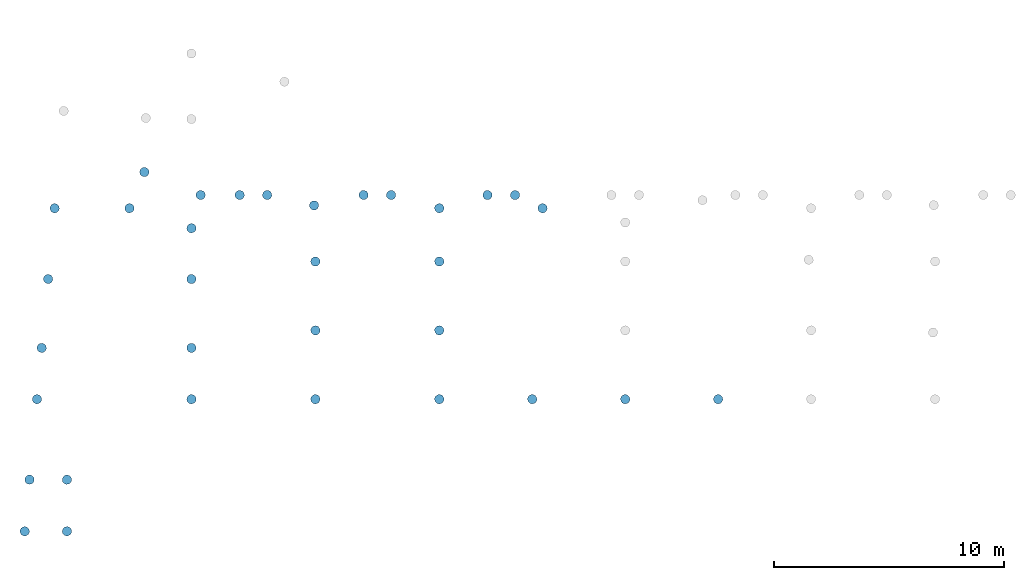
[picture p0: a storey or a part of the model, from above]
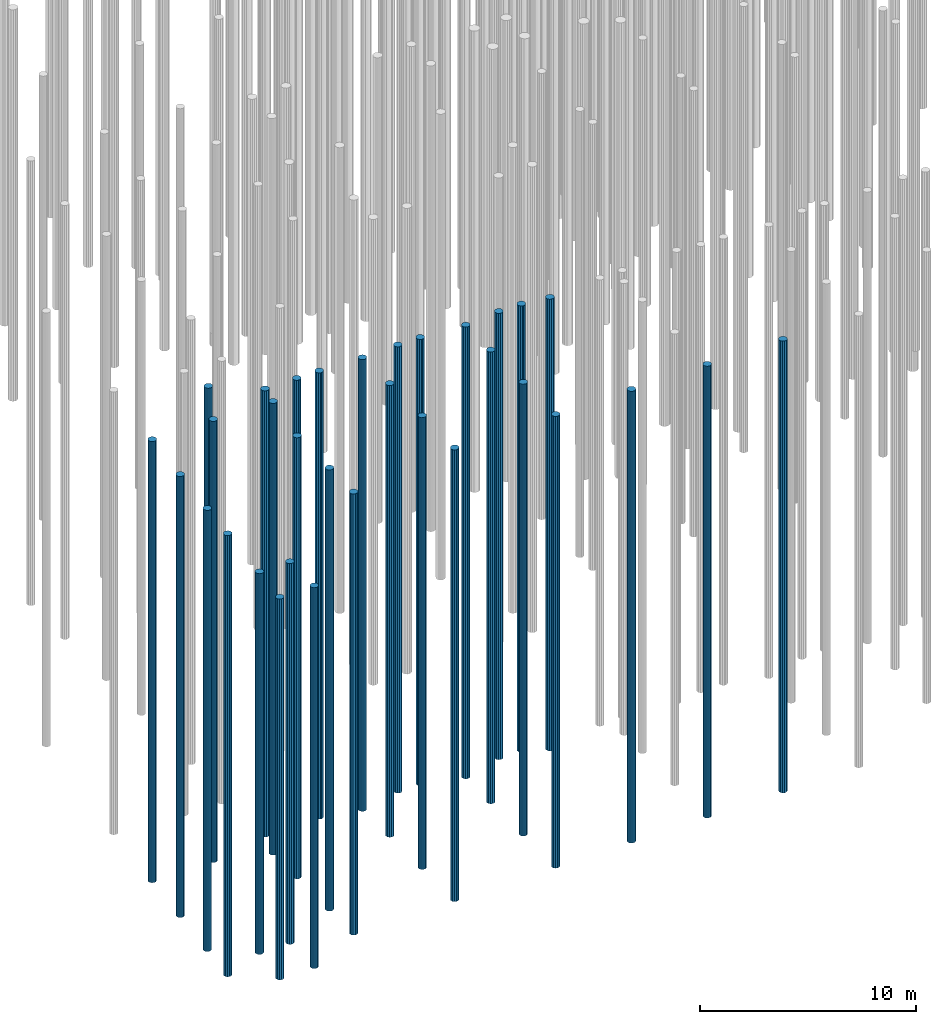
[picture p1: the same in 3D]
Properties of the parts of a building model (IFC2X3), part 1 of 11

# File
Description: ViewDefinition [CoordinationView_V2.0]
Time: 2020-05-26T17:20:09
Written by: The EXPRESS Data Manager Version 5.02.0100.07 : 28 Aug 2013
Made in: 20190510_1515(x64) - Exporter 18.3.3.18 - Alternate UI 18.3.3.18
Comment: STEP Physical File produced by: The EXPRESS Data Manager Version 5.02.0100.07 : 28 Aug 2013 * Module: EDMstepFileFactory/EDMstandAlone * Creation date: Tue May 26 17:20:09 2020 * Host: NL5CD93789YK * Database: C:\Users\Kees-D\AppData\Local\Temp\{93316886-3447-4F1F-995B-1711069A9E40}\ifc * Database version: 5507 * Database creation date: Tue May 26 17:18:45 2020 * Schema: IFC2X3 * Model: DataRepository.ifc * Model creation date: Tue May 26 17:18:45 2020 * Header model: DataRepository.ifc_HeaderModel * Header model creation date: Tue May 26 17:18:45 2020 * EDMuser: sdai-user * EDMgroup: sdai-group * License ID and type: 5605 : Permanent license. Expiry date: * EDMstepFileFactory options: 020000

# IfcProject
LongName: De Zalmhaven Rotterdam; Phase: voorlopig

# IfcSite, Default
RefLatitude: 42, 24, 53, 508911; RefLongitude: -71, -15, -29, -58837; RefElevation: 0 mm

# IfcBuilding, niet gebruiken
LongName: niet gebruiken
Pset_BuildingCommon - NumberOfStoreys: 32

# IfcBuildingStorey (32)
In: niet gebruiken
Name | LongName | Elevation (mm)
Level t.b.v. palenplan | Level t.b.v. palenplan | -4000
00 begane grond | 00 begane grond | 0
00a eerste tussenverdieping | 00a eerste tussenverdieping | 2770
01 eerste verdieping | 01 eerste verdieping | 3690
01a eerste tussenverdieping | 01a eerste tussenverdieping | 3810
01b tweede tussenverdieping | 01b tweede tussenverdieping | 5570
01c derde tussenverdieping | 01c derde tussenverdieping | 6610
02 tweede verdieping | 02 tweede verdieping | 6660
02a eerste tussenverdieping | 02a eerste tussenverdieping | 8370
02b tweede tussenverdieping | 02b tweede tussenverdieping | 9410
03 derde verdieping | 03 derde verdieping | 9630
04 vierde verdieping | 04 vierde verdieping | 12600
05 vijfde verdieping | 05 vijfde verdieping | 15570
06 zesde verdieping | 06 zesde verdieping | 18540
07 zevende verdieping | 07 zevende verdieping | 21510
08 achtste verdieping | 08 achtste verdieping | 24480
09 negende verdieping | 09 negende verdieping | 27450
10 tiende verdieping | 10 tiende verdieping | 30420
11 elfde verdieping | 11 elfde verdieping | 33390
12 twaalfde verdieping | 12 twaalfde verdieping | 36360
13 dertiende verdieping | 13 dertiende verdieping | 39330
14 veertiende verdieping | 14 veertiende verdieping | 42300
15 vijftiende verdieping | 15 vijftiende verdieping | 45270
16 zestiende verdieping | 16 zestiende verdieping | 48240
17 zeventiende verdieping | 17 zeventiende verdieping | 51210
18 achttiende verdieping | 18 achttiende verdieping | 54180
19 negentiende verdieping | 19 negentiende verdieping | 57150
20 twintigste verdieping | 20 twintigste verdieping | 60120
21 eenentwintigste verdieping | 21 eenentwintigste verdieping | 63090
22 tweeëntwintigste verdieping | 22 tweeëntwintigste verdieping | 66160
23 dakverdieping | 23 dakverdieping | 69950
23 drieëntwintigste verdieping | 23 drieëntwintigste verdieping | 73080

# IfcBeam: 250x100 (4)
In: 04 vierde verdieping
Type - ElementType: 250x100; PredefinedType: BEAM; Classification: 28.11 hoofddraagconstructies - kolommen en liggers, kolom-/liggerconstructies (Uniformat); Material: NLRS_f2_beton ihwg
Pset_BeamCommon - LoadBearing: yes; IsExternal: no; Slope: 0 deg; Reference: 250x100
Name (NLRS_28.11_SF_WPB_betonbalk ihwg recht_gen:250x100:...) | Span (mm)
6669307 | 10390
6669745 | 10390
6670276 | 5195
6670424 | 5195

# IfcBeam: 250x280 (12)
Type - ElementType: 250x280; PredefinedType: BEAM; Classification: 28.11 hoofddraagconstructies - kolommen en liggers, kolom-/liggerconstructies (Uniformat); Material: NLRS_f2_beton ihwg
Pset_BeamCommon - LoadBearing: yes; IsExternal: no; Slope: 0 deg; Reference: 250x280
Name (NLRS_28.11_SF_WPB_betonbalk ihwg recht_gen:250x280:...) | In | Span (mm)
4332247 | 01 eerste verdieping | 27080
4332594 | 02 tweede verdieping | 27080
4332708 | 03 derde verdieping | 27080
4332937 | 04 vierde verdieping | 5810
4333367 | 01 eerste verdieping | 27080
4333371 | 01c derde tussenverdieping | 27080
4333375 | 02b tweede tussenverdieping | 27080
4333379 | 04 vierde verdieping | 5810
6669748 | 23 drieëntwintigste verdieping | 2490
7334016 | 04 vierde verdieping | 2885
7334308 | 04 vierde verdieping | 2885
7673550 | 23 drieëntwintigste verdieping | 2490

# IfcBeam: 400x600, NLRS_28.11_SF_WPB_prefabbeton balk recht_gen:400x600:10267960
In: 04 vierde verdieping
Type - ElementType: 400x600; PredefinedType: BEAM; Classification: 28.11 hoofddraagconstructies - kolommen en liggers, kolom-/liggerconstructies (Uniformat); Material: NLRS_f2_beton prefab
Pset_BeamCommon - LoadBearing: yes; IsExternal: yes; Slope: 0 deg; Reference: 400x600; Span: 32800 mm

# IfcBeam: 600x540/200x200 (4)
Type - ElementType: 600x540/200x200; PredefinedType: BEAM; Classification: 28.11 hoofddraagconstructies - kolommen en liggers, kolom-/liggerconstructies (Uniformat); Material: NLRS_f2_beton prefab
Pset_BeamCommon - LoadBearing: yes; IsExternal: no; Slope: 0 deg; Reference: 600x540/200x200; Span: 32800 mm
Name (NLRS_28.11_SF_WPB_prefabbeton balk enkele sponning_gen:600x540/200x200:...) | In
6144007 | 01b tweede tussenverdieping
6144459 | 02a eerste tussenverdieping
6209170 | 02a eerste tussenverdieping
6209176 | 01b tweede tussenverdieping

# IfcBeam: 800x810 (6)
In: 04 vierde verdieping
Type - ElementType: 800x810; PredefinedType: BEAM; Classification: 28.11 hoofddraagconstructies - kolommen en liggers, kolom-/liggerconstructies (Uniformat); Material: NLRS_f2_beton ihwg
Pset_BeamCommon - LoadBearing: yes; IsExternal: yes; Slope: 0 deg; Reference: 800x810
Name (NLRS_28.11_SF_WPB_betonbalk ihwg recht_gen:800x810:...) | Span (mm)
4380914 | 11755
4381154 | 11755
4381575 | 3845
4381686 | 3845
4382677 | 3655
4382757 | 3655

# IfcBeam: NLRS_28.11_SF_WPB_Halfen 40-22_gen:ligger stripstaal RECT_100x10 (68)
Type - PredefinedType: BEAM
Classification: 28.11 hoofddraagconstructies - kolommen en liggers, kolom-/liggerconstructies (Uniformat); Material: NLRS_h2_staal
Pset_BeamCommon - LoadBearing: yes; IsExternal: yes; Slope: 0 deg; Reference: ligger stripstaal RECT_100x10; Span: 1760 mm
Name (NLRS_28.11_SF_WPB_Halfen 40-22_gen:ligger stripstaal RECT_100x10:...) | In | Group
10560951 | 05 vijfde verdieping | Model Group:NLRS_01.00_verdieping 05_gen:6691052
10564388 | 05 vijfde verdieping | Model Group:NLRS_01.00_verdieping 05_gen (members excluded):6698157
10564701 | 05 vijfde verdieping | Model Group:NLRS_01.00_verdieping 05_gen:6691052
10564886 | 05 vijfde verdieping | Model Group:NLRS_01.00_verdieping 05_gen (members excluded):6698157
10597414 | 06 zesde verdieping | Model Group:NLRS_01.00_verdieping 06--10_gen:4844478
10597416 | 06 zesde verdieping | Model Group:NLRS_01.00_verdieping 06--10_gen:4844478
10597426 | 06 zesde verdieping | Model Group:NLRS_01.00_verdieping 06--10_gen:4600460
10597428 | 06 zesde verdieping | Model Group:NLRS_01.00_verdieping 06--10_gen:4600460
10597434 | 07 zevende verdieping | Model Group:NLRS_01.00_verdieping 06--10_gen:4600975
10597436 | 07 zevende verdieping | Model Group:NLRS_01.00_verdieping 06--10_gen:4600975
10597438 | 08 achtste verdieping | Model Group:NLRS_01.00_verdieping 06--10_gen:4602043
10597440 | 08 achtste verdieping | Model Group:NLRS_01.00_verdieping 06--10_gen:4602043
10597442 | 09 negende verdieping | Model Group:NLRS_01.00_verdieping 06--10_gen:4603152
10597444 | 09 negende verdieping | Model Group:NLRS_01.00_verdieping 06--10_gen:4603152
10597446 | 10 tiende verdieping | Model Group:NLRS_01.00_verdieping 06--10_gen:4604220
10597448 | 10 tiende verdieping | Model Group:NLRS_01.00_verdieping 06--10_gen:4604220
10597470 | 07 zevende verdieping | Model Group:NLRS_01.00_verdieping 06--10_gen:4844553
10597472 | 07 zevende verdieping | Model Group:NLRS_01.00_verdieping 06--10_gen:4844553
10597474 | 08 achtste verdieping | Model Group:NLRS_01.00_verdieping 06--10_gen:4844628
10597476 | 08 achtste verdieping | Model Group:NLRS_01.00_verdieping 06--10_gen:4844628
10597478 | 09 negende verdieping | Model Group:NLRS_01.00_verdieping 06--10_gen:4844703
10597480 | 09 negende verdieping | Model Group:NLRS_01.00_verdieping 06--10_gen:4844703
10597482 | 10 tiende verdieping | Model Group:NLRS_01.00_verdieping 06--10_gen:4844850
10597484 | 10 tiende verdieping | Model Group:NLRS_01.00_verdieping 06--10_gen:4844850
10612537 | 11 elfde verdieping | Model Group:NLRS_01.00_verdieping 11--17_gen:4845821
10612539 | 11 elfde verdieping | Model Group:NLRS_01.00_verdieping 11--17_gen:4845821
10613337 | 12 twaalfde verdieping | Model Group:NLRS_01.00_verdieping 11--17_gen:4609129
10613339 | 12 twaalfde verdieping | Model Group:NLRS_01.00_verdieping 11--17_gen:4609129
10613347 | 13 dertiende verdieping | Model Group:NLRS_01.00_verdieping 11--17_gen:4609592
10613349 | 13 dertiende verdieping | Model Group:NLRS_01.00_verdieping 11--17_gen:4609592
10613352 | 14 veertiende verdieping | Model Group:NLRS_01.00_verdieping 11--17_gen:4610618
10613354 | 14 veertiende verdieping | Model Group:NLRS_01.00_verdieping 11--17_gen:4610618
10613357 | 15 vijftiende verdieping | Model Group:NLRS_01.00_verdieping 11--17_gen:4611642
10613359 | 15 vijftiende verdieping | Model Group:NLRS_01.00_verdieping 11--17_gen:4611642
10613362 | 16 zestiende verdieping | Model Group:NLRS_01.00_verdieping 11--17_gen:4612668
10613364 | 16 zestiende verdieping | Model Group:NLRS_01.00_verdieping 11--17_gen:4612668
10613367 | 17 zeventiende verdieping | Model Group:NLRS_01.00_verdieping 11--17_gen:4613692
10613369 | 17 zeventiende verdieping | Model Group:NLRS_01.00_verdieping 11--17_gen:4613692
10613372 | 11 elfde verdieping | Model Group:NLRS_01.00_verdieping 11--17_gen:4626135
10613374 | 11 elfde verdieping | Model Group:NLRS_01.00_verdieping 11--17_gen:4626135
10613412 | 12 twaalfde verdieping | Model Group:NLRS_01.00_verdieping 11--17_gen:4844919
10613414 | 12 twaalfde verdieping | Model Group:NLRS_01.00_verdieping 11--17_gen:4844919
10613417 | 13 dertiende verdieping | Model Group:NLRS_01.00_verdieping 11--17_gen:4844988
10613419 | 13 dertiende verdieping | Model Group:NLRS_01.00_verdieping 11--17_gen:4844988
10613422 | 14 veertiende verdieping | Model Group:NLRS_01.00_verdieping 11--17_gen:4845057
10613424 | 14 veertiende verdieping | Model Group:NLRS_01.00_verdieping 11--17_gen:4845057
10613427 | 15 vijftiende verdieping | Model Group:NLRS_01.00_verdieping 11--17_gen:4845126
10613429 | 15 vijftiende verdieping | Model Group:NLRS_01.00_verdieping 11--17_gen:4845126
10613432 | 16 zestiende verdieping | Model Group:NLRS_01.00_verdieping 11--17_gen:4845195
10613434 | 16 zestiende verdieping | Model Group:NLRS_01.00_verdieping 11--17_gen:4845195
10613437 | 17 zeventiende verdieping | Model Group:NLRS_01.00_verdieping 11--17_gen:4845336
10613439 | 17 zeventiende verdieping | Model Group:NLRS_01.00_verdieping 11--17_gen:4845336
10622174 | 18 achttiende verdieping | Model Group:NLRS_01.00_verdieping 18-19_gen:4845405
10622176 | 18 achttiende verdieping | Model Group:NLRS_01.00_verdieping 18-19_gen:4845405
10622920 | 18 achttiende verdieping | Model Group:NLRS_01.00_verdieping 18-19_gen:4617185
10622922 | 18 achttiende verdieping | Model Group:NLRS_01.00_verdieping 18-19_gen:4617185
10622930 | 19 negentiende verdieping | Model Group:NLRS_01.00_verdieping 18-19_gen:4617669
10622932 | 19 negentiende verdieping | Model Group:NLRS_01.00_verdieping 18-19_gen:4617669
10622945 | 19 negentiende verdieping | Model Group:NLRS_01.00_verdieping 18-19_gen:4845546
10622947 | 19 negentiende verdieping | Model Group:NLRS_01.00_verdieping 18-19_gen:4845546
10623256 | 20 twintigste verdieping | Model Group:NLRS_01.00_verdieping 20_gen:4845671
10623258 | 20 twintigste verdieping | Model Group:NLRS_01.00_verdieping 20_gen:4845671
10623633 | 20 twintigste verdieping | Model Group:NLRS_01.00_verdieping 20_gen:4622361
10623635 | 20 twintigste verdieping | Model Group:NLRS_01.00_verdieping 20_gen:4622361
10623772 | 21 eenentwintigste verdieping | Model Group:NLRS_01.00_verdieping 21--23_gen (members excluded):4846692
10623774 | 21 eenentwintigste verdieping | Model Group:NLRS_01.00_verdieping 21--23_gen (members excluded):4846692
10624008 | 21 eenentwintigste verdieping | Model Group:NLRS_01.00_verdieping 21--23_gen (members excluded):4647240
10624010 | 21 eenentwintigste verdieping | Model Group:NLRS_01.00_verdieping 21--23_gen (members excluded):4647240

# IfcBeam: NLRS_28.11_SF_WPB_betonbalk ihwg enkele sponning_gen:1050x560/200x310 (6)
In: 04 vierde verdieping
Type - PredefinedType: BEAM
Classification: 28.11 hoofddraagconstructies - kolommen en liggers, kolom-/liggerconstructies (Uniformat); Material: NLRS_f2_beton ihwg
Pset_BeamCommon - LoadBearing: yes; Slope: 0 deg; Reference: 1050x560/200x310
Name (NLRS_28.11_SF_WPB_betonbalk ihwg enkele sponning_gen:1050x560/200x310:...) | IsExternal | Span (mm)
4375370 | no | 5400
4378778 | yes | 26800
4380398 | yes | 26800
4380517 | no | 5400
13262287 | yes | 100
13265829 | yes | 100

# IfcBeam: NLRS_28.11_SF_WPB_betonbalk ihwg recht_gen:1000x150 (2)
In: 04 vierde verdieping
Type - PredefinedType: BEAM
Classification: 28.11 hoofddraagconstructies - kolommen en liggers, kolom-/liggerconstructies (Uniformat); Material: NLRS_f2_beton ihwg
Pset_BeamCommon - LoadBearing: yes; IsExternal: yes; Slope: 0 deg; Reference: 1000x150; Span: 1900 mm
Name (NLRS_28.11_SF_WPB_betonbalk ihwg recht_gen:1000x150:...)
4382414
4382585

# IfcBeam: NLRS_28.11_SF_WPB_betonbalk ihwg recht_gen:1000x560 (2)
In: 04 vierde verdieping
Type - PredefinedType: BEAM
Classification: 28.11 hoofddraagconstructies - kolommen en liggers, kolom-/liggerconstructies (Uniformat); Material: NLRS_f2_beton ihwg
Pset_BeamCommon - LoadBearing: yes; IsExternal: yes; Slope: 0 deg; Reference: 1000x560; Span: 1495 mm
Name (NLRS_28.11_SF_WPB_betonbalk ihwg recht_gen:1000x560:...)
4381937
4382583

# IfcBeam: NLRS_28.11_SF_WPB_betonbalk ihwg recht_gen:1050x250 (10)
In: 04 vierde verdieping
Type - PredefinedType: BEAM
Classification: 28.11 hoofddraagconstructies - kolommen en liggers, kolom-/liggerconstructies (Uniformat); Material: NLRS_f2_beton ihwg
Pset_BeamCommon - LoadBearing: yes; IsExternal: yes; Slope: 0 deg; Reference: 1050x250
Name (NLRS_28.11_SF_WPB_betonbalk ihwg recht_gen:1050x250:...) | Span (mm)
9976815 | 1203.1
9976825 | 3900
9976848 | 3900
9976854 | 3900
9976860 | 3900
10146550 | 1203.1
10146552 | 3900
10146554 | 3900
10146556 | 3900
10146558 | 3900

# IfcBeam: NLRS_28.11_SF_WPB_betonbalk ihwg recht_gen:1050x560 (2)
In: 04 vierde verdieping
Type - PredefinedType: BEAM
Classification: 28.11 hoofddraagconstructies - kolommen en liggers, kolom-/liggerconstructies (Uniformat); Material: NLRS_f2_beton ihwg
Pset_BeamCommon - LoadBearing: yes; IsExternal: no; Slope: 0 deg; Reference: 1050x560; Span: 3100 mm
Name (NLRS_28.11_SF_WPB_betonbalk ihwg recht_gen:1050x560:...)
4378003
4380521

# IfcBeam: NLRS_28.11_SF_WPB_betonbalk ihwg recht_gen:125x250 (2)
In: 04 vierde verdieping
Type - PredefinedType: BEAM
Classification: 28.11 hoofddraagconstructies - kolommen en liggers, kolom-/liggerconstructies (Uniformat); Material: NLRS_f2_beton ihwg
Pset_BeamCommon - LoadBearing: yes; IsExternal: yes; Slope: 0 deg; Reference: 125x250; Span: 5400 mm
Name (NLRS_28.11_SF_WPB_betonbalk ihwg recht_gen:125x250:...)
4375756
4380519

# IfcBeam: NLRS_28.11_SF_WPB_betonbalk ihwg recht_gen:180x250 (102)
Type - PredefinedType: BEAM
Classification: 28.11 hoofddraagconstructies - kolommen en liggers, kolom-/liggerconstructies (Uniformat); Material: NLRS_f2_beton ihwg
Pset_BeamCommon - LoadBearing: yes; IsExternal: no; Slope: 0 deg; Reference: 180x250
Name (NLRS_28.11_SF_WPB_betonbalk ihwg recht_gen:180x250:...) | In | Span (mm)
6347500 | 01 eerste verdieping | 970
6348159 | 01 eerste verdieping | 970
6348193 | 01 eerste verdieping | 970
6348211 | 01 eerste verdieping | 970
6348388 | 01 eerste verdieping | 970
6348408 | 01 eerste verdieping | 970
6348428 | 01 eerste verdieping | 970
6348448 | 01 eerste verdieping | 970
6348462 | 01 eerste verdieping | 970
6348476 | 01 eerste verdieping | 970
6348494 | 01 eerste verdieping | 970
6348510 | 01 eerste verdieping | 970
6348524 | 01 eerste verdieping | 970
6348540 | 01 eerste verdieping | 970
6348590 | 01c derde tussenverdieping | 970
6348595 | 01c derde tussenverdieping | 970
6348600 | 01c derde tussenverdieping | 970
6348605 | 01c derde tussenverdieping | 970
6348610 | 01c derde tussenverdieping | 970
6348620 | 01c derde tussenverdieping | 970
6348625 | 01c derde tussenverdieping | 970
6348630 | 01c derde tussenverdieping | 970
6348635 | 01c derde tussenverdieping | 970
6348640 | 01c derde tussenverdieping | 970
6348645 | 01c derde tussenverdieping | 970
6348650 | 01c derde tussenverdieping | 970
6348655 | 01c derde tussenverdieping | 970
6348735 | 03 derde verdieping | 970
6348740 | 03 derde verdieping | 970
6348745 | 03 derde verdieping | 970
6348750 | 03 derde verdieping | 970
6348755 | 03 derde verdieping | 970
6348760 | 03 derde verdieping | 970
6348765 | 03 derde verdieping | 970
6348770 | 03 derde verdieping | 970
6348775 | 03 derde verdieping | 970
6348780 | 03 derde verdieping | 970
6348785 | 03 derde verdieping | 970
6348790 | 03 derde verdieping | 970
6348795 | 03 derde verdieping | 970
6348800 | 03 derde verdieping | 970
6349392 | 04 vierde verdieping | 970
6349522 | 04 vierde verdieping | 970
6349592 | 04 vierde verdieping | 970
6349610 | 04 vierde verdieping | 970
6349626 | 04 vierde verdieping | 970
6349642 | 04 vierde verdieping | 970
6349660 | 04 vierde verdieping | 970
6353897 | 01 eerste verdieping | 970
6354036 | 01 eerste verdieping | 970
6354056 | 01 eerste verdieping | 970
6354076 | 01 eerste verdieping | 970
6354096 | 01 eerste verdieping | 1000
6354116 | 01 eerste verdieping | 1000
6354134 | 01 eerste verdieping | 970
6354152 | 01 eerste verdieping | 970
6354170 | 01 eerste verdieping | 1000
6354188 | 01 eerste verdieping | 970
6354210 | 01 eerste verdieping | 970
6354230 | 01 eerste verdieping | 970
6354289 | 01 eerste verdieping | 1000
6354309 | 01 eerste verdieping | 970
6354329 | 01 eerste verdieping | 970
6354478 | 01c derde tussenverdieping | 970
6354483 | 01c derde tussenverdieping | 970
6354488 | 01c derde tussenverdieping | 970
6354493 | 01c derde tussenverdieping | 970
6354498 | 01c derde tussenverdieping | 970
6354503 | 01c derde tussenverdieping | 970
6354508 | 01c derde tussenverdieping | 970
6354513 | 01c derde tussenverdieping | 970
6354518 | 01c derde tussenverdieping | 970
6354523 | 01c derde tussenverdieping | 970
6354528 | 01c derde tussenverdieping | 970
6354533 | 01c derde tussenverdieping | 970
6354538 | 01c derde tussenverdieping | 970
6354543 | 01c derde tussenverdieping | 970
6354548 | 01c derde tussenverdieping | 970
6354620 | 03 derde verdieping | 970
6354625 | 03 derde verdieping | 970
6354630 | 03 derde verdieping | 970
6354635 | 03 derde verdieping | 970
6354640 | 03 derde verdieping | 970
6354645 | 03 derde verdieping | 970
6354650 | 03 derde verdieping | 970
6354655 | 03 derde verdieping | 970
6354660 | 03 derde verdieping | 970
6354665 | 03 derde verdieping | 970
6354670 | 03 derde verdieping | 970
6354675 | 03 derde verdieping | 970
6354680 | 03 derde verdieping | 970
6354685 | 03 derde verdieping | 970
6354690 | 03 derde verdieping | 970
6355044 | 04 vierde verdieping | 970
6355186 | 04 vierde verdieping | 970
6355234 | 04 vierde verdieping | 970
6355239 | 04 vierde verdieping | 970
6355267 | 04 vierde verdieping | 970
6355272 | 04 vierde verdieping | 970
6355300 | 04 vierde verdieping | 970
6355305 | 04 vierde verdieping | 970
7228354 | 01c derde tussenverdieping | 970

# IfcBeam: NLRS_28.11_SF_WPB_betonbalk ihwg recht_gen:700x450 (2)
In: 04 vierde verdieping
Type - PredefinedType: BEAM
Classification: 28.11 hoofddraagconstructies - kolommen en liggers, kolom-/liggerconstructies (Uniformat); Material: NLRS_f2_beton ihwg
Pset_BeamCommon - LoadBearing: yes; IsExternal: no; Slope: 0 deg; Reference: 700x450
Name (NLRS_28.11_SF_WPB_betonbalk ihwg recht_gen:700x450:...) | Span (mm)
4376239 | 8575
4380562 | 8450

# IfcBeam: NLRS_28.11_SF_WPB_betonbalk ihwg recht_gen:800x250, NLRS_28.11_SF_WPB_betonbalk ihwg recht_gen:800x250:5027235
In: 01 eerste verdieping
Type - PredefinedType: BEAM
Classification: 28.11 hoofddraagconstructies - kolommen en liggers, kolom-/liggerconstructies (Uniformat); Material: NLRS_f2_beton ihwg
Pset_BeamCommon - LoadBearing: yes; IsExternal: yes; Slope: 0 deg; Reference: 800x250; Span: 2895 mm

# IfcBeam: NLRS_28.11_SF_WPB_betonbalk ihwg recht_gen:850x650 (2)
In: 04 vierde verdieping
Type - PredefinedType: BEAM
Classification: 28.11 hoofddraagconstructies - kolommen en liggers, kolom-/liggerconstructies (Uniformat); Material: NLRS_f2_beton ihwg
Pset_BeamCommon - LoadBearing: yes; IsExternal: no; Slope: 0 deg; Reference: 850x650; Span: 11200 mm
Name (NLRS_28.11_SF_WPB_betonbalk ihwg recht_gen:850x650:...)
4379910
4380402

# IfcBeam: NLRS_28.11_SF_WPB_oplegnok ihwg beton_gen:620x250 (12)
Type - PredefinedType: BEAM
Classification: 28.11 hoofddraagconstructies - kolommen en liggers, kolom-/liggerconstructies (Uniformat); Material: NLRS_f2_beton ihwg
Pset_BeamCommon - LoadBearing: yes; IsExternal: yes; Slope: 0 deg; Reference: 620x250; Span: 300 mm
Name (NLRS_28.11_SF_WPB_oplegnok ihwg beton_gen:620x250:...) | In
5040999 | 01 eerste verdieping
5041577 | 01c derde tussenverdieping
5041601 | 02b tweede tussenverdieping
5041644 | 02b tweede tussenverdieping
5041664 | 01c derde tussenverdieping
5041684 | 01 eerste verdieping
5042062 | 01 eerste verdieping
5042066 | 01c derde tussenverdieping
5042070 | 02b tweede tussenverdieping
5042074 | 02b tweede tussenverdieping
5042078 | 01c derde tussenverdieping
5042082 | 01 eerste verdieping

# IfcBeam: NLRS_28.11_SF_WPB_prefabbeton balk dubbele sponning_gen:1250x460/200x260/200x260 (18)
Type - PredefinedType: BEAM
Classification: 28.11 hoofddraagconstructies - kolommen en liggers, kolom-/liggerconstructies (Uniformat); Material: NLRS_f2_beton prefab
Pset_BeamCommon - LoadBearing: yes; IsExternal: yes; Slope: 0 deg; Reference: 1250x460/200x260/200x260
Name (NLRS_28.11_SF_WPB_prefabbeton balk dubbele sponning_gen:1250x460/200x260/200x260:...) | In | Span (mm)
4287489 | 01 eerste verdieping | 27705
4287718 | 01 eerste verdieping | 8155
4288211 | 01 eerste verdieping | 11285
4288277 | 01 eerste verdieping | 26490
4288377 | 01 eerste verdieping | 8155
4288379 | 01 eerste verdieping | 11285
4289503 | 01c derde tussenverdieping | 27705
4289505 | 01c derde tussenverdieping | 8155
4289507 | 01c derde tussenverdieping | 11285
4289509 | 01c derde tussenverdieping | 26490
4289511 | 01c derde tussenverdieping | 8155
4289513 | 01c derde tussenverdieping | 11285
4289604 | 02b tweede tussenverdieping | 27705
4289606 | 02b tweede tussenverdieping | 8154.87
4289608 | 02b tweede tussenverdieping | 11285
4289610 | 02b tweede tussenverdieping | 26490
4289612 | 02b tweede tussenverdieping | 8155
4289614 | 02b tweede tussenverdieping | 11285

# IfcBeam: NLRS_28.11_SF_WPB_prefabbeton balk dubbele sponning_gen:500x600/150x270/150x270, NLRS_28.11_SF_WPB_prefabbeton balk dubbele sponning_gen:500x600/150x270/150x270:5711546
In: 01b tweede tussenverdieping
Type - PredefinedType: BEAM
Classification: 28.11 hoofddraagconstructies - kolommen en liggers, kolom-/liggerconstructies (Uniformat); Material: NLRS_f2_beton prefab
Pset_BeamCommon - LoadBearing: yes; IsExternal: yes; Slope: 0 deg; Reference: 500x600/150x270/150x270; Span: 5725 mm

# IfcBeam: NLRS_28.11_SF_WPB_prefabbeton balk dubbele sponning_gen:650x1715/200x1530/200x345 (2)
In: 04 vierde verdieping
Type - PredefinedType: BEAM
Classification: 28.11 hoofddraagconstructies - kolommen en liggers, kolom-/liggerconstructies (Uniformat); Material: NLRS_f2_beton prefab
Pset_BeamCommon - LoadBearing: yes; IsExternal: yes; Slope: 0 deg; Reference: 650x1715/200x1530/200x345
Name (NLRS_28.11_SF_WPB_prefabbeton balk dubbele sponning_gen:650x1715/200x1530/200x345:...) | Span (mm)
4376907 | 26300
4376967 | 26270

# IfcBeam: NLRS_28.11_SF_WPB_prefabbeton balk dubbele sponning_gen:650x1860/200x1530/200x490 (5)
In: 04 vierde verdieping
Type - PredefinedType: BEAM
Classification: 28.11 hoofddraagconstructies - kolommen en liggers, kolom-/liggerconstructies (Uniformat); Material: NLRS_f2_beton prefab
Pset_BeamCommon - LoadBearing: yes; Slope: 0 deg; Reference: 650x1860/200x1530/200x490
Name (NLRS_28.11_SF_WPB_prefabbeton balk dubbele sponning_gen:650x1860/200x1530/200x490:...) | IsExternal | Span (mm)
4369412 | yes | 13625
4376826 | yes | 10005
5499119 | yes | 4320
6598969 | yes | 5515
9418061 | no | 22300

# IfcBeam: NLRS_28.11_SF_WPB_prefabbeton balk dubbele sponning_gen:800x460/200x260/200x260 (22)
Type - PredefinedType: BEAM
Classification: 28.11 hoofddraagconstructies - kolommen en liggers, kolom-/liggerconstructies (Uniformat); Material: NLRS_f2_beton prefab
Pset_BeamCommon - LoadBearing: yes; IsExternal: yes; Slope: 0 deg; Reference: 800x460/200x260/200x260
Name (NLRS_28.11_SF_WPB_prefabbeton balk dubbele sponning_gen:800x460/200x260/200x260:...) | In | Span (mm)
4273786 | 00a eerste tussenverdieping | 48580
4281436 | 00a eerste tussenverdieping | 9785
4281739 | 00a eerste tussenverdieping | 27705
4281942 | 00a eerste tussenverdieping | 4085
4285708 | 01b tweede tussenverdieping | 48580
4285710 | 01b tweede tussenverdieping | 9785
4285714 | 01b tweede tussenverdieping | 27705
4285716 | 01b tweede tussenverdieping | 4085
4285832 | 02a eerste tussenverdieping | 48580
4285834 | 02a eerste tussenverdieping | 9785
4285838 | 02a eerste tussenverdieping | 27705
4285840 | 02a eerste tussenverdieping | 13435
4288633 | 01a eerste tussenverdieping | 22070
4289113 | 01a eerste tussenverdieping | 9785
4289221 | 01a eerste tussenverdieping | 13355
4289515 | 01c derde tussenverdieping | 22070
4289519 | 01c derde tussenverdieping | 9785
4289521 | 01c derde tussenverdieping | 13355
4289616 | 02b tweede tussenverdieping | 22070
4289620 | 02b tweede tussenverdieping | 9785
4289622 | 02b tweede tussenverdieping | 13355
6646900 | 00a eerste tussenverdieping | 3760

# IfcBeam: NLRS_28.11_SF_WPB_prefabbeton balk dubbele sponning_gen:800x600/200x150/200x270, NLRS_28.11_SF_WPB_prefabbeton balk dubbele sponning_gen:800x600/200x150/200x270:5712803
In: 01b tweede tussenverdieping
Type - PredefinedType: BEAM
Classification: 28.11 hoofddraagconstructies - kolommen en liggers, kolom-/liggerconstructies (Uniformat); Material: NLRS_f2_beton prefab
Pset_BeamCommon - LoadBearing: yes; IsExternal: yes; Slope: 0 deg; Reference: 800x600/200x150/200x270; Span: 16105 mm

# IfcBeam: NLRS_28.11_SF_WPB_prefabbeton balk dubbele sponning_gen:800x660/200x410/200x410 (8)
In: 04 vierde verdieping
Type - PredefinedType: BEAM
Classification: 28.11 hoofddraagconstructies - kolommen en liggers, kolom-/liggerconstructies (Uniformat); Material: NLRS_f2_beton prefab
Pset_BeamCommon - LoadBearing: yes; IsExternal: yes; Slope: 0 deg; Reference: 800x660/200x410/200x410
Name (NLRS_28.11_SF_WPB_prefabbeton balk dubbele sponning_gen:800x660/200x410/200x410:...) | Span (mm)
4369086 | 1610
4372293 | 3760
4380201 | 22335
6267585 | 9785
6267593 | 4340
6597534 | 4345
6597552 | 13355
6597572 | 3900

# IfcBeam: NLRS_28.11_SF_WPB_prefabbeton balk dubbele sponning_gen:800x660/250x410/250x410 (2)
In: 04 vierde verdieping
Type - PredefinedType: BEAM
Classification: 28.11 hoofddraagconstructies - kolommen en liggers, kolom-/liggerconstructies (Uniformat); Material: NLRS_f2_beton prefab
Pset_BeamCommon - LoadBearing: yes; Slope: 0 deg; Reference: 800x660/250x410/250x410
Name (NLRS_28.11_SF_WPB_prefabbeton balk dubbele sponning_gen:800x660/250x410/250x410:...) | IsExternal | Span (mm)
5372191 | yes | 4080
7688064 | no | 4370

# IfcBeam: NLRS_28.11_SF_WPB_prefabbeton balk dubbele sponning_gen:900x660/250x410/250x410 (6)
Type - PredefinedType: BEAM
Classification: 28.11 hoofddraagconstructies - kolommen en liggers, kolom-/liggerconstructies (Uniformat); Material: NLRS_f2_beton prefab
Pset_BeamCommon - LoadBearing: yes; IsExternal: yes; Slope: 0 deg; Reference: 900x660/250x410/250x410
Name (NLRS_28.11_SF_WPB_prefabbeton balk dubbele sponning_gen:900x660/250x410/250x410:...) | In | Span (mm)
4369169 | 04 vierde verdieping | 13755
4374534 | 04 vierde verdieping | 4400
4374785 | 03 derde verdieping | 27705
4376654 | 03 derde verdieping | 48580
4377311 | 03 derde verdieping | 9785
6598063 | 03 derde verdieping | 4370

# IfcBeam: NLRS_28.11_SF_WPB_prefabbeton balk enkele sponning_gen:380x370/180x150 (10)
Type - PredefinedType: BEAM
Classification: 28.11 hoofddraagconstructies - kolommen en liggers, kolom-/liggerconstructies (Uniformat); Material: NLRS_f2_beton prefab
Pset_BeamCommon - LoadBearing: yes; IsExternal: yes; Slope: 0 deg; Reference: 380x370/180x150; Span: 3760 mm
Name (NLRS_28.11_SF_WPB_prefabbeton balk enkele sponning_gen:380x370/180x150:...) | In
9909960 | 01a eerste tussenverdieping
9959031 | 01c derde tussenverdieping
12389725 | 02a eerste tussenverdieping
12389727 | 01b tweede tussenverdieping
12389729 | 00a eerste tussenverdieping
12391878 | 01 eerste verdieping
12391880 | 01c derde tussenverdieping
12391915 | 02a eerste tussenverdieping
12391917 | 01b tweede tussenverdieping
12391919 | 00a eerste tussenverdieping

# IfcBeam: NLRS_28.11_SF_WPB_prefabbeton balk enkele sponning_gen:400x385/100x210 (2)
In: 00a eerste tussenverdieping
Type - PredefinedType: BEAM
Classification: 28.11 hoofddraagconstructies - kolommen en liggers, kolom-/liggerconstructies (Uniformat); Material: NLRS_f2_beton prefab
Pset_BeamCommon - LoadBearing: yes; IsExternal: yes; Slope: 0 deg; Reference: 400x385/100x210
Name (NLRS_28.11_SF_WPB_prefabbeton balk enkele sponning_gen:400x385/100x210:...) | Span (mm)
5712865 | 15906.7
5713066 | 6795.62

# IfcBeam: NLRS_28.11_SF_WPB_prefabbeton balk enkele sponning_gen:600x530/200x200 (2)
In: 00a eerste tussenverdieping
Type - PredefinedType: BEAM
Classification: 28.11 hoofddraagconstructies - kolommen en liggers, kolom-/liggerconstructies (Uniformat); Material: NLRS_f2_beton prefab
Pset_BeamCommon - LoadBearing: yes; IsExternal: yes; Slope: 0 deg; Reference: 600x530/200x200; Span: 12255 mm
Name (NLRS_28.11_SF_WPB_prefabbeton balk enkele sponning_gen:600x530/200x200:...)
6563997
6564005

# IfcBeam: NLRS_28.11_SF_WPB_prefabbeton balk enkele sponning_gen:600x540/200x200 (49)
Type - PredefinedType: BEAM
Classification: 28.11 hoofddraagconstructies - kolommen en liggers, kolom-/liggerconstructies (Uniformat); Material: NLRS_f2_beton prefab
Pset_BeamCommon - LoadBearing: yes; Slope: 0 deg; Reference: 600x540/200x200
Name (NLRS_28.11_SF_WPB_prefabbeton balk enkele sponning_gen:600x540/200x200:...) | In | IsExternal | Span (mm)
4273336 | 00a eerste tussenverdieping | yes | 27965
4273691 | 00a eerste tussenverdieping | yes | 8155
4281434 | 00a eerste tussenverdieping | yes | 2755
4281737 | 00a eerste tussenverdieping | yes | 17250
4282006 | 00a eerste tussenverdieping | yes | 4105
4285706 | 01b tweede tussenverdieping | yes | 27950
4285712 | 01b tweede tussenverdieping | yes | 17250
4285718 | 01b tweede tussenverdieping | yes | 4085
4285830 | 02a eerste tussenverdieping | yes | 27950
4285836 | 02a eerste tussenverdieping | yes | 17250
4285842 | 02a eerste tussenverdieping | yes | 13365
4285936 | 01b tweede tussenverdieping | yes | 2755
4286149 | 01b tweede tussenverdieping | yes | 8155
4286705 | 02a eerste tussenverdieping | yes | 2755
4286855 | 02a eerste tussenverdieping | yes | 8155
4288872 | 01a eerste tussenverdieping | no | 17250
4289307 | 01a eerste tussenverdieping | no | 4105
4289517 | 01c derde tussenverdieping | no | 17250
4289523 | 01c derde tussenverdieping | yes | 8155
4289618 | 02b tweede tussenverdieping | no | 17250
4289624 | 02b tweede tussenverdieping | no | 13355
4289793 | 01c derde tussenverdieping | no | 26550
4289898 | 01c derde tussenverdieping | no | 15530
4290076 | 02b tweede tussenverdieping | no | 15530
4290285 | 02b tweede tussenverdieping | no | 26550
4370319 | 00a eerste tussenverdieping | yes | 17930
4943216 | 01a eerste tussenverdieping | no | 15530
5228666 | 01b tweede tussenverdieping | yes | 5180
5591001 | 00a eerste tussenverdieping | yes | 3800
5778800 | 00a eerste tussenverdieping | no | 27830
6140185 | 00a eerste tussenverdieping | no | 4950
6188712 | 01a eerste tussenverdieping | no | 4715
6188793 | 01c derde tussenverdieping | no | 4730
6188839 | 02b tweede tussenverdieping | no | 4730
6191604 | 00a eerste tussenverdieping | no | 15530
6191719 | 01b tweede tussenverdieping | no | 15530
6191768 | 02a eerste tussenverdieping | no | 15530
6205656 | 01a eerste tussenverdieping | no | 4205
6205664 | 01b tweede tussenverdieping | no | 5455
6205676 | 00a eerste tussenverdieping | no | 5455
6205793 | 01c derde tussenverdieping | no | 4205
6205799 | 02a eerste tussenverdieping | no | 5455
6205914 | 02b tweede tussenverdieping | no | 4205
6206204 | 01b tweede tussenverdieping | yes | 17930
6206216 | 02a eerste tussenverdieping | no | 27510
6209184 | 00a eerste tussenverdieping | no | 10780
6383836 | 01a eerste tussenverdieping | no | 26565
6603083 | 01c derde tussenverdieping | no | 5180
6607941 | 01a eerste tussenverdieping | no | 5180

# IfcBeam: NLRS_28.11_SF_WPB_prefabbeton balk enkele sponning_gen:600x540/200x340, NLRS_28.11_SF_WPB_prefabbeton balk enkele sponning_gen:600x540/200x340:5711531
In: 01b tweede tussenverdieping
Type - PredefinedType: BEAM
Classification: 28.11 hoofddraagconstructies - kolommen en liggers, kolom-/liggerconstructies (Uniformat); Material: NLRS_f2_beton prefab
Pset_BeamCommon - LoadBearing: yes; IsExternal: yes; Slope: 0 deg; Reference: 600x540/200x340; Span: 5860 mm

# IfcBeam: NLRS_28.11_SF_WPB_prefabbeton balk enkele sponning_gen:600x600/200x330, NLRS_28.11_SF_WPB_prefabbeton balk enkele sponning_gen:600x600/200x330:5711533
In: 01b tweede tussenverdieping
Type - PredefinedType: BEAM
Classification: 28.11 hoofddraagconstructies - kolommen en liggers, kolom-/liggerconstructies (Uniformat); Material: NLRS_f2_beton prefab
Pset_BeamCommon - LoadBearing: yes; IsExternal: yes; Slope: 0 deg; Reference: 600x600/200x330; Span: 9310 mm

# IfcBeam: NLRS_28.11_SF_WPB_prefabbeton balk recht_gen:200x140 (9)
Type - PredefinedType: BEAM
Classification: 28.11 hoofddraagconstructies - kolommen en liggers, kolom-/liggerconstructies (Uniformat); Material: NLRS_f2_beton prefab
Pset_BeamCommon - LoadBearing: yes; IsExternal: yes; Slope: 0 deg; Reference: 200x140
Name (NLRS_28.11_SF_WPB_prefabbeton balk recht_gen:200x140:...) | In | Span (mm)
9339275 | 01a eerste tussenverdieping | 1270
9383114 | 01c derde tussenverdieping | 1270
9383120 | 02b tweede tussenverdieping | 1270
9383130 | 01a eerste tussenverdieping | 990
9388214 | 01c derde tussenverdieping | 990
9388231 | 02b tweede tussenverdieping | 990
9388316 | 01a eerste tussenverdieping | 1229.9
9388849 | 01c derde tussenverdieping | 1229.9
9388875 | 02b tweede tussenverdieping | 1229.9

# IfcBeam: NLRS_28.11_SF_WPB_prefabbeton balk recht_gen:200x490, NLRS_28.11_SF_WPB_prefabbeton balk recht_gen:200x490:10350241
In: 04 vierde verdieping
Type - PredefinedType: BEAM
Classification: 28.11 hoofddraagconstructies - kolommen en liggers, kolom-/liggerconstructies (Uniformat); Material: NLRS_f2_beton prefab
Pset_BeamCommon - LoadBearing: yes; IsExternal: yes; Slope: 0 deg; Reference: 200x490; Span: 2150 mm

# IfcBeam: NLRS_28.11_SF_WPB_prefabbeton balk recht_gen:380x350 (11)
Type - PredefinedType: BEAM
Classification: 28.11 hoofddraagconstructies - kolommen en liggers, kolom-/liggerconstructies (Uniformat); Material: NLRS_f2_beton prefab
Pset_BeamCommon - LoadBearing: yes; IsExternal: yes; Slope: 0 deg; Reference: 380x350; Span: 3760 mm
Name (NLRS_28.11_SF_WPB_prefabbeton balk recht_gen:380x350:...) | In
6595537 | 00a eerste tussenverdieping
6595552 | 01b tweede tussenverdieping
6595558 | 02a eerste tussenverdieping
12390936 | 01b tweede tussenverdieping
12390990 | 02a eerste tussenverdieping
12391668 | 00a eerste tussenverdieping
12391803 | 02a eerste tussenverdieping
12391840 | 01b tweede tussenverdieping
12391954 | 01 eerste verdieping
12391956 | 01c derde tussenverdieping
12391958 | 02b tweede tussenverdieping

# IfcBeam: NLRS_28.11_SF_WPB_prefabbeton balk recht_gen:400x450 (2)
In: 02b tweede tussenverdieping
Type - PredefinedType: BEAM
Classification: 28.11 hoofddraagconstructies - kolommen en liggers, kolom-/liggerconstructies (Uniformat); Material: NLRS_f2_beton prefab
Pset_BeamCommon - LoadBearing: yes; IsExternal: yes; Slope: 0 deg; Reference: 400x450; Span: 3760 mm
Name (NLRS_28.11_SF_WPB_prefabbeton balk recht_gen:400x450:...)
5136998
6350766

# IfcBeam: NLRS_28.11_SF_WPB_prefabbeton balk recht_gen:400x540 (3)
Type - PredefinedType: BEAM
Classification: 28.11 hoofddraagconstructies - kolommen en liggers, kolom-/liggerconstructies (Uniformat); Material: NLRS_f2_beton prefab
Pset_BeamCommon - LoadBearing: yes; IsExternal: no; Slope: 0 deg; Reference: 400x540
Name (NLRS_28.11_SF_WPB_prefabbeton balk recht_gen:400x540:...) | In | Span (mm)
6188659 | 00a eerste tussenverdieping | 4715
6515204 | 01b tweede tussenverdieping | 4730
6515227 | 02a eerste tussenverdieping | 4730

# IfcBeam: NLRS_28.11_SF_WPB_prefabbeton balk recht_gen:400x600 (3)
In: 04 vierde verdieping
Type - PredefinedType: BEAM
Classification: 28.11 hoofddraagconstructies - kolommen en liggers, kolom-/liggerconstructies (Uniformat); Material: NLRS_f2_beton prefab
Pset_BeamCommon - LoadBearing: yes; IsExternal: yes; Slope: 0 deg; Reference: 400x600
Name (NLRS_28.11_SF_WPB_prefabbeton balk recht_gen:400x600:...) | Span (mm)
4371802 | 8155
6146898 | 32800
10268051 | 27930

# IfcBeam: NLRS_28.11_SF_WPB_stalen ligger HEA_gen:ligger HEA 120 (12)
In: 04 vierde verdieping
Type - PredefinedType: BEAM
Classification: 28.11 hoofddraagconstructies - kolommen en liggers, kolom-/liggerconstructies (Uniformat); Material: NLRS_h2_staal
Pset_BeamCommon - LoadBearing: yes; IsExternal: yes; Slope: 0 deg; Reference: ligger HEA 120
Name (NLRS_28.11_SF_WPB_stalen ligger HEA_gen:ligger HEA 120:...) | Span (mm) | Group
6841219 | 2515 | Model Group:NLRS_01.00_low-rise loggia dak staal_gen:6844852
6842499 | 2318.1 | Model Group:NLRS_01.00_low-rise loggia dak staal_gen:6844852
6844909 | 2515 | Model Group:NLRS_01.00_low-rise loggia dak staal_gen:6844915
6844913 | 2318.1 | Model Group:NLRS_01.00_low-rise loggia dak staal_gen:6844915
6845592 | 2415
6845596 | 2318
12746877 | 2308 | Model Group:NLRS_01.00_low-rise loggia dak staal_gen:6844852
12746896 | 2308 | Model Group:NLRS_01.00_low-rise loggia dak staal_gen:6844915
12746916 | 2515 | Model Group:NLRS_01.00_low-rise loggia dak staal_gen:6844852
12746922 | 2515 | Model Group:NLRS_01.00_low-rise loggia dak staal_gen:6844915
12746949 | 2415
12746951 | 2318

# IfcBeam: NLRS_28.11_SF_WPB_stalen ligger HEA_gen:ligger HEA 160 (59)
Type - PredefinedType: BEAM
Classification: 28.11 hoofddraagconstructies - kolommen en liggers, kolom-/liggerconstructies (Uniformat); Material: NLRS_h2_staal
Pset_BeamCommon - LoadBearing: yes; IsExternal: yes; Slope: 0 deg; Reference: ligger HEA 160
Name (NLRS_28.11_SF_WPB_stalen ligger HEA_gen:ligger HEA 160:...) | In | Span (mm) | Group
4383226 | 04 vierde verdieping | 2500
4426600 | 04 vierde verdieping | 2819.42
4526759 | 00a eerste tussenverdieping | 1915
4527006 | 00a eerste tussenverdieping | 1152
4672129 | 23 dakverdieping | 2560 | Model Group:NLRS_01.00_verdieping 21--23_gen (members excluded):4647240
4672852 | 23 dakverdieping | 2560 | Model Group:NLRS_01.00_verdieping 21--23_gen (members excluded):4647240
4672917 | 23 dakverdieping | 2560 | Model Group:NLRS_01.00_verdieping 21--23_gen (members excluded):4647240
4672987 | 23 dakverdieping | 2560 | Model Group:NLRS_01.00_verdieping 21--23_gen (members excluded):4647240
4847134 | 23 dakverdieping | 2560 | Model Group:NLRS_01.00_verdieping 21--23_gen (members excluded):4846692
4847144 | 23 dakverdieping | 2560 | Model Group:NLRS_01.00_verdieping 21--23_gen (members excluded):4846692
4847146 | 23 dakverdieping | 2560 | Model Group:NLRS_01.00_verdieping 21--23_gen (members excluded):4846692
4847148 | 23 dakverdieping | 2560 | Model Group:NLRS_01.00_verdieping 21--23_gen (members excluded):4846692
12744530 | 04 vierde verdieping | 2819.42
12747691 | 04 vierde verdieping | 2500
12748023 | 04 vierde verdieping | 2500
12748067 | 04 vierde verdieping | 2500
12748134 | 04 vierde verdieping | 10600
12748541 | 04 vierde verdieping | 2500
12748543 | 04 vierde verdieping | 2500
12748545 | 04 vierde verdieping | 2500
12748547 | 04 vierde verdieping | 2500
12748549 | 04 vierde verdieping | 10600
12748605 | 04 vierde verdieping | 2500
12748607 | 04 vierde verdieping | 2500
12748609 | 04 vierde verdieping | 2500
12748611 | 04 vierde verdieping | 2500
12748613 | 04 vierde verdieping | 10600
13141686 | 23 dakverdieping | 2480 | Model Group:NLRS_01.00_verdieping 21--23_gen (members excluded):4846692
13141727 | 23 dakverdieping | 2480 | Model Group:NLRS_01.00_verdieping 21--23_gen (members excluded):4647240
13142162 | 23 dakverdieping | 2460 | Model Group:NLRS_01.00_verdieping 21--23_gen (members excluded):4846692
13142243 | 23 dakverdieping | 2435 | Model Group:NLRS_01.00_verdieping 21--23_gen (members excluded):4846692
13142305 | 23 dakverdieping | 2445 | Model Group:NLRS_01.00_verdieping 21--23_gen (members excluded):4846692
13142395 | 23 dakverdieping | 2460 | Model Group:NLRS_01.00_verdieping 21--23_gen (members excluded):4647240
13142397 | 23 dakverdieping | 2435 | Model Group:NLRS_01.00_verdieping 21--23_gen (members excluded):4647240
13142399 | 23 dakverdieping | 2445 | Model Group:NLRS_01.00_verdieping 21--23_gen (members excluded):4647240
13142850 | 23 dakverdieping | 2445 | Model Group:NLRS_01.00_verdieping 21--23_gen (members excluded):4846692
13143296 | 23 dakverdieping | 2480 | Model Group:NLRS_01.00_verdieping 21--23_gen (members excluded):4846692
13143298 | 23 dakverdieping | 2460 | Model Group:NLRS_01.00_verdieping 21--23_gen (members excluded):4846692
13143300 | 23 dakverdieping | 2435 | Model Group:NLRS_01.00_verdieping 21--23_gen (members excluded):4846692
13143662 | 23 dakverdieping | 2445 | Model Group:NLRS_01.00_verdieping 21--23_gen (members excluded):4647240
13143664 | 23 dakverdieping | 2480 | Model Group:NLRS_01.00_verdieping 21--23_gen (members excluded):4647240
13143666 | 23 dakverdieping | 2460 | Model Group:NLRS_01.00_verdieping 21--23_gen (members excluded):4647240
13143668 | 23 dakverdieping | 2435 | Model Group:NLRS_01.00_verdieping 21--23_gen (members excluded):4647240
13144793 | 23 dakverdieping | 2555 | Model Group:NLRS_01.00_verdieping 21--23_gen (members excluded):4846692
13144795 | 23 dakverdieping | 2555 | Model Group:NLRS_01.00_verdieping 21--23_gen (members excluded):4846692
13145132 | 23 dakverdieping | 2555 | Model Group:NLRS_01.00_verdieping 21--23_gen (members excluded):4846692
13145209 | 23 dakverdieping | 2460 | Model Group:NLRS_01.00_verdieping 21--23_gen (members excluded):4846692
13145273 | 23 dakverdieping | 2477.11 | Model Group:NLRS_01.00_verdieping 21--23_gen (members excluded):4846692
13145354 | 23 dakverdieping | 2555 | Model Group:NLRS_01.00_verdieping 21--23_gen (members excluded):4846692
13145356 | 23 dakverdieping | 2460 | Model Group:NLRS_01.00_verdieping 21--23_gen (members excluded):4846692
13145358 | 23 dakverdieping | 2460 | Model Group:NLRS_01.00_verdieping 21--23_gen (members excluded):4846692
13145738 | 23 dakverdieping | 2555 | Model Group:NLRS_01.00_verdieping 21--23_gen (members excluded):4647240
13145740 | 23 dakverdieping | 2555 | Model Group:NLRS_01.00_verdieping 21--23_gen (members excluded):4647240
13145742 | 23 dakverdieping | 2555 | Model Group:NLRS_01.00_verdieping 21--23_gen (members excluded):4647240
13145744 | 23 dakverdieping | 2460 | Model Group:NLRS_01.00_verdieping 21--23_gen (members excluded):4647240
13145746 | 23 dakverdieping | 2477.11 | Model Group:NLRS_01.00_verdieping 21--23_gen (members excluded):4647240
13145748 | 23 dakverdieping | 2555 | Model Group:NLRS_01.00_verdieping 21--23_gen (members excluded):4647240
13145750 | 23 dakverdieping | 2460 | Model Group:NLRS_01.00_verdieping 21--23_gen (members excluded):4647240
13145752 | 23 dakverdieping | 2460 | Model Group:NLRS_01.00_verdieping 21--23_gen (members excluded):4647240

# IfcBeam: NLRS_28.11_SF_WPB_stalen ligger HEA_gen:ligger HEA 180 (4)
In: 04 vierde verdieping
Type - PredefinedType: BEAM
Classification: 28.11 hoofddraagconstructies - kolommen en liggers, kolom-/liggerconstructies (Uniformat); Material: NLRS_h2_staal
Pset_BeamCommon - LoadBearing: yes; IsExternal: yes; Slope: 0 deg; Reference: ligger HEA 180
Name (NLRS_28.11_SF_WPB_stalen ligger HEA_gen:ligger HEA 180:...) | Span (mm)
4426450 | 6104
4426547 | 6330.2
12744526 | 6104
12744528 | 6330.2

# IfcBeam: NLRS_28.11_SF_WPB_stalen ligger HEA_gen:ligger HEA 200 (4)
In: 23 dakverdieping
Type - PredefinedType: BEAM
Classification: 28.11 hoofddraagconstructies - kolommen en liggers, kolom-/liggerconstructies (Uniformat); Material: NLRS_h2_staal
Pset_BeamCommon - LoadBearing: yes; IsExternal: yes; Slope: 0 deg; Reference: ligger HEA 200; Span: 12850 mm
Name (NLRS_28.11_SF_WPB_stalen ligger HEA_gen:ligger HEA 200:...) | Group
13245114 | Model Group:NLRS_01.00_verdieping 21--23_gen (members excluded):4846692
13245936 | Model Group:NLRS_01.00_verdieping 21--23_gen (members excluded):4846692
13247040 | Model Group:NLRS_01.00_verdieping 21--23_gen (members excluded):4647240
13247060 | Model Group:NLRS_01.00_verdieping 21--23_gen (members excluded):4647240

# IfcBeam: NLRS_28.11_SF_WPB_stalen ligger HEA_gen:ligger HEA 240 (8)
In: 23 dakverdieping
Type - PredefinedType: BEAM
Classification: 28.11 hoofddraagconstructies - kolommen en liggers, kolom-/liggerconstructies (Uniformat); Material: NLRS_h2_staal
Pset_BeamCommon - LoadBearing: yes; IsExternal: yes; Slope: 0 deg; Reference: ligger HEA 240
Name (NLRS_28.11_SF_WPB_stalen ligger HEA_gen:ligger HEA 240:...) | Span (mm) | Group
4672390 | 7999 | Model Group:NLRS_01.00_verdieping 21--23_gen (members excluded):4647240
4672593 | 8016.11 | Model Group:NLRS_01.00_verdieping 21--23_gen (members excluded):4647240
4672640 | 8019 | Model Group:NLRS_01.00_verdieping 21--23_gen (members excluded):4647240
4672698 | 8016.11 | Model Group:NLRS_01.00_verdieping 21--23_gen (members excluded):4647240
4847136 | 8075 | Model Group:NLRS_01.00_verdieping 21--23_gen (members excluded):4846692
4847138 | 8092.11 | Model Group:NLRS_01.00_verdieping 21--23_gen (members excluded):4846692
4847140 | 8095 | Model Group:NLRS_01.00_verdieping 21--23_gen (members excluded):4846692
4847142 | 8092.11 | Model Group:NLRS_01.00_verdieping 21--23_gen (members excluded):4846692

# IfcBeam: NLRS_28.11_SF_WPB_stalen ligger HEA_gen:ligger HEA 260 (12)
Type - PredefinedType: BEAM
Classification: 28.11 hoofddraagconstructies - kolommen en liggers, kolom-/liggerconstructies (Uniformat); Material: NLRS_h2_staal
Pset_BeamCommon - LoadBearing: yes; IsExternal: yes; Slope: 0 deg; Reference: ligger HEA 260
Name (NLRS_28.11_SF_WPB_stalen ligger HEA_gen:ligger HEA 260:...) | In | Span (mm) | Group
10436185 | 01 eerste verdieping | 11940
10436193 | 01 eerste verdieping | 11940
10436203 | 01 eerste verdieping | 1839.99
10436213 | 01 eerste verdieping | 1839.99
10439399 | 01c derde tussenverdieping | 11940 | Model Group:Hijsloods stalen liggers:10439407
10439401 | 01c derde tussenverdieping | 11940 | Model Group:Hijsloods stalen liggers:10439407
10439403 | 01c derde tussenverdieping | 1839.99 | Model Group:Hijsloods stalen liggers:10439407
10439405 | 01c derde tussenverdieping | 1839.99 | Model Group:Hijsloods stalen liggers:10439407
10439424 | 02b tweede tussenverdieping | 11940 | Model Group:Hijsloods stalen liggers:10439432
10439426 | 02b tweede tussenverdieping | 11940 | Model Group:Hijsloods stalen liggers:10439432
10439428 | 02b tweede tussenverdieping | 1839.99 | Model Group:Hijsloods stalen liggers:10439432
10439430 | 02b tweede tussenverdieping | 1839.99 | Model Group:Hijsloods stalen liggers:10439432

# IfcBeam: NLRS_28.11_SF_WPB_stalen ligger HEA_gen:ligger HEA 320 (4)
In: 04 vierde verdieping
Type - PredefinedType: BEAM
Classification: 28.11 hoofddraagconstructies - kolommen en liggers, kolom-/liggerconstructies (Uniformat); Material: NLRS_h2_staal
Pset_BeamCommon - LoadBearing: yes; IsExternal: yes; Slope: 0 deg; Reference: ligger HEA 320
Name (NLRS_28.11_SF_WPB_stalen ligger HEA_gen:ligger HEA 320:...) | Span (mm)
10465154 | 1930
10465156 | 1930
10465178 | 11940
10465180 | 11940

# IfcBeam: NLRS_28.11_SF_WPB_stalen ligger HEB_gen:ligger HEB 100 (6)
Type - PredefinedType: BEAM
Classification: 28.11 hoofddraagconstructies - kolommen en liggers, kolom-/liggerconstructies (Uniformat); Material: NLRS_h2_staal
Pset_BeamCommon - LoadBearing: yes; IsExternal: yes; Slope: 0 deg; Reference: ligger HEB 100
Name (NLRS_28.11_SF_WPB_stalen ligger HEB_gen:ligger HEB 100:...) | In | Span (mm) | Group
7614056 | 22 tweeëntwintigste verdieping | 4551.7 | Model Group:NLRS_01.00_mid-rise_gen:4847172
7614480 | 22 tweeëntwintigste verdieping | 4550 | Model Group:NLRS_01.00_mid-rise_gen:4847172
7618134 | 22 tweeëntwintigste verdieping | 4551.7 | Model Group:NLRS_01.00_mid-rise_gen:4675261
7618136 | 22 tweeëntwintigste verdieping | 4550 | Model Group:NLRS_01.00_mid-rise_gen:4675261
9362902 | 04 vierde verdieping | 1900
9363547 | 04 vierde verdieping | 1900

# IfcBeam: NLRS_28.11_SF_WPB_stalen ligger HEB_gen:ligger HEB 160 (4)
In: 00a eerste tussenverdieping
Type - PredefinedType: BEAM
Classification: 28.11 hoofddraagconstructies - kolommen en liggers, kolom-/liggerconstructies (Uniformat); Material: NLRS_h2_staal
Pset_BeamCommon - LoadBearing: yes; IsExternal: no; Reference: ligger HEB 160; Span: 2553.88 mm; Slope: 0.987034 deg
Name (NLRS_28.11_SF_WPB_stalen ligger HEB_gen:ligger HEB 160:...) | Group
12735725 | Model Group:luifel:12735764
12735732 | Model Group:luifel:12735764
12735804 | Model Group:luifel:12735808
12735806 | Model Group:luifel:12735808

# IfcBeam: NLRS_28.11_SF_WPB_stalen ligger HEB_gen:ligger HEB 200 (2)
In: 05 vijfde verdieping
Type - PredefinedType: BEAM
Classification: 28.11 hoofddraagconstructies - kolommen en liggers, kolom-/liggerconstructies (Uniformat); Material: NLRS_h2_staal
Pset_BeamCommon - LoadBearing: yes; IsExternal: no; Slope: 0 deg; Reference: ligger HEB 200
Name (NLRS_28.11_SF_WPB_stalen ligger HEB_gen:ligger HEB 200:...) | Span (mm)
5713848 | 22285
5719558 | 21163.5

# IfcBeam: NLRS_28.11_SF_WPB_stalen ligger HEB_gen:ligger HEB 260 (2)
In: 04 vierde verdieping
Type - PredefinedType: BEAM
Classification: 28.11 hoofddraagconstructies - kolommen en liggers, kolom-/liggerconstructies (Uniformat); Material: NLRS_h2_staal
Pset_BeamCommon - LoadBearing: yes; IsExternal: no; Slope: 0 deg; Reference: ligger HEB 260
Name (NLRS_28.11_SF_WPB_stalen ligger HEB_gen:ligger HEB 260:...) | Span (mm)
5714088 | 21875
5719544 | 5510

# IfcBeam: NLRS_28.11_SF_WPB_stalen ligger HEB_gen:ligger HEB 320, NLRS_28.11_SF_WPB_stalen ligger HEB_gen:ligger HEB 320:12047275
In: 01c derde tussenverdieping
Type - PredefinedType: BEAM
Classification: 28.11 hoofddraagconstructies - kolommen en liggers, kolom-/liggerconstructies (Uniformat); Material: NLRS_h2_staal
Pset_BeamCommon - LoadBearing: yes; IsExternal: no; Slope: 0 deg; Reference: ligger HEB 320; Span: 21570 mm

# IfcBeam: NLRS_28.11_SF_WPB_stalen ligger UNP_gen:160 (6)
In: 00a eerste tussenverdieping
Type - PredefinedType: BEAM
Classification: 28.11 hoofddraagconstructies - kolommen en liggers, kolom-/liggerconstructies (Uniformat); Material: NLRS_h2_staal_gen_rsf
Pset_BeamCommon - LoadBearing: yes; IsExternal: no; Reference: 160
Name (NLRS_28.11_SF_WPB_stalen ligger UNP_gen:160:...) | Span (mm) | Slope (deg) | Group
12735706 | 2618.87 | 0.962544 | Model Group:luifel:12735764
12735712 | 4670 | 0 | Model Group:luifel:12735764
12735718 | 2618.87 | 0.962544 | Model Group:luifel:12735764
12735798 | 2618.87 | 0.962544 | Model Group:luifel:12735808
12735800 | 4670 | 0 | Model Group:luifel:12735808
12735802 | 2618.87 | 0.962544 | Model Group:luifel:12735808

# IfcBeam: NLRS_28.11_SF_WPB_stalen ligger buisprofiel warmgevormd vierkant_gen:ligger buisprofiel warmgevormd vierkant SHSH_180x180x10 (3)
In: 04 vierde verdieping
Type - PredefinedType: BEAM
Classification: 28.11 hoofddraagconstructies - kolommen en liggers, kolom-/liggerconstructies (Uniformat); Material: NLRS_h2_staal
Pset_BeamCommon - LoadBearing: yes; IsExternal: yes; Slope: 0 deg; Reference: ligger buisprofiel warmgevormd vierkant SHSH_180x180x10; Span: 8085 mm
Name (NLRS_28.11_SF_WPB_stalen ligger buisprofiel warmgevormd vierkant_gen:ligger buisprofiel warmgevormd vierkant SHSH_180x180x10:...)
4383766
4384096
4384111

# IfcBeam: NLRS_28.11_SF_WPB_stalen ligger buisprofiel warmgevormd vierkant_gen:ligger buisprofiel warmgevormd vierkant SHSH_250x450x10 (2)
Type - PredefinedType: BEAM
Classification: 28.11 hoofddraagconstructies - kolommen en liggers, kolom-/liggerconstructies (Uniformat); Material: NLRS_h2_staal
Pset_BeamCommon - LoadBearing: yes; IsExternal: yes; Slope: 0 deg; Reference: ligger buisprofiel warmgevormd vierkant SHSH_250x450x10; Span: 5200 mm
Name (NLRS_28.11_SF_WPB_stalen ligger buisprofiel warmgevormd vierkant_gen:ligger buisprofiel warmgevormd vierkant SHSH_250x450x10:...) | In | Group
4401447 | 00a eerste tussenverdieping | Model Group:luifel:12735764
12735790 | 01 eerste verdieping | Model Group:luifel:12735808

# IfcBeam: NLRS_28.11_SF_WPB_stalen ligger hoekprofiel gelijkzijdig_gen:ligger gelijzijdig hoekprofiel LEQU_100x100x10 (12)
Type - PredefinedType: BEAM
Classification: 28.11 hoofddraagconstructies - kolommen en liggers, kolom-/liggerconstructies (Uniformat); Material: NLRS_h2_staal
Pset_BeamCommon - LoadBearing: yes; IsExternal: yes; Slope: 0 deg; Reference: ligger gelijzijdig hoekprofiel LEQU_100x100x10
Name (NLRS_28.11_SF_WPB_stalen ligger hoekprofiel gelijkzijdig_gen:ligger gelijzijdig hoekprofiel LEQU_100x100x10:...) | In | Span (mm) | Group
11785569 | 04 vierde verdieping | 3600 | Model Group:Rooster en hoeklijnen schacht:11786479
11785699 | 04 vierde verdieping | 1800 | Model Group:Rooster en hoeklijnen schacht:11786479
11785993 | 04 vierde verdieping | 1800 | Model Group:Rooster en hoeklijnen schacht:11786479
11786434 | 04 vierde verdieping | 3600 | Model Group:Rooster en hoeklijnen schacht:11786479
11786703 | 07 zevende verdieping | 3600 | Model Group:Rooster en hoeklijnen schacht:11786711
11786705 | 07 zevende verdieping | 1800 | Model Group:Rooster en hoeklijnen schacht:11786711
11786707 | 07 zevende verdieping | 1800 | Model Group:Rooster en hoeklijnen schacht:11786711
11786709 | 07 zevende verdieping | 3600 | Model Group:Rooster en hoeklijnen schacht:11786711
11786790 | 02a eerste tussenverdieping | 3600 | Model Group:Rooster en hoeklijnen schacht:11786798
11786792 | 02a eerste tussenverdieping | 1800 | Model Group:Rooster en hoeklijnen schacht:11786798
11786794 | 02a eerste tussenverdieping | 1800 | Model Group:Rooster en hoeklijnen schacht:11786798
11786796 | 02a eerste tussenverdieping | 3600 | Model Group:Rooster en hoeklijnen schacht:11786798

# IfcBeam: NLRS_28.11_SF_WPB_stalen ligger hoekprofiel gelijkzijdig_gen:ligger gelijzijdig hoekprofiel LEQU_120x120x12, NLRS_28.11_SF_WPB_stalen ligger hoekprofiel gelijkzijdig_gen:ligger gelijzijdig hoekprofiel LEQU_120x120x12:4527140
In: 00a eerste tussenverdieping
Type - PredefinedType: BEAM
Classification: 28.11 hoofddraagconstructies - kolommen en liggers, kolom-/liggerconstructies (Uniformat); Material: NLRS_h2_staal
Pset_BeamCommon - LoadBearing: yes; IsExternal: yes; Slope: 0 deg; Reference: ligger gelijzijdig hoekprofiel LEQU_120x120x12; Span: 1658.74 mm

# IfcBeam: NLRS_28.11_SF_WPB_stalen ligger hoekprofiel gelijkzijdig_gen:ligger gelijzijdig hoekprofiel LEQU_150x150x15 (29)
Type - PredefinedType: BEAM
Classification: 28.11 hoofddraagconstructies - kolommen en liggers, kolom-/liggerconstructies (Uniformat); Material: NLRS_h2_staal
Pset_BeamCommon - LoadBearing: yes; IsExternal: yes; Reference: ligger gelijzijdig hoekprofiel LEQU_150x150x15
Name (NLRS_28.11_SF_WPB_stalen ligger hoekprofiel gelijkzijdig_gen:ligger gelijzijdig hoekprofiel LEQU_150x150x15:...) | In | Span (mm) | Slope (deg)
4271743 | 00 begane grond | 1660 | 0
5014942 | 00 begane grond | 1660 | 0
6540256 | 00 begane grond | 1250 | 0
6540268 | 00 begane grond | 1250 | 0
6540275 | 00a eerste tussenverdieping | 1000 | 0 | Group: Model Group:NLRS_28.11_trapvloerligger 00a -- 02a_gen:6540295
6540288 | 00a eerste tussenverdieping | 1000 | 0 | Group: Model Group:NLRS_28.11_trapvloerligger 00a -- 02a_gen:6540295
6540303 | 01b tweede tussenverdieping | 1000 | 0 | Group: Model Group:NLRS_28.11_trapvloerligger 00a -- 02a_gen:6540307
6540305 | 01b tweede tussenverdieping | 1000 | 0 | Group: Model Group:NLRS_28.11_trapvloerligger 00a -- 02a_gen:6540307
6540316 | 02a eerste tussenverdieping | 1000 | 0 | Group: Model Group:NLRS_28.11_trapvloerligger 00a -- 02a_gen:6540320
6540318 | 02a eerste tussenverdieping | 1000 | 0 | Group: Model Group:NLRS_28.11_trapvloerligger 00a -- 02a_gen:6540320
6540814 | 00 begane grond | 1250 | 0
6540816 | 00 begane grond | 1250 | 0
6541572 | 00a eerste tussenverdieping | 1000 | 0 | Group: Model Group:NLRS_28.11_trapvloerligger 00a -- 02a_gen:6541576
6541574 | 00a eerste tussenverdieping | 1000 | 0 | Group: Model Group:NLRS_28.11_trapvloerligger 00a -- 02a_gen:6541576
6541577 | 01b tweede tussenverdieping | 1000 | 0 | Group: Model Group:NLRS_28.11_trapvloerligger 00a -- 02a_gen:6541581
6541579 | 01b tweede tussenverdieping | 1000 | 0 | Group: Model Group:NLRS_28.11_trapvloerligger 00a -- 02a_gen:6541581
6541582 | 02a eerste tussenverdieping | 1000 | 0 | Group: Model Group:NLRS_28.11_trapvloerligger 00a -- 02a_gen:6541586
6541584 | 02a eerste tussenverdieping | 1000 | 0 | Group: Model Group:NLRS_28.11_trapvloerligger 00a -- 02a_gen:6541586
6665302 | 00a eerste tussenverdieping | 765 | 0
6665320 | 00a eerste tussenverdieping | 940 | 0
7339718 | 00 begane grond | 1755 | 0
7339974 | 00 begane grond | 1755 | 0
11787286 | 06 zesde verdieping | 3600 | 0
11787288 | 06 zesde verdieping | 1800 | 0
11787290 | 06 zesde verdieping | 1800 | 0
11787292 | 06 zesde verdieping | 3600 | 0
12806389 | 03 derde verdieping | 1045 | 7.05883
12806466 | 03 derde verdieping | 1045 | 7.05883
12806489 | 03 derde verdieping | 1045 | 7.05883

# IfcBeam: NLRS_28.11_SF_WPB_stalen ligger hoekprofiel gelijkzijdig_gen:ligger gelijzijdig hoekprofiel LEQU_180x180x16 (2)
Type - PredefinedType: BEAM
Classification: 28.11 hoofddraagconstructies - kolommen en liggers, kolom-/liggerconstructies (Uniformat); Material: NLRS_h2_staal
Pset_BeamCommon - LoadBearing: yes; IsExternal: yes; Slope: 0 deg; Reference: ligger gelijzijdig hoekprofiel LEQU_180x180x16; Span: 3825 mm
Name (NLRS_28.11_SF_WPB_stalen ligger hoekprofiel gelijkzijdig_gen:ligger gelijzijdig hoekprofiel LEQU_180x180x16:...) | In
7801111 | 02b tweede tussenverdieping
7801322 | 04 vierde verdieping

# IfcBeam: NLRS_28.11_SF_WPB_stalen ligger hoekprofiel gelijkzijdig_gen:ligger gelijzijdig hoekprofiel LEQU_180x180x18, NLRS_28.11_SF_WPB_stalen ligger hoekprofiel gelijkzijdig_gen:ligger gelijzijdig hoekprofiel LEQU_180x180x18:5719584
In: 04 vierde verdieping
Type - PredefinedType: BEAM
Classification: 28.11 hoofddraagconstructies - kolommen en liggers, kolom-/liggerconstructies (Uniformat); Material: NLRS_h2_staal
Pset_BeamCommon - LoadBearing: yes; IsExternal: no; Slope: 0 deg; Reference: ligger gelijzijdig hoekprofiel LEQU_180x180x18; Span: 16025 mm

# IfcBeam: NLRS_28.11_SF_WPB_stalen ligger hoekprofiel gelijkzijdig_gen:ligger gelijzijdig hoekprofiel LEQU_200x200x12 (2)
Type - PredefinedType: BEAM
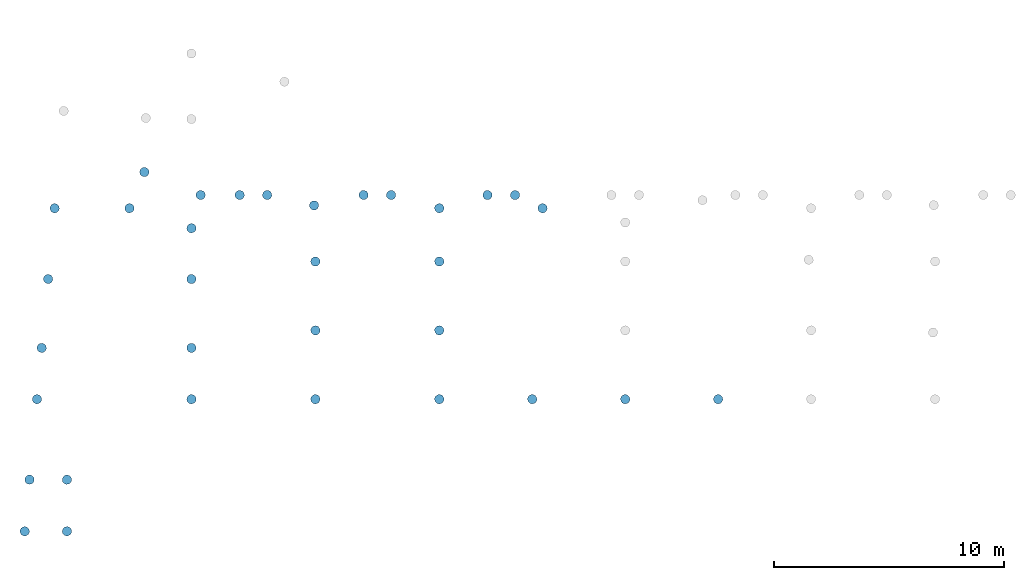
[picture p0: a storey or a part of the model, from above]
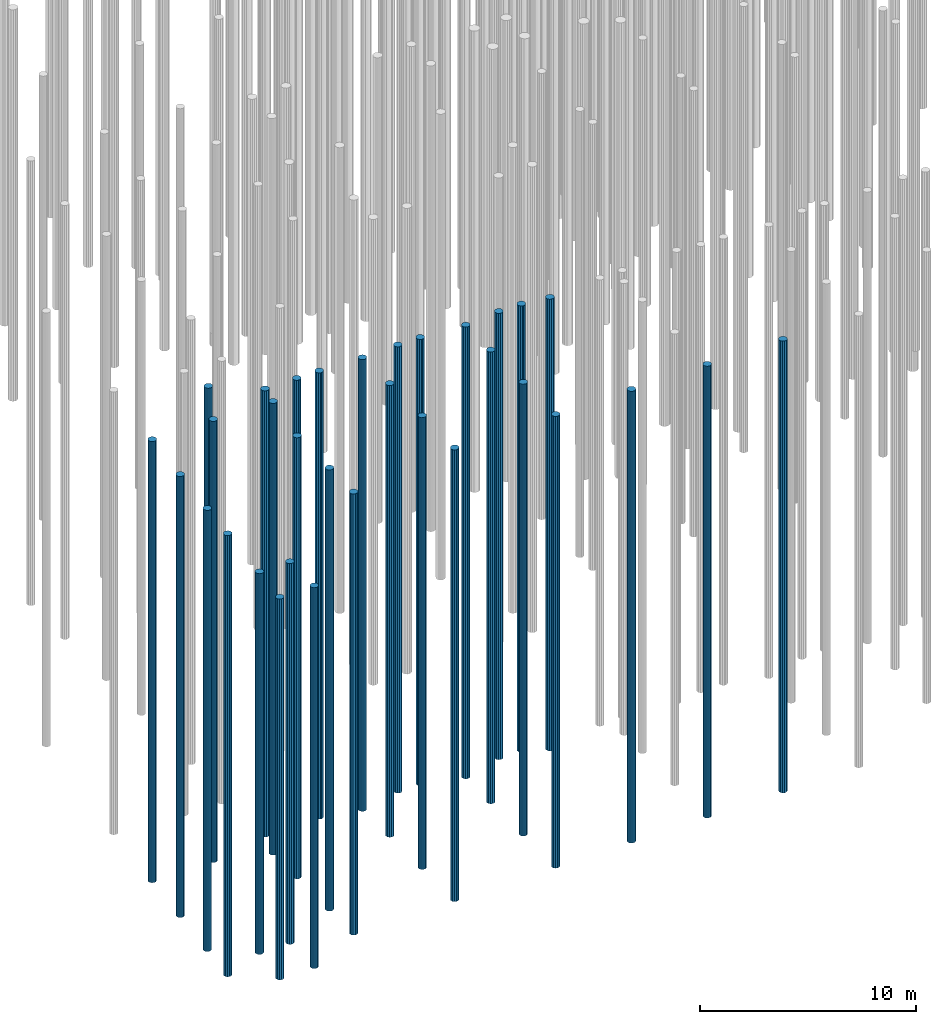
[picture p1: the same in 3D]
Properties of the parts of a building model (IFC2X3), part 2 of 11

# IfcBeam: NLRS_28.11_SF_WPB_stalen ligger hoekprofiel gelijkzijdig_gen:ligger gelijzijdig hoekprofiel LEQU_200x200x12 (2)
Classification: 28.11 hoofddraagconstructies - kolommen en liggers, kolom-/liggerconstructies (Uniformat); Material: NLRS_h2_staal
Pset_BeamCommon - LoadBearing: yes; IsExternal: yes; Slope: 0 deg; Reference: ligger gelijzijdig hoekprofiel LEQU_200x200x12; Span: 4100 mm
Name (NLRS_28.11_SF_WPB_stalen ligger hoekprofiel gelijkzijdig_gen:ligger gelijzijdig hoekprofiel LEQU_200x200x12:...) | In
7798782 | 01 eerste verdieping
7800392 | 01c derde tussenverdieping

# IfcBeam: NLRS_28.11_SF_WPB_stalen ligger hoekprofiel gelijkzijdig_gen:ligger gelijzijdig hoekprofiel LEQU_200x200x15 (48)
Type - PredefinedType: BEAM
Classification: 28.11 hoofddraagconstructies - kolommen en liggers, kolom-/liggerconstructies (Uniformat); Material: NLRS_h2_staal
Pset_BeamCommon - LoadBearing: yes; IsExternal: yes; Slope: 0 deg; Reference: ligger gelijzijdig hoekprofiel LEQU_200x200x15
Name (NLRS_28.11_SF_WPB_stalen ligger hoekprofiel gelijkzijdig_gen:ligger gelijzijdig hoekprofiel LEQU_200x200x15:...) | In | Span (mm)
4398969 | 01c derde tussenverdieping | 1510
4399065 | 02b tweede tussenverdieping | 1510
4400018 | 01c derde tussenverdieping | 1510.02
4400020 | 02b tweede tussenverdieping | 1510
4400491 | 02b tweede tussenverdieping | 7420
5015048 | 01c derde tussenverdieping | 1510
5015050 | 02b tweede tussenverdieping | 1510
5015060 | 01c derde tussenverdieping | 1510.02
5015062 | 02b tweede tussenverdieping | 1510
5015064 | 02b tweede tussenverdieping | 7420
5163502 | 01c derde tussenverdieping | 1025
5164369 | 02b tweede tussenverdieping | 1025
5164424 | 04 vierde verdieping | 1025
5165587 | 01c derde tussenverdieping | 1605
5165820 | 02b tweede tussenverdieping | 1025
5165852 | 04 vierde verdieping | 1025
6290990 | 01a eerste tussenverdieping | 8080
6293801 | 01c derde tussenverdieping | 8080
6294368 | 02b tweede tussenverdieping | 8100
6294415 | 01a eerste tussenverdieping | 8080
6294629 | 00a eerste tussenverdieping | 8080
6294697 | 01c derde tussenverdieping | 8080
6296511 | 01a eerste tussenverdieping | 8350
6296513 | 00a eerste tussenverdieping | 4300
6297227 | 01b tweede tussenverdieping | 8350
6297305 | 01c derde tussenverdieping | 8350
6297535 | 02b tweede tussenverdieping | 8350
6297645 | 02a eerste tussenverdieping | 8350
6356914 | 00a eerste tussenverdieping | 4950
6357214 | 00a eerste tussenverdieping | 3880
6497865 | 03 derde verdieping | 3880
6497867 | 03 derde verdieping | 3880
6515192 | 01b tweede tussenverdieping | 3880
6515198 | 02a eerste tussenverdieping | 3880
6515213 | 01b tweede tussenverdieping | 4950
6515236 | 02a eerste tussenverdieping | 4950
6665327 | 00a eerste tussenverdieping | 1820
7389013 | 01a eerste tussenverdieping | 2986
7389334 | 01a eerste tussenverdieping | 1215
7390213 | 02a eerste tussenverdieping | 5625
7391093 | 04 vierde verdieping | 7941
7392047 | 01b tweede tussenverdieping | 3881
8693514 | 02b tweede tussenverdieping | 5205
8699555 | 02b tweede tussenverdieping | 5205
10987446 | 02b tweede tussenverdieping | 2065
10987459 | 02b tweede tussenverdieping | 2065
12734886 | 03 derde verdieping | 5200 | Group: Model Group:luifel:12735764
12735796 | 03 derde verdieping | 5200 | Group: Model Group:luifel:12735808

# IfcBeam: NLRS_28.11_SF_WPB_stalen ligger hoekprofiel gelijkzijdig_gen:ligger gelijzijdig hoekprofiel LEQU_200x200x16 (23)
Type - PredefinedType: BEAM
Classification: 28.11 hoofddraagconstructies - kolommen en liggers, kolom-/liggerconstructies (Uniformat); Material: NLRS_h2_staal
Pset_BeamCommon - LoadBearing: yes; IsExternal: yes; Reference: ligger gelijzijdig hoekprofiel LEQU_200x200x16
Name (NLRS_28.11_SF_WPB_stalen ligger hoekprofiel gelijkzijdig_gen:ligger gelijzijdig hoekprofiel LEQU_200x200x16:...) | In | Span (mm) | Slope (deg)
12806381 | 04 vierde verdieping | 1075 | 7.05883
12806460 | 04 vierde verdieping | 1075 | 7.05883
12806482 | 04 vierde verdieping | 1075 | 7.05883
13472094 | 00a eerste tussenverdieping | 2550 | 0
13472780 | 00a eerste tussenverdieping | 1650 | 0
13472844 | 00a eerste tussenverdieping | 4200 | 0
13473012 | 00a eerste tussenverdieping | 2550 | 0
13473090 | 00a eerste tussenverdieping | 6750 | 0
13473264 | 00a eerste tussenverdieping | 2550 | 0
13473305 | 00a eerste tussenverdieping | 1650 | 0
13473480 | 00a eerste tussenverdieping | 5700 | 0
13473840 | 00a eerste tussenverdieping | 5100 | 0
13474145 | 00a eerste tussenverdieping | 6694.99 | 0
13474516 | 00a eerste tussenverdieping | 1830 | 0
13474754 | 01b tweede tussenverdieping | 26155 | 0
13474943 | 02a eerste tussenverdieping | 26170 | 0
13475207 | 01b tweede tussenverdieping | 16480 | 0
13475371 | 01b tweede tussenverdieping | 11285 | 0
13475550 | 02a eerste tussenverdieping | 14425 | 0
13475552 | 02a eerste tussenverdieping | 10205 | 0
13475632 | 02a eerste tussenverdieping | 2550 | 0
13475955 | 02a eerste tussenverdieping | 480 | 0
13476107 | 00a eerste tussenverdieping | 7489.98 | 0

# IfcBeam: NLRS_28.11_SF_WPB_stalen ligger hoekprofiel gelijkzijdig_gen:ligger gelijzijdig hoekprofiel LEQU_40x40x4 (16)
In: 00 begane grond
Type - PredefinedType: BEAM
Classification: 28.11 hoofddraagconstructies - kolommen en liggers, kolom-/liggerconstructies (Uniformat); Material: NLRS_h2_staal
Pset_BeamCommon - LoadBearing: yes; IsExternal: yes; Slope: 0 deg; Reference: ligger gelijzijdig hoekprofiel LEQU_40x40x4
Name (NLRS_28.11_SF_WPB_stalen ligger hoekprofiel gelijkzijdig_gen:ligger gelijzijdig hoekprofiel LEQU_40x40x4:...) | Span (mm) | Group
11673526 | 1180 | Model Group:omranding 1000x1000:11674810
11674352 | 1180 | Model Group:omranding 1000x1000:11674810
11674433 | 1180 | Model Group:omranding 1000x1000:11674810
11674705 | 1180 | Model Group:omranding 1000x1000:11674810
11674855 | 1180 | Model Group:omranding 1000x1000:11674867
11674861 | 1180 | Model Group:omranding 1000x1000:11674867
11674863 | 1180 | Model Group:omranding 1000x1000:11674867
11674865 | 1180 | Model Group:omranding 1000x1000:11674867
11674918 | 1180 | Model Group:omranding 1000x1000:11674930
11674924 | 1180 | Model Group:omranding 1000x1000:11674930
11674926 | 1180 | Model Group:omranding 1000x1000:11674930
11674928 | 1180 | Model Group:omranding 1000x1000:11674930
11675404 | 985
11675406 | 960
11675787 | 960
11675861 | 985

# IfcBeam: NLRS_28.11_SF_WPB_stalen ligger hoekprofiel gelijkzijdig_gen:ligger gelijzijdig hoekprofiel LEQU_50x50x5 (2)
In: 00 begane grond
Type - PredefinedType: BEAM
Classification: 28.11 hoofddraagconstructies - kolommen en liggers, kolom-/liggerconstructies (Uniformat); Material: NLRS_h2_staal
Pset_BeamCommon - LoadBearing: yes; IsExternal: yes; Slope: 0 deg; Reference: ligger gelijzijdig hoekprofiel LEQU_50x50x5
Name (NLRS_28.11_SF_WPB_stalen ligger hoekprofiel gelijkzijdig_gen:ligger gelijzijdig hoekprofiel LEQU_50x50x5:...) | Span (mm)
7198411 | 4479.62
7199133 | 5080

# IfcBeam: NLRS_28.11_SF_WPB_stalen ligger hoekprofiel ongelijkzijdig_gen:ligger ongelijzijdig hoekprofiel LUEQ_75x50x5 (64)
Type - PredefinedType: BEAM
Classification: 28.11 hoofddraagconstructies - kolommen en liggers, kolom-/liggerconstructies (Uniformat); Material: NLRS_h2_staal
Pset_BeamCommon - LoadBearing: yes; IsExternal: yes; Slope: 0 deg; Reference: ligger ongelijzijdig hoekprofiel LUEQ_75x50x5
Name (NLRS_28.11_SF_WPB_stalen ligger hoekprofiel ongelijkzijdig_gen:ligger ongelijzijdig hoekprofiel LUEQ_75x50x5:...) | In | Span (mm) | Group
13476683 | 23 dakverdieping | 330 | Model Group:verankering glazenwasinstallatie:13477772
13477040 | 23 dakverdieping | 330 | Model Group:verankering glazenwasinstallatie:13477772
13477234 | 23 dakverdieping | 230 | Model Group:verankering glazenwasinstallatie:13477772
13477681 | 23 dakverdieping | 230 | Model Group:verankering glazenwasinstallatie:13477772
13477807 | 23 dakverdieping | 330 | Model Group:verankering glazenwasinstallatie:13477815
13477809 | 22 tweeëntwintigste verdieping | 330 | Model Group:verankering glazenwasinstallatie:13477815
13477811 | 23 dakverdieping | 230 | Model Group:verankering glazenwasinstallatie:13477815
13477813 | 23 dakverdieping | 230 | Model Group:verankering glazenwasinstallatie:13477815
13482484 | 23 dakverdieping | 330 | Model Group:verankering glazenwasinstallatie:13482492
13482486 | 23 dakverdieping | 330 | Model Group:verankering glazenwasinstallatie:13482492
13482488 | 23 dakverdieping | 230 | Model Group:verankering glazenwasinstallatie:13482492
13482490 | 23 dakverdieping | 230 | Model Group:verankering glazenwasinstallatie:13482492
13482516 | 23 dakverdieping | 330 | Model Group:verankering glazenwasinstallatie:13482524
13482518 | 23 dakverdieping | 330 | Model Group:verankering glazenwasinstallatie:13482524
13482520 | 23 dakverdieping | 230 | Model Group:verankering glazenwasinstallatie:13482524
13482522 | 23 dakverdieping | 230 | Model Group:verankering glazenwasinstallatie:13482524
13482544 | 23 dakverdieping | 330 | Model Group:verankering glazenwasinstallatie:13482552
13482546 | 23 dakverdieping | 330 | Model Group:verankering glazenwasinstallatie:13482552
13482548 | 23 dakverdieping | 230 | Model Group:verankering glazenwasinstallatie:13482552
13482550 | 23 dakverdieping | 230 | Model Group:verankering glazenwasinstallatie:13482552
13482570 | 23 dakverdieping | 330 | Model Group:verankering glazenwasinstallatie:13482578
13482572 | 23 dakverdieping | 330 | Model Group:verankering glazenwasinstallatie:13482578
13482574 | 23 dakverdieping | 230 | Model Group:verankering glazenwasinstallatie:13482578
13482576 | 23 dakverdieping | 230 | Model Group:verankering glazenwasinstallatie:13482578
13482596 | 23 dakverdieping | 330 | Model Group:verankering glazenwasinstallatie:13482604
13482598 | 23 dakverdieping | 330 | Model Group:verankering glazenwasinstallatie:13482604
13482600 | 23 dakverdieping | 230 | Model Group:verankering glazenwasinstallatie:13482604
13482602 | 23 dakverdieping | 230 | Model Group:verankering glazenwasinstallatie:13482604
13482624 | 23 dakverdieping | 330 | Model Group:verankering glazenwasinstallatie:13482632
13482626 | 23 dakverdieping | 330 | Model Group:verankering glazenwasinstallatie:13482632
13482628 | 23 dakverdieping | 230 | Model Group:verankering glazenwasinstallatie:13482632
13482630 | 23 dakverdieping | 230 | Model Group:verankering glazenwasinstallatie:13482632
13482671 | 23 dakverdieping | 330 | Model Group:verankering glazenwasinstallatie:13482679
13482673 | 23 dakverdieping | 330 | Model Group:verankering glazenwasinstallatie:13482679
13482675 | 23 dakverdieping | 230 | Model Group:verankering glazenwasinstallatie:13482679
13482677 | 23 dakverdieping | 230 | Model Group:verankering glazenwasinstallatie:13482679
13482680 | 23 dakverdieping | 330 | Model Group:verankering glazenwasinstallatie:13482688
13482682 | 22 tweeëntwintigste verdieping | 330 | Model Group:verankering glazenwasinstallatie:13482688
13482684 | 23 dakverdieping | 230 | Model Group:verankering glazenwasinstallatie:13482688
13482686 | 23 dakverdieping | 230 | Model Group:verankering glazenwasinstallatie:13482688
13482689 | 23 dakverdieping | 330 | Model Group:verankering glazenwasinstallatie:13482697
13482691 | 23 dakverdieping | 330 | Model Group:verankering glazenwasinstallatie:13482697
13482693 | 23 dakverdieping | 230 | Model Group:verankering glazenwasinstallatie:13482697
13482695 | 23 dakverdieping | 230 | Model Group:verankering glazenwasinstallatie:13482697
13482698 | 23 dakverdieping | 330 | Model Group:verankering glazenwasinstallatie:13482706
13482700 | 23 dakverdieping | 330 | Model Group:verankering glazenwasinstallatie:13482706
13482702 | 23 dakverdieping | 230 | Model Group:verankering glazenwasinstallatie:13482706
13482704 | 23 dakverdieping | 230 | Model Group:verankering glazenwasinstallatie:13482706
13482707 | 23 dakverdieping | 330 | Model Group:verankering glazenwasinstallatie:13482715
13482709 | 23 dakverdieping | 330 | Model Group:verankering glazenwasinstallatie:13482715
13482711 | 23 dakverdieping | 230 | Model Group:verankering glazenwasinstallatie:13482715
13482713 | 23 dakverdieping | 230 | Model Group:verankering glazenwasinstallatie:13482715
13482716 | 23 dakverdieping | 330 | Model Group:verankering glazenwasinstallatie:13482724
13482718 | 23 dakverdieping | 330 | Model Group:verankering glazenwasinstallatie:13482724
13482720 | 23 dakverdieping | 230 | Model Group:verankering glazenwasinstallatie:13482724
13482722 | 23 dakverdieping | 230 | Model Group:verankering glazenwasinstallatie:13482724
13482725 | 23 dakverdieping | 330 | Model Group:verankering glazenwasinstallatie:13482733
13482727 | 23 dakverdieping | 330 | Model Group:verankering glazenwasinstallatie:13482733
13482729 | 23 dakverdieping | 230 | Model Group:verankering glazenwasinstallatie:13482733
13482731 | 23 dakverdieping | 230 | Model Group:verankering glazenwasinstallatie:13482733
13482734 | 23 dakverdieping | 330 | Model Group:verankering glazenwasinstallatie:13482742
13482736 | 23 dakverdieping | 330 | Model Group:verankering glazenwasinstallatie:13482742
13482738 | 23 dakverdieping | 230 | Model Group:verankering glazenwasinstallatie:13482742
13482740 | 23 dakverdieping | 230 | Model Group:verankering glazenwasinstallatie:13482742

# IfcBeam: NLRS_28.11_SF_WPB_tt-plaatvloer Holcon 1 ligger_gen:TT-plaat 1 ligger b=400, NLRS_28.11_SF_WPB_tt-plaatvloer Holcon 1 ligger_gen:TT-plaat 1 ligger b=400:10184322
In: 04 vierde verdieping
Type - PredefinedType: BEAM
Classification: 28.11 hoofddraagconstructies - kolommen en liggers, kolom-/liggerconstructies (Uniformat); Material: NLRS_f2_beton prefab
Pset_BeamCommon - LoadBearing: yes; IsExternal: yes; Slope: 0 deg; Reference: TT-plaat 1 ligger b=400; Span: 11730 mm

# IfcBeam: NLRS_28.11_SF_WPB_tt-plaatvloer Holcon 1 ligger_gen:TT-plaat 1 ligger b=930 (9)
In: 04 vierde verdieping
Type - PredefinedType: BEAM
Classification: 28.11 hoofddraagconstructies - kolommen en liggers, kolom-/liggerconstructies (Uniformat); Material: NLRS_f2_beton prefab
Pset_BeamCommon - LoadBearing: yes; IsExternal: yes; Slope: 0 deg; Reference: TT-plaat 1 ligger b=930; Span: 11730 mm
Name (NLRS_28.11_SF_WPB_tt-plaatvloer Holcon 1 ligger_gen:TT-plaat 1 ligger b=930:...)
10184264
10184271
10184277
10184283
10184289
10184298
10184304
10184310
10184316

# IfcBeam: NLRS_28.11_SF_WPB_tt-plaatvloer Holcon 102B_gen:TT-plaat, b=1790 (2)
In: 04 vierde verdieping
Type - PredefinedType: BEAM
Classification: 28.11 hoofddraagconstructies - kolommen en liggers, kolom-/liggerconstructies (Uniformat); Material: NLRS_f2_beton prefab
Pset_BeamCommon - LoadBearing: yes; IsExternal: yes; Slope: 0 deg; Reference: TT-plaat, b=1790; Span: 11730 mm
Name (NLRS_28.11_SF_WPB_tt-plaatvloer Holcon 102B_gen:TT-plaat, b=1790:...)
4558991
4559931

# IfcBeam: NLRS_28.11_SF_WPB_tt-plaatvloer Holcon 102B_gen:TT-plaat, b=1990, NLRS_28.11_SF_WPB_tt-plaatvloer Holcon 102B_gen:TT-plaat, b=1990:4559775
In: 04 vierde verdieping
Type - PredefinedType: BEAM
Classification: 28.11 hoofddraagconstructies - kolommen en liggers, kolom-/liggerconstructies (Uniformat); Material: NLRS_f2_beton prefab
Pset_BeamCommon - LoadBearing: yes; IsExternal: yes; Slope: 0 deg; Reference: TT-plaat, b=1990; Span: 11730 mm

# IfcBeam: NLRS_28.11_SF_WPB_tt-plaatvloer Holcon 102B_gen:TT-plaat, b=2040 (10)
In: 04 vierde verdieping
Type - PredefinedType: BEAM
Classification: 28.11 hoofddraagconstructies - kolommen en liggers, kolom-/liggerconstructies (Uniformat); Material: NLRS_f2_beton prefab
Pset_BeamCommon - LoadBearing: yes; IsExternal: yes; Reference: TT-plaat, b=2040
Name (NLRS_28.11_SF_WPB_tt-plaatvloer Holcon 102B_gen:TT-plaat, b=2040:...) | Slope (deg) | Span (mm)
4558813 | 0 | 11730
4558884 | 0 | 11730
4558886 | 0 | 11730
4558888 | 0 | 11730
4559251 | 0 | 10560
4559253 | 0 | 10560
4559894 | 0 | 11730
4559896 | 0 | 11730
10159797 | 1.36772e-07 | 10510
10162999 | 1.36772e-07 | 10510

# IfcBeam: NLRS_28.11_SF_WPB_tt-plaatvloer Holcon 102B_gen:TT-plaat, b=2305, NLRS_28.11_SF_WPB_tt-plaatvloer Holcon 102B_gen:TT-plaat, b=2305:4559898
In: 04 vierde verdieping
Type - PredefinedType: BEAM
Classification: 28.11 hoofddraagconstructies - kolommen en liggers, kolom-/liggerconstructies (Uniformat); Material: NLRS_f2_beton prefab
Pset_BeamCommon - LoadBearing: yes; IsExternal: yes; Slope: 0 deg; Reference: TT-plaat, b=2305; Span: 11730 mm

# IfcBeam: NLRS_28.11_SF_WPB_tt-plaatvloer Holcon 102B_gen:TT-plaat, b=2460 (32)
In: 04 vierde verdieping
Type - PredefinedType: BEAM
Classification: 28.11 hoofddraagconstructies - kolommen en liggers, kolom-/liggerconstructies (Uniformat); Material: NLRS_f2_beton prefab
Pset_BeamCommon - LoadBearing: yes; IsExternal: yes; Slope: 0 deg; Reference: TT-plaat, b=2460; Span: 11730 mm
Name (NLRS_28.11_SF_WPB_tt-plaatvloer Holcon 102B_gen:TT-plaat, b=2460:...)
4556368
4558734
4558993
4558995
4558999
4559001
4559617
4559619
4559621
4559623
4559654
4559656
4559660
4559693
4559695
4559699
4559701
4559734
4559738
4559740
4559742
4559773
4559779
4559812
4559814
4559816
4559818
4559853
4559855
4559857
4559859
4559892

# IfcBeam: ligger stripstaal RECT_100x10 (4)
In: 03 derde verdieping
Type - ElementType: ligger stripstaal RECT_100x10; PredefinedType: BEAM; Classification: 28.11 hoofddraagconstructies - kolommen en liggers, kolom-/liggerconstructies (Uniformat); Material: NLRS_h2_staal
Pset_BeamCommon - LoadBearing: yes; IsExternal: yes; Reference: ligger stripstaal RECT_100x10; Span: 1517.15 mm; Slope: 44.893 deg
Name (NLRS_28.11_SF_WPB_stalen ligger stripstaal_gen:ligger stripstaal RECT_100x10:...)
4427543
12744363
12744393
12744395

# IfcBeam: ligger stripstaal RECT_120x10 (194)
Type - ElementType: ligger stripstaal RECT_120x10; PredefinedType: BEAM; Classification: 28.11 hoofddraagconstructies - kolommen en liggers, kolom-/liggerconstructies (Uniformat); Material: NLRS_h2_staal
Pset_BeamCommon - LoadBearing: yes; IsExternal: yes; Slope: 0 deg; Reference: ligger stripstaal RECT_120x10; Span: 600 mm
Name (NLRS_28.11_SF_WPB_stalen ligger stripstaal_gen:ligger stripstaal RECT_120x10:...) | In | Group
10553879 | 05 vijfde verdieping | Model Group:NLRS_01.00_verdieping 05_gen:6691052
10555017 | 05 vijfde verdieping | Model Group:NLRS_01.00_verdieping 05_gen:6691052
10555073 | 05 vijfde verdieping | Model Group:NLRS_01.00_verdieping 05_gen:6691052
10555682 | 05 vijfde verdieping | Model Group:NLRS_01.00_verdieping 05_gen (members excluded):6698157
10555684 | 05 vijfde verdieping | Model Group:NLRS_01.00_verdieping 05_gen (members excluded):6698157
10555687 | 05 vijfde verdieping | Model Group:NLRS_01.00_verdieping 05_gen (members excluded):6698157
10678003 | 06 zesde verdieping | Model Group:NLRS_01.00_verdieping 06--10_gen:4844478
10678179 | 06 zesde verdieping | Model Group:NLRS_01.00_verdieping 06--10_gen:4844478
10678243 | 06 zesde verdieping | Model Group:NLRS_01.00_verdieping 06--10_gen:4844478
10681913 | 06 zesde verdieping | Model Group:NLRS_01.00_verdieping 06--10_gen:4600460
10681916 | 06 zesde verdieping | Model Group:NLRS_01.00_verdieping 06--10_gen:4600460
10681919 | 06 zesde verdieping | Model Group:NLRS_01.00_verdieping 06--10_gen:4600460
10681935 | 07 zevende verdieping | Model Group:NLRS_01.00_verdieping 06--10_gen:4600975
10681938 | 07 zevende verdieping | Model Group:NLRS_01.00_verdieping 06--10_gen:4600975
10681941 | 07 zevende verdieping | Model Group:NLRS_01.00_verdieping 06--10_gen:4600975
10681946 | 08 achtste verdieping | Model Group:NLRS_01.00_verdieping 06--10_gen:4602043
10681949 | 08 achtste verdieping | Model Group:NLRS_01.00_verdieping 06--10_gen:4602043
10681952 | 08 achtste verdieping | Model Group:NLRS_01.00_verdieping 06--10_gen:4602043
10681957 | 09 negende verdieping | Model Group:NLRS_01.00_verdieping 06--10_gen:4603152
10681960 | 09 negende verdieping | Model Group:NLRS_01.00_verdieping 06--10_gen:4603152
10681963 | 09 negende verdieping | Model Group:NLRS_01.00_verdieping 06--10_gen:4603152
10681968 | 10 tiende verdieping | Model Group:NLRS_01.00_verdieping 06--10_gen:4604220
10681971 | 10 tiende verdieping | Model Group:NLRS_01.00_verdieping 06--10_gen:4604220
10681974 | 10 tiende verdieping | Model Group:NLRS_01.00_verdieping 06--10_gen:4604220
10682034 | 07 zevende verdieping | Model Group:NLRS_01.00_verdieping 06--10_gen:4844553
10682037 | 07 zevende verdieping | Model Group:NLRS_01.00_verdieping 06--10_gen:4844553
10682040 | 07 zevende verdieping | Model Group:NLRS_01.00_verdieping 06--10_gen:4844553
10682045 | 08 achtste verdieping | Model Group:NLRS_01.00_verdieping 06--10_gen:4844628
10682048 | 08 achtste verdieping | Model Group:NLRS_01.00_verdieping 06--10_gen:4844628
10682051 | 08 achtste verdieping | Model Group:NLRS_01.00_verdieping 06--10_gen:4844628
10682056 | 09 negende verdieping | Model Group:NLRS_01.00_verdieping 06--10_gen:4844703
10682059 | 09 negende verdieping | Model Group:NLRS_01.00_verdieping 06--10_gen:4844703
10682062 | 09 negende verdieping | Model Group:NLRS_01.00_verdieping 06--10_gen:4844703
10682067 | 10 tiende verdieping | Model Group:NLRS_01.00_verdieping 06--10_gen:4844850
10682070 | 10 tiende verdieping | Model Group:NLRS_01.00_verdieping 06--10_gen:4844850
10682073 | 10 tiende verdieping | Model Group:NLRS_01.00_verdieping 06--10_gen:4844850
10769471 | 21 eenentwintigste verdieping | Model Group:NLRS_01.00_verdieping 21--23_gen (members excluded):4846692
10771042 | 21 eenentwintigste verdieping | Model Group:NLRS_01.00_verdieping 21--23_gen (members excluded):4846692
10771110 | 21 eenentwintigste verdieping | Model Group:NLRS_01.00_verdieping 21--23_gen (members excluded):4846692
10771257 | 21 eenentwintigste verdieping | Model Group:NLRS_01.00_verdieping 21--23_gen (members excluded):4846692
10771605 | 21 eenentwintigste verdieping | Model Group:NLRS_01.00_verdieping 21--23_gen (members excluded):4846692
10771669 | 21 eenentwintigste verdieping | Model Group:NLRS_01.00_verdieping 21--23_gen (members excluded):4846692
10771789 | 21 eenentwintigste verdieping | Model Group:NLRS_01.00_verdieping 21--23_gen (members excluded):4846692
10771887 | 21 eenentwintigste verdieping | Model Group:NLRS_01.00_verdieping 21--23_gen (members excluded):4846692
10771963 | 21 eenentwintigste verdieping | Model Group:NLRS_01.00_verdieping 21--23_gen (members excluded):4846692
10773153 | 21 eenentwintigste verdieping | Model Group:NLRS_01.00_verdieping 21--23_gen (members excluded):4647240
10773155 | 21 eenentwintigste verdieping | Model Group:NLRS_01.00_verdieping 21--23_gen (members excluded):4647240
10773157 | 21 eenentwintigste verdieping | Model Group:NLRS_01.00_verdieping 21--23_gen (members excluded):4647240
10773160 | 21 eenentwintigste verdieping | Model Group:NLRS_01.00_verdieping 21--23_gen (members excluded):4647240
10773163 | 21 eenentwintigste verdieping | Model Group:NLRS_01.00_verdieping 21--23_gen (members excluded):4647240
10773166 | 21 eenentwintigste verdieping | Model Group:NLRS_01.00_verdieping 21--23_gen (members excluded):4647240
10773168 | 21 eenentwintigste verdieping | Model Group:NLRS_01.00_verdieping 21--23_gen (members excluded):4647240
10773170 | 21 eenentwintigste verdieping | Model Group:NLRS_01.00_verdieping 21--23_gen (members excluded):4647240
10773172 | 21 eenentwintigste verdieping | Model Group:NLRS_01.00_verdieping 21--23_gen (members excluded):4647240
10776341 | 22 tweeëntwintigste verdieping | Model Group:NLRS_01.00_verdieping 21--23_gen (members excluded):4846692
10776344 | 22 tweeëntwintigste verdieping | Model Group:NLRS_01.00_verdieping 21--23_gen (members excluded):4846692
10776442 | 22 tweeëntwintigste verdieping | Model Group:NLRS_01.00_verdieping 21--23_gen (members excluded):4846692
10776584 | 22 tweeëntwintigste verdieping | Model Group:NLRS_01.00_verdieping 21--23_gen (members excluded):4846692
10777478 | 22 tweeëntwintigste verdieping | Model Group:NLRS_01.00_verdieping 21--23_gen (members excluded):4647240
10777481 | 22 tweeëntwintigste verdieping | Model Group:NLRS_01.00_verdieping 21--23_gen (members excluded):4647240
10777484 | 22 tweeëntwintigste verdieping | Model Group:NLRS_01.00_verdieping 21--23_gen (members excluded):4647240
10777487 | 22 tweeëntwintigste verdieping | Model Group:NLRS_01.00_verdieping 21--23_gen (members excluded):4647240
10778747 | 23 dakverdieping | Model Group:NLRS_01.00_verdieping 21--23_gen (members excluded):4846692
10779319 | 23 dakverdieping | Model Group:NLRS_01.00_verdieping 21--23_gen (members excluded):4846692
10779368 | 23 dakverdieping | Model Group:NLRS_01.00_verdieping 21--23_gen (members excluded):4846692
10779447 | 23 dakverdieping | Model Group:NLRS_01.00_verdieping 21--23_gen (members excluded):4647240
10779449 | 23 dakverdieping | Model Group:NLRS_01.00_verdieping 21--23_gen (members excluded):4647240
10779451 | 23 dakverdieping | Model Group:NLRS_01.00_verdieping 21--23_gen (members excluded):4647240
10784642 | 05 vijfde verdieping | Model Group:NLRS_01.00_verdieping 05_gen:6691052
10785435 | 05 vijfde verdieping | Model Group:NLRS_01.00_verdieping 05_gen (members excluded):6698157
10789964 | 07 zevende verdieping | Model Group:NLRS_01.00_verdieping 06--10_gen:4844553
10797724 | 06 zesde verdieping | Model Group:NLRS_01.00_verdieping 06--10_gen:4600460
10797738 | 07 zevende verdieping | Model Group:NLRS_01.00_verdieping 06--10_gen:4600975
10797745 | 08 achtste verdieping | Model Group:NLRS_01.00_verdieping 06--10_gen:4602043
10797752 | 09 negende verdieping | Model Group:NLRS_01.00_verdieping 06--10_gen:4603152
10797759 | 10 tiende verdieping | Model Group:NLRS_01.00_verdieping 06--10_gen:4604220
10797801 | 06 zesde verdieping | Model Group:NLRS_01.00_verdieping 06--10_gen:4844478
10797808 | 08 achtste verdieping | Model Group:NLRS_01.00_verdieping 06--10_gen:4844628
10797815 | 09 negende verdieping | Model Group:NLRS_01.00_verdieping 06--10_gen:4844703
10797822 | 10 tiende verdieping | Model Group:NLRS_01.00_verdieping 06--10_gen:4844850
10799281 | 07 zevende verdieping | Model Group:NLRS_01.00_verdieping 06--10_gen:4844553
10802814 | 06 zesde verdieping | Model Group:NLRS_01.00_verdieping 06--10_gen:4600460
10802832 | 07 zevende verdieping | Model Group:NLRS_01.00_verdieping 06--10_gen:4600975
10802841 | 08 achtste verdieping | Model Group:NLRS_01.00_verdieping 06--10_gen:4602043
10802850 | 09 negende verdieping | Model Group:NLRS_01.00_verdieping 06--10_gen:4603152
10802859 | 10 tiende verdieping | Model Group:NLRS_01.00_verdieping 06--10_gen:4604220
10802913 | 06 zesde verdieping | Model Group:NLRS_01.00_verdieping 06--10_gen:4844478
10802922 | 08 achtste verdieping | Model Group:NLRS_01.00_verdieping 06--10_gen:4844628
10802931 | 09 negende verdieping | Model Group:NLRS_01.00_verdieping 06--10_gen:4844703
10802940 | 10 tiende verdieping | Model Group:NLRS_01.00_verdieping 06--10_gen:4844850
10813220 | 11 elfde verdieping | Model Group:NLRS_01.00_verdieping 11--17_gen:4845821
10813322 | 05 vijfde verdieping | Model Group:NLRS_01.00_verdieping 05_gen:6691052
10813374 | 11 elfde verdieping | Model Group:NLRS_01.00_verdieping 11--17_gen:4845821
10813456 | 11 elfde verdieping | Model Group:NLRS_01.00_verdieping 11--17_gen:4845821
10813459 | 11 elfde verdieping | Model Group:NLRS_01.00_verdieping 11--17_gen:4845821
10813462 | 11 elfde verdieping | Model Group:NLRS_01.00_verdieping 11--17_gen:4845821
10820635 | 12 twaalfde verdieping | Model Group:NLRS_01.00_verdieping 11--17_gen:4609129
10820641 | 12 twaalfde verdieping | Model Group:NLRS_01.00_verdieping 11--17_gen:4609129
10820644 | 12 twaalfde verdieping | Model Group:NLRS_01.00_verdieping 11--17_gen:4609129
10820647 | 12 twaalfde verdieping | Model Group:NLRS_01.00_verdieping 11--17_gen:4609129
10820650 | 12 twaalfde verdieping | Model Group:NLRS_01.00_verdieping 11--17_gen:4609129
10820681 | 13 dertiende verdieping | Model Group:NLRS_01.00_verdieping 11--17_gen:4609592
10820687 | 13 dertiende verdieping | Model Group:NLRS_01.00_verdieping 11--17_gen:4609592
10820690 | 13 dertiende verdieping | Model Group:NLRS_01.00_verdieping 11--17_gen:4609592
10820693 | 13 dertiende verdieping | Model Group:NLRS_01.00_verdieping 11--17_gen:4609592
10820696 | 13 dertiende verdieping | Model Group:NLRS_01.00_verdieping 11--17_gen:4609592
10820704 | 14 veertiende verdieping | Model Group:NLRS_01.00_verdieping 11--17_gen:4610618
10820710 | 14 veertiende verdieping | Model Group:NLRS_01.00_verdieping 11--17_gen:4610618
10820713 | 14 veertiende verdieping | Model Group:NLRS_01.00_verdieping 11--17_gen:4610618
10820716 | 14 veertiende verdieping | Model Group:NLRS_01.00_verdieping 11--17_gen:4610618
10820719 | 14 veertiende verdieping | Model Group:NLRS_01.00_verdieping 11--17_gen:4610618
10820727 | 15 vijftiende verdieping | Model Group:NLRS_01.00_verdieping 11--17_gen:4611642
10820733 | 15 vijftiende verdieping | Model Group:NLRS_01.00_verdieping 11--17_gen:4611642
10820736 | 15 vijftiende verdieping | Model Group:NLRS_01.00_verdieping 11--17_gen:4611642
10820739 | 15 vijftiende verdieping | Model Group:NLRS_01.00_verdieping 11--17_gen:4611642
10820742 | 15 vijftiende verdieping | Model Group:NLRS_01.00_verdieping 11--17_gen:4611642
10820750 | 16 zestiende verdieping | Model Group:NLRS_01.00_verdieping 11--17_gen:4612668
10820756 | 16 zestiende verdieping | Model Group:NLRS_01.00_verdieping 11--17_gen:4612668
10820759 | 16 zestiende verdieping | Model Group:NLRS_01.00_verdieping 11--17_gen:4612668
10820762 | 16 zestiende verdieping | Model Group:NLRS_01.00_verdieping 11--17_gen:4612668
10820765 | 16 zestiende verdieping | Model Group:NLRS_01.00_verdieping 11--17_gen:4612668
10820773 | 17 zeventiende verdieping | Model Group:NLRS_01.00_verdieping 11--17_gen:4613692
10820779 | 17 zeventiende verdieping | Model Group:NLRS_01.00_verdieping 11--17_gen:4613692
10820782 | 17 zeventiende verdieping | Model Group:NLRS_01.00_verdieping 11--17_gen:4613692
10820785 | 17 zeventiende verdieping | Model Group:NLRS_01.00_verdieping 11--17_gen:4613692
10820788 | 17 zeventiende verdieping | Model Group:NLRS_01.00_verdieping 11--17_gen:4613692
10820796 | 11 elfde verdieping | Model Group:NLRS_01.00_verdieping 11--17_gen:4626135
10820802 | 11 elfde verdieping | Model Group:NLRS_01.00_verdieping 11--17_gen:4626135
10820805 | 11 elfde verdieping | Model Group:NLRS_01.00_verdieping 11--17_gen:4626135
10820808 | 11 elfde verdieping | Model Group:NLRS_01.00_verdieping 11--17_gen:4626135
10820811 | 11 elfde verdieping | Model Group:NLRS_01.00_verdieping 11--17_gen:4626135
10820980 | 12 twaalfde verdieping | Model Group:NLRS_01.00_verdieping 11--17_gen:4844919
10820986 | 12 twaalfde verdieping | Model Group:NLRS_01.00_verdieping 11--17_gen:4844919
10820989 | 12 twaalfde verdieping | Model Group:NLRS_01.00_verdieping 11--17_gen:4844919
10820992 | 12 twaalfde verdieping | Model Group:NLRS_01.00_verdieping 11--17_gen:4844919
10820995 | 12 twaalfde verdieping | Model Group:NLRS_01.00_verdieping 11--17_gen:4844919
10821003 | 13 dertiende verdieping | Model Group:NLRS_01.00_verdieping 11--17_gen:4844988
10821009 | 13 dertiende verdieping | Model Group:NLRS_01.00_verdieping 11--17_gen:4844988
10821012 | 13 dertiende verdieping | Model Group:NLRS_01.00_verdieping 11--17_gen:4844988
10821015 | 13 dertiende verdieping | Model Group:NLRS_01.00_verdieping 11--17_gen:4844988
10821018 | 13 dertiende verdieping | Model Group:NLRS_01.00_verdieping 11--17_gen:4844988
10821026 | 14 veertiende verdieping | Model Group:NLRS_01.00_verdieping 11--17_gen:4845057
10821032 | 14 veertiende verdieping | Model Group:NLRS_01.00_verdieping 11--17_gen:4845057
10821035 | 14 veertiende verdieping | Model Group:NLRS_01.00_verdieping 11--17_gen:4845057
10821038 | 14 veertiende verdieping | Model Group:NLRS_01.00_verdieping 11--17_gen:4845057
10821041 | 14 veertiende verdieping | Model Group:NLRS_01.00_verdieping 11--17_gen:4845057
10821049 | 15 vijftiende verdieping | Model Group:NLRS_01.00_verdieping 11--17_gen:4845126
10821055 | 15 vijftiende verdieping | Model Group:NLRS_01.00_verdieping 11--17_gen:4845126
10821058 | 15 vijftiende verdieping | Model Group:NLRS_01.00_verdieping 11--17_gen:4845126
10821061 | 15 vijftiende verdieping | Model Group:NLRS_01.00_verdieping 11--17_gen:4845126
10821064 | 15 vijftiende verdieping | Model Group:NLRS_01.00_verdieping 11--17_gen:4845126
10821072 | 16 zestiende verdieping | Model Group:NLRS_01.00_verdieping 11--17_gen:4845195
10821078 | 16 zestiende verdieping | Model Group:NLRS_01.00_verdieping 11--17_gen:4845195
10821081 | 16 zestiende verdieping | Model Group:NLRS_01.00_verdieping 11--17_gen:4845195
10821084 | 16 zestiende verdieping | Model Group:NLRS_01.00_verdieping 11--17_gen:4845195
10821087 | 16 zestiende verdieping | Model Group:NLRS_01.00_verdieping 11--17_gen:4845195
10821095 | 17 zeventiende verdieping | Model Group:NLRS_01.00_verdieping 11--17_gen:4845336
10821101 | 17 zeventiende verdieping | Model Group:NLRS_01.00_verdieping 11--17_gen:4845336
10821104 | 17 zeventiende verdieping | Model Group:NLRS_01.00_verdieping 11--17_gen:4845336
10821107 | 17 zeventiende verdieping | Model Group:NLRS_01.00_verdieping 11--17_gen:4845336
10821110 | 17 zeventiende verdieping | Model Group:NLRS_01.00_verdieping 11--17_gen:4845336
10854424 | 18 achttiende verdieping | Model Group:NLRS_01.00_verdieping 18-19_gen:4845405
10854430 | 18 achttiende verdieping | Model Group:NLRS_01.00_verdieping 18-19_gen:4845405
10854433 | 18 achttiende verdieping | Model Group:NLRS_01.00_verdieping 18-19_gen:4845405
10854436 | 18 achttiende verdieping | Model Group:NLRS_01.00_verdieping 18-19_gen:4845405
10854439 | 18 achttiende verdieping | Model Group:NLRS_01.00_verdieping 18-19_gen:4845405
10868893 | 18 achttiende verdieping | Model Group:NLRS_01.00_verdieping 18-19_gen:4617185
10868899 | 18 achttiende verdieping | Model Group:NLRS_01.00_verdieping 18-19_gen:4617185
10868902 | 18 achttiende verdieping | Model Group:NLRS_01.00_verdieping 18-19_gen:4617185
10868905 | 18 achttiende verdieping | Model Group:NLRS_01.00_verdieping 18-19_gen:4617185
10868908 | 18 achttiende verdieping | Model Group:NLRS_01.00_verdieping 18-19_gen:4617185
10868943 | 19 negentiende verdieping | Model Group:NLRS_01.00_verdieping 18-19_gen:4617669
10868949 | 19 negentiende verdieping | Model Group:NLRS_01.00_verdieping 18-19_gen:4617669
10868952 | 19 negentiende verdieping | Model Group:NLRS_01.00_verdieping 18-19_gen:4617669
10868955 | 19 negentiende verdieping | Model Group:NLRS_01.00_verdieping 18-19_gen:4617669
10868958 | 19 negentiende verdieping | Model Group:NLRS_01.00_verdieping 18-19_gen:4617669
10869018 | 19 negentiende verdieping | Model Group:NLRS_01.00_verdieping 18-19_gen:4845546
10869024 | 19 negentiende verdieping | Model Group:NLRS_01.00_verdieping 18-19_gen:4845546
10869027 | 19 negentiende verdieping | Model Group:NLRS_01.00_verdieping 18-19_gen:4845546
10869030 | 19 negentiende verdieping | Model Group:NLRS_01.00_verdieping 18-19_gen:4845546
10869033 | 19 negentiende verdieping | Model Group:NLRS_01.00_verdieping 18-19_gen:4845546
10870708 | 20 twintigste verdieping | Model Group:NLRS_01.00_verdieping 20_gen:4845671
10870714 | 20 twintigste verdieping | Model Group:NLRS_01.00_verdieping 20_gen:4845671
10870717 | 20 twintigste verdieping | Model Group:NLRS_01.00_verdieping 20_gen:4845671
10870720 | 20 twintigste verdieping | Model Group:NLRS_01.00_verdieping 20_gen:4845671
10870723 | 20 twintigste verdieping | Model Group:NLRS_01.00_verdieping 20_gen:4845671
10925384 | 05 vijfde verdieping | Model Group:NLRS_01.00_verdieping 05_gen (members excluded):6698157
10931451 | 20 twintigste verdieping | Model Group:NLRS_01.00_verdieping 20_gen:4622361
10931457 | 20 twintigste verdieping | Model Group:NLRS_01.00_verdieping 20_gen:4622361
10931460 | 20 twintigste verdieping | Model Group:NLRS_01.00_verdieping 20_gen:4622361
10931463 | 20 twintigste verdieping | Model Group:NLRS_01.00_verdieping 20_gen:4622361
10931466 | 20 twintigste verdieping | Model Group:NLRS_01.00_verdieping 20_gen:4622361
12634451 | 21 eenentwintigste verdieping | Model Group:NLRS_01.00_verdieping 21--23_gen (members excluded):4846692
12634775 | 21 eenentwintigste verdieping | Model Group:NLRS_01.00_verdieping 21--23_gen (members excluded):4647240

# IfcBeam: ligger stripstaal RECT_300x10 (2)
In: 05 vijfde verdieping
Type - ElementType: ligger stripstaal RECT_300x10; PredefinedType: BEAM; Classification: 28.11 hoofddraagconstructies - kolommen en liggers, kolom-/liggerconstructies (Uniformat); Material: NLRS_h2_staal
Pset_BeamCommon - LoadBearing: yes; IsExternal: no; Slope: 0 deg; Reference: ligger stripstaal RECT_300x10
Name (NLRS_28.11_SF_WPB_stalen ligger stripstaal_gen:ligger stripstaal RECT_300x10:...) | Span (mm)
5714279 | 22015
5719560 | 21163.5

# IfcBeam: ligger stripstaal RECT_355x12 (2)
In: 04 vierde verdieping
Type - ElementType: ligger stripstaal RECT_355x12; PredefinedType: BEAM; Classification: 28.11 hoofddraagconstructies - kolommen en liggers, kolom-/liggerconstructies (Uniformat); Material: NLRS_h2_staal
Pset_BeamCommon - LoadBearing: yes; IsExternal: no; Slope: 0 deg; Reference: ligger stripstaal RECT_355x12
Name (NLRS_28.11_SF_WPB_stalen ligger stripstaal_gen:ligger stripstaal RECT_355x12:...) | Span (mm)
5714028 | 21875
5719546 | 5510

# IfcBeam: ligger stripstaal RECT_450x15, NLRS_28.11_SF_WPB_stalen ligger stripstaal_gen:ligger stripstaal RECT_450x15:12047273
In: 01c derde tussenverdieping
Type - ElementType: ligger stripstaal RECT_450x15; PredefinedType: BEAM; Classification: 28.11 hoofddraagconstructies - kolommen en liggers, kolom-/liggerconstructies (Uniformat); Material: NLRS_h2_staal
Pset_BeamCommon - LoadBearing: yes; IsExternal: no; Slope: 0 deg; Reference: ligger stripstaal RECT_450x15; Span: 21570 mm

# IfcBeam: ligger stripstaal RECT_460x10 (6)
Type - ElementType: ligger stripstaal RECT_460x10; PredefinedType: BEAM; Classification: 28.11 hoofddraagconstructies - kolommen en liggers, kolom-/liggerconstructies (Uniformat); Material: NLRS_h2_staal
Pset_BeamCommon - LoadBearing: yes; IsExternal: yes; Slope: 0 deg; Reference: ligger stripstaal RECT_460x10; Span: 1839.99 mm
Name (NLRS_28.11_SF_WPB_stalen ligger stripstaal_gen:ligger stripstaal RECT_460x10:...) | In | Group
10446243 | 02b tweede tussenverdieping | Model Group:Hijsloods stalen liggers:10439432
10446251 | 02b tweede tussenverdieping | Model Group:Hijsloods stalen liggers:10439432
10449827 | 01 eerste verdieping
10449829 | 01 eerste verdieping
10449835 | 01c derde tussenverdieping | Model Group:Hijsloods stalen liggers:10439407
10449837 | 01c derde tussenverdieping | Model Group:Hijsloods stalen liggers:10439407

# IfcBeam: ligger stripstaal RECT_500x10 (2)
In: 04 vierde verdieping
Type - ElementType: ligger stripstaal RECT_500x10; PredefinedType: BEAM; Classification: 28.11 hoofddraagconstructies - kolommen en liggers, kolom-/liggerconstructies (Uniformat); Material: NLRS_h2_staal
Pset_BeamCommon - LoadBearing: yes; IsExternal: yes; Slope: 0 deg; Reference: ligger stripstaal RECT_500x10; Span: 1930 mm
Name (NLRS_28.11_SF_WPB_stalen ligger stripstaal_gen:ligger stripstaal RECT_500x10:...)
10465158
10465160

# IfcBuildingElementProxy: NLRS_24.11_GM_UN_prefab trap parking bordes l=2020_gen (3)
Type - Classification: 24.11 trappen en hellingen - trappen, rechte steektrappen (Uniformat)
Pset_BuildingElementProxyCommon - Reference: NLRS_24.11_GM_UN_prefab trap parking bordes l=2020_gen
Name (NLRS_24.11_GM_UN_prefab trap parking_gen:NLRS_24.11_GM_UN_prefab trap parking bordes l=2020_gen:...) | In
5734895 | 00a eerste tussenverdieping
5747234 | 01b tweede tussenverdieping
5747242 | 02a eerste tussenverdieping

# IfcBuildingElementProxy: NLRS_24.11_GM_UN_prefab trap parking bordes l=2245 b=1230_gen (3)
Type - Classification: 24.11 trappen en hellingen - trappen, rechte steektrappen (Uniformat); Material: Analytical Floor Surface
Pset_BuildingElementProxyCommon - Reference: NLRS_24.11_GM_UN_prefab trap parking bordes l=2245 b=1230_gen
Name (NLRS_24.11_GM_UN_prefab trap parking_gen:NLRS_24.11_GM_UN_prefab trap parking bordes l=2245 b=1230_gen:...) | In
7637163 | 02a eerste tussenverdieping
7638165 | 00a eerste tussenverdieping
7638219 | 01b tweede tussenverdieping

# IfcBuildingElementProxy: NLRS_24.11_GM_UN_prefab trap parking bordes l=2245_gen (3)
Type - Classification: 24.11 trappen en hellingen - trappen, rechte steektrappen (Uniformat)
Pset_BuildingElementProxyCommon - Reference: NLRS_24.11_GM_UN_prefab trap parking bordes l=2245_gen
Name (NLRS_24.11_GM_UN_prefab trap parking_gen:NLRS_24.11_GM_UN_prefab trap parking bordes l=2245_gen:...) | In
5743728 | 00a eerste tussenverdieping
5746728 | 01b tweede tussenverdieping
5746736 | 02a eerste tussenverdieping

# IfcBuildingElementProxy: isokorf QPZXT 75 E_gen (6)
In: 04 vierde verdieping
Pset_BuildingElementProxyCommon - Reference: isokorf QPZXT 75 E_gen
Name (NLRS_01.00_GM_WPB_isokorf QPZXT 75 E_gen:isokorf QPZXT 75 E_gen:...)
10949792
10949794
10949795
10949796
10949797
10955483

# IfcColumn: 250x400 (4)
In: 04 vierde verdieping
Type - ElementType: 250x400; PredefinedType: COLUMN; Classification: 28.11 hoofddraagconstructies - kolommen en liggers, kolom-/liggerconstructies (Uniformat); Material: NLRS_f2_beton prefab
Pset_ColumnCommon - LoadBearing: yes; IsExternal: no; Reference: 250x400
Name (NLRS_28.11_SCO_TLB_prefabbeton kolom vierkant_gen1:250x400:...)
5713755
5713757
5713759
5713761

# IfcColumn: 290x250 (8)
Type - ElementType: 290x250; PredefinedType: COLUMN; Classification: 28.11 hoofddraagconstructies - kolommen en liggers, kolom-/liggerconstructies (Uniformat); Material: NLRS_f2_beton ihwg
Pset_ColumnCommon - LoadBearing: yes; IsExternal: no; Reference: 290x250
Name (NLRS_28.11_SCO_TLB_beton kolom ihwg_gen:290x250:...) | In
7332375 | 00 begane grond
7333172 | 01 eerste verdieping
7333222 | 02 tweede verdieping
7333245 | 03 derde verdieping
7333505 | 00 begane grond
7333695 | 03 derde verdieping
7333730 | 01 eerste verdieping
7333764 | 02 tweede verdieping

# IfcColumn: 300x1100 (5)
In: 00 begane grond
Type - ElementType: 300x1100; PredefinedType: COLUMN; Classification: 28.11 hoofddraagconstructies - kolommen en liggers, kolom-/liggerconstructies (Uniformat); Material: NLRS_f2_beton prefab
Pset_ColumnCommon - LoadBearing: yes; IsExternal: no; Reference: 300x1100
Name (NLRS_28.11_SCO_TLB_prefabbeton kolom vierkant_gen1:300x1100:...)
5707229
5707231
5707233
5707235
5708559

# IfcColumn: 300x300 opstort, NLRS_28.11_SCO_TLB_beton kolom ihwg_gen:300x300 opstort:7381139
In: 00 begane grond
Type - ElementType: 300x300 opstort; PredefinedType: COLUMN; Classification: 28.11 hoofddraagconstructies - kolommen en liggers, kolom-/liggerconstructies (Uniformat); Material: NLRS_f2_beton ihwg
Pset_ColumnCommon - LoadBearing: yes; IsExternal: no; Reference: 300x300 opstort

# IfcColumn: 300x550 (5)
In: 01b tweede tussenverdieping
Type - ElementType: 300x550; PredefinedType: COLUMN; Classification: 28.11 hoofddraagconstructies - kolommen en liggers, kolom-/liggerconstructies (Uniformat); Material: NLRS_f2_beton prefab
Pset_ColumnCommon - LoadBearing: yes; IsExternal: no; Reference: 300x550
Name (NLRS_28.11_SCO_TLB_prefabbeton kolom vierkant_gen1:300x550:...)
5711304
5711306
5711308
5711310
5711312

# IfcColumn: 300x600 (2)
Type - ElementType: 300x600; PredefinedType: COLUMN; Classification: 28.11 hoofddraagconstructies - kolommen en liggers, kolom-/liggerconstructies (Uniformat); Material: NLRS_f2_beton prefab
Pset_ColumnCommon - LoadBearing: yes; IsExternal: no; Reference: 300x600
Name (NLRS_28.11_SCO_TLB_prefabbeton kolom vierkant_gen1:300x600:...) | In
4479358 | 00 begane grond
5235587 | 01a eerste tussenverdieping

# IfcColumn: 400x400 (5)
In: 00 begane grond
Type - ElementType: 400x400; PredefinedType: COLUMN; Classification: 28.11 hoofddraagconstructies - kolommen en liggers, kolom-/liggerconstructies (Uniformat); Material: NLRS_f2_beton prefab
Pset_ColumnCommon - LoadBearing: yes; IsExternal: no; Reference: 400x400
Name (NLRS_28.11_SCO_TLB_prefabbeton kolom vierkant_gen:400x400:...)
4269729
4269744
4269759
4269776
4269791

# IfcColumn: 400x450 opstort GOI (32)
In: 23 dakverdieping
Type - ElementType: 400x450 opstort GOI; PredefinedType: COLUMN; Classification: 28.11 hoofddraagconstructies - kolommen en liggers, kolom-/liggerconstructies (Uniformat); Material: NLRS_f2_beton ihwg
Pset_ColumnCommon - LoadBearing: yes; IsExternal: no; Reference: 400x450 opstort GOI
Name (NLRS_28.11_SCO_TLB_beton kolom ihwg_gen:400x450 opstort GOI:...) | Group
13244528 | Model Group:NLRS_01.00_verdieping 21--23_gen (members excluded):4846692
13245715 | Model Group:NLRS_01.00_verdieping 21--23_gen (members excluded):4846692
13245727 | Model Group:NLRS_01.00_verdieping 21--23_gen (members excluded):4846692
13245739 | Model Group:NLRS_01.00_verdieping 21--23_gen (members excluded):4846692
13245757 | Model Group:NLRS_01.00_verdieping 21--23_gen (members excluded):4846692
13245771 | Model Group:NLRS_01.00_verdieping 21--23_gen (members excluded):4846692
13245785 | Model Group:NLRS_01.00_verdieping 21--23_gen (members excluded):4846692
13245799 | Model Group:NLRS_01.00_verdieping 21--23_gen (members excluded):4846692
13245934 | Model Group:NLRS_01.00_verdieping 21--23_gen (members excluded):4846692
13245938 | Model Group:NLRS_01.00_verdieping 21--23_gen (members excluded):4846692
13245940 | Model Group:NLRS_01.00_verdieping 21--23_gen (members excluded):4846692
13245942 | Model Group:NLRS_01.00_verdieping 21--23_gen (members excluded):4846692
13245944 | Model Group:NLRS_01.00_verdieping 21--23_gen (members excluded):4846692
13245946 | Model Group:NLRS_01.00_verdieping 21--23_gen (members excluded):4846692
13245948 | Model Group:NLRS_01.00_verdieping 21--23_gen (members excluded):4846692
13245950 | Model Group:NLRS_01.00_verdieping 21--23_gen (members excluded):4846692
13247038 | Model Group:NLRS_01.00_verdieping 21--23_gen (members excluded):4647240
13247044 | Model Group:NLRS_01.00_verdieping 21--23_gen (members excluded):4647240
13247046 | Model Group:NLRS_01.00_verdieping 21--23_gen (members excluded):4647240
13247048 | Model Group:NLRS_01.00_verdieping 21--23_gen (members excluded):4647240
13247050 | Model Group:NLRS_01.00_verdieping 21--23_gen (members excluded):4647240
13247052 | Model Group:NLRS_01.00_verdieping 21--23_gen (members excluded):4647240
13247054 | Model Group:NLRS_01.00_verdieping 21--23_gen (members excluded):4647240
13247056 | Model Group:NLRS_01.00_verdieping 21--23_gen (members excluded):4647240
13247058 | Model Group:NLRS_01.00_verdieping 21--23_gen (members excluded):4647240
13247062 | Model Group:NLRS_01.00_verdieping 21--23_gen (members excluded):4647240
13247064 | Model Group:NLRS_01.00_verdieping 21--23_gen (members excluded):4647240
13247066 | Model Group:NLRS_01.00_verdieping 21--23_gen (members excluded):4647240
13247068 | Model Group:NLRS_01.00_verdieping 21--23_gen (members excluded):4647240
13247070 | Model Group:NLRS_01.00_verdieping 21--23_gen (members excluded):4647240
13247072 | Model Group:NLRS_01.00_verdieping 21--23_gen (members excluded):4647240
13247074 | Model Group:NLRS_01.00_verdieping 21--23_gen (members excluded):4647240

# IfcColumn: 400x850 (64)
Type - ElementType: 400x850; PredefinedType: COLUMN; Classification: 28.11 hoofddraagconstructies - kolommen en liggers, kolom-/liggerconstructies (Uniformat); Material: NLRS_f2_beton prefab
Pset_ColumnCommon - Reference: 400x850; LoadBearing: yes; IsExternal: no
Name (NLRS_28.11_SCO_TLB_prefabbeton kolom vierkant_gen:400x850:...) | In
4106742 | 00 begane grond
4260725 | 00 begane grond
4260737 | 00 begane grond
4260743 | 00 begane grond
4260749 | 00 begane grond
4260771 | 00 begane grond
4260777 | 00 begane grond
4260783 | 00 begane grond
4263038 | 00 begane grond
4263057 | 00 begane grond
4263091 | 00 begane grond
4263110 | 00 begane grond
4263125 | 00 begane grond
4349027 | 01a eerste tussenverdieping
4349029 | 01a eerste tussenverdieping
4349033 | 01a eerste tussenverdieping
4349035 | 01a eerste tussenverdieping
4349037 | 01a eerste tussenverdieping
4349049 | 01a eerste tussenverdieping
4349051 | 01a eerste tussenverdieping
4349055 | 01a eerste tussenverdieping
4349057 | 01a eerste tussenverdieping
4349059 | 01a eerste tussenverdieping
4349155 | 01c derde tussenverdieping
4349157 | 01c derde tussenverdieping
4349161 | 01c derde tussenverdieping
4349163 | 01c derde tussenverdieping
4349165 | 01c derde tussenverdieping
4349177 | 01c derde tussenverdieping
4349179 | 01c derde tussenverdieping
4349183 | 01c derde tussenverdieping
4349185 | 01c derde tussenverdieping
4349187 | 01c derde tussenverdieping
4349277 | 02b tweede tussenverdieping
4349279 | 02b tweede tussenverdieping
4349283 | 02b tweede tussenverdieping
4349285 | 02b tweede tussenverdieping
4349287 | 02b tweede tussenverdieping
4349299 | 02b tweede tussenverdieping
4349301 | 02b tweede tussenverdieping
4349305 | 02b tweede tussenverdieping
4349307 | 02b tweede tussenverdieping
4349309 | 02b tweede tussenverdieping
4350188 | 01a eerste tussenverdieping
4350190 | 01a eerste tussenverdieping
4350232 | 01c derde tussenverdieping
4350234 | 01c derde tussenverdieping
4350267 | 02b tweede tussenverdieping
4350269 | 02b tweede tussenverdieping
4512396 | 01a eerste tussenverdieping
4512549 | 01c derde tussenverdieping
4512565 | 02b tweede tussenverdieping
5014926 | 00 begane grond
5014928 | 00 begane grond
5014930 | 00 begane grond
5015014 | 01a eerste tussenverdieping
5015016 | 01a eerste tussenverdieping
5015022 | 01c derde tussenverdieping
5015024 | 01c derde tussenverdieping
5015030 | 02b tweede tussenverdieping
5015032 | 02b tweede tussenverdieping
5029803 | 01a eerste tussenverdieping
5029805 | 01c derde tussenverdieping
5029807 | 02b tweede tussenverdieping

# IfcColumn: 410x250 (8)
Type - ElementType: 410x250; PredefinedType: COLUMN; Classification: 28.11 hoofddraagconstructies - kolommen en liggers, kolom-/liggerconstructies (Uniformat); Material: NLRS_f2_beton ihwg
Pset_ColumnCommon - LoadBearing: yes; IsExternal: no; Reference: 410x250
Name (NLRS_28.11_SCO_TLB_beton kolom ihwg_gen:410x250:...) | In
4326439 | 00 begane grond
4330815 | 01 eerste verdieping
4330882 | 02 tweede verdieping
4332973 | 03 derde verdieping
4333313 | 00 begane grond
4333331 | 01 eerste verdieping
4333349 | 02 tweede verdieping
4333381 | 03 derde verdieping

# IfcColumn: 410x360 (30)
Type - ElementType: 410x360; PredefinedType: COLUMN; Classification: 28.11 hoofddraagconstructies - kolommen en liggers, kolom-/liggerconstructies (Uniformat); Material: NLRS_f2_beton prefab
Pset_ColumnCommon - LoadBearing: yes; IsExternal: no; Reference: 410x360
Name (NLRS_28.11_SCO_TLB_prefabbeton kolom vierkant_gen:410x360:...) | In | Group
12239478 | 06 zesde verdieping | Model Group:NLRS_01.00_verdieping 06--10_gen:4844478
12239612 | 11 elfde verdieping | Model Group:NLRS_01.00_verdieping 11--17_gen:4845821
12240923 | 06 zesde verdieping | Model Group:NLRS_01.00_verdieping 06--10_gen:4600460
12240931 | 07 zevende verdieping | Model Group:NLRS_01.00_verdieping 06--10_gen:4600975
12240935 | 08 achtste verdieping | Model Group:NLRS_01.00_verdieping 06--10_gen:4602043
12240939 | 09 negende verdieping | Model Group:NLRS_01.00_verdieping 06--10_gen:4603152
12240943 | 10 tiende verdieping | Model Group:NLRS_01.00_verdieping 06--10_gen:4604220
12240967 | 07 zevende verdieping | Model Group:NLRS_01.00_verdieping 06--10_gen:4844553
12240971 | 08 achtste verdieping | Model Group:NLRS_01.00_verdieping 06--10_gen:4844628
12240975 | 09 negende verdieping | Model Group:NLRS_01.00_verdieping 06--10_gen:4844703
12240979 | 10 tiende verdieping | Model Group:NLRS_01.00_verdieping 06--10_gen:4844850
12241427 | 18 achttiende verdieping | Model Group:NLRS_01.00_verdieping 18-19_gen:4845405
12243078 | 12 twaalfde verdieping | Model Group:NLRS_01.00_verdieping 11--17_gen:4609129
12243086 | 13 dertiende verdieping | Model Group:NLRS_01.00_verdieping 11--17_gen:4609592
12243090 | 14 veertiende verdieping | Model Group:NLRS_01.00_verdieping 11--17_gen:4610618
12243094 | 15 vijftiende verdieping | Model Group:NLRS_01.00_verdieping 11--17_gen:4611642
12243098 | 16 zestiende verdieping | Model Group:NLRS_01.00_verdieping 11--17_gen:4612668
12243102 | 17 zeventiende verdieping | Model Group:NLRS_01.00_verdieping 11--17_gen:4613692
12243106 | 11 elfde verdieping | Model Group:NLRS_01.00_verdieping 11--17_gen:4626135
12243138 | 12 twaalfde verdieping | Model Group:NLRS_01.00_verdieping 11--17_gen:4844919
12243142 | 13 dertiende verdieping | Model Group:NLRS_01.00_verdieping 11--17_gen:4844988
12243146 | 14 veertiende verdieping | Model Group:NLRS_01.00_verdieping 11--17_gen:4845057
12243150 | 15 vijftiende verdieping | Model Group:NLRS_01.00_verdieping 11--17_gen:4845126
12243154 | 16 zestiende verdieping | Model Group:NLRS_01.00_verdieping 11--17_gen:4845195
12243158 | 17 zeventiende verdieping | Model Group:NLRS_01.00_verdieping 11--17_gen:4845336
12243893 | 18 achttiende verdieping | Model Group:NLRS_01.00_verdieping 18-19_gen:4617185
12243901 | 19 negentiende verdieping | Model Group:NLRS_01.00_verdieping 18-19_gen:4617669
12243913 | 19 negentiende verdieping | Model Group:NLRS_01.00_verdieping 18-19_gen:4845546
12244335 | 05 vijfde verdieping | Model Group:NLRS_01.00_verdieping 05_gen:6691052
12244622 | 05 vijfde verdieping | Model Group:NLRS_01.00_verdieping 05_gen (members excluded):6698157

# IfcColumn: 410x410 (8)
In: 03 derde verdieping
Type - ElementType: 410x410; PredefinedType: COLUMN; Classification: 28.11 hoofddraagconstructies - kolommen en liggers, kolom-/liggerconstructies (Uniformat); Material: NLRS_f2_beton ihwg
Pset_ColumnCommon - LoadBearing: yes; IsExternal: no; Reference: 410x410
Name (NLRS_28.11_SCO_TLB_beton kolom ihwg_gen:410x410:...)
4330935
4330937
4330939
4332004
4333353
4333355
4333357
4333365

# IfcColumn: 410x410 (134)
Type - ElementType: 410x410; PredefinedType: COLUMN; Classification: 28.11 hoofddraagconstructies - kolommen en liggers, kolom-/liggerconstructies (Uniformat); Material: NLRS_f2_beton prefab
Pset_ColumnCommon - LoadBearing: yes; IsExternal: no; Reference: 410x410
Name | In | Group
NLRS_28.11_SCO_TLB_prefabbeton kolom vierkant_gen:410x410:4575107 | 04 vierde verdieping | Model Group:NLRS_01.00_verdieping 04_gen (members excluded):4585793
NLRS_28.11_SCO_TLB_prefabbeton kolom vierkant_gen:410x410:4576002 | 04 vierde verdieping | Model Group:NLRS_01.00_verdieping 04_gen (members excluded):4585793
NLRS_28.11_SCO_TLB_prefabbeton kolom vierkant_gen:410x410:4599018 | 06 zesde verdieping | Model Group:NLRS_01.00_verdieping 06--10_gen:4600460
NLRS_28.11_SCO_TLB_prefabbeton kolom vierkant_gen1:410x410:4599057 | 06 zesde verdieping | Model Group:NLRS_01.00_verdieping 06--10_gen:4600460
NLRS_28.11_SCO_TLB_prefabbeton kolom vierkant_gen:410x410:4599086 | 06 zesde verdieping | Model Group:NLRS_01.00_verdieping 06--10_gen:4600460
NLRS_28.11_SCO_TLB_prefabbeton kolom vierkant_gen:410x410:4599129 | 06 zesde verdieping | Model Group:NLRS_01.00_verdieping 06--10_gen:4600460
NLRS_28.11_SCO_TLB_prefabbeton kolom vierkant_gen:410x410:4600755 | 07 zevende verdieping | Model Group:NLRS_01.00_verdieping 06--10_gen:4600975
NLRS_28.11_SCO_TLB_prefabbeton kolom vierkant_gen1:410x410:4600794 | 07 zevende verdieping | Model Group:NLRS_01.00_verdieping 06--10_gen:4600975
NLRS_28.11_SCO_TLB_prefabbeton kolom vierkant_gen:410x410:4600823 | 07 zevende verdieping | Model Group:NLRS_01.00_verdieping 06--10_gen:4600975
NLRS_28.11_SCO_TLB_prefabbeton kolom vierkant_gen:410x410:4600866 | 07 zevende verdieping | Model Group:NLRS_01.00_verdieping 06--10_gen:4600975
NLRS_28.11_SCO_TLB_prefabbeton kolom vierkant_gen:410x410:4601823 | 08 achtste verdieping | Model Group:NLRS_01.00_verdieping 06--10_gen:4602043
NLRS_28.11_SCO_TLB_prefabbeton kolom vierkant_gen1:410x410:4601862 | 08 achtste verdieping | Model Group:NLRS_01.00_verdieping 06--10_gen:4602043
NLRS_28.11_SCO_TLB_prefabbeton kolom vierkant_gen:410x410:4601891 | 08 achtste verdieping | Model Group:NLRS_01.00_verdieping 06--10_gen:4602043
NLRS_28.11_SCO_TLB_prefabbeton kolom vierkant_gen:410x410:4601934 | 08 achtste verdieping | Model Group:NLRS_01.00_verdieping 06--10_gen:4602043
NLRS_28.11_SCO_TLB_prefabbeton kolom vierkant_gen:410x410:4602932 | 09 negende verdieping | Model Group:NLRS_01.00_verdieping 06--10_gen:4603152
NLRS_28.11_SCO_TLB_prefabbeton kolom vierkant_gen1:410x410:4602971 | 09 negende verdieping | Model Group:NLRS_01.00_verdieping 06--10_gen:4603152
NLRS_28.11_SCO_TLB_prefabbeton kolom vierkant_gen:410x410:4603000 | 09 negende verdieping | Model Group:NLRS_01.00_verdieping 06--10_gen:4603152
NLRS_28.11_SCO_TLB_prefabbeton kolom vierkant_gen:410x410:4603043 | 09 negende verdieping | Model Group:NLRS_01.00_verdieping 06--10_gen:4603152
NLRS_28.11_SCO_TLB_prefabbeton kolom vierkant_gen:410x410:4604000 | 10 tiende verdieping | Model Group:NLRS_01.00_verdieping 06--10_gen:4604220
NLRS_28.11_SCO_TLB_prefabbeton kolom vierkant_gen1:410x410:4604039 | 10 tiende verdieping | Model Group:NLRS_01.00_verdieping 06--10_gen:4604220
NLRS_28.11_SCO_TLB_prefabbeton kolom vierkant_gen:410x410:4604068 | 10 tiende verdieping | Model Group:NLRS_01.00_verdieping 06--10_gen:4604220
NLRS_28.11_SCO_TLB_prefabbeton kolom vierkant_gen:410x410:4604111 | 10 tiende verdieping | Model Group:NLRS_01.00_verdieping 06--10_gen:4604220
NLRS_28.11_SCO_TLB_prefabbeton kolom vierkant_gen:410x410:4608008 | 12 twaalfde verdieping | Model Group:NLRS_01.00_verdieping 11--17_gen:4609129
NLRS_28.11_SCO_TLB_prefabbeton kolom vierkant_gen1:410x410:4608047 | 12 twaalfde verdieping | Model Group:NLRS_01.00_verdieping 11--17_gen:4609129
NLRS_28.11_SCO_TLB_prefabbeton kolom vierkant_gen:410x410:4608076 | 12 twaalfde verdieping | Model Group:NLRS_01.00_verdieping 11--17_gen:4609129
NLRS_28.11_SCO_TLB_prefabbeton kolom vierkant_gen:410x410:4608119 | 12 twaalfde verdieping | Model Group:NLRS_01.00_verdieping 11--17_gen:4609129
NLRS_28.11_SCO_TLB_prefabbeton kolom vierkant_gen:410x410:4609378 | 13 dertiende verdieping | Model Group:NLRS_01.00_verdieping 11--17_gen:4609592
NLRS_28.11_SCO_TLB_prefabbeton kolom vierkant_gen1:410x410:4609417 | 13 dertiende verdieping | Model Group:NLRS_01.00_verdieping 11--17_gen:4609592
NLRS_28.11_SCO_TLB_prefabbeton kolom vierkant_gen:410x410:4609446 | 13 dertiende verdieping | Model Group:NLRS_01.00_verdieping 11--17_gen:4609592
NLRS_28.11_SCO_TLB_prefabbeton kolom vierkant_gen:410x410:4609489 | 13 dertiende verdieping | Model Group:NLRS_01.00_verdieping 11--17_gen:4609592
NLRS_28.11_SCO_TLB_prefabbeton kolom vierkant_gen:410x410:4610404 | 14 veertiende verdieping | Model Group:NLRS_01.00_verdieping 11--17_gen:4610618
NLRS_28.11_SCO_TLB_prefabbeton kolom vierkant_gen1:410x410:4610443 | 14 veertiende verdieping | Model Group:NLRS_01.00_verdieping 11--17_gen:4610618
NLRS_28.11_SCO_TLB_prefabbeton kolom vierkant_gen:410x410:4610472 | 14 veertiende verdieping | Model Group:NLRS_01.00_verdieping 11--17_gen:4610618
NLRS_28.11_SCO_TLB_prefabbeton kolom vierkant_gen:410x410:4610515 | 14 veertiende verdieping | Model Group:NLRS_01.00_verdieping 11--17_gen:4610618
NLRS_28.11_SCO_TLB_prefabbeton kolom vierkant_gen:410x410:4611428 | 15 vijftiende verdieping | Model Group:NLRS_01.00_verdieping 11--17_gen:4611642
NLRS_28.11_SCO_TLB_prefabbeton kolom vierkant_gen1:410x410:4611467 | 15 vijftiende verdieping | Model Group:NLRS_01.00_verdieping 11--17_gen:4611642
NLRS_28.11_SCO_TLB_prefabbeton kolom vierkant_gen:410x410:4611496 | 15 vijftiende verdieping | Model Group:NLRS_01.00_verdieping 11--17_gen:4611642
NLRS_28.11_SCO_TLB_prefabbeton kolom vierkant_gen:410x410:4611539 | 15 vijftiende verdieping | Model Group:NLRS_01.00_verdieping 11--17_gen:4611642
NLRS_28.11_SCO_TLB_prefabbeton kolom vierkant_gen:410x410:4612454 | 16 zestiende verdieping | Model Group:NLRS_01.00_verdieping 11--17_gen:4612668
NLRS_28.11_SCO_TLB_prefabbeton kolom vierkant_gen1:410x410:4612493 | 16 zestiende verdieping | Model Group:NLRS_01.00_verdieping 11--17_gen:4612668
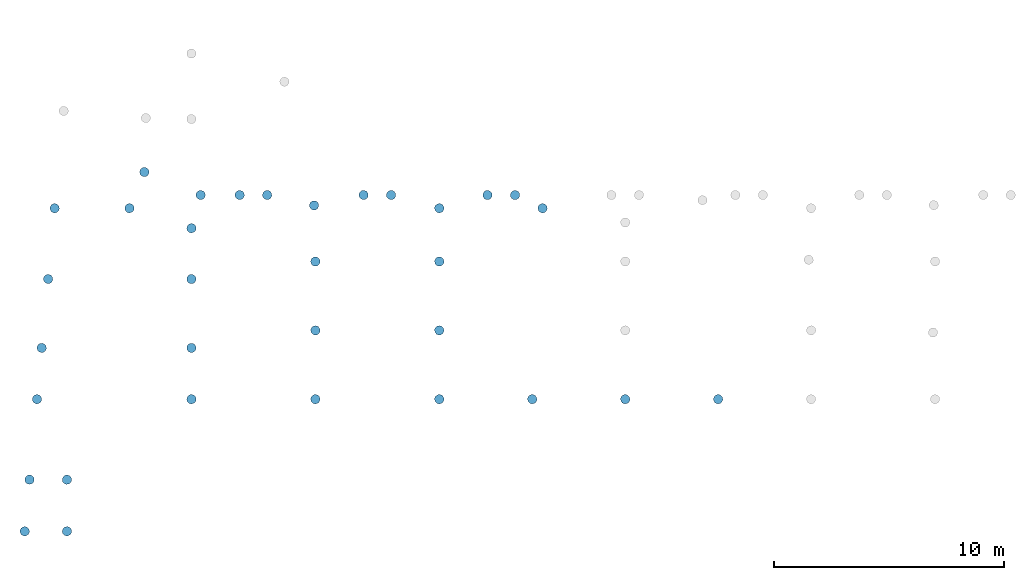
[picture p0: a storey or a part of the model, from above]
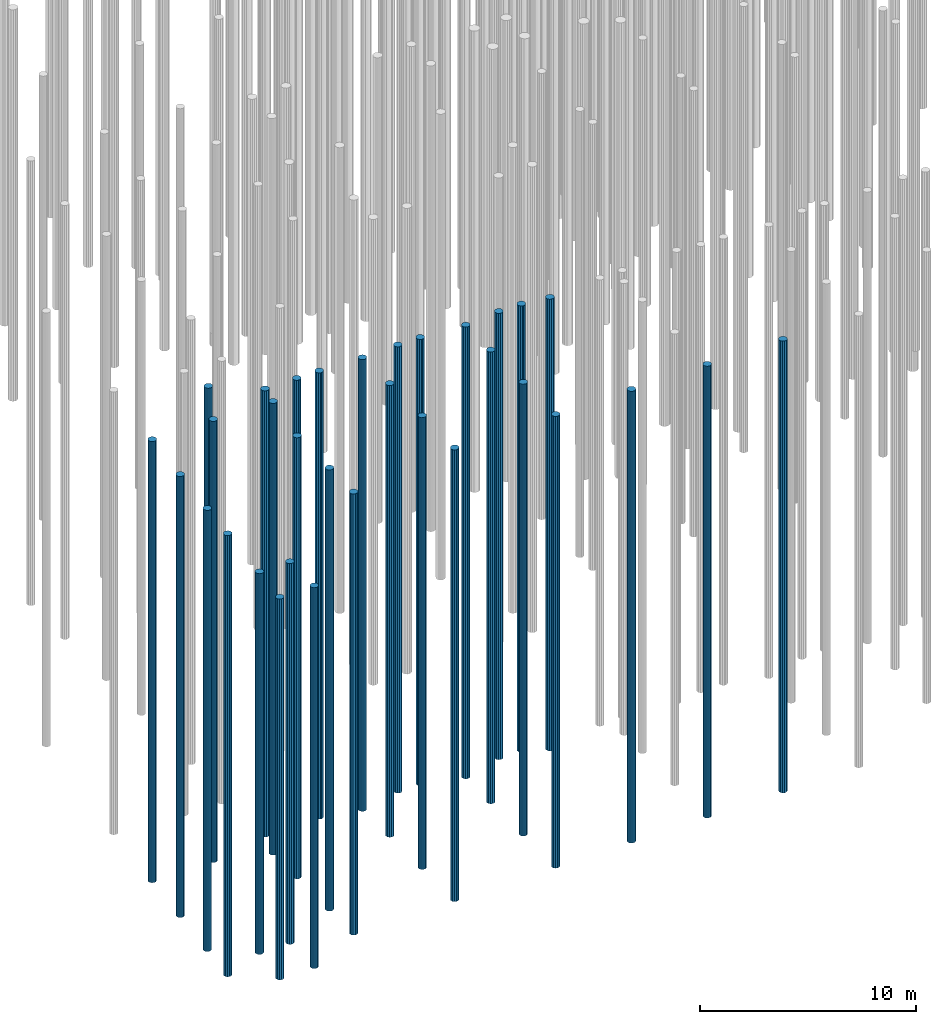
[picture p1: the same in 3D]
Properties of the parts of a building model (IFC2X3), part 3 of 11

# IfcColumn: 410x410 (134)
Name | In | Group
NLRS_28.11_SCO_TLB_prefabbeton kolom vierkant_gen:410x410:4612522 | 16 zestiende verdieping | Model Group:NLRS_01.00_verdieping 11--17_gen:4612668
NLRS_28.11_SCO_TLB_prefabbeton kolom vierkant_gen:410x410:4612565 | 16 zestiende verdieping | Model Group:NLRS_01.00_verdieping 11--17_gen:4612668
NLRS_28.11_SCO_TLB_prefabbeton kolom vierkant_gen:410x410:4613478 | 17 zeventiende verdieping | Model Group:NLRS_01.00_verdieping 11--17_gen:4613692
NLRS_28.11_SCO_TLB_prefabbeton kolom vierkant_gen1:410x410:4613517 | 17 zeventiende verdieping | Model Group:NLRS_01.00_verdieping 11--17_gen:4613692
NLRS_28.11_SCO_TLB_prefabbeton kolom vierkant_gen:410x410:4613546 | 17 zeventiende verdieping | Model Group:NLRS_01.00_verdieping 11--17_gen:4613692
NLRS_28.11_SCO_TLB_prefabbeton kolom vierkant_gen:410x410:4613589 | 17 zeventiende verdieping | Model Group:NLRS_01.00_verdieping 11--17_gen:4613692
NLRS_28.11_SCO_TLB_prefabbeton kolom vierkant_gen:410x410:4615968 | 18 achttiende verdieping | Model Group:NLRS_01.00_verdieping 18-19_gen:4617185
NLRS_28.11_SCO_TLB_prefabbeton kolom vierkant_gen1:410x410:4616007 | 18 achttiende verdieping | Model Group:NLRS_01.00_verdieping 18-19_gen:4617185
NLRS_28.11_SCO_TLB_prefabbeton kolom vierkant_gen:410x410:4616036 | 18 achttiende verdieping | Model Group:NLRS_01.00_verdieping 18-19_gen:4617185
NLRS_28.11_SCO_TLB_prefabbeton kolom vierkant_gen:410x410:4616079 | 18 achttiende verdieping | Model Group:NLRS_01.00_verdieping 18-19_gen:4617185
NLRS_28.11_SCO_TLB_prefabbeton kolom vierkant_gen:410x410:4617455 | 19 negentiende verdieping | Model Group:NLRS_01.00_verdieping 18-19_gen:4617669
NLRS_28.11_SCO_TLB_prefabbeton kolom vierkant_gen1:410x410:4617494 | 19 negentiende verdieping | Model Group:NLRS_01.00_verdieping 18-19_gen:4617669
NLRS_28.11_SCO_TLB_prefabbeton kolom vierkant_gen:410x410:4617523 | 19 negentiende verdieping | Model Group:NLRS_01.00_verdieping 18-19_gen:4617669
NLRS_28.11_SCO_TLB_prefabbeton kolom vierkant_gen:410x410:4617566 | 19 negentiende verdieping | Model Group:NLRS_01.00_verdieping 18-19_gen:4617669
NLRS_28.11_SCO_TLB_prefabbeton kolom vierkant_gen:410x410:4618552 | 20 twintigste verdieping | Model Group:NLRS_01.00_verdieping 20_gen:4622361
NLRS_28.11_SCO_TLB_prefabbeton kolom vierkant_gen1:410x410:4618591 | 20 twintigste verdieping | Model Group:NLRS_01.00_verdieping 20_gen:4622361
NLRS_28.11_SCO_TLB_prefabbeton kolom vierkant_gen:410x410:4618620 | 20 twintigste verdieping | Model Group:NLRS_01.00_verdieping 20_gen:4622361
NLRS_28.11_SCO_TLB_prefabbeton kolom vierkant_gen:410x410:4618663 | 20 twintigste verdieping | Model Group:NLRS_01.00_verdieping 20_gen:4622361
NLRS_28.11_SCO_TLB_prefabbeton kolom vierkant_gen:410x410:4625921 | 11 elfde verdieping | Model Group:NLRS_01.00_verdieping 11--17_gen:4626135
NLRS_28.11_SCO_TLB_prefabbeton kolom vierkant_gen1:410x410:4625960 | 11 elfde verdieping | Model Group:NLRS_01.00_verdieping 11--17_gen:4626135
NLRS_28.11_SCO_TLB_prefabbeton kolom vierkant_gen:410x410:4625989 | 11 elfde verdieping | Model Group:NLRS_01.00_verdieping 11--17_gen:4626135
NLRS_28.11_SCO_TLB_prefabbeton kolom vierkant_gen:410x410:4626032 | 11 elfde verdieping | Model Group:NLRS_01.00_verdieping 11--17_gen:4626135
NLRS_28.11_SCO_TLB_prefabbeton kolom vierkant_gen:410x410:4844293 | 04 vierde verdieping | Model Group:NLRS_01.00_verdieping 04_gen (members excluded):4844403
NLRS_28.11_SCO_TLB_prefabbeton kolom vierkant_gen:410x410:4844299 | 04 vierde verdieping | Model Group:NLRS_01.00_verdieping 04_gen (members excluded):4844403
NLRS_28.11_SCO_TLB_prefabbeton kolom vierkant_gen:410x410:4844404 | 06 zesde verdieping | Model Group:NLRS_01.00_verdieping 06--10_gen:4844478
NLRS_28.11_SCO_TLB_prefabbeton kolom vierkant_gen1:410x410:4844407 | 06 zesde verdieping | Model Group:NLRS_01.00_verdieping 06--10_gen:4844478
NLRS_28.11_SCO_TLB_prefabbeton kolom vierkant_gen:410x410:4844436 | 06 zesde verdieping | Model Group:NLRS_01.00_verdieping 06--10_gen:4844478
NLRS_28.11_SCO_TLB_prefabbeton kolom vierkant_gen:410x410:4844443 | 06 zesde verdieping | Model Group:NLRS_01.00_verdieping 06--10_gen:4844478
NLRS_28.11_SCO_TLB_prefabbeton kolom vierkant_gen:410x410:4844479 | 07 zevende verdieping | Model Group:NLRS_01.00_verdieping 06--10_gen:4844553
NLRS_28.11_SCO_TLB_prefabbeton kolom vierkant_gen1:410x410:4844482 | 07 zevende verdieping | Model Group:NLRS_01.00_verdieping 06--10_gen:4844553
NLRS_28.11_SCO_TLB_prefabbeton kolom vierkant_gen:410x410:4844511 | 07 zevende verdieping | Model Group:NLRS_01.00_verdieping 06--10_gen:4844553
NLRS_28.11_SCO_TLB_prefabbeton kolom vierkant_gen:410x410:4844518 | 07 zevende verdieping | Model Group:NLRS_01.00_verdieping 06--10_gen:4844553
NLRS_28.11_SCO_TLB_prefabbeton kolom vierkant_gen:410x410:4844554 | 08 achtste verdieping | Model Group:NLRS_01.00_verdieping 06--10_gen:4844628
NLRS_28.11_SCO_TLB_prefabbeton kolom vierkant_gen1:410x410:4844557 | 08 achtste verdieping | Model Group:NLRS_01.00_verdieping 06--10_gen:4844628
NLRS_28.11_SCO_TLB_prefabbeton kolom vierkant_gen:410x410:4844586 | 08 achtste verdieping | Model Group:NLRS_01.00_verdieping 06--10_gen:4844628
NLRS_28.11_SCO_TLB_prefabbeton kolom vierkant_gen:410x410:4844593 | 08 achtste verdieping | Model Group:NLRS_01.00_verdieping 06--10_gen:4844628
NLRS_28.11_SCO_TLB_prefabbeton kolom vierkant_gen:410x410:4844629 | 09 negende verdieping | Model Group:NLRS_01.00_verdieping 06--10_gen:4844703
NLRS_28.11_SCO_TLB_prefabbeton kolom vierkant_gen1:410x410:4844632 | 09 negende verdieping | Model Group:NLRS_01.00_verdieping 06--10_gen:4844703
NLRS_28.11_SCO_TLB_prefabbeton kolom vierkant_gen:410x410:4844661 | 09 negende verdieping | Model Group:NLRS_01.00_verdieping 06--10_gen:4844703
NLRS_28.11_SCO_TLB_prefabbeton kolom vierkant_gen:410x410:4844668 | 09 negende verdieping | Model Group:NLRS_01.00_verdieping 06--10_gen:4844703
NLRS_28.11_SCO_TLB_prefabbeton kolom vierkant_gen:410x410:4844704 | 10 tiende verdieping | Model Group:NLRS_01.00_verdieping 06--10_gen:4844850
NLRS_28.11_SCO_TLB_prefabbeton kolom vierkant_gen1:410x410:4844707 | 10 tiende verdieping | Model Group:NLRS_01.00_verdieping 06--10_gen:4844850
NLRS_28.11_SCO_TLB_prefabbeton kolom vierkant_gen:410x410:4844736 | 10 tiende verdieping | Model Group:NLRS_01.00_verdieping 06--10_gen:4844850
NLRS_28.11_SCO_TLB_prefabbeton kolom vierkant_gen:410x410:4844743 | 10 tiende verdieping | Model Group:NLRS_01.00_verdieping 06--10_gen:4844850
NLRS_28.11_SCO_TLB_prefabbeton kolom vierkant_gen:410x410:4844851 | 12 twaalfde verdieping | Model Group:NLRS_01.00_verdieping 11--17_gen:4844919
NLRS_28.11_SCO_TLB_prefabbeton kolom vierkant_gen1:410x410:4844854 | 12 twaalfde verdieping | Model Group:NLRS_01.00_verdieping 11--17_gen:4844919
NLRS_28.11_SCO_TLB_prefabbeton kolom vierkant_gen:410x410:4844883 | 12 twaalfde verdieping | Model Group:NLRS_01.00_verdieping 11--17_gen:4844919
NLRS_28.11_SCO_TLB_prefabbeton kolom vierkant_gen:410x410:4844890 | 12 twaalfde verdieping | Model Group:NLRS_01.00_verdieping 11--17_gen:4844919
NLRS_28.11_SCO_TLB_prefabbeton kolom vierkant_gen:410x410:4844920 | 13 dertiende verdieping | Model Group:NLRS_01.00_verdieping 11--17_gen:4844988
NLRS_28.11_SCO_TLB_prefabbeton kolom vierkant_gen1:410x410:4844923 | 13 dertiende verdieping | Model Group:NLRS_01.00_verdieping 11--17_gen:4844988
NLRS_28.11_SCO_TLB_prefabbeton kolom vierkant_gen:410x410:4844952 | 13 dertiende verdieping | Model Group:NLRS_01.00_verdieping 11--17_gen:4844988
NLRS_28.11_SCO_TLB_prefabbeton kolom vierkant_gen:410x410:4844959 | 13 dertiende verdieping | Model Group:NLRS_01.00_verdieping 11--17_gen:4844988
NLRS_28.11_SCO_TLB_prefabbeton kolom vierkant_gen:410x410:4844989 | 14 veertiende verdieping | Model Group:NLRS_01.00_verdieping 11--17_gen:4845057
NLRS_28.11_SCO_TLB_prefabbeton kolom vierkant_gen1:410x410:4844992 | 14 veertiende verdieping | Model Group:NLRS_01.00_verdieping 11--17_gen:4845057
NLRS_28.11_SCO_TLB_prefabbeton kolom vierkant_gen:410x410:4845021 | 14 veertiende verdieping | Model Group:NLRS_01.00_verdieping 11--17_gen:4845057
NLRS_28.11_SCO_TLB_prefabbeton kolom vierkant_gen:410x410:4845028 | 14 veertiende verdieping | Model Group:NLRS_01.00_verdieping 11--17_gen:4845057
NLRS_28.11_SCO_TLB_prefabbeton kolom vierkant_gen:410x410:4845058 | 15 vijftiende verdieping | Model Group:NLRS_01.00_verdieping 11--17_gen:4845126
NLRS_28.11_SCO_TLB_prefabbeton kolom vierkant_gen1:410x410:4845061 | 15 vijftiende verdieping | Model Group:NLRS_01.00_verdieping 11--17_gen:4845126
NLRS_28.11_SCO_TLB_prefabbeton kolom vierkant_gen:410x410:4845090 | 15 vijftiende verdieping | Model Group:NLRS_01.00_verdieping 11--17_gen:4845126
NLRS_28.11_SCO_TLB_prefabbeton kolom vierkant_gen:410x410:4845097 | 15 vijftiende verdieping | Model Group:NLRS_01.00_verdieping 11--17_gen:4845126
NLRS_28.11_SCO_TLB_prefabbeton kolom vierkant_gen:410x410:4845127 | 16 zestiende verdieping | Model Group:NLRS_01.00_verdieping 11--17_gen:4845195
NLRS_28.11_SCO_TLB_prefabbeton kolom vierkant_gen1:410x410:4845130 | 16 zestiende verdieping | Model Group:NLRS_01.00_verdieping 11--17_gen:4845195
NLRS_28.11_SCO_TLB_prefabbeton kolom vierkant_gen:410x410:4845159 | 16 zestiende verdieping | Model Group:NLRS_01.00_verdieping 11--17_gen:4845195
NLRS_28.11_SCO_TLB_prefabbeton kolom vierkant_gen:410x410:4845166 | 16 zestiende verdieping | Model Group:NLRS_01.00_verdieping 11--17_gen:4845195
NLRS_28.11_SCO_TLB_prefabbeton kolom vierkant_gen:410x410:4845196 | 17 zeventiende verdieping | Model Group:NLRS_01.00_verdieping 11--17_gen:4845336
NLRS_28.11_SCO_TLB_prefabbeton kolom vierkant_gen1:410x410:4845199 | 17 zeventiende verdieping | Model Group:NLRS_01.00_verdieping 11--17_gen:4845336
NLRS_28.11_SCO_TLB_prefabbeton kolom vierkant_gen:410x410:4845228 | 17 zeventiende verdieping | Model Group:NLRS_01.00_verdieping 11--17_gen:4845336
NLRS_28.11_SCO_TLB_prefabbeton kolom vierkant_gen:410x410:4845235 | 17 zeventiende verdieping | Model Group:NLRS_01.00_verdieping 11--17_gen:4845336
NLRS_28.11_SCO_TLB_prefabbeton kolom vierkant_gen:410x410:4845337 | 18 achttiende verdieping | Model Group:NLRS_01.00_verdieping 18-19_gen:4845405
NLRS_28.11_SCO_TLB_prefabbeton kolom vierkant_gen1:410x410:4845340 | 18 achttiende verdieping | Model Group:NLRS_01.00_verdieping 18-19_gen:4845405
NLRS_28.11_SCO_TLB_prefabbeton kolom vierkant_gen:410x410:4845369 | 18 achttiende verdieping | Model Group:NLRS_01.00_verdieping 18-19_gen:4845405
NLRS_28.11_SCO_TLB_prefabbeton kolom vierkant_gen:410x410:4845376 | 18 achttiende verdieping | Model Group:NLRS_01.00_verdieping 18-19_gen:4845405
NLRS_28.11_SCO_TLB_prefabbeton kolom vierkant_gen:410x410:4845406 | 19 negentiende verdieping | Model Group:NLRS_01.00_verdieping 18-19_gen:4845546
NLRS_28.11_SCO_TLB_prefabbeton kolom vierkant_gen1:410x410:4845409 | 19 negentiende verdieping | Model Group:NLRS_01.00_verdieping 18-19_gen:4845546
NLRS_28.11_SCO_TLB_prefabbeton kolom vierkant_gen:410x410:4845438 | 19 negentiende verdieping | Model Group:NLRS_01.00_verdieping 18-19_gen:4845546
NLRS_28.11_SCO_TLB_prefabbeton kolom vierkant_gen:410x410:4845445 | 19 negentiende verdieping | Model Group:NLRS_01.00_verdieping 18-19_gen:4845546
NLRS_28.11_SCO_TLB_prefabbeton kolom vierkant_gen:410x410:4845547 | 20 twintigste verdieping | Model Group:NLRS_01.00_verdieping 20_gen:4845671
NLRS_28.11_SCO_TLB_prefabbeton kolom vierkant_gen1:410x410:4845550 | 20 twintigste verdieping | Model Group:NLRS_01.00_verdieping 20_gen:4845671
NLRS_28.11_SCO_TLB_prefabbeton kolom vierkant_gen:410x410:4845579 | 20 twintigste verdieping | Model Group:NLRS_01.00_verdieping 20_gen:4845671
NLRS_28.11_SCO_TLB_prefabbeton kolom vierkant_gen:410x410:4845586 | 20 twintigste verdieping | Model Group:NLRS_01.00_verdieping 20_gen:4845671
NLRS_28.11_SCO_TLB_prefabbeton kolom vierkant_gen1:410x410:4845678 | 05 vijfde verdieping | Model Group:NLRS_01.00_verdieping 05_gen:6691052
NLRS_28.11_SCO_TLB_prefabbeton kolom vierkant_gen1:410x410:4845681 | 05 vijfde verdieping | Model Group:NLRS_01.00_verdieping 05_gen:6691052
NLRS_28.11_SCO_TLB_prefabbeton kolom vierkant_gen:410x410:4845710 | 05 vijfde verdieping | Model Group:NLRS_01.00_verdieping 05_gen:6691052
NLRS_28.11_SCO_TLB_prefabbeton kolom vierkant_gen:410x410:4845717 | 05 vijfde verdieping | Model Group:NLRS_01.00_verdieping 05_gen:6691052
NLRS_28.11_SCO_TLB_prefabbeton kolom vierkant_gen:410x410:4845753 | 11 elfde verdieping | Model Group:NLRS_01.00_verdieping 11--17_gen:4845821
NLRS_28.11_SCO_TLB_prefabbeton kolom vierkant_gen1:410x410:4845756 | 11 elfde verdieping | Model Group:NLRS_01.00_verdieping 11--17_gen:4845821
NLRS_28.11_SCO_TLB_prefabbeton kolom vierkant_gen:410x410:4845785 | 11 elfde verdieping | Model Group:NLRS_01.00_verdieping 11--17_gen:4845821
NLRS_28.11_SCO_TLB_prefabbeton kolom vierkant_gen:410x410:4845792 | 11 elfde verdieping | Model Group:NLRS_01.00_verdieping 11--17_gen:4845821
NLRS_28.11_SCO_TLB_prefabbeton kolom vierkant_gen1:410x410:6698036 | 05 vijfde verdieping | Model Group:NLRS_01.00_verdieping 05_gen (members excluded):6698157
NLRS_28.11_SCO_TLB_prefabbeton kolom vierkant_gen1:410x410:6698039 | 05 vijfde verdieping | Model Group:NLRS_01.00_verdieping 05_gen (members excluded):6698157
NLRS_28.11_SCO_TLB_prefabbeton kolom vierkant_gen:410x410:6698068 | 05 vijfde verdieping | Model Group:NLRS_01.00_verdieping 05_gen (members excluded):6698157
NLRS_28.11_SCO_TLB_prefabbeton kolom vierkant_gen:410x410:6698075 | 05 vijfde verdieping | Model Group:NLRS_01.00_verdieping 05_gen (members excluded):6698157
NLRS_28.11_SCO_TLB_prefabbeton kolom vierkant_gen1:410x410:12077394 | 04 vierde verdieping | Model Group:NLRS_01.00_verdieping 04_gen (members excluded):4844403
NLRS_28.11_SCO_TLB_prefabbeton kolom vierkant_gen1:410x410:12078238 | 04 vierde verdieping | Model Group:NLRS_01.00_verdieping 04_gen (members excluded):4585793

# IfcColumn: 500x850 (32)
Type - ElementType: 500x850; PredefinedType: COLUMN; Classification: 28.11 hoofddraagconstructies - kolommen en liggers, kolom-/liggerconstructies (Uniformat); Material: NLRS_f2_beton prefab
Pset_ColumnCommon - LoadBearing: yes; IsExternal: no; Reference: 500x850
Name (NLRS_28.11_SCO_TLB_prefabbeton kolom vierkant_gen:500x850:...) | In
4260731 | 00 begane grond
4260759 | 00 begane grond
4260765 | 00 begane grond
4260789 | 00 begane grond
4263076 | 00 begane grond
4349031 | 01a eerste tussenverdieping
4349053 | 01a eerste tussenverdieping
4349159 | 01c derde tussenverdieping
4349181 | 01c derde tussenverdieping
4349281 | 02b tweede tussenverdieping
4349303 | 02b tweede tussenverdieping
4350184 | 01a eerste tussenverdieping
4350186 | 01a eerste tussenverdieping
4350228 | 01c derde tussenverdieping
4350230 | 01c derde tussenverdieping
4350263 | 02b tweede tussenverdieping
4350265 | 02b tweede tussenverdieping
4350583 | 01a eerste tussenverdieping
4350617 | 01c derde tussenverdieping
4350649 | 02b tweede tussenverdieping
5014922 | 00 begane grond
5014924 | 00 begane grond
5014932 | 00 begane grond
5015010 | 01a eerste tussenverdieping
5015012 | 01a eerste tussenverdieping
5015018 | 01c derde tussenverdieping
5015020 | 01c derde tussenverdieping
5015026 | 02b tweede tussenverdieping
5015028 | 02b tweede tussenverdieping
5015034 | 01a eerste tussenverdieping
5015036 | 01c derde tussenverdieping
5015038 | 02b tweede tussenverdieping

# IfcColumn: 515x410/105x160 (8)
In: 03 derde verdieping
Type - ElementType: 515x410/105x160; PredefinedType: COLUMN; Classification: 28.11 hoofddraagconstructies - kolommen en liggers, kolom-/liggerconstructies (Uniformat); Material: NLRS_f2_beton ihwg
Pset_ColumnCommon - LoadBearing: yes; IsExternal: no; Reference: 515x410/105x160
Name (NLRS_28.11_SCO_TLB_beton kolom ihwg enkele sponning_gen:515x410/105x160:...)
4331876
4331947
4332991
4333063
4333361
4333363
4333383
4333385

# IfcColumn: 620x250 (8)
Type - ElementType: 620x250; PredefinedType: COLUMN; Classification: 28.11 hoofddraagconstructies - kolommen en liggers, kolom-/liggerconstructies (Uniformat); Material: NLRS_f2_beton ihwg
Pset_ColumnCommon - LoadBearing: yes; IsExternal: no; Reference: 620x250
Name (NLRS_28.11_SCO_TLB_beton kolom ihwg_gen:620x250:...) | In
4330786 | 00 begane grond
4330817 | 01 eerste verdieping
4330884 | 02 tweede verdieping
4330947 | 03 derde verdieping
4333315 | 00 begane grond
4333333 | 01 eerste verdieping
4333351 | 02 tweede verdieping
4333359 | 03 derde verdieping

# IfcColumn: 620x410/105x160/105x160 (48)
Type - ElementType: 620x410/105x160/105x160; PredefinedType: COLUMN; Classification: 28.11 hoofddraagconstructies - kolommen en liggers, kolom-/liggerconstructies (Uniformat); Material: NLRS_f2_beton ihwg
Pset_ColumnCommon - LoadBearing: yes; IsExternal: no; Reference: 620x410/105x160/105x160
Name (NLRS_28.11_SCO_TLB_beton kolom ihwg dubbele sponning_gen:620x410/105x160/105x160:...) | In
4325567 | 00 begane grond
4325950 | 00 begane grond
4325963 | 00 begane grond
4325976 | 00 begane grond
4325993 | 00 begane grond
4326023 | 00 begane grond
4326248 | 00 begane grond
4330799 | 01 eerste verdieping
4330801 | 01 eerste verdieping
4330803 | 01 eerste verdieping
4330805 | 01 eerste verdieping
4330807 | 01 eerste verdieping
4330809 | 01 eerste verdieping
4330811 | 01 eerste verdieping
4330866 | 02 tweede verdieping
4330868 | 02 tweede verdieping
4330870 | 02 tweede verdieping
4330872 | 02 tweede verdieping
4330874 | 02 tweede verdieping
4330876 | 02 tweede verdieping
4330878 | 02 tweede verdieping
4332538 | 00 begane grond
4332644 | 01 eerste verdieping
4332795 | 02 tweede verdieping
4333299 | 00 begane grond
4333301 | 00 begane grond
4333303 | 00 begane grond
4333305 | 00 begane grond
4333307 | 00 begane grond
4333309 | 00 begane grond
4333311 | 00 begane grond
4333317 | 01 eerste verdieping
4333319 | 01 eerste verdieping
4333321 | 01 eerste verdieping
4333323 | 01 eerste verdieping
4333325 | 01 eerste verdieping
4333327 | 01 eerste verdieping
4333329 | 01 eerste verdieping
4333335 | 02 tweede verdieping
4333337 | 02 tweede verdieping
4333339 | 02 tweede verdieping
4333341 | 02 tweede verdieping
4333343 | 02 tweede verdieping
4333345 | 02 tweede verdieping
4333347 | 02 tweede verdieping
4333369 | 00 begane grond
4333373 | 01 eerste verdieping
4333377 | 02 tweede verdieping

# IfcColumn: kolom HEA 140 (6)
In: 03 derde verdieping
Type - ElementType: kolom HEA 140; PredefinedType: COLUMN; Classification: 28.11 hoofddraagconstructies - kolommen en liggers, kolom-/liggerconstructies (Uniformat); Material: NLRS_h2_staal
Pset_ColumnCommon - LoadBearing: yes; IsExternal: no; Reference: kolom HEA 140
Name (NLRS_28.11_SCO_TLB_stalen kolom HEA_gen:kolom HEA 140:...) | Group
6842096 | Model Group:NLRS_01.00_low-rise loggia dak staal_gen:6844852
6844911 | Model Group:NLRS_01.00_low-rise loggia dak staal_gen:6844915
6845594
12746882 | Model Group:NLRS_01.00_low-rise loggia dak staal_gen:6844852
12746898 | Model Group:NLRS_01.00_low-rise loggia dak staal_gen:6844915
12746965

# IfcColumn: kolom HEA 200 (27)
Type - ElementType: kolom HEA 200; PredefinedType: COLUMN; Classification: 28.11 hoofddraagconstructies - kolommen en liggers, kolom-/liggerconstructies (Uniformat); Material: NLRS_h2_staal
Pset_ColumnCommon - LoadBearing: yes; IsExternal: no; Reference: kolom HEA 200
Name (NLRS_28.11_SCO_TLB_stalen kolom HEA_gen:kolom HEA 200:...) | In
4426868 | 03 derde verdieping
4426960 | 03 derde verdieping
4526367 | 03 derde verdieping
4528126 | 03 derde verdieping
4528293 | 03 derde verdieping
4528310 | 03 derde verdieping
4528414 | 03 derde verdieping
4528416 | 03 derde verdieping
4528418 | 03 derde verdieping
4528451 | 03 derde verdieping
4528453 | 03 derde verdieping
4528455 | 03 derde verdieping
5637571 | 03 derde verdieping
12743961 | 03 derde verdieping
12743986 | 04 vierde verdieping
12744607 | 04 vierde verdieping
12744609 | 04 vierde verdieping
12744664 | 04 vierde verdieping
12744840 | 04 vierde verdieping
12744941 | 03 derde verdieping
12744943 | 04 vierde verdieping
12748228 | 04 vierde verdieping
12748376 | 04 vierde verdieping
12748551 | 04 vierde verdieping
12748553 | 04 vierde verdieping
12748615 | 04 vierde verdieping
12748617 | 04 vierde verdieping

# IfcColumn: kolom HEA 240 (24)
In: 21 eenentwintigste verdieping
Type - ElementType: kolom HEA 240; PredefinedType: COLUMN; Classification: 28.11 hoofddraagconstructies - kolommen en liggers, kolom-/liggerconstructies (Uniformat); Material: NLRS_h2_staal
Pset_ColumnCommon - LoadBearing: yes; IsExternal: no; Reference: kolom HEA 240
Name (NLRS_28.11_SCO_TLB_stalen kolom HEA_gen:kolom HEA 240:...) | Group
4649142 | Model Group:NLRS_01.00_verdieping 21--23_gen (members excluded):4647240
4649326 | Model Group:NLRS_01.00_verdieping 21--23_gen (members excluded):4647240
4649369 | Model Group:NLRS_01.00_verdieping 21--23_gen (members excluded):4647240
4650081 | Model Group:NLRS_01.00_verdieping 21--23_gen (members excluded):4647240
4650098 | Model Group:NLRS_01.00_verdieping 21--23_gen (members excluded):4647240
4650115 | Model Group:NLRS_01.00_verdieping 21--23_gen (members excluded):4647240
4650134 | Model Group:NLRS_01.00_verdieping 21--23_gen (members excluded):4647240
4650153 | Model Group:NLRS_01.00_verdieping 21--23_gen (members excluded):4647240
4650172 | Model Group:NLRS_01.00_verdieping 21--23_gen (members excluded):4647240
4650482 | Model Group:NLRS_01.00_verdieping 21--23_gen (members excluded):4647240
4650503 | Model Group:NLRS_01.00_verdieping 21--23_gen (members excluded):4647240
4650524 | Model Group:NLRS_01.00_verdieping 21--23_gen (members excluded):4647240
4846703 | Model Group:NLRS_01.00_verdieping 21--23_gen (members excluded):4846692
4846705 | Model Group:NLRS_01.00_verdieping 21--23_gen (members excluded):4846692
4846707 | Model Group:NLRS_01.00_verdieping 21--23_gen (members excluded):4846692
4846737 | Model Group:NLRS_01.00_verdieping 21--23_gen (members excluded):4846692
4846739 | Model Group:NLRS_01.00_verdieping 21--23_gen (members excluded):4846692
4846741 | Model Group:NLRS_01.00_verdieping 21--23_gen (members excluded):4846692
4846743 | Model Group:NLRS_01.00_verdieping 21--23_gen (members excluded):4846692
4846745 | Model Group:NLRS_01.00_verdieping 21--23_gen (members excluded):4846692
4846747 | Model Group:NLRS_01.00_verdieping 21--23_gen (members excluded):4846692
4846765 | Model Group:NLRS_01.00_verdieping 21--23_gen (members excluded):4846692
4846767 | Model Group:NLRS_01.00_verdieping 21--23_gen (members excluded):4846692
4846769 | Model Group:NLRS_01.00_verdieping 21--23_gen (members excluded):4846692

# IfcColumn: kolom HEB 200 (2)
In: 05 vijfde verdieping
Type - ElementType: kolom HEB 200; PredefinedType: COLUMN; Classification: 28.11 hoofddraagconstructies - kolommen en liggers, kolom-/liggerconstructies (Uniformat); Material: NLRS_h2_staal
Pset_ColumnCommon - LoadBearing: yes; IsExternal: no; Reference: kolom HEB 200
Name (NLRS_28.11_SCO_TLB_stalen kolom HEB_gen:kolom HEB 200:...)
5713891
6914932

# IfcColumn: kolom IPE 240 (2)
Type - ElementType: kolom IPE 240; PredefinedType: COLUMN; Classification: 28.11 hoofddraagconstructies - kolommen en liggers, kolom-/liggerconstructies (Uniformat); Material: NLRS_h2_staal
Pset_ColumnCommon - LoadBearing: yes; IsExternal: no; Reference: kolom IPE 240
Name (NLRS_28.11_SCO_TLB_stalen kolom IPE_gen:kolom IPE 240:...) | In
13469220 | 01b tweede tussenverdieping
13470216 | 04 vierde verdieping

# IfcColumn: kolom buisprofiel koudgevormd vierkant RHSC_100x100x10, NLRS_28.11_SCO_TLB_stalen kolom buisprofiel koudgevormd vierkant_gen:kolom buisprofiel koudgevormd vierkant RHSC_100x100x10:4526430
In: 00 begane grond
Type - ElementType: kolom buisprofiel koudgevormd vierkant RHSC_100x100x10; PredefinedType: COLUMN; Classification: 28.11 hoofddraagconstructies - kolommen en liggers, kolom-/liggerconstructies (Uniformat); Material: NLRS_h2_staal
Pset_ColumnCommon - LoadBearing: yes; IsExternal: no; Slope: 0 deg; Reference: kolom buisprofiel koudgevormd vierkant RHSC_100x100x10

# IfcColumn: kolom buisprofiel warmgevormd vierkant SHSH_100x100x8 (7)
Type - ElementType: kolom buisprofiel warmgevormd vierkant SHSH_100x100x8; PredefinedType: COLUMN; Classification: 28.11 hoofddraagconstructies - kolommen en liggers, kolom-/liggerconstructies (Uniformat); Material: NLRS_h2_staal
Pset_ColumnCommon - LoadBearing: yes; IsExternal: no; Reference: kolom buisprofiel warmgevormd vierkant SHSH_100x100x8
Name (NLRS_28.11_SCO_TLB_stalen kolom buisprofiel warmgevormd vierkant_gen:kolom buisprofiel warmgevormd vierkant SHSH_100x100x8:...) | In | Group
12746862 | 04 vierde verdieping | Model Group:NLRS_01.00_low-rise loggia dak staal_gen:6844852 | Pset_ColumnCommon - Slope: 0 deg
12746868 | 03 derde verdieping | Pset_ColumnCommon - Slope: 0 deg
12746894 | 04 vierde verdieping | Model Group:NLRS_01.00_low-rise loggia dak staal_gen:6844915
12746928 | 04 vierde verdieping | Model Group:NLRS_01.00_low-rise loggia dak staal_gen:6844852
12746934 | 04 vierde verdieping | Model Group:NLRS_01.00_low-rise loggia dak staal_gen:6844915
12746963 | 04 vierde verdieping
12746967 | 04 vierde verdieping

# IfcColumn: kolom buisprofiel warmgevormd vierkant SHSH_250x100x10 (4)
In: 01 eerste verdieping
Type - ElementType: kolom buisprofiel warmgevormd vierkant SHSH_250x100x10; PredefinedType: COLUMN; Classification: 28.11 hoofddraagconstructies - kolommen en liggers, kolom-/liggerconstructies (Uniformat); Material: NLRS_h2_staal
Pset_ColumnCommon - LoadBearing: yes; IsExternal: no; Reference: kolom buisprofiel warmgevormd vierkant SHSH_250x100x10
Name (NLRS_28.11_SCO_TLB_stalen kolom buisprofiel warmgevormd vierkant_gen:kolom buisprofiel warmgevormd vierkant SHSH_250x100x10:...) | Group
4401572 | Model Group:luifel:12735764 | Pset_ColumnCommon - Slope: 0 deg
4401719 | Model Group:luifel:12735764
12735792 | Model Group:luifel:12735808
12735794 | Model Group:luifel:12735808

# IfcColumn: ø400 (265)
Type - ElementType: ø400; PredefinedType: COLUMN; Classification: 28.11 hoofddraagconstructies - kolommen en liggers, kolom-/liggerconstructies (Uniformat); Material: NLRS_f2_beton prefab
Pset_ColumnCommon - LoadBearing: yes; IsExternal: no; Reference: ø400
Name (NLRS_28.11_SCO_TLB_prefabbeton kolom rond_gen:ø400:...) | In
4111216 | 00 begane grond
4111274 | 00 begane grond
4111291 | 00 begane grond
4111308 | 00 begane grond
4111325 | 00 begane grond
4111372 | 00 begane grond
4111399 | 00 begane grond
4111403 | 00 begane grond
4111407 | 00 begane grond
4111411 | 00 begane grond
4111415 | 00 begane grond
4111419 | 00 begane grond
4111423 | 00 begane grond
4260800 | 00 begane grond
4260806 | 00 begane grond
4262838 | 00 begane grond
4262896 | 00 begane grond
4262911 | 00 begane grond
4263401 | 00 begane grond
4263416 | 00 begane grond
4263431 | 00 begane grond
4263446 | 00 begane grond
4263461 | 00 begane grond
4263508 | 00 begane grond
4263546 | 00 begane grond
4263548 | 00 begane grond
4263550 | 00 begane grond
4263552 | 00 begane grond
4263554 | 00 begane grond
4263556 | 00 begane grond
4263558 | 00 begane grond
4263560 | 00 begane grond
4268940 | 00 begane grond
4269008 | 00 begane grond
4269023 | 00 begane grond
4269036 | 00 begane grond
4269085 | 00 begane grond
4269686 | 00 begane grond
4269699 | 00 begane grond
4269714 | 00 begane grond
4270122 | 00 begane grond
4270139 | 00 begane grond
4270156 | 00 begane grond
4346029 | 00a eerste tussenverdieping
4346031 | 00a eerste tussenverdieping
4346033 | 00a eerste tussenverdieping
4346035 | 00a eerste tussenverdieping
4346037 | 00a eerste tussenverdieping
4346039 | 00a eerste tussenverdieping
4346041 | 00a eerste tussenverdieping
4346043 | 00a eerste tussenverdieping
4346045 | 00a eerste tussenverdieping
4346047 | 00a eerste tussenverdieping
4346049 | 00a eerste tussenverdieping
4346051 | 00a eerste tussenverdieping
4346053 | 00a eerste tussenverdieping
4346055 | 00a eerste tussenverdieping
4346057 | 00a eerste tussenverdieping
4346208 | 01b tweede tussenverdieping
4346210 | 01b tweede tussenverdieping
4346212 | 01b tweede tussenverdieping
4346214 | 01b tweede tussenverdieping
4346216 | 01b tweede tussenverdieping
4346218 | 01b tweede tussenverdieping
4346220 | 01b tweede tussenverdieping
4346222 | 01b tweede tussenverdieping
4346224 | 01b tweede tussenverdieping
4346226 | 01b tweede tussenverdieping
4346228 | 01b tweede tussenverdieping
4346230 | 01b tweede tussenverdieping
4346232 | 01b tweede tussenverdieping
4346234 | 01b tweede tussenverdieping
4346236 | 01b tweede tussenverdieping
4347202 | 00a eerste tussenverdieping
4347204 | 00a eerste tussenverdieping
4347206 | 00a eerste tussenverdieping
4347208 | 00a eerste tussenverdieping
4347210 | 00a eerste tussenverdieping
4347214 | 00a eerste tussenverdieping
4347218 | 00a eerste tussenverdieping
4347220 | 00a eerste tussenverdieping
4347222 | 00a eerste tussenverdieping
4347224 | 00a eerste tussenverdieping
4347226 | 00a eerste tussenverdieping
4347232 | 00a eerste tussenverdieping
4347457 | 01b tweede tussenverdieping
4347459 | 01b tweede tussenverdieping
4347461 | 01b tweede tussenverdieping
4347463 | 01b tweede tussenverdieping
4347465 | 01b tweede tussenverdieping
4347469 | 01b tweede tussenverdieping
4347473 | 01b tweede tussenverdieping
4347475 | 01b tweede tussenverdieping
4347477 | 01b tweede tussenverdieping
4347479 | 01b tweede tussenverdieping
4347481 | 01b tweede tussenverdieping
4347487 | 01b tweede tussenverdieping
4347862 | 02a eerste tussenverdieping
4347864 | 02a eerste tussenverdieping
4347866 | 02a eerste tussenverdieping
4347868 | 02a eerste tussenverdieping
4347870 | 02a eerste tussenverdieping
4347874 | 02a eerste tussenverdieping
4347878 | 02a eerste tussenverdieping
4347880 | 02a eerste tussenverdieping
4347882 | 02a eerste tussenverdieping
4347884 | 02a eerste tussenverdieping
4347886 | 02a eerste tussenverdieping
4347892 | 02a eerste tussenverdieping
4347980 | 01c derde tussenverdieping
4347982 | 01c derde tussenverdieping
4347984 | 01c derde tussenverdieping
4347986 | 01c derde tussenverdieping
4347988 | 01c derde tussenverdieping
4347992 | 01c derde tussenverdieping
4347996 | 01c derde tussenverdieping
4347998 | 01c derde tussenverdieping
4348000 | 01c derde tussenverdieping
4348002 | 01c derde tussenverdieping
4348004 | 01c derde tussenverdieping
4348010 | 01c derde tussenverdieping
4348097 | 01a eerste tussenverdieping
4348099 | 01a eerste tussenverdieping
4348101 | 01a eerste tussenverdieping
4348103 | 01a eerste tussenverdieping
4348105 | 01a eerste tussenverdieping
4348109 | 01a eerste tussenverdieping
4348113 | 01a eerste tussenverdieping
4348115 | 01a eerste tussenverdieping
4348117 | 01a eerste tussenverdieping
4348119 | 01a eerste tussenverdieping
4348121 | 01a eerste tussenverdieping
4348127 | 01a eerste tussenverdieping
4348211 | 02b tweede tussenverdieping
4348213 | 02b tweede tussenverdieping
4348215 | 02b tweede tussenverdieping
4348217 | 02b tweede tussenverdieping
4348219 | 02b tweede tussenverdieping
4348227 | 02b tweede tussenverdieping
4348229 | 02b tweede tussenverdieping
4348231 | 02b tweede tussenverdieping
4348233 | 02b tweede tussenverdieping
4348235 | 02b tweede tussenverdieping
4348408 | 02a eerste tussenverdieping
4348410 | 02a eerste tussenverdieping
4348412 | 02a eerste tussenverdieping
4348414 | 02a eerste tussenverdieping
4348416 | 02a eerste tussenverdieping
4348418 | 02a eerste tussenverdieping
4348420 | 02a eerste tussenverdieping
4348422 | 02a eerste tussenverdieping
4348424 | 02a eerste tussenverdieping
4348426 | 02a eerste tussenverdieping
4348428 | 02a eerste tussenverdieping
4348430 | 02a eerste tussenverdieping
4348432 | 02a eerste tussenverdieping
4348434 | 02a eerste tussenverdieping
4348436 | 02a eerste tussenverdieping
4348543 | 02a eerste tussenverdieping
4348568 | 02a eerste tussenverdieping
4348600 | 01b tweede tussenverdieping
4348623 | 01b tweede tussenverdieping
4348684 | 02a eerste tussenverdieping
4348686 | 01c derde tussenverdieping
4348690 | 02b tweede tussenverdieping
4348736 | 01b tweede tussenverdieping
4348738 | 02a eerste tussenverdieping
4348740 | 01c derde tussenverdieping
4348742 | 02b tweede tussenverdieping
4349039 | 01a eerste tussenverdieping
4349041 | 01a eerste tussenverdieping
4349043 | 01a eerste tussenverdieping
4349045 | 01a eerste tussenverdieping
4349047 | 01a eerste tussenverdieping
4349167 | 01c derde tussenverdieping
4349169 | 01c derde tussenverdieping
4349171 | 01c derde tussenverdieping
4349173 | 01c derde tussenverdieping
4349175 | 01c derde tussenverdieping
4349289 | 02b tweede tussenverdieping
4349291 | 02b tweede tussenverdieping
4349293 | 02b tweede tussenverdieping
4349295 | 02b tweede tussenverdieping
4349297 | 02b tweede tussenverdieping
4349546 | 01a eerste tussenverdieping
4349548 | 01c derde tussenverdieping
4349550 | 02b tweede tussenverdieping
4349576 | 01a eerste tussenverdieping
4349578 | 01c derde tussenverdieping
4349580 | 02b tweede tussenverdieping
4349900 | 01c derde tussenverdieping
4349941 | 01a eerste tussenverdieping
4349981 | 02b tweede tussenverdieping
4370852 | 02a eerste tussenverdieping
4370887 | 02a eerste tussenverdieping
4370947 | 02a eerste tussenverdieping
4370959 | 02a eerste tussenverdieping
4370973 | 02a eerste tussenverdieping
4370987 | 02a eerste tussenverdieping
4370999 | 02a eerste tussenverdieping
4371075 | 02a eerste tussenverdieping
4371089 | 02a eerste tussenverdieping
4371103 | 02a eerste tussenverdieping
4371117 | 02a eerste tussenverdieping
4371131 | 02a eerste tussenverdieping
4371173 | 02a eerste tussenverdieping
4371187 | 02a eerste tussenverdieping
4371229 | 02a eerste tussenverdieping
4371243 | 02a eerste tussenverdieping
4371259 | 02a eerste tussenverdieping
4371375 | 01b tweede tussenverdieping
4371381 | 01b tweede tussenverdieping
4371383 | 01b tweede tussenverdieping
4371385 | 01b tweede tussenverdieping
4371387 | 01b tweede tussenverdieping
4371389 | 01b tweede tussenverdieping
4371393 | 01b tweede tussenverdieping
4371395 | 01b tweede tussenverdieping
4371397 | 01b tweede tussenverdieping
4371399 | 01b tweede tussenverdieping
4371401 | 01b tweede tussenverdieping
4371407 | 01b tweede tussenverdieping
4371409 | 01b tweede tussenverdieping
4371411 | 01b tweede tussenverdieping
4371413 | 01b tweede tussenverdieping
4371415 | 01b tweede tussenverdieping
4371537 | 00a eerste tussenverdieping
4371543 | 00a eerste tussenverdieping
4371545 | 00a eerste tussenverdieping
4371547 | 00a eerste tussenverdieping
4371549 | 00a eerste tussenverdieping
4371551 | 00a eerste tussenverdieping
4371555 | 00a eerste tussenverdieping
4371557 | 00a eerste tussenverdieping
4371559 | 00a eerste tussenverdieping
4371561 | 00a eerste tussenverdieping
4371563 | 00a eerste tussenverdieping
4371569 | 00a eerste tussenverdieping
4371575 | 00a eerste tussenverdieping
4371577 | 00a eerste tussenverdieping
4371679 | 00 begane grond
4371681 | 00 begane grond
4371683 | 00 begane grond
4513723 | 01b tweede tussenverdieping
4513725 | 00a eerste tussenverdieping
5224479 | 01b tweede tussenverdieping
5707225 | 00 begane grond
5707227 | 00 begane grond
5707965 | 00 begane grond
5707971 | 00 begane grond
5708625 | 00 begane grond
5708627 | 00 begane grond
5708629 | 00 begane grond
5708631 | 00 begane grond
5708633 | 00 begane grond
5708635 | 00 begane grond
5712953 | 00a eerste tussenverdieping
5712955 | 00a eerste tussenverdieping
5712957 | 00a eerste tussenverdieping
5712959 | 00a eerste tussenverdieping
5713141 | 00a eerste tussenverdieping
5923048 | 01c derde tussenverdieping
5923062 | 01b tweede tussenverdieping
5923101 | 02a eerste tussenverdieping
5923112 | 02b tweede tussenverdieping

# IfcColumn: ø500 (2)
In: 00 begane grond
Type - ElementType: ø500; PredefinedType: COLUMN; Classification: 28.11 hoofddraagconstructies - kolommen en liggers, kolom-/liggerconstructies (Uniformat); Material: NLRS_f2_beton ihwg
Pset_ColumnCommon - LoadBearing: yes; IsExternal: no; Reference: ø500
Name (NLRS_28.11_SCO_TLB_beton kolom ihwg rond_gen:ø500:...)
5709442
5709444

# IfcColumn: ø650 (16)
Type - ElementType: ø650; PredefinedType: COLUMN; Classification: 28.11 hoofddraagconstructies - kolommen en liggers, kolom-/liggerconstructies (Uniformat); Material: NLRS_f2_beton prefab
Pset_ColumnCommon - LoadBearing: yes; IsExternal: no; Reference: ø650
Name (NLRS_28.11_SCO_TLB_prefabbeton kolom rond_gen:ø650:...) | In
4260818 | 00 begane grond
4260824 | 00 begane grond
4512616 | 01a eerste tussenverdieping
4512706 | 01c derde tussenverdieping
4512726 | 02b tweede tussenverdieping
4512892 | 01a eerste tussenverdieping
4512894 | 01c derde tussenverdieping
4512896 | 02b tweede tussenverdieping
4513494 | 01a eerste tussenverdieping
4513496 | 01c derde tussenverdieping
4513498 | 02b tweede tussenverdieping
4513500 | 01a eerste tussenverdieping
4513502 | 01c derde tussenverdieping
4513504 | 02b tweede tussenverdieping
5014934 | 00 begane grond
5014936 | 00 begane grond

# IfcFooting: NLRS_16.12_SF_WPB_funderingsbalk ihwg enkele sponning_gen:500x700/125x90 (5)
In: 00 begane grond
PredefinedType: FOOTING_BEAM; Classification: 16.12 funderingsconstructies - voeten en balken, fundatie balken (Uniformat); Material: NLRS_f2_beton ihwg
Name (NLRS_16.12_SF_WPB_funderingsbalk ihwg enkele sponning_gen:500x700/125x90:...)
4116787
5301152
5846172
5846183
5857483

# IfcFooting: NLRS_16.12_SF_WPB_funderingsbalk ihwg enkele sponning_gen:850x700/125x90, NLRS_16.12_SF_WPB_funderingsbalk ihwg enkele sponning_gen:850x700/125x90:5301129
In: 00 begane grond
PredefinedType: FOOTING_BEAM; Classification: 16.12 funderingsconstructies - voeten en balken, fundatie balken (Uniformat); Material: NLRS_f2_beton ihwg

# IfcFooting: NLRS_16.12_SF_WPB_funderingsbalk ihwg recht_gen:1000x1200 (3)
In: 00 begane grond
PredefinedType: FOOTING_BEAM; Classification: 16.12 funderingsconstructies - voeten en balken, fundatie balken (Uniformat); Material: NLRS_f2_beton ihwg
Name (NLRS_16.12_SF_WPB_funderingsbalk ihwg recht_gen:1000x1200:...)
5193062
5200732
13061932

# IfcFooting: NLRS_16.12_SF_WPB_funderingsbalk ihwg recht_gen:1000x1300 (2)
In: 00 begane grond
PredefinedType: FOOTING_BEAM; Classification: 16.12 funderingsconstructies - voeten en balken, fundatie balken (Uniformat); Material: NLRS_f2_beton ihwg
Name (NLRS_16.12_SF_WPB_funderingsbalk ihwg recht_gen:1000x1300:...)
5193136
5195674

# IfcFooting: NLRS_16.12_SF_WPB_funderingsbalk ihwg recht_gen:1000x1800, NLRS_16.12_SF_WPB_funderingsbalk ihwg recht_gen:1000x1800:5985573
In: 00 begane grond
PredefinedType: FOOTING_BEAM; Classification: 16.12 funderingsconstructies - voeten en balken, fundatie balken (Uniformat); Material: NLRS_f2_beton ihwg

# IfcFooting: NLRS_16.12_SF_WPB_funderingsbalk ihwg recht_gen:1260x1200, NLRS_16.12_SF_WPB_funderingsbalk ihwg recht_gen:1260x1200:5213145
In: 00 begane grond
PredefinedType: FOOTING_BEAM; Classification: 16.12 funderingsconstructies - voeten en balken, fundatie balken (Uniformat); Material: NLRS_f2_beton ihwg

# IfcFooting: NLRS_16.12_SF_WPB_funderingsbalk ihwg recht_gen:1350x1200, NLRS_16.12_SF_WPB_funderingsbalk ihwg recht_gen:1350x1200:13062500
In: 00 begane grond
PredefinedType: FOOTING_BEAM; Classification: 16.12 funderingsconstructies - voeten en balken, fundatie balken (Uniformat); Material: NLRS_f2_beton ihwg

# IfcFooting: NLRS_16.12_SF_WPB_funderingsbalk ihwg recht_gen:200x200 (6)
In: 00 begane grond
PredefinedType: FOOTING_BEAM; Classification: 16.12 funderingsconstructies - voeten en balken, fundatie balken (Uniformat); Material: NLRS_f2_beton ihwg
Name (NLRS_16.12_SF_WPB_funderingsbalk ihwg recht_gen:200x200:...)
5989763
5991578
10729533
10729544
10729551
10729557

# IfcFooting: NLRS_16.12_SF_WPB_funderingsbalk ihwg recht_gen:200x250 (3)
In: 00 begane grond
PredefinedType: FOOTING_BEAM; Classification: 16.12 funderingsconstructies - voeten en balken, fundatie balken (Uniformat); Material: NLRS_f2_beton ihwg
Name (NLRS_16.12_SF_WPB_funderingsbalk ihwg recht_gen:200x250:...)
11809089
11816197
11819065

# IfcFooting: NLRS_16.12_SF_WPB_funderingsbalk ihwg recht_gen:250x600, NLRS_16.12_SF_WPB_funderingsbalk ihwg recht_gen:250x600:5996238
In: 00 begane grond
PredefinedType: FOOTING_BEAM; Classification: 16.12 funderingsconstructies - voeten en balken, fundatie balken (Uniformat); Material: NLRS_f2_beton ihwg

# IfcFooting: NLRS_16.12_SF_WPB_funderingsbalk ihwg recht_gen:2700x1300 (5)
In: 00 begane grond
PredefinedType: FOOTING_BEAM; Classification: 16.12 funderingsconstructies - voeten en balken, fundatie balken (Uniformat); Material: NLRS_f2_beton ihwg
Name (NLRS_16.12_SF_WPB_funderingsbalk ihwg recht_gen:2700x1300:...)
4195453
4195489
5014821
5014857
7730355

# IfcFooting: NLRS_16.12_SF_WPB_funderingsbalk ihwg recht_gen:350x1000, NLRS_16.12_SF_WPB_funderingsbalk ihwg recht_gen:350x1000:13058161
In: 00 begane grond
PredefinedType: FOOTING_BEAM; Classification: 16.12 funderingsconstructies - voeten en balken, fundatie balken (Uniformat); Material: NLRS_f2_beton ihwg

# IfcFooting: NLRS_16.12_SF_WPB_funderingsbalk ihwg recht_gen:350x700, NLRS_16.12_SF_WPB_funderingsbalk ihwg recht_gen:350x700:13054715
In: 00 begane grond
PredefinedType: FOOTING_BEAM; Classification: 16.12 funderingsconstructies - voeten en balken, fundatie balken (Uniformat); Material: NLRS_f2_beton ihwg

# IfcFooting: NLRS_16.12_SF_WPB_funderingsbalk ihwg recht_gen:400x600 (2)
In: 00 begane grond
PredefinedType: FOOTING_BEAM; Classification: 16.12 funderingsconstructies - voeten en balken, fundatie balken (Uniformat); Material: NLRS_f2_beton ihwg
Name (NLRS_16.12_SF_WPB_funderingsbalk ihwg recht_gen:400x600:...)
13054161
13060282

# IfcFooting: NLRS_16.12_SF_WPB_funderingsbalk ihwg recht_gen:500x1000 (2)
In: 00 begane grond
PredefinedType: FOOTING_BEAM; Classification: 16.12 funderingsconstructies - voeten en balken, fundatie balken (Uniformat); Material: NLRS_f2_beton ihwg
Name (NLRS_16.12_SF_WPB_funderingsbalk ihwg recht_gen:500x1000:...)
5995429
5995735

# IfcFooting: NLRS_16.12_SF_WPB_funderingsbalk ihwg recht_gen:500x1200 (7)
In: 00 begane grond
PredefinedType: FOOTING_BEAM; Classification: 16.12 funderingsconstructies - voeten en balken, fundatie balken (Uniformat); Material: NLRS_f2_beton ihwg
Name (NLRS_16.12_SF_WPB_funderingsbalk ihwg recht_gen:500x1200:...)
5136535
5136541
5136547
5136553
5237996
5990661
5992284

# IfcFooting: NLRS_16.12_SF_WPB_funderingsbalk ihwg recht_gen:500x1250, NLRS_16.12_SF_WPB_funderingsbalk ihwg recht_gen:500x1250:6119427
In: 00 begane grond
PredefinedType: FOOTING_BEAM; Classification: 16.12 funderingsconstructies - voeten en balken, fundatie balken (Uniformat); Material: NLRS_f2_beton ihwg

# IfcFooting: NLRS_16.12_SF_WPB_funderingsbalk ihwg recht_gen:500x550, NLRS_16.12_SF_WPB_funderingsbalk ihwg recht_gen:500x550:13060575
In: 00 begane grond
PredefinedType: FOOTING_BEAM; Classification: 16.12 funderingsconstructies - voeten en balken, fundatie balken (Uniformat); Material: NLRS_f2_beton ihwg

# IfcFooting: NLRS_16.12_SF_WPB_funderingsbalk ihwg recht_gen:500x600 (108)
In: 00 begane grond
PredefinedType: FOOTING_BEAM; Classification: 16.12 funderingsconstructies - voeten en balken, fundatie balken (Uniformat); Material: NLRS_f2_beton ihwg
Name (NLRS_16.12_SF_WPB_funderingsbalk ihwg recht_gen:500x600:...)
4116683
4116689
4116696
4116698
4116708
4116714
4116720
4116726
4116732
4116738
4116744
4116750
4116756
4116762
4116768
4116774
4116781
4116832
4116859
4116865
4117104
4117248
4117410
4117618
4117644
4118572
4119921
4120007
4150359
4153707
4153811
4153849
4153939
4155468
4155876
4159264
4194445
4195433
4195435
4197026
4197127
4197191
4197320
4197393
4197420
4197539
5014803
5143186
5195685
5206024
5218667
5224543
5237603
5288704
5297320
5300702
5302264
5708919
5708958
5756421
5846395
5846484
5846548
5846606
5846799
5846839
5861128
5861556
5923951
5923955
5944160
5946697
5946754
5946758
5947509
5947942
5948049
5987802
6022948
6379410
6379420
10112047
13050315
13051584
13052216
13052844
13053448
13055574
13056009
13056026
13056406
13056473
13056589
13056750
13056817
13057183
13057196
13057260
13057334
13057347
13057394
13057407
13057930
13058549
13058832
13058921
13060169
13060185

# IfcFooting: NLRS_16.12_SF_WPB_funderingsbalk ihwg recht_gen:500x610 (3)
In: 00 begane grond
PredefinedType: FOOTING_BEAM; Classification: 16.12 funderingsconstructies - voeten en balken, fundatie balken (Uniformat); Material: NLRS_f2_beton ihwg
Name (NLRS_16.12_SF_WPB_funderingsbalk ihwg recht_gen:500x610:...)
4155642
4155710
4159114

# IfcFooting: NLRS_16.12_SF_WPB_funderingsbalk ihwg recht_gen:500x658, NLRS_16.12_SF_WPB_funderingsbalk ihwg recht_gen:500x658:8505457
In: 00 begane grond
PredefinedType: FOOTING_BEAM; Classification: 16.12 funderingsconstructies - voeten en balken, fundatie balken (Uniformat); Material: NLRS_f2_beton ihwg

# IfcFooting: NLRS_16.12_SF_WPB_funderingsbalk ihwg recht_gen:500x708 (2)
In: 00 begane grond
PredefinedType: FOOTING_BEAM; Classification: 16.12 funderingsconstructies - voeten en balken, fundatie balken (Uniformat); Material: NLRS_f2_beton ihwg
Name (NLRS_16.12_SF_WPB_funderingsbalk ihwg recht_gen:500x708:...)
9911551
9911826

# IfcFooting: NLRS_16.12_SF_WPB_funderingsbalk ihwg recht_gen:500x798, NLRS_16.12_SF_WPB_funderingsbalk ihwg recht_gen:500x798:9911328
In: 00 begane grond
PredefinedType: FOOTING_BEAM; Classification: 16.12 funderingsconstructies - voeten en balken, fundatie balken (Uniformat); Material: NLRS_f2_beton ihwg

# IfcFooting: NLRS_16.12_SF_WPB_funderingsbalk ihwg recht_gen:500x900, NLRS_16.12_SF_WPB_funderingsbalk ihwg recht_gen:500x900:11808504
In: 00 begane grond
PredefinedType: FOOTING_BEAM; Classification: 16.12 funderingsconstructies - voeten en balken, fundatie balken (Uniformat); Material: NLRS_f2_beton ihwg

# IfcFooting: NLRS_16.12_SF_WPB_funderingsbalk ihwg recht_gen:500x950, NLRS_16.12_SF_WPB_funderingsbalk ihwg recht_gen:500x950:13059339
In: 00 begane grond
PredefinedType: FOOTING_BEAM; Classification: 16.12 funderingsconstructies - voeten en balken, fundatie balken (Uniformat); Material: NLRS_f2_beton ihwg

# IfcFooting: NLRS_16.12_SF_WPB_funderingsbalk ihwg recht_gen:600x1000 (4)
In: 00 begane grond
PredefinedType: FOOTING_BEAM; Classification: 16.12 funderingsconstructies - voeten en balken, fundatie balken (Uniformat); Material: NLRS_f2_beton ihwg
Name (NLRS_16.12_SF_WPB_funderingsbalk ihwg recht_gen:600x1000:...)
8521329
8521485
8556289
8556291

# IfcFooting: NLRS_16.12_SF_WPB_funderingsbalk ihwg recht_gen:600x1200 (18)
In: 00 begane grond
PredefinedType: FOOTING_BEAM; Classification: 16.12 funderingsconstructies - voeten en balken, fundatie balken (Uniformat); Material: NLRS_f2_beton ihwg
Name (NLRS_16.12_SF_WPB_funderingsbalk ihwg recht_gen:600x1200:...)
5210960
5211198
5211878
5216930
5216943
5216956
5216970
5217012
5217022
5217044
5217054
5217065
5217076
5217085
5217095
5217106
5951280
13061578

# IfcFooting: NLRS_16.12_SF_WPB_funderingsbalk ihwg recht_gen:600x1250, NLRS_16.12_SF_WPB_funderingsbalk ihwg recht_gen:600x1250:6007440
In: 00 begane grond
PredefinedType: FOOTING_BEAM; Classification: 16.12 funderingsconstructies - voeten en balken, fundatie balken (Uniformat); Material: NLRS_f2_beton ihwg

# IfcFooting: NLRS_16.12_SF_WPB_funderingsbalk ihwg recht_gen:600x600 (18)
In: 00 begane grond
PredefinedType: FOOTING_BEAM; Classification: 16.12 funderingsconstructies - voeten en balken, fundatie balken (Uniformat); Material: NLRS_f2_beton ihwg
Name (NLRS_16.12_SF_WPB_funderingsbalk ihwg recht_gen:600x600:...)
5707977
5707979
5707981
5951565
5951721
5951956
5952004
5952051
6205608
6206022
6206091
13055190
13055364
13055406
13055537
13059516
13059529
13059996

# IfcFooting: NLRS_16.12_SF_WPB_funderingsbalk ihwg recht_gen:600x700 (2)
In: 00 begane grond
PredefinedType: FOOTING_BEAM; Classification: 16.12 funderingsconstructies - voeten en balken, fundatie balken (Uniformat); Material: NLRS_f2_beton ihwg
Name (NLRS_16.12_SF_WPB_funderingsbalk ihwg recht_gen:600x700:...)
13059753
13059767

# IfcFooting: NLRS_16.12_SF_WPB_funderingsbalk ihwg recht_gen:650x1200, NLRS_16.12_SF_WPB_funderingsbalk ihwg recht_gen:650x1200:7786130
In: 00 begane grond
PredefinedType: FOOTING_BEAM; Classification: 16.12 funderingsconstructies - voeten en balken, fundatie balken (Uniformat); Material: NLRS_f2_beton ihwg

# IfcFooting: NLRS_16.12_SF_WPB_funderingsbalk ihwg recht_gen:700x600 (4)
In: 00 begane grond
PredefinedType: FOOTING_BEAM; Classification: 16.12 funderingsconstructies - voeten en balken, fundatie balken (Uniformat); Material: NLRS_f2_beton ihwg
Name (NLRS_16.12_SF_WPB_funderingsbalk ihwg recht_gen:700x600:...)
4156001
4158942
5206580
9466920

# IfcFooting: NLRS_16.12_SF_WPB_funderingsbalk ihwg recht_gen:800x1000 (15)
In: 00 begane grond
PredefinedType: FOOTING_BEAM; Classification: 16.12 funderingsconstructies - voeten en balken, fundatie balken (Uniformat); Material: NLRS_f2_beton ihwg
Name (NLRS_16.12_SF_WPB_funderingsbalk ihwg recht_gen:800x1000:...)
4195429
4195437
4195443
4195445
4195447
4195455
4195515
5014797
5014805
5014813
5014815
5014823
5014865
6063119
9906641

# IfcFooting: NLRS_16.12_SF_WPB_funderingsbalk ihwg recht_gen:800x1200 (7)
In: 00 begane grond
PredefinedType: FOOTING_BEAM; Classification: 16.12 funderingsconstructies - voeten en balken, fundatie balken (Uniformat); Material: NLRS_f2_beton ihwg
Name (NLRS_16.12_SF_WPB_funderingsbalk ihwg recht_gen:800x1200:...)
4117218
4117233
4150118
4150279
5136529
5138315
5160379

# IfcFooting: NLRS_16.12_SF_WPB_funderingsbalk ihwg recht_gen:850x600, NLRS_16.12_SF_WPB_funderingsbalk ihwg recht_gen:850x600:13063054
In: 00 begane grond
PredefinedType: FOOTING_BEAM; Classification: 16.12 funderingsconstructies - voeten en balken, fundatie balken (Uniformat); Material: NLRS_f2_beton ihwg

# IfcFooting: NLRS_16.12_SF_WPB_funderingsbalk ihwg recht_gen:930x1200, NLRS_16.12_SF_WPB_funderingsbalk ihwg recht_gen:930x1200:5217037
In: 00 begane grond
PredefinedType: FOOTING_BEAM; Classification: 16.12 funderingsconstructies - voeten en balken, fundatie balken (Uniformat); Material: NLRS_f2_beton ihwg

# IfcFooting: NLRS_16.12_SF_WPB_opstort ihwg recht_gen:125x90 (3)
In: 00 begane grond
PredefinedType: FOOTING_BEAM; Classification: 16.12 funderingsconstructies - voeten en balken, fundatie balken (Uniformat); Material: NLRS_f2_beton ihwg
Name (NLRS_16.12_SF_WPB_opstort ihwg recht_gen:125x90:...)
7215924
7311607
7311770

# IfcFooting: NLRS_16.12_SF_WPB_opstort ihwg recht_gen:175x332, NLRS_16.12_SF_WPB_opstort ihwg recht_gen:175x332:6379571
In: 00 begane grond
PredefinedType: FOOTING_BEAM; Classification: 16.12 funderingsconstructies - voeten en balken, fundatie balken (Uniformat); Material: NLRS_f2_beton ihwg

# IfcFooting: NLRS_16.12_SF_WPB_opstort ihwg recht_gen:190x90, NLRS_16.12_SF_WPB_opstort ihwg recht_gen:190x90:7311841
In: 00 begane grond
PredefinedType: FOOTING_BEAM; Classification: 16.12 funderingsconstructies - voeten en balken, fundatie balken (Uniformat); Material: NLRS_f2_beton ihwg

# IfcFooting: NLRS_16.12_SF_WPB_opstort ihwg recht_gen:200x332 (2)
In: 00 begane grond
PredefinedType: FOOTING_BEAM; Classification: 16.12 funderingsconstructies - voeten en balken, fundatie balken (Uniformat); Material: NLRS_f2_beton ihwg
Name (NLRS_16.12_SF_WPB_opstort ihwg recht_gen:200x332:...)
4175069
4175141

# IfcFooting: NLRS_16.12_SF_WPB_opstort ihwg recht_gen:200x390, NLRS_16.12_SF_WPB_opstort ihwg recht_gen:200x390:4195033
In: 00 begane grond
PredefinedType: FOOTING_BEAM; Classification: 16.12 funderingsconstructies - voeten en balken, fundatie balken (Uniformat); Material: NLRS_f2_beton ihwg

# IfcFooting: NLRS_16.12_SF_WPB_opstort ihwg recht_gen:225x132, NLRS_16.12_SF_WPB_opstort ihwg recht_gen:225x132:7315391
In: 00 begane grond
PredefinedType: FOOTING_BEAM; Classification: 16.12 funderingsconstructies - voeten en balken, fundatie balken (Uniformat); Material: NLRS_f2_beton ihwg

# IfcFooting: NLRS_16.12_SF_WPB_opstort ihwg recht_gen:250x242 (3)
In: 00 begane grond
PredefinedType: FOOTING_BEAM; Classification: 16.12 funderingsconstructies - voeten en balken, fundatie balken (Uniformat); Material: NLRS_f2_beton ihwg
Name (NLRS_16.12_SF_WPB_opstort ihwg recht_gen:250x242:...)
4175103
4175135
7065630

# IfcFooting: NLRS_16.12_SF_WPB_opstort ihwg recht_gen:250x292 (3)
In: 00 begane grond
PredefinedType: FOOTING_BEAM; Classification: 16.12 funderingsconstructies - voeten en balken, fundatie balken (Uniformat); Material: NLRS_f2_beton ihwg
Name (NLRS_16.12_SF_WPB_opstort ihwg recht_gen:250x292:...)
5993856
5994008
6570763

# IfcFooting: NLRS_16.12_SF_WPB_opstort ihwg recht_gen:250x332 (61)
In: 00 begane grond
PredefinedType: FOOTING_BEAM; Classification: 16.12 funderingsconstructies - voeten en balken, fundatie balken (Uniformat); Material: NLRS_f2_beton ihwg
Name (NLRS_16.12_SF_WPB_opstort ihwg recht_gen:250x332:...)
4175067
4175071
4175073
4175075
4175077
4175079
4175081
4175083
4175085
4175087
4175089
4175091
4175093
4175095
4175097
4175099
4175101
4175105
4175111
4175119
4175121
4175159
4175167
4175169
4175173
4175183
4190788
4195461
4195463
4195465
4195467
4195469
4195471
4195499
4195501
4197636
4197640
4197642
4227493
5014829
5014831
5014833
5014835
5014837
5014839
5014843
5014861
5014863
5833244
5842829
5845207
5856550
5861117
5862358
5862675
5862729
5944482
5960030
5967067
6122770
7314654

# IfcFooting: NLRS_16.12_SF_WPB_opstort ihwg recht_gen:250x390 (10)
In: 00 begane grond
PredefinedType: FOOTING_BEAM; Classification: 16.12 funderingsconstructies - voeten en balken, fundatie balken (Uniformat); Material: NLRS_f2_beton ihwg
Name (NLRS_16.12_SF_WPB_opstort ihwg recht_gen:250x390:...)
4175125
4175129
4175133
4175153
4175155
4175165
4195517
4195519
5014869
5288706

# IfcFooting: NLRS_16.12_SF_WPB_opstort ihwg recht_gen:250x422 (4)
In: 00 begane grond
PredefinedType: FOOTING_BEAM; Classification: 16.12 funderingsconstructies - voeten en balken, fundatie balken (Uniformat); Material: NLRS_f2_beton ihwg
Name (NLRS_16.12_SF_WPB_opstort ihwg recht_gen:250x422:...)
4175171
4175175
4194435
7791150

# IfcFooting: NLRS_16.12_SF_WPB_opstort ihwg recht_gen:252x250, NLRS_16.12_SF_WPB_opstort ihwg recht_gen:252x250:12834946
In: 00 begane grond
PredefinedType: FOOTING_BEAM; Classification: 16.12 funderingsconstructies - voeten en balken, fundatie balken (Uniformat); Material: NLRS_f2_beton ihwg

# IfcFooting: NLRS_16.12_SF_WPB_opstort ihwg recht_gen:300x550, NLRS_16.12_SF_WPB_opstort ihwg recht_gen:300x550:5143196
In: 00 begane grond
PredefinedType: FOOTING_BEAM; Classification: 16.12 funderingsconstructies - voeten en balken, fundatie balken (Uniformat); Material: NLRS_f2_beton ihwg

# IfcFooting: NLRS_16.12_SF_WPB_opstort ihwg recht_gen:375x292, NLRS_16.12_SF_WPB_opstort ihwg recht_gen:375x292:5962315
In: 00 begane grond
PredefinedType: FOOTING_BEAM; Classification: 16.12 funderingsconstructies - voeten en balken, fundatie balken (Uniformat); Material: NLRS_f2_beton ihwg

# IfcFooting: NLRS_16.12_SF_WPB_opstort ihwg recht_gen:400x200 (3)
In: 00 begane grond
PredefinedType: FOOTING_BEAM; Classification: 16.12 funderingsconstructies - voeten en balken, fundatie balken (Uniformat); Material: NLRS_f2_beton ihwg
Name (NLRS_16.12_SF_WPB_opstort ihwg recht_gen:400x200:...)
7317137
7317722
7317876

# IfcFooting: NLRS_16.12_SF_WPB_opstort ihwg recht_gen:410x332 (2)
In: 00 begane grond
PredefinedType: FOOTING_BEAM; Classification: 16.12 funderingsconstructies - voeten en balken, fundatie balken (Uniformat); Material: NLRS_f2_beton ihwg
Name (NLRS_16.12_SF_WPB_opstort ihwg recht_gen:410x332:...)
5895111
5896187

# IfcGroup: Model Group:NLRS_01.00_verdieping 04_gen (2)
Name (Model Group:NLRS_01.00_verdieping 04_gen (members excluded):...) | Group
4585793 | Model Group:NLRS_01.00_mid-rise_gen:4675261
4844403 | Model Group:NLRS_01.00_mid-rise_gen:4847172

# IfcGroup: Model Group:NLRS_01.00_verdieping 05_gen (2)
Name (Model Group:...) | Group
NLRS_01.00_verdieping 05_gen:6691052 | Model Group:NLRS_01.00_mid-rise_gen:4847172
NLRS_01.00_verdieping 05_gen (members excluded):6698157 | Model Group:NLRS_01.00_mid-rise_gen:4675261

# IfcGroup: Model Group:NLRS_01.00_verdieping 06--10_gen (10)
Name (Model Group:NLRS_01.00_verdieping 06--10_gen:...) | Group
4600460 | Model Group:NLRS_01.00_mid-rise_gen:4675261
4600975 | Model Group:NLRS_01.00_mid-rise_gen:4675261
4602043 | Model Group:NLRS_01.00_mid-rise_gen:4675261
4603152 | Model Group:NLRS_01.00_mid-rise_gen:4675261
4604220 | Model Group:NLRS_01.00_mid-rise_gen:4675261
4844478 | Model Group:NLRS_01.00_mid-rise_gen:4847172
4844553 | Model Group:NLRS_01.00_mid-rise_gen:4847172
4844628 | Model Group:NLRS_01.00_mid-rise_gen:4847172
4844703 | Model Group:NLRS_01.00_mid-rise_gen:4847172
4844850 | Model Group:NLRS_01.00_mid-rise_gen:4847172

# IfcGroup: Model Group:NLRS_01.00_verdieping 11--17_gen (14)
Name (Model Group:NLRS_01.00_verdieping 11--17_gen:...) | Group
4609129 | Model Group:NLRS_01.00_mid-rise_gen:4675261
4609592 | Model Group:NLRS_01.00_mid-rise_gen:4675261
4610618 | Model Group:NLRS_01.00_mid-rise_gen:4675261
4611642 | Model Group:NLRS_01.00_mid-rise_gen:4675261
4612668 | Model Group:NLRS_01.00_mid-rise_gen:4675261
4613692 | Model Group:NLRS_01.00_mid-rise_gen:4675261
4626135 | Model Group:NLRS_01.00_mid-rise_gen:4675261
4844919 | Model Group:NLRS_01.00_mid-rise_gen:4847172
4844988 | Model Group:NLRS_01.00_mid-rise_gen:4847172
4845057 | Model Group:NLRS_01.00_mid-rise_gen:4847172
4845126 | Model Group:NLRS_01.00_mid-rise_gen:4847172
4845195 | Model Group:NLRS_01.00_mid-rise_gen:4847172
4845336 | Model Group:NLRS_01.00_mid-rise_gen:4847172
4845821 | Model Group:NLRS_01.00_mid-rise_gen:4847172

# IfcGroup: Model Group:NLRS_01.00_verdieping 18-19_gen (4)
Name (Model Group:NLRS_01.00_verdieping 18-19_gen:...) | Group
4617185 | Model Group:NLRS_01.00_mid-rise_gen:4675261
4617669 | Model Group:NLRS_01.00_mid-rise_gen:4675261
4845405 | Model Group:NLRS_01.00_mid-rise_gen:4847172
4845546 | Model Group:NLRS_01.00_mid-rise_gen:4847172

# IfcGroup: Model Group:NLRS_01.00_verdieping 20_gen (2)
Name (Model Group:NLRS_01.00_verdieping 20_gen:...) | Group
4622361 | Model Group:NLRS_01.00_mid-rise_gen:4675261
4845671 | Model Group:NLRS_01.00_mid-rise_gen:4847172

# IfcGroup: Model Group:NLRS_01.00_verdieping 21--23_gen (2)
Name (Model Group:NLRS_01.00_verdieping 21--23_gen (members excluded):...) | Group
4647240 | Model Group:NLRS_01.00_mid-rise_gen:4675261
4846692 | Model Group:NLRS_01.00_mid-rise_gen:4847172

# IfcGroup: Model Group:NLRS_21.21_wand ihwg as L.P 06-20_gen (64)
Name (Model Group:NLRS_21.21_wand ihwg as L.P 06-20_gen:...) | Group
4599056 | Model Group:NLRS_01.00_verdieping 06--10_gen:4600460
4599124 | Model Group:NLRS_01.00_verdieping 06--10_gen:4600460
4600793 | Model Group:NLRS_01.00_verdieping 06--10_gen:4600975
4600861 | Model Group:NLRS_01.00_verdieping 06--10_gen:4600975
4601861 | Model Group:NLRS_01.00_verdieping 06--10_gen:4602043
4601929 | Model Group:NLRS_01.00_verdieping 06--10_gen:4602043
4602970 | Model Group:NLRS_01.00_verdieping 06--10_gen:4603152
4603038 | Model Group:NLRS_01.00_verdieping 06--10_gen:4603152
4604038 | Model Group:NLRS_01.00_verdieping 06--10_gen:4604220
4604106 | Model Group:NLRS_01.00_verdieping 06--10_gen:4604220
4608046 | Model Group:NLRS_01.00_verdieping 11--17_gen:4609129
4608114 | Model Group:NLRS_01.00_verdieping 11--17_gen:4609129
4609416 | Model Group:NLRS_01.00_verdieping 11--17_gen:4609592
4609484 | Model Group:NLRS_01.00_verdieping 11--17_gen:4609592
4610442 | Model Group:NLRS_01.00_verdieping 11--17_gen:4610618
4610510 | Model Group:NLRS_01.00_verdieping 11--17_gen:4610618
4611466 | Model Group:NLRS_01.00_verdieping 11--17_gen:4611642
4611534 | Model Group:NLRS_01.00_verdieping 11--17_gen:4611642
4612492 | Model Group:NLRS_01.00_verdieping 11--17_gen:4612668
4612560 | Model Group:NLRS_01.00_verdieping 11--17_gen:4612668
4613516 | Model Group:NLRS_01.00_verdieping 11--17_gen:4613692
4613584 | Model Group:NLRS_01.00_verdieping 11--17_gen:4613692
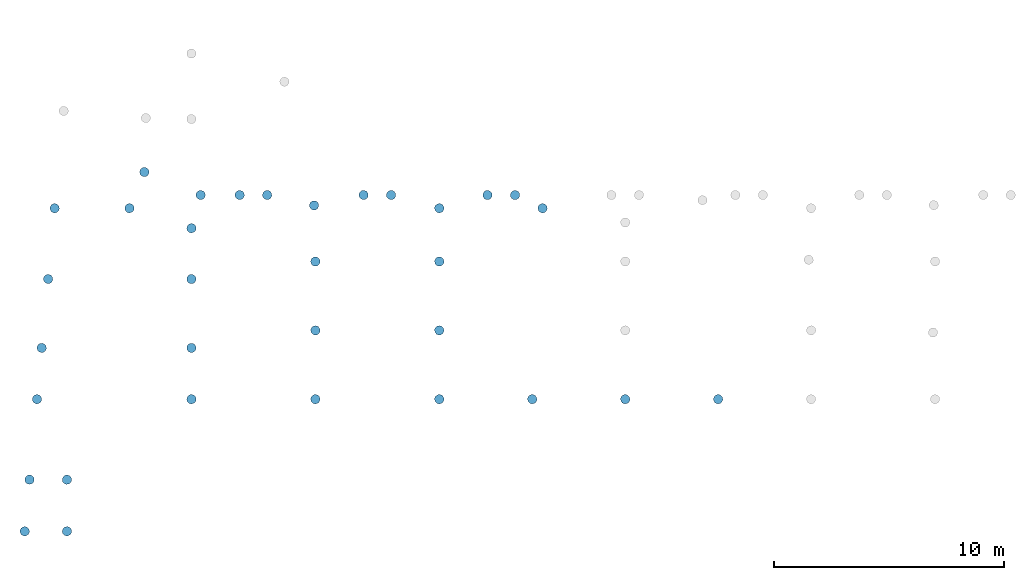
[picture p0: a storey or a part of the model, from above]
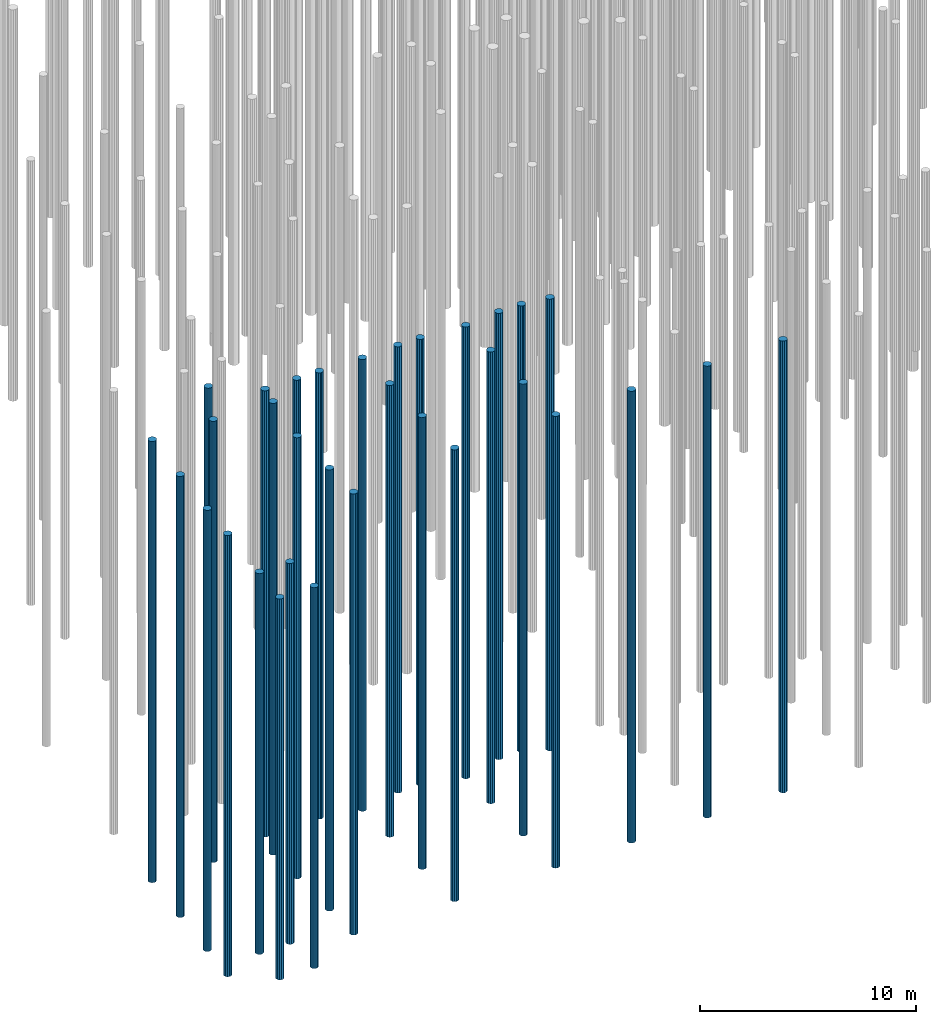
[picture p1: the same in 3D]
Properties of the parts of a building model (IFC2X3), part 4 of 11

# IfcGroup: Model Group:NLRS_21.21_wand ihwg as L.P 06-20_gen (64)
Name (Model Group:NLRS_21.21_wand ihwg as L.P 06-20_gen:...) | Group
4616006 | Model Group:NLRS_01.00_verdieping 18-19_gen:4617185
4616074 | Model Group:NLRS_01.00_verdieping 18-19_gen:4617185
4617493 | Model Group:NLRS_01.00_verdieping 18-19_gen:4617669
4617561 | Model Group:NLRS_01.00_verdieping 18-19_gen:4617669
4618590 | Model Group:NLRS_01.00_verdieping 20_gen:4622361
4618658 | Model Group:NLRS_01.00_verdieping 20_gen:4622361
4625959 | Model Group:NLRS_01.00_verdieping 11--17_gen:4626135
4626027 | Model Group:NLRS_01.00_verdieping 11--17_gen:4626135
4844406 | Model Group:NLRS_01.00_verdieping 06--10_gen:4844478
4844438 | Model Group:NLRS_01.00_verdieping 06--10_gen:4844478
4844481 | Model Group:NLRS_01.00_verdieping 06--10_gen:4844553
4844513 | Model Group:NLRS_01.00_verdieping 06--10_gen:4844553
4844556 | Model Group:NLRS_01.00_verdieping 06--10_gen:4844628
4844588 | Model Group:NLRS_01.00_verdieping 06--10_gen:4844628
4844631 | Model Group:NLRS_01.00_verdieping 06--10_gen:4844703
4844663 | Model Group:NLRS_01.00_verdieping 06--10_gen:4844703
4844706 | Model Group:NLRS_01.00_verdieping 06--10_gen:4844850
4844738 | Model Group:NLRS_01.00_verdieping 06--10_gen:4844850
4844853 | Model Group:NLRS_01.00_verdieping 11--17_gen:4844919
4844885 | Model Group:NLRS_01.00_verdieping 11--17_gen:4844919
4844922 | Model Group:NLRS_01.00_verdieping 11--17_gen:4844988
4844954 | Model Group:NLRS_01.00_verdieping 11--17_gen:4844988
4844991 | Model Group:NLRS_01.00_verdieping 11--17_gen:4845057
4845023 | Model Group:NLRS_01.00_verdieping 11--17_gen:4845057
4845060 | Model Group:NLRS_01.00_verdieping 11--17_gen:4845126
4845092 | Model Group:NLRS_01.00_verdieping 11--17_gen:4845126
4845129 | Model Group:NLRS_01.00_verdieping 11--17_gen:4845195
4845161 | Model Group:NLRS_01.00_verdieping 11--17_gen:4845195
4845198 | Model Group:NLRS_01.00_verdieping 11--17_gen:4845336
4845230 | Model Group:NLRS_01.00_verdieping 11--17_gen:4845336
4845339 | Model Group:NLRS_01.00_verdieping 18-19_gen:4845405
4845371 | Model Group:NLRS_01.00_verdieping 18-19_gen:4845405
4845408 | Model Group:NLRS_01.00_verdieping 18-19_gen:4845546
4845440 | Model Group:NLRS_01.00_verdieping 18-19_gen:4845546
4845549 | Model Group:NLRS_01.00_verdieping 20_gen:4845671
4845581 | Model Group:NLRS_01.00_verdieping 20_gen:4845671
4845680 | Model Group:NLRS_01.00_verdieping 05_gen:6691052
4845712 | Model Group:NLRS_01.00_verdieping 05_gen:6691052
4845755 | Model Group:NLRS_01.00_verdieping 11--17_gen:4845821
4845787 | Model Group:NLRS_01.00_verdieping 11--17_gen:4845821
6698038 | Model Group:NLRS_01.00_verdieping 05_gen (members excluded):6698157
6698070 | Model Group:NLRS_01.00_verdieping 05_gen (members excluded):6698157

# IfcOpeningElement: Opening (5029)
Name | In | Classification
591 x  | 00 begane grond
Basic Wall:NLRS_22.21_WA_beton ihwg d=250_gen:4222103 | 00 begane grond | 22.21 binnenwanden - constructief, massieve wanden (Uniformat)
Basic Wall:NLRS_22.21_WA_beton ihwg d=250_gen:4222248 | 00 begane grond | 22.21 binnenwanden - constructief, massieve wanden (Uniformat)
Basic Wall:NLRS_21.21_WA_beton prefab d=200_gen:4222705 | 00 begane grond | 21.21 buitenwanden - constructief, massieve wanden (Uniformat)
Basic Wall:NLRS_21.21_WA_beton prefab d=250_gen:4223142 | 00 begane grond | 21.21 buitenwanden - constructief, massieve wanden (Uniformat)
2 x Basic Wall:NLRS_21.21_WA_beton prefab d=250_gen:4227569 | 00 begane grond | 21.21 buitenwanden - constructief, massieve wanden (Uniformat)
4 x Basic Wall:NLRS_22.21_WA_beton prefab d=250_gen:4227600 | 00 begane grond | 22.21 binnenwanden - constructief, massieve wanden (Uniformat)
10 x Basic Wall:NLRS_22.21_WA_beton prefab d=250_gen:1312532 | 00 begane grond | 22.21 binnenwanden - constructief, massieve wanden (Uniformat)
8 x Basic Wall:NLRS_21.21_WA_beton prefab d=250_gen:4227922 | 00 begane grond | 21.21 buitenwanden - constructief, massieve wanden (Uniformat)
61 x Basic Wall:NLRS_21.21_WA_beton prefab d=200_gen:4231471 | 00 begane grond | 21.21 buitenwanden - constructief, massieve wanden (Uniformat)
Basic Wall:NLRS_22.21_WA_beton prefab d=250_gen:4238424 | 00 begane grond | 22.21 binnenwanden - constructief, massieve wanden (Uniformat)
Basic Wall:NLRS_22.21_WA_beton prefab d=250_gen:4239312 | 00 begane grond | 22.21 binnenwanden - constructief, massieve wanden (Uniformat)
Basic Wall:NLRS_22.21_WA_beton prefab d=250_gen:4239349 | 00 begane grond | 22.21 binnenwanden - constructief, massieve wanden (Uniformat)
Basic Wall:NLRS_22.21_WA_beton prefab d=250_gen:4239422 | 00 begane grond | 22.21 binnenwanden - constructief, massieve wanden (Uniformat)
2 x Basic Wall:NLRS_22.21_WA_beton ihwg d=250_gen:4239756 | 00 begane grond | 22.21 binnenwanden - constructief, massieve wanden (Uniformat)
5 x Basic Wall:NLRS_22.21_WA_beton ihwg d=250_gen:4239840 | 00 begane grond | 22.21 binnenwanden - constructief, massieve wanden (Uniformat)
4 x Basic Wall:NLRS_22.21_WA_beton ihwg d=250_gen:4240043 | 00 begane grond | 22.21 binnenwanden - constructief, massieve wanden (Uniformat)
Basic Wall:NLRS_22.21_WA_beton ihwg d=250_gen:4240099 | 00 begane grond | 22.21 binnenwanden - constructief, massieve wanden (Uniformat)
4 x Basic Wall:NLRS_22.21_WA_beton ihwg d=250_gen:1312528 | 00 begane grond | 22.21 binnenwanden - constructief, massieve wanden (Uniformat)
Basic Wall:NLRS_22.21_WA_beton ihwg d=250_gen:4240202 | 00 begane grond | 22.21 binnenwanden - constructief, massieve wanden (Uniformat)
2 x Basic Wall:NLRS_22.21_WA_beton prefab d=250_gen:4240422 | 00 begane grond | 22.21 binnenwanden - constructief, massieve wanden (Uniformat)
Basic Wall:NLRS_22.21_WA_beton ihwg d=250_gen:4240908 | 00 begane grond | 22.21 binnenwanden - constructief, massieve wanden (Uniformat)
5 x Basic Wall:NLRS_22.21_WA_beton ihwg d=250_gen:4241678 | 00 begane grond | 22.21 binnenwanden - constructief, massieve wanden (Uniformat)
7 x Basic Wall:NLRS_22.21_WA_beton ihwg d=250_gen:4242182 | 00 begane grond | 22.21 binnenwanden - constructief, massieve wanden (Uniformat)
Basic Wall:NLRS_22.21_WA_beton ihwg d=250_gen:4243948 | 00 begane grond | 22.21 binnenwanden - constructief, massieve wanden (Uniformat)
5 x Basic Wall:NLRS_22.21_WA_beton ihwg d=250_gen:4246637 | 00 begane grond | 22.21 binnenwanden - constructief, massieve wanden (Uniformat)
11 x Basic Wall:NLRS_22.21_WA_beton ihwg d=250_gen:4246909 | 00 begane grond | 22.21 binnenwanden - constructief, massieve wanden (Uniformat)
6 x Basic Wall:NLRS_22.21_WA_beton ihwg d=250_gen:4251977 | 00 begane grond | 22.21 binnenwanden - constructief, massieve wanden (Uniformat)
12 x Basic Wall:NLRS_22.21_WA_beton ihwg d=250_gen:4256084 | 00 begane grond | 22.21 binnenwanden - constructief, massieve wanden (Uniformat)
2 x Basic Wall:NLRS_22.21_WA_beton ihwg d=250_gen:4256256 | 00 begane grond | 22.21 binnenwanden - constructief, massieve wanden (Uniformat)
2 x Basic Wall:NLRS_22.21_WA_beton prefab d=180_gen:4264732 | 00 begane grond | 22.21 binnenwanden - constructief, massieve wanden (Uniformat)
62 x Basic Wall:NLRS_21.21_WA_beton prefab d=200_gen:4291020 | 01 eerste verdieping | 21.21 buitenwanden - constructief, massieve wanden (Uniformat)
40 x Basic Wall:NLRS_21.21_WA_beton prefab d=200_gen:4293523 | 02 tweede verdieping | 21.21 buitenwanden - constructief, massieve wanden (Uniformat)
7 x Basic Wall:NLRS_21.21_WA_beton prefab d=200_gen:4294763 | 03 derde verdieping | 21.21 buitenwanden - constructief, massieve wanden (Uniformat)
6 x Basic Wall:NLRS_21.21_WA_beton prefab d=200_gen:4295345 | 03 derde verdieping | 21.21 buitenwanden - constructief, massieve wanden (Uniformat)
6 x Basic Wall:NLRS_21.21_WA_beton prefab d=200_gen:4296181 | 03 derde verdieping | 21.21 buitenwanden - constructief, massieve wanden (Uniformat)
5 x Basic Wall:NLRS_21.21_WA_beton prefab d=200_gen:4296283 | 03 derde verdieping | 21.21 buitenwanden - constructief, massieve wanden (Uniformat)
7 x Basic Wall:NLRS_21.21_WA_beton prefab d=250_gen:4296753 | 00 begane grond | 21.21 buitenwanden - constructief, massieve wanden (Uniformat)
8 x Basic Wall:NLRS_21.21_WA_beton prefab d=250_gen:4299056 | 01 eerste verdieping | 21.21 buitenwanden - constructief, massieve wanden (Uniformat)
7 x Basic Wall:NLRS_21.21_WA_beton prefab d=250_gen:4299065 | 01 eerste verdieping | 21.21 buitenwanden - constructief, massieve wanden (Uniformat)
7 x Basic Wall:NLRS_21.21_WA_beton prefab d=250_gen:4299069 | 01 eerste verdieping | 21.21 buitenwanden - constructief, massieve wanden (Uniformat)
8 x Basic Wall:NLRS_21.21_WA_beton prefab d=250_gen:4299799 | 02 tweede verdieping | 21.21 buitenwanden - constructief, massieve wanden (Uniformat)
3 x Basic Wall:NLRS_21.21_WA_beton prefab d=250_gen:1307923 | 02 tweede verdieping | 21.21 buitenwanden - constructief, massieve wanden (Uniformat)
6 x Basic Wall:NLRS_21.21_WA_beton prefab d=250_gen:4299801 | 02 tweede verdieping | 21.21 buitenwanden - constructief, massieve wanden (Uniformat)
7 x Basic Wall:NLRS_21.21_WA_beton prefab d=250_gen:4299885 | 03 derde verdieping | 21.21 buitenwanden - constructief, massieve wanden (Uniformat)
5 x Basic Wall:NLRS_21.21_WA_beton prefab d=250_gen:4299887 | 03 derde verdieping | 21.21 buitenwanden - constructief, massieve wanden (Uniformat)
6 x Basic Wall:NLRS_22.21_WA_beton ihwg d=250_gen:1312528 | 01 eerste verdieping | 22.21 binnenwanden - constructief, massieve wanden (Uniformat)
2 x Basic Wall:NLRS_22.21_WA_beton prefab d=250_gen:4318848 | 00 begane grond | 22.21 binnenwanden - constructief, massieve wanden (Uniformat)
2 x Basic Wall:NLRS_22.21_WA_beton ihwg d=250_gen:4319766 | 01 eerste verdieping | 22.21 binnenwanden - constructief, massieve wanden (Uniformat)
2 x Basic Wall:NLRS_22.21_WA_beton ihwg d=250_gen:4320068 | 01 eerste verdieping | 22.21 binnenwanden - constructief, massieve wanden (Uniformat)
3 x Basic Wall:NLRS_22.21_WA_beton prefab d=200_gen:1312531 | 00 begane grond | 22.21 binnenwanden - constructief, massieve wanden (Uniformat)
Basic Wall:NLRS_22.21_WA_beton prefab d=250_gen:1312532 | 01 eerste verdieping | 22.21 binnenwanden - constructief, massieve wanden (Uniformat)
Basic Wall:NLRS_22.21_WA_beton prefab d=250_gen:4323399 | 00a eerste tussenverdieping | 22.21 binnenwanden - constructief, massieve wanden (Uniformat)
Basic Wall:NLRS_22.21_WA_beton prefab d=250_gen:4323753 | 01a eerste tussenverdieping | 22.21 binnenwanden - constructief, massieve wanden (Uniformat)
Basic Wall:NLRS_22.21_WA_beton ihwg d=250_gen:4336141 | 01 eerste verdieping | 22.21 binnenwanden - constructief, massieve wanden (Uniformat)
Basic Wall:NLRS_22.21_WA_beton ihwg d=250_gen:4339330:1 | 02 tweede verdieping | 22.21 binnenwanden - constructief, massieve wanden (Uniformat)
Basic Wall:NLRS_22.21_WA_beton ihwg d=250_gen:4339334 | 01c derde tussenverdieping | 22.21 binnenwanden - constructief, massieve wanden (Uniformat)
Basic Wall:NLRS_22.21_WA_beton ihwg d=250_gen:4339336 | 01c derde tussenverdieping | 22.21 binnenwanden - constructief, massieve wanden (Uniformat)
Basic Wall:NLRS_22.21_WA_beton prefab d=250_gen:4339346 | 01b tweede tussenverdieping | 22.21 binnenwanden - constructief, massieve wanden (Uniformat)
Basic Wall:NLRS_22.21_WA_beton ihwg d=250_gen:4339354 | 01c derde tussenverdieping | 22.21 binnenwanden - constructief, massieve wanden (Uniformat)
4 x Basic Wall:NLRS_22.21_WA_beton ihwg d=250_gen:1312528 | 01c derde tussenverdieping | 22.21 binnenwanden - constructief, massieve wanden (Uniformat)
2 x Basic Wall:NLRS_22.21_WA_beton ihwg d=250_gen:4341136 | 02 tweede verdieping | 22.21 binnenwanden - constructief, massieve wanden (Uniformat)
Basic Wall:NLRS_22.21_WA_beton ihwg d=250_gen:4342956 | 03 derde verdieping | 22.21 binnenwanden - constructief, massieve wanden (Uniformat)
Basic Wall:NLRS_22.21_WA_beton ihwg d=250_gen:4342958 | 02b tweede tussenverdieping | 22.21 binnenwanden - constructief, massieve wanden (Uniformat)
4 x Basic Wall:NLRS_22.21_WA_beton ihwg d=250_gen:1312528 | 02b tweede tussenverdieping | 22.21 binnenwanden - constructief, massieve wanden (Uniformat)
Basic Wall:NLRS_21.21_WA_beton prefab d=250_gen:4342962 | 03 derde verdieping | 21.21 buitenwanden - constructief, massieve wanden (Uniformat)
Basic Wall:NLRS_21.21_WA_beton prefab d=250_gen:1307923 | 03 derde verdieping | 21.21 buitenwanden - constructief, massieve wanden (Uniformat)
Basic Wall:NLRS_22.21_WA_beton prefab d=250_gen:4342970 | 02a eerste tussenverdieping | 22.21 binnenwanden - constructief, massieve wanden (Uniformat)
6 x Basic Wall:NLRS_22.21_WA_beton ihwg d=250_gen:4342978 | 02b tweede tussenverdieping | 22.21 binnenwanden - constructief, massieve wanden (Uniformat)
Basic Wall:NLRS_22.21_WA_beton ihwg d=250_gen:4342984 | 03 derde verdieping | 22.21 binnenwanden - constructief, massieve wanden (Uniformat)
Basic Wall:NLRS_22.21_WA_beton ihwg d=250_gen:4343917 | 03 derde verdieping | 22.21 binnenwanden - constructief, massieve wanden (Uniformat)
2 x Basic Wall:NLRS_21.21_WA_beton ihwg d=250_gen:1307691 | 02b tweede tussenverdieping | 21.21 buitenwanden - constructief, massieve wanden (Uniformat)
2 x Basic Wall:NLRS_22.21_WA_beton ihwg d=250_gen:4343927 | 03 derde verdieping | 22.21 binnenwanden - constructief, massieve wanden (Uniformat)
5 x Basic Wall:NLRS_22.21_WA_beton ihwg d=250_gen:4344512 | 02b tweede tussenverdieping | 22.21 binnenwanden - constructief, massieve wanden (Uniformat)
4 x Basic Wall:NLRS_22.21_WA_beton ihwg d=250_gen:4344708 | 02b tweede tussenverdieping | 22.21 binnenwanden - constructief, massieve wanden (Uniformat)
Basic Wall:NLRS_22.21_WA_beton ihwg d=250_gen:4344791 | 01c derde tussenverdieping | 22.21 binnenwanden - constructief, massieve wanden (Uniformat)
Basic Wall:NLRS_22.21_WA_beton ihwg d=250_gen:4345254 | 01 eerste verdieping | 22.21 binnenwanden - constructief, massieve wanden (Uniformat)
14 x Basic Wall:NLRS_22.21_WA_beton prefab d=250_gen:1312532 | 01a eerste tussenverdieping | 22.21 binnenwanden - constructief, massieve wanden (Uniformat)
13 x Basic Wall:NLRS_22.21_WA_beton prefab d=250_gen:1312532 | 02 tweede verdieping | 22.21 binnenwanden - constructief, massieve wanden (Uniformat)
Basic Wall:NLRS_22.21_WA_beton prefab d=250_gen:4363912 | 02b tweede tussenverdieping | 22.21 binnenwanden - constructief, massieve wanden (Uniformat)
26 x Basic Wall:NLRS_22.21_WA_beton prefab d=250_gen:1312532 | 02b tweede tussenverdieping | 22.21 binnenwanden - constructief, massieve wanden (Uniformat)
Basic Wall:NLRS_22.21_WA_beton prefab d=250_gen:4367377 | 02b tweede tussenverdieping | 22.21 binnenwanden - constructief, massieve wanden (Uniformat)
Basic Wall:NLRS_22.21_WA_beton prefab d=250_gen:4367529 | 02b tweede tussenverdieping | 22.21 binnenwanden - constructief, massieve wanden (Uniformat)
Basic Wall:NLRS_22.21_WA_beton prefab d=250_gen:4367553 | 01a eerste tussenverdieping | 22.21 binnenwanden - constructief, massieve wanden (Uniformat)
Basic Wall:NLRS_22.21_WA_beton prefab d=250_gen:4367575 | 02 tweede verdieping | 22.21 binnenwanden - constructief, massieve wanden (Uniformat)
Basic Wall:NLRS_22.21_WA_beton prefab d=250_gen:4367605 | 02b tweede tussenverdieping | 22.21 binnenwanden - constructief, massieve wanden (Uniformat)
NLRS_21.21_SF_WPB_oplegnok ihwg beton_gen:200x250:4394952:1 | 04 vierde verdieping | 21.21 buitenwanden - constructief, massieve wanden (Uniformat)
Basic Wall:NLRS_21.21_WA_beton prefab d=250_gen:4407109 | 02 tweede verdieping | 21.21 buitenwanden - constructief, massieve wanden (Uniformat)
2 x Basic Wall:NLRS_21.21_WA_beton prefab d=200_gen:4407357 | 01 eerste verdieping | 21.21 buitenwanden - constructief, massieve wanden (Uniformat)
2 x Basic Wall:NLRS_21.21_WA_beton prefab d=200_gen:4407509 | 02 tweede verdieping | 21.21 buitenwanden - constructief, massieve wanden (Uniformat)
Floor:NLRS_23.21_FL_druklaag d=70 - gevlinderd_gen:4409162:2 | 00 begane grond | 23.21 vloeren - constructief, vrijdragende vloeren (Uniformat)
Floor:NLRS_23.21_FL_geisoleerde kanaalplaat d=200 rc 3.5 iso132_gen:4411953:2 | 00 begane grond | 23.21 vloeren - constructief, vrijdragende vloeren (Uniformat)
Floor:NLRS_23.21_FL_geisoleerde kanaalplaat d=200 rc 3.5 iso132_gen:4412209:2 | 00 begane grond | 23.21 vloeren - constructief, vrijdragende vloeren (Uniformat)
42 x  | 01 eerste verdieping
44 x  | 02 tweede verdieping
40 x  | 03 derde verdieping
48 x  | 04 vierde verdieping
Floor:NLRS_23.21_FL_druklaag d=70 - gevlinderd en ingestrooid_gen:4460084:2 | 00a eerste tussenverdieping | 23.21 vloeren - constructief, vrijdragende vloeren (Uniformat)
Floor:NLRS_23.21_FL_druklaag d=70 - gevlinderd en ingestrooid_gen:4460084:3 | 00a eerste tussenverdieping | 23.21 vloeren - constructief, vrijdragende vloeren (Uniformat)
Floor:NLRS_23.21_FL_druklaag d=70 - gevlinderd en ingestrooid_gen:4460084:4 | 00a eerste tussenverdieping | 23.21 vloeren - constructief, vrijdragende vloeren (Uniformat)
Floor:NLRS_23.21_FL_druklaag d=70 - gevlinderd en ingestrooid_gen:4460084:5 | 00a eerste tussenverdieping | 23.21 vloeren - constructief, vrijdragende vloeren (Uniformat)
Floor:NLRS_23.21_FL_druklaag d=70 - gevlinderd en ingestrooid_gen:4460084:6 | 00a eerste tussenverdieping | 23.21 vloeren - constructief, vrijdragende vloeren (Uniformat)
Floor:NLRS_23.21_FL_druklaag d=70 - gevlinderd en ingestrooid_gen:4460084:7 | 00a eerste tussenverdieping | 23.21 vloeren - constructief, vrijdragende vloeren (Uniformat)
Floor:NLRS_23.21_FL_druklaag d=70 - gevlinderd en ingestrooid_gen:4460084:8 | 00a eerste tussenverdieping | 23.21 vloeren - constructief, vrijdragende vloeren (Uniformat)
8 x  | 01a eerste tussenverdieping | 23.21 vloeren - constructief, vrijdragende vloeren (Uniformat)
14 x  | 01a eerste tussenverdieping
Floor:NLRS_23.21_FL_druklaag d=70 - gevlinderd en ingestrooid_gen:4463176:2 | 01a eerste tussenverdieping | 23.21 vloeren - constructief, vrijdragende vloeren (Uniformat)
Floor:NLRS_23.21_FL_druklaag d=70 - gevlinderd en ingestrooid_gen:4463176:3 | 01a eerste tussenverdieping | 23.21 vloeren - constructief, vrijdragende vloeren (Uniformat)
Floor:NLRS_23.21_FL_druklaag d=70 - gevlinderd en ingestrooid_gen:4463176:4 | 01a eerste tussenverdieping | 23.21 vloeren - constructief, vrijdragende vloeren (Uniformat)
Floor:NLRS_23.21_FL_druklaag d=70 - gevlinderd en ingestrooid_gen:4463176:5 | 01a eerste tussenverdieping | 23.21 vloeren - constructief, vrijdragende vloeren (Uniformat)
Floor:NLRS_23.21_FL_druklaag d=70 - gevlinderd en ingestrooid_gen:4463176:6 | 01a eerste tussenverdieping | 23.21 vloeren - constructief, vrijdragende vloeren (Uniformat)
Floor:NLRS_23.21_FL_druklaag d=70 - gevlinderd en ingestrooid_gen:4463176:7 | 01a eerste tussenverdieping | 23.21 vloeren - constructief, vrijdragende vloeren (Uniformat)
Floor:NLRS_23.21_FL_druklaag d=70 - gevlinderd en ingestrooid_gen:4463176:8 | 01a eerste tussenverdieping | 23.21 vloeren - constructief, vrijdragende vloeren (Uniformat)
Floor:NLRS_23.21_FL_druklaag d=70 - gevlinderd en ingestrooid_gen:4463176:9 | 01a eerste tussenverdieping | 23.21 vloeren - constructief, vrijdragende vloeren (Uniformat)
Floor:NLRS_23.21_FL_druklaag d=70 - gevlinderd en ingestrooid_gen:4463176:10 | 01a eerste tussenverdieping | 23.21 vloeren - constructief, vrijdragende vloeren (Uniformat)
Floor:NLRS_23.21_FL_druklaag d=70 - gevlinderd en ingestrooid_gen:4463176:11 | 01a eerste tussenverdieping | 23.21 vloeren - constructief, vrijdragende vloeren (Uniformat)
Floor:NLRS_23.21_FL_druklaag d=70 - gevlinderd en ingestrooid_gen:4463176:12 | 01a eerste tussenverdieping | 23.21 vloeren - constructief, vrijdragende vloeren (Uniformat)
Floor:NLRS_23.21_FL_druklaag d=70 - gevlinderd en ingestrooid_gen:4463176:13 | 01a eerste tussenverdieping | 23.21 vloeren - constructief, vrijdragende vloeren (Uniformat)
Floor:NLRS_23.21_FL_druklaag d=70 - gevlinderd en ingestrooid_gen:4463176:14 | 01a eerste tussenverdieping | 23.21 vloeren - constructief, vrijdragende vloeren (Uniformat)
Floor:NLRS_23.21_FL_druklaag d=70 - gevlinderd en ingestrooid_gen:4463176:15 | 01a eerste tussenverdieping | 23.21 vloeren - constructief, vrijdragende vloeren (Uniformat)
Floor:NLRS_23.21_FL_druklaag d=70 - gevlinderd en ingestrooid_gen:4463176:16 | 01a eerste tussenverdieping | 23.21 vloeren - constructief, vrijdragende vloeren (Uniformat)
Floor:NLRS_23.21_FL_druklaag d=70 - gevlinderd en ingestrooid_gen:4464669:2 | 01a eerste tussenverdieping | 23.21 vloeren - constructief, vrijdragende vloeren (Uniformat)
Floor:NLRS_23.21_FL_druklaag d=70 - gevlinderd en ingestrooid_gen:4464669:3 | 01a eerste tussenverdieping | 23.21 vloeren - constructief, vrijdragende vloeren (Uniformat)
Floor:NLRS_23.21_FL_druklaag d=70 - gevlinderd en ingestrooid_gen:4464669:4 | 01a eerste tussenverdieping | 23.21 vloeren - constructief, vrijdragende vloeren (Uniformat)
Floor:NLRS_23.21_FL_druklaag d=70 - gevlinderd en ingestrooid_gen:4464669:5 | 01a eerste tussenverdieping | 23.21 vloeren - constructief, vrijdragende vloeren (Uniformat)
Floor:NLRS_23.21_FL_druklaag d=70 - gevlinderd en ingestrooid_gen:4464669:6 | 01a eerste tussenverdieping | 23.21 vloeren - constructief, vrijdragende vloeren (Uniformat)
Floor:NLRS_23.21_FL_druklaag d=70 - gevlinderd en ingestrooid_gen:4464669:7 | 01a eerste tussenverdieping | 23.21 vloeren - constructief, vrijdragende vloeren (Uniformat)
Floor:NLRS_23.21_FL_druklaag d=70 - gevlinderd en ingestrooid_gen:4464669:8 | 01a eerste tussenverdieping | 23.21 vloeren - constructief, vrijdragende vloeren (Uniformat)
Floor:NLRS_23.21_FL_druklaag d=70 - gevlinderd en ingestrooid_gen:4464669:9 | 01a eerste tussenverdieping | 23.21 vloeren - constructief, vrijdragende vloeren (Uniformat)
Floor:NLRS_23.21_FL_druklaag d=70 - gevlinderd en ingestrooid_gen:4464669:10 | 01a eerste tussenverdieping | 23.21 vloeren - constructief, vrijdragende vloeren (Uniformat)
Floor:NLRS_23.21_FL_druklaag d=70 - gevlinderd en ingestrooid_gen:4464669:11 | 01a eerste tussenverdieping | 23.21 vloeren - constructief, vrijdragende vloeren (Uniformat)
Floor:NLRS_23.21_FL_druklaag d=70 - gevlinderd en ingestrooid_gen:4464669:12 | 01a eerste tussenverdieping | 23.21 vloeren - constructief, vrijdragende vloeren (Uniformat)
Floor:NLRS_23.21_FL_druklaag d=70 - gevlinderd en ingestrooid_gen:4464669:13 | 01a eerste tussenverdieping | 23.21 vloeren - constructief, vrijdragende vloeren (Uniformat)
Floor:NLRS_23.21_FL_druklaag d=70 - gevlinderd en ingestrooid_gen:4464669:14 | 01a eerste tussenverdieping | 23.21 vloeren - constructief, vrijdragende vloeren (Uniformat)
8 x  | 01c derde tussenverdieping | 23.21 vloeren - constructief, vrijdragende vloeren (Uniformat)
8 x  | 02b tweede tussenverdieping | 23.21 vloeren - constructief, vrijdragende vloeren (Uniformat)
Floor:NLRS_23.21_FL_druklaag d=70 - gevlinderd en ingestrooid_gen:4472069:2 | 02b tweede tussenverdieping | 23.21 vloeren - constructief, vrijdragende vloeren (Uniformat)
Floor:NLRS_23.21_FL_druklaag d=70 - gevlinderd en ingestrooid_gen:4472069:3 | 02b tweede tussenverdieping | 23.21 vloeren - constructief, vrijdragende vloeren (Uniformat)
Floor:NLRS_23.21_FL_druklaag d=70 - gevlinderd en ingestrooid_gen:4472069:4 | 02b tweede tussenverdieping | 23.21 vloeren - constructief, vrijdragende vloeren (Uniformat)
Floor:NLRS_23.21_FL_druklaag d=70 - gevlinderd en ingestrooid_gen:4472069:5 | 02b tweede tussenverdieping | 23.21 vloeren - constructief, vrijdragende vloeren (Uniformat)
Floor:NLRS_23.21_FL_druklaag d=70 - gevlinderd en ingestrooid_gen:4472069:6 | 02b tweede tussenverdieping | 23.21 vloeren - constructief, vrijdragende vloeren (Uniformat)
Floor:NLRS_23.21_FL_druklaag d=70 - gevlinderd en ingestrooid_gen:4472069:7 | 02b tweede tussenverdieping | 23.21 vloeren - constructief, vrijdragende vloeren (Uniformat)
Floor:NLRS_23.21_FL_druklaag d=70 - gevlinderd en ingestrooid_gen:4472069:8 | 02b tweede tussenverdieping | 23.21 vloeren - constructief, vrijdragende vloeren (Uniformat)
Floor:NLRS_23.21_FL_druklaag d=70 - gevlinderd en ingestrooid_gen:4472069:9 | 02b tweede tussenverdieping | 23.21 vloeren - constructief, vrijdragende vloeren (Uniformat)
Floor:NLRS_23.21_FL_druklaag d=70 - gevlinderd en ingestrooid_gen:4472069:10 | 02b tweede tussenverdieping | 23.21 vloeren - constructief, vrijdragende vloeren (Uniformat)
Floor:NLRS_23.21_FL_druklaag d=70 - gevlinderd en ingestrooid_gen:4472069:11 | 02b tweede tussenverdieping | 23.21 vloeren - constructief, vrijdragende vloeren (Uniformat)
Floor:NLRS_23.21_FL_druklaag d=70 - gevlinderd en ingestrooid_gen:4472069:12 | 02b tweede tussenverdieping | 23.21 vloeren - constructief, vrijdragende vloeren (Uniformat)
Floor:NLRS_23.21_FL_druklaag d=70 - gevlinderd en ingestrooid_gen:4472069:13 | 02b tweede tussenverdieping | 23.21 vloeren - constructief, vrijdragende vloeren (Uniformat)
Floor:NLRS_23.21_FL_druklaag d=70 - gevlinderd en ingestrooid_gen:4472069:14 | 02b tweede tussenverdieping | 23.21 vloeren - constructief, vrijdragende vloeren (Uniformat)
Floor:NLRS_23.21_FL_druklaag d=70 - gevlinderd en ingestrooid_gen:4472069:15 | 02b tweede tussenverdieping | 23.21 vloeren - constructief, vrijdragende vloeren (Uniformat)
Floor:NLRS_23.21_FL_druklaag d=70 - gevlinderd en ingestrooid_gen:4472069:16 | 02b tweede tussenverdieping | 23.21 vloeren - constructief, vrijdragende vloeren (Uniformat)
Floor:NLRS_23.21_FL_druklaag d=70 - gevlinderd en ingestrooid_gen:4472123:2 | 01c derde tussenverdieping | 23.21 vloeren - constructief, vrijdragende vloeren (Uniformat)
Floor:NLRS_23.21_FL_druklaag d=70 - gevlinderd en ingestrooid_gen:4472123:3 | 01c derde tussenverdieping | 23.21 vloeren - constructief, vrijdragende vloeren (Uniformat)
Floor:NLRS_23.21_FL_druklaag d=70 - gevlinderd en ingestrooid_gen:4472123:4 | 01c derde tussenverdieping | 23.21 vloeren - constructief, vrijdragende vloeren (Uniformat)
Floor:NLRS_23.21_FL_druklaag d=70 - gevlinderd en ingestrooid_gen:4472123:5 | 01c derde tussenverdieping | 23.21 vloeren - constructief, vrijdragende vloeren (Uniformat)
Floor:NLRS_23.21_FL_druklaag d=70 - gevlinderd en ingestrooid_gen:4472123:6 | 01c derde tussenverdieping | 23.21 vloeren - constructief, vrijdragende vloeren (Uniformat)
Floor:NLRS_23.21_FL_druklaag d=70 - gevlinderd en ingestrooid_gen:4472123:7 | 01c derde tussenverdieping | 23.21 vloeren - constructief, vrijdragende vloeren (Uniformat)
Floor:NLRS_23.21_FL_druklaag d=70 - gevlinderd en ingestrooid_gen:4472123:8 | 01c derde tussenverdieping | 23.21 vloeren - constructief, vrijdragende vloeren (Uniformat)
Floor:NLRS_23.21_FL_druklaag d=70 - gevlinderd en ingestrooid_gen:4472123:9 | 01c derde tussenverdieping | 23.21 vloeren - constructief, vrijdragende vloeren (Uniformat)
Floor:NLRS_23.21_FL_druklaag d=70 - gevlinderd en ingestrooid_gen:4472123:10 | 01c derde tussenverdieping | 23.21 vloeren - constructief, vrijdragende vloeren (Uniformat)
Floor:NLRS_23.21_FL_druklaag d=70 - gevlinderd en ingestrooid_gen:4472123:11 | 01c derde tussenverdieping | 23.21 vloeren - constructief, vrijdragende vloeren (Uniformat)
Floor:NLRS_23.21_FL_druklaag d=70 - gevlinderd en ingestrooid_gen:4472123:12 | 01c derde tussenverdieping | 23.21 vloeren - constructief, vrijdragende vloeren (Uniformat)
Floor:NLRS_23.21_FL_druklaag d=70 - gevlinderd en ingestrooid_gen:4472123:13 | 01c derde tussenverdieping | 23.21 vloeren - constructief, vrijdragende vloeren (Uniformat)
Floor:NLRS_23.21_FL_druklaag d=70 - gevlinderd en ingestrooid_gen:4472123:14 | 01c derde tussenverdieping | 23.21 vloeren - constructief, vrijdragende vloeren (Uniformat)
Floor:NLRS_23.21_FL_druklaag d=70 - gevlinderd en ingestrooid_gen:4472123:15 | 01c derde tussenverdieping | 23.21 vloeren - constructief, vrijdragende vloeren (Uniformat)
Floor:NLRS_23.21_FL_druklaag d=70 - gevlinderd en ingestrooid_gen:4472123:16 | 01c derde tussenverdieping | 23.21 vloeren - constructief, vrijdragende vloeren (Uniformat)
Floor:NLRS_23.21_FL_druklaag d=70 - gevlinderd en ingestrooid_gen:4472351:2 | 01c derde tussenverdieping | 23.21 vloeren - constructief, vrijdragende vloeren (Uniformat)
Floor:NLRS_23.21_FL_druklaag d=70 - gevlinderd en ingestrooid_gen:4472351:3 | 01c derde tussenverdieping | 23.21 vloeren - constructief, vrijdragende vloeren (Uniformat)
Floor:NLRS_23.21_FL_druklaag d=70 - gevlinderd en ingestrooid_gen:4472351:4 | 01c derde tussenverdieping | 23.21 vloeren - constructief, vrijdragende vloeren (Uniformat)
Floor:NLRS_23.21_FL_druklaag d=70 - gevlinderd en ingestrooid_gen:4472351:5 | 01c derde tussenverdieping | 23.21 vloeren - constructief, vrijdragende vloeren (Uniformat)
Floor:NLRS_23.21_FL_druklaag d=70 - gevlinderd en ingestrooid_gen:4472351:6 | 01c derde tussenverdieping | 23.21 vloeren - constructief, vrijdragende vloeren (Uniformat)
Floor:NLRS_23.21_FL_druklaag d=70 - gevlinderd en ingestrooid_gen:4472351:7 | 01c derde tussenverdieping | 23.21 vloeren - constructief, vrijdragende vloeren (Uniformat)
Floor:NLRS_23.21_FL_druklaag d=70 - gevlinderd en ingestrooid_gen:4472351:8 | 01c derde tussenverdieping | 23.21 vloeren - constructief, vrijdragende vloeren (Uniformat)
Floor:NLRS_23.21_FL_druklaag d=70 - gevlinderd en ingestrooid_gen:4472351:9 | 01c derde tussenverdieping | 23.21 vloeren - constructief, vrijdragende vloeren (Uniformat)
Floor:NLRS_23.21_FL_druklaag d=70 - gevlinderd en ingestrooid_gen:4472351:10 | 01c derde tussenverdieping | 23.21 vloeren - constructief, vrijdragende vloeren (Uniformat)
Floor:NLRS_23.21_FL_druklaag d=70 - gevlinderd en ingestrooid_gen:4472351:11 | 01c derde tussenverdieping | 23.21 vloeren - constructief, vrijdragende vloeren (Uniformat)
Floor:NLRS_23.21_FL_druklaag d=70 - gevlinderd en ingestrooid_gen:4472351:12 | 01c derde tussenverdieping | 23.21 vloeren - constructief, vrijdragende vloeren (Uniformat)
Floor:NLRS_23.21_FL_druklaag d=70 - gevlinderd en ingestrooid_gen:4472351:13 | 01c derde tussenverdieping | 23.21 vloeren - constructief, vrijdragende vloeren (Uniformat)
Floor:NLRS_23.21_FL_druklaag d=70 - gevlinderd en ingestrooid_gen:4472351:14 | 01c derde tussenverdieping | 23.21 vloeren - constructief, vrijdragende vloeren (Uniformat)
Floor:NLRS_23.21_FL_druklaag d=70 - gevlinderd en ingestrooid_gen:4472631:2 | 02b tweede tussenverdieping | 23.21 vloeren - constructief, vrijdragende vloeren (Uniformat)
Floor:NLRS_23.21_FL_druklaag d=70 - gevlinderd en ingestrooid_gen:4472631:3 | 02b tweede tussenverdieping | 23.21 vloeren - constructief, vrijdragende vloeren (Uniformat)
Floor:NLRS_23.21_FL_druklaag d=70 - gevlinderd en ingestrooid_gen:4472631:4 | 02b tweede tussenverdieping | 23.21 vloeren - constructief, vrijdragende vloeren (Uniformat)
Floor:NLRS_23.21_FL_druklaag d=70 - gevlinderd en ingestrooid_gen:4472631:5 | 02b tweede tussenverdieping | 23.21 vloeren - constructief, vrijdragende vloeren (Uniformat)
Floor:NLRS_23.21_FL_druklaag d=70 - gevlinderd en ingestrooid_gen:4472631:6 | 02b tweede tussenverdieping | 23.21 vloeren - constructief, vrijdragende vloeren (Uniformat)
Floor:NLRS_23.21_FL_druklaag d=70 - gevlinderd en ingestrooid_gen:4472631:7 | 02b tweede tussenverdieping | 23.21 vloeren - constructief, vrijdragende vloeren (Uniformat)
Floor:NLRS_23.21_FL_druklaag d=70 - gevlinderd en ingestrooid_gen:4472631:8 | 02b tweede tussenverdieping | 23.21 vloeren - constructief, vrijdragende vloeren (Uniformat)
Floor:NLRS_23.21_FL_druklaag d=70 - gevlinderd en ingestrooid_gen:4472631:9 | 02b tweede tussenverdieping | 23.21 vloeren - constructief, vrijdragende vloeren (Uniformat)
Floor:NLRS_23.21_FL_druklaag d=70 - gevlinderd en ingestrooid_gen:4472631:10 | 02b tweede tussenverdieping | 23.21 vloeren - constructief, vrijdragende vloeren (Uniformat)
Floor:NLRS_23.21_FL_druklaag d=70 - gevlinderd en ingestrooid_gen:4472631:11 | 02b tweede tussenverdieping | 23.21 vloeren - constructief, vrijdragende vloeren (Uniformat)
Floor:NLRS_23.21_FL_druklaag d=70 - gevlinderd en ingestrooid_gen:4472631:12 | 02b tweede tussenverdieping | 23.21 vloeren - constructief, vrijdragende vloeren (Uniformat)
Floor:NLRS_23.21_FL_kanaalplaat d=400_gen:4481380:2 | 04 vierde verdieping | 23.21 vloeren - constructief, vrijdragende vloeren (Uniformat)
Floor:NLRS_23.21_FL_druklaag d=80-var_gen:4483913:2 | 04 vierde verdieping | 23.21 vloeren - constructief, vrijdragende vloeren (Uniformat)
Floor:NLRS_23.21_FL_kanaalplaat d=400_gen:4487132:2 | 04 vierde verdieping | 23.21 vloeren - constructief, vrijdragende vloeren (Uniformat)
Floor:NLRS_23.21_FL_kanaalplaat d=400_gen:4525344:2 | 04 vierde verdieping | 23.21 vloeren - constructief, vrijdragende vloeren (Uniformat)
12 x Basic Wall:NLRS_21.21_WA_beton prefab d=250_gen:4538003 | 00 begane grond | 21.21 buitenwanden - constructief, massieve wanden (Uniformat)
5 x Basic Wall:NLRS_21.21_WA_beton prefab d=250_gen:4539723 | 03 derde verdieping | 21.21 buitenwanden - constructief, massieve wanden (Uniformat)
7 x Basic Wall:NLRS_21.21_WA_beton prefab d=250_gen:4541086 | 02 tweede verdieping | 21.21 buitenwanden - constructief, massieve wanden (Uniformat)
2 x Basic Wall:NLRS_21.21_WA_beton prefab d=250_gen:4560774 | 04 vierde verdieping | 21.21 buitenwanden - constructief, massieve wanden (Uniformat)
2 x Basic Wall:NLRS_21.21_WA_beton ihwg d=150_gen:4561322 | 04 vierde verdieping | 21.21 buitenwanden - constructief, massieve wanden (Uniformat) | Group: Model Group:NLRS_01.00_dakopbouw 01_gen:4907491
19 x Basic Wall:NLRS_22.21_WA_beton ihwg d=250_gen:1312528 | 03 derde verdieping | 22.21 binnenwanden - constructief, massieve wanden (Uniformat)
4 x Basic Wall:NLRS_22.21_WA_beton prefab d=200_gen:4564469 | 00 begane grond | 22.21 binnenwanden - constructief, massieve wanden (Uniformat)
3 x Basic Wall:NLRS_22.21_WA_beton prefab d=200_gen:4564477 | 01a eerste tussenverdieping | 22.21 binnenwanden - constructief, massieve wanden (Uniformat)
3 x Basic Wall:NLRS_22.21_WA_beton prefab d=200_gen:4564485 | 01c derde tussenverdieping | 22.21 binnenwanden - constructief, massieve wanden (Uniformat)
3 x Basic Wall:NLRS_22.21_WA_beton prefab d=200_gen:4564491 | 02b tweede tussenverdieping | 22.21 binnenwanden - constructief, massieve wanden (Uniformat)
Basic Wall:NLRS_21.21_WA_beton ihwg d=150_gen:4566548 | 04 vierde verdieping | 21.21 buitenwanden - constructief, massieve wanden (Uniformat) | Group: Model Group:NLRS_01.00_dakopbouw 02_gen:4909826
3 x Basic Wall:NLRS_21.21_WA_beton prefab d=270_gen:4571514 | 04 vierde verdieping | 21.21 buitenwanden - constructief, massieve wanden (Uniformat) | Group: Model Group:NLRS_01.00_verdieping 04_gen (members excluded):4585793
3 x Basic Wall:NLRS_21.21_WA_beton prefab d=250_gen:4572448 | 04 vierde verdieping | 21.21 buitenwanden - constructief, massieve wanden (Uniformat) | Group: Model Group:NLRS_01.00_verdieping 04_gen (members excluded):4585793
3 x Basic Wall:NLRS_21.21_WA_beton prefab d=250_gen:1307923 | 04 vierde verdieping | 21.21 buitenwanden - constructief, massieve wanden (Uniformat) | Group: Model Group:NLRS_01.00_verdieping 04_gen (members excluded):4585793
3 x Basic Wall:NLRS_21.21_WA_beton prefab d=250_gen:4573377 | 04 vierde verdieping | 21.21 buitenwanden - constructief, massieve wanden (Uniformat) | Group: Model Group:NLRS_01.00_verdieping 04_gen (members excluded):4585793
3 x Basic Wall:NLRS_21.21_WA_beton prefab d=250_gen:4573563 | 04 vierde verdieping | 21.21 buitenwanden - constructief, massieve wanden (Uniformat) | Group: Model Group:NLRS_01.00_verdieping 04_gen (members excluded):4585793
3 x Basic Wall:NLRS_21.21_WA_beton prefab d=270_gen:4573694 | 04 vierde verdieping | 21.21 buitenwanden - constructief, massieve wanden (Uniformat) | Group: Model Group:NLRS_01.00_verdieping 04_gen (members excluded):4585793
Basic Wall:NLRS_21.21_WA_beton ihwg d=410_gen:4574461 | 05 vijfde verdieping | 21.21 buitenwanden - constructief, massieve wanden (Uniformat) | Group: Model Group:NLRS_01.00_verdieping 04_gen (members excluded):4585793
Basic Wall:NLRS_22.21_WA_beton ihwg d=250_gen:4575757 | 04 vierde verdieping | 22.21 binnenwanden - constructief, massieve wanden (Uniformat) | Group: Model Group:NLRS_01.00_verdieping 04_gen (members excluded):4585793
Basic Wall:NLRS_22.21_WA_beton ihwg d=250_gen:4577208 | 04 vierde verdieping | 22.21 binnenwanden - constructief, massieve wanden (Uniformat) | Group: Model Group:NLRS_01.00_verdieping 04_gen (members excluded):4585793
Basic Wall:NLRS_22.21_WA_beton ihwg d=250_gen:4577402 | 04 vierde verdieping | 22.21 binnenwanden - constructief, massieve wanden (Uniformat) | Group: Model Group:NLRS_01.00_verdieping 04_gen (members excluded):4585793
3 x Basic Wall:NLRS_22.21_WA_beton prefab d=200_gen:4578065 | 04 vierde verdieping | 22.21 binnenwanden - constructief, massieve wanden (Uniformat) | Group: Model Group:NLRS_01.00_verdieping 04_gen (members excluded):4585793
2 x Basic Wall:NLRS_22.21_WA_beton prefab d=200_gen:1312531 | 04 vierde verdieping | 22.21 binnenwanden - constructief, massieve wanden (Uniformat) | Group: Model Group:NLRS_01.00_verdieping 04_gen (members excluded):4585793
3 x Basic Wall:NLRS_21.21_WA_beton prefab d=270_gen:4599059 | 06 zesde verdieping | 21.21 buitenwanden - constructief, massieve wanden (Uniformat) | Group: Model Group:NLRS_01.00_verdieping 06--10_gen:4600460
3 x Basic Wall:NLRS_21.21_WA_beton prefab d=250_gen:4599064 | 06 zesde verdieping | 21.21 buitenwanden - constructief, massieve wanden (Uniformat) | Group: Model Group:NLRS_01.00_verdieping 06--10_gen:4600460
3 x Basic Wall:NLRS_21.21_WA_beton prefab d=250_gen:1307923 | 06 zesde verdieping | 21.21 buitenwanden - constructief, massieve wanden (Uniformat) | Group: Model Group:NLRS_01.00_verdieping 06--10_gen:4600460
3 x Basic Wall:NLRS_21.21_WA_beton prefab d=250_gen:4599069 | 06 zesde verdieping | 21.21 buitenwanden - constructief, massieve wanden (Uniformat) | Group: Model Group:NLRS_01.00_verdieping 06--10_gen:4600460
3 x Basic Wall:NLRS_21.21_WA_beton prefab d=250_gen:4599074 | 06 zesde verdieping | 21.21 buitenwanden - constructief, massieve wanden (Uniformat) | Group: Model Group:NLRS_01.00_verdieping 06--10_gen:4600460
3 x Basic Wall:NLRS_21.21_WA_beton prefab d=270_gen:4599079 | 06 zesde verdieping | 21.21 buitenwanden - constructief, massieve wanden (Uniformat) | Group: Model Group:NLRS_01.00_verdieping 06--10_gen:4600460
3 x Basic Wall:NLRS_21.21_WA_beton prefab d=250_gen:4599084 | 07 zevende verdieping | 21.21 buitenwanden - constructief, massieve wanden (Uniformat) | Group: Model Group:NLRS_01.00_verdieping 06--10_gen:4600460
Basic Wall:NLRS_21.21_WA_beton prefab d=250_gen:1307923 | 07 zevende verdieping | 21.21 buitenwanden - constructief, massieve wanden (Uniformat) | Group: Model Group:NLRS_01.00_verdieping 06--10_gen:4600460
2 x Basic Wall:NLRS_22.21_WA_beton ihwg d=250_gen:4599125 | 06 zesde verdieping | 22.21 binnenwanden - constructief, massieve wanden (Uniformat) | Group: Model Group:NLRS_01.00_verdieping 06--10_gen:4600460
Basic Wall:NLRS_22.21_WA_beton ihwg d=250_gen:4599127 | 06 zesde verdieping | 22.21 binnenwanden - constructief, massieve wanden (Uniformat) | Group: Model Group:NLRS_01.00_verdieping 06--10_gen:4600460
Basic Wall:NLRS_22.21_WA_beton ihwg d=250_gen:4599135 | 06 zesde verdieping | 22.21 binnenwanden - constructief, massieve wanden (Uniformat) | Group: Model Group:NLRS_01.00_verdieping 06--10_gen:4600460
Basic Wall:NLRS_22.21_WA_beton ihwg d=250_gen:4599139 | 06 zesde verdieping | 22.21 binnenwanden - constructief, massieve wanden (Uniformat) | Group: Model Group:NLRS_01.00_verdieping 06--10_gen:4600460
Basic Wall:NLRS_22.21_WA_beton ihwg d=250_gen:4599141 | 06 zesde verdieping | 22.21 binnenwanden - constructief, massieve wanden (Uniformat) | Group: Model Group:NLRS_01.00_verdieping 06--10_gen:4600460
3 x Basic Wall:NLRS_22.21_WA_beton prefab d=200_gen:4599146 | 06 zesde verdieping | 22.21 binnenwanden - constructief, massieve wanden (Uniformat) | Group: Model Group:NLRS_01.00_verdieping 06--10_gen:4600460
2 x Basic Wall:NLRS_22.21_WA_beton prefab d=200_gen:1312531 | 06 zesde verdieping | 22.21 binnenwanden - constructief, massieve wanden (Uniformat) | Group: Model Group:NLRS_01.00_verdieping 06--10_gen:4600460
3 x Basic Wall:NLRS_21.21_WA_beton prefab d=270_gen:4600796 | 07 zevende verdieping | 21.21 buitenwanden - constructief, massieve wanden (Uniformat) | Group: Model Group:NLRS_01.00_verdieping 06--10_gen:4600975
3 x Basic Wall:NLRS_21.21_WA_beton prefab d=250_gen:4600801 | 07 zevende verdieping | 21.21 buitenwanden - constructief, massieve wanden (Uniformat) | Group: Model Group:NLRS_01.00_verdieping 06--10_gen:4600975
3 x Basic Wall:NLRS_21.21_WA_beton prefab d=250_gen:1307923 | 07 zevende verdieping | 21.21 buitenwanden - constructief, massieve wanden (Uniformat) | Group: Model Group:NLRS_01.00_verdieping 06--10_gen:4600975
3 x Basic Wall:NLRS_21.21_WA_beton prefab d=250_gen:4600806 | 07 zevende verdieping | 21.21 buitenwanden - constructief, massieve wanden (Uniformat) | Group: Model Group:NLRS_01.00_verdieping 06--10_gen:4600975
3 x Basic Wall:NLRS_21.21_WA_beton prefab d=250_gen:4600811 | 07 zevende verdieping | 21.21 buitenwanden - constructief, massieve wanden (Uniformat) | Group: Model Group:NLRS_01.00_verdieping 06--10_gen:4600975
3 x Basic Wall:NLRS_21.21_WA_beton prefab d=270_gen:4600816 | 07 zevende verdieping | 21.21 buitenwanden - constructief, massieve wanden (Uniformat) | Group: Model Group:NLRS_01.00_verdieping 06--10_gen:4600975
3 x Basic Wall:NLRS_21.21_WA_beton prefab d=250_gen:4600821 | 08 achtste verdieping | 21.21 buitenwanden - constructief, massieve wanden (Uniformat) | Group: Model Group:NLRS_01.00_verdieping 06--10_gen:4600975
Basic Wall:NLRS_21.21_WA_beton prefab d=250_gen:1307923 | 08 achtste verdieping | 21.21 buitenwanden - constructief, massieve wanden (Uniformat) | Group: Model Group:NLRS_01.00_verdieping 06--10_gen:4600975
2 x Basic Wall:NLRS_22.21_WA_beton ihwg d=250_gen:4600862 | 07 zevende verdieping | 22.21 binnenwanden - constructief, massieve wanden (Uniformat) | Group: Model Group:NLRS_01.00_verdieping 06--10_gen:4600975
Basic Wall:NLRS_22.21_WA_beton ihwg d=250_gen:4600864 | 07 zevende verdieping | 22.21 binnenwanden - constructief, massieve wanden (Uniformat) | Group: Model Group:NLRS_01.00_verdieping 06--10_gen:4600975
Basic Wall:NLRS_22.21_WA_beton ihwg d=250_gen:4600872 | 07 zevende verdieping | 22.21 binnenwanden - constructief, massieve wanden (Uniformat) | Group: Model Group:NLRS_01.00_verdieping 06--10_gen:4600975
Basic Wall:NLRS_22.21_WA_beton ihwg d=250_gen:4600876 | 07 zevende verdieping | 22.21 binnenwanden - constructief, massieve wanden (Uniformat) | Group: Model Group:NLRS_01.00_verdieping 06--10_gen:4600975
Basic Wall:NLRS_22.21_WA_beton ihwg d=250_gen:4600878 | 07 zevende verdieping | 22.21 binnenwanden - constructief, massieve wanden (Uniformat) | Group: Model Group:NLRS_01.00_verdieping 06--10_gen:4600975
3 x Basic Wall:NLRS_22.21_WA_beton prefab d=200_gen:4600883 | 07 zevende verdieping | 22.21 binnenwanden - constructief, massieve wanden (Uniformat) | Group: Model Group:NLRS_01.00_verdieping 06--10_gen:4600975
2 x Basic Wall:NLRS_22.21_WA_beton prefab d=200_gen:1312531 | 07 zevende verdieping | 22.21 binnenwanden - constructief, massieve wanden (Uniformat) | Group: Model Group:NLRS_01.00_verdieping 06--10_gen:4600975
3 x Basic Wall:NLRS_21.21_WA_beton prefab d=270_gen:4601864 | 08 achtste verdieping | 21.21 buitenwanden - constructief, massieve wanden (Uniformat) | Group: Model Group:NLRS_01.00_verdieping 06--10_gen:4602043
3 x Basic Wall:NLRS_21.21_WA_beton prefab d=250_gen:4601869 | 08 achtste verdieping | 21.21 buitenwanden - constructief, massieve wanden (Uniformat) | Group: Model Group:NLRS_01.00_verdieping 06--10_gen:4602043
3 x Basic Wall:NLRS_21.21_WA_beton prefab d=250_gen:1307923 | 08 achtste verdieping | 21.21 buitenwanden - constructief, massieve wanden (Uniformat) | Group: Model Group:NLRS_01.00_verdieping 06--10_gen:4602043
3 x Basic Wall:NLRS_21.21_WA_beton prefab d=250_gen:4601874 | 08 achtste verdieping | 21.21 buitenwanden - constructief, massieve wanden (Uniformat) | Group: Model Group:NLRS_01.00_verdieping 06--10_gen:4602043
3 x Basic Wall:NLRS_21.21_WA_beton prefab d=250_gen:4601879 | 08 achtste verdieping | 21.21 buitenwanden - constructief, massieve wanden (Uniformat) | Group: Model Group:NLRS_01.00_verdieping 06--10_gen:4602043
3 x Basic Wall:NLRS_21.21_WA_beton prefab d=270_gen:4601884 | 08 achtste verdieping | 21.21 buitenwanden - constructief, massieve wanden (Uniformat) | Group: Model Group:NLRS_01.00_verdieping 06--10_gen:4602043
3 x Basic Wall:NLRS_21.21_WA_beton prefab d=250_gen:4601889 | 09 negende verdieping | 21.21 buitenwanden - constructief, massieve wanden (Uniformat) | Group: Model Group:NLRS_01.00_verdieping 06--10_gen:4602043
Basic Wall:NLRS_21.21_WA_beton prefab d=250_gen:1307923 | 09 negende verdieping | 21.21 buitenwanden - constructief, massieve wanden (Uniformat) | Group: Model Group:NLRS_01.00_verdieping 06--10_gen:4602043
2 x Basic Wall:NLRS_22.21_WA_beton ihwg d=250_gen:4601930 | 08 achtste verdieping | 22.21 binnenwanden - constructief, massieve wanden (Uniformat) | Group: Model Group:NLRS_01.00_verdieping 06--10_gen:4602043
Basic Wall:NLRS_22.21_WA_beton ihwg d=250_gen:4601932 | 08 achtste verdieping | 22.21 binnenwanden - constructief, massieve wanden (Uniformat) | Group: Model Group:NLRS_01.00_verdieping 06--10_gen:4602043
Basic Wall:NLRS_22.21_WA_beton ihwg d=250_gen:4601940 | 08 achtste verdieping | 22.21 binnenwanden - constructief, massieve wanden (Uniformat) | Group: Model Group:NLRS_01.00_verdieping 06--10_gen:4602043
Basic Wall:NLRS_22.21_WA_beton ihwg d=250_gen:4601944 | 08 achtste verdieping | 22.21 binnenwanden - constructief, massieve wanden (Uniformat) | Group: Model Group:NLRS_01.00_verdieping 06--10_gen:4602043
Basic Wall:NLRS_22.21_WA_beton ihwg d=250_gen:4601946 | 08 achtste verdieping | 22.21 binnenwanden - constructief, massieve wanden (Uniformat) | Group: Model Group:NLRS_01.00_verdieping 06--10_gen:4602043
3 x Basic Wall:NLRS_22.21_WA_beton prefab d=200_gen:4601951 | 08 achtste verdieping | 22.21 binnenwanden - constructief, massieve wanden (Uniformat) | Group: Model Group:NLRS_01.00_verdieping 06--10_gen:4602043
2 x Basic Wall:NLRS_22.21_WA_beton prefab d=200_gen:1312531 | 08 achtste verdieping | 22.21 binnenwanden - constructief, massieve wanden (Uniformat) | Group: Model Group:NLRS_01.00_verdieping 06--10_gen:4602043
3 x Basic Wall:NLRS_21.21_WA_beton prefab d=270_gen:4602973 | 09 negende verdieping | 21.21 buitenwanden - constructief, massieve wanden (Uniformat) | Group: Model Group:NLRS_01.00_verdieping 06--10_gen:4603152
3 x Basic Wall:NLRS_21.21_WA_beton prefab d=250_gen:4602978 | 09 negende verdieping | 21.21 buitenwanden - constructief, massieve wanden (Uniformat) | Group: Model Group:NLRS_01.00_verdieping 06--10_gen:4603152
3 x Basic Wall:NLRS_21.21_WA_beton prefab d=250_gen:1307923 | 09 negende verdieping | 21.21 buitenwanden - constructief, massieve wanden (Uniformat) | Group: Model Group:NLRS_01.00_verdieping 06--10_gen:4603152
3 x Basic Wall:NLRS_21.21_WA_beton prefab d=250_gen:4602983 | 09 negende verdieping | 21.21 buitenwanden - constructief, massieve wanden (Uniformat) | Group: Model Group:NLRS_01.00_verdieping 06--10_gen:4603152
3 x Basic Wall:NLRS_21.21_WA_beton prefab d=250_gen:4602988 | 09 negende verdieping | 21.21 buitenwanden - constructief, massieve wanden (Uniformat) | Group: Model Group:NLRS_01.00_verdieping 06--10_gen:4603152
3 x Basic Wall:NLRS_21.21_WA_beton prefab d=270_gen:4602993 | 09 negende verdieping | 21.21 buitenwanden - constructief, massieve wanden (Uniformat) | Group: Model Group:NLRS_01.00_verdieping 06--10_gen:4603152
3 x Basic Wall:NLRS_21.21_WA_beton prefab d=250_gen:4602998 | 10 tiende verdieping | 21.21 buitenwanden - constructief, massieve wanden (Uniformat) | Group: Model Group:NLRS_01.00_verdieping 06--10_gen:4603152
Basic Wall:NLRS_21.21_WA_beton prefab d=250_gen:1307923 | 10 tiende verdieping | 21.21 buitenwanden - constructief, massieve wanden (Uniformat) | Group: Model Group:NLRS_01.00_verdieping 06--10_gen:4603152
2 x Basic Wall:NLRS_22.21_WA_beton ihwg d=250_gen:4603039 | 09 negende verdieping | 22.21 binnenwanden - constructief, massieve wanden (Uniformat) | Group: Model Group:NLRS_01.00_verdieping 06--10_gen:4603152
Basic Wall:NLRS_22.21_WA_beton ihwg d=250_gen:4603041 | 09 negende verdieping | 22.21 binnenwanden - constructief, massieve wanden (Uniformat) | Group: Model Group:NLRS_01.00_verdieping 06--10_gen:4603152
Basic Wall:NLRS_22.21_WA_beton ihwg d=250_gen:4603049 | 09 negende verdieping | 22.21 binnenwanden - constructief, massieve wanden (Uniformat) | Group: Model Group:NLRS_01.00_verdieping 06--10_gen:4603152
Basic Wall:NLRS_22.21_WA_beton ihwg d=250_gen:4603053 | 09 negende verdieping | 22.21 binnenwanden - constructief, massieve wanden (Uniformat) | Group: Model Group:NLRS_01.00_verdieping 06--10_gen:4603152
Basic Wall:NLRS_22.21_WA_beton ihwg d=250_gen:4603055 | 09 negende verdieping | 22.21 binnenwanden - constructief, massieve wanden (Uniformat) | Group: Model Group:NLRS_01.00_verdieping 06--10_gen:4603152
3 x Basic Wall:NLRS_22.21_WA_beton prefab d=200_gen:4603060 | 09 negende verdieping | 22.21 binnenwanden - constructief, massieve wanden (Uniformat) | Group: Model Group:NLRS_01.00_verdieping 06--10_gen:4603152
2 x Basic Wall:NLRS_22.21_WA_beton prefab d=200_gen:1312531 | 09 negende verdieping | 22.21 binnenwanden - constructief, massieve wanden (Uniformat) | Group: Model Group:NLRS_01.00_verdieping 06--10_gen:4603152
3 x Basic Wall:NLRS_21.21_WA_beton prefab d=270_gen:4604041 | 10 tiende verdieping | 21.21 buitenwanden - constructief, massieve wanden (Uniformat) | Group: Model Group:NLRS_01.00_verdieping 06--10_gen:4604220
3 x Basic Wall:NLRS_21.21_WA_beton prefab d=250_gen:4604046 | 10 tiende verdieping | 21.21 buitenwanden - constructief, massieve wanden (Uniformat) | Group: Model Group:NLRS_01.00_verdieping 06--10_gen:4604220
3 x Basic Wall:NLRS_21.21_WA_beton prefab d=250_gen:1307923 | 10 tiende verdieping | 21.21 buitenwanden - constructief, massieve wanden (Uniformat) | Group: Model Group:NLRS_01.00_verdieping 06--10_gen:4604220
3 x Basic Wall:NLRS_21.21_WA_beton prefab d=250_gen:4604051 | 10 tiende verdieping | 21.21 buitenwanden - constructief, massieve wanden (Uniformat) | Group: Model Group:NLRS_01.00_verdieping 06--10_gen:4604220
3 x Basic Wall:NLRS_21.21_WA_beton prefab d=250_gen:4604056 | 10 tiende verdieping | 21.21 buitenwanden - constructief, massieve wanden (Uniformat) | Group: Model Group:NLRS_01.00_verdieping 06--10_gen:4604220
3 x Basic Wall:NLRS_21.21_WA_beton prefab d=270_gen:4604061 | 10 tiende verdieping | 21.21 buitenwanden - constructief, massieve wanden (Uniformat) | Group: Model Group:NLRS_01.00_verdieping 06--10_gen:4604220
3 x Basic Wall:NLRS_21.21_WA_beton prefab d=250_gen:4604066 | 11 elfde verdieping | 21.21 buitenwanden - constructief, massieve wanden (Uniformat) | Group: Model Group:NLRS_01.00_verdieping 06--10_gen:4604220
Basic Wall:NLRS_21.21_WA_beton prefab d=250_gen:1307923 | 11 elfde verdieping | 21.21 buitenwanden - constructief, massieve wanden (Uniformat) | Group: Model Group:NLRS_01.00_verdieping 06--10_gen:4604220
2 x Basic Wall:NLRS_22.21_WA_beton ihwg d=250_gen:4604107 | 10 tiende verdieping | 22.21 binnenwanden - constructief, massieve wanden (Uniformat) | Group: Model Group:NLRS_01.00_verdieping 06--10_gen:4604220
Basic Wall:NLRS_22.21_WA_beton ihwg d=250_gen:4604109 | 10 tiende verdieping | 22.21 binnenwanden - constructief, massieve wanden (Uniformat) | Group: Model Group:NLRS_01.00_verdieping 06--10_gen:4604220
Basic Wall:NLRS_22.21_WA_beton ihwg d=250_gen:4604117 | 10 tiende verdieping | 22.21 binnenwanden - constructief, massieve wanden (Uniformat) | Group: Model Group:NLRS_01.00_verdieping 06--10_gen:4604220
Basic Wall:NLRS_22.21_WA_beton ihwg d=250_gen:4604121 | 10 tiende verdieping | 22.21 binnenwanden - constructief, massieve wanden (Uniformat) | Group: Model Group:NLRS_01.00_verdieping 06--10_gen:4604220
Basic Wall:NLRS_22.21_WA_beton ihwg d=250_gen:4604123 | 10 tiende verdieping | 22.21 binnenwanden - constructief, massieve wanden (Uniformat) | Group: Model Group:NLRS_01.00_verdieping 06--10_gen:4604220
3 x Basic Wall:NLRS_22.21_WA_beton prefab d=200_gen:4604128 | 10 tiende verdieping | 22.21 binnenwanden - constructief, massieve wanden (Uniformat) | Group: Model Group:NLRS_01.00_verdieping 06--10_gen:4604220
2 x Basic Wall:NLRS_22.21_WA_beton prefab d=200_gen:1312531 | 10 tiende verdieping | 22.21 binnenwanden - constructief, massieve wanden (Uniformat) | Group: Model Group:NLRS_01.00_verdieping 06--10_gen:4604220
4 x  | 11 elfde verdieping | 23.21 vloeren - constructief, vrijdragende vloeren (Uniformat) | Group: Model Group:NLRS_01.00_verdieping 11--17_gen:4626135
56 x  | 11 elfde verdieping
Floor:NLRS_23.21_FL_beton ihwg d=250_gen:4604141:2 | 11 elfde verdieping | 23.21 vloeren - constructief, vrijdragende vloeren (Uniformat) | Group: Model Group:NLRS_01.00_verdieping 11--17_gen:4626135
3 x Basic Wall:NLRS_21.21_WA_beton prefab d=270_gen:4608049 | 12 twaalfde verdieping | 21.21 buitenwanden - constructief, massieve wanden (Uniformat) | Group: Model Group:NLRS_01.00_verdieping 11--17_gen:4609129
3 x Basic Wall:NLRS_21.21_WA_beton prefab d=250_gen:4608054 | 12 twaalfde verdieping | 21.21 buitenwanden - constructief, massieve wanden (Uniformat) | Group: Model Group:NLRS_01.00_verdieping 11--17_gen:4609129
4 x Basic Wall:NLRS_21.21_WA_beton prefab d=250_gen:1307923 | 12 twaalfde verdieping | 21.21 buitenwanden - constructief, massieve wanden (Uniformat) | Group: Model Group:NLRS_01.00_verdieping 11--17_gen:4609129
3 x Basic Wall:NLRS_21.21_WA_beton prefab d=250_gen:4608059 | 12 twaalfde verdieping | 21.21 buitenwanden - constructief, massieve wanden (Uniformat) | Group: Model Group:NLRS_01.00_verdieping 11--17_gen:4609129
3 x Basic Wall:NLRS_21.21_WA_beton prefab d=250_gen:4608064 | 12 twaalfde verdieping | 21.21 buitenwanden - constructief, massieve wanden (Uniformat) | Group: Model Group:NLRS_01.00_verdieping 11--17_gen:4609129
3 x Basic Wall:NLRS_21.21_WA_beton prefab d=270_gen:4608069 | 12 twaalfde verdieping | 21.21 buitenwanden - constructief, massieve wanden (Uniformat) | Group: Model Group:NLRS_01.00_verdieping 11--17_gen:4609129
3 x Basic Wall:NLRS_21.21_WA_beton prefab d=250_gen:4608074 | 12 twaalfde verdieping | 21.21 buitenwanden - constructief, massieve wanden (Uniformat) | Group: Model Group:NLRS_01.00_verdieping 11--17_gen:4609129
2 x Basic Wall:NLRS_22.21_WA_beton ihwg d=250_gen:4608115 | 12 twaalfde verdieping | 22.21 binnenwanden - constructief, massieve wanden (Uniformat) | Group: Model Group:NLRS_01.00_verdieping 11--17_gen:4609129
Basic Wall:NLRS_22.21_WA_beton ihwg d=250_gen:4608117 | 12 twaalfde verdieping | 22.21 binnenwanden - constructief, massieve wanden (Uniformat) | Group: Model Group:NLRS_01.00_verdieping 11--17_gen:4609129
Basic Wall:NLRS_22.21_WA_beton ihwg d=250_gen:4608125 | 12 twaalfde verdieping | 22.21 binnenwanden - constructief, massieve wanden (Uniformat) | Group: Model Group:NLRS_01.00_verdieping 11--17_gen:4609129
Basic Wall:NLRS_22.21_WA_beton ihwg d=250_gen:4608127 | 12 twaalfde verdieping | 22.21 binnenwanden - constructief, massieve wanden (Uniformat) | Group: Model Group:NLRS_01.00_verdieping 11--17_gen:4609129
3 x Basic Wall:NLRS_22.21_WA_beton prefab d=200_gen:4608130 | 12 twaalfde verdieping | 22.21 binnenwanden - constructief, massieve wanden (Uniformat) | Group: Model Group:NLRS_01.00_verdieping 11--17_gen:4609129
2 x Basic Wall:NLRS_22.21_WA_beton prefab d=200_gen:1312531 | 12 twaalfde verdieping | 22.21 binnenwanden - constructief, massieve wanden (Uniformat) | Group: Model Group:NLRS_01.00_verdieping 11--17_gen:4609129
3 x Basic Wall:NLRS_21.21_WA_beton prefab d=270_gen:4609419 | 13 dertiende verdieping | 21.21 buitenwanden - constructief, massieve wanden (Uniformat) | Group: Model Group:NLRS_01.00_verdieping 11--17_gen:4609592
3 x Basic Wall:NLRS_21.21_WA_beton prefab d=250_gen:4609424 | 13 dertiende verdieping | 21.21 buitenwanden - constructief, massieve wanden (Uniformat) | Group: Model Group:NLRS_01.00_verdieping 11--17_gen:4609592
4 x Basic Wall:NLRS_21.21_WA_beton prefab d=250_gen:1307923 | 13 dertiende verdieping | 21.21 buitenwanden - constructief, massieve wanden (Uniformat) | Group: Model Group:NLRS_01.00_verdieping 11--17_gen:4609592
3 x Basic Wall:NLRS_21.21_WA_beton prefab d=250_gen:4609429 | 13 dertiende verdieping | 21.21 buitenwanden - constructief, massieve wanden (Uniformat) | Group: Model Group:NLRS_01.00_verdieping 11--17_gen:4609592
3 x Basic Wall:NLRS_21.21_WA_beton prefab d=250_gen:4609434 | 13 dertiende verdieping | 21.21 buitenwanden - constructief, massieve wanden (Uniformat) | Group: Model Group:NLRS_01.00_verdieping 11--17_gen:4609592
3 x Basic Wall:NLRS_21.21_WA_beton prefab d=270_gen:4609439 | 13 dertiende verdieping | 21.21 buitenwanden - constructief, massieve wanden (Uniformat) | Group: Model Group:NLRS_01.00_verdieping 11--17_gen:4609592
3 x Basic Wall:NLRS_21.21_WA_beton prefab d=250_gen:4609444 | 13 dertiende verdieping | 21.21 buitenwanden - constructief, massieve wanden (Uniformat) | Group: Model Group:NLRS_01.00_verdieping 11--17_gen:4609592
2 x Basic Wall:NLRS_22.21_WA_beton ihwg d=250_gen:4609485 | 13 dertiende verdieping | 22.21 binnenwanden - constructief, massieve wanden (Uniformat) | Group: Model Group:NLRS_01.00_verdieping 11--17_gen:4609592
Basic Wall:NLRS_22.21_WA_beton ihwg d=250_gen:4609487 | 13 dertiende verdieping | 22.21 binnenwanden - constructief, massieve wanden (Uniformat) | Group: Model Group:NLRS_01.00_verdieping 11--17_gen:4609592
Basic Wall:NLRS_22.21_WA_beton ihwg d=250_gen:4609495 | 13 dertiende verdieping | 22.21 binnenwanden - constructief, massieve wanden (Uniformat) | Group: Model Group:NLRS_01.00_verdieping 11--17_gen:4609592
Basic Wall:NLRS_22.21_WA_beton ihwg d=250_gen:4609497 | 13 dertiende verdieping | 22.21 binnenwanden - constructief, massieve wanden (Uniformat) | Group: Model Group:NLRS_01.00_verdieping 11--17_gen:4609592
3 x Basic Wall:NLRS_22.21_WA_beton prefab d=200_gen:4609500 | 13 dertiende verdieping | 22.21 binnenwanden - constructief, massieve wanden (Uniformat) | Group: Model Group:NLRS_01.00_verdieping 11--17_gen:4609592
2 x Basic Wall:NLRS_22.21_WA_beton prefab d=200_gen:1312531 | 13 dertiende verdieping | 22.21 binnenwanden - constructief, massieve wanden (Uniformat) | Group: Model Group:NLRS_01.00_verdieping 11--17_gen:4609592
3 x Basic Wall:NLRS_21.21_WA_beton prefab d=270_gen:4610445 | 14 veertiende verdieping | 21.21 buitenwanden - constructief, massieve wanden (Uniformat) | Group: Model Group:NLRS_01.00_verdieping 11--17_gen:4610618
3 x Basic Wall:NLRS_21.21_WA_beton prefab d=250_gen:4610450 | 14 veertiende verdieping | 21.21 buitenwanden - constructief, massieve wanden (Uniformat) | Group: Model Group:NLRS_01.00_verdieping 11--17_gen:4610618
4 x Basic Wall:NLRS_21.21_WA_beton prefab d=250_gen:1307923 | 14 veertiende verdieping | 21.21 buitenwanden - constructief, massieve wanden (Uniformat) | Group: Model Group:NLRS_01.00_verdieping 11--17_gen:4610618
3 x Basic Wall:NLRS_21.21_WA_beton prefab d=250_gen:4610455 | 14 veertiende verdieping | 21.21 buitenwanden - constructief, massieve wanden (Uniformat) | Group: Model Group:NLRS_01.00_verdieping 11--17_gen:4610618
3 x Basic Wall:NLRS_21.21_WA_beton prefab d=250_gen:4610460 | 14 veertiende verdieping | 21.21 buitenwanden - constructief, massieve wanden (Uniformat) | Group: Model Group:NLRS_01.00_verdieping 11--17_gen:4610618
3 x Basic Wall:NLRS_21.21_WA_beton prefab d=270_gen:4610465 | 14 veertiende verdieping | 21.21 buitenwanden - constructief, massieve wanden (Uniformat) | Group: Model Group:NLRS_01.00_verdieping 11--17_gen:4610618
3 x Basic Wall:NLRS_21.21_WA_beton prefab d=250_gen:4610470 | 14 veertiende verdieping | 21.21 buitenwanden - constructief, massieve wanden (Uniformat) | Group: Model Group:NLRS_01.00_verdieping 11--17_gen:4610618
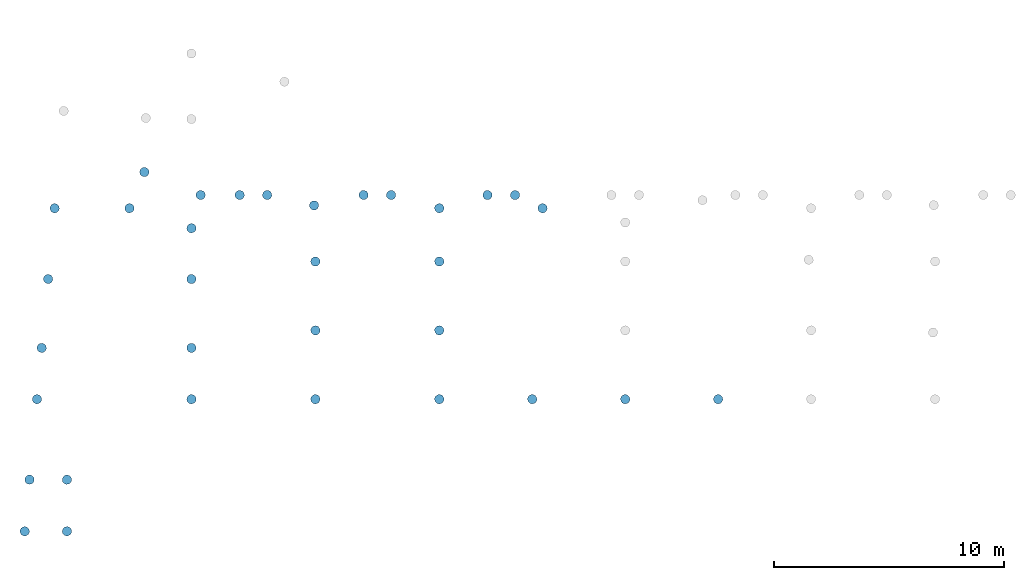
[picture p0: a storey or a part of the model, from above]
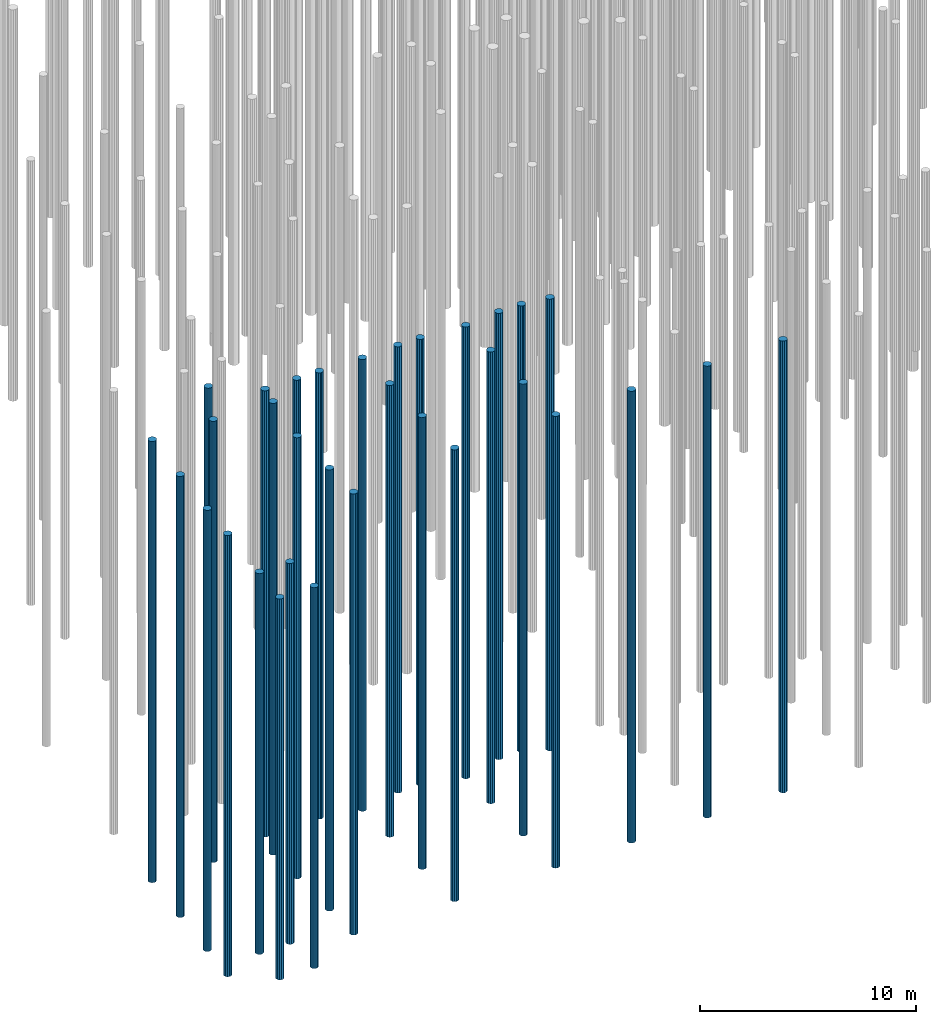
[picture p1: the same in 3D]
Properties of the parts of a building model (IFC2X3), part 5 of 11

# IfcOpeningElement: Opening (5029)
Name | In | Classification
2 x Basic Wall:NLRS_22.21_WA_beton ihwg d=250_gen:4610511 | 14 veertiende verdieping | 22.21 binnenwanden - constructief, massieve wanden (Uniformat) | Group: Model Group:NLRS_01.00_verdieping 11--17_gen:4610618
Basic Wall:NLRS_22.21_WA_beton ihwg d=250_gen:4610513 | 14 veertiende verdieping | 22.21 binnenwanden - constructief, massieve wanden (Uniformat) | Group: Model Group:NLRS_01.00_verdieping 11--17_gen:4610618
Basic Wall:NLRS_22.21_WA_beton ihwg d=250_gen:4610521 | 14 veertiende verdieping | 22.21 binnenwanden - constructief, massieve wanden (Uniformat) | Group: Model Group:NLRS_01.00_verdieping 11--17_gen:4610618
Basic Wall:NLRS_22.21_WA_beton ihwg d=250_gen:4610523 | 14 veertiende verdieping | 22.21 binnenwanden - constructief, massieve wanden (Uniformat) | Group: Model Group:NLRS_01.00_verdieping 11--17_gen:4610618
3 x Basic Wall:NLRS_22.21_WA_beton prefab d=200_gen:4610526 | 14 veertiende verdieping | 22.21 binnenwanden - constructief, massieve wanden (Uniformat) | Group: Model Group:NLRS_01.00_verdieping 11--17_gen:4610618
2 x Basic Wall:NLRS_22.21_WA_beton prefab d=200_gen:1312531 | 14 veertiende verdieping | 22.21 binnenwanden - constructief, massieve wanden (Uniformat) | Group: Model Group:NLRS_01.00_verdieping 11--17_gen:4610618
3 x Basic Wall:NLRS_21.21_WA_beton prefab d=270_gen:4611469 | 15 vijftiende verdieping | 21.21 buitenwanden - constructief, massieve wanden (Uniformat) | Group: Model Group:NLRS_01.00_verdieping 11--17_gen:4611642
3 x Basic Wall:NLRS_21.21_WA_beton prefab d=250_gen:4611474 | 15 vijftiende verdieping | 21.21 buitenwanden - constructief, massieve wanden (Uniformat) | Group: Model Group:NLRS_01.00_verdieping 11--17_gen:4611642
4 x Basic Wall:NLRS_21.21_WA_beton prefab d=250_gen:1307923 | 15 vijftiende verdieping | 21.21 buitenwanden - constructief, massieve wanden (Uniformat) | Group: Model Group:NLRS_01.00_verdieping 11--17_gen:4611642
3 x Basic Wall:NLRS_21.21_WA_beton prefab d=250_gen:4611479 | 15 vijftiende verdieping | 21.21 buitenwanden - constructief, massieve wanden (Uniformat) | Group: Model Group:NLRS_01.00_verdieping 11--17_gen:4611642
3 x Basic Wall:NLRS_21.21_WA_beton prefab d=250_gen:4611484 | 15 vijftiende verdieping | 21.21 buitenwanden - constructief, massieve wanden (Uniformat) | Group: Model Group:NLRS_01.00_verdieping 11--17_gen:4611642
3 x Basic Wall:NLRS_21.21_WA_beton prefab d=270_gen:4611489 | 15 vijftiende verdieping | 21.21 buitenwanden - constructief, massieve wanden (Uniformat) | Group: Model Group:NLRS_01.00_verdieping 11--17_gen:4611642
3 x Basic Wall:NLRS_21.21_WA_beton prefab d=250_gen:4611494 | 15 vijftiende verdieping | 21.21 buitenwanden - constructief, massieve wanden (Uniformat) | Group: Model Group:NLRS_01.00_verdieping 11--17_gen:4611642
2 x Basic Wall:NLRS_22.21_WA_beton ihwg d=250_gen:4611535 | 15 vijftiende verdieping | 22.21 binnenwanden - constructief, massieve wanden (Uniformat) | Group: Model Group:NLRS_01.00_verdieping 11--17_gen:4611642
Basic Wall:NLRS_22.21_WA_beton ihwg d=250_gen:4611537 | 15 vijftiende verdieping | 22.21 binnenwanden - constructief, massieve wanden (Uniformat) | Group: Model Group:NLRS_01.00_verdieping 11--17_gen:4611642
Basic Wall:NLRS_22.21_WA_beton ihwg d=250_gen:4611545 | 15 vijftiende verdieping | 22.21 binnenwanden - constructief, massieve wanden (Uniformat) | Group: Model Group:NLRS_01.00_verdieping 11--17_gen:4611642
Basic Wall:NLRS_22.21_WA_beton ihwg d=250_gen:4611547 | 15 vijftiende verdieping | 22.21 binnenwanden - constructief, massieve wanden (Uniformat) | Group: Model Group:NLRS_01.00_verdieping 11--17_gen:4611642
3 x Basic Wall:NLRS_22.21_WA_beton prefab d=200_gen:4611550 | 15 vijftiende verdieping | 22.21 binnenwanden - constructief, massieve wanden (Uniformat) | Group: Model Group:NLRS_01.00_verdieping 11--17_gen:4611642
2 x Basic Wall:NLRS_22.21_WA_beton prefab d=200_gen:1312531 | 15 vijftiende verdieping | 22.21 binnenwanden - constructief, massieve wanden (Uniformat) | Group: Model Group:NLRS_01.00_verdieping 11--17_gen:4611642
3 x Basic Wall:NLRS_21.21_WA_beton prefab d=270_gen:4612495 | 16 zestiende verdieping | 21.21 buitenwanden - constructief, massieve wanden (Uniformat) | Group: Model Group:NLRS_01.00_verdieping 11--17_gen:4612668
3 x Basic Wall:NLRS_21.21_WA_beton prefab d=250_gen:4612500 | 16 zestiende verdieping | 21.21 buitenwanden - constructief, massieve wanden (Uniformat) | Group: Model Group:NLRS_01.00_verdieping 11--17_gen:4612668
4 x Basic Wall:NLRS_21.21_WA_beton prefab d=250_gen:1307923 | 16 zestiende verdieping | 21.21 buitenwanden - constructief, massieve wanden (Uniformat) | Group: Model Group:NLRS_01.00_verdieping 11--17_gen:4612668
3 x Basic Wall:NLRS_21.21_WA_beton prefab d=250_gen:4612505 | 16 zestiende verdieping | 21.21 buitenwanden - constructief, massieve wanden (Uniformat) | Group: Model Group:NLRS_01.00_verdieping 11--17_gen:4612668
3 x Basic Wall:NLRS_21.21_WA_beton prefab d=250_gen:4612510 | 16 zestiende verdieping | 21.21 buitenwanden - constructief, massieve wanden (Uniformat) | Group: Model Group:NLRS_01.00_verdieping 11--17_gen:4612668
3 x Basic Wall:NLRS_21.21_WA_beton prefab d=270_gen:4612515 | 16 zestiende verdieping | 21.21 buitenwanden - constructief, massieve wanden (Uniformat) | Group: Model Group:NLRS_01.00_verdieping 11--17_gen:4612668
3 x Basic Wall:NLRS_21.21_WA_beton prefab d=250_gen:4612520 | 16 zestiende verdieping | 21.21 buitenwanden - constructief, massieve wanden (Uniformat) | Group: Model Group:NLRS_01.00_verdieping 11--17_gen:4612668
2 x Basic Wall:NLRS_22.21_WA_beton ihwg d=250_gen:4612561 | 16 zestiende verdieping | 22.21 binnenwanden - constructief, massieve wanden (Uniformat) | Group: Model Group:NLRS_01.00_verdieping 11--17_gen:4612668
Basic Wall:NLRS_22.21_WA_beton ihwg d=250_gen:4612563 | 16 zestiende verdieping | 22.21 binnenwanden - constructief, massieve wanden (Uniformat) | Group: Model Group:NLRS_01.00_verdieping 11--17_gen:4612668
Basic Wall:NLRS_22.21_WA_beton ihwg d=250_gen:4612571 | 16 zestiende verdieping | 22.21 binnenwanden - constructief, massieve wanden (Uniformat) | Group: Model Group:NLRS_01.00_verdieping 11--17_gen:4612668
Basic Wall:NLRS_22.21_WA_beton ihwg d=250_gen:4612573 | 16 zestiende verdieping | 22.21 binnenwanden - constructief, massieve wanden (Uniformat) | Group: Model Group:NLRS_01.00_verdieping 11--17_gen:4612668
3 x Basic Wall:NLRS_22.21_WA_beton prefab d=200_gen:4612576 | 16 zestiende verdieping | 22.21 binnenwanden - constructief, massieve wanden (Uniformat) | Group: Model Group:NLRS_01.00_verdieping 11--17_gen:4612668
2 x Basic Wall:NLRS_22.21_WA_beton prefab d=200_gen:1312531 | 16 zestiende verdieping | 22.21 binnenwanden - constructief, massieve wanden (Uniformat) | Group: Model Group:NLRS_01.00_verdieping 11--17_gen:4612668
3 x Basic Wall:NLRS_21.21_WA_beton prefab d=270_gen:4613519 | 17 zeventiende verdieping | 21.21 buitenwanden - constructief, massieve wanden (Uniformat) | Group: Model Group:NLRS_01.00_verdieping 11--17_gen:4613692
3 x Basic Wall:NLRS_21.21_WA_beton prefab d=250_gen:4613524 | 17 zeventiende verdieping | 21.21 buitenwanden - constructief, massieve wanden (Uniformat) | Group: Model Group:NLRS_01.00_verdieping 11--17_gen:4613692
4 x Basic Wall:NLRS_21.21_WA_beton prefab d=250_gen:1307923 | 17 zeventiende verdieping | 21.21 buitenwanden - constructief, massieve wanden (Uniformat) | Group: Model Group:NLRS_01.00_verdieping 11--17_gen:4613692
3 x Basic Wall:NLRS_21.21_WA_beton prefab d=250_gen:4613529 | 17 zeventiende verdieping | 21.21 buitenwanden - constructief, massieve wanden (Uniformat) | Group: Model Group:NLRS_01.00_verdieping 11--17_gen:4613692
3 x Basic Wall:NLRS_21.21_WA_beton prefab d=250_gen:4613534 | 17 zeventiende verdieping | 21.21 buitenwanden - constructief, massieve wanden (Uniformat) | Group: Model Group:NLRS_01.00_verdieping 11--17_gen:4613692
3 x Basic Wall:NLRS_21.21_WA_beton prefab d=270_gen:4613539 | 17 zeventiende verdieping | 21.21 buitenwanden - constructief, massieve wanden (Uniformat) | Group: Model Group:NLRS_01.00_verdieping 11--17_gen:4613692
3 x Basic Wall:NLRS_21.21_WA_beton prefab d=250_gen:4613544 | 17 zeventiende verdieping | 21.21 buitenwanden - constructief, massieve wanden (Uniformat) | Group: Model Group:NLRS_01.00_verdieping 11--17_gen:4613692
2 x Basic Wall:NLRS_22.21_WA_beton ihwg d=250_gen:4613585 | 17 zeventiende verdieping | 22.21 binnenwanden - constructief, massieve wanden (Uniformat) | Group: Model Group:NLRS_01.00_verdieping 11--17_gen:4613692
Basic Wall:NLRS_22.21_WA_beton ihwg d=250_gen:4613587 | 17 zeventiende verdieping | 22.21 binnenwanden - constructief, massieve wanden (Uniformat) | Group: Model Group:NLRS_01.00_verdieping 11--17_gen:4613692
Basic Wall:NLRS_22.21_WA_beton ihwg d=250_gen:4613595 | 17 zeventiende verdieping | 22.21 binnenwanden - constructief, massieve wanden (Uniformat) | Group: Model Group:NLRS_01.00_verdieping 11--17_gen:4613692
Basic Wall:NLRS_22.21_WA_beton ihwg d=250_gen:4613597 | 17 zeventiende verdieping | 22.21 binnenwanden - constructief, massieve wanden (Uniformat) | Group: Model Group:NLRS_01.00_verdieping 11--17_gen:4613692
3 x Basic Wall:NLRS_22.21_WA_beton prefab d=200_gen:4613600 | 17 zeventiende verdieping | 22.21 binnenwanden - constructief, massieve wanden (Uniformat) | Group: Model Group:NLRS_01.00_verdieping 11--17_gen:4613692
2 x Basic Wall:NLRS_22.21_WA_beton prefab d=200_gen:1312531 | 17 zeventiende verdieping | 22.21 binnenwanden - constructief, massieve wanden (Uniformat) | Group: Model Group:NLRS_01.00_verdieping 11--17_gen:4613692
4 x  | 18 achttiende verdieping | 23.21 vloeren - constructief, vrijdragende vloeren (Uniformat) | Group: Model Group:NLRS_01.00_verdieping 18-19_gen:4617185
58 x  | 18 achttiende verdieping
Floor:NLRS_23.21_FL_beton ihwg d=250_gen:4613613:2 | 18 achttiende verdieping | 23.21 vloeren - constructief, vrijdragende vloeren (Uniformat) | Group: Model Group:NLRS_01.00_verdieping 18-19_gen:4617185
3 x Basic Wall:NLRS_21.21_WA_beton prefab d=270_gen:4616009 | 18 achttiende verdieping | 21.21 buitenwanden - constructief, massieve wanden (Uniformat) | Group: Model Group:NLRS_01.00_verdieping 18-19_gen:4617185
3 x Basic Wall:NLRS_21.21_WA_beton prefab d=250_gen:4616014 | 18 achttiende verdieping | 21.21 buitenwanden - constructief, massieve wanden (Uniformat) | Group: Model Group:NLRS_01.00_verdieping 18-19_gen:4617185
4 x Basic Wall:NLRS_21.21_WA_beton prefab d=250_gen:1307923 | 18 achttiende verdieping | 21.21 buitenwanden - constructief, massieve wanden (Uniformat) | Group: Model Group:NLRS_01.00_verdieping 18-19_gen:4617185
3 x Basic Wall:NLRS_21.21_WA_beton prefab d=250_gen:4616019 | 18 achttiende verdieping | 21.21 buitenwanden - constructief, massieve wanden (Uniformat) | Group: Model Group:NLRS_01.00_verdieping 18-19_gen:4617185
3 x Basic Wall:NLRS_21.21_WA_beton prefab d=250_gen:4616024 | 18 achttiende verdieping | 21.21 buitenwanden - constructief, massieve wanden (Uniformat) | Group: Model Group:NLRS_01.00_verdieping 18-19_gen:4617185
3 x Basic Wall:NLRS_21.21_WA_beton prefab d=270_gen:4616029 | 18 achttiende verdieping | 21.21 buitenwanden - constructief, massieve wanden (Uniformat) | Group: Model Group:NLRS_01.00_verdieping 18-19_gen:4617185
3 x Basic Wall:NLRS_21.21_WA_beton prefab d=250_gen:4616034 | 18 achttiende verdieping | 21.21 buitenwanden - constructief, massieve wanden (Uniformat) | Group: Model Group:NLRS_01.00_verdieping 18-19_gen:4617185
2 x Basic Wall:NLRS_22.21_WA_beton ihwg d=250_gen:4616075 | 18 achttiende verdieping | 22.21 binnenwanden - constructief, massieve wanden (Uniformat) | Group: Model Group:NLRS_01.00_verdieping 18-19_gen:4617185
Basic Wall:NLRS_22.21_WA_beton ihwg d=250_gen:4616077 | 18 achttiende verdieping | 22.21 binnenwanden - constructief, massieve wanden (Uniformat) | Group: Model Group:NLRS_01.00_verdieping 18-19_gen:4617185
Basic Wall:NLRS_22.21_WA_beton ihwg d=250_gen:4616085 | 18 achttiende verdieping | 22.21 binnenwanden - constructief, massieve wanden (Uniformat) | Group: Model Group:NLRS_01.00_verdieping 18-19_gen:4617185
Basic Wall:NLRS_22.21_WA_beton ihwg d=250_gen:4616087 | 18 achttiende verdieping | 22.21 binnenwanden - constructief, massieve wanden (Uniformat) | Group: Model Group:NLRS_01.00_verdieping 18-19_gen:4617185
3 x Basic Wall:NLRS_22.21_WA_beton prefab d=200_gen:4616090 | 18 achttiende verdieping | 22.21 binnenwanden - constructief, massieve wanden (Uniformat) | Group: Model Group:NLRS_01.00_verdieping 18-19_gen:4617185
2 x Basic Wall:NLRS_22.21_WA_beton prefab d=200_gen:1312531 | 18 achttiende verdieping | 22.21 binnenwanden - constructief, massieve wanden (Uniformat) | Group: Model Group:NLRS_01.00_verdieping 18-19_gen:4617185
3 x Basic Wall:NLRS_21.21_WA_beton prefab d=270_gen:4617496 | 19 negentiende verdieping | 21.21 buitenwanden - constructief, massieve wanden (Uniformat) | Group: Model Group:NLRS_01.00_verdieping 18-19_gen:4617669
3 x Basic Wall:NLRS_21.21_WA_beton prefab d=250_gen:4617501 | 19 negentiende verdieping | 21.21 buitenwanden - constructief, massieve wanden (Uniformat) | Group: Model Group:NLRS_01.00_verdieping 18-19_gen:4617669
4 x Basic Wall:NLRS_21.21_WA_beton prefab d=250_gen:1307923 | 19 negentiende verdieping | 21.21 buitenwanden - constructief, massieve wanden (Uniformat) | Group: Model Group:NLRS_01.00_verdieping 18-19_gen:4617669
3 x Basic Wall:NLRS_21.21_WA_beton prefab d=250_gen:4617506 | 19 negentiende verdieping | 21.21 buitenwanden - constructief, massieve wanden (Uniformat) | Group: Model Group:NLRS_01.00_verdieping 18-19_gen:4617669
3 x Basic Wall:NLRS_21.21_WA_beton prefab d=250_gen:4617511 | 19 negentiende verdieping | 21.21 buitenwanden - constructief, massieve wanden (Uniformat) | Group: Model Group:NLRS_01.00_verdieping 18-19_gen:4617669
3 x Basic Wall:NLRS_21.21_WA_beton prefab d=270_gen:4617516 | 19 negentiende verdieping | 21.21 buitenwanden - constructief, massieve wanden (Uniformat) | Group: Model Group:NLRS_01.00_verdieping 18-19_gen:4617669
3 x Basic Wall:NLRS_21.21_WA_beton prefab d=250_gen:4617521 | 19 negentiende verdieping | 21.21 buitenwanden - constructief, massieve wanden (Uniformat) | Group: Model Group:NLRS_01.00_verdieping 18-19_gen:4617669
2 x Basic Wall:NLRS_22.21_WA_beton ihwg d=250_gen:4617562 | 19 negentiende verdieping | 22.21 binnenwanden - constructief, massieve wanden (Uniformat) | Group: Model Group:NLRS_01.00_verdieping 18-19_gen:4617669
Basic Wall:NLRS_22.21_WA_beton ihwg d=250_gen:4617564 | 19 negentiende verdieping | 22.21 binnenwanden - constructief, massieve wanden (Uniformat) | Group: Model Group:NLRS_01.00_verdieping 18-19_gen:4617669
Basic Wall:NLRS_22.21_WA_beton ihwg d=250_gen:4617572 | 19 negentiende verdieping | 22.21 binnenwanden - constructief, massieve wanden (Uniformat) | Group: Model Group:NLRS_01.00_verdieping 18-19_gen:4617669
Basic Wall:NLRS_22.21_WA_beton ihwg d=250_gen:4617574 | 19 negentiende verdieping | 22.21 binnenwanden - constructief, massieve wanden (Uniformat) | Group: Model Group:NLRS_01.00_verdieping 18-19_gen:4617669
3 x Basic Wall:NLRS_22.21_WA_beton prefab d=200_gen:4617577 | 19 negentiende verdieping | 22.21 binnenwanden - constructief, massieve wanden (Uniformat) | Group: Model Group:NLRS_01.00_verdieping 18-19_gen:4617669
2 x Basic Wall:NLRS_22.21_WA_beton prefab d=200_gen:1312531 | 19 negentiende verdieping | 22.21 binnenwanden - constructief, massieve wanden (Uniformat) | Group: Model Group:NLRS_01.00_verdieping 18-19_gen:4617669
4 x  | 20 twintigste verdieping | 23.21 vloeren - constructief, vrijdragende vloeren (Uniformat) | Group: Model Group:NLRS_01.00_verdieping 20_gen:4622361
58 x  | 20 twintigste verdieping
Floor:NLRS_23.21_FL_beton ihwg d=250_gen:4617590:2 | 20 twintigste verdieping | 23.21 vloeren - constructief, vrijdragende vloeren (Uniformat) | Group: Model Group:NLRS_01.00_verdieping 20_gen:4622361
3 x Basic Wall:NLRS_21.21_WA_beton prefab d=270_gen:4618593 | 20 twintigste verdieping | 21.21 buitenwanden - constructief, massieve wanden (Uniformat) | Group: Model Group:NLRS_01.00_verdieping 20_gen:4622361
3 x Basic Wall:NLRS_21.21_WA_beton prefab d=250_gen:4618598 | 20 twintigste verdieping | 21.21 buitenwanden - constructief, massieve wanden (Uniformat) | Group: Model Group:NLRS_01.00_verdieping 20_gen:4622361
3 x Basic Wall:NLRS_21.21_WA_beton prefab d=250_gen:4618603 | 20 twintigste verdieping | 21.21 buitenwanden - constructief, massieve wanden (Uniformat) | Group: Model Group:NLRS_01.00_verdieping 20_gen:4622361
3 x Basic Wall:NLRS_21.21_WA_beton prefab d=250_gen:4618608 | 20 twintigste verdieping | 21.21 buitenwanden - constructief, massieve wanden (Uniformat) | Group: Model Group:NLRS_01.00_verdieping 20_gen:4622361
3 x Basic Wall:NLRS_21.21_WA_beton prefab d=270_gen:4618613 | 20 twintigste verdieping | 21.21 buitenwanden - constructief, massieve wanden (Uniformat) | Group: Model Group:NLRS_01.00_verdieping 20_gen:4622361
3 x Basic Wall:NLRS_21.21_WA_beton prefab d=250_gen:4618618 | 20 twintigste verdieping | 21.21 buitenwanden - constructief, massieve wanden (Uniformat) | Group: Model Group:NLRS_01.00_verdieping 20_gen:4622361
Basic Wall:NLRS_22.21_WA_beton ihwg d=250_gen:4618661 | 20 twintigste verdieping | 22.21 binnenwanden - constructief, massieve wanden (Uniformat) | Group: Model Group:NLRS_01.00_verdieping 20_gen:4622361
Basic Wall:NLRS_22.21_WA_beton ihwg d=250_gen:4618669 | 20 twintigste verdieping | 22.21 binnenwanden - constructief, massieve wanden (Uniformat) | Group: Model Group:NLRS_01.00_verdieping 20_gen:4622361
Basic Wall:NLRS_22.21_WA_beton ihwg d=250_gen:4618671 | 20 twintigste verdieping | 22.21 binnenwanden - constructief, massieve wanden (Uniformat) | Group: Model Group:NLRS_01.00_verdieping 20_gen:4622361
3 x Basic Wall:NLRS_22.21_WA_beton prefab d=200_gen:4618674 | 20 twintigste verdieping | 22.21 binnenwanden - constructief, massieve wanden (Uniformat) | Group: Model Group:NLRS_01.00_verdieping 20_gen:4622361
2 x Basic Wall:NLRS_22.21_WA_beton prefab d=200_gen:1312531 | 20 twintigste verdieping | 22.21 binnenwanden - constructief, massieve wanden (Uniformat) | Group: Model Group:NLRS_01.00_verdieping 20_gen:4622361
4 x  | 21 eenentwintigste verdieping | 23.21 vloeren - constructief, vrijdragende vloeren (Uniformat) | Group: Model Group:NLRS_01.00_verdieping 21--23_gen (members excluded):4647240
52 x  | 21 eenentwintigste verdieping
Floor:NLRS_23.21_FL_beton ihwg d=250_gen:4618687:2 | 21 eenentwintigste verdieping | 23.21 vloeren - constructief, vrijdragende vloeren (Uniformat) | Group: Model Group:NLRS_01.00_verdieping 21--23_gen (members excluded):4647240
3 x Basic Wall:NLRS_22.21_WA_beton ihwg d=250_gen:4620181 | 20 twintigste verdieping | 22.21 binnenwanden - constructief, massieve wanden (Uniformat) | Group: Model Group:NLRS_01.00_verdieping 20_gen:4622361
Basic Wall:NLRS_22.21_WA_beton ihwg d=250_gen:4621115 | 21 eenentwintigste verdieping | 22.21 binnenwanden - constructief, massieve wanden (Uniformat) | Group: Model Group:NLRS_01.00_verdieping 21--23_gen (members excluded):4647240
Basic Wall:NLRS_22.21_WA_beton ihwg d=250_gen:4621120 | 21 eenentwintigste verdieping | 22.21 binnenwanden - constructief, massieve wanden (Uniformat) | Group: Model Group:NLRS_01.00_verdieping 21--23_gen (members excluded):4647240
Basic Wall:NLRS_22.21_WA_beton ihwg d=250_gen:4621122 | 21 eenentwintigste verdieping | 22.21 binnenwanden - constructief, massieve wanden (Uniformat) | Group: Model Group:NLRS_01.00_verdieping 21--23_gen (members excluded):4647240
6 x Basic Wall:NLRS_22.21_WA_beton prefab d=200_gen:4621125 | 21 eenentwintigste verdieping | 22.21 binnenwanden - constructief, massieve wanden (Uniformat) | Group: Model Group:NLRS_01.00_verdieping 21--23_gen (members excluded):4647240
2 x Basic Wall:NLRS_22.21_WA_beton prefab d=200_gen:4621127 | 21 eenentwintigste verdieping | 22.21 binnenwanden - constructief, massieve wanden (Uniformat) | Group: Model Group:NLRS_01.00_verdieping 21--23_gen (members excluded):4647240
2 x Basic Wall:NLRS_22.21_WA_beton prefab d=200_gen:4621131 | 21 eenentwintigste verdieping | 22.21 binnenwanden - constructief, massieve wanden (Uniformat) | Group: Model Group:NLRS_01.00_verdieping 21--23_gen (members excluded):4647240
7 x Basic Wall:NLRS_22.21_WA_beton ihwg d=250_gen:4621218 | 21 eenentwintigste verdieping | 22.21 binnenwanden - constructief, massieve wanden (Uniformat) | Group: Model Group:NLRS_01.00_verdieping 21--23_gen (members excluded):4647240
3 x Basic Wall:NLRS_21.21_WA_beton prefab d=270_gen:4625962 | 11 elfde verdieping | 21.21 buitenwanden - constructief, massieve wanden (Uniformat) | Group: Model Group:NLRS_01.00_verdieping 11--17_gen:4626135
3 x Basic Wall:NLRS_21.21_WA_beton prefab d=250_gen:4625967 | 11 elfde verdieping | 21.21 buitenwanden - constructief, massieve wanden (Uniformat) | Group: Model Group:NLRS_01.00_verdieping 11--17_gen:4626135
4 x Basic Wall:NLRS_21.21_WA_beton prefab d=250_gen:1307923 | 11 elfde verdieping | 21.21 buitenwanden - constructief, massieve wanden (Uniformat) | Group: Model Group:NLRS_01.00_verdieping 11--17_gen:4626135
3 x Basic Wall:NLRS_21.21_WA_beton prefab d=250_gen:4625972 | 11 elfde verdieping | 21.21 buitenwanden - constructief, massieve wanden (Uniformat) | Group: Model Group:NLRS_01.00_verdieping 11--17_gen:4626135
3 x Basic Wall:NLRS_21.21_WA_beton prefab d=250_gen:4625977 | 11 elfde verdieping | 21.21 buitenwanden - constructief, massieve wanden (Uniformat) | Group: Model Group:NLRS_01.00_verdieping 11--17_gen:4626135
3 x Basic Wall:NLRS_21.21_WA_beton prefab d=270_gen:4625982 | 11 elfde verdieping | 21.21 buitenwanden - constructief, massieve wanden (Uniformat) | Group: Model Group:NLRS_01.00_verdieping 11--17_gen:4626135
3 x Basic Wall:NLRS_21.21_WA_beton prefab d=250_gen:4625987 | 11 elfde verdieping | 21.21 buitenwanden - constructief, massieve wanden (Uniformat) | Group: Model Group:NLRS_01.00_verdieping 11--17_gen:4626135
2 x Basic Wall:NLRS_22.21_WA_beton ihwg d=250_gen:4626028 | 11 elfde verdieping | 22.21 binnenwanden - constructief, massieve wanden (Uniformat) | Group: Model Group:NLRS_01.00_verdieping 11--17_gen:4626135
Basic Wall:NLRS_22.21_WA_beton ihwg d=250_gen:4626030 | 11 elfde verdieping | 22.21 binnenwanden - constructief, massieve wanden (Uniformat) | Group: Model Group:NLRS_01.00_verdieping 11--17_gen:4626135
Basic Wall:NLRS_22.21_WA_beton ihwg d=250_gen:4626038 | 11 elfde verdieping | 22.21 binnenwanden - constructief, massieve wanden (Uniformat) | Group: Model Group:NLRS_01.00_verdieping 11--17_gen:4626135
Basic Wall:NLRS_22.21_WA_beton ihwg d=250_gen:4626040 | 11 elfde verdieping | 22.21 binnenwanden - constructief, massieve wanden (Uniformat) | Group: Model Group:NLRS_01.00_verdieping 11--17_gen:4626135
3 x Basic Wall:NLRS_22.21_WA_beton prefab d=200_gen:4626043 | 11 elfde verdieping | 22.21 binnenwanden - constructief, massieve wanden (Uniformat) | Group: Model Group:NLRS_01.00_verdieping 11--17_gen:4626135
2 x Basic Wall:NLRS_22.21_WA_beton prefab d=200_gen:1312531 | 11 elfde verdieping | 22.21 binnenwanden - constructief, massieve wanden (Uniformat) | Group: Model Group:NLRS_01.00_verdieping 11--17_gen:4626135
4 x  | 06 zesde verdieping | 23.21 vloeren - constructief, vrijdragende vloeren (Uniformat) | Group: Model Group:NLRS_01.00_verdieping 06--10_gen:4600460
56 x  | 06 zesde verdieping
Floor:NLRS_23.21_FL_beton ihwg d=250_gen:4628732:2 | 06 zesde verdieping | 23.21 vloeren - constructief, vrijdragende vloeren (Uniformat) | Group: Model Group:NLRS_01.00_verdieping 06--10_gen:4600460
4 x  | 07 zevende verdieping | 23.21 vloeren - constructief, vrijdragende vloeren (Uniformat) | Group: Model Group:NLRS_01.00_verdieping 06--10_gen:4600975
56 x  | 07 zevende verdieping
Floor:NLRS_23.21_FL_beton ihwg d=250_gen:4628896:2 | 07 zevende verdieping | 23.21 vloeren - constructief, vrijdragende vloeren (Uniformat) | Group: Model Group:NLRS_01.00_verdieping 06--10_gen:4600975
4 x  | 08 achtste verdieping | 23.21 vloeren - constructief, vrijdragende vloeren (Uniformat) | Group: Model Group:NLRS_01.00_verdieping 06--10_gen:4602043
54 x  | 08 achtste verdieping
Floor:NLRS_23.21_FL_beton ihwg d=250_gen:4628978:2 | 08 achtste verdieping | 23.21 vloeren - constructief, vrijdragende vloeren (Uniformat) | Group: Model Group:NLRS_01.00_verdieping 06--10_gen:4602043
4 x  | 09 negende verdieping | 23.21 vloeren - constructief, vrijdragende vloeren (Uniformat) | Group: Model Group:NLRS_01.00_verdieping 06--10_gen:4603152
54 x  | 09 negende verdieping
Floor:NLRS_23.21_FL_beton ihwg d=250_gen:4629060:2 | 09 negende verdieping | 23.21 vloeren - constructief, vrijdragende vloeren (Uniformat) | Group: Model Group:NLRS_01.00_verdieping 06--10_gen:4603152
4 x  | 10 tiende verdieping | 23.21 vloeren - constructief, vrijdragende vloeren (Uniformat) | Group: Model Group:NLRS_01.00_verdieping 06--10_gen:4604220
54 x  | 10 tiende verdieping
Floor:NLRS_23.21_FL_beton ihwg d=250_gen:4629142:2 | 10 tiende verdieping | 23.21 vloeren - constructief, vrijdragende vloeren (Uniformat) | Group: Model Group:NLRS_01.00_verdieping 06--10_gen:4604220
4 x  | 12 twaalfde verdieping | 23.21 vloeren - constructief, vrijdragende vloeren (Uniformat) | Group: Model Group:NLRS_01.00_verdieping 11--17_gen:4609129
56 x  | 12 twaalfde verdieping
Floor:NLRS_23.21_FL_beton ihwg d=250_gen:4640288:2 | 12 twaalfde verdieping | 23.21 vloeren - constructief, vrijdragende vloeren (Uniformat) | Group: Model Group:NLRS_01.00_verdieping 11--17_gen:4609129
4 x  | 13 dertiende verdieping | 23.21 vloeren - constructief, vrijdragende vloeren (Uniformat) | Group: Model Group:NLRS_01.00_verdieping 11--17_gen:4609592
60 x  | 13 dertiende verdieping
Floor:NLRS_23.21_FL_beton ihwg d=250_gen:4640440:2 | 13 dertiende verdieping | 23.21 vloeren - constructief, vrijdragende vloeren (Uniformat) | Group: Model Group:NLRS_01.00_verdieping 11--17_gen:4609592
4 x  | 14 veertiende verdieping | 23.21 vloeren - constructief, vrijdragende vloeren (Uniformat) | Group: Model Group:NLRS_01.00_verdieping 11--17_gen:4610618
60 x  | 14 veertiende verdieping
Floor:NLRS_23.21_FL_beton ihwg d=250_gen:4640516:2 | 14 veertiende verdieping | 23.21 vloeren - constructief, vrijdragende vloeren (Uniformat) | Group: Model Group:NLRS_01.00_verdieping 11--17_gen:4610618
4 x  | 15 vijftiende verdieping | 23.21 vloeren - constructief, vrijdragende vloeren (Uniformat) | Group: Model Group:NLRS_01.00_verdieping 11--17_gen:4611642
60 x  | 15 vijftiende verdieping
Floor:NLRS_23.21_FL_beton ihwg d=250_gen:4640592:2 | 15 vijftiende verdieping | 23.21 vloeren - constructief, vrijdragende vloeren (Uniformat) | Group: Model Group:NLRS_01.00_verdieping 11--17_gen:4611642
4 x  | 16 zestiende verdieping | 23.21 vloeren - constructief, vrijdragende vloeren (Uniformat) | Group: Model Group:NLRS_01.00_verdieping 11--17_gen:4612668
58 x  | 16 zestiende verdieping
Floor:NLRS_23.21_FL_beton ihwg d=250_gen:4640668:2 | 16 zestiende verdieping | 23.21 vloeren - constructief, vrijdragende vloeren (Uniformat) | Group: Model Group:NLRS_01.00_verdieping 11--17_gen:4612668
4 x  | 17 zeventiende verdieping | 23.21 vloeren - constructief, vrijdragende vloeren (Uniformat) | Group: Model Group:NLRS_01.00_verdieping 11--17_gen:4613692
58 x  | 17 zeventiende verdieping
Floor:NLRS_23.21_FL_beton ihwg d=250_gen:4640744:2 | 17 zeventiende verdieping | 23.21 vloeren - constructief, vrijdragende vloeren (Uniformat) | Group: Model Group:NLRS_01.00_verdieping 11--17_gen:4613692
4 x  | 19 negentiende verdieping | 23.21 vloeren - constructief, vrijdragende vloeren (Uniformat) | Group: Model Group:NLRS_01.00_verdieping 18-19_gen:4617669
58 x  | 19 negentiende verdieping
Floor:NLRS_23.21_FL_beton ihwg d=250_gen:4644337:2 | 19 negentiende verdieping | 23.21 vloeren - constructief, vrijdragende vloeren (Uniformat) | Group: Model Group:NLRS_01.00_verdieping 18-19_gen:4617669
2 x Basic Wall:NLRS_22.21_WA_beton ihwg d=250_gen:4652445 | 22 tweeëntwintigste verdieping | 22.21 binnenwanden - constructief, massieve wanden (Uniformat) | Group: Model Group:NLRS_01.00_verdieping 21--23_gen (members excluded):4647240
2 x Basic Wall:NLRS_22.21_WA_beton ihwg d=250_gen:4652449 | 22 tweeëntwintigste verdieping | 22.21 binnenwanden - constructief, massieve wanden (Uniformat) | Group: Model Group:NLRS_01.00_verdieping 21--23_gen (members excluded):4647240
4 x Basic Wall:NLRS_22.21_WA_beton ihwg d=250_gen:4652453 | 22 tweeëntwintigste verdieping | 22.21 binnenwanden - constructief, massieve wanden (Uniformat) | Group: Model Group:NLRS_01.00_verdieping 21--23_gen (members excluded):4647240
Basic Wall:NLRS_22.21_WA_beton ihwg d=250_gen:4653282 | 22 tweeëntwintigste verdieping | 22.21 binnenwanden - constructief, massieve wanden (Uniformat) | Group: Model Group:NLRS_01.00_verdieping 21--23_gen (members excluded):4647240
3 x  | 22 tweeëntwintigste verdieping | 23.21 vloeren - constructief, vrijdragende vloeren (Uniformat) | Group: Model Group:NLRS_01.00_verdieping 21--23_gen (members excluded):4647240
42 x  | 22 tweeëntwintigste verdieping
Floor:NLRS_23.21_FL_beton ihwg d=250_gen:4653976:2 | 22 tweeëntwintigste verdieping | 23.21 vloeren - constructief, vrijdragende vloeren (Uniformat) | Group: Model Group:NLRS_01.00_verdieping 21--23_gen (members excluded):4647240
Floor:NLRS_23.21_FL_beton ihwg d=250_gen:4655458:2 | 22 tweeëntwintigste verdieping | 23.21 vloeren - constructief, vrijdragende vloeren (Uniformat) | Group: Model Group:NLRS_01.00_verdieping 21--23_gen (members excluded):4647240
3 x  | 23 dakverdieping | 23.21 vloeren - constructief, vrijdragende vloeren (Uniformat) | Group: Model Group:NLRS_01.00_verdieping 21--23_gen (members excluded):4647240
66 x  | 23 dakverdieping
Floor:NLRS_23.21_FL_beton ihwg d=250_gen:4656935:2 | 23 dakverdieping | 23.21 vloeren - constructief, vrijdragende vloeren (Uniformat) | Group: Model Group:NLRS_01.00_verdieping 21--23_gen (members excluded):4647240
3 x Basic Wall:NLRS_21.21_WA_beton prefab d=250_gen:4723596 | 02 tweede verdieping | 21.21 buitenwanden - constructief, massieve wanden (Uniformat)
Basic Wall:NLRS_22.21_WA_beton prefab d=250_gen:4732926 | 02b tweede tussenverdieping | 22.21 binnenwanden - constructief, massieve wanden (Uniformat)
9 x Basic Wall:NLRS_21.21_WA_beton ihwg d=250_gen:4744578 | 04 vierde verdieping | 21.21 buitenwanden - constructief, massieve wanden (Uniformat) | Group: Model Group:NLRS_01.00_verdieping 04_gen (members excluded):4585793
9 x Basic Wall:NLRS_21.21_WA_beton ihwg d=250_gen:4745194 | 04 vierde verdieping | 21.21 buitenwanden - constructief, massieve wanden (Uniformat) | Group: Model Group:NLRS_01.00_verdieping 04_gen (members excluded):4585793
9 x Basic Wall:NLRS_21.21_WA_beton ihwg d=250_gen:4745206 | 06 zesde verdieping | 21.21 buitenwanden - constructief, massieve wanden (Uniformat) | Group: Model Group:NLRS_21.21_wand ihwg as L.P 06-20_gen:4599056
9 x Basic Wall:NLRS_21.21_WA_beton ihwg d=250_gen:4745210 | 06 zesde verdieping | 21.21 buitenwanden - constructief, massieve wanden (Uniformat) | Group: Model Group:NLRS_21.21_wand ihwg as L.P 06-20_gen:4599124
9 x Basic Wall:NLRS_21.21_WA_beton ihwg d=250_gen:4745222 | 07 zevende verdieping | 21.21 buitenwanden - constructief, massieve wanden (Uniformat) | Group: Model Group:NLRS_21.21_wand ihwg as L.P 06-20_gen:4600793
9 x Basic Wall:NLRS_21.21_WA_beton ihwg d=250_gen:4745226 | 07 zevende verdieping | 21.21 buitenwanden - constructief, massieve wanden (Uniformat) | Group: Model Group:NLRS_21.21_wand ihwg as L.P 06-20_gen:4600861
9 x Basic Wall:NLRS_21.21_WA_beton ihwg d=250_gen:4745230 | 08 achtste verdieping | 21.21 buitenwanden - constructief, massieve wanden (Uniformat) | Group: Model Group:NLRS_21.21_wand ihwg as L.P 06-20_gen:4601861
9 x Basic Wall:NLRS_21.21_WA_beton ihwg d=250_gen:4745234 | 08 achtste verdieping | 21.21 buitenwanden - constructief, massieve wanden (Uniformat) | Group: Model Group:NLRS_21.21_wand ihwg as L.P 06-20_gen:4601929
9 x Basic Wall:NLRS_21.21_WA_beton ihwg d=250_gen:4745238 | 09 negende verdieping | 21.21 buitenwanden - constructief, massieve wanden (Uniformat) | Group: Model Group:NLRS_21.21_wand ihwg as L.P 06-20_gen:4602970
9 x Basic Wall:NLRS_21.21_WA_beton ihwg d=250_gen:4745242 | 09 negende verdieping | 21.21 buitenwanden - constructief, massieve wanden (Uniformat) | Group: Model Group:NLRS_21.21_wand ihwg as L.P 06-20_gen:4603038
9 x Basic Wall:NLRS_21.21_WA_beton ihwg d=250_gen:4745246 | 10 tiende verdieping | 21.21 buitenwanden - constructief, massieve wanden (Uniformat) | Group: Model Group:NLRS_21.21_wand ihwg as L.P 06-20_gen:4604038
9 x Basic Wall:NLRS_21.21_WA_beton ihwg d=250_gen:4745250 | 10 tiende verdieping | 21.21 buitenwanden - constructief, massieve wanden (Uniformat) | Group: Model Group:NLRS_21.21_wand ihwg as L.P 06-20_gen:4604106
9 x Basic Wall:NLRS_21.21_WA_beton ihwg d=250_gen:4745254 | 12 twaalfde verdieping | 21.21 buitenwanden - constructief, massieve wanden (Uniformat) | Group: Model Group:NLRS_21.21_wand ihwg as L.P 06-20_gen:4608046
9 x Basic Wall:NLRS_21.21_WA_beton ihwg d=250_gen:4745258 | 12 twaalfde verdieping | 21.21 buitenwanden - constructief, massieve wanden (Uniformat) | Group: Model Group:NLRS_21.21_wand ihwg as L.P 06-20_gen:4608114
9 x Basic Wall:NLRS_21.21_WA_beton ihwg d=250_gen:4745270 | 13 dertiende verdieping | 21.21 buitenwanden - constructief, massieve wanden (Uniformat) | Group: Model Group:NLRS_21.21_wand ihwg as L.P 06-20_gen:4609416
9 x Basic Wall:NLRS_21.21_WA_beton ihwg d=250_gen:4745274 | 13 dertiende verdieping | 21.21 buitenwanden - constructief, massieve wanden (Uniformat) | Group: Model Group:NLRS_21.21_wand ihwg as L.P 06-20_gen:4609484
9 x Basic Wall:NLRS_21.21_WA_beton ihwg d=250_gen:4745278 | 14 veertiende verdieping | 21.21 buitenwanden - constructief, massieve wanden (Uniformat) | Group: Model Group:NLRS_21.21_wand ihwg as L.P 06-20_gen:4610442
9 x Basic Wall:NLRS_21.21_WA_beton ihwg d=250_gen:4745282 | 14 veertiende verdieping | 21.21 buitenwanden - constructief, massieve wanden (Uniformat) | Group: Model Group:NLRS_21.21_wand ihwg as L.P 06-20_gen:4610510
9 x Basic Wall:NLRS_21.21_WA_beton ihwg d=250_gen:4745286 | 15 vijftiende verdieping | 21.21 buitenwanden - constructief, massieve wanden (Uniformat) | Group: Model Group:NLRS_21.21_wand ihwg as L.P 06-20_gen:4611466
9 x Basic Wall:NLRS_21.21_WA_beton ihwg d=250_gen:4745290 | 15 vijftiende verdieping | 21.21 buitenwanden - constructief, massieve wanden (Uniformat) | Group: Model Group:NLRS_21.21_wand ihwg as L.P 06-20_gen:4611534
9 x Basic Wall:NLRS_21.21_WA_beton ihwg d=250_gen:4745294 | 16 zestiende verdieping | 21.21 buitenwanden - constructief, massieve wanden (Uniformat) | Group: Model Group:NLRS_21.21_wand ihwg as L.P 06-20_gen:4612492
9 x Basic Wall:NLRS_21.21_WA_beton ihwg d=250_gen:4745298 | 16 zestiende verdieping | 21.21 buitenwanden - constructief, massieve wanden (Uniformat) | Group: Model Group:NLRS_21.21_wand ihwg as L.P 06-20_gen:4612560
9 x Basic Wall:NLRS_21.21_WA_beton ihwg d=250_gen:4745302 | 17 zeventiende verdieping | 21.21 buitenwanden - constructief, massieve wanden (Uniformat) | Group: Model Group:NLRS_21.21_wand ihwg as L.P 06-20_gen:4613516
9 x Basic Wall:NLRS_21.21_WA_beton ihwg d=250_gen:4745306 | 17 zeventiende verdieping | 21.21 buitenwanden - constructief, massieve wanden (Uniformat) | Group: Model Group:NLRS_21.21_wand ihwg as L.P 06-20_gen:4613584
9 x Basic Wall:NLRS_21.21_WA_beton ihwg d=250_gen:4745310 | 18 achttiende verdieping | 21.21 buitenwanden - constructief, massieve wanden (Uniformat) | Group: Model Group:NLRS_21.21_wand ihwg as L.P 06-20_gen:4616006
9 x Basic Wall:NLRS_21.21_WA_beton ihwg d=250_gen:4745314 | 18 achttiende verdieping | 21.21 buitenwanden - constructief, massieve wanden (Uniformat) | Group: Model Group:NLRS_21.21_wand ihwg as L.P 06-20_gen:4616074
9 x Basic Wall:NLRS_21.21_WA_beton ihwg d=250_gen:4745326 | 19 negentiende verdieping | 21.21 buitenwanden - constructief, massieve wanden (Uniformat) | Group: Model Group:NLRS_21.21_wand ihwg as L.P 06-20_gen:4617493
9 x Basic Wall:NLRS_21.21_WA_beton ihwg d=250_gen:4745330 | 19 negentiende verdieping | 21.21 buitenwanden - constructief, massieve wanden (Uniformat) | Group: Model Group:NLRS_21.21_wand ihwg as L.P 06-20_gen:4617561
9 x Basic Wall:NLRS_21.21_WA_beton ihwg d=250_gen:4745334 | 20 twintigste verdieping | 21.21 buitenwanden - constructief, massieve wanden (Uniformat) | Group: Model Group:NLRS_21.21_wand ihwg as L.P 06-20_gen:4618590
9 x Basic Wall:NLRS_21.21_WA_beton ihwg d=250_gen:4745338 | 20 twintigste verdieping | 21.21 buitenwanden - constructief, massieve wanden (Uniformat) | Group: Model Group:NLRS_21.21_wand ihwg as L.P 06-20_gen:4618658
9 x Basic Wall:NLRS_21.21_WA_beton ihwg d=250_gen:4745358 | 11 elfde verdieping | 21.21 buitenwanden - constructief, massieve wanden (Uniformat) | Group: Model Group:NLRS_21.21_wand ihwg as L.P 06-20_gen:4625959
9 x Basic Wall:NLRS_21.21_WA_beton ihwg d=250_gen:4745362 | 11 elfde verdieping | 21.21 buitenwanden - constructief, massieve wanden (Uniformat) | Group: Model Group:NLRS_21.21_wand ihwg as L.P 06-20_gen:4626027
3 x Basic Wall:NLRS_21.21_WA_beton prefab d=270_gen:4844264 | 04 vierde verdieping | 21.21 buitenwanden - constructief, massieve wanden (Uniformat) | Group: Model Group:NLRS_01.00_verdieping 04_gen (members excluded):4844403
3 x Basic Wall:NLRS_21.21_WA_beton prefab d=250_gen:4844269 | 04 vierde verdieping | 21.21 buitenwanden - constructief, massieve wanden (Uniformat) | Group: Model Group:NLRS_01.00_verdieping 04_gen (members excluded):4844403
3 x Basic Wall:NLRS_21.21_WA_beton prefab d=250_gen:1307923 | 04 vierde verdieping | 21.21 buitenwanden - constructief, massieve wanden (Uniformat) | Group: Model Group:NLRS_01.00_verdieping 04_gen (members excluded):4844403
3 x Basic Wall:NLRS_21.21_WA_beton prefab d=250_gen:4844274 | 04 vierde verdieping | 21.21 buitenwanden - constructief, massieve wanden (Uniformat) | Group: Model Group:NLRS_01.00_verdieping 04_gen (members excluded):4844403
3 x Basic Wall:NLRS_21.21_WA_beton prefab d=250_gen:4844279 | 04 vierde verdieping | 21.21 buitenwanden - constructief, massieve wanden (Uniformat) | Group: Model Group:NLRS_01.00_verdieping 04_gen (members excluded):4844403
3 x Basic Wall:NLRS_21.21_WA_beton prefab d=270_gen:4844284 | 04 vierde verdieping | 21.21 buitenwanden - constructief, massieve wanden (Uniformat) | Group: Model Group:NLRS_01.00_verdieping 04_gen (members excluded):4844403
Basic Wall:NLRS_21.21_WA_beton ihwg d=410_gen:4574461 | 05 vijfde verdieping | 21.21 buitenwanden - constructief, massieve wanden (Uniformat) | Group: Model Group:NLRS_01.00_verdieping 04_gen (members excluded):4844403
Basic Wall:NLRS_22.21_WA_beton ihwg d=250_gen:4844297 | 04 vierde verdieping | 22.21 binnenwanden - constructief, massieve wanden (Uniformat) | Group: Model Group:NLRS_01.00_verdieping 04_gen (members excluded):4844403
Basic Wall:NLRS_22.21_WA_beton ihwg d=250_gen:4844308 | 04 vierde verdieping | 22.21 binnenwanden - constructief, massieve wanden (Uniformat) | Group: Model Group:NLRS_01.00_verdieping 04_gen (members excluded):4844403
Basic Wall:NLRS_22.21_WA_beton ihwg d=250_gen:4844312 | 04 vierde verdieping | 22.21 binnenwanden - constructief, massieve wanden (Uniformat) | Group: Model Group:NLRS_01.00_verdieping 04_gen (members excluded):4844403
3 x Basic Wall:NLRS_22.21_WA_beton prefab d=200_gen:4844319 | 04 vierde verdieping | 22.21 binnenwanden - constructief, massieve wanden (Uniformat) | Group: Model Group:NLRS_01.00_verdieping 04_gen (members excluded):4844403
2 x Basic Wall:NLRS_22.21_WA_beton prefab d=200_gen:1312531 | 04 vierde verdieping | 22.21 binnenwanden - constructief, massieve wanden (Uniformat) | Group: Model Group:NLRS_01.00_verdieping 04_gen (members excluded):4844403
4 x  | 05 vijfde verdieping | 23.21 vloeren - constructief, vrijdragende vloeren (Uniformat) | Group: Model Group:NLRS_01.00_verdieping 05_gen:6691052
58 x  | 05 vijfde verdieping
Floor:NLRS_23.21_FL_beton ihwg d=250_gen:4844332:2 | 05 vijfde verdieping | 23.21 vloeren - constructief, vrijdragende vloeren (Uniformat) | Group: Model Group:NLRS_01.00_verdieping 05_gen:6691052
3 x Basic Wall:NLRS_21.21_WA_beton prefab d=270_gen:4844409 | 06 zesde verdieping | 21.21 buitenwanden - constructief, massieve wanden (Uniformat) | Group: Model Group:NLRS_01.00_verdieping 06--10_gen:4844478
3 x Basic Wall:NLRS_21.21_WA_beton prefab d=250_gen:4844414 | 06 zesde verdieping | 21.21 buitenwanden - constructief, massieve wanden (Uniformat) | Group: Model Group:NLRS_01.00_verdieping 06--10_gen:4844478
3 x Basic Wall:NLRS_21.21_WA_beton prefab d=250_gen:1307923 | 06 zesde verdieping | 21.21 buitenwanden - constructief, massieve wanden (Uniformat) | Group: Model Group:NLRS_01.00_verdieping 06--10_gen:4844478
3 x Basic Wall:NLRS_21.21_WA_beton prefab d=250_gen:4844419 | 06 zesde verdieping | 21.21 buitenwanden - constructief, massieve wanden (Uniformat) | Group: Model Group:NLRS_01.00_verdieping 06--10_gen:4844478
3 x Basic Wall:NLRS_21.21_WA_beton prefab d=250_gen:4844424 | 06 zesde verdieping | 21.21 buitenwanden - constructief, massieve wanden (Uniformat) | Group: Model Group:NLRS_01.00_verdieping 06--10_gen:4844478
3 x Basic Wall:NLRS_21.21_WA_beton prefab d=270_gen:4844429 | 06 zesde verdieping | 21.21 buitenwanden - constructief, massieve wanden (Uniformat) | Group: Model Group:NLRS_01.00_verdieping 06--10_gen:4844478
3 x Basic Wall:NLRS_21.21_WA_beton prefab d=250_gen:4844434 | 07 zevende verdieping | 21.21 buitenwanden - constructief, massieve wanden (Uniformat) | Group: Model Group:NLRS_01.00_verdieping 06--10_gen:4844478
Basic Wall:NLRS_21.21_WA_beton prefab d=250_gen:1307923 | 07 zevende verdieping | 21.21 buitenwanden - constructief, massieve wanden (Uniformat) | Group: Model Group:NLRS_01.00_verdieping 06--10_gen:4844478
2 x Basic Wall:NLRS_22.21_WA_beton ihwg d=250_gen:4844439 | 06 zesde verdieping | 22.21 binnenwanden - constructief, massieve wanden (Uniformat) | Group: Model Group:NLRS_01.00_verdieping 06--10_gen:4844478
Basic Wall:NLRS_22.21_WA_beton ihwg d=250_gen:4844441 | 06 zesde verdieping | 22.21 binnenwanden - constructief, massieve wanden (Uniformat) | Group: Model Group:NLRS_01.00_verdieping 06--10_gen:4844478
Basic Wall:NLRS_22.21_WA_beton ihwg d=250_gen:4844449 | 06 zesde verdieping | 22.21 binnenwanden - constructief, massieve wanden (Uniformat) | Group: Model Group:NLRS_01.00_verdieping 06--10_gen:4844478
Basic Wall:NLRS_22.21_WA_beton ihwg d=250_gen:4844453 | 06 zesde verdieping | 22.21 binnenwanden - constructief, massieve wanden (Uniformat) | Group: Model Group:NLRS_01.00_verdieping 06--10_gen:4844478
Basic Wall:NLRS_22.21_WA_beton ihwg d=250_gen:4844455 | 06 zesde verdieping | 22.21 binnenwanden - constructief, massieve wanden (Uniformat) | Group: Model Group:NLRS_01.00_verdieping 06--10_gen:4844478
3 x Basic Wall:NLRS_22.21_WA_beton prefab d=200_gen:4844460 | 06 zesde verdieping | 22.21 binnenwanden - constructief, massieve wanden (Uniformat) | Group: Model Group:NLRS_01.00_verdieping 06--10_gen:4844478
2 x Basic Wall:NLRS_22.21_WA_beton prefab d=200_gen:1312531 | 06 zesde verdieping | 22.21 binnenwanden - constructief, massieve wanden (Uniformat) | Group: Model Group:NLRS_01.00_verdieping 06--10_gen:4844478
3 x Basic Wall:NLRS_21.21_WA_beton prefab d=270_gen:4844484 | 07 zevende verdieping | 21.21 buitenwanden - constructief, massieve wanden (Uniformat) | Group: Model Group:NLRS_01.00_verdieping 06--10_gen:4844553
3 x Basic Wall:NLRS_21.21_WA_beton prefab d=250_gen:4844489 | 07 zevende verdieping | 21.21 buitenwanden - constructief, massieve wanden (Uniformat) | Group: Model Group:NLRS_01.00_verdieping 06--10_gen:4844553
3 x Basic Wall:NLRS_21.21_WA_beton prefab d=250_gen:1307923 | 07 zevende verdieping | 21.21 buitenwanden - constructief, massieve wanden (Uniformat) | Group: Model Group:NLRS_01.00_verdieping 06--10_gen:4844553
3 x Basic Wall:NLRS_21.21_WA_beton prefab d=250_gen:4844494 | 07 zevende verdieping | 21.21 buitenwanden - constructief, massieve wanden (Uniformat) | Group: Model Group:NLRS_01.00_verdieping 06--10_gen:4844553
3 x Basic Wall:NLRS_21.21_WA_beton prefab d=250_gen:4844499 | 07 zevende verdieping | 21.21 buitenwanden - constructief, massieve wanden (Uniformat) | Group: Model Group:NLRS_01.00_verdieping 06--10_gen:4844553
3 x Basic Wall:NLRS_21.21_WA_beton prefab d=270_gen:4844504 | 07 zevende verdieping | 21.21 buitenwanden - constructief, massieve wanden (Uniformat) | Group: Model Group:NLRS_01.00_verdieping 06--10_gen:4844553
3 x Basic Wall:NLRS_21.21_WA_beton prefab d=250_gen:4844509 | 08 achtste verdieping | 21.21 buitenwanden - constructief, massieve wanden (Uniformat) | Group: Model Group:NLRS_01.00_verdieping 06--10_gen:4844553
Basic Wall:NLRS_21.21_WA_beton prefab d=250_gen:1307923 | 08 achtste verdieping | 21.21 buitenwanden - constructief, massieve wanden (Uniformat) | Group: Model Group:NLRS_01.00_verdieping 06--10_gen:4844553
2 x Basic Wall:NLRS_22.21_WA_beton ihwg d=250_gen:4844514 | 07 zevende verdieping | 22.21 binnenwanden - constructief, massieve wanden (Uniformat) | Group: Model Group:NLRS_01.00_verdieping 06--10_gen:4844553
Basic Wall:NLRS_22.21_WA_beton ihwg d=250_gen:4844516 | 07 zevende verdieping | 22.21 binnenwanden - constructief, massieve wanden (Uniformat) | Group: Model Group:NLRS_01.00_verdieping 06--10_gen:4844553
Basic Wall:NLRS_22.21_WA_beton ihwg d=250_gen:4844524 | 07 zevende verdieping | 22.21 binnenwanden - constructief, massieve wanden (Uniformat) | Group: Model Group:NLRS_01.00_verdieping 06--10_gen:4844553
Basic Wall:NLRS_22.21_WA_beton ihwg d=250_gen:4844528 | 07 zevende verdieping | 22.21 binnenwanden - constructief, massieve wanden (Uniformat) | Group: Model Group:NLRS_01.00_verdieping 06--10_gen:4844553
Basic Wall:NLRS_22.21_WA_beton ihwg d=250_gen:4844530 | 07 zevende verdieping | 22.21 binnenwanden - constructief, massieve wanden (Uniformat) | Group: Model Group:NLRS_01.00_verdieping 06--10_gen:4844553
3 x Basic Wall:NLRS_22.21_WA_beton prefab d=200_gen:4844535 | 07 zevende verdieping | 22.21 binnenwanden - constructief, massieve wanden (Uniformat) | Group: Model Group:NLRS_01.00_verdieping 06--10_gen:4844553
2 x Basic Wall:NLRS_22.21_WA_beton prefab d=200_gen:1312531 | 07 zevende verdieping | 22.21 binnenwanden - constructief, massieve wanden (Uniformat) | Group: Model Group:NLRS_01.00_verdieping 06--10_gen:4844553
3 x Basic Wall:NLRS_21.21_WA_beton prefab d=270_gen:4844559 | 08 achtste verdieping | 21.21 buitenwanden - constructief, massieve wanden (Uniformat) | Group: Model Group:NLRS_01.00_verdieping 06--10_gen:4844628
3 x Basic Wall:NLRS_21.21_WA_beton prefab d=250_gen:4844564 | 08 achtste verdieping | 21.21 buitenwanden - constructief, massieve wanden (Uniformat) | Group: Model Group:NLRS_01.00_verdieping 06--10_gen:4844628
3 x Basic Wall:NLRS_21.21_WA_beton prefab d=250_gen:1307923 | 08 achtste verdieping | 21.21 buitenwanden - constructief, massieve wanden (Uniformat) | Group: Model Group:NLRS_01.00_verdieping 06--10_gen:4844628
3 x Basic Wall:NLRS_21.21_WA_beton prefab d=250_gen:4844569 | 08 achtste verdieping | 21.21 buitenwanden - constructief, massieve wanden (Uniformat) | Group: Model Group:NLRS_01.00_verdieping 06--10_gen:4844628
3 x Basic Wall:NLRS_21.21_WA_beton prefab d=250_gen:4844574 | 08 achtste verdieping | 21.21 buitenwanden - constructief, massieve wanden (Uniformat) | Group: Model Group:NLRS_01.00_verdieping 06--10_gen:4844628
3 x Basic Wall:NLRS_21.21_WA_beton prefab d=270_gen:4844579 | 08 achtste verdieping | 21.21 buitenwanden - constructief, massieve wanden (Uniformat) | Group: Model Group:NLRS_01.00_verdieping 06--10_gen:4844628
3 x Basic Wall:NLRS_21.21_WA_beton prefab d=250_gen:4844584 | 09 negende verdieping | 21.21 buitenwanden - constructief, massieve wanden (Uniformat) | Group: Model Group:NLRS_01.00_verdieping 06--10_gen:4844628
Basic Wall:NLRS_21.21_WA_beton prefab d=250_gen:1307923 | 09 negende verdieping | 21.21 buitenwanden - constructief, massieve wanden (Uniformat) | Group: Model Group:NLRS_01.00_verdieping 06--10_gen:4844628
2 x Basic Wall:NLRS_22.21_WA_beton ihwg d=250_gen:4844589 | 08 achtste verdieping | 22.21 binnenwanden - constructief, massieve wanden (Uniformat) | Group: Model Group:NLRS_01.00_verdieping 06--10_gen:4844628
Basic Wall:NLRS_22.21_WA_beton ihwg d=250_gen:4844591 | 08 achtste verdieping | 22.21 binnenwanden - constructief, massieve wanden (Uniformat) | Group: Model Group:NLRS_01.00_verdieping 06--10_gen:4844628
Basic Wall:NLRS_22.21_WA_beton ihwg d=250_gen:4844599 | 08 achtste verdieping | 22.21 binnenwanden - constructief, massieve wanden (Uniformat) | Group: Model Group:NLRS_01.00_verdieping 06--10_gen:4844628
Basic Wall:NLRS_22.21_WA_beton ihwg d=250_gen:4844603 | 08 achtste verdieping | 22.21 binnenwanden - constructief, massieve wanden (Uniformat) | Group: Model Group:NLRS_01.00_verdieping 06--10_gen:4844628
Basic Wall:NLRS_22.21_WA_beton ihwg d=250_gen:4844605 | 08 achtste verdieping | 22.21 binnenwanden - constructief, massieve wanden (Uniformat) | Group: Model Group:NLRS_01.00_verdieping 06--10_gen:4844628
3 x Basic Wall:NLRS_22.21_WA_beton prefab d=200_gen:4844610 | 08 achtste verdieping | 22.21 binnenwanden - constructief, massieve wanden (Uniformat) | Group: Model Group:NLRS_01.00_verdieping 06--10_gen:4844628
2 x Basic Wall:NLRS_22.21_WA_beton prefab d=200_gen:1312531 | 08 achtste verdieping | 22.21 binnenwanden - constructief, massieve wanden (Uniformat) | Group: Model Group:NLRS_01.00_verdieping 06--10_gen:4844628
3 x Basic Wall:NLRS_21.21_WA_beton prefab d=270_gen:4844634 | 09 negende verdieping | 21.21 buitenwanden - constructief, massieve wanden (Uniformat) | Group: Model Group:NLRS_01.00_verdieping 06--10_gen:4844703
3 x Basic Wall:NLRS_21.21_WA_beton prefab d=250_gen:4844639 | 09 negende verdieping | 21.21 buitenwanden - constructief, massieve wanden (Uniformat) | Group: Model Group:NLRS_01.00_verdieping 06--10_gen:4844703
3 x Basic Wall:NLRS_21.21_WA_beton prefab d=250_gen:1307923 | 09 negende verdieping | 21.21 buitenwanden - constructief, massieve wanden (Uniformat) | Group: Model Group:NLRS_01.00_verdieping 06--10_gen:4844703
3 x Basic Wall:NLRS_21.21_WA_beton prefab d=250_gen:4844644 | 09 negende verdieping | 21.21 buitenwanden - constructief, massieve wanden (Uniformat) | Group: Model Group:NLRS_01.00_verdieping 06--10_gen:4844703
3 x Basic Wall:NLRS_21.21_WA_beton prefab d=250_gen:4844649 | 09 negende verdieping | 21.21 buitenwanden - constructief, massieve wanden (Uniformat) | Group: Model Group:NLRS_01.00_verdieping 06--10_gen:4844703
3 x Basic Wall:NLRS_21.21_WA_beton prefab d=270_gen:4844654 | 09 negende verdieping | 21.21 buitenwanden - constructief, massieve wanden (Uniformat) | Group: Model Group:NLRS_01.00_verdieping 06--10_gen:4844703
3 x Basic Wall:NLRS_21.21_WA_beton prefab d=250_gen:4844659 | 10 tiende verdieping | 21.21 buitenwanden - constructief, massieve wanden (Uniformat) | Group: Model Group:NLRS_01.00_verdieping 06--10_gen:4844703
Basic Wall:NLRS_21.21_WA_beton prefab d=250_gen:1307923 | 10 tiende verdieping | 21.21 buitenwanden - constructief, massieve wanden (Uniformat) | Group: Model Group:NLRS_01.00_verdieping 06--10_gen:4844703
2 x Basic Wall:NLRS_22.21_WA_beton ihwg d=250_gen:4844664 | 09 negende verdieping | 22.21 binnenwanden - constructief, massieve wanden (Uniformat) | Group: Model Group:NLRS_01.00_verdieping 06--10_gen:4844703
Basic Wall:NLRS_22.21_WA_beton ihwg d=250_gen:4844666 | 09 negende verdieping | 22.21 binnenwanden - constructief, massieve wanden (Uniformat) | Group: Model Group:NLRS_01.00_verdieping 06--10_gen:4844703
Basic Wall:NLRS_22.21_WA_beton ihwg d=250_gen:4844674 | 09 negende verdieping | 22.21 binnenwanden - constructief, massieve wanden (Uniformat) | Group: Model Group:NLRS_01.00_verdieping 06--10_gen:4844703
Basic Wall:NLRS_22.21_WA_beton ihwg d=250_gen:4844678 | 09 negende verdieping | 22.21 binnenwanden - constructief, massieve wanden (Uniformat) | Group: Model Group:NLRS_01.00_verdieping 06--10_gen:4844703
Basic Wall:NLRS_22.21_WA_beton ihwg d=250_gen:4844680 | 09 negende verdieping | 22.21 binnenwanden - constructief, massieve wanden (Uniformat) | Group: Model Group:NLRS_01.00_verdieping 06--10_gen:4844703
3 x Basic Wall:NLRS_22.21_WA_beton prefab d=200_gen:4844685 | 09 negende verdieping | 22.21 binnenwanden - constructief, massieve wanden (Uniformat) | Group: Model Group:NLRS_01.00_verdieping 06--10_gen:4844703
2 x Basic Wall:NLRS_22.21_WA_beton prefab d=200_gen:1312531 | 09 negende verdieping | 22.21 binnenwanden - constructief, massieve wanden (Uniformat) | Group: Model Group:NLRS_01.00_verdieping 06--10_gen:4844703
3 x Basic Wall:NLRS_21.21_WA_beton prefab d=270_gen:4844709 | 10 tiende verdieping | 21.21 buitenwanden - constructief, massieve wanden (Uniformat) | Group: Model Group:NLRS_01.00_verdieping 06--10_gen:4844850
3 x Basic Wall:NLRS_21.21_WA_beton prefab d=250_gen:4844714 | 10 tiende verdieping | 21.21 buitenwanden - constructief, massieve wanden (Uniformat) | Group: Model Group:NLRS_01.00_verdieping 06--10_gen:4844850
3 x Basic Wall:NLRS_21.21_WA_beton prefab d=250_gen:1307923 | 10 tiende verdieping | 21.21 buitenwanden - constructief, massieve wanden (Uniformat) | Group: Model Group:NLRS_01.00_verdieping 06--10_gen:4844850
3 x Basic Wall:NLRS_21.21_WA_beton prefab d=250_gen:4844719 | 10 tiende verdieping | 21.21 buitenwanden - constructief, massieve wanden (Uniformat) | Group: Model Group:NLRS_01.00_verdieping 06--10_gen:4844850
3 x Basic Wall:NLRS_21.21_WA_beton prefab d=250_gen:4844724 | 10 tiende verdieping | 21.21 buitenwanden - constructief, massieve wanden (Uniformat) | Group: Model Group:NLRS_01.00_verdieping 06--10_gen:4844850
3 x Basic Wall:NLRS_21.21_WA_beton prefab d=270_gen:4844729 | 10 tiende verdieping | 21.21 buitenwanden - constructief, massieve wanden (Uniformat) | Group: Model Group:NLRS_01.00_verdieping 06--10_gen:4844850
3 x Basic Wall:NLRS_21.21_WA_beton prefab d=250_gen:4844734 | 11 elfde verdieping | 21.21 buitenwanden - constructief, massieve wanden (Uniformat) | Group: Model Group:NLRS_01.00_verdieping 06--10_gen:4844850
Basic Wall:NLRS_21.21_WA_beton prefab d=250_gen:1307923 | 11 elfde verdieping | 21.21 buitenwanden - constructief, massieve wanden (Uniformat) | Group: Model Group:NLRS_01.00_verdieping 06--10_gen:4844850
2 x Basic Wall:NLRS_22.21_WA_beton ihwg d=250_gen:4844739 | 10 tiende verdieping | 22.21 binnenwanden - constructief, massieve wanden (Uniformat) | Group: Model Group:NLRS_01.00_verdieping 06--10_gen:4844850
Basic Wall:NLRS_22.21_WA_beton ihwg d=250_gen:4844741 | 10 tiende verdieping | 22.21 binnenwanden - constructief, massieve wanden (Uniformat) | Group: Model Group:NLRS_01.00_verdieping 06--10_gen:4844850
Basic Wall:NLRS_22.21_WA_beton ihwg d=250_gen:4844749 | 10 tiende verdieping | 22.21 binnenwanden - constructief, massieve wanden (Uniformat) | Group: Model Group:NLRS_01.00_verdieping 06--10_gen:4844850
Basic Wall:NLRS_22.21_WA_beton ihwg d=250_gen:4844753 | 10 tiende verdieping | 22.21 binnenwanden - constructief, massieve wanden (Uniformat) | Group: Model Group:NLRS_01.00_verdieping 06--10_gen:4844850
Basic Wall:NLRS_22.21_WA_beton ihwg d=250_gen:4844755 | 10 tiende verdieping | 22.21 binnenwanden - constructief, massieve wanden (Uniformat) | Group: Model Group:NLRS_01.00_verdieping 06--10_gen:4844850
3 x Basic Wall:NLRS_22.21_WA_beton prefab d=200_gen:4844760 | 10 tiende verdieping | 22.21 binnenwanden - constructief, massieve wanden (Uniformat) | Group: Model Group:NLRS_01.00_verdieping 06--10_gen:4844850
2 x Basic Wall:NLRS_22.21_WA_beton prefab d=200_gen:1312531 | 10 tiende verdieping | 22.21 binnenwanden - constructief, massieve wanden (Uniformat) | Group: Model Group:NLRS_01.00_verdieping 06--10_gen:4844850
4 x  | 11 elfde verdieping | 23.21 vloeren - constructief, vrijdragende vloeren (Uniformat) | Group: Model Group:NLRS_01.00_verdieping 11--17_gen:4845821
Floor:NLRS_23.21_FL_beton ihwg d=250_gen:4844773:2 | 11 elfde verdieping | 23.21 vloeren - constructief, vrijdragende vloeren (Uniformat) | Group: Model Group:NLRS_01.00_verdieping 11--17_gen:4845821
3 x Basic Wall:NLRS_21.21_WA_beton prefab d=270_gen:4844856 | 12 twaalfde verdieping | 21.21 buitenwanden - constructief, massieve wanden (Uniformat) | Group: Model Group:NLRS_01.00_verdieping 11--17_gen:4844919
3 x Basic Wall:NLRS_21.21_WA_beton prefab d=250_gen:4844861 | 12 twaalfde verdieping | 21.21 buitenwanden - constructief, massieve wanden (Uniformat) | Group: Model Group:NLRS_01.00_verdieping 11--17_gen:4844919
4 x Basic Wall:NLRS_21.21_WA_beton prefab d=250_gen:1307923 | 12 twaalfde verdieping | 21.21 buitenwanden - constructief, massieve wanden (Uniformat) | Group: Model Group:NLRS_01.00_verdieping 11--17_gen:4844919
3 x Basic Wall:NLRS_21.21_WA_beton prefab d=250_gen:4844866 | 12 twaalfde verdieping | 21.21 buitenwanden - constructief, massieve wanden (Uniformat) | Group: Model Group:NLRS_01.00_verdieping 11--17_gen:4844919
3 x Basic Wall:NLRS_21.21_WA_beton prefab d=250_gen:4844871 | 12 twaalfde verdieping | 21.21 buitenwanden - constructief, massieve wanden (Uniformat) | Group: Model Group:NLRS_01.00_verdieping 11--17_gen:4844919
3 x Basic Wall:NLRS_21.21_WA_beton prefab d=270_gen:4844876 | 12 twaalfde verdieping | 21.21 buitenwanden - constructief, massieve wanden (Uniformat) | Group: Model Group:NLRS_01.00_verdieping 11--17_gen:4844919
3 x Basic Wall:NLRS_21.21_WA_beton prefab d=250_gen:4844881 | 12 twaalfde verdieping | 21.21 buitenwanden - constructief, massieve wanden (Uniformat) | Group: Model Group:NLRS_01.00_verdieping 11--17_gen:4844919
2 x Basic Wall:NLRS_22.21_WA_beton ihwg d=250_gen:4844886 | 12 twaalfde verdieping | 22.21 binnenwanden - constructief, massieve wanden (Uniformat) | Group: Model Group:NLRS_01.00_verdieping 11--17_gen:4844919
Basic Wall:NLRS_22.21_WA_beton ihwg d=250_gen:4844888 | 12 twaalfde verdieping | 22.21 binnenwanden - constructief, massieve wanden (Uniformat) | Group: Model Group:NLRS_01.00_verdieping 11--17_gen:4844919
Basic Wall:NLRS_22.21_WA_beton ihwg d=250_gen:4844896 | 12 twaalfde verdieping | 22.21 binnenwanden - constructief, massieve wanden (Uniformat) | Group: Model Group:NLRS_01.00_verdieping 11--17_gen:4844919
Basic Wall:NLRS_22.21_WA_beton ihwg d=250_gen:4844898 | 12 twaalfde verdieping | 22.21 binnenwanden - constructief, massieve wanden (Uniformat) | Group: Model Group:NLRS_01.00_verdieping 11--17_gen:4844919
3 x Basic Wall:NLRS_22.21_WA_beton prefab d=200_gen:4844901 | 12 twaalfde verdieping | 22.21 binnenwanden - constructief, massieve wanden (Uniformat) | Group: Model Group:NLRS_01.00_verdieping 11--17_gen:4844919
2 x Basic Wall:NLRS_22.21_WA_beton prefab d=200_gen:1312531 | 12 twaalfde verdieping | 22.21 binnenwanden - constructief, massieve wanden (Uniformat) | Group: Model Group:NLRS_01.00_verdieping 11--17_gen:4844919
3 x Basic Wall:NLRS_21.21_WA_beton prefab d=270_gen:4844925 | 13 dertiende verdieping | 21.21 buitenwanden - constructief, massieve wanden (Uniformat) | Group: Model Group:NLRS_01.00_verdieping 11--17_gen:4844988
3 x Basic Wall:NLRS_21.21_WA_beton prefab d=250_gen:4844930 | 13 dertiende verdieping | 21.21 buitenwanden - constructief, massieve wanden (Uniformat) | Group: Model Group:NLRS_01.00_verdieping 11--17_gen:4844988
4 x Basic Wall:NLRS_21.21_WA_beton prefab d=250_gen:1307923 | 13 dertiende verdieping | 21.21 buitenwanden - constructief, massieve wanden (Uniformat) | Group: Model Group:NLRS_01.00_verdieping 11--17_gen:4844988
3 x Basic Wall:NLRS_21.21_WA_beton prefab d=250_gen:4844935 | 13 dertiende verdieping | 21.21 buitenwanden - constructief, massieve wanden (Uniformat) | Group: Model Group:NLRS_01.00_verdieping 11--17_gen:4844988
3 x Basic Wall:NLRS_21.21_WA_beton prefab d=250_gen:4844940 | 13 dertiende verdieping | 21.21 buitenwanden - constructief, massieve wanden (Uniformat) | Group: Model Group:NLRS_01.00_verdieping 11--17_gen:4844988
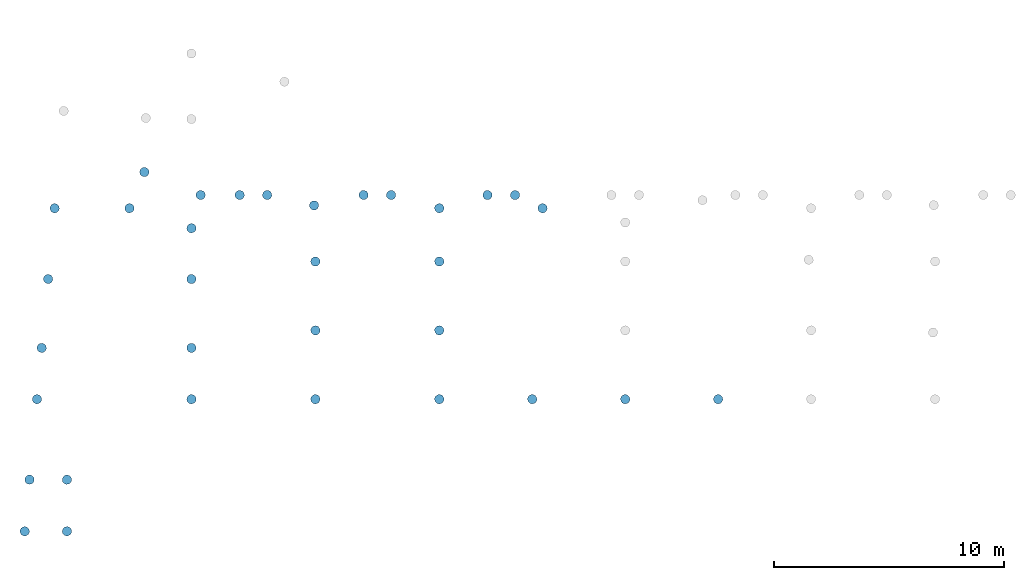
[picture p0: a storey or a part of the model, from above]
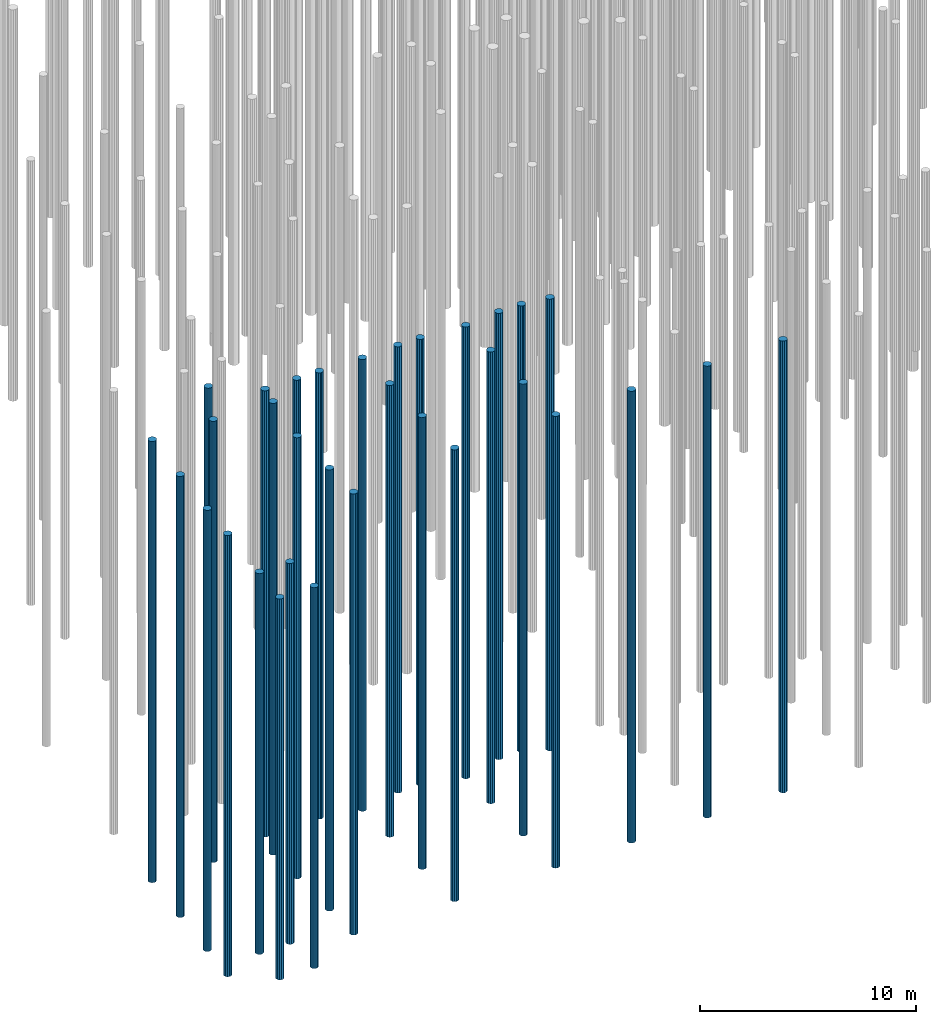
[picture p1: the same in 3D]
Properties of the parts of a building model (IFC2X3), part 6 of 11

# IfcOpeningElement: Opening (5029)
Name | In | Classification
3 x Basic Wall:NLRS_21.21_WA_beton prefab d=270_gen:4844945 | 13 dertiende verdieping | 21.21 buitenwanden - constructief, massieve wanden (Uniformat) | Group: Model Group:NLRS_01.00_verdieping 11--17_gen:4844988
3 x Basic Wall:NLRS_21.21_WA_beton prefab d=250_gen:4844950 | 13 dertiende verdieping | 21.21 buitenwanden - constructief, massieve wanden (Uniformat) | Group: Model Group:NLRS_01.00_verdieping 11--17_gen:4844988
2 x Basic Wall:NLRS_22.21_WA_beton ihwg d=250_gen:4844955 | 13 dertiende verdieping | 22.21 binnenwanden - constructief, massieve wanden (Uniformat) | Group: Model Group:NLRS_01.00_verdieping 11--17_gen:4844988
Basic Wall:NLRS_22.21_WA_beton ihwg d=250_gen:4844957 | 13 dertiende verdieping | 22.21 binnenwanden - constructief, massieve wanden (Uniformat) | Group: Model Group:NLRS_01.00_verdieping 11--17_gen:4844988
Basic Wall:NLRS_22.21_WA_beton ihwg d=250_gen:4844965 | 13 dertiende verdieping | 22.21 binnenwanden - constructief, massieve wanden (Uniformat) | Group: Model Group:NLRS_01.00_verdieping 11--17_gen:4844988
Basic Wall:NLRS_22.21_WA_beton ihwg d=250_gen:4844967 | 13 dertiende verdieping | 22.21 binnenwanden - constructief, massieve wanden (Uniformat) | Group: Model Group:NLRS_01.00_verdieping 11--17_gen:4844988
3 x Basic Wall:NLRS_22.21_WA_beton prefab d=200_gen:4844970 | 13 dertiende verdieping | 22.21 binnenwanden - constructief, massieve wanden (Uniformat) | Group: Model Group:NLRS_01.00_verdieping 11--17_gen:4844988
2 x Basic Wall:NLRS_22.21_WA_beton prefab d=200_gen:1312531 | 13 dertiende verdieping | 22.21 binnenwanden - constructief, massieve wanden (Uniformat) | Group: Model Group:NLRS_01.00_verdieping 11--17_gen:4844988
3 x Basic Wall:NLRS_21.21_WA_beton prefab d=270_gen:4844994 | 14 veertiende verdieping | 21.21 buitenwanden - constructief, massieve wanden (Uniformat) | Group: Model Group:NLRS_01.00_verdieping 11--17_gen:4845057
3 x Basic Wall:NLRS_21.21_WA_beton prefab d=250_gen:4844999 | 14 veertiende verdieping | 21.21 buitenwanden - constructief, massieve wanden (Uniformat) | Group: Model Group:NLRS_01.00_verdieping 11--17_gen:4845057
4 x Basic Wall:NLRS_21.21_WA_beton prefab d=250_gen:1307923 | 14 veertiende verdieping | 21.21 buitenwanden - constructief, massieve wanden (Uniformat) | Group: Model Group:NLRS_01.00_verdieping 11--17_gen:4845057
3 x Basic Wall:NLRS_21.21_WA_beton prefab d=250_gen:4845004 | 14 veertiende verdieping | 21.21 buitenwanden - constructief, massieve wanden (Uniformat) | Group: Model Group:NLRS_01.00_verdieping 11--17_gen:4845057
3 x Basic Wall:NLRS_21.21_WA_beton prefab d=250_gen:4845009 | 14 veertiende verdieping | 21.21 buitenwanden - constructief, massieve wanden (Uniformat) | Group: Model Group:NLRS_01.00_verdieping 11--17_gen:4845057
3 x Basic Wall:NLRS_21.21_WA_beton prefab d=270_gen:4845014 | 14 veertiende verdieping | 21.21 buitenwanden - constructief, massieve wanden (Uniformat) | Group: Model Group:NLRS_01.00_verdieping 11--17_gen:4845057
3 x Basic Wall:NLRS_21.21_WA_beton prefab d=250_gen:4845019 | 14 veertiende verdieping | 21.21 buitenwanden - constructief, massieve wanden (Uniformat) | Group: Model Group:NLRS_01.00_verdieping 11--17_gen:4845057
2 x Basic Wall:NLRS_22.21_WA_beton ihwg d=250_gen:4845024 | 14 veertiende verdieping | 22.21 binnenwanden - constructief, massieve wanden (Uniformat) | Group: Model Group:NLRS_01.00_verdieping 11--17_gen:4845057
Basic Wall:NLRS_22.21_WA_beton ihwg d=250_gen:4845026 | 14 veertiende verdieping | 22.21 binnenwanden - constructief, massieve wanden (Uniformat) | Group: Model Group:NLRS_01.00_verdieping 11--17_gen:4845057
Basic Wall:NLRS_22.21_WA_beton ihwg d=250_gen:4845034 | 14 veertiende verdieping | 22.21 binnenwanden - constructief, massieve wanden (Uniformat) | Group: Model Group:NLRS_01.00_verdieping 11--17_gen:4845057
Basic Wall:NLRS_22.21_WA_beton ihwg d=250_gen:4845036 | 14 veertiende verdieping | 22.21 binnenwanden - constructief, massieve wanden (Uniformat) | Group: Model Group:NLRS_01.00_verdieping 11--17_gen:4845057
3 x Basic Wall:NLRS_22.21_WA_beton prefab d=200_gen:4845039 | 14 veertiende verdieping | 22.21 binnenwanden - constructief, massieve wanden (Uniformat) | Group: Model Group:NLRS_01.00_verdieping 11--17_gen:4845057
2 x Basic Wall:NLRS_22.21_WA_beton prefab d=200_gen:1312531 | 14 veertiende verdieping | 22.21 binnenwanden - constructief, massieve wanden (Uniformat) | Group: Model Group:NLRS_01.00_verdieping 11--17_gen:4845057
3 x Basic Wall:NLRS_21.21_WA_beton prefab d=270_gen:4845063 | 15 vijftiende verdieping | 21.21 buitenwanden - constructief, massieve wanden (Uniformat) | Group: Model Group:NLRS_01.00_verdieping 11--17_gen:4845126
3 x Basic Wall:NLRS_21.21_WA_beton prefab d=250_gen:4845068 | 15 vijftiende verdieping | 21.21 buitenwanden - constructief, massieve wanden (Uniformat) | Group: Model Group:NLRS_01.00_verdieping 11--17_gen:4845126
4 x Basic Wall:NLRS_21.21_WA_beton prefab d=250_gen:1307923 | 15 vijftiende verdieping | 21.21 buitenwanden - constructief, massieve wanden (Uniformat) | Group: Model Group:NLRS_01.00_verdieping 11--17_gen:4845126
3 x Basic Wall:NLRS_21.21_WA_beton prefab d=250_gen:4845073 | 15 vijftiende verdieping | 21.21 buitenwanden - constructief, massieve wanden (Uniformat) | Group: Model Group:NLRS_01.00_verdieping 11--17_gen:4845126
3 x Basic Wall:NLRS_21.21_WA_beton prefab d=250_gen:4845078 | 15 vijftiende verdieping | 21.21 buitenwanden - constructief, massieve wanden (Uniformat) | Group: Model Group:NLRS_01.00_verdieping 11--17_gen:4845126
3 x Basic Wall:NLRS_21.21_WA_beton prefab d=270_gen:4845083 | 15 vijftiende verdieping | 21.21 buitenwanden - constructief, massieve wanden (Uniformat) | Group: Model Group:NLRS_01.00_verdieping 11--17_gen:4845126
3 x Basic Wall:NLRS_21.21_WA_beton prefab d=250_gen:4845088 | 15 vijftiende verdieping | 21.21 buitenwanden - constructief, massieve wanden (Uniformat) | Group: Model Group:NLRS_01.00_verdieping 11--17_gen:4845126
2 x Basic Wall:NLRS_22.21_WA_beton ihwg d=250_gen:4845093 | 15 vijftiende verdieping | 22.21 binnenwanden - constructief, massieve wanden (Uniformat) | Group: Model Group:NLRS_01.00_verdieping 11--17_gen:4845126
Basic Wall:NLRS_22.21_WA_beton ihwg d=250_gen:4845095 | 15 vijftiende verdieping | 22.21 binnenwanden - constructief, massieve wanden (Uniformat) | Group: Model Group:NLRS_01.00_verdieping 11--17_gen:4845126
Basic Wall:NLRS_22.21_WA_beton ihwg d=250_gen:4845103 | 15 vijftiende verdieping | 22.21 binnenwanden - constructief, massieve wanden (Uniformat) | Group: Model Group:NLRS_01.00_verdieping 11--17_gen:4845126
Basic Wall:NLRS_22.21_WA_beton ihwg d=250_gen:4845105 | 15 vijftiende verdieping | 22.21 binnenwanden - constructief, massieve wanden (Uniformat) | Group: Model Group:NLRS_01.00_verdieping 11--17_gen:4845126
3 x Basic Wall:NLRS_22.21_WA_beton prefab d=200_gen:4845108 | 15 vijftiende verdieping | 22.21 binnenwanden - constructief, massieve wanden (Uniformat) | Group: Model Group:NLRS_01.00_verdieping 11--17_gen:4845126
2 x Basic Wall:NLRS_22.21_WA_beton prefab d=200_gen:1312531 | 15 vijftiende verdieping | 22.21 binnenwanden - constructief, massieve wanden (Uniformat) | Group: Model Group:NLRS_01.00_verdieping 11--17_gen:4845126
3 x Basic Wall:NLRS_21.21_WA_beton prefab d=270_gen:4845132 | 16 zestiende verdieping | 21.21 buitenwanden - constructief, massieve wanden (Uniformat) | Group: Model Group:NLRS_01.00_verdieping 11--17_gen:4845195
3 x Basic Wall:NLRS_21.21_WA_beton prefab d=250_gen:4845137 | 16 zestiende verdieping | 21.21 buitenwanden - constructief, massieve wanden (Uniformat) | Group: Model Group:NLRS_01.00_verdieping 11--17_gen:4845195
4 x Basic Wall:NLRS_21.21_WA_beton prefab d=250_gen:1307923 | 16 zestiende verdieping | 21.21 buitenwanden - constructief, massieve wanden (Uniformat) | Group: Model Group:NLRS_01.00_verdieping 11--17_gen:4845195
3 x Basic Wall:NLRS_21.21_WA_beton prefab d=250_gen:4845142 | 16 zestiende verdieping | 21.21 buitenwanden - constructief, massieve wanden (Uniformat) | Group: Model Group:NLRS_01.00_verdieping 11--17_gen:4845195
3 x Basic Wall:NLRS_21.21_WA_beton prefab d=250_gen:4845147 | 16 zestiende verdieping | 21.21 buitenwanden - constructief, massieve wanden (Uniformat) | Group: Model Group:NLRS_01.00_verdieping 11--17_gen:4845195
3 x Basic Wall:NLRS_21.21_WA_beton prefab d=270_gen:4845152 | 16 zestiende verdieping | 21.21 buitenwanden - constructief, massieve wanden (Uniformat) | Group: Model Group:NLRS_01.00_verdieping 11--17_gen:4845195
3 x Basic Wall:NLRS_21.21_WA_beton prefab d=250_gen:4845157 | 16 zestiende verdieping | 21.21 buitenwanden - constructief, massieve wanden (Uniformat) | Group: Model Group:NLRS_01.00_verdieping 11--17_gen:4845195
2 x Basic Wall:NLRS_22.21_WA_beton ihwg d=250_gen:4845162 | 16 zestiende verdieping | 22.21 binnenwanden - constructief, massieve wanden (Uniformat) | Group: Model Group:NLRS_01.00_verdieping 11--17_gen:4845195
Basic Wall:NLRS_22.21_WA_beton ihwg d=250_gen:4845164 | 16 zestiende verdieping | 22.21 binnenwanden - constructief, massieve wanden (Uniformat) | Group: Model Group:NLRS_01.00_verdieping 11--17_gen:4845195
Basic Wall:NLRS_22.21_WA_beton ihwg d=250_gen:4845172 | 16 zestiende verdieping | 22.21 binnenwanden - constructief, massieve wanden (Uniformat) | Group: Model Group:NLRS_01.00_verdieping 11--17_gen:4845195
Basic Wall:NLRS_22.21_WA_beton ihwg d=250_gen:4845174 | 16 zestiende verdieping | 22.21 binnenwanden - constructief, massieve wanden (Uniformat) | Group: Model Group:NLRS_01.00_verdieping 11--17_gen:4845195
3 x Basic Wall:NLRS_22.21_WA_beton prefab d=200_gen:4845177 | 16 zestiende verdieping | 22.21 binnenwanden - constructief, massieve wanden (Uniformat) | Group: Model Group:NLRS_01.00_verdieping 11--17_gen:4845195
2 x Basic Wall:NLRS_22.21_WA_beton prefab d=200_gen:1312531 | 16 zestiende verdieping | 22.21 binnenwanden - constructief, massieve wanden (Uniformat) | Group: Model Group:NLRS_01.00_verdieping 11--17_gen:4845195
3 x Basic Wall:NLRS_21.21_WA_beton prefab d=270_gen:4845201 | 17 zeventiende verdieping | 21.21 buitenwanden - constructief, massieve wanden (Uniformat) | Group: Model Group:NLRS_01.00_verdieping 11--17_gen:4845336
3 x Basic Wall:NLRS_21.21_WA_beton prefab d=250_gen:4845206 | 17 zeventiende verdieping | 21.21 buitenwanden - constructief, massieve wanden (Uniformat) | Group: Model Group:NLRS_01.00_verdieping 11--17_gen:4845336
4 x Basic Wall:NLRS_21.21_WA_beton prefab d=250_gen:1307923 | 17 zeventiende verdieping | 21.21 buitenwanden - constructief, massieve wanden (Uniformat) | Group: Model Group:NLRS_01.00_verdieping 11--17_gen:4845336
3 x Basic Wall:NLRS_21.21_WA_beton prefab d=250_gen:4845211 | 17 zeventiende verdieping | 21.21 buitenwanden - constructief, massieve wanden (Uniformat) | Group: Model Group:NLRS_01.00_verdieping 11--17_gen:4845336
3 x Basic Wall:NLRS_21.21_WA_beton prefab d=250_gen:4845216 | 17 zeventiende verdieping | 21.21 buitenwanden - constructief, massieve wanden (Uniformat) | Group: Model Group:NLRS_01.00_verdieping 11--17_gen:4845336
3 x Basic Wall:NLRS_21.21_WA_beton prefab d=270_gen:4845221 | 17 zeventiende verdieping | 21.21 buitenwanden - constructief, massieve wanden (Uniformat) | Group: Model Group:NLRS_01.00_verdieping 11--17_gen:4845336
3 x Basic Wall:NLRS_21.21_WA_beton prefab d=250_gen:4845226 | 17 zeventiende verdieping | 21.21 buitenwanden - constructief, massieve wanden (Uniformat) | Group: Model Group:NLRS_01.00_verdieping 11--17_gen:4845336
2 x Basic Wall:NLRS_22.21_WA_beton ihwg d=250_gen:4845231 | 17 zeventiende verdieping | 22.21 binnenwanden - constructief, massieve wanden (Uniformat) | Group: Model Group:NLRS_01.00_verdieping 11--17_gen:4845336
Basic Wall:NLRS_22.21_WA_beton ihwg d=250_gen:4845233 | 17 zeventiende verdieping | 22.21 binnenwanden - constructief, massieve wanden (Uniformat) | Group: Model Group:NLRS_01.00_verdieping 11--17_gen:4845336
Basic Wall:NLRS_22.21_WA_beton ihwg d=250_gen:4845241 | 17 zeventiende verdieping | 22.21 binnenwanden - constructief, massieve wanden (Uniformat) | Group: Model Group:NLRS_01.00_verdieping 11--17_gen:4845336
Basic Wall:NLRS_22.21_WA_beton ihwg d=250_gen:4845243 | 17 zeventiende verdieping | 22.21 binnenwanden - constructief, massieve wanden (Uniformat) | Group: Model Group:NLRS_01.00_verdieping 11--17_gen:4845336
3 x Basic Wall:NLRS_22.21_WA_beton prefab d=200_gen:4845246 | 17 zeventiende verdieping | 22.21 binnenwanden - constructief, massieve wanden (Uniformat) | Group: Model Group:NLRS_01.00_verdieping 11--17_gen:4845336
2 x Basic Wall:NLRS_22.21_WA_beton prefab d=200_gen:1312531 | 17 zeventiende verdieping | 22.21 binnenwanden - constructief, massieve wanden (Uniformat) | Group: Model Group:NLRS_01.00_verdieping 11--17_gen:4845336
4 x  | 18 achttiende verdieping | 23.21 vloeren - constructief, vrijdragende vloeren (Uniformat) | Group: Model Group:NLRS_01.00_verdieping 18-19_gen:4845405
Floor:NLRS_23.21_FL_beton ihwg d=250_gen:4845259:2 | 18 achttiende verdieping | 23.21 vloeren - constructief, vrijdragende vloeren (Uniformat) | Group: Model Group:NLRS_01.00_verdieping 18-19_gen:4845405
3 x Basic Wall:NLRS_21.21_WA_beton prefab d=270_gen:4845342 | 18 achttiende verdieping | 21.21 buitenwanden - constructief, massieve wanden (Uniformat) | Group: Model Group:NLRS_01.00_verdieping 18-19_gen:4845405
3 x Basic Wall:NLRS_21.21_WA_beton prefab d=250_gen:4845347 | 18 achttiende verdieping | 21.21 buitenwanden - constructief, massieve wanden (Uniformat) | Group: Model Group:NLRS_01.00_verdieping 18-19_gen:4845405
4 x Basic Wall:NLRS_21.21_WA_beton prefab d=250_gen:1307923 | 18 achttiende verdieping | 21.21 buitenwanden - constructief, massieve wanden (Uniformat) | Group: Model Group:NLRS_01.00_verdieping 18-19_gen:4845405
3 x Basic Wall:NLRS_21.21_WA_beton prefab d=250_gen:4845352 | 18 achttiende verdieping | 21.21 buitenwanden - constructief, massieve wanden (Uniformat) | Group: Model Group:NLRS_01.00_verdieping 18-19_gen:4845405
3 x Basic Wall:NLRS_21.21_WA_beton prefab d=250_gen:4845357 | 18 achttiende verdieping | 21.21 buitenwanden - constructief, massieve wanden (Uniformat) | Group: Model Group:NLRS_01.00_verdieping 18-19_gen:4845405
3 x Basic Wall:NLRS_21.21_WA_beton prefab d=270_gen:4845362 | 18 achttiende verdieping | 21.21 buitenwanden - constructief, massieve wanden (Uniformat) | Group: Model Group:NLRS_01.00_verdieping 18-19_gen:4845405
3 x Basic Wall:NLRS_21.21_WA_beton prefab d=250_gen:4845367 | 18 achttiende verdieping | 21.21 buitenwanden - constructief, massieve wanden (Uniformat) | Group: Model Group:NLRS_01.00_verdieping 18-19_gen:4845405
2 x Basic Wall:NLRS_22.21_WA_beton ihwg d=250_gen:4845372 | 18 achttiende verdieping | 22.21 binnenwanden - constructief, massieve wanden (Uniformat) | Group: Model Group:NLRS_01.00_verdieping 18-19_gen:4845405
Basic Wall:NLRS_22.21_WA_beton ihwg d=250_gen:4845374 | 18 achttiende verdieping | 22.21 binnenwanden - constructief, massieve wanden (Uniformat) | Group: Model Group:NLRS_01.00_verdieping 18-19_gen:4845405
Basic Wall:NLRS_22.21_WA_beton ihwg d=250_gen:4845382 | 18 achttiende verdieping | 22.21 binnenwanden - constructief, massieve wanden (Uniformat) | Group: Model Group:NLRS_01.00_verdieping 18-19_gen:4845405
Basic Wall:NLRS_22.21_WA_beton ihwg d=250_gen:4845384 | 18 achttiende verdieping | 22.21 binnenwanden - constructief, massieve wanden (Uniformat) | Group: Model Group:NLRS_01.00_verdieping 18-19_gen:4845405
3 x Basic Wall:NLRS_22.21_WA_beton prefab d=200_gen:4845387 | 18 achttiende verdieping | 22.21 binnenwanden - constructief, massieve wanden (Uniformat) | Group: Model Group:NLRS_01.00_verdieping 18-19_gen:4845405
2 x Basic Wall:NLRS_22.21_WA_beton prefab d=200_gen:1312531 | 18 achttiende verdieping | 22.21 binnenwanden - constructief, massieve wanden (Uniformat) | Group: Model Group:NLRS_01.00_verdieping 18-19_gen:4845405
3 x Basic Wall:NLRS_21.21_WA_beton prefab d=270_gen:4845411 | 19 negentiende verdieping | 21.21 buitenwanden - constructief, massieve wanden (Uniformat) | Group: Model Group:NLRS_01.00_verdieping 18-19_gen:4845546
3 x Basic Wall:NLRS_21.21_WA_beton prefab d=250_gen:4845416 | 19 negentiende verdieping | 21.21 buitenwanden - constructief, massieve wanden (Uniformat) | Group: Model Group:NLRS_01.00_verdieping 18-19_gen:4845546
4 x Basic Wall:NLRS_21.21_WA_beton prefab d=250_gen:1307923 | 19 negentiende verdieping | 21.21 buitenwanden - constructief, massieve wanden (Uniformat) | Group: Model Group:NLRS_01.00_verdieping 18-19_gen:4845546
3 x Basic Wall:NLRS_21.21_WA_beton prefab d=250_gen:4845421 | 19 negentiende verdieping | 21.21 buitenwanden - constructief, massieve wanden (Uniformat) | Group: Model Group:NLRS_01.00_verdieping 18-19_gen:4845546
3 x Basic Wall:NLRS_21.21_WA_beton prefab d=250_gen:4845426 | 19 negentiende verdieping | 21.21 buitenwanden - constructief, massieve wanden (Uniformat) | Group: Model Group:NLRS_01.00_verdieping 18-19_gen:4845546
3 x Basic Wall:NLRS_21.21_WA_beton prefab d=270_gen:4845431 | 19 negentiende verdieping | 21.21 buitenwanden - constructief, massieve wanden (Uniformat) | Group: Model Group:NLRS_01.00_verdieping 18-19_gen:4845546
3 x Basic Wall:NLRS_21.21_WA_beton prefab d=250_gen:4845436 | 19 negentiende verdieping | 21.21 buitenwanden - constructief, massieve wanden (Uniformat) | Group: Model Group:NLRS_01.00_verdieping 18-19_gen:4845546
4 x Basic Wall:NLRS_22.21_WA_beton ihwg d=250_gen:4845441 | 19 negentiende verdieping | 22.21 binnenwanden - constructief, massieve wanden (Uniformat) | Group: Model Group:NLRS_01.00_verdieping 18-19_gen:4845546
Basic Wall:NLRS_22.21_WA_beton ihwg d=250_gen:4845443 | 19 negentiende verdieping | 22.21 binnenwanden - constructief, massieve wanden (Uniformat) | Group: Model Group:NLRS_01.00_verdieping 18-19_gen:4845546
Basic Wall:NLRS_22.21_WA_beton ihwg d=250_gen:4845451 | 19 negentiende verdieping | 22.21 binnenwanden - constructief, massieve wanden (Uniformat) | Group: Model Group:NLRS_01.00_verdieping 18-19_gen:4845546
Basic Wall:NLRS_22.21_WA_beton ihwg d=250_gen:4845453 | 19 negentiende verdieping | 22.21 binnenwanden - constructief, massieve wanden (Uniformat) | Group: Model Group:NLRS_01.00_verdieping 18-19_gen:4845546
3 x Basic Wall:NLRS_22.21_WA_beton prefab d=200_gen:4845456 | 19 negentiende verdieping | 22.21 binnenwanden - constructief, massieve wanden (Uniformat) | Group: Model Group:NLRS_01.00_verdieping 18-19_gen:4845546
2 x Basic Wall:NLRS_22.21_WA_beton prefab d=200_gen:1312531 | 19 negentiende verdieping | 22.21 binnenwanden - constructief, massieve wanden (Uniformat) | Group: Model Group:NLRS_01.00_verdieping 18-19_gen:4845546
4 x  | 20 twintigste verdieping | 23.21 vloeren - constructief, vrijdragende vloeren (Uniformat) | Group: Model Group:NLRS_01.00_verdieping 20_gen:4845671
Floor:NLRS_23.21_FL_beton ihwg d=250_gen:4845469:2 | 20 twintigste verdieping | 23.21 vloeren - constructief, vrijdragende vloeren (Uniformat) | Group: Model Group:NLRS_01.00_verdieping 20_gen:4845671
3 x Basic Wall:NLRS_21.21_WA_beton prefab d=270_gen:4845552 | 20 twintigste verdieping | 21.21 buitenwanden - constructief, massieve wanden (Uniformat) | Group: Model Group:NLRS_01.00_verdieping 20_gen:4845671
3 x Basic Wall:NLRS_21.21_WA_beton prefab d=250_gen:4845557 | 20 twintigste verdieping | 21.21 buitenwanden - constructief, massieve wanden (Uniformat) | Group: Model Group:NLRS_01.00_verdieping 20_gen:4845671
3 x Basic Wall:NLRS_21.21_WA_beton prefab d=250_gen:4845562 | 20 twintigste verdieping | 21.21 buitenwanden - constructief, massieve wanden (Uniformat) | Group: Model Group:NLRS_01.00_verdieping 20_gen:4845671
3 x Basic Wall:NLRS_21.21_WA_beton prefab d=250_gen:4845567 | 20 twintigste verdieping | 21.21 buitenwanden - constructief, massieve wanden (Uniformat) | Group: Model Group:NLRS_01.00_verdieping 20_gen:4845671
3 x Basic Wall:NLRS_21.21_WA_beton prefab d=270_gen:4845572 | 20 twintigste verdieping | 21.21 buitenwanden - constructief, massieve wanden (Uniformat) | Group: Model Group:NLRS_01.00_verdieping 20_gen:4845671
3 x Basic Wall:NLRS_21.21_WA_beton prefab d=250_gen:4845577 | 20 twintigste verdieping | 21.21 buitenwanden - constructief, massieve wanden (Uniformat) | Group: Model Group:NLRS_01.00_verdieping 20_gen:4845671
Basic Wall:NLRS_22.21_WA_beton ihwg d=250_gen:4845584 | 20 twintigste verdieping | 22.21 binnenwanden - constructief, massieve wanden (Uniformat) | Group: Model Group:NLRS_01.00_verdieping 20_gen:4845671
Basic Wall:NLRS_22.21_WA_beton ihwg d=250_gen:4845589 | 20 twintigste verdieping | 22.21 binnenwanden - constructief, massieve wanden (Uniformat) | Group: Model Group:NLRS_01.00_verdieping 20_gen:4845671
Basic Wall:NLRS_22.21_WA_beton ihwg d=250_gen:4845591 | 20 twintigste verdieping | 22.21 binnenwanden - constructief, massieve wanden (Uniformat) | Group: Model Group:NLRS_01.00_verdieping 20_gen:4845671
3 x Basic Wall:NLRS_22.21_WA_beton prefab d=200_gen:4845594 | 20 twintigste verdieping | 22.21 binnenwanden - constructief, massieve wanden (Uniformat) | Group: Model Group:NLRS_01.00_verdieping 20_gen:4845671
2 x Basic Wall:NLRS_22.21_WA_beton prefab d=200_gen:1312531 | 20 twintigste verdieping | 22.21 binnenwanden - constructief, massieve wanden (Uniformat) | Group: Model Group:NLRS_01.00_verdieping 20_gen:4845671
4 x  | 21 eenentwintigste verdieping | 23.21 vloeren - constructief, vrijdragende vloeren (Uniformat) | Group: Model Group:NLRS_01.00_verdieping 21--23_gen (members excluded):4846692
Floor:NLRS_23.21_FL_beton ihwg d=250_gen:4845607:2 | 21 eenentwintigste verdieping | 23.21 vloeren - constructief, vrijdragende vloeren (Uniformat) | Group: Model Group:NLRS_01.00_verdieping 21--23_gen (members excluded):4846692
3 x Basic Wall:NLRS_22.21_WA_beton ihwg d=250_gen:4845643 | 20 twintigste verdieping | 22.21 binnenwanden - constructief, massieve wanden (Uniformat) | Group: Model Group:NLRS_01.00_verdieping 20_gen:4845671
Basic Wall:NLRS_22.21_WA_beton ihwg d=250_gen:4845649 | 21 eenentwintigste verdieping | 22.21 binnenwanden - constructief, massieve wanden (Uniformat) | Group: Model Group:NLRS_01.00_verdieping 21--23_gen (members excluded):4846692
Basic Wall:NLRS_22.21_WA_beton ihwg d=250_gen:4845651 | 21 eenentwintigste verdieping | 22.21 binnenwanden - constructief, massieve wanden (Uniformat) | Group: Model Group:NLRS_01.00_verdieping 21--23_gen (members excluded):4846692
Basic Wall:NLRS_22.21_WA_beton ihwg d=250_gen:4845653 | 21 eenentwintigste verdieping | 22.21 binnenwanden - constructief, massieve wanden (Uniformat) | Group: Model Group:NLRS_01.00_verdieping 21--23_gen (members excluded):4846692
6 x Basic Wall:NLRS_22.21_WA_beton prefab d=200_gen:4845656 | 21 eenentwintigste verdieping | 22.21 binnenwanden - constructief, massieve wanden (Uniformat) | Group: Model Group:NLRS_01.00_verdieping 21--23_gen (members excluded):4846692
3 x Basic Wall:NLRS_22.21_WA_beton prefab d=200_gen:4845658 | 21 eenentwintigste verdieping | 22.21 binnenwanden - constructief, massieve wanden (Uniformat) | Group: Model Group:NLRS_01.00_verdieping 21--23_gen (members excluded):4846692
2 x Basic Wall:NLRS_22.21_WA_beton prefab d=200_gen:4845662 | 21 eenentwintigste verdieping | 22.21 binnenwanden - constructief, massieve wanden (Uniformat) | Group: Model Group:NLRS_01.00_verdieping 21--23_gen (members excluded):4846692
5 x Basic Wall:NLRS_22.21_WA_beton ihwg d=250_gen:4845669 | 21 eenentwintigste verdieping | 22.21 binnenwanden - constructief, massieve wanden (Uniformat) | Group: Model Group:NLRS_01.00_verdieping 21--23_gen (members excluded):4846692
3 x Basic Wall:NLRS_21.21_WA_beton prefab d=270_gen:4845683 | 05 vijfde verdieping | 21.21 buitenwanden - constructief, massieve wanden (Uniformat) | Group: Model Group:NLRS_01.00_verdieping 05_gen:6691052
3 x Basic Wall:NLRS_21.21_WA_beton prefab d=250_gen:4845688 | 05 vijfde verdieping | 21.21 buitenwanden - constructief, massieve wanden (Uniformat) | Group: Model Group:NLRS_01.00_verdieping 05_gen:6691052
3 x Basic Wall:NLRS_21.21_WA_beton prefab d=250_gen:1307923 | 05 vijfde verdieping | 21.21 buitenwanden - constructief, massieve wanden (Uniformat) | Group: Model Group:NLRS_01.00_verdieping 05_gen:6691052
3 x Basic Wall:NLRS_21.21_WA_beton prefab d=250_gen:4845693 | 05 vijfde verdieping | 21.21 buitenwanden - constructief, massieve wanden (Uniformat) | Group: Model Group:NLRS_01.00_verdieping 05_gen:6691052
3 x Basic Wall:NLRS_21.21_WA_beton prefab d=250_gen:4845698 | 05 vijfde verdieping | 21.21 buitenwanden - constructief, massieve wanden (Uniformat) | Group: Model Group:NLRS_01.00_verdieping 05_gen:6691052
3 x Basic Wall:NLRS_21.21_WA_beton prefab d=270_gen:4845703 | 05 vijfde verdieping | 21.21 buitenwanden - constructief, massieve wanden (Uniformat) | Group: Model Group:NLRS_01.00_verdieping 05_gen:6691052
3 x Basic Wall:NLRS_21.21_WA_beton prefab d=250_gen:4845708 | 06 zesde verdieping | 21.21 buitenwanden - constructief, massieve wanden (Uniformat) | Group: Model Group:NLRS_01.00_verdieping 05_gen:6691052
Basic Wall:NLRS_21.21_WA_beton prefab d=250_gen:1307923 | 06 zesde verdieping | 21.21 buitenwanden - constructief, massieve wanden (Uniformat) | Group: Model Group:NLRS_01.00_verdieping 05_gen:6691052
2 x Basic Wall:NLRS_22.21_WA_beton ihwg d=250_gen:4845713 | 05 vijfde verdieping | 22.21 binnenwanden - constructief, massieve wanden (Uniformat) | Group: Model Group:NLRS_01.00_verdieping 05_gen:6691052
Basic Wall:NLRS_22.21_WA_beton ihwg d=250_gen:4845715 | 05 vijfde verdieping | 22.21 binnenwanden - constructief, massieve wanden (Uniformat) | Group: Model Group:NLRS_01.00_verdieping 05_gen:6691052
Basic Wall:NLRS_22.21_WA_beton ihwg d=250_gen:4845723 | 05 vijfde verdieping | 22.21 binnenwanden - constructief, massieve wanden (Uniformat) | Group: Model Group:NLRS_01.00_verdieping 05_gen:6691052
Basic Wall:NLRS_22.21_WA_beton ihwg d=250_gen:4845727 | 05 vijfde verdieping | 22.21 binnenwanden - constructief, massieve wanden (Uniformat) | Group: Model Group:NLRS_01.00_verdieping 05_gen:6691052
Basic Wall:NLRS_22.21_WA_beton ihwg d=250_gen:4845729 | 05 vijfde verdieping | 22.21 binnenwanden - constructief, massieve wanden (Uniformat) | Group: Model Group:NLRS_01.00_verdieping 05_gen:6691052
3 x Basic Wall:NLRS_22.21_WA_beton prefab d=200_gen:4845734 | 05 vijfde verdieping | 22.21 binnenwanden - constructief, massieve wanden (Uniformat) | Group: Model Group:NLRS_01.00_verdieping 05_gen:6691052
2 x Basic Wall:NLRS_22.21_WA_beton prefab d=200_gen:1312531 | 05 vijfde verdieping | 22.21 binnenwanden - constructief, massieve wanden (Uniformat) | Group: Model Group:NLRS_01.00_verdieping 05_gen:6691052
3 x Basic Wall:NLRS_21.21_WA_beton prefab d=270_gen:4845758 | 11 elfde verdieping | 21.21 buitenwanden - constructief, massieve wanden (Uniformat) | Group: Model Group:NLRS_01.00_verdieping 11--17_gen:4845821
3 x Basic Wall:NLRS_21.21_WA_beton prefab d=250_gen:4845763 | 11 elfde verdieping | 21.21 buitenwanden - constructief, massieve wanden (Uniformat) | Group: Model Group:NLRS_01.00_verdieping 11--17_gen:4845821
4 x Basic Wall:NLRS_21.21_WA_beton prefab d=250_gen:1307923 | 11 elfde verdieping | 21.21 buitenwanden - constructief, massieve wanden (Uniformat) | Group: Model Group:NLRS_01.00_verdieping 11--17_gen:4845821
3 x Basic Wall:NLRS_21.21_WA_beton prefab d=250_gen:4845768 | 11 elfde verdieping | 21.21 buitenwanden - constructief, massieve wanden (Uniformat) | Group: Model Group:NLRS_01.00_verdieping 11--17_gen:4845821
3 x Basic Wall:NLRS_21.21_WA_beton prefab d=250_gen:4845773 | 11 elfde verdieping | 21.21 buitenwanden - constructief, massieve wanden (Uniformat) | Group: Model Group:NLRS_01.00_verdieping 11--17_gen:4845821
3 x Basic Wall:NLRS_21.21_WA_beton prefab d=270_gen:4845778 | 11 elfde verdieping | 21.21 buitenwanden - constructief, massieve wanden (Uniformat) | Group: Model Group:NLRS_01.00_verdieping 11--17_gen:4845821
3 x Basic Wall:NLRS_21.21_WA_beton prefab d=250_gen:4845783 | 11 elfde verdieping | 21.21 buitenwanden - constructief, massieve wanden (Uniformat) | Group: Model Group:NLRS_01.00_verdieping 11--17_gen:4845821
2 x Basic Wall:NLRS_22.21_WA_beton ihwg d=250_gen:4845788 | 11 elfde verdieping | 22.21 binnenwanden - constructief, massieve wanden (Uniformat) | Group: Model Group:NLRS_01.00_verdieping 11--17_gen:4845821
Basic Wall:NLRS_22.21_WA_beton ihwg d=250_gen:4845790 | 11 elfde verdieping | 22.21 binnenwanden - constructief, massieve wanden (Uniformat) | Group: Model Group:NLRS_01.00_verdieping 11--17_gen:4845821
Basic Wall:NLRS_22.21_WA_beton ihwg d=250_gen:4845798 | 11 elfde verdieping | 22.21 binnenwanden - constructief, massieve wanden (Uniformat) | Group: Model Group:NLRS_01.00_verdieping 11--17_gen:4845821
Basic Wall:NLRS_22.21_WA_beton ihwg d=250_gen:4845800 | 11 elfde verdieping | 22.21 binnenwanden - constructief, massieve wanden (Uniformat) | Group: Model Group:NLRS_01.00_verdieping 11--17_gen:4845821
3 x Basic Wall:NLRS_22.21_WA_beton prefab d=200_gen:4845803 | 11 elfde verdieping | 22.21 binnenwanden - constructief, massieve wanden (Uniformat) | Group: Model Group:NLRS_01.00_verdieping 11--17_gen:4845821
2 x Basic Wall:NLRS_22.21_WA_beton prefab d=200_gen:1312531 | 11 elfde verdieping | 22.21 binnenwanden - constructief, massieve wanden (Uniformat) | Group: Model Group:NLRS_01.00_verdieping 11--17_gen:4845821
4 x  | 06 zesde verdieping | 23.21 vloeren - constructief, vrijdragende vloeren (Uniformat) | Group: Model Group:NLRS_01.00_verdieping 06--10_gen:4844478
Floor:NLRS_23.21_FL_beton ihwg d=250_gen:4845823:2 | 06 zesde verdieping | 23.21 vloeren - constructief, vrijdragende vloeren (Uniformat) | Group: Model Group:NLRS_01.00_verdieping 06--10_gen:4844478
4 x  | 07 zevende verdieping | 23.21 vloeren - constructief, vrijdragende vloeren (Uniformat) | Group: Model Group:NLRS_01.00_verdieping 06--10_gen:4844553
Floor:NLRS_23.21_FL_beton ihwg d=250_gen:4845887:2 | 07 zevende verdieping | 23.21 vloeren - constructief, vrijdragende vloeren (Uniformat) | Group: Model Group:NLRS_01.00_verdieping 06--10_gen:4844553
4 x  | 08 achtste verdieping | 23.21 vloeren - constructief, vrijdragende vloeren (Uniformat) | Group: Model Group:NLRS_01.00_verdieping 06--10_gen:4844628
Floor:NLRS_23.21_FL_beton ihwg d=250_gen:4845951:2 | 08 achtste verdieping | 23.21 vloeren - constructief, vrijdragende vloeren (Uniformat) | Group: Model Group:NLRS_01.00_verdieping 06--10_gen:4844628
4 x  | 09 negende verdieping | 23.21 vloeren - constructief, vrijdragende vloeren (Uniformat) | Group: Model Group:NLRS_01.00_verdieping 06--10_gen:4844703
Floor:NLRS_23.21_FL_beton ihwg d=250_gen:4846015:2 | 09 negende verdieping | 23.21 vloeren - constructief, vrijdragende vloeren (Uniformat) | Group: Model Group:NLRS_01.00_verdieping 06--10_gen:4844703
4 x  | 10 tiende verdieping | 23.21 vloeren - constructief, vrijdragende vloeren (Uniformat) | Group: Model Group:NLRS_01.00_verdieping 06--10_gen:4844850
Floor:NLRS_23.21_FL_beton ihwg d=250_gen:4846079:2 | 10 tiende verdieping | 23.21 vloeren - constructief, vrijdragende vloeren (Uniformat) | Group: Model Group:NLRS_01.00_verdieping 06--10_gen:4844850
4 x  | 12 twaalfde verdieping | 23.21 vloeren - constructief, vrijdragende vloeren (Uniformat) | Group: Model Group:NLRS_01.00_verdieping 11--17_gen:4844919
Floor:NLRS_23.21_FL_beton ihwg d=250_gen:4846183:2 | 12 twaalfde verdieping | 23.21 vloeren - constructief, vrijdragende vloeren (Uniformat) | Group: Model Group:NLRS_01.00_verdieping 11--17_gen:4844919
4 x  | 13 dertiende verdieping | 23.21 vloeren - constructief, vrijdragende vloeren (Uniformat) | Group: Model Group:NLRS_01.00_verdieping 11--17_gen:4844988
Floor:NLRS_23.21_FL_beton ihwg d=250_gen:4846255:2 | 13 dertiende verdieping | 23.21 vloeren - constructief, vrijdragende vloeren (Uniformat) | Group: Model Group:NLRS_01.00_verdieping 11--17_gen:4844988
4 x  | 14 veertiende verdieping | 23.21 vloeren - constructief, vrijdragende vloeren (Uniformat) | Group: Model Group:NLRS_01.00_verdieping 11--17_gen:4845057
Floor:NLRS_23.21_FL_beton ihwg d=250_gen:4846327:2 | 14 veertiende verdieping | 23.21 vloeren - constructief, vrijdragende vloeren (Uniformat) | Group: Model Group:NLRS_01.00_verdieping 11--17_gen:4845057
4 x  | 15 vijftiende verdieping | 23.21 vloeren - constructief, vrijdragende vloeren (Uniformat) | Group: Model Group:NLRS_01.00_verdieping 11--17_gen:4845126
Floor:NLRS_23.21_FL_beton ihwg d=250_gen:4846399:2 | 15 vijftiende verdieping | 23.21 vloeren - constructief, vrijdragende vloeren (Uniformat) | Group: Model Group:NLRS_01.00_verdieping 11--17_gen:4845126
4 x  | 16 zestiende verdieping | 23.21 vloeren - constructief, vrijdragende vloeren (Uniformat) | Group: Model Group:NLRS_01.00_verdieping 11--17_gen:4845195
Floor:NLRS_23.21_FL_beton ihwg d=250_gen:4846471:2 | 16 zestiende verdieping | 23.21 vloeren - constructief, vrijdragende vloeren (Uniformat) | Group: Model Group:NLRS_01.00_verdieping 11--17_gen:4845195
4 x  | 17 zeventiende verdieping | 23.21 vloeren - constructief, vrijdragende vloeren (Uniformat) | Group: Model Group:NLRS_01.00_verdieping 11--17_gen:4845336
Floor:NLRS_23.21_FL_beton ihwg d=250_gen:4846543:2 | 17 zeventiende verdieping | 23.21 vloeren - constructief, vrijdragende vloeren (Uniformat) | Group: Model Group:NLRS_01.00_verdieping 11--17_gen:4845336
4 x  | 19 negentiende verdieping | 23.21 vloeren - constructief, vrijdragende vloeren (Uniformat) | Group: Model Group:NLRS_01.00_verdieping 18-19_gen:4845546
Floor:NLRS_23.21_FL_beton ihwg d=250_gen:4846615:2 | 19 negentiende verdieping | 23.21 vloeren - constructief, vrijdragende vloeren (Uniformat) | Group: Model Group:NLRS_01.00_verdieping 18-19_gen:4845546
2 x Basic Wall:NLRS_22.21_WA_beton ihwg d=250_gen:4846819 | 22 tweeëntwintigste verdieping | 22.21 binnenwanden - constructief, massieve wanden (Uniformat) | Group: Model Group:NLRS_01.00_verdieping 21--23_gen (members excluded):4846692
4 x Basic Wall:NLRS_22.21_WA_beton ihwg d=250_gen:4846825 | 22 tweeëntwintigste verdieping | 22.21 binnenwanden - constructief, massieve wanden (Uniformat) | Group: Model Group:NLRS_01.00_verdieping 21--23_gen (members excluded):4846692
Basic Wall:NLRS_22.21_WA_beton ihwg d=250_gen:4846833 | 22 tweeëntwintigste verdieping | 22.21 binnenwanden - constructief, massieve wanden (Uniformat) | Group: Model Group:NLRS_01.00_verdieping 21--23_gen (members excluded):4846692
Basic Wall:NLRS_22.21_WA_beton ihwg d=250_gen:4846837:1 | 22 tweeëntwintigste verdieping | 22.21 binnenwanden - constructief, massieve wanden (Uniformat) | Group: Model Group:NLRS_01.00_verdieping 21--23_gen (members excluded):4846692
Basic Wall:NLRS_22.21_WA_beton ihwg d=250_gen:4846837 | 22 tweeëntwintigste verdieping | 22.21 binnenwanden - constructief, massieve wanden (Uniformat) | Group: Model Group:NLRS_01.00_verdieping 21--23_gen (members excluded):4846692
Basic Wall:NLRS_22.21_WA_beton ihwg d=250_gen:1312528 | 22 tweeëntwintigste verdieping | 22.21 binnenwanden - constructief, massieve wanden (Uniformat) | Group: Model Group:NLRS_01.00_verdieping 21--23_gen (members excluded):4846692
3 x  | 22 tweeëntwintigste verdieping | 23.21 vloeren - constructief, vrijdragende vloeren (Uniformat) | Group: Model Group:NLRS_01.00_verdieping 21--23_gen (members excluded):4846692
Floor:NLRS_23.21_FL_beton ihwg d=250_gen:4846857:2 | 22 tweeëntwintigste verdieping | 23.21 vloeren - constructief, vrijdragende vloeren (Uniformat) | Group: Model Group:NLRS_01.00_verdieping 21--23_gen (members excluded):4846692
Floor:NLRS_23.21_FL_beton ihwg d=250_gen:4846883:2 | 22 tweeëntwintigste verdieping | 23.21 vloeren - constructief, vrijdragende vloeren (Uniformat) | Group: Model Group:NLRS_01.00_verdieping 21--23_gen (members excluded):4846692
3 x  | 23 dakverdieping | 23.21 vloeren - constructief, vrijdragende vloeren (Uniformat) | Group: Model Group:NLRS_01.00_verdieping 21--23_gen (members excluded):4846692
Floor:NLRS_23.21_FL_beton ihwg d=250_gen:4846936:2 | 23 dakverdieping | 23.21 vloeren - constructief, vrijdragende vloeren (Uniformat) | Group: Model Group:NLRS_01.00_verdieping 21--23_gen (members excluded):4846692
9 x Basic Wall:NLRS_21.21_WA_beton ihwg d=250_gen:4847173 | 04 vierde verdieping | 21.21 buitenwanden - constructief, massieve wanden (Uniformat) | Group: Model Group:NLRS_01.00_verdieping 04_gen (members excluded):4844403
9 x Basic Wall:NLRS_21.21_WA_beton ihwg d=250_gen:4847175 | 04 vierde verdieping | 21.21 buitenwanden - constructief, massieve wanden (Uniformat) | Group: Model Group:NLRS_01.00_verdieping 04_gen (members excluded):4844403
9 x Basic Wall:NLRS_21.21_WA_beton ihwg d=250_gen:4847177 | 06 zesde verdieping | 21.21 buitenwanden - constructief, massieve wanden (Uniformat) | Group: Model Group:NLRS_21.21_wand ihwg as L.P 06-20_gen:4844406
9 x Basic Wall:NLRS_21.21_WA_beton ihwg d=250_gen:4847179 | 06 zesde verdieping | 21.21 buitenwanden - constructief, massieve wanden (Uniformat) | Group: Model Group:NLRS_21.21_wand ihwg as L.P 06-20_gen:4844438
9 x Basic Wall:NLRS_21.21_WA_beton ihwg d=250_gen:4847181 | 07 zevende verdieping | 21.21 buitenwanden - constructief, massieve wanden (Uniformat) | Group: Model Group:NLRS_21.21_wand ihwg as L.P 06-20_gen:4844481
9 x Basic Wall:NLRS_21.21_WA_beton ihwg d=250_gen:4847183 | 07 zevende verdieping | 21.21 buitenwanden - constructief, massieve wanden (Uniformat) | Group: Model Group:NLRS_21.21_wand ihwg as L.P 06-20_gen:4844513
9 x Basic Wall:NLRS_21.21_WA_beton ihwg d=250_gen:4847185 | 08 achtste verdieping | 21.21 buitenwanden - constructief, massieve wanden (Uniformat) | Group: Model Group:NLRS_21.21_wand ihwg as L.P 06-20_gen:4844556
9 x Basic Wall:NLRS_21.21_WA_beton ihwg d=250_gen:4847187 | 08 achtste verdieping | 21.21 buitenwanden - constructief, massieve wanden (Uniformat) | Group: Model Group:NLRS_21.21_wand ihwg as L.P 06-20_gen:4844588
9 x Basic Wall:NLRS_21.21_WA_beton ihwg d=250_gen:4847189 | 09 negende verdieping | 21.21 buitenwanden - constructief, massieve wanden (Uniformat) | Group: Model Group:NLRS_21.21_wand ihwg as L.P 06-20_gen:4844631
9 x Basic Wall:NLRS_21.21_WA_beton ihwg d=250_gen:4847191 | 09 negende verdieping | 21.21 buitenwanden - constructief, massieve wanden (Uniformat) | Group: Model Group:NLRS_21.21_wand ihwg as L.P 06-20_gen:4844663
9 x Basic Wall:NLRS_21.21_WA_beton ihwg d=250_gen:4847193 | 10 tiende verdieping | 21.21 buitenwanden - constructief, massieve wanden (Uniformat) | Group: Model Group:NLRS_21.21_wand ihwg as L.P 06-20_gen:4844706
9 x Basic Wall:NLRS_21.21_WA_beton ihwg d=250_gen:4847195 | 10 tiende verdieping | 21.21 buitenwanden - constructief, massieve wanden (Uniformat) | Group: Model Group:NLRS_21.21_wand ihwg as L.P 06-20_gen:4844738
9 x Basic Wall:NLRS_21.21_WA_beton ihwg d=250_gen:4847197 | 12 twaalfde verdieping | 21.21 buitenwanden - constructief, massieve wanden (Uniformat) | Group: Model Group:NLRS_21.21_wand ihwg as L.P 06-20_gen:4844853
9 x Basic Wall:NLRS_21.21_WA_beton ihwg d=250_gen:4847199 | 12 twaalfde verdieping | 21.21 buitenwanden - constructief, massieve wanden (Uniformat) | Group: Model Group:NLRS_21.21_wand ihwg as L.P 06-20_gen:4844885
9 x Basic Wall:NLRS_21.21_WA_beton ihwg d=250_gen:4847201 | 13 dertiende verdieping | 21.21 buitenwanden - constructief, massieve wanden (Uniformat) | Group: Model Group:NLRS_21.21_wand ihwg as L.P 06-20_gen:4844922
9 x Basic Wall:NLRS_21.21_WA_beton ihwg d=250_gen:4847203 | 13 dertiende verdieping | 21.21 buitenwanden - constructief, massieve wanden (Uniformat) | Group: Model Group:NLRS_21.21_wand ihwg as L.P 06-20_gen:4844954
9 x Basic Wall:NLRS_21.21_WA_beton ihwg d=250_gen:4847205 | 14 veertiende verdieping | 21.21 buitenwanden - constructief, massieve wanden (Uniformat) | Group: Model Group:NLRS_21.21_wand ihwg as L.P 06-20_gen:4844991
9 x Basic Wall:NLRS_21.21_WA_beton ihwg d=250_gen:4847207 | 14 veertiende verdieping | 21.21 buitenwanden - constructief, massieve wanden (Uniformat) | Group: Model Group:NLRS_21.21_wand ihwg as L.P 06-20_gen:4845023
9 x Basic Wall:NLRS_21.21_WA_beton ihwg d=250_gen:4847209 | 15 vijftiende verdieping | 21.21 buitenwanden - constructief, massieve wanden (Uniformat) | Group: Model Group:NLRS_21.21_wand ihwg as L.P 06-20_gen:4845060
9 x Basic Wall:NLRS_21.21_WA_beton ihwg d=250_gen:4847211 | 15 vijftiende verdieping | 21.21 buitenwanden - constructief, massieve wanden (Uniformat) | Group: Model Group:NLRS_21.21_wand ihwg as L.P 06-20_gen:4845092
9 x Basic Wall:NLRS_21.21_WA_beton ihwg d=250_gen:4847213 | 16 zestiende verdieping | 21.21 buitenwanden - constructief, massieve wanden (Uniformat) | Group: Model Group:NLRS_21.21_wand ihwg as L.P 06-20_gen:4845129
9 x Basic Wall:NLRS_21.21_WA_beton ihwg d=250_gen:4847215 | 16 zestiende verdieping | 21.21 buitenwanden - constructief, massieve wanden (Uniformat) | Group: Model Group:NLRS_21.21_wand ihwg as L.P 06-20_gen:4845161
9 x Basic Wall:NLRS_21.21_WA_beton ihwg d=250_gen:4847217 | 17 zeventiende verdieping | 21.21 buitenwanden - constructief, massieve wanden (Uniformat) | Group: Model Group:NLRS_21.21_wand ihwg as L.P 06-20_gen:4845198
9 x Basic Wall:NLRS_21.21_WA_beton ihwg d=250_gen:4847219 | 17 zeventiende verdieping | 21.21 buitenwanden - constructief, massieve wanden (Uniformat) | Group: Model Group:NLRS_21.21_wand ihwg as L.P 06-20_gen:4845230
9 x Basic Wall:NLRS_21.21_WA_beton ihwg d=250_gen:4847221 | 18 achttiende verdieping | 21.21 buitenwanden - constructief, massieve wanden (Uniformat) | Group: Model Group:NLRS_21.21_wand ihwg as L.P 06-20_gen:4845339
9 x Basic Wall:NLRS_21.21_WA_beton ihwg d=250_gen:4847223 | 18 achttiende verdieping | 21.21 buitenwanden - constructief, massieve wanden (Uniformat) | Group: Model Group:NLRS_21.21_wand ihwg as L.P 06-20_gen:4845371
9 x Basic Wall:NLRS_21.21_WA_beton ihwg d=250_gen:4847225 | 19 negentiende verdieping | 21.21 buitenwanden - constructief, massieve wanden (Uniformat) | Group: Model Group:NLRS_21.21_wand ihwg as L.P 06-20_gen:4845408
9 x Basic Wall:NLRS_21.21_WA_beton ihwg d=250_gen:4847227 | 19 negentiende verdieping | 21.21 buitenwanden - constructief, massieve wanden (Uniformat) | Group: Model Group:NLRS_21.21_wand ihwg as L.P 06-20_gen:4845440
9 x Basic Wall:NLRS_21.21_WA_beton ihwg d=250_gen:4847229 | 20 twintigste verdieping | 21.21 buitenwanden - constructief, massieve wanden (Uniformat) | Group: Model Group:NLRS_21.21_wand ihwg as L.P 06-20_gen:4845549
9 x Basic Wall:NLRS_21.21_WA_beton ihwg d=250_gen:4847231 | 20 twintigste verdieping | 21.21 buitenwanden - constructief, massieve wanden (Uniformat) | Group: Model Group:NLRS_21.21_wand ihwg as L.P 06-20_gen:4845581
9 x Basic Wall:NLRS_21.21_WA_beton ihwg d=250_gen:4847233 | 05 vijfde verdieping | 21.21 buitenwanden - constructief, massieve wanden (Uniformat) | Group: Model Group:NLRS_21.21_wand ihwg as L.P 06-20_gen:4845680
9 x Basic Wall:NLRS_21.21_WA_beton ihwg d=250_gen:4847235 | 05 vijfde verdieping | 21.21 buitenwanden - constructief, massieve wanden (Uniformat) | Group: Model Group:NLRS_21.21_wand ihwg as L.P 06-20_gen:4845712
9 x Basic Wall:NLRS_21.21_WA_beton ihwg d=250_gen:4847237 | 11 elfde verdieping | 21.21 buitenwanden - constructief, massieve wanden (Uniformat) | Group: Model Group:NLRS_21.21_wand ihwg as L.P 06-20_gen:4845755
9 x Basic Wall:NLRS_21.21_WA_beton ihwg d=250_gen:4847239 | 11 elfde verdieping | 21.21 buitenwanden - constructief, massieve wanden (Uniformat) | Group: Model Group:NLRS_21.21_wand ihwg as L.P 06-20_gen:4845787
14 x Basic Wall:NLRS_22.21_WA_beton ihwg d=250_gen:4886314 | 00 begane grond | 22.21 binnenwanden - constructief, massieve wanden (Uniformat)
Basic Wall:NLRS_22.21_WA_beton ihwg d=250_gen:4887180 | 01 eerste verdieping | 22.21 binnenwanden - constructief, massieve wanden (Uniformat)
2 x Basic Wall:NLRS_21.21_WA_beton ihwg d=150_gen:4907957 | 04 vierde verdieping | 21.21 buitenwanden - constructief, massieve wanden (Uniformat) | Group: Model Group:NLRS_01.00_dakopbouw 01_gen:4907974
2 x Basic Wall:NLRS_21.21_WA_beton ihwg d=150_gen:4908057 | 04 vierde verdieping | 21.21 buitenwanden - constructief, massieve wanden (Uniformat) | Group: Model Group:NLRS_01.00_dakopbouw 01_gen:4908074
2 x Basic Wall:NLRS_21.21_WA_beton ihwg d=150_gen:4908127 | 04 vierde verdieping | 21.21 buitenwanden - constructief, massieve wanden (Uniformat) | Group: Model Group:NLRS_01.00_dakopbouw 01_gen:4908144
2 x Basic Wall:NLRS_21.21_WA_beton ihwg d=150_gen:4908203 | 04 vierde verdieping | 21.21 buitenwanden - constructief, massieve wanden (Uniformat)
Basic Wall:NLRS_21.21_WA_beton ihwg d=150_gen:4910168 | 04 vierde verdieping | 21.21 buitenwanden - constructief, massieve wanden (Uniformat) | Group: Model Group:NLRS_01.00_dakopbouw 02_gen:4910181
Basic Wall:NLRS_21.21_WA_beton ihwg d=150_gen:4910326 | 04 vierde verdieping | 21.21 buitenwanden - constructief, massieve wanden (Uniformat) | Group: Model Group:NLRS_01.00_dakopbouw 02_gen:4910339
Basic Wall:NLRS_21.21_WA_beton ihwg d=150_gen:4910426 | 04 vierde verdieping | 21.21 buitenwanden - constructief, massieve wanden (Uniformat) | Group: Model Group:NLRS_01.00_dakopbouw 02_gen:4910439
Basic Wall:NLRS_21.21_WA_beton ihwg d=150_gen:4910519 | 04 vierde verdieping | 21.21 buitenwanden - constructief, massieve wanden (Uniformat) | Group: Model Group:NLRS_01.00_dakopbouw 02_gen:4910532
Basic Wall:NLRS_22.21_WA_beton ihwg d=250_gen:5014890 | 00 begane grond | 22.21 binnenwanden - constructief, massieve wanden (Uniformat)
Basic Wall:NLRS_22.21_WA_beton ihwg d=250_gen:5014892 | 00 begane grond | 22.21 binnenwanden - constructief, massieve wanden (Uniformat)
5 x Basic Wall:NLRS_22.21_WA_beton ihwg d=250_gen:5014894 | 00 begane grond | 22.21 binnenwanden - constructief, massieve wanden (Uniformat)
7 x Basic Wall:NLRS_22.21_WA_beton ihwg d=250_gen:5014896 | 00 begane grond | 22.21 binnenwanden - constructief, massieve wanden (Uniformat)
Basic Wall:NLRS_22.21_WA_beton ihwg d=250_gen:5014910 | 00 begane grond | 22.21 binnenwanden - constructief, massieve wanden (Uniformat)
2 x Basic Wall:NLRS_22.21_WA_beton ihwg d=250_gen:5014960 | 01 eerste verdieping | 22.21 binnenwanden - constructief, massieve wanden (Uniformat)
2 x Basic Wall:NLRS_22.21_WA_beton ihwg d=250_gen:5014966 | 01 eerste verdieping | 22.21 binnenwanden - constructief, massieve wanden (Uniformat)
2 x Basic Wall:NLRS_22.21_WA_beton ihwg d=250_gen:1312528 | 02 tweede verdieping | 22.21 binnenwanden - constructief, massieve wanden (Uniformat)
2 x Basic Wall:NLRS_22.21_WA_beton ihwg d=250_gen:5014990 | 02 tweede verdieping | 22.21 binnenwanden - constructief, massieve wanden (Uniformat)
Basic Wall:NLRS_22.21_WA_beton ihwg d=250_gen:5014996 | 03 derde verdieping | 22.21 binnenwanden - constructief, massieve wanden (Uniformat)
Basic Wall:NLRS_22.21_WA_beton ihwg d=250_gen:5015004:1 | 03 derde verdieping | 22.21 binnenwanden - constructief, massieve wanden (Uniformat)
Basic Wall:NLRS_22.21_WA_beton ihwg d=250_gen:5015004 | 03 derde verdieping | 22.21 binnenwanden - constructief, massieve wanden (Uniformat)
2 x Basic Wall:NLRS_22.21_WA_beton ihwg d=250_gen:5015006 | 03 derde verdieping | 22.21 binnenwanden - constructief, massieve wanden (Uniformat)
Basic Wall:NLRS_22.21_WA_beton ihwg d=250_gen:5015404:1 | 02 tweede verdieping | 22.21 binnenwanden - constructief, massieve wanden (Uniformat)
4 x Basic Wall:NLRS_22.21_WA_beton prefab d=200_gen:5030617 | 00 begane grond | 22.21 binnenwanden - constructief, massieve wanden (Uniformat)
3 x Basic Wall:NLRS_22.21_WA_beton prefab d=200_gen:5030625 | 01a eerste tussenverdieping | 22.21 binnenwanden - constructief, massieve wanden (Uniformat)
3 x Basic Wall:NLRS_22.21_WA_beton prefab d=200_gen:5030633 | 01c derde tussenverdieping | 22.21 binnenwanden - constructief, massieve wanden (Uniformat)
3 x Basic Wall:NLRS_22.21_WA_beton prefab d=200_gen:5030639 | 02b tweede tussenverdieping | 22.21 binnenwanden - constructief, massieve wanden (Uniformat)
Basic Wall:NLRS_22.21_WA_beton ihwg d=250_gen:5095103 | 01 eerste verdieping | 22.21 binnenwanden - constructief, massieve wanden (Uniformat)
7 x Basic Wall:NLRS_21.21_WA_beton ihwg d=250_gen:5096675 | 21 eenentwintigste verdieping | 21.21 buitenwanden - constructief, massieve wanden (Uniformat) | Group: Model Group:NLRS_01.00_verdieping 21--23_gen (members excluded):4846692
7 x Basic Wall:NLRS_21.21_WA_beton ihwg d=250_gen:5097815 | 21 eenentwintigste verdieping | 21.21 buitenwanden - constructief, massieve wanden (Uniformat) | Group: Model Group:NLRS_01.00_verdieping 21--23_gen (members excluded):4647240
3 x Basic Wall:NLRS_21.21_WA_beton prefab d=250_gen:5102033 | 21 eenentwintigste verdieping | 21.21 buitenwanden - constructief, massieve wanden (Uniformat) | Group: Model Group:NLRS_01.00_verdieping 21--23_gen (members excluded):4846692
3 x Basic Wall:NLRS_21.21_WA_beton prefab d=250_gen:5103390 | 21 eenentwintigste verdieping | 21.21 buitenwanden - constructief, massieve wanden (Uniformat) | Group: Model Group:NLRS_01.00_verdieping 21--23_gen (members excluded):4647240
7 x Basic Wall:NLRS_21.21_WA_beton ihwg d=250_gen:5104569 | 21 eenentwintigste verdieping | 21.21 buitenwanden - constructief, massieve wanden (Uniformat) | Group: Model Group:NLRS_01.00_verdieping 21--23_gen (members excluded):4846692
7 x Basic Wall:NLRS_21.21_WA_beton ihwg d=250_gen:5105304 | 21 eenentwintigste verdieping | 21.21 buitenwanden - constructief, massieve wanden (Uniformat) | Group: Model Group:NLRS_01.00_verdieping 21--23_gen (members excluded):4647240
3 x Basic Wall:NLRS_21.21_WA_beton prefab d=250_gen:5108967 | 21 eenentwintigste verdieping | 21.21 buitenwanden - constructief, massieve wanden (Uniformat) | Group: Model Group:NLRS_01.00_verdieping 21--23_gen (members excluded):4846692
3 x Basic Wall:NLRS_21.21_WA_beton prefab d=250_gen:5109469 | 21 eenentwintigste verdieping | 21.21 buitenwanden - constructief, massieve wanden (Uniformat) | Group: Model Group:NLRS_01.00_verdieping 21--23_gen (members excluded):4647240
7 x Basic Wall:NLRS_21.21_WA_beton ihwg d=250_gen:5111924 | 22 tweeëntwintigste verdieping | 21.21 buitenwanden - constructief, massieve wanden (Uniformat) | Group: Model Group:NLRS_01.00_verdieping 21--23_gen (members excluded):4846692
7 x Basic Wall:NLRS_21.21_WA_beton ihwg d=250_gen:5115240 | 22 tweeëntwintigste verdieping | 21.21 buitenwanden - constructief, massieve wanden (Uniformat) | Group: Model Group:NLRS_01.00_verdieping 21--23_gen (members excluded):4846692
7 x Basic Wall:NLRS_21.21_WA_beton ihwg d=250_gen:5118776 | 22 tweeëntwintigste verdieping | 21.21 buitenwanden - constructief, massieve wanden (Uniformat) | Group: Model Group:NLRS_01.00_verdieping 21--23_gen (members excluded):4647240
7 x Basic Wall:NLRS_21.21_WA_beton ihwg d=250_gen:5118785 | 22 tweeëntwintigste verdieping | 21.21 buitenwanden - constructief, massieve wanden (Uniformat) | Group: Model Group:NLRS_01.00_verdieping 21--23_gen (members excluded):4647240
3 x Basic Wall:NLRS_21.21_WA_beton prefab d=250_gen:5119108 | 22 tweeëntwintigste verdieping | 21.21 buitenwanden - constructief, massieve wanden (Uniformat) | Group: Model Group:NLRS_01.00_verdieping 21--23_gen (members excluded):4846692
3 x Basic Wall:NLRS_21.21_WA_beton prefab d=250_gen:5119213 | 22 tweeëntwintigste verdieping | 21.21 buitenwanden - constructief, massieve wanden (Uniformat) | Group: Model Group:NLRS_01.00_verdieping 21--23_gen (members excluded):4846692
3 x Basic Wall:NLRS_21.21_WA_beton prefab d=250_gen:5119791 | 22 tweeëntwintigste verdieping | 21.21 buitenwanden - constructief, massieve wanden (Uniformat) | Group: Model Group:NLRS_01.00_verdieping 21--23_gen (members excluded):4647240
3 x Basic Wall:NLRS_21.21_WA_beton prefab d=250_gen:5119796 | 22 tweeëntwintigste verdieping | 21.21 buitenwanden - constructief, massieve wanden (Uniformat) | Group: Model Group:NLRS_01.00_verdieping 21--23_gen (members excluded):4647240
12 x  | 01b tweede tussenverdieping
3 x  | 00a eerste tussenverdieping
NLRS_16.12_SF_WPB_funderingsbalk ihwg recht_gen:800x1200:5136529:1 | 00 begane grond | 16.12 funderingsconstructies - voeten en balken, fundatie balken (Uniformat)
NLRS_16.12_SF_WPB_funderingsbalk ihwg recht_gen:800x1200:5136529:2 | 00 begane grond | 16.12 funderingsconstructies - voeten en balken, fundatie balken (Uniformat)
NLRS_16.12_SF_WPB_funderingsbalk ihwg recht_gen:500x1200:5136541:1 | 00 begane grond | 16.12 funderingsconstructies - voeten en balken, fundatie balken (Uniformat)
NLRS_16.12_SF_WPB_funderingsbalk ihwg recht_gen:500x1200:5136541:2 | 00 begane grond | 16.12 funderingsconstructies - voeten en balken, fundatie balken (Uniformat)
NLRS_16.12_SF_WPB_funderingsbalk ihwg recht_gen:500x1200:5136541:3 | 00 begane grond | 16.12 funderingsconstructies - voeten en balken, fundatie balken (Uniformat)
NLRS_16.12_SF_WPB_funderingsbalk ihwg recht_gen:500x1200:5136553:1 | 00 begane grond | 16.12 funderingsconstructies - voeten en balken, fundatie balken (Uniformat)
NLRS_16.12_SF_WPB_funderingsbalk ihwg recht_gen:500x1200:5136553:2 | 00 begane grond | 16.12 funderingsconstructies - voeten en balken, fundatie balken (Uniformat)
NLRS_16.12_SF_WPB_funderingsbalk ihwg recht_gen:500x1200:5136553:3 | 00 begane grond | 16.12 funderingsconstructies - voeten en balken, fundatie balken (Uniformat)
Floor:NLRS_23.21_FL_druklaag d=70 - gevlinderd_gen:5154816:2 | 00 begane grond | 23.21 vloeren - constructief, vrijdragende vloeren (Uniformat)
Floor:NLRS_23.21_FL_druklaag d=70 - gevlinderd_gen:5154816:3 | 00 begane grond | 23.21 vloeren - constructief, vrijdragende vloeren (Uniformat)
Floor:NLRS_23.21_FL_druklaag d=70 - gevlinderd_gen:5154816:4 | 00 begane grond | 23.21 vloeren - constructief, vrijdragende vloeren (Uniformat)
Floor:NLRS_23.21_FL_druklaag d=70 - gevlinderd_gen:5154816:5 | 00 begane grond | 23.21 vloeren - constructief, vrijdragende vloeren (Uniformat)
Floor:NLRS_23.21_FL_druklaag d=70 - gevlinderd_gen:5154816:6 | 00 begane grond | 23.21 vloeren - constructief, vrijdragende vloeren (Uniformat)
Floor:NLRS_23.21_FL_druklaag d=70 - gevlinderd_gen:5154816:7 | 00 begane grond | 23.21 vloeren - constructief, vrijdragende vloeren (Uniformat)
Floor:NLRS_23.21_FL_geisoleerde kanaalplaat d=200 rc 3.5 iso132_gen:5155302:2 | 00 begane grond | 23.21 vloeren - constructief, vrijdragende vloeren (Uniformat)
Floor:NLRS_13.22_FL_beton ihwg d=1960_gen:5209071:2 | 00 begane grond | 13.22 vloeren op grondslag - constructief, vloeren als gebouwonderdeel (Uniformat)
Floor:NLRS_13.22_FL_beton ihwg d=1960_gen:5216382:2 | 00 begane grond | 13.22 vloeren op grondslag - constructief, vloeren als gebouwonderdeel (Uniformat)
2 x Basic Wall:NLRS_22.21_WA_beton prefab d=200_gen:5231142 | 00 begane grond | 22.21 binnenwanden - constructief, massieve wanden (Uniformat)
2 x Basic Wall:NLRS_22.21_WA_beton prefab d=200_gen:5232298 | 01a eerste tussenverdieping | 22.21 binnenwanden - constructief, massieve wanden (Uniformat)
2 x Basic Wall:NLRS_22.21_WA_beton prefab d=200_gen:5232454 | 01c derde tussenverdieping | 22.21 binnenwanden - constructief, massieve wanden (Uniformat)
2 x Basic Wall:NLRS_22.21_WA_beton prefab d=200_gen:5232584 | 02b tweede tussenverdieping | 22.21 binnenwanden - constructief, massieve wanden (Uniformat)
2 x Basic Wall:NLRS_22.21_WA_beton prefab d=200_gen:5232745 | 04 vierde verdieping | 22.21 binnenwanden - constructief, massieve wanden (Uniformat)
2 x Basic Wall:NLRS_22.21_WA_beton prefab d=200_gen:5233568 | 04 vierde verdieping | 22.21 binnenwanden - constructief, massieve wanden (Uniformat)
2 x Basic Wall:NLRS_22.21_WA_beton prefab d=200_gen:5233570 | 04 vierde verdieping | 22.21 binnenwanden - constructief, massieve wanden (Uniformat)
Floor:NLRS_23.21_FL_druklaag d=70 - gevlinderd_gen:5296847:2 | 00 begane grond | 23.21 vloeren - constructief, vrijdragende vloeren (Uniformat)
Floor:NLRS_23.21_FL_druklaag d=70 - gevlinderd_gen:5297085:2 | 00 begane grond | 23.21 vloeren - constructief, vrijdragende vloeren (Uniformat)
Floor:NLRS_23.21_FL_druklaag d=70 - gevlinderd_gen:5297085:3 | 00 begane grond | 23.21 vloeren - constructief, vrijdragende vloeren (Uniformat)
Floor:NLRS_23.21_FL_druklaag d=70 - gevlinderd_gen:5297085:4 | 00 begane grond | 23.21 vloeren - constructief, vrijdragende vloeren (Uniformat)
Floor:NLRS_23.21_FL_druklaag d=70 - gevlinderd_gen:5297204:2 | 00 begane grond | 23.21 vloeren - constructief, vrijdragende vloeren (Uniformat)
Floor:NLRS_23.21_FL_druklaag d=70 - gevlinderd_gen:5297204:3 | 00 begane grond | 23.21 vloeren - constructief, vrijdragende vloeren (Uniformat)
Floor:NLRS_23.21_FL_druklaag d=70 - gevlinderd_gen:5297204:4 | 00 begane grond | 23.21 vloeren - constructief, vrijdragende vloeren (Uniformat)
Floor:NLRS_23.21_FL_druklaag d=70 - gevlinderd_gen:5297204:5 | 00 begane grond | 23.21 vloeren - constructief, vrijdragende vloeren (Uniformat)
5 x  | 01c derde tussenverdieping
5 x  | 02b tweede tussenverdieping
2 x Basic Wall:NLRS_21.21_WA_beton prefab d=250_gen:1307923 | 00 begane grond | 21.21 buitenwanden - constructief, massieve wanden (Uniformat)
6 x Basic Wall:NLRS_21.21_WA_beton prefab d=250_gen:1307923 | 00a eerste tussenverdieping | 21.21 buitenwanden - constructief, massieve wanden (Uniformat)
13 x Basic Wall:NLRS_16.21_WA_beton ihwg d=250_gen:5707900 | 00 begane grond | 16.21 funderingsconstructies - keerwanden, grondkerende wanden (Uniformat)
6 x Basic Wall:NLRS_16.21_WA_beton ihwg d=250_gen:5708017 | 00 begane grond | 16.21 funderingsconstructies - keerwanden, grondkerende wanden (Uniformat)
Basic Wall:NLRS_21.21_WA_beton prefab d=250_gen:5708810 | 00 begane grond | 21.21 buitenwanden - constructief, massieve wanden (Uniformat)
Basic Wall:NLRS_21.21_WA_beton prefab d=250_gen:5708812 | 00 begane grond | 21.21 buitenwanden - constructief, massieve wanden (Uniformat)
2 x Basic Wall:NLRS_16.21_WA_beton ihwg d=250_gen:5709169 | 00 begane grond | 16.21 funderingsconstructies - keerwanden, grondkerende wanden (Uniformat)
2 x Basic Wall:NLRS_16.21_WA_beton ihwg d=500_gen:5709347 | 00 begane grond | 16.21 funderingsconstructies - keerwanden, grondkerende wanden (Uniformat)
4 x Basic Wall:NLRS_16.21_WA_beton ihwg d=500_gen:5060097 | 00 begane grond | 16.21 funderingsconstructies - keerwanden, grondkerende wanden (Uniformat)
Basic Wall:NLRS_21.21_WA_beton prefab d=250_gen:5709629 | 00a eerste tussenverdieping | 21.21 buitenwanden - constructief, massieve wanden (Uniformat)
Basic Wall:NLRS_21.21_WA_beton prefab d=250_gen:5709809 | 00a eerste tussenverdieping | 21.21 buitenwanden - constructief, massieve wanden (Uniformat)
2 x Basic Wall:NLRS_21.21_WA_beton prefab d=250_gen:5711382 | 01b tweede tussenverdieping | 21.21 buitenwanden - constructief, massieve wanden (Uniformat)
3 x Basic Wall:NLRS_21.21_WA_beton prefab d=250_gen:1307923 | 01b tweede tussenverdieping | 21.21 buitenwanden - constructief, massieve wanden (Uniformat)
5 x Basic Wall:NLRS_21.21_WA_beton prefab d=250_gen:5711727 | 00a eerste tussenverdieping | 21.21 buitenwanden - constructief, massieve wanden (Uniformat)
Basic Wall:NLRS_21.21_WA_beton prefab d=250_gen:5713658 | 00a eerste tussenverdieping | 21.21 buitenwanden - constructief, massieve wanden (Uniformat)
2 x Basic Wall:NLRS_21.21_WA_beton prefab d=250_gen:1307923 | 04 vierde verdieping | 21.21 buitenwanden - constructief, massieve wanden (Uniformat)
10 x Basic Wall:NLRS_16.21_WA_beton prefab d=250_gen:1240268 | 00a eerste tussenverdieping | 16.21 funderingsconstructies - keerwanden, grondkerende wanden (Uniformat)
6 x Basic Wall:NLRS_16.21_WA_beton prefab d=250_gen:1240268 | 01a eerste tussenverdieping | 16.21 funderingsconstructies - keerwanden, grondkerende wanden (Uniformat)
10 x Basic Wall:NLRS_16.21_WA_beton prefab d=250_gen:1240268 | 01b tweede tussenverdieping | 16.21 funderingsconstructies - keerwanden, grondkerende wanden (Uniformat)
10 x Basic Wall:NLRS_16.21_WA_beton prefab d=250_gen:1240268 | 02a eerste tussenverdieping | 16.21 funderingsconstructies - keerwanden, grondkerende wanden (Uniformat)
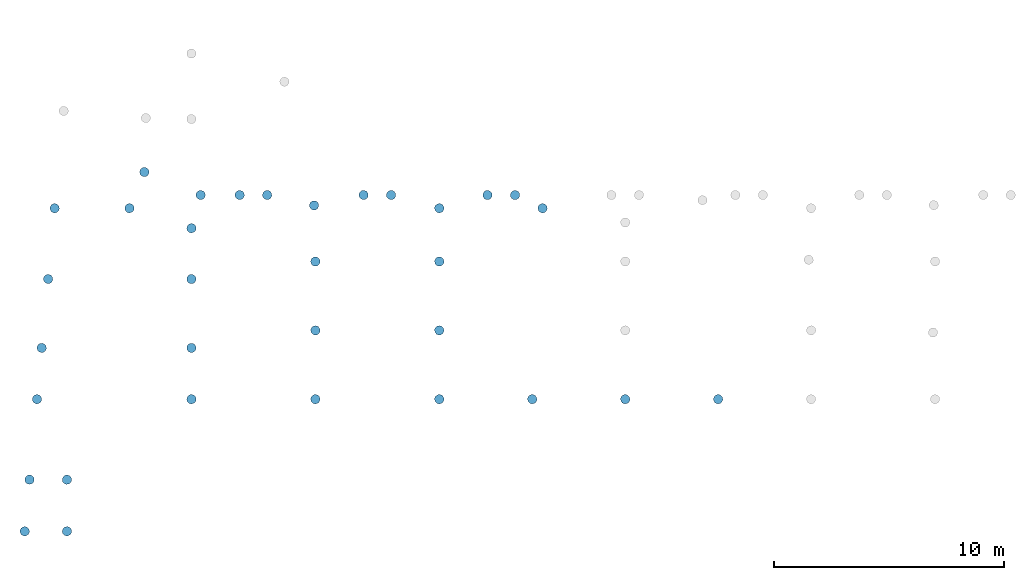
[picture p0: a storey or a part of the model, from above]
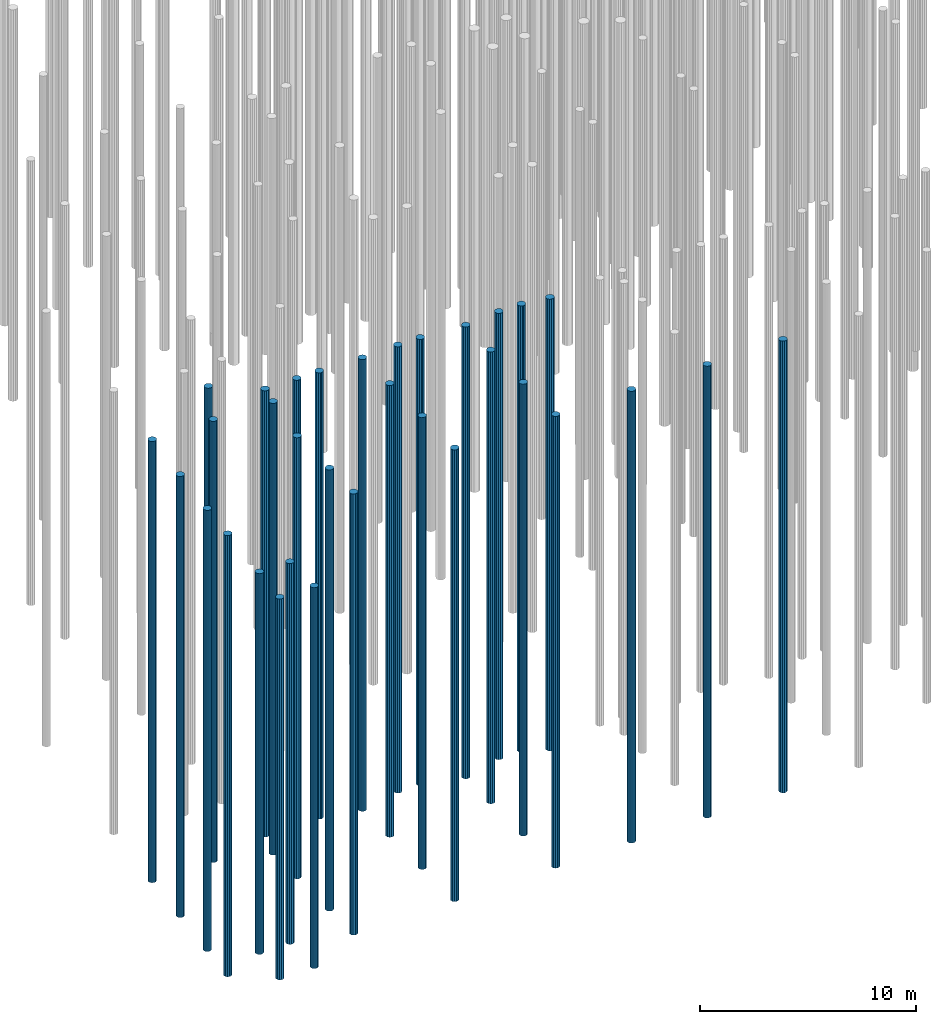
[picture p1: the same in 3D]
Properties of the parts of a building model (IFC2X3), part 7 of 11

# IfcOpeningElement: Opening (5029)
Name | In | Classification
6 x Basic Wall:NLRS_16.21_WA_beton prefab d=250_gen:1240268 | 01c derde tussenverdieping | 16.21 funderingsconstructies - keerwanden, grondkerende wanden (Uniformat)
11 x Basic Wall:NLRS_16.21_WA_beton prefab d=250_gen:1240268 | 00 begane grond | 16.21 funderingsconstructies - keerwanden, grondkerende wanden (Uniformat)
Basic Wall:NLRS_22.21_WA_beton ihwg d=250_gen:5966790 | 00 begane grond | 22.21 binnenwanden - constructief, massieve wanden (Uniformat)
Basic Wall:NLRS_22.21_WA_beton ihwg d=250_gen:5966850 | 00 begane grond | 22.21 binnenwanden - constructief, massieve wanden (Uniformat)
2 x Basic Wall:NLRS_22.21_WA_beton prefab d=180_gen:4264732 | 02b tweede tussenverdieping | 22.21 binnenwanden - constructief, massieve wanden (Uniformat)
4 x  | 05 vijfde verdieping | 23.21 vloeren - constructief, vrijdragende vloeren (Uniformat) | Group: Model Group:NLRS_01.00_verdieping 05_gen (members excluded):6698157
Floor:NLRS_23.21_FL_beton ihwg d=250_gen:6697974:2 | 05 vijfde verdieping | 23.21 vloeren - constructief, vrijdragende vloeren (Uniformat) | Group: Model Group:NLRS_01.00_verdieping 05_gen (members excluded):6698157
3 x Basic Wall:NLRS_21.21_WA_beton prefab d=270_gen:6698041 | 05 vijfde verdieping | 21.21 buitenwanden - constructief, massieve wanden (Uniformat) | Group: Model Group:NLRS_01.00_verdieping 05_gen (members excluded):6698157
3 x Basic Wall:NLRS_21.21_WA_beton prefab d=250_gen:6698046 | 05 vijfde verdieping | 21.21 buitenwanden - constructief, massieve wanden (Uniformat) | Group: Model Group:NLRS_01.00_verdieping 05_gen (members excluded):6698157
3 x Basic Wall:NLRS_21.21_WA_beton prefab d=250_gen:1307923 | 05 vijfde verdieping | 21.21 buitenwanden - constructief, massieve wanden (Uniformat) | Group: Model Group:NLRS_01.00_verdieping 05_gen (members excluded):6698157
3 x Basic Wall:NLRS_21.21_WA_beton prefab d=250_gen:6698051 | 05 vijfde verdieping | 21.21 buitenwanden - constructief, massieve wanden (Uniformat) | Group: Model Group:NLRS_01.00_verdieping 05_gen (members excluded):6698157
3 x Basic Wall:NLRS_21.21_WA_beton prefab d=250_gen:6698056 | 05 vijfde verdieping | 21.21 buitenwanden - constructief, massieve wanden (Uniformat) | Group: Model Group:NLRS_01.00_verdieping 05_gen (members excluded):6698157
3 x Basic Wall:NLRS_21.21_WA_beton prefab d=270_gen:6698061 | 05 vijfde verdieping | 21.21 buitenwanden - constructief, massieve wanden (Uniformat) | Group: Model Group:NLRS_01.00_verdieping 05_gen (members excluded):6698157
3 x Basic Wall:NLRS_21.21_WA_beton prefab d=250_gen:6698066 | 06 zesde verdieping | 21.21 buitenwanden - constructief, massieve wanden (Uniformat) | Group: Model Group:NLRS_01.00_verdieping 05_gen (members excluded):6698157
Basic Wall:NLRS_21.21_WA_beton prefab d=250_gen:1307923 | 06 zesde verdieping | 21.21 buitenwanden - constructief, massieve wanden (Uniformat) | Group: Model Group:NLRS_01.00_verdieping 05_gen (members excluded):6698157
2 x Basic Wall:NLRS_22.21_WA_beton ihwg d=250_gen:6698071 | 05 vijfde verdieping | 22.21 binnenwanden - constructief, massieve wanden (Uniformat) | Group: Model Group:NLRS_01.00_verdieping 05_gen (members excluded):6698157
Basic Wall:NLRS_22.21_WA_beton ihwg d=250_gen:6698073 | 05 vijfde verdieping | 22.21 binnenwanden - constructief, massieve wanden (Uniformat) | Group: Model Group:NLRS_01.00_verdieping 05_gen (members excluded):6698157
Basic Wall:NLRS_22.21_WA_beton ihwg d=250_gen:6698081 | 05 vijfde verdieping | 22.21 binnenwanden - constructief, massieve wanden (Uniformat) | Group: Model Group:NLRS_01.00_verdieping 05_gen (members excluded):6698157
Basic Wall:NLRS_22.21_WA_beton ihwg d=250_gen:6698085 | 05 vijfde verdieping | 22.21 binnenwanden - constructief, massieve wanden (Uniformat) | Group: Model Group:NLRS_01.00_verdieping 05_gen (members excluded):6698157
Basic Wall:NLRS_22.21_WA_beton ihwg d=250_gen:6698087 | 05 vijfde verdieping | 22.21 binnenwanden - constructief, massieve wanden (Uniformat) | Group: Model Group:NLRS_01.00_verdieping 05_gen (members excluded):6698157
3 x Basic Wall:NLRS_22.21_WA_beton prefab d=200_gen:6698092 | 05 vijfde verdieping | 22.21 binnenwanden - constructief, massieve wanden (Uniformat) | Group: Model Group:NLRS_01.00_verdieping 05_gen (members excluded):6698157
2 x Basic Wall:NLRS_22.21_WA_beton prefab d=200_gen:1312531 | 05 vijfde verdieping | 22.21 binnenwanden - constructief, massieve wanden (Uniformat) | Group: Model Group:NLRS_01.00_verdieping 05_gen (members excluded):6698157
9 x Basic Wall:NLRS_21.21_WA_beton ihwg d=250_gen:6698110 | 05 vijfde verdieping | 21.21 buitenwanden - constructief, massieve wanden (Uniformat) | Group: Model Group:NLRS_21.21_wand ihwg as L.P 06-20_gen:6698038
9 x Basic Wall:NLRS_21.21_WA_beton ihwg d=250_gen:6698112 | 05 vijfde verdieping | 21.21 buitenwanden - constructief, massieve wanden (Uniformat) | Group: Model Group:NLRS_21.21_wand ihwg as L.P 06-20_gen:6698070
Basic Wall:NLRS_21.12_WA_isolatie EPS platen d=20_gen:7313392 | 00 begane grond | 21.12 buitenwanden - niet constructief, spouwwanden (Uniformat)
Basic Wall:NLRS_21.12_WA_isolatie EPS platen d=20_gen:7313950 | 00 begane grond | 21.12 buitenwanden - niet constructief, spouwwanden (Uniformat)
Floor:NLRS_23.21_FL_breedplaatschil d=70_gen:7348165:2 | 01a eerste tussenverdieping | 23.21 vloeren - constructief, vrijdragende vloeren (Uniformat)
Floor:NLRS_23.21_FL_breedplaatschil d=70_gen:7349808:2 | 01c derde tussenverdieping | 23.21 vloeren - constructief, vrijdragende vloeren (Uniformat)
Floor:NLRS_23.21_FL_breedplaatschil d=70_gen:7349842:2 | 02b tweede tussenverdieping | 23.21 vloeren - constructief, vrijdragende vloeren (Uniformat)
Floor:NLRS_23.21_FL_breedplaatschil d=70_gen:7353312:2 | 01a eerste tussenverdieping | 23.21 vloeren - constructief, vrijdragende vloeren (Uniformat)
Floor:NLRS_23.21_FL_breedplaatschil d=70_gen:7354867:2 | 01c derde tussenverdieping | 23.21 vloeren - constructief, vrijdragende vloeren (Uniformat)
Floor:NLRS_23.21_FL_breedplaatschil d=70_gen:7354914:2 | 02b tweede tussenverdieping | 23.21 vloeren - constructief, vrijdragende vloeren (Uniformat)
Floor:NLRS_23.21_FL_breedplaatschil d=70_gen:7355239:2 | 01a eerste tussenverdieping | 23.21 vloeren - constructief, vrijdragende vloeren (Uniformat) | Group: Model Group:NLRS_23.21_FL_breedplaat d=50/250 01--02:5439545
Floor:NLRS_23.21_FL_breedplaatschil d=70_gen:7355239:3 | 01a eerste tussenverdieping | 23.21 vloeren - constructief, vrijdragende vloeren (Uniformat) | Group: Model Group:NLRS_23.21_FL_breedplaat d=50/250 01--02:5439545
Floor:NLRS_23.21_FL_breedplaatschil d=70_gen:7355239:4 | 01a eerste tussenverdieping | 23.21 vloeren - constructief, vrijdragende vloeren (Uniformat) | Group: Model Group:NLRS_23.21_FL_breedplaat d=50/250 01--02:5439545
Floor:NLRS_23.21_FL_breedplaatschil d=70_gen:7356579:2 | 01c derde tussenverdieping | 23.21 vloeren - constructief, vrijdragende vloeren (Uniformat) | Group: Model Group:NLRS_23.21_FL_breedplaat d=50/250 01--02:5438789
Floor:NLRS_23.21_FL_breedplaatschil d=70_gen:7356579:3 | 01c derde tussenverdieping | 23.21 vloeren - constructief, vrijdragende vloeren (Uniformat) | Group: Model Group:NLRS_23.21_FL_breedplaat d=50/250 01--02:5438789
Floor:NLRS_23.21_FL_breedplaatschil d=70_gen:7356579:4 | 01c derde tussenverdieping | 23.21 vloeren - constructief, vrijdragende vloeren (Uniformat) | Group: Model Group:NLRS_23.21_FL_breedplaat d=50/250 01--02:5438789
Floor:NLRS_23.21_FL_breedplaatschil d=70_gen:7356630:2 | 02b tweede tussenverdieping | 23.21 vloeren - constructief, vrijdragende vloeren (Uniformat) | Group: Model Group:NLRS_23.21_FL_breedplaat d=50/250 01--02:5439165
Floor:NLRS_23.21_FL_breedplaatschil d=70_gen:7356630:3 | 02b tweede tussenverdieping | 23.21 vloeren - constructief, vrijdragende vloeren (Uniformat) | Group: Model Group:NLRS_23.21_FL_breedplaat d=50/250 01--02:5439165
Floor:NLRS_23.21_FL_breedplaatschil d=70_gen:7356630:4 | 02b tweede tussenverdieping | 23.21 vloeren - constructief, vrijdragende vloeren (Uniformat) | Group: Model Group:NLRS_23.21_FL_breedplaat d=50/250 01--02:5439165
Floor:NLRS_23.21_FL_breedplaatschil d=70_gen:7357067:2 | 01a eerste tussenverdieping | 23.21 vloeren - constructief, vrijdragende vloeren (Uniformat) | Group: Model Group:NLRS_23.21_FL_breedplaat d=50/250 01--02:5439545
Floor:NLRS_23.21_FL_breedplaatschil d=70_gen:7357067:3 | 01a eerste tussenverdieping | 23.21 vloeren - constructief, vrijdragende vloeren (Uniformat) | Group: Model Group:NLRS_23.21_FL_breedplaat d=50/250 01--02:5439545
Floor:NLRS_23.21_FL_breedplaatschil d=70_gen:7357067:4 | 01a eerste tussenverdieping | 23.21 vloeren - constructief, vrijdragende vloeren (Uniformat) | Group: Model Group:NLRS_23.21_FL_breedplaat d=50/250 01--02:5439545
Floor:NLRS_23.21_FL_breedplaatschil d=70_gen:7358726:2 | 01c derde tussenverdieping | 23.21 vloeren - constructief, vrijdragende vloeren (Uniformat) | Group: Model Group:NLRS_23.21_FL_breedplaat d=50/250 01--02:5438789
Floor:NLRS_23.21_FL_breedplaatschil d=70_gen:7358726:3 | 01c derde tussenverdieping | 23.21 vloeren - constructief, vrijdragende vloeren (Uniformat) | Group: Model Group:NLRS_23.21_FL_breedplaat d=50/250 01--02:5438789
Floor:NLRS_23.21_FL_breedplaatschil d=70_gen:7358726:4 | 01c derde tussenverdieping | 23.21 vloeren - constructief, vrijdragende vloeren (Uniformat) | Group: Model Group:NLRS_23.21_FL_breedplaat d=50/250 01--02:5438789
Floor:NLRS_23.21_FL_breedplaatschil d=70_gen:7358768:2 | 02b tweede tussenverdieping | 23.21 vloeren - constructief, vrijdragende vloeren (Uniformat) | Group: Model Group:NLRS_23.21_FL_breedplaat d=50/250 01--02:5439165
Floor:NLRS_23.21_FL_breedplaatschil d=70_gen:7358768:3 | 02b tweede tussenverdieping | 23.21 vloeren - constructief, vrijdragende vloeren (Uniformat) | Group: Model Group:NLRS_23.21_FL_breedplaat d=50/250 01--02:5439165
Floor:NLRS_23.21_FL_breedplaatschil d=70_gen:7358768:4 | 02b tweede tussenverdieping | 23.21 vloeren - constructief, vrijdragende vloeren (Uniformat) | Group: Model Group:NLRS_23.21_FL_breedplaat d=50/250 01--02:5439165
2 x  | 01 eerste verdieping | 23.21 vloeren - constructief, vrijdragende vloeren (Uniformat)
2 x  | 01 eerste verdieping | 23.21 vloeren - constructief, vrijdragende vloeren (Uniformat) | Group: Model Group:Breedplaten woningen noord:7361993
2 x  | 02 tweede verdieping | 23.21 vloeren - constructief, vrijdragende vloeren (Uniformat) | Group: Model Group:Breedplaten woningen noord:7362532
2 x  | 02 tweede verdieping | 23.21 vloeren - constructief, vrijdragende vloeren (Uniformat)
2 x  | 03 derde verdieping | 23.21 vloeren - constructief, vrijdragende vloeren (Uniformat) | Group: Model Group:Breedplaten woningen noord:7367752
2 x  | 03 derde verdieping | 23.21 vloeren - constructief, vrijdragende vloeren (Uniformat)
8 x  | 04 vierde verdieping | 23.21 vloeren - constructief, vrijdragende vloeren (Uniformat)
Floor:NLRS_23.21_FL_breedplaatschil d=70_gen:7395939:2 | 00 begane grond | 23.21 vloeren - constructief, vrijdragende vloeren (Uniformat)
Floor:NLRS_23.21_FL_breedplaatschil d=70_gen:7395939:3 | 00 begane grond | 23.21 vloeren - constructief, vrijdragende vloeren (Uniformat)
Floor:NLRS_23.21_FL_breedplaatschil d=70_gen:7395939:4 | 00 begane grond | 23.21 vloeren - constructief, vrijdragende vloeren (Uniformat)
Floor:NLRS_23.21_FL_breedplaatschil d=70_gen:7395939:5 | 00 begane grond | 23.21 vloeren - constructief, vrijdragende vloeren (Uniformat)
4 x  | 02a eerste tussenverdieping
2 x Basic Wall:NLRS_22.21_WA_beton ihwg d=250_gen:8499910 | 00 begane grond | 22.21 binnenwanden - constructief, massieve wanden (Uniformat)
Floor:NLRS_13.22_FL_beton ihwg d=292_gen:8499944:2 | 00 begane grond | 13.22 vloeren op grondslag - constructief, vloeren als gebouwonderdeel (Uniformat)
Floor:NLRS_23.21_FL_druklaag d=110_gen:8505476:2 | 00 begane grond | 23.21 vloeren - constructief, vrijdragende vloeren (Uniformat)
Floor:NLRS_23.21_FL_beton ihwg d=255_gen:8614351:2 | 01a eerste tussenverdieping | 23.21 vloeren - constructief, vrijdragende vloeren (Uniformat)
Floor:NLRS_23.21_FL_kanaalplaat d=200_gen:8688232:2 | 02b tweede tussenverdieping | 23.21 vloeren - constructief, vrijdragende vloeren (Uniformat)
Floor:NLRS_23.21_FL_kanaalplaat d=200_gen:8699548:2 | 02b tweede tussenverdieping | 23.21 vloeren - constructief, vrijdragende vloeren (Uniformat)
Floor:NLRS_23.21_FL_beton ihwg d=255_gen:8752822:2 | 01c derde tussenverdieping | 23.21 vloeren - constructief, vrijdragende vloeren (Uniformat)
Floor:NLRS_23.21_FL_beton ihwg d=255_gen:8752910:2 | 02b tweede tussenverdieping | 23.21 vloeren - constructief, vrijdragende vloeren (Uniformat)
Floor:NLRS_23.21_FL_beton ihwg d=255_gen:8764299:2 | 01a eerste tussenverdieping | 23.21 vloeren - constructief, vrijdragende vloeren (Uniformat)
Floor:NLRS_23.21_FL_beton ihwg d=255_gen:8768356:2 | 01c derde tussenverdieping | 23.21 vloeren - constructief, vrijdragende vloeren (Uniformat)
Floor:NLRS_23.21_FL_beton ihwg d=255_gen:9081642:2 | 02b tweede tussenverdieping | 23.21 vloeren - constructief, vrijdragende vloeren (Uniformat)
Floor:NLRS_23.21_FL_beton ihwg d=250_gen:10900035:2 | 22 tweeëntwintigste verdieping | 23.21 vloeren - constructief, vrijdragende vloeren (Uniformat) | Group: Model Group:NLRS_01.00_verdieping 21--23_gen (members excluded):4846692
Floor:NLRS_23.21_FL_beton ihwg d=250_gen:10901381:2 | 22 tweeëntwintigste verdieping | 23.21 vloeren - constructief, vrijdragende vloeren (Uniformat) | Group: Model Group:NLRS_01.00_verdieping 21--23_gen (members excluded):4647240
Floor:NLRS_23.21_FL_beton ihwg d=250_gen:10906785:2 | 22 tweeëntwintigste verdieping | 23.21 vloeren - constructief, vrijdragende vloeren (Uniformat) | Group: Model Group:NLRS_01.00_verdieping 21--23_gen (members excluded):4846692
Floor:NLRS_23.21_FL_beton ihwg d=250_gen:10908000:2 | 22 tweeëntwintigste verdieping | 23.21 vloeren - constructief, vrijdragende vloeren (Uniformat) | Group: Model Group:NLRS_01.00_verdieping 21--23_gen (members excluded):4647240
Basic Wall:NLRS_22.21_WA_beton ihwg d=250_gen:11363083 | 04 vierde verdieping | 22.21 binnenwanden - constructief, massieve wanden (Uniformat) | Group: Model Group:NLRS_01.00_verdieping 04_gen (members excluded):4844403
Basic Wall:NLRS_22.21_WA_beton ihwg d=250_gen:1312528 | 04 vierde verdieping | 22.21 binnenwanden - constructief, massieve wanden (Uniformat) | Group: Model Group:NLRS_01.00_verdieping 04_gen (members excluded):4844403
Basic Wall:NLRS_22.21_WA_beton ihwg d=250_gen:11363210 | 04 vierde verdieping | 22.21 binnenwanden - constructief, massieve wanden (Uniformat) | Group: Model Group:NLRS_01.00_verdieping 04_gen (members excluded):4844403
Basic Wall:NLRS_22.21_WA_beton ihwg d=250_gen:11363226 | 04 vierde verdieping | 22.21 binnenwanden - constructief, massieve wanden (Uniformat) | Group: Model Group:NLRS_01.00_verdieping 04_gen (members excluded):4844403
3 x Basic Wall:NLRS_22.21_WA_beton ihwg d=250_gen:11363240 | 04 vierde verdieping | 22.21 binnenwanden - constructief, massieve wanden (Uniformat) | Group: Model Group:NLRS_01.00_verdieping 04_gen (members excluded):4844403
Basic Wall:NLRS_22.21_WA_beton ihwg d=250_gen:11363270 | 04 vierde verdieping | 22.21 binnenwanden - constructief, massieve wanden (Uniformat) | Group: Model Group:NLRS_01.00_verdieping 04_gen (members excluded):4585793
Basic Wall:NLRS_22.21_WA_beton ihwg d=250_gen:11363272 | 04 vierde verdieping | 22.21 binnenwanden - constructief, massieve wanden (Uniformat) | Group: Model Group:NLRS_01.00_verdieping 04_gen (members excluded):4585793
3 x Basic Wall:NLRS_22.21_WA_beton ihwg d=250_gen:11363274 | 04 vierde verdieping | 22.21 binnenwanden - constructief, massieve wanden (Uniformat) | Group: Model Group:NLRS_01.00_verdieping 04_gen (members excluded):4585793
2 x Basic Wall:NLRS_22.21_WA_beton ihwg d=250_gen:11363629 | 05 vijfde verdieping | 22.21 binnenwanden - constructief, massieve wanden (Uniformat) | Group: Model Group:NLRS_01.00_verdieping 05_gen:6691052
Basic Wall:NLRS_22.21_WA_beton ihwg d=250_gen:11363657 | 05 vijfde verdieping | 22.21 binnenwanden - constructief, massieve wanden (Uniformat) | Group: Model Group:NLRS_01.00_verdieping 05_gen:6691052
2 x Basic Wall:NLRS_22.21_WA_beton ihwg d=250_gen:11363695 | 05 vijfde verdieping | 22.21 binnenwanden - constructief, massieve wanden (Uniformat) | Group: Model Group:NLRS_01.00_verdieping 05_gen (members excluded):6698157
Basic Wall:NLRS_22.21_WA_beton ihwg d=250_gen:11363697 | 05 vijfde verdieping | 22.21 binnenwanden - constructief, massieve wanden (Uniformat) | Group: Model Group:NLRS_01.00_verdieping 05_gen (members excluded):6698157
2 x Basic Wall:NLRS_22.21_WA_beton ihwg d=250_gen:11363800 | 06 zesde verdieping | 22.21 binnenwanden - constructief, massieve wanden (Uniformat) | Group: Model Group:NLRS_01.00_verdieping 06--10_gen:4844478
Basic Wall:NLRS_22.21_WA_beton ihwg d=250_gen:11363904 | 06 zesde verdieping | 22.21 binnenwanden - constructief, massieve wanden (Uniformat) | Group: Model Group:NLRS_01.00_verdieping 06--10_gen:4844478
2 x Basic Wall:NLRS_22.21_WA_beton ihwg d=250_gen:11363936 | 06 zesde verdieping | 22.21 binnenwanden - constructief, massieve wanden (Uniformat) | Group: Model Group:NLRS_01.00_verdieping 06--10_gen:4600460
Basic Wall:NLRS_22.21_WA_beton ihwg d=250_gen:11363938 | 06 zesde verdieping | 22.21 binnenwanden - constructief, massieve wanden (Uniformat) | Group: Model Group:NLRS_01.00_verdieping 06--10_gen:4600460
2 x Basic Wall:NLRS_22.21_WA_beton ihwg d=250_gen:11363948 | 07 zevende verdieping | 22.21 binnenwanden - constructief, massieve wanden (Uniformat) | Group: Model Group:NLRS_01.00_verdieping 06--10_gen:4600975
Basic Wall:NLRS_22.21_WA_beton ihwg d=250_gen:11363950 | 07 zevende verdieping | 22.21 binnenwanden - constructief, massieve wanden (Uniformat) | Group: Model Group:NLRS_01.00_verdieping 06--10_gen:4600975
2 x Basic Wall:NLRS_22.21_WA_beton ihwg d=250_gen:11363954 | 08 achtste verdieping | 22.21 binnenwanden - constructief, massieve wanden (Uniformat) | Group: Model Group:NLRS_01.00_verdieping 06--10_gen:4602043
Basic Wall:NLRS_22.21_WA_beton ihwg d=250_gen:11363956 | 08 achtste verdieping | 22.21 binnenwanden - constructief, massieve wanden (Uniformat) | Group: Model Group:NLRS_01.00_verdieping 06--10_gen:4602043
2 x Basic Wall:NLRS_22.21_WA_beton ihwg d=250_gen:11363960 | 09 negende verdieping | 22.21 binnenwanden - constructief, massieve wanden (Uniformat) | Group: Model Group:NLRS_01.00_verdieping 06--10_gen:4603152
Basic Wall:NLRS_22.21_WA_beton ihwg d=250_gen:11363962 | 09 negende verdieping | 22.21 binnenwanden - constructief, massieve wanden (Uniformat) | Group: Model Group:NLRS_01.00_verdieping 06--10_gen:4603152
2 x Basic Wall:NLRS_22.21_WA_beton ihwg d=250_gen:11363966 | 10 tiende verdieping | 22.21 binnenwanden - constructief, massieve wanden (Uniformat) | Group: Model Group:NLRS_01.00_verdieping 06--10_gen:4604220
Basic Wall:NLRS_22.21_WA_beton ihwg d=250_gen:11363968 | 10 tiende verdieping | 22.21 binnenwanden - constructief, massieve wanden (Uniformat) | Group: Model Group:NLRS_01.00_verdieping 06--10_gen:4604220
2 x Basic Wall:NLRS_22.21_WA_beton ihwg d=250_gen:11364017 | 07 zevende verdieping | 22.21 binnenwanden - constructief, massieve wanden (Uniformat) | Group: Model Group:NLRS_01.00_verdieping 06--10_gen:4844553
Basic Wall:NLRS_22.21_WA_beton ihwg d=250_gen:11364019 | 07 zevende verdieping | 22.21 binnenwanden - constructief, massieve wanden (Uniformat) | Group: Model Group:NLRS_01.00_verdieping 06--10_gen:4844553
2 x Basic Wall:NLRS_22.21_WA_beton ihwg d=250_gen:11364023 | 08 achtste verdieping | 22.21 binnenwanden - constructief, massieve wanden (Uniformat) | Group: Model Group:NLRS_01.00_verdieping 06--10_gen:4844628
Basic Wall:NLRS_22.21_WA_beton ihwg d=250_gen:11364025 | 08 achtste verdieping | 22.21 binnenwanden - constructief, massieve wanden (Uniformat) | Group: Model Group:NLRS_01.00_verdieping 06--10_gen:4844628
2 x Basic Wall:NLRS_22.21_WA_beton ihwg d=250_gen:11364029 | 09 negende verdieping | 22.21 binnenwanden - constructief, massieve wanden (Uniformat) | Group: Model Group:NLRS_01.00_verdieping 06--10_gen:4844703
Basic Wall:NLRS_22.21_WA_beton ihwg d=250_gen:11364031 | 09 negende verdieping | 22.21 binnenwanden - constructief, massieve wanden (Uniformat) | Group: Model Group:NLRS_01.00_verdieping 06--10_gen:4844703
2 x Basic Wall:NLRS_22.21_WA_beton ihwg d=250_gen:11364035 | 10 tiende verdieping | 22.21 binnenwanden - constructief, massieve wanden (Uniformat) | Group: Model Group:NLRS_01.00_verdieping 06--10_gen:4844850
Basic Wall:NLRS_22.21_WA_beton ihwg d=250_gen:11364037 | 10 tiende verdieping | 22.21 binnenwanden - constructief, massieve wanden (Uniformat) | Group: Model Group:NLRS_01.00_verdieping 06--10_gen:4844850
2 x Basic Wall:NLRS_22.21_WA_beton ihwg d=250_gen:11365139 | 11 elfde verdieping | 22.21 binnenwanden - constructief, massieve wanden (Uniformat) | Group: Model Group:NLRS_01.00_verdieping 11--17_gen:4845821
Basic Wall:NLRS_22.21_WA_beton ihwg d=250_gen:11365169 | 11 elfde verdieping | 22.21 binnenwanden - constructief, massieve wanden (Uniformat) | Group: Model Group:NLRS_01.00_verdieping 11--17_gen:4845821
2 x Basic Wall:NLRS_22.21_WA_beton ihwg d=250_gen:11366752 | 12 twaalfde verdieping | 22.21 binnenwanden - constructief, massieve wanden (Uniformat) | Group: Model Group:NLRS_01.00_verdieping 11--17_gen:4609129
Basic Wall:NLRS_22.21_WA_beton ihwg d=250_gen:11366754 | 12 twaalfde verdieping | 22.21 binnenwanden - constructief, massieve wanden (Uniformat) | Group: Model Group:NLRS_01.00_verdieping 11--17_gen:4609129
2 x Basic Wall:NLRS_22.21_WA_beton ihwg d=250_gen:11366766 | 13 dertiende verdieping | 22.21 binnenwanden - constructief, massieve wanden (Uniformat) | Group: Model Group:NLRS_01.00_verdieping 11--17_gen:4609592
Basic Wall:NLRS_22.21_WA_beton ihwg d=250_gen:11366768 | 13 dertiende verdieping | 22.21 binnenwanden - constructief, massieve wanden (Uniformat) | Group: Model Group:NLRS_01.00_verdieping 11--17_gen:4609592
2 x Basic Wall:NLRS_22.21_WA_beton ihwg d=250_gen:11366773 | 14 veertiende verdieping | 22.21 binnenwanden - constructief, massieve wanden (Uniformat) | Group: Model Group:NLRS_01.00_verdieping 11--17_gen:4610618
Basic Wall:NLRS_22.21_WA_beton ihwg d=250_gen:11366775 | 14 veertiende verdieping | 22.21 binnenwanden - constructief, massieve wanden (Uniformat) | Group: Model Group:NLRS_01.00_verdieping 11--17_gen:4610618
2 x Basic Wall:NLRS_22.21_WA_beton ihwg d=250_gen:11366780 | 15 vijftiende verdieping | 22.21 binnenwanden - constructief, massieve wanden (Uniformat) | Group: Model Group:NLRS_01.00_verdieping 11--17_gen:4611642
Basic Wall:NLRS_22.21_WA_beton ihwg d=250_gen:11366782 | 15 vijftiende verdieping | 22.21 binnenwanden - constructief, massieve wanden (Uniformat) | Group: Model Group:NLRS_01.00_verdieping 11--17_gen:4611642
2 x Basic Wall:NLRS_22.21_WA_beton ihwg d=250_gen:11366787 | 16 zestiende verdieping | 22.21 binnenwanden - constructief, massieve wanden (Uniformat) | Group: Model Group:NLRS_01.00_verdieping 11--17_gen:4612668
Basic Wall:NLRS_22.21_WA_beton ihwg d=250_gen:11366789 | 16 zestiende verdieping | 22.21 binnenwanden - constructief, massieve wanden (Uniformat) | Group: Model Group:NLRS_01.00_verdieping 11--17_gen:4612668
2 x Basic Wall:NLRS_22.21_WA_beton ihwg d=250_gen:11366794 | 17 zeventiende verdieping | 22.21 binnenwanden - constructief, massieve wanden (Uniformat) | Group: Model Group:NLRS_01.00_verdieping 11--17_gen:4613692
Basic Wall:NLRS_22.21_WA_beton ihwg d=250_gen:11366796 | 17 zeventiende verdieping | 22.21 binnenwanden - constructief, massieve wanden (Uniformat) | Group: Model Group:NLRS_01.00_verdieping 11--17_gen:4613692
2 x Basic Wall:NLRS_22.21_WA_beton ihwg d=250_gen:11366801 | 11 elfde verdieping | 22.21 binnenwanden - constructief, massieve wanden (Uniformat) | Group: Model Group:NLRS_01.00_verdieping 11--17_gen:4626135
Basic Wall:NLRS_22.21_WA_beton ihwg d=250_gen:11366803 | 11 elfde verdieping | 22.21 binnenwanden - constructief, massieve wanden (Uniformat) | Group: Model Group:NLRS_01.00_verdieping 11--17_gen:4626135
2 x Basic Wall:NLRS_22.21_WA_beton ihwg d=250_gen:11366857 | 12 twaalfde verdieping | 22.21 binnenwanden - constructief, massieve wanden (Uniformat) | Group: Model Group:NLRS_01.00_verdieping 11--17_gen:4844919
Basic Wall:NLRS_22.21_WA_beton ihwg d=250_gen:11366859 | 12 twaalfde verdieping | 22.21 binnenwanden - constructief, massieve wanden (Uniformat) | Group: Model Group:NLRS_01.00_verdieping 11--17_gen:4844919
2 x Basic Wall:NLRS_22.21_WA_beton ihwg d=250_gen:11366864 | 13 dertiende verdieping | 22.21 binnenwanden - constructief, massieve wanden (Uniformat) | Group: Model Group:NLRS_01.00_verdieping 11--17_gen:4844988
Basic Wall:NLRS_22.21_WA_beton ihwg d=250_gen:11366866 | 13 dertiende verdieping | 22.21 binnenwanden - constructief, massieve wanden (Uniformat) | Group: Model Group:NLRS_01.00_verdieping 11--17_gen:4844988
2 x Basic Wall:NLRS_22.21_WA_beton ihwg d=250_gen:11366871 | 14 veertiende verdieping | 22.21 binnenwanden - constructief, massieve wanden (Uniformat) | Group: Model Group:NLRS_01.00_verdieping 11--17_gen:4845057
Basic Wall:NLRS_22.21_WA_beton ihwg d=250_gen:11366873 | 14 veertiende verdieping | 22.21 binnenwanden - constructief, massieve wanden (Uniformat) | Group: Model Group:NLRS_01.00_verdieping 11--17_gen:4845057
2 x Basic Wall:NLRS_22.21_WA_beton ihwg d=250_gen:11366878 | 15 vijftiende verdieping | 22.21 binnenwanden - constructief, massieve wanden (Uniformat) | Group: Model Group:NLRS_01.00_verdieping 11--17_gen:4845126
Basic Wall:NLRS_22.21_WA_beton ihwg d=250_gen:11366880 | 15 vijftiende verdieping | 22.21 binnenwanden - constructief, massieve wanden (Uniformat) | Group: Model Group:NLRS_01.00_verdieping 11--17_gen:4845126
2 x Basic Wall:NLRS_22.21_WA_beton ihwg d=250_gen:11366885 | 16 zestiende verdieping | 22.21 binnenwanden - constructief, massieve wanden (Uniformat) | Group: Model Group:NLRS_01.00_verdieping 11--17_gen:4845195
Basic Wall:NLRS_22.21_WA_beton ihwg d=250_gen:11366887 | 16 zestiende verdieping | 22.21 binnenwanden - constructief, massieve wanden (Uniformat) | Group: Model Group:NLRS_01.00_verdieping 11--17_gen:4845195
2 x Basic Wall:NLRS_22.21_WA_beton ihwg d=250_gen:11366892 | 17 zeventiende verdieping | 22.21 binnenwanden - constructief, massieve wanden (Uniformat) | Group: Model Group:NLRS_01.00_verdieping 11--17_gen:4845336
Basic Wall:NLRS_22.21_WA_beton ihwg d=250_gen:11366894 | 17 zeventiende verdieping | 22.21 binnenwanden - constructief, massieve wanden (Uniformat) | Group: Model Group:NLRS_01.00_verdieping 11--17_gen:4845336
Basic Wall:NLRS_22.21_WA_beton ihwg d=250_gen:11368166 | 18 achttiende verdieping | 22.21 binnenwanden - constructief, massieve wanden (Uniformat) | Group: Model Group:NLRS_01.00_verdieping 18-19_gen:4845405
Basic Wall:NLRS_22.21_WA_beton ihwg d=250_gen:11368426 | 18 achttiende verdieping | 22.21 binnenwanden - constructief, massieve wanden (Uniformat) | Group: Model Group:NLRS_01.00_verdieping 18-19_gen:4845405
Basic Wall:NLRS_22.21_WA_beton ihwg d=250_gen:11369110 | 18 achttiende verdieping | 22.21 binnenwanden - constructief, massieve wanden (Uniformat) | Group: Model Group:NLRS_01.00_verdieping 18-19_gen:4617185
Basic Wall:NLRS_22.21_WA_beton ihwg d=250_gen:11369112 | 18 achttiende verdieping | 22.21 binnenwanden - constructief, massieve wanden (Uniformat) | Group: Model Group:NLRS_01.00_verdieping 18-19_gen:4617185
Basic Wall:NLRS_22.21_WA_beton ihwg d=250_gen:11369124 | 19 negentiende verdieping | 22.21 binnenwanden - constructief, massieve wanden (Uniformat) | Group: Model Group:NLRS_01.00_verdieping 18-19_gen:4617669
Basic Wall:NLRS_22.21_WA_beton ihwg d=250_gen:11369126 | 19 negentiende verdieping | 22.21 binnenwanden - constructief, massieve wanden (Uniformat) | Group: Model Group:NLRS_01.00_verdieping 18-19_gen:4617669
Basic Wall:NLRS_22.21_WA_beton ihwg d=250_gen:11369145 | 19 negentiende verdieping | 22.21 binnenwanden - constructief, massieve wanden (Uniformat) | Group: Model Group:NLRS_01.00_verdieping 18-19_gen:4845546
Basic Wall:NLRS_22.21_WA_beton ihwg d=250_gen:11369147 | 19 negentiende verdieping | 22.21 binnenwanden - constructief, massieve wanden (Uniformat) | Group: Model Group:NLRS_01.00_verdieping 18-19_gen:4845546
Basic Wall:NLRS_22.21_WA_beton ihwg d=250_gen:11369548 | 20 twintigste verdieping | 22.21 binnenwanden - constructief, massieve wanden (Uniformat) | Group: Model Group:NLRS_01.00_verdieping 20_gen:4845671
Basic Wall:NLRS_22.21_WA_beton ihwg d=250_gen:11369750 | 20 twintigste verdieping | 22.21 binnenwanden - constructief, massieve wanden (Uniformat) | Group: Model Group:NLRS_01.00_verdieping 20_gen:4845671
Basic Wall:NLRS_22.21_WA_beton ihwg d=250_gen:11370064 | 20 twintigste verdieping | 22.21 binnenwanden - constructief, massieve wanden (Uniformat) | Group: Model Group:NLRS_01.00_verdieping 20_gen:4622361
Basic Wall:NLRS_22.21_WA_beton ihwg d=250_gen:11370066 | 20 twintigste verdieping | 22.21 binnenwanden - constructief, massieve wanden (Uniformat) | Group: Model Group:NLRS_01.00_verdieping 20_gen:4622361
Basic Wall:NLRS_22.21_WA_beton ihwg d=250_gen:11514347 | 18 achttiende verdieping | 22.21 binnenwanden - constructief, massieve wanden (Uniformat) | Group: Model Group:NLRS_01.00_verdieping 18-19_gen:4845405
Basic Wall:NLRS_22.21_WA_beton ihwg d=250_gen:11514365 | 18 achttiende verdieping | 22.21 binnenwanden - constructief, massieve wanden (Uniformat) | Group: Model Group:NLRS_01.00_verdieping 18-19_gen:4617185
Basic Wall:NLRS_22.21_WA_beton ihwg d=250_gen:11514369 | 19 negentiende verdieping | 22.21 binnenwanden - constructief, massieve wanden (Uniformat) | Group: Model Group:NLRS_01.00_verdieping 18-19_gen:4617669
Basic Wall:NLRS_22.21_WA_beton ihwg d=250_gen:11514381 | 19 negentiende verdieping | 22.21 binnenwanden - constructief, massieve wanden (Uniformat) | Group: Model Group:NLRS_01.00_verdieping 18-19_gen:4845546
2 x Basic Wall:NLRS_22.21_WA_beton ihwg d=250_gen:11514497 | 20 twintigste verdieping | 22.21 binnenwanden - constructief, massieve wanden (Uniformat) | Group: Model Group:NLRS_01.00_verdieping 20_gen:4845671
Basic Wall:NLRS_22.21_WA_beton ihwg d=250_gen:11514521 | 20 twintigste verdieping | 22.21 binnenwanden - constructief, massieve wanden (Uniformat) | Group: Model Group:NLRS_01.00_verdieping 20_gen:4845671
Basic Wall:NLRS_22.21_WA_beton ihwg d=250_gen:11514541 | 20 twintigste verdieping | 22.21 binnenwanden - constructief, massieve wanden (Uniformat) | Group: Model Group:NLRS_01.00_verdieping 20_gen:4845671
2 x Basic Wall:NLRS_22.21_WA_beton ihwg d=250_gen:11514565 | 20 twintigste verdieping | 22.21 binnenwanden - constructief, massieve wanden (Uniformat) | Group: Model Group:NLRS_01.00_verdieping 20_gen:4622361
Basic Wall:NLRS_22.21_WA_beton ihwg d=250_gen:11514567 | 20 twintigste verdieping | 22.21 binnenwanden - constructief, massieve wanden (Uniformat) | Group: Model Group:NLRS_01.00_verdieping 20_gen:4622361
Basic Wall:NLRS_22.21_WA_beton ihwg d=250_gen:11514569 | 20 twintigste verdieping | 22.21 binnenwanden - constructief, massieve wanden (Uniformat) | Group: Model Group:NLRS_01.00_verdieping 20_gen:4622361
Basic Wall:NLRS_22.21_WA_beton ihwg d=250_gen:11656887 | 21 eenentwintigste verdieping | 22.21 binnenwanden - constructief, massieve wanden (Uniformat) | Group: Model Group:NLRS_01.00_verdieping 21--23_gen (members excluded):4846692
Basic Wall:NLRS_22.21_WA_beton ihwg d=250_gen:11656917 | 21 eenentwintigste verdieping | 22.21 binnenwanden - constructief, massieve wanden (Uniformat) | Group: Model Group:NLRS_01.00_verdieping 21--23_gen (members excluded):4647240
3 x Basic Wall:NLRS_22.21_WA_beton ihwg d=250_gen:11656997 | 21 eenentwintigste verdieping | 22.21 binnenwanden - constructief, massieve wanden (Uniformat) | Group: Model Group:NLRS_01.00_verdieping 21--23_gen (members excluded):4846692
Basic Wall:NLRS_22.21_WA_beton ihwg d=250_gen:11657047 | 21 eenentwintigste verdieping | 22.21 binnenwanden - constructief, massieve wanden (Uniformat) | Group: Model Group:NLRS_01.00_verdieping 21--23_gen (members excluded):4846692
3 x Basic Wall:NLRS_22.21_WA_beton ihwg d=250_gen:11657360 | 21 eenentwintigste verdieping | 22.21 binnenwanden - constructief, massieve wanden (Uniformat) | Group: Model Group:NLRS_01.00_verdieping 21--23_gen (members excluded):4647240
Basic Wall:NLRS_22.21_WA_beton ihwg d=250_gen:11657376 | 21 eenentwintigste verdieping | 22.21 binnenwanden - constructief, massieve wanden (Uniformat) | Group: Model Group:NLRS_01.00_verdieping 21--23_gen (members excluded):4647240
2 x Basic Wall:NLRS_22.21_WA_beton ihwg d=250_gen:11657770 | 21 eenentwintigste verdieping | 22.21 binnenwanden - constructief, massieve wanden (Uniformat) | Group: Model Group:NLRS_01.00_verdieping 21--23_gen (members excluded):4846692
2 x Basic Wall:NLRS_22.21_WA_beton ihwg d=250_gen:11658094 | 21 eenentwintigste verdieping | 22.21 binnenwanden - constructief, massieve wanden (Uniformat) | Group: Model Group:NLRS_01.00_verdieping 21--23_gen (members excluded):4647240
2 x Basic Wall:NLRS_22.21_WA_beton ihwg d=250_gen:11661834 | 22 tweeëntwintigste verdieping | 22.21 binnenwanden - constructief, massieve wanden (Uniformat) | Group: Model Group:NLRS_01.00_verdieping 21--23_gen (members excluded):4846692
2 x Basic Wall:NLRS_22.21_WA_beton ihwg d=250_gen:11663187 | 22 tweeëntwintigste verdieping | 22.21 binnenwanden - constructief, massieve wanden (Uniformat) | Group: Model Group:NLRS_01.00_verdieping 21--23_gen (members excluded):4647240
Floor:NLRS_23.21_FL_beton prefab d=200_gen:11786973:2 | 06 zesde verdieping | 23.21 vloeren - constructief, vrijdragende vloeren (Uniformat)
Floor:NLRS_23.21_FL_beton prefab d=200_gen:11786973:3 | 06 zesde verdieping | 23.21 vloeren - constructief, vrijdragende vloeren (Uniformat)
2 x Basic Wall:NLRS_22.21_WA_beton prefab d=100_gen:11924729 | 22 tweeëntwintigste verdieping | 22.21 binnenwanden - constructief, massieve wanden (Uniformat) | Group: Model Group:NLRS_01.00_verdieping 21--23_gen (members excluded):4846692
2 x Basic Wall:NLRS_22.21_WA_beton prefab d=100_gen:11924998 | 22 tweeëntwintigste verdieping | 22.21 binnenwanden - constructief, massieve wanden (Uniformat) | Group: Model Group:NLRS_01.00_verdieping 21--23_gen (members excluded):4846692
4 x Basic Wall:NLRS_22.21_WA_beton prefab d=100_gen:11925539 | 22 tweeëntwintigste verdieping | 22.21 binnenwanden - constructief, massieve wanden (Uniformat) | Group: Model Group:NLRS_01.00_verdieping 21--23_gen (members excluded):4647240
4 x Basic Wall:NLRS_22.21_WA_beton prefab d=100_gen:11925541 | 22 tweeëntwintigste verdieping | 22.21 binnenwanden - constructief, massieve wanden (Uniformat) | Group: Model Group:NLRS_01.00_verdieping 21--23_gen (members excluded):4647240
Basic Wall:NLRS_21.21_WA_beton ihwg d=250_gen:12256831 | 20 twintigste verdieping | 21.21 buitenwanden - constructief, massieve wanden (Uniformat) | Group: Model Group:NLRS_01.00_verdieping 20_gen:4845671
Basic Wall:NLRS_21.21_WA_beton ihwg d=250_gen:12257136 | 18 achttiende verdieping | 21.21 buitenwanden - constructief, massieve wanden (Uniformat) | Group: Model Group:NLRS_01.00_verdieping 18-19_gen:4845405
Basic Wall:NLRS_21.21_WA_beton ihwg d=250_gen:12257434 | 20 twintigste verdieping | 21.21 buitenwanden - constructief, massieve wanden (Uniformat) | Group: Model Group:NLRS_01.00_verdieping 20_gen:4622361
Basic Wall:NLRS_21.21_WA_beton ihwg d=250_gen:12258142 | 19 negentiende verdieping | 21.21 buitenwanden - constructief, massieve wanden (Uniformat) | Group: Model Group:NLRS_01.00_verdieping 18-19_gen:4845546
Basic Wall:NLRS_21.21_WA_beton ihwg d=250_gen:12258519 | 12 twaalfde verdieping | 21.21 buitenwanden - constructief, massieve wanden (Uniformat) | Group: Model Group:NLRS_01.00_verdieping 11--17_gen:4609129
Basic Wall:NLRS_21.21_WA_beton ihwg d=250_gen:12258564 | 12 twaalfde verdieping | 21.21 buitenwanden - constructief, massieve wanden (Uniformat) | Group: Model Group:NLRS_01.00_verdieping 11--17_gen:4844919
Basic Wall:NLRS_21.21_WA_beton ihwg d=250_gen:12258570 | 14 veertiende verdieping | 21.21 buitenwanden - constructief, massieve wanden (Uniformat) | Group: Model Group:NLRS_01.00_verdieping 11--17_gen:4845057
Basic Wall:NLRS_21.21_WA_beton ihwg d=250_gen:12258573 | 15 vijftiende verdieping | 21.21 buitenwanden - constructief, massieve wanden (Uniformat) | Group: Model Group:NLRS_01.00_verdieping 11--17_gen:4845126
Basic Wall:NLRS_21.21_WA_beton ihwg d=250_gen:12258576 | 16 zestiende verdieping | 21.21 buitenwanden - constructief, massieve wanden (Uniformat) | Group: Model Group:NLRS_01.00_verdieping 11--17_gen:4845195
Basic Wall:NLRS_21.21_WA_beton ihwg d=250_gen:12259458 | 20 twintigste verdieping | 21.21 buitenwanden - constructief, massieve wanden (Uniformat) | Group: Model Group:NLRS_01.00_verdieping 20_gen:4845671
Basic Wall:NLRS_21.21_WA_beton ihwg d=250_gen:12260066 | 06 zesde verdieping | 21.21 buitenwanden - constructief, massieve wanden (Uniformat) | Group: Model Group:NLRS_01.00_verdieping 06--10_gen:4600460
Basic Wall:NLRS_21.21_WA_beton ihwg d=250_gen:12260072 | 07 zevende verdieping | 21.21 buitenwanden - constructief, massieve wanden (Uniformat) | Group: Model Group:NLRS_01.00_verdieping 06--10_gen:4600975
Basic Wall:NLRS_21.21_WA_beton ihwg d=250_gen:12260075 | 08 achtste verdieping | 21.21 buitenwanden - constructief, massieve wanden (Uniformat) | Group: Model Group:NLRS_01.00_verdieping 06--10_gen:4602043
Basic Wall:NLRS_21.21_WA_beton ihwg d=250_gen:12260099 | 06 zesde verdieping | 21.21 buitenwanden - constructief, massieve wanden (Uniformat) | Group: Model Group:NLRS_01.00_verdieping 06--10_gen:4844478
Basic Wall:NLRS_21.21_WA_beton ihwg d=250_gen:12260105 | 08 achtste verdieping | 21.21 buitenwanden - constructief, massieve wanden (Uniformat) | Group: Model Group:NLRS_01.00_verdieping 06--10_gen:4844628
Basic Wall:NLRS_21.21_WA_beton ihwg d=250_gen:12269226 | 08 achtste verdieping | 21.21 buitenwanden - constructief, massieve wanden (Uniformat) | Group: Model Group:NLRS_01.00_verdieping 06--10_gen:4602043
Basic Wall:NLRS_21.21_WA_beton ihwg d=250_gen:12269249 | 08 achtste verdieping | 21.21 buitenwanden - constructief, massieve wanden (Uniformat) | Group: Model Group:NLRS_01.00_verdieping 06--10_gen:4844628
Basic Wall:NLRS_21.21_WA_beton ihwg d=250_gen:12269377 | 12 twaalfde verdieping | 21.21 buitenwanden - constructief, massieve wanden (Uniformat) | Group: Model Group:NLRS_01.00_verdieping 11--17_gen:4609129
Basic Wall:NLRS_21.21_WA_beton ihwg d=250_gen:12269386 | 14 veertiende verdieping | 21.21 buitenwanden - constructief, massieve wanden (Uniformat) | Group: Model Group:NLRS_01.00_verdieping 11--17_gen:4610618
Basic Wall:NLRS_21.21_WA_beton ihwg d=250_gen:12269389 | 15 vijftiende verdieping | 21.21 buitenwanden - constructief, massieve wanden (Uniformat) | Group: Model Group:NLRS_01.00_verdieping 11--17_gen:4611642
Basic Wall:NLRS_21.21_WA_beton ihwg d=250_gen:12269422 | 12 twaalfde verdieping | 21.21 buitenwanden - constructief, massieve wanden (Uniformat) | Group: Model Group:NLRS_01.00_verdieping 11--17_gen:4844919
Basic Wall:NLRS_21.21_WA_beton ihwg d=250_gen:12269428 | 14 veertiende verdieping | 21.21 buitenwanden - constructief, massieve wanden (Uniformat) | Group: Model Group:NLRS_01.00_verdieping 11--17_gen:4845057
Basic Wall:NLRS_21.21_WA_beton ihwg d=250_gen:12269431 | 15 vijftiende verdieping | 21.21 buitenwanden - constructief, massieve wanden (Uniformat) | Group: Model Group:NLRS_01.00_verdieping 11--17_gen:4845126
Basic Wall:NLRS_21.21_WA_beton ihwg d=250_gen:12269434 | 16 zestiende verdieping | 21.21 buitenwanden - constructief, massieve wanden (Uniformat) | Group: Model Group:NLRS_01.00_verdieping 11--17_gen:4845195
Basic Wall:NLRS_21.21_WA_beton ihwg d=250_gen:12269675 | 19 negentiende verdieping | 21.21 buitenwanden - constructief, massieve wanden (Uniformat) | Group: Model Group:NLRS_01.00_verdieping 18-19_gen:4617669
Basic Wall:NLRS_21.21_WA_beton ihwg d=250_gen:12269684 | 19 negentiende verdieping | 21.21 buitenwanden - constructief, massieve wanden (Uniformat) | Group: Model Group:NLRS_01.00_verdieping 18-19_gen:4845546
Basic Wall:NLRS_22.21_WA_beton prefab d=250_gen:12908715 | 00 begane grond | 22.21 binnenwanden - constructief, massieve wanden (Uniformat)
Basic Wall:NLRS_22.21_WA_beton prefab d=250_gen:12908733 | 01a eerste tussenverdieping | 22.21 binnenwanden - constructief, massieve wanden (Uniformat)
Basic Wall:NLRS_22.21_WA_beton prefab d=250_gen:12908790 | 02b tweede tussenverdieping | 22.21 binnenwanden - constructief, massieve wanden (Uniformat)
Basic Wall:NLRS_22.21_WA_beton prefab d=250_gen:12908828 | 02 tweede verdieping | 22.21 binnenwanden - constructief, massieve wanden (Uniformat)
Basic Wall:NLRS_22.21_WA_beton prefab d=250_gen:12909392 | 00 begane grond | 22.21 binnenwanden - constructief, massieve wanden (Uniformat)
Basic Wall:NLRS_22.21_WA_beton prefab d=250_gen:12916153 | 00 begane grond | 22.21 binnenwanden - constructief, massieve wanden (Uniformat)
Basic Wall:NLRS_22.21_WA_beton prefab d=250_gen:12918180 | 00 begane grond | 22.21 binnenwanden - constructief, massieve wanden (Uniformat)

# IfcOpeningElement: Recess (128)
Name (Basic Wall:...) | In | Classification
NLRS_22.21_WA_beton ihwg d=250_gen:4221399 | 00 begane grond | 22.21 binnenwanden - constructief, massieve wanden (Uniformat)
NLRS_22.21_WA_beton ihwg d=250_gen:4240983 | 00 begane grond | 22.21 binnenwanden - constructief, massieve wanden (Uniformat)
NLRS_22.21_WA_beton ihwg d=250_gen:4241086 | 00 begane grond | 22.21 binnenwanden - constructief, massieve wanden (Uniformat)
NLRS_22.21_WA_beton ihwg d=250_gen:4242755 | 00 begane grond | 22.21 binnenwanden - constructief, massieve wanden (Uniformat)
2 x NLRS_22.21_WA_beton ihwg d=250_gen:4243690 | 00 begane grond | 22.21 binnenwanden - constructief, massieve wanden (Uniformat)
NLRS_22.21_WA_beton ihwg d=250_gen:4244499 | 00 begane grond | 22.21 binnenwanden - constructief, massieve wanden (Uniformat)
NLRS_22.21_WA_beton ihwg d=250_gen:4244517 | 00 begane grond | 22.21 binnenwanden - constructief, massieve wanden (Uniformat)
2 x NLRS_22.21_WA_beton ihwg d=250_gen:4318057 | 00 begane grond | 22.21 binnenwanden - constructief, massieve wanden (Uniformat)
NLRS_22.21_WA_beton ihwg d=250_gen:4318079 | 00 begane grond | 22.21 binnenwanden - constructief, massieve wanden (Uniformat)
NLRS_22.21_WA_beton ihwg d=250_gen:4318214 | 00 begane grond | 22.21 binnenwanden - constructief, massieve wanden (Uniformat)
2 x NLRS_22.21_WA_beton ihwg d=250_gen:4318234 | 00 begane grond | 22.21 binnenwanden - constructief, massieve wanden (Uniformat)
NLRS_22.21_WA_beton ihwg d=250_gen:4318254 | 00 begane grond | 22.21 binnenwanden - constructief, massieve wanden (Uniformat)
NLRS_22.21_WA_beton ihwg d=250_gen:4318288 | 00 begane grond | 22.21 binnenwanden - constructief, massieve wanden (Uniformat)
2 x NLRS_22.21_WA_beton ihwg d=250_gen:4318306 | 00 begane grond | 22.21 binnenwanden - constructief, massieve wanden (Uniformat)
NLRS_22.21_WA_beton ihwg d=250_gen:4318324 | 00 begane grond | 22.21 binnenwanden - constructief, massieve wanden (Uniformat)
NLRS_22.21_WA_beton ihwg d=250_gen:4318362 | 00 begane grond | 22.21 binnenwanden - constructief, massieve wanden (Uniformat)
2 x NLRS_22.21_WA_beton ihwg d=250_gen:4318382 | 00 begane grond | 22.21 binnenwanden - constructief, massieve wanden (Uniformat)
3 x NLRS_22.21_WA_beton ihwg d=250_gen:4319766 | 01 eerste verdieping | 22.21 binnenwanden - constructief, massieve wanden (Uniformat)
4 x NLRS_22.21_WA_beton ihwg d=250_gen:4338551 | 02 tweede verdieping | 22.21 binnenwanden - constructief, massieve wanden (Uniformat)
20 x NLRS_22.21_WA_beton ihwg d=250_gen:4339057 | 02 tweede verdieping | 22.21 binnenwanden - constructief, massieve wanden (Uniformat)
3 x NLRS_22.21_WA_beton ihwg d=250_gen:4339330 | 02 tweede verdieping | 22.21 binnenwanden - constructief, massieve wanden (Uniformat)
5 x NLRS_22.21_WA_beton ihwg d=250_gen:4339332 | 02 tweede verdieping | 22.21 binnenwanden - constructief, massieve wanden (Uniformat)
4 x NLRS_21.21_WA_beton ihwg d=150_gen:4561441 | 04 vierde verdieping | 21.21 buitenwanden - constructief, massieve wanden (Uniformat) | Group: Model Group:NLRS_01.00_dakopbouw 01_gen:4907491
2 x NLRS_21.21_WA_beton ihwg d=150_gen:4566546 | 04 vierde verdieping | 21.21 buitenwanden - constructief, massieve wanden (Uniformat) | Group: Model Group:NLRS_01.00_dakopbouw 02_gen:4909826
NLRS_22.21_WA_beton ihwg d=250_gen:4575549 | 04 vierde verdieping | 22.21 binnenwanden - constructief, massieve wanden (Uniformat) | Group: Model Group:NLRS_01.00_verdieping 04_gen (members excluded):4585793
NLRS_22.21_WA_beton ihwg d=250_gen:4599125 | 06 zesde verdieping | 22.21 binnenwanden - constructief, massieve wanden (Uniformat) | Group: Model Group:NLRS_01.00_verdieping 06--10_gen:4600460
NLRS_22.21_WA_beton ihwg d=250_gen:4600862 | 07 zevende verdieping | 22.21 binnenwanden - constructief, massieve wanden (Uniformat) | Group: Model Group:NLRS_01.00_verdieping 06--10_gen:4600975
NLRS_22.21_WA_beton ihwg d=250_gen:4601930 | 08 achtste verdieping | 22.21 binnenwanden - constructief, massieve wanden (Uniformat) | Group: Model Group:NLRS_01.00_verdieping 06--10_gen:4602043
NLRS_22.21_WA_beton ihwg d=250_gen:4603039 | 09 negende verdieping | 22.21 binnenwanden - constructief, massieve wanden (Uniformat) | Group: Model Group:NLRS_01.00_verdieping 06--10_gen:4603152
NLRS_22.21_WA_beton ihwg d=250_gen:4604107 | 10 tiende verdieping | 22.21 binnenwanden - constructief, massieve wanden (Uniformat) | Group: Model Group:NLRS_01.00_verdieping 06--10_gen:4604220
NLRS_22.21_WA_beton ihwg d=250_gen:4608115 | 12 twaalfde verdieping | 22.21 binnenwanden - constructief, massieve wanden (Uniformat) | Group: Model Group:NLRS_01.00_verdieping 11--17_gen:4609129
NLRS_22.21_WA_beton ihwg d=250_gen:4609485 | 13 dertiende verdieping | 22.21 binnenwanden - constructief, massieve wanden (Uniformat) | Group: Model Group:NLRS_01.00_verdieping 11--17_gen:4609592
NLRS_22.21_WA_beton ihwg d=250_gen:4610511 | 14 veertiende verdieping | 22.21 binnenwanden - constructief, massieve wanden (Uniformat) | Group: Model Group:NLRS_01.00_verdieping 11--17_gen:4610618
NLRS_22.21_WA_beton ihwg d=250_gen:4611535 | 15 vijftiende verdieping | 22.21 binnenwanden - constructief, massieve wanden (Uniformat) | Group: Model Group:NLRS_01.00_verdieping 11--17_gen:4611642
NLRS_22.21_WA_beton ihwg d=250_gen:4612561 | 16 zestiende verdieping | 22.21 binnenwanden - constructief, massieve wanden (Uniformat) | Group: Model Group:NLRS_01.00_verdieping 11--17_gen:4612668
NLRS_22.21_WA_beton ihwg d=250_gen:4613585 | 17 zeventiende verdieping | 22.21 binnenwanden - constructief, massieve wanden (Uniformat) | Group: Model Group:NLRS_01.00_verdieping 11--17_gen:4613692
NLRS_22.21_WA_beton ihwg d=250_gen:4616075 | 18 achttiende verdieping | 22.21 binnenwanden - constructief, massieve wanden (Uniformat) | Group: Model Group:NLRS_01.00_verdieping 18-19_gen:4617185
NLRS_22.21_WA_beton ihwg d=250_gen:4617562 | 19 negentiende verdieping | 22.21 binnenwanden - constructief, massieve wanden (Uniformat) | Group: Model Group:NLRS_01.00_verdieping 18-19_gen:4617669
NLRS_22.21_WA_beton ihwg d=250_gen:4626028 | 11 elfde verdieping | 22.21 binnenwanden - constructief, massieve wanden (Uniformat) | Group: Model Group:NLRS_01.00_verdieping 11--17_gen:4626135
NLRS_22.21_WA_beton ihwg d=250_gen:4844295 | 04 vierde verdieping | 22.21 binnenwanden - constructief, massieve wanden (Uniformat) | Group: Model Group:NLRS_01.00_verdieping 04_gen (members excluded):4844403
NLRS_22.21_WA_beton ihwg d=250_gen:4844439 | 06 zesde verdieping | 22.21 binnenwanden - constructief, massieve wanden (Uniformat) | Group: Model Group:NLRS_01.00_verdieping 06--10_gen:4844478
NLRS_22.21_WA_beton ihwg d=250_gen:4844514 | 07 zevende verdieping | 22.21 binnenwanden - constructief, massieve wanden (Uniformat) | Group: Model Group:NLRS_01.00_verdieping 06--10_gen:4844553
NLRS_22.21_WA_beton ihwg d=250_gen:4844589 | 08 achtste verdieping | 22.21 binnenwanden - constructief, massieve wanden (Uniformat) | Group: Model Group:NLRS_01.00_verdieping 06--10_gen:4844628
NLRS_22.21_WA_beton ihwg d=250_gen:4844664 | 09 negende verdieping | 22.21 binnenwanden - constructief, massieve wanden (Uniformat) | Group: Model Group:NLRS_01.00_verdieping 06--10_gen:4844703
NLRS_22.21_WA_beton ihwg d=250_gen:4844739 | 10 tiende verdieping | 22.21 binnenwanden - constructief, massieve wanden (Uniformat) | Group: Model Group:NLRS_01.00_verdieping 06--10_gen:4844850
NLRS_22.21_WA_beton ihwg d=250_gen:4844886 | 12 twaalfde verdieping | 22.21 binnenwanden - constructief, massieve wanden (Uniformat) | Group: Model Group:NLRS_01.00_verdieping 11--17_gen:4844919
NLRS_22.21_WA_beton ihwg d=250_gen:4844955 | 13 dertiende verdieping | 22.21 binnenwanden - constructief, massieve wanden (Uniformat) | Group: Model Group:NLRS_01.00_verdieping 11--17_gen:4844988
NLRS_22.21_WA_beton ihwg d=250_gen:4845024 | 14 veertiende verdieping | 22.21 binnenwanden - constructief, massieve wanden (Uniformat) | Group: Model Group:NLRS_01.00_verdieping 11--17_gen:4845057
NLRS_22.21_WA_beton ihwg d=250_gen:4845093 | 15 vijftiende verdieping | 22.21 binnenwanden - constructief, massieve wanden (Uniformat) | Group: Model Group:NLRS_01.00_verdieping 11--17_gen:4845126
NLRS_22.21_WA_beton ihwg d=250_gen:4845162 | 16 zestiende verdieping | 22.21 binnenwanden - constructief, massieve wanden (Uniformat) | Group: Model Group:NLRS_01.00_verdieping 11--17_gen:4845195
NLRS_22.21_WA_beton ihwg d=250_gen:4845231 | 17 zeventiende verdieping | 22.21 binnenwanden - constructief, massieve wanden (Uniformat) | Group: Model Group:NLRS_01.00_verdieping 11--17_gen:4845336
NLRS_22.21_WA_beton ihwg d=250_gen:4845372 | 18 achttiende verdieping | 22.21 binnenwanden - constructief, massieve wanden (Uniformat) | Group: Model Group:NLRS_01.00_verdieping 18-19_gen:4845405
NLRS_22.21_WA_beton ihwg d=250_gen:4845441 | 19 negentiende verdieping | 22.21 binnenwanden - constructief, massieve wanden (Uniformat) | Group: Model Group:NLRS_01.00_verdieping 18-19_gen:4845546
NLRS_22.21_WA_beton ihwg d=250_gen:4845643 | 20 twintigste verdieping | 22.21 binnenwanden - constructief, massieve wanden (Uniformat) | Group: Model Group:NLRS_01.00_verdieping 20_gen:4845671
NLRS_22.21_WA_beton ihwg d=250_gen:4845713 | 05 vijfde verdieping | 22.21 binnenwanden - constructief, massieve wanden (Uniformat) | Group: Model Group:NLRS_01.00_verdieping 05_gen:6691052
NLRS_22.21_WA_beton ihwg d=250_gen:4845788 | 11 elfde verdieping | 22.21 binnenwanden - constructief, massieve wanden (Uniformat) | Group: Model Group:NLRS_01.00_verdieping 11--17_gen:4845821
NLRS_22.21_WA_beton ihwg d=250_gen:4887180 | 01 eerste verdieping | 22.21 binnenwanden - constructief, massieve wanden (Uniformat)
4 x NLRS_21.21_WA_beton ihwg d=150_gen:4907959 | 04 vierde verdieping | 21.21 buitenwanden - constructief, massieve wanden (Uniformat) | Group: Model Group:NLRS_01.00_dakopbouw 01_gen:4907974
4 x NLRS_21.21_WA_beton ihwg d=150_gen:4908059 | 04 vierde verdieping | 21.21 buitenwanden - constructief, massieve wanden (Uniformat) | Group: Model Group:NLRS_01.00_dakopbouw 01_gen:4908074
4 x NLRS_21.21_WA_beton ihwg d=150_gen:4908129 | 04 vierde verdieping | 21.21 buitenwanden - constructief, massieve wanden (Uniformat) | Group: Model Group:NLRS_01.00_dakopbouw 01_gen:4908144
4 x NLRS_21.21_WA_beton ihwg d=150_gen:4908201 | 04 vierde verdieping | 21.21 buitenwanden - constructief, massieve wanden (Uniformat)
2 x NLRS_21.21_WA_beton ihwg d=150_gen:4910166 | 04 vierde verdieping | 21.21 buitenwanden - constructief, massieve wanden (Uniformat) | Group: Model Group:NLRS_01.00_dakopbouw 02_gen:4910181
2 x NLRS_21.21_WA_beton ihwg d=150_gen:4910324 | 04 vierde verdieping | 21.21 buitenwanden - constructief, massieve wanden (Uniformat) | Group: Model Group:NLRS_01.00_dakopbouw 02_gen:4910339
2 x NLRS_21.21_WA_beton ihwg d=150_gen:4910424 | 04 vierde verdieping | 21.21 buitenwanden - constructief, massieve wanden (Uniformat) | Group: Model Group:NLRS_01.00_dakopbouw 02_gen:4910439
2 x NLRS_21.21_WA_beton ihwg d=150_gen:4910517 | 04 vierde verdieping | 21.21 buitenwanden - constructief, massieve wanden (Uniformat) | Group: Model Group:NLRS_01.00_dakopbouw 02_gen:4910532
NLRS_22.21_WA_beton ihwg d=250_gen:5014900 | 00 begane grond | 22.21 binnenwanden - constructief, massieve wanden (Uniformat)
2 x NLRS_22.21_WA_beton ihwg d=250_gen:5014904 | 00 begane grond | 22.21 binnenwanden - constructief, massieve wanden (Uniformat)
NLRS_22.21_WA_beton ihwg d=250_gen:5014912 | 00 begane grond | 22.21 binnenwanden - constructief, massieve wanden (Uniformat)
2 x NLRS_22.21_WA_beton ihwg d=250_gen:5015004 | 03 derde verdieping | 22.21 binnenwanden - constructief, massieve wanden (Uniformat)
NLRS_21.21_WA_beton prefab d=250_gen:6397895 | 00a eerste tussenverdieping | 21.21 buitenwanden - constructief, massieve wanden (Uniformat)
NLRS_22.21_WA_beton ihwg d=250_gen:6698071 | 05 vijfde verdieping | 22.21 binnenwanden - constructief, massieve wanden (Uniformat) | Group: Model Group:NLRS_01.00_verdieping 05_gen (members excluded):6698157

# IfcPile: NLRS_17.12_SFO_TLB_funderingspaal grondverdringend_gen:Fundex_r410/500 (249)
In: Level t.b.v. palenplan
Classification: 17.12 paalfunderingen - niet geheid, dragende palen - geschroefd (grondverdringend) (Uniformat); Material: NLRS_f2_beton ihwg
Name (NLRS_17.12_SFO_TLB_funderingspaal grondverdringend_gen:Fundex_r410/500:...)
5035816
5141383
5141531
5141544
5141555
5141605
5141616
5141627
5141638
5141649
5142054
5142066
5142217
5142373
5142521
5142788
5142800
5142811
5142822
5142835
5142846
5142861
5142878
5142891
5142902
5142913
5142924
5142937
5142952
5142963
5142976
5142987
5142998
5143009
5143020
5145873
5145875
5145877
5145879
5145881
5145883
5145885
5145887
5145889
5145891
5145893
5145895
5145897
5145899
5145902
5145904
5145906
5145908
5145910
5145912
5145914
5145916
5145918
5145920
5145922
5145924
5145926
5145928
5145931
5145933
5145935
5145937
5145939
5145941
5145943
5145945
5145947
5145949
5145951
5145953
5145956
5145958
5210970
5210974
5210977
5211884
5211890
5211892
5216932
5216934
5216936
5216945
5216947
5216949
5216958
5216960
5216962
5216972
5216974
5216976
5217008
5217010
5217020
5217024
5217026
5217028
5217033
5217035
5217046
5217056
5217058
5217060
5217067
5217069
5217071
5217078
5217081
5217083
5217091
5217093
5217108
5217502
5217587
5217831
5217859
5221824
5221828
5221872
5221874
5222016
5222018
5222035
5222037
5222054
5222056
5222073
5222075
5222094
5222096
5222113
5222115
5222130
5222132
5222149
5222151
5222176
5222178
5222195
5222197
5222212
5222214
5222229
5222231
5222248
5222250
5222267
5222269
5222661
5222672
5223214
5223216
5223229
5223231
5223716
5223718
5223744
5224505
5225156
5225169
5225182
5225193
5231810
5231814
5231816
5231818
5231820
5231822
5231824
5231929
5231940
5232040
5232114
5232163
5234636
5240364
5240517
5240574
5240620
5240714
5240827
5240869
5240880
5240978
5240980
5242067
5242140
5242177
5242204
5242215
5242226
5242243
5242303
5242305
5242409
5242568
5242628
5242630
5242739
5242741
5242771
5242773
5242826
5242828
5242879
5242918
5243032
5243321
5243390
5243424
5243471
5243480
5243748
5243816
5243818
5243857
5243880
5243934
5244022
5244056
5244101
5244103
5244158
5262514
5262796
5263123
5263125
5263602
5263627
5264256
5264935
5264977
5270211
5270422
5271506
5271672
5275440
5656003
5656006
5656008
5656010
6209925
6209927
7801794
9329887

# IfcPile: NLRS_17.12_SFO_TLB_funderingspaal grondverdringend_gen:Fundex_r460/560 (118)
In: Level t.b.v. palenplan
Classification: 17.12 paalfunderingen - niet geheid, dragende palen - geschroefd (grondverdringend) (Uniformat); Material: NLRS_f2_beton ihwg
Name (NLRS_17.12_SFO_TLB_funderingspaal grondverdringend_gen:Fundex_r460/560:...)
5171030
5172375
5172688
5172690
5172706
5172708
5173110
5173112
5173122
5173124
5173126
5173128
5203443
5203600
5205324
5205339
5205415
5207828
5207830
5207832
5207834
5207846
5210903
5210943
5210945
5234620
5234622
5234624
5234626
5234628
5234630
5234632
5234634
5241856
5262888
5262992
5262994
5272069
5272124
5272137
5272150
5272163
5272190
5272205
5272220
5272231
5272246
5272715
5272857
5272859
5272861
5272874
5272876
5272878
5272909
5272926
5272937
5272990
5273116
5273281
5286454
5286851
5286866
5287284
5287324
5287464
5287579
5287590
5287759
5287770
5287781
5287792
5287803
5287816
5287827
5288006
5288048
5288059
5288460
5288516
5288577
5288645
5288847
5288899
5288910
5288921
5288932
5289057
5289068
5289154
5289165
5289176
5289189
5289200
5289560
5289571
5289582
5289591
5289602
5289613
5289649
5289660
5289671
5289680
5289691
5289702
5301888
5301911
5578567
5578569
5578571
5578648
5578683
5578709
5586860
5617640
5617643
5617646

# IfcPile: NLRS_17.12_SFO_TLB_funderingspaal grondverdringend_gen:Fundex_r530/650 (231)
In: Level t.b.v. palenplan
Classification: 17.12 paalfunderingen - niet geheid, dragende palen - geschroefd (grondverdringend) (Uniformat); Material: NLRS_f2_beton ihwg
Name (NLRS_17.12_SFO_TLB_funderingspaal grondverdringend_gen:Fundex_r530/650:...)
5174649
5174998
5175054
5175056
5176601
5176603
5176605
5176607
5176614
5176616
5176618
5176620
5177075
5177090
5177105
5177116
5177270
5177281
5200522
5200620
5200639
5200912
5200957
5201326
5201341
5201352
5201363
5201428
5201516
5201529
5201540
5201551
5201562
5201579
5201596
5201609
5201646
5201657
5201719
5201730
5201741
5201752
5201826
5201891
5201904
5201928
5201939
5202003
5202070
5202202
5202217
5202228
5202243
5202256
5202354
5202394
5202491
5202493
5202504
5202506
5202521
5202523
5202538
5202540
5202557
5202559
5202592
5202603
5202614
5202629
5202890
5202901
5202914
5202925
5202938
5203000
5203100
5203115
5203292
5203307
5203318
5203329
5203340
5203417
5203430
5205350
5205361
5205372
5205391
5205404
5205426
5205538
5205551
5205575
5205592
5205607
5205620
5205631
5205907
5206220
5206233
5206246
5206722
5206735
5206750
5207700
5207702
5207704
5207706
5207708
5207710
5207712
5207714
5207716
5207718
5207720
5207726
5207728
5207730
5207736
5207738
5207740
5207742
5207744
5207746
5207748
5207750
5207752
5207754
5207756
5207758
5207760
5207764
5207766
5207768
5207770
5207772
5207774
5207776
5207778
5207780
5207782
5207784
5207786
5207788
5207790
5207792
5207794
5207796
5207798
5207800
5207802
5207806
5207808
5207810
5207812
5207814
5207816
5207820
5207822
5207824
5207826
5207836
5207838
5207840
5207842
5207844
5207848
5207850
5207856
5207858
5207860
5207862
5207864
5207866
5207868
5207870
5207872
5207874
5210905
5210907
5210909
5210911
5210913
5210915
5210917
5210919
5210921
5210923
5210925
5210927
5210929
5210933
5210935
5210937
5210939
5210941
5240307
5263453
5288311
5289275
5590965
5590984
5590986
5618029
5619415
5619492
5620459
5620461
5620463
5638030
5638033
5638036
6027522
6027525
6027722
6027849
6027945
6028121
6028159
6950336
6950339
6950344
6950361
7724507
7724698
8515680
9330868
9330878
9330880
9330882

# IfcSlab: Floor:NLRS_13.22_FL_beton ihwg d=1300, Floor:NLRS_13.22_FL_beton ihwg d=1300:6063453
In: 00 begane grond
PredefinedType: BASESLAB; Classification: 13.22 vloeren op grondslag - constructief, vloeren als gebouwonderdeel (Uniformat); Material: NLRS_f2_beton ihwg 1300 mm
Pset_SlabCommon - LoadBearing: yes; PitchAngle: 0 deg; IsExternal: yes; Reference: NLRS_13.22_FL_beton ihwg d=1300; ThermalTransmittance: 0.804615 kg/K/s3

# IfcSlab: Floor:NLRS_13.22_FL_beton ihwg d=1350_gen, Floor:NLRS_13.22_FL_beton ihwg d=1350_gen:6046175
In: 00 begane grond
PredefinedType: BASESLAB; Classification: 13.22 vloeren op grondslag - constructief, vloeren als gebouwonderdeel (Uniformat); Material: NLRS_f2_beton ihwg
Pset_SlabCommon - LoadBearing: yes; IsExternal: yes; Reference: NLRS_13.22_FL_beton ihwg d=1350_gen; ThermalTransmittance: 0.774815 kg/K/s3

# IfcSlab: Floor:NLRS_13.22_FL_beton ihwg d=1558 (2)
In: 00 begane grond
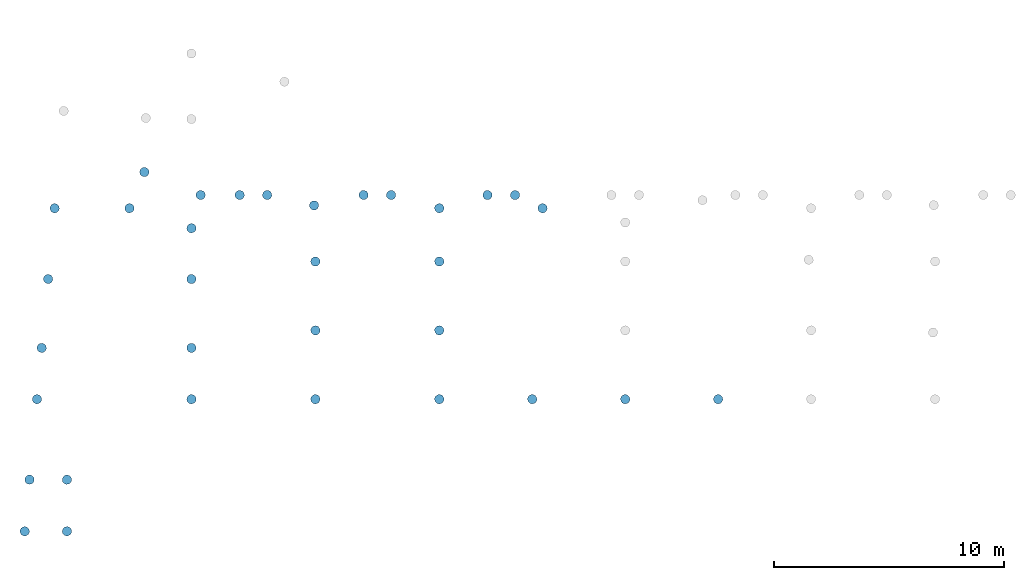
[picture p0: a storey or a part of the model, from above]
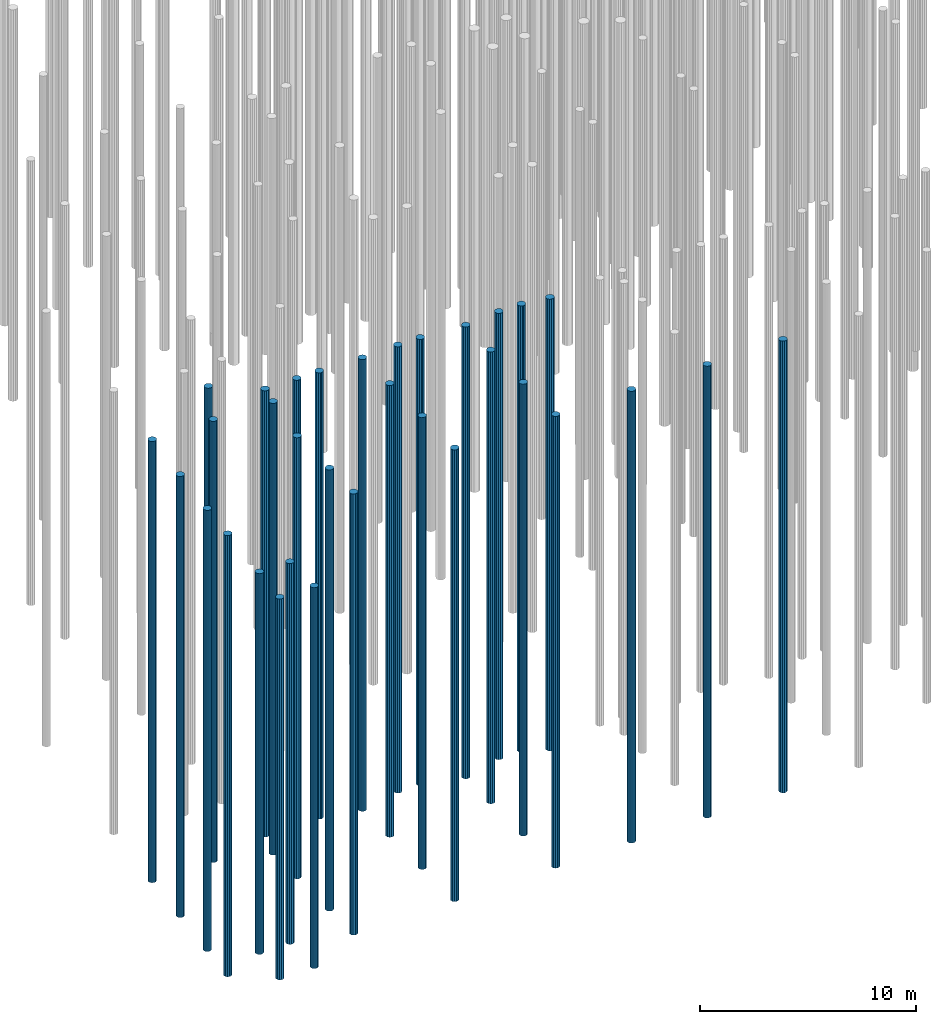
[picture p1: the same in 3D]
Properties of the parts of a building model (IFC2X3), part 8 of 11

# IfcSlab: Floor:NLRS_13.22_FL_beton ihwg d=1558 (2)
PredefinedType: BASESLAB; Classification: 13.22 vloeren op grondslag - constructief, vloeren als gebouwonderdeel (Uniformat); Material: NLRS_f2_beton ihwg 1558 mm
Pset_SlabCommon - LoadBearing: yes; PitchAngle: 0 deg; IsExternal: yes; Reference: NLRS_13.22_FL_beton ihwg d=1558; ThermalTransmittance: 0.671374 kg/K/s3
Name (Floor:NLRS_13.22_FL_beton ihwg d=1558:...)
6032295
6046221

# IfcSlab: Floor:NLRS_13.22_FL_beton ihwg d=1600_gen (2)
In: 00 begane grond
PredefinedType: BASESLAB; Classification: 13.22 vloeren op grondslag - constructief, vloeren als gebouwonderdeel (Uniformat); Material: NLRS_f2_beton ihwg 1600 mm
Pset_SlabCommon - LoadBearing: yes; PitchAngle: 0 deg; IsExternal: yes; Reference: NLRS_13.22_FL_beton ihwg d=1600_gen; ThermalTransmittance: 0.65375 kg/K/s3
Name (Floor:NLRS_13.22_FL_beton ihwg d=1600_gen:...)
4950501
5171011

# IfcSlab: Floor:NLRS_13.22_FL_beton ihwg d=1648 (4)
In: 00 begane grond
PredefinedType: BASESLAB; Classification: 13.22 vloeren op grondslag - constructief, vloeren als gebouwonderdeel (Uniformat); Material: NLRS_f2_beton ihwg 1648 mm
Pset_SlabCommon - LoadBearing: yes; IsExternal: yes; Reference: NLRS_13.22_FL_beton ihwg d=1648; ThermalTransmittance: 0.634709 kg/K/s3
Name (Floor:NLRS_13.22_FL_beton ihwg d=1648:...)
6037248 | Pset_SlabCommon - PitchAngle: 0 deg
6040336
6046202 | Pset_SlabCommon - PitchAngle: 0 deg
6046294

# IfcSlab: Floor:NLRS_13.22_FL_beton ihwg d=1850_gen (2)
In: 00 begane grond
PredefinedType: BASESLAB; Classification: 13.22 vloeren op grondslag - constructief, vloeren als gebouwonderdeel (Uniformat); Material: NLRS_f2_beton ihwg 1850 mm
Pset_SlabCommon - LoadBearing: yes; PitchAngle: 0 deg; IsExternal: yes; Reference: NLRS_13.22_FL_beton ihwg d=1850_gen; ThermalTransmittance: 0.565405 kg/K/s3
Name (Floor:NLRS_13.22_FL_beton ihwg d=1850_gen:...)
5178922
5935845

# IfcSlab: Floor:NLRS_13.22_FL_beton ihwg d=1960_gen (2)
In: 00 begane grond
PredefinedType: BASESLAB; Classification: 13.22 vloeren op grondslag - constructief, vloeren als gebouwonderdeel (Uniformat); Material: NLRS_f2_beton ihwg 1960 mm
Pset_SlabCommon - LoadBearing: yes; IsExternal: yes; Reference: NLRS_13.22_FL_beton ihwg d=1960_gen; ThermalTransmittance: 0.533673 kg/K/s3
Name (Floor:NLRS_13.22_FL_beton ihwg d=1960_gen:...)
5209071
5216382

# IfcSlab: Floor:NLRS_13.22_FL_beton ihwg d=245_gevlinderd en ingestrooid_gen (2)
In: 00 begane grond
PredefinedType: BASESLAB; Classification: 13.22 vloeren op grondslag - constructief, vloeren als gebouwonderdeel (Uniformat); Material: NLRS_f2_beton ihwg 245 mm
Pset_SlabCommon - LoadBearing: yes; PitchAngle: 0 deg; IsExternal: yes; Reference: NLRS_13.22_FL_beton ihwg d=245_gevlinderd en ingestrooid_gen; ThermalTransmittance: 4.26939 kg/K/s3
Name (Floor:NLRS_13.22_FL_beton ihwg d=245_gevlinderd en ingestrooid_gen:...)
8108826
8581055

# IfcSlab: Floor:NLRS_13.22_FL_beton ihwg d=250_gen (5)
In: 00 begane grond
PredefinedType: BASESLAB; Classification: 13.22 vloeren op grondslag - constructief, vloeren als gebouwonderdeel (Uniformat)
Pset_SlabCommon - LoadBearing: yes; IsExternal: yes; Reference: NLRS_13.22_FL_beton ihwg d=250_gen; ThermalTransmittance: 4.184 kg/K/s3
Name (Floor:NLRS_13.22_FL_beton ihwg d=250_gen:...) | Material | PitchAngle (deg)
5707893 | NLRS_f2_beton ihwg 250 mm | 0
5709084 | NLRS_f2_beton ihwg 250 mm | 0
5709511
7396568 | NLRS_f2_beton ihwg 250 mm | 0
8448463 | NLRS_f2_beton ihwg 250 mm | 0

# IfcSlab: Floor:NLRS_13.22_FL_beton ihwg d=292_gen, Floor:NLRS_13.22_FL_beton ihwg d=292_gen:8499944
In: 00 begane grond
PredefinedType: FLOOR; Classification: 13.22 vloeren op grondslag - constructief, vloeren als gebouwonderdeel (Uniformat); Material: NLRS_f2_beton ihwg 292 mm
Pset_SlabCommon - LoadBearing: yes; IsExternal: no; Reference: NLRS_13.22_FL_beton ihwg d=292_gen; ThermalTransmittance: 3.58219 kg/K/s3

# IfcSlab: Floor:NLRS_13.22_FL_beton ihwg d=300_gen (4)
In: 00 begane grond
PredefinedType: BASESLAB; Classification: 13.22 vloeren op grondslag - constructief, vloeren als gebouwonderdeel (Uniformat); Material: NLRS_f2_beton ihwg 300 mm
Pset_SlabCommon - LoadBearing: yes; IsExternal: yes; Reference: NLRS_13.22_FL_beton ihwg d=300_gen; ThermalTransmittance: 3.48667 kg/K/s3
Name (Floor:NLRS_13.22_FL_beton ihwg d=300_gen:...) | PitchAngle (deg)
5707933
5709395 | 0
5880522 | 0
5880542 | 0

# IfcSlab: Floor:NLRS_13.22_FL_beton ihwg d=300_gevlinderd en ingestrooid_gen, Floor:NLRS_13.22_FL_beton ihwg d=300_gevlinderd en ingestrooid_gen:5707949
In: 00 begane grond
PredefinedType: BASESLAB; Classification: 13.22 vloeren op grondslag - constructief, vloeren als gebouwonderdeel (Uniformat); Material: NLRS_f2_beton ihwg 300 mm
Pset_SlabCommon - LoadBearing: yes; PitchAngle: 0 deg; IsExternal: yes; Reference: NLRS_13.22_FL_beton ihwg d=300_gevlinderd en ingestrooid_gen; ThermalTransmittance: 3.48667 kg/K/s3

# IfcSlab: Floor:NLRS_13.22_FL_beton ihwg d=332_gen (7)
In: 00 begane grond
PredefinedType: FLOOR; Classification: 13.22 vloeren op grondslag - constructief, vloeren als gebouwonderdeel (Uniformat)
Pset_SlabCommon - LoadBearing: yes; IsExternal: no; Reference: NLRS_13.22_FL_beton ihwg d=332_gen; ThermalTransmittance: 3.1506 kg/K/s3
Name (Floor:NLRS_13.22_FL_beton ihwg d=332_gen:...) | Material | PitchAngle (deg)
6036699 | NLRS_f2_beton ihwg
6036736 | NLRS_f2_beton ihwg 332 mm | 0
6040411 | NLRS_f2_beton ihwg 332 mm
6041142 | NLRS_f2_beton ihwg 332 mm | 0
6041527 | NLRS_f2_beton ihwg 332 mm | 0
6046303 | NLRS_f2_beton ihwg 332 mm
6048562 | NLRS_f2_beton ihwg 332 mm | 0

# IfcSlab: Floor:NLRS_13.22_FL_beton ihwg d=422_ge (3)
In: 00 begane grond
PredefinedType: FLOOR; Classification: 13.22 vloeren op grondslag - constructief, vloeren als gebouwonderdeel (Uniformat); Material: NLRS_f2_beton ihwg 422 mm
Pset_SlabCommon - LoadBearing: yes; IsExternal: no; Reference: NLRS_13.22_FL_beton ihwg d=422_ge; ThermalTransmittance: 2.47867 kg/K/s3
Name (Floor:NLRS_13.22_FL_beton ihwg d=422_ge:...)
6073577 | Pset_SlabCommon - PitchAngle: 0 deg
6082112
6082112:2

# IfcSlab: Floor:NLRS_13.22_FL_beton ihwg d=50_gen, Floor:NLRS_13.22_FL_beton ihwg d=50_gen:8007154
In: 00 begane grond
PredefinedType: BASESLAB; Classification: 13.22 vloeren op grondslag - constructief, vloeren als gebouwonderdeel (Uniformat); Material: NLRS_f2_beton ihwg 50 mm
Pset_SlabCommon - LoadBearing: yes; PitchAngle: 0 deg; IsExternal: yes; Reference: NLRS_13.22_FL_beton ihwg d=50_gen; ThermalTransmittance: 20.92 kg/K/s3

# IfcSlab: Floor:NLRS_13.22_FL_beton ihwg d=908_gen, Floor:NLRS_13.22_FL_beton ihwg d=908_gen:8453163
In: 00 begane grond
PredefinedType: FLOOR; Classification: 13.22 vloeren op grondslag - constructief, vloeren als gebouwonderdeel (Uniformat); Material: NLRS_f2_beton ihwg 908 mm
Pset_SlabCommon - LoadBearing: yes; IsExternal: no; PitchAngle: 0 deg; Reference: NLRS_13.22_FL_beton ihwg d=908_gen; ThermalTransmittance: 1.15198 kg/K/s3

# IfcSlab: Floor:NLRS_13.22_FL_beton prefab d=200_gen (35)
In: 00 begane grond
PredefinedType: FLOOR; Classification: 13.22 vloeren op grondslag - constructief, vloeren als gebouwonderdeel (Uniformat); Material: NLRS_f2_beton prefab 200 mm
Pset_SlabCommon - LoadBearing: yes; IsExternal: no; PitchAngle: 0 deg; Reference: NLRS_13.22_FL_beton prefab d=200_gen; ThermalTransmittance: 5.23 kg/K/s3
Name (Floor:NLRS_13.22_FL_beton prefab d=200_gen:...)
5707642
5707651
5707660
5707669
5707678
5707687
5707696
5707705
5707714
5707846
5707855
5707864
5715300
5715309
5715318
5715430
5715439
5715489
5715522
5719483
5719492
5719501
5719510
5756178
5756187
5756196
5756233
5756242
5756251
5756283
5757255
5757264
5757273
5757282
6057809

# IfcSlab: Floor:NLRS_23.11_FL_stalen roostervloer d=30_gen (3)
PredefinedType: FLOOR; Classification: 23.11 vloeren - niet constructief, vrijdragende vloeren (Uniformat); Material: NLRS_h2_roostervloer staal 30 mm
Pset_SlabCommon - LoadBearing: yes; IsExternal: no; PitchAngle: 0 deg; Reference: NLRS_23.11_FL_stalen roostervloer d=30_gen
Name (Floor:NLRS_23.11_FL_stalen roostervloer d=30_gen:...) | In | Group
11786499 | 05 vijfde verdieping | Model Group:Rooster en hoeklijnen schacht:11786479
11786714 | 07 zevende verdieping | Model Group:Rooster en hoeklijnen schacht:11786711
11786801 | 02a eerste tussenverdieping | Model Group:Rooster en hoeklijnen schacht:11786798

# IfcSlab: Floor:NLRS_23.21_FL_beton bpv d=var_gen (3)
In: 04 vierde verdieping
PredefinedType: FLOOR; Classification: 23.21 vloeren - constructief, vrijdragende vloeren (Uniformat); Material: NLRS_f2_beton ihwg 1 mm
Pset_SlabCommon - LoadBearing: yes; IsExternal: no; Reference: NLRS_23.21_FL_beton bpv d=var_gen; ThermalTransmittance: 1046 kg/K/s3
Name (Floor:NLRS_23.21_FL_beton bpv d=var_gen:...)
10120669
10135446
10136500

# IfcSlab: Floor:NLRS_23.21_FL_beton ihwg d=10_gen, Floor:NLRS_23.21_FL_beton ihwg d=10_gen:6939213
In: 00 begane grond
PredefinedType: FLOOR; Classification: 23.21 vloeren - constructief, vrijdragende vloeren (Uniformat); Material: NLRS_f2_beton ihwg 10 mm
Pset_SlabCommon - LoadBearing: yes; IsExternal: no; PitchAngle: 0 deg; Reference: NLRS_23.21_FL_beton ihwg d=10_gen; ThermalTransmittance: 104.6 kg/K/s3

# IfcSlab: Floor:NLRS_23.21_FL_beton ihwg d=1300_gen, Floor:NLRS_23.21_FL_beton ihwg d=1300_gen:6062853
In: 00 begane grond
PredefinedType: FLOOR; Classification: 23.21 vloeren - constructief, vrijdragende vloeren (Uniformat); Material: NLRS_f2_beton ihwg 1300 mm
Pset_SlabCommon - LoadBearing: yes; IsExternal: no; PitchAngle: 0 deg; Reference: NLRS_23.21_FL_beton ihwg d=1300_gen; ThermalTransmittance: 0.804615 kg/K/s3

# IfcSlab: Floor:NLRS_23.21_FL_beton ihwg d=130_gen, Floor:NLRS_23.21_FL_beton ihwg d=130_gen:6081425
In: 00 begane grond
PredefinedType: FLOOR; Classification: 23.21 vloeren - constructief, vrijdragende vloeren (Uniformat); Material: NLRS_f2_beton ihwg 130 mm
Pset_SlabCommon - LoadBearing: yes; IsExternal: no; PitchAngle: 0 deg; Reference: NLRS_23.21_FL_beton ihwg d=130_gen; ThermalTransmittance: 8.04615 kg/K/s3

# IfcSlab: Floor:NLRS_23.21_FL_beton ihwg d=132_gen precies 132, Floor:NLRS_23.21_FL_beton ihwg d=132_gen precies 132:8005983
In: 00 begane grond
PredefinedType: FLOOR; Classification: 23.21 vloeren - constructief, vrijdragende vloeren (Uniformat); Material: NLRS_f2_beton ihwg 132 mm
Pset_SlabCommon - LoadBearing: yes; IsExternal: no; PitchAngle: 0 deg; Reference: NLRS_23.21_FL_beton ihwg d=132_gen precies 132; ThermalTransmittance: 7.92424 kg/K/s3

# IfcSlab: Floor:NLRS_23.21_FL_beton ihwg d=20_gen, Floor:NLRS_23.21_FL_beton ihwg d=20_gen:10124228
In: 00 begane grond
PredefinedType: FLOOR; Classification: 23.21 vloeren - constructief, vrijdragende vloeren (Uniformat); Material: NLRS_f2_beton ihwg 20 mm
Pset_SlabCommon - LoadBearing: yes; IsExternal: no; PitchAngle: 0 deg; Reference: NLRS_23.21_FL_beton ihwg d=20_gen; ThermalTransmittance: 52.3 kg/K/s3

# IfcSlab: Floor:NLRS_23.21_FL_beton ihwg d=230_gen (4)
In: 03 derde verdieping
PredefinedType: FLOOR; Classification: 23.21 vloeren - constructief, vrijdragende vloeren (Uniformat); Material: NLRS_f2_beton ihwg 230 mm
Pset_SlabCommon - LoadBearing: yes; IsExternal: no; Reference: NLRS_23.21_FL_beton ihwg d=230_gen; ThermalTransmittance: 4.54783 kg/K/s3
Name (Floor:NLRS_23.21_FL_beton ihwg d=230_gen:...)
4969136
4969136:2
5015600
5015600:2

# IfcSlab: Floor:NLRS_23.21_FL_beton ihwg d=250_gen (229)
PredefinedType: FLOOR; Classification: 23.21 vloeren - constructief, vrijdragende vloeren (Uniformat)
Pset_SlabCommon - LoadBearing: yes; IsExternal: no; Reference: NLRS_23.21_FL_beton ihwg d=250_gen; ThermalTransmittance: 4.184 kg/K/s3
Name (Floor:NLRS_23.21_FL_beton ihwg d=250_gen:...) | In | Material | Group | PitchAngle (deg)
4604141 | 11 elfde verdieping | NLRS_f2_beton ihwg 250 mm | Model Group:NLRS_01.00_verdieping 11--17_gen:4626135
4613613 | 18 achttiende verdieping | NLRS_f2_beton ihwg 250 mm | Model Group:NLRS_01.00_verdieping 18-19_gen:4617185
4617590 | 20 twintigste verdieping | NLRS_f2_beton ihwg 250 mm | Model Group:NLRS_01.00_verdieping 20_gen:4622361
4618687 | 21 eenentwintigste verdieping | NLRS_f2_beton ihwg 250 mm | Model Group:NLRS_01.00_verdieping 21--23_gen (members excluded):4647240
4628732 | 06 zesde verdieping | NLRS_f2_beton ihwg 250 mm | Model Group:NLRS_01.00_verdieping 06--10_gen:4600460
4628896 | 07 zevende verdieping | NLRS_f2_beton ihwg 250 mm | Model Group:NLRS_01.00_verdieping 06--10_gen:4600975
4628978 | 08 achtste verdieping | NLRS_f2_beton ihwg 250 mm | Model Group:NLRS_01.00_verdieping 06--10_gen:4602043
4629060 | 09 negende verdieping | NLRS_f2_beton ihwg 250 mm | Model Group:NLRS_01.00_verdieping 06--10_gen:4603152
4629142 | 10 tiende verdieping | NLRS_f2_beton ihwg 250 mm | Model Group:NLRS_01.00_verdieping 06--10_gen:4604220
4640288 | 12 twaalfde verdieping | NLRS_f2_beton ihwg 250 mm | Model Group:NLRS_01.00_verdieping 11--17_gen:4609129
4640440 | 13 dertiende verdieping | NLRS_f2_beton ihwg 250 mm | Model Group:NLRS_01.00_verdieping 11--17_gen:4609592
4640516 | 14 veertiende verdieping | NLRS_f2_beton ihwg 250 mm | Model Group:NLRS_01.00_verdieping 11--17_gen:4610618
4640592 | 15 vijftiende verdieping | NLRS_f2_beton ihwg 250 mm | Model Group:NLRS_01.00_verdieping 11--17_gen:4611642
4640668 | 16 zestiende verdieping | NLRS_f2_beton ihwg 250 mm | Model Group:NLRS_01.00_verdieping 11--17_gen:4612668
4640744 | 17 zeventiende verdieping | NLRS_f2_beton ihwg 250 mm | Model Group:NLRS_01.00_verdieping 11--17_gen:4613692
4644337 | 19 negentiende verdieping | NLRS_f2_beton ihwg 250 mm | Model Group:NLRS_01.00_verdieping 18-19_gen:4617669
4653976 | 22 tweeëntwintigste verdieping | NLRS_f2_beton ihwg 250 mm | Model Group:NLRS_01.00_verdieping 21--23_gen (members excluded):4647240
4655458 | 22 tweeëntwintigste verdieping | NLRS_f2_beton ihwg 250 mm | Model Group:NLRS_01.00_verdieping 21--23_gen (members excluded):4647240
4656935 | 23 dakverdieping | NLRS_f2_beton ihwg 250 mm | Model Group:NLRS_01.00_verdieping 21--23_gen (members excluded):4647240
4844332 | 05 vijfde verdieping | NLRS_f2_beton ihwg 250 mm | Model Group:NLRS_01.00_verdieping 05_gen:6691052
4844773 | 11 elfde verdieping | NLRS_f2_beton ihwg 250 mm | Model Group:NLRS_01.00_verdieping 11--17_gen:4845821
4845259 | 18 achttiende verdieping | NLRS_f2_beton ihwg 250 mm | Model Group:NLRS_01.00_verdieping 18-19_gen:4845405
4845469 | 20 twintigste verdieping | NLRS_f2_beton ihwg 250 mm | Model Group:NLRS_01.00_verdieping 20_gen:4845671
4845607 | 21 eenentwintigste verdieping | NLRS_f2_beton ihwg 250 mm | Model Group:NLRS_01.00_verdieping 21--23_gen (members excluded):4846692
4845823 | 06 zesde verdieping | NLRS_f2_beton ihwg 250 mm | Model Group:NLRS_01.00_verdieping 06--10_gen:4844478
4845887 | 07 zevende verdieping | NLRS_f2_beton ihwg 250 mm | Model Group:NLRS_01.00_verdieping 06--10_gen:4844553
4845951 | 08 achtste verdieping | NLRS_f2_beton ihwg 250 mm | Model Group:NLRS_01.00_verdieping 06--10_gen:4844628
4846015 | 09 negende verdieping | NLRS_f2_beton ihwg 250 mm | Model Group:NLRS_01.00_verdieping 06--10_gen:4844703
4846079 | 10 tiende verdieping | NLRS_f2_beton ihwg 250 mm | Model Group:NLRS_01.00_verdieping 06--10_gen:4844850
4846183 | 12 twaalfde verdieping | NLRS_f2_beton ihwg 250 mm | Model Group:NLRS_01.00_verdieping 11--17_gen:4844919
4846255 | 13 dertiende verdieping | NLRS_f2_beton ihwg 250 mm | Model Group:NLRS_01.00_verdieping 11--17_gen:4844988
4846327 | 14 veertiende verdieping | NLRS_f2_beton ihwg 250 mm | Model Group:NLRS_01.00_verdieping 11--17_gen:4845057
4846399 | 15 vijftiende verdieping | NLRS_f2_beton ihwg 250 mm | Model Group:NLRS_01.00_verdieping 11--17_gen:4845126
4846471 | 16 zestiende verdieping | NLRS_f2_beton ihwg 250 mm | Model Group:NLRS_01.00_verdieping 11--17_gen:4845195
4846543 | 17 zeventiende verdieping | NLRS_f2_beton ihwg 250 mm | Model Group:NLRS_01.00_verdieping 11--17_gen:4845336
4846615 | 19 negentiende verdieping | NLRS_f2_beton ihwg 250 mm | Model Group:NLRS_01.00_verdieping 18-19_gen:4845546
4846857 | 22 tweeëntwintigste verdieping | NLRS_f2_beton ihwg 250 mm | Model Group:NLRS_01.00_verdieping 21--23_gen (members excluded):4846692
4846883 | 22 tweeëntwintigste verdieping | NLRS_f2_beton ihwg 250 mm | Model Group:NLRS_01.00_verdieping 21--23_gen (members excluded):4846692
4846936 | 23 dakverdieping | NLRS_f2_beton ihwg 250 mm | Model Group:NLRS_01.00_verdieping 21--23_gen (members excluded):4846692
5751642 | 04 vierde verdieping
5751937 | 04 vierde verdieping
5880473 | 00 begane grond | NLRS_f2_beton ihwg 250 mm |  | 0
5880490 | 00 begane grond | NLRS_f2_beton ihwg 250 mm |  | 0
5880507 | 00 begane grond | NLRS_f2_beton ihwg 250 mm |  | 0
6378739 | 00 begane grond | NLRS_f2_beton ihwg 250 mm |  | 0
6697974 | 05 vijfde verdieping | NLRS_f2_beton ihwg 250 mm | Model Group:NLRS_01.00_verdieping 05_gen (members excluded):6698157
7175396 | 05 vijfde verdieping | NLRS_f2_beton ihwg 250 mm | Model Group:NLRS_01.00_verdieping 05_gen:6691052 | 0
7175419 | 05 vijfde verdieping | NLRS_f2_beton ihwg 250 mm | Model Group:NLRS_01.00_verdieping 05_gen (members excluded):6698157 | 0
7218117 | 06 zesde verdieping | NLRS_f2_beton ihwg 250 mm | Model Group:NLRS_01.00_verdieping 06--10_gen:4600460 | 0
7218141 | 07 zevende verdieping | NLRS_f2_beton ihwg 250 mm | Model Group:NLRS_01.00_verdieping 06--10_gen:4600975 | 0
7218151 | 08 achtste verdieping | NLRS_f2_beton ihwg 250 mm | Model Group:NLRS_01.00_verdieping 06--10_gen:4602043 | 0
7218161 | 09 negende verdieping | NLRS_f2_beton ihwg 250 mm | Model Group:NLRS_01.00_verdieping 06--10_gen:4603152 | 0
7218171 | 10 tiende verdieping | NLRS_f2_beton ihwg 250 mm | Model Group:NLRS_01.00_verdieping 06--10_gen:4604220 | 0
7223366 | 06 zesde verdieping | NLRS_f2_beton ihwg 250 mm | Model Group:NLRS_01.00_verdieping 06--10_gen:4844478 | 0
7223379 | 07 zevende verdieping | NLRS_f2_beton ihwg 250 mm | Model Group:NLRS_01.00_verdieping 06--10_gen:4844553 | 0
7223392 | 08 achtste verdieping | NLRS_f2_beton ihwg 250 mm | Model Group:NLRS_01.00_verdieping 06--10_gen:4844628 | 0
7223405 | 09 negende verdieping | NLRS_f2_beton ihwg 250 mm | Model Group:NLRS_01.00_verdieping 06--10_gen:4844703 | 0
7223418 | 10 tiende verdieping | NLRS_f2_beton ihwg 250 mm | Model Group:NLRS_01.00_verdieping 06--10_gen:4844850 | 0
7233934 | 05 vijfde verdieping | NLRS_f2_beton ihwg 250 mm | Model Group:NLRS_01.00_verdieping 05_gen:6691052 | 0
7233958 | 05 vijfde verdieping | NLRS_f2_beton ihwg 250 mm | Model Group:NLRS_01.00_verdieping 05_gen (members excluded):6698157 | 0
7234283 | 05 vijfde verdieping | NLRS_f2_beton ihwg 250 mm | Model Group:NLRS_01.00_verdieping 05_gen:6691052 | 0
7234306 | 05 vijfde verdieping | NLRS_f2_beton ihwg 250 mm | Model Group:NLRS_01.00_verdieping 05_gen (members excluded):6698157 | 0
7253605 | 20 twintigste verdieping | NLRS_f2_beton ihwg 250 mm | Model Group:NLRS_01.00_verdieping 20_gen:4845671 | 0
7254458 | 20 twintigste verdieping | NLRS_f2_beton ihwg 250 mm | Model Group:NLRS_01.00_verdieping 20_gen:4622361 | 0
7290613 | 05 vijfde verdieping | NLRS_f2_beton ihwg 250 mm | Model Group:NLRS_01.00_verdieping 05_gen:6691052 | 0
7291149 | 05 vijfde verdieping | NLRS_f2_beton ihwg 250 mm | Model Group:NLRS_01.00_verdieping 05_gen (members excluded):6698157 | 0
7291260 | 06 zesde verdieping | NLRS_f2_beton ihwg 250 mm | Model Group:NLRS_01.00_verdieping 06--10_gen:4844478 | 0
7291268 | 06 zesde verdieping | NLRS_f2_beton ihwg 250 mm | Model Group:NLRS_01.00_verdieping 06--10_gen:4844478 | 0
7293809 | 06 zesde verdieping | NLRS_f2_beton ihwg 250 mm | Model Group:NLRS_01.00_verdieping 06--10_gen:4600460 | 0
7293817 | 06 zesde verdieping | NLRS_f2_beton ihwg 250 mm | Model Group:NLRS_01.00_verdieping 06--10_gen:4600460 | 0
7293847 | 07 zevende verdieping | NLRS_f2_beton ihwg 250 mm | Model Group:NLRS_01.00_verdieping 06--10_gen:4600975 | 0
7293855 | 07 zevende verdieping | NLRS_f2_beton ihwg 250 mm | Model Group:NLRS_01.00_verdieping 06--10_gen:4600975 | 0
7293866 | 08 achtste verdieping | NLRS_f2_beton ihwg 250 mm | Model Group:NLRS_01.00_verdieping 06--10_gen:4602043 | 0
7293874 | 08 achtste verdieping | NLRS_f2_beton ihwg 250 mm | Model Group:NLRS_01.00_verdieping 06--10_gen:4602043 | 0
7293885 | 09 negende verdieping | NLRS_f2_beton ihwg 250 mm | Model Group:NLRS_01.00_verdieping 06--10_gen:4603152 | 0
7293893 | 09 negende verdieping | NLRS_f2_beton ihwg 250 mm | Model Group:NLRS_01.00_verdieping 06--10_gen:4603152 | 0
7293904 | 10 tiende verdieping | NLRS_f2_beton ihwg 250 mm | Model Group:NLRS_01.00_verdieping 06--10_gen:4604220 | 0
7293912 | 10 tiende verdieping | NLRS_f2_beton ihwg 250 mm | Model Group:NLRS_01.00_verdieping 06--10_gen:4604220 | 0
7294018 | 07 zevende verdieping | NLRS_f2_beton ihwg 250 mm | Model Group:NLRS_01.00_verdieping 06--10_gen:4844553 | 0
7294026 | 07 zevende verdieping | NLRS_f2_beton ihwg 250 mm | Model Group:NLRS_01.00_verdieping 06--10_gen:4844553 | 0
7294037 | 08 achtste verdieping | NLRS_f2_beton ihwg 250 mm | Model Group:NLRS_01.00_verdieping 06--10_gen:4844628 | 0
7294045 | 08 achtste verdieping | NLRS_f2_beton ihwg 250 mm | Model Group:NLRS_01.00_verdieping 06--10_gen:4844628 | 0
7294056 | 09 negende verdieping | NLRS_f2_beton ihwg 250 mm | Model Group:NLRS_01.00_verdieping 06--10_gen:4844703 | 0
7294064 | 09 negende verdieping | NLRS_f2_beton ihwg 250 mm | Model Group:NLRS_01.00_verdieping 06--10_gen:4844703 | 0
7294075 | 10 tiende verdieping | NLRS_f2_beton ihwg 250 mm | Model Group:NLRS_01.00_verdieping 06--10_gen:4844850 | 0
7294083 | 10 tiende verdieping | NLRS_f2_beton ihwg 250 mm | Model Group:NLRS_01.00_verdieping 06--10_gen:4844850 | 0
7296393 | 11 elfde verdieping | NLRS_f2_beton ihwg 250 mm | Model Group:NLRS_01.00_verdieping 11--17_gen:4845821 | 0
7298501 | 12 twaalfde verdieping | NLRS_f2_beton ihwg 250 mm | Model Group:NLRS_01.00_verdieping 11--17_gen:4609129 | 0
7298539 | 13 dertiende verdieping | NLRS_f2_beton ihwg 250 mm | Model Group:NLRS_01.00_verdieping 11--17_gen:4609592 | 0
7298558 | 14 veertiende verdieping | NLRS_f2_beton ihwg 250 mm | Model Group:NLRS_01.00_verdieping 11--17_gen:4610618 | 0
7298577 | 15 vijftiende verdieping | NLRS_f2_beton ihwg 250 mm | Model Group:NLRS_01.00_verdieping 11--17_gen:4611642 | 0
7298596 | 16 zestiende verdieping | NLRS_f2_beton ihwg 250 mm | Model Group:NLRS_01.00_verdieping 11--17_gen:4612668 | 0
7298615 | 17 zeventiende verdieping | NLRS_f2_beton ihwg 250 mm | Model Group:NLRS_01.00_verdieping 11--17_gen:4613692 | 0
7298634 | 11 elfde verdieping | NLRS_f2_beton ihwg 250 mm | Model Group:NLRS_01.00_verdieping 11--17_gen:4626135 | 0
7298786 | 12 twaalfde verdieping | NLRS_f2_beton ihwg 250 mm | Model Group:NLRS_01.00_verdieping 11--17_gen:4844919 | 0
7298805 | 13 dertiende verdieping | NLRS_f2_beton ihwg 250 mm | Model Group:NLRS_01.00_verdieping 11--17_gen:4844988 | 0
7298824 | 14 veertiende verdieping | NLRS_f2_beton ihwg 250 mm | Model Group:NLRS_01.00_verdieping 11--17_gen:4845057 | 0
7298843 | 15 vijftiende verdieping | NLRS_f2_beton ihwg 250 mm | Model Group:NLRS_01.00_verdieping 11--17_gen:4845126 | 0
7298862 | 16 zestiende verdieping | NLRS_f2_beton ihwg 250 mm | Model Group:NLRS_01.00_verdieping 11--17_gen:4845195 | 0
7298881 | 17 zeventiende verdieping | NLRS_f2_beton ihwg 250 mm | Model Group:NLRS_01.00_verdieping 11--17_gen:4845336 | 0
7300170 | 18 achttiende verdieping | NLRS_f2_beton ihwg 250 mm | Model Group:NLRS_01.00_verdieping 18-19_gen:4845405 | 0
7300793 | 18 achttiende verdieping | NLRS_f2_beton ihwg 250 mm | Model Group:NLRS_01.00_verdieping 18-19_gen:4617185 | 0
7300831 | 19 negentiende verdieping | NLRS_f2_beton ihwg 250 mm | Model Group:NLRS_01.00_verdieping 18-19_gen:4617669 | 0
7300888 | 19 negentiende verdieping | NLRS_f2_beton ihwg 250 mm | Model Group:NLRS_01.00_verdieping 18-19_gen:4845546 | 0
7301419 | 06 zesde verdieping | NLRS_f2_beton ihwg 250 mm | Model Group:NLRS_01.00_verdieping 06--10_gen:4844478 | 0
7302530 | 06 zesde verdieping | NLRS_f2_beton ihwg 250 mm | Model Group:NLRS_01.00_verdieping 06--10_gen:4600460 | 0
7302550 | 07 zevende verdieping | NLRS_f2_beton ihwg 250 mm | Model Group:NLRS_01.00_verdieping 06--10_gen:4600975 | 0
7302560 | 08 achtste verdieping | NLRS_f2_beton ihwg 250 mm | Model Group:NLRS_01.00_verdieping 06--10_gen:4602043 | 0
7302570 | 09 negende verdieping | NLRS_f2_beton ihwg 250 mm | Model Group:NLRS_01.00_verdieping 06--10_gen:4603152 | 0
7302580 | 10 tiende verdieping | NLRS_f2_beton ihwg 250 mm | Model Group:NLRS_01.00_verdieping 06--10_gen:4604220 | 0
7302640 | 07 zevende verdieping | NLRS_f2_beton ihwg 250 mm | Model Group:NLRS_01.00_verdieping 06--10_gen:4844553 | 0
7302650 | 08 achtste verdieping | NLRS_f2_beton ihwg 250 mm | Model Group:NLRS_01.00_verdieping 06--10_gen:4844628 | 0
7302660 | 09 negende verdieping | NLRS_f2_beton ihwg 250 mm | Model Group:NLRS_01.00_verdieping 06--10_gen:4844703 | 0
7302670 | 10 tiende verdieping | NLRS_f2_beton ihwg 250 mm | Model Group:NLRS_01.00_verdieping 06--10_gen:4844850 | 0
7302700 | 11 elfde verdieping | NLRS_f2_beton ihwg 250 mm | Model Group:NLRS_01.00_verdieping 11--17_gen:4845821 | 0
7302709 | 11 elfde verdieping | NLRS_f2_beton ihwg 250 mm | Model Group:NLRS_01.00_verdieping 11--17_gen:4845821 | 0
7304133 | 12 twaalfde verdieping | NLRS_f2_beton ihwg 250 mm | Model Group:NLRS_01.00_verdieping 11--17_gen:4609129 | 0
7304142 | 12 twaalfde verdieping | NLRS_f2_beton ihwg 250 mm | Model Group:NLRS_01.00_verdieping 11--17_gen:4609129 | 0
7304171 | 13 dertiende verdieping | NLRS_f2_beton ihwg 250 mm | Model Group:NLRS_01.00_verdieping 11--17_gen:4609592 | 0
7304180 | 13 dertiende verdieping | NLRS_f2_beton ihwg 250 mm | Model Group:NLRS_01.00_verdieping 11--17_gen:4609592 | 0
7304190 | 14 veertiende verdieping | NLRS_f2_beton ihwg 250 mm | Model Group:NLRS_01.00_verdieping 11--17_gen:4610618 | 0
7304199 | 14 veertiende verdieping | NLRS_f2_beton ihwg 250 mm | Model Group:NLRS_01.00_verdieping 11--17_gen:4610618 | 0
7304209 | 15 vijftiende verdieping | NLRS_f2_beton ihwg 250 mm | Model Group:NLRS_01.00_verdieping 11--17_gen:4611642 | 0
7304218 | 15 vijftiende verdieping | NLRS_f2_beton ihwg 250 mm | Model Group:NLRS_01.00_verdieping 11--17_gen:4611642 | 0
7304228 | 16 zestiende verdieping | NLRS_f2_beton ihwg 250 mm | Model Group:NLRS_01.00_verdieping 11--17_gen:4612668 | 0
7304237 | 16 zestiende verdieping | NLRS_f2_beton ihwg 250 mm | Model Group:NLRS_01.00_verdieping 11--17_gen:4612668 | 0
7304247 | 17 zeventiende verdieping | NLRS_f2_beton ihwg 250 mm | Model Group:NLRS_01.00_verdieping 11--17_gen:4613692 | 0
7304256 | 17 zeventiende verdieping | NLRS_f2_beton ihwg 250 mm | Model Group:NLRS_01.00_verdieping 11--17_gen:4613692 | 0
7304266 | 11 elfde verdieping | NLRS_f2_beton ihwg 250 mm | Model Group:NLRS_01.00_verdieping 11--17_gen:4626135 | 0
7304275 | 11 elfde verdieping | NLRS_f2_beton ihwg 250 mm | Model Group:NLRS_01.00_verdieping 11--17_gen:4626135 | 0
7304418 | 12 twaalfde verdieping | NLRS_f2_beton ihwg 250 mm | Model Group:NLRS_01.00_verdieping 11--17_gen:4844919 | 0
7304427 | 12 twaalfde verdieping | NLRS_f2_beton ihwg 250 mm | Model Group:NLRS_01.00_verdieping 11--17_gen:4844919 | 0
7304437 | 13 dertiende verdieping | NLRS_f2_beton ihwg 250 mm | Model Group:NLRS_01.00_verdieping 11--17_gen:4844988 | 0
7304446 | 13 dertiende verdieping | NLRS_f2_beton ihwg 250 mm | Model Group:NLRS_01.00_verdieping 11--17_gen:4844988 | 0
7304456 | 14 veertiende verdieping | NLRS_f2_beton ihwg 250 mm | Model Group:NLRS_01.00_verdieping 11--17_gen:4845057 | 0
7304465 | 14 veertiende verdieping | NLRS_f2_beton ihwg 250 mm | Model Group:NLRS_01.00_verdieping 11--17_gen:4845057 | 0
7304475 | 15 vijftiende verdieping | NLRS_f2_beton ihwg 250 mm | Model Group:NLRS_01.00_verdieping 11--17_gen:4845126 | 0
7304484 | 15 vijftiende verdieping | NLRS_f2_beton ihwg 250 mm | Model Group:NLRS_01.00_verdieping 11--17_gen:4845126 | 0
7304494 | 16 zestiende verdieping | NLRS_f2_beton ihwg 250 mm | Model Group:NLRS_01.00_verdieping 11--17_gen:4845195 | 0
7304503 | 16 zestiende verdieping | NLRS_f2_beton ihwg 250 mm | Model Group:NLRS_01.00_verdieping 11--17_gen:4845195 | 0
7304513 | 17 zeventiende verdieping | NLRS_f2_beton ihwg 250 mm | Model Group:NLRS_01.00_verdieping 11--17_gen:4845336 | 0
7304522 | 17 zeventiende verdieping | NLRS_f2_beton ihwg 250 mm | Model Group:NLRS_01.00_verdieping 11--17_gen:4845336 | 0
7304769 | 18 achttiende verdieping | NLRS_f2_beton ihwg 250 mm | Model Group:NLRS_01.00_verdieping 18-19_gen:4845405 | 0
7304778 | 18 achttiende verdieping | NLRS_f2_beton ihwg 250 mm | Model Group:NLRS_01.00_verdieping 18-19_gen:4845405 | 0
7305197 | 18 achttiende verdieping | NLRS_f2_beton ihwg 250 mm | Model Group:NLRS_01.00_verdieping 18-19_gen:4617185 | 0
7305206 | 18 achttiende verdieping | NLRS_f2_beton ihwg 250 mm | Model Group:NLRS_01.00_verdieping 18-19_gen:4617185 | 0
7305235 | 19 negentiende verdieping | NLRS_f2_beton ihwg 250 mm | Model Group:NLRS_01.00_verdieping 18-19_gen:4617669 | 0
7305244 | 19 negentiende verdieping | NLRS_f2_beton ihwg 250 mm | Model Group:NLRS_01.00_verdieping 18-19_gen:4617669 | 0
7305292 | 19 negentiende verdieping | NLRS_f2_beton ihwg 250 mm | Model Group:NLRS_01.00_verdieping 18-19_gen:4845546 | 0
7305301 | 19 negentiende verdieping | NLRS_f2_beton ihwg 250 mm | Model Group:NLRS_01.00_verdieping 18-19_gen:4845546 | 0
7305376 | 20 twintigste verdieping | NLRS_f2_beton ihwg 250 mm | Model Group:NLRS_01.00_verdieping 20_gen:4845671 | 0
7305428 | 20 twintigste verdieping | NLRS_f2_beton ihwg 250 mm | Model Group:NLRS_01.00_verdieping 20_gen:4622361 | 0
10900035 | 22 tweeëntwintigste verdieping | NLRS_f2_beton ihwg 250 mm | Model Group:NLRS_01.00_verdieping 21--23_gen (members excluded):4846692
10901381 | 22 tweeëntwintigste verdieping | NLRS_f2_beton ihwg 250 mm | Model Group:NLRS_01.00_verdieping 21--23_gen (members excluded):4647240
10906785 | 22 tweeëntwintigste verdieping | NLRS_f2_beton ihwg 250 mm | Model Group:NLRS_01.00_verdieping 21--23_gen (members excluded):4846692
10908000 | 22 tweeëntwintigste verdieping | NLRS_f2_beton ihwg 250 mm | Model Group:NLRS_01.00_verdieping 21--23_gen (members excluded):4647240
11470243 | 01c derde tussenverdieping | NLRS_f2_beton ihwg 250 mm |  | 0
11470288 | 01c derde tussenverdieping | NLRS_f2_beton ihwg 250 mm |  | 0
11470317 | 02b tweede tussenverdieping | NLRS_f2_beton ihwg 250 mm |  | 0
11470349 | 01c derde tussenverdieping | NLRS_f2_beton ihwg 250 mm
11471834 | 01c derde tussenverdieping | NLRS_f2_beton ihwg 250 mm |  | 0
12174700 | 05 vijfde verdieping | NLRS_f2_beton ihwg 250 mm | Model Group:NLRS_01.00_verdieping 05_gen:6691052 | 0
12175145 | 05 vijfde verdieping | NLRS_f2_beton ihwg 250 mm | Model Group:NLRS_01.00_verdieping 05_gen (members excluded):6698157 | 0
12184262 | 06 zesde verdieping | NLRS_f2_beton ihwg 250 mm | Model Group:NLRS_01.00_verdieping 06--10_gen:4844478 | 0
12185531 | 06 zesde verdieping | NLRS_f2_beton ihwg 250 mm | Model Group:NLRS_01.00_verdieping 06--10_gen:4600460 | 0
12185559 | 07 zevende verdieping | NLRS_f2_beton ihwg 250 mm | Model Group:NLRS_01.00_verdieping 06--10_gen:4600975 | 0
12185573 | 08 achtste verdieping | NLRS_f2_beton ihwg 250 mm | Model Group:NLRS_01.00_verdieping 06--10_gen:4602043 | 0
12185587 | 09 negende verdieping | NLRS_f2_beton ihwg 250 mm | Model Group:NLRS_01.00_verdieping 06--10_gen:4603152 | 0
12185601 | 10 tiende verdieping | NLRS_f2_beton ihwg 250 mm | Model Group:NLRS_01.00_verdieping 06--10_gen:4604220 | 0
12185685 | 07 zevende verdieping | NLRS_f2_beton ihwg 250 mm | Model Group:NLRS_01.00_verdieping 06--10_gen:4844553 | 0
12185699 | 08 achtste verdieping | NLRS_f2_beton ihwg 250 mm | Model Group:NLRS_01.00_verdieping 06--10_gen:4844628 | 0
12185713 | 09 negende verdieping | NLRS_f2_beton ihwg 250 mm | Model Group:NLRS_01.00_verdieping 06--10_gen:4844703 | 0
12185727 | 10 tiende verdieping | NLRS_f2_beton ihwg 250 mm | Model Group:NLRS_01.00_verdieping 06--10_gen:4844850 | 0
12186222 | 12 twaalfde verdieping | NLRS_f2_beton ihwg 250 mm | Model Group:NLRS_01.00_verdieping 11--17_gen:4844919 | 0
12187946 | 12 twaalfde verdieping | NLRS_f2_beton ihwg 250 mm | Model Group:NLRS_01.00_verdieping 11--17_gen:4609129 | 0
12187970 | 13 dertiende verdieping | NLRS_f2_beton ihwg 250 mm | Model Group:NLRS_01.00_verdieping 11--17_gen:4609592 | 0
12187982 | 14 veertiende verdieping | NLRS_f2_beton ihwg 250 mm | Model Group:NLRS_01.00_verdieping 11--17_gen:4610618 | 0
12187994 | 15 vijftiende verdieping | NLRS_f2_beton ihwg 250 mm | Model Group:NLRS_01.00_verdieping 11--17_gen:4611642 | 0
12188006 | 16 zestiende verdieping | NLRS_f2_beton ihwg 250 mm | Model Group:NLRS_01.00_verdieping 11--17_gen:4612668 | 0
12188018 | 17 zeventiende verdieping | NLRS_f2_beton ihwg 250 mm | Model Group:NLRS_01.00_verdieping 11--17_gen:4613692 | 0
12188030 | 11 elfde verdieping | NLRS_f2_beton ihwg 250 mm | Model Group:NLRS_01.00_verdieping 11--17_gen:4626135 | 0
12188126 | 13 dertiende verdieping | NLRS_f2_beton ihwg 250 mm | Model Group:NLRS_01.00_verdieping 11--17_gen:4844988 | 0
12188138 | 14 veertiende verdieping | NLRS_f2_beton ihwg 250 mm | Model Group:NLRS_01.00_verdieping 11--17_gen:4845057 | 0
12188150 | 15 vijftiende verdieping | NLRS_f2_beton ihwg 250 mm | Model Group:NLRS_01.00_verdieping 11--17_gen:4845126 | 0
12188162 | 16 zestiende verdieping | NLRS_f2_beton ihwg 250 mm | Model Group:NLRS_01.00_verdieping 11--17_gen:4845195 | 0
12188174 | 17 zeventiende verdieping | NLRS_f2_beton ihwg 250 mm | Model Group:NLRS_01.00_verdieping 11--17_gen:4845336 | 0
12188186 | 11 elfde verdieping | NLRS_f2_beton ihwg 250 mm | Model Group:NLRS_01.00_verdieping 11--17_gen:4845821 | 0
12188246 | 18 achttiende verdieping | NLRS_f2_beton ihwg 250 mm | Model Group:NLRS_01.00_verdieping 18-19_gen:4845405 | 0
12188882 | 18 achttiende verdieping | NLRS_f2_beton ihwg 250 mm | Model Group:NLRS_01.00_verdieping 18-19_gen:4617185 | 0
12188910 | 19 negentiende verdieping | NLRS_f2_beton ihwg 250 mm | Model Group:NLRS_01.00_verdieping 18-19_gen:4617669 | 0
12188952 | 19 negentiende verdieping | NLRS_f2_beton ihwg 250 mm | Model Group:NLRS_01.00_verdieping 18-19_gen:4845546 | 0
12189020 | 20 twintigste verdieping | NLRS_f2_beton ihwg 250 mm | Model Group:NLRS_01.00_verdieping 20_gen:4845671 | 0
12189302 | 20 twintigste verdieping | NLRS_f2_beton ihwg 250 mm | Model Group:NLRS_01.00_verdieping 20_gen:4622361 | 0
12189381 | 21 eenentwintigste verdieping | NLRS_f2_beton ihwg 250 mm | Model Group:NLRS_01.00_verdieping 21--23_gen (members excluded):4846692 | 0
12192267 | 21 eenentwintigste verdieping | NLRS_f2_beton ihwg 250 mm | Model Group:NLRS_01.00_verdieping 21--23_gen (members excluded):4647240 | 0
12193028 | 05 vijfde verdieping | NLRS_f2_beton ihwg 250 mm | Model Group:NLRS_01.00_verdieping 05_gen:6691052 | 0
12194301 | 05 vijfde verdieping | NLRS_f2_beton ihwg 250 mm | Model Group:NLRS_01.00_verdieping 05_gen (members excluded):6698157 | 0
12194704 | 06 zesde verdieping | NLRS_f2_beton ihwg 250 mm | Model Group:NLRS_01.00_verdieping 06--10_gen:4844478 | 0
12198398 | 06 zesde verdieping | NLRS_f2_beton ihwg 250 mm | Model Group:NLRS_01.00_verdieping 06--10_gen:4600460 | 0
12198424 | 07 zevende verdieping | NLRS_f2_beton ihwg 250 mm | Model Group:NLRS_01.00_verdieping 06--10_gen:4600975 | 0
12198437 | 08 achtste verdieping | NLRS_f2_beton ihwg 250 mm | Model Group:NLRS_01.00_verdieping 06--10_gen:4602043 | 0
12198450 | 09 negende verdieping | NLRS_f2_beton ihwg 250 mm | Model Group:NLRS_01.00_verdieping 06--10_gen:4603152 | 0
12198463 | 10 tiende verdieping | NLRS_f2_beton ihwg 250 mm | Model Group:NLRS_01.00_verdieping 06--10_gen:4604220 | 0
12198541 | 07 zevende verdieping | NLRS_f2_beton ihwg 250 mm | Model Group:NLRS_01.00_verdieping 06--10_gen:4844553 | 0
12198554 | 08 achtste verdieping | NLRS_f2_beton ihwg 250 mm | Model Group:NLRS_01.00_verdieping 06--10_gen:4844628 | 0
12198567 | 09 negende verdieping | NLRS_f2_beton ihwg 250 mm | Model Group:NLRS_01.00_verdieping 06--10_gen:4844703 | 0
12198580 | 10 tiende verdieping | NLRS_f2_beton ihwg 250 mm | Model Group:NLRS_01.00_verdieping 06--10_gen:4844850 | 0
12199267 | 11 elfde verdieping | NLRS_f2_beton ihwg 250 mm | Model Group:NLRS_01.00_verdieping 11--17_gen:4845821 | 0
12203414 | 12 twaalfde verdieping | NLRS_f2_beton ihwg 250 mm | Model Group:NLRS_01.00_verdieping 11--17_gen:4609129 | 0
12203440 | 13 dertiende verdieping | NLRS_f2_beton ihwg 250 mm | Model Group:NLRS_01.00_verdieping 11--17_gen:4609592 | 0
12203453 | 14 veertiende verdieping | NLRS_f2_beton ihwg 250 mm | Model Group:NLRS_01.00_verdieping 11--17_gen:4610618 | 0
12203466 | 15 vijftiende verdieping | NLRS_f2_beton ihwg 250 mm | Model Group:NLRS_01.00_verdieping 11--17_gen:4611642 | 0
12203479 | 16 zestiende verdieping | NLRS_f2_beton ihwg 250 mm | Model Group:NLRS_01.00_verdieping 11--17_gen:4612668 | 0
12203492 | 17 zeventiende verdieping | NLRS_f2_beton ihwg 250 mm | Model Group:NLRS_01.00_verdieping 11--17_gen:4613692 | 0
12203505 | 11 elfde verdieping | NLRS_f2_beton ihwg 250 mm | Model Group:NLRS_01.00_verdieping 11--17_gen:4626135 | 0
12203609 | 12 twaalfde verdieping | NLRS_f2_beton ihwg 250 mm | Model Group:NLRS_01.00_verdieping 11--17_gen:4844919 | 0
12203622 | 13 dertiende verdieping | NLRS_f2_beton ihwg 250 mm | Model Group:NLRS_01.00_verdieping 11--17_gen:4844988 | 0
12203635 | 14 veertiende verdieping | NLRS_f2_beton ihwg 250 mm | Model Group:NLRS_01.00_verdieping 11--17_gen:4845057 | 0
12203648 | 15 vijftiende verdieping | NLRS_f2_beton ihwg 250 mm | Model Group:NLRS_01.00_verdieping 11--17_gen:4845126 | 0
12203661 | 16 zestiende verdieping | NLRS_f2_beton ihwg 250 mm | Model Group:NLRS_01.00_verdieping 11--17_gen:4845195 | 0
12203674 | 17 zeventiende verdieping | NLRS_f2_beton ihwg 250 mm | Model Group:NLRS_01.00_verdieping 11--17_gen:4845336 | 0
12205442 | 18 achttiende verdieping | NLRS_f2_beton ihwg 250 mm | Model Group:NLRS_01.00_verdieping 18-19_gen:4845405 | 0
12206525 | 18 achttiende verdieping | NLRS_f2_beton ihwg 250 mm | Model Group:NLRS_01.00_verdieping 18-19_gen:4617185 | 0
12206551 | 19 negentiende verdieping | NLRS_f2_beton ihwg 250 mm | Model Group:NLRS_01.00_verdieping 18-19_gen:4617669 | 0
12206590 | 19 negentiende verdieping | NLRS_f2_beton ihwg 250 mm | Model Group:NLRS_01.00_verdieping 18-19_gen:4845546 | 0
12207107 | 20 twintigste verdieping | NLRS_f2_beton ihwg 250 mm | Model Group:NLRS_01.00_verdieping 20_gen:4845671 | 0
12207614 | 20 twintigste verdieping | NLRS_f2_beton ihwg 250 mm | Model Group:NLRS_01.00_verdieping 20_gen:4622361 | 0
12208015 | 21 eenentwintigste verdieping | NLRS_f2_beton ihwg 250 mm | Model Group:NLRS_01.00_verdieping 21--23_gen (members excluded):4846692 | 0
12209207 | 21 eenentwintigste verdieping | NLRS_f2_beton ihwg 250 mm | Model Group:NLRS_01.00_verdieping 21--23_gen (members excluded):4647240 | 0

# IfcSlab: Floor:NLRS_23.21_FL_beton ihwg d=255_gen (6)
PredefinedType: FLOOR; Classification: 23.21 vloeren - constructief, vrijdragende vloeren (Uniformat); Material: NLRS_f2_beton ihwg 255 mm
Pset_SlabCommon - LoadBearing: yes; IsExternal: no; Reference: NLRS_23.21_FL_beton ihwg d=255_gen; ThermalTransmittance: 4.10196 kg/K/s3
Name (Floor:NLRS_23.21_FL_beton ihwg d=255_gen:...) | In
8614351 | 01a eerste tussenverdieping
8752822 | 01c derde tussenverdieping
8752910 | 02b tweede tussenverdieping
8764299 | 01a eerste tussenverdieping
8768356 | 01c derde tussenverdieping
9081642 | 02b tweede tussenverdieping

# IfcSlab: Floor:NLRS_23.21_FL_beton ihwg d=260_gen (3)
PredefinedType: FLOOR; Classification: 23.21 vloeren - constructief, vrijdragende vloeren (Uniformat); Material: NLRS_f2_beton ihwg 260 mm
Pset_SlabCommon - LoadBearing: yes; IsExternal: no; PitchAngle: 0 deg; Reference: NLRS_23.21_FL_beton ihwg d=260_gen; ThermalTransmittance: 4.02308 kg/K/s3
Name (Floor:NLRS_23.21_FL_beton ihwg d=260_gen:...) | In
6035592 | 02b tweede tussenverdieping
6035619 | 01c derde tussenverdieping
6035660 | 01a eerste tussenverdieping

# IfcSlab: Floor:NLRS_23.21_FL_beton ihwg d=270_gen (2)
PredefinedType: FLOOR; Classification: 23.21 vloeren - constructief, vrijdragende vloeren (Uniformat); Material: NLRS_f2_beton ihwg 270 mm
Pset_SlabCommon - LoadBearing: yes; IsExternal: no; PitchAngle: 0 deg; Reference: NLRS_23.21_FL_beton ihwg d=270_gen; ThermalTransmittance: 3.87407 kg/K/s3
Name (Floor:NLRS_23.21_FL_beton ihwg d=270_gen:...) | In
5719593 | 04 vierde verdieping
6731287 | 02a eerste tussenverdieping

# IfcSlab: Floor:NLRS_23.21_FL_beton ihwg d=280_gen, Floor:NLRS_23.21_FL_beton ihwg d=280_gen:13061159
In: 00 begane grond
PredefinedType: FLOOR; Classification: 23.21 vloeren - constructief, vrijdragende vloeren (Uniformat); Material: NLRS_f2_beton ihwg 280 mm
Pset_SlabCommon - LoadBearing: yes; IsExternal: no; PitchAngle: 0 deg; Reference: NLRS_23.21_FL_beton ihwg d=280_gen; ThermalTransmittance: 3.73571 kg/K/s3

# IfcSlab: Floor:NLRS_23.21_FL_beton ihwg d=332_gen (2)
In: 00 begane grond
PredefinedType: FLOOR; Classification: 23.21 vloeren - constructief, vrijdragende vloeren (Uniformat); Material: NLRS_f2_beton ihwg 332 mm
Pset_SlabCommon - LoadBearing: yes; IsExternal: no; PitchAngle: 0 deg; Reference: NLRS_23.21_FL_beton ihwg d=332_gen; ThermalTransmittance: 3.1506 kg/K/s3
Name (Floor:NLRS_23.21_FL_beton ihwg d=332_gen:...)
6081470
6498006

# IfcSlab: Floor:NLRS_23.21_FL_beton ihwg d=350_gen (2)
In: 00 begane grond
PredefinedType: FLOOR; Classification: 23.21 vloeren - constructief, vrijdragende vloeren (Uniformat); Material: NLRS_f2_beton ihwg 350 mm
Pset_SlabCommon - LoadBearing: yes; IsExternal: no; Reference: NLRS_23.21_FL_beton ihwg d=350_gen; ThermalTransmittance: 2.98857 kg/K/s3
Name (Floor:NLRS_23.21_FL_beton ihwg d=350_gen:...)
4195541
5014881

# IfcSlab: Floor:NLRS_23.21_FL_beton ihwg d=410_gen, Floor:NLRS_23.21_FL_beton ihwg d=410_gen:6035636
In: 04 vierde verdieping
PredefinedType: FLOOR; Classification: 23.21 vloeren - constructief, vrijdragende vloeren (Uniformat); Material: NLRS_f2_beton ihwg 410 mm
Pset_SlabCommon - LoadBearing: yes; IsExternal: no; PitchAngle: 0 deg; Reference: NLRS_23.21_FL_beton ihwg d=410_gen; ThermalTransmittance: 2.55122 kg/K/s3

# IfcSlab: Floor:NLRS_23.21_FL_beton ihwg d=70_gen (4)
In: 00 begane grond
PredefinedType: FLOOR; Classification: 23.21 vloeren - constructief, vrijdragende vloeren (Uniformat); Material: NLRS_f2_beton ihwg 70 mm
Pset_SlabCommon - LoadBearing: yes; IsExternal: no; PitchAngle: 0 deg; Reference: NLRS_23.21_FL_beton ihwg d=70_gen; ThermalTransmittance: 14.9429 kg/K/s3
Name (Floor:NLRS_23.21_FL_beton ihwg d=70_gen:...)
8006143
8006165
8006275
8006284

# IfcSlab: Floor:NLRS_23.21_FL_beton ihwg d=90_gen (20)
In: 00 begane grond
PredefinedType: FLOOR; Classification: 23.21 vloeren - constructief, vrijdragende vloeren (Uniformat); Material: NLRS_f2_beton ihwg 90 mm
Pset_SlabCommon - LoadBearing: yes; IsExternal: no; Reference: NLRS_23.21_FL_beton ihwg d=90_gen; ThermalTransmittance: 11.6222 kg/K/s3
Name (Floor:NLRS_23.21_FL_beton ihwg d=90_gen:...) | PitchAngle (deg)
6037612 | 0
6037775 | 0
6040882
6040882:2
6040882:3
6048571 | 0
6048609 | 0
6073534 | 0
6075661 | 0
6499970 | 0
6499985 | 0
6500480
6500480:2
6501945 | 0
7065491
7065491:2
7065491:3
8006201 | 0
8006211 | 0
10124212 | 0

# IfcSlab: Floor:NLRS_23.21_FL_beton ihwg d=var_gen (4)
In: 04 vierde verdieping
PredefinedType: FLOOR; Classification: 23.21 vloeren - constructief, vrijdragende vloeren (Uniformat)
Pset_SlabCommon - LoadBearing: yes; IsExternal: no; Reference: NLRS_23.21_FL_beton ihwg d=var_gen; ThermalTransmittance: 1046 kg/K/s3
Name (Floor:NLRS_23.21_FL_beton ihwg d=var_gen:...) | Material
10120606 | NLRS_f2_beton ihwg 1 mm
10135169 | NLRS_f2_beton ihwg 1 mm
10136523
10136564 | NLRS_f2_beton ihwg 1 mm | Pset_SlabCommon - PitchAngle: 0 deg

# IfcSlab: Floor:NLRS_23.21_FL_beton prefab d=180_gen, Floor:NLRS_23.21_FL_beton prefab d=180_gen:5916136
In: 00 begane grond
PredefinedType: FLOOR; Classification: 23.21 vloeren - constructief, vrijdragende vloeren (Uniformat); Material: NLRS_f2_beton prefab 180 mm
Pset_SlabCommon - LoadBearing: yes; IsExternal: no; PitchAngle: 0 deg; Reference: NLRS_23.21_FL_beton prefab d=180_gen; ThermalTransmittance: 5.81111 kg/K/s3

# IfcSlab: Floor:NLRS_23.21_FL_beton prefab d=200_gen (2)
PredefinedType: FLOOR; Classification: 23.21 vloeren - constructief, vrijdragende vloeren (Uniformat); Material: NLRS_f2_beton prefab 200 mm
Pset_SlabCommon - LoadBearing: yes; IsExternal: no; Reference: NLRS_23.21_FL_beton prefab d=200_gen; ThermalTransmittance: 5.23 kg/K/s3
Name (Floor:NLRS_23.21_FL_beton prefab d=200_gen:...) | In
4526203 | 00a eerste tussenverdieping | Pset_SlabCommon - PitchAngle: 0 deg
11786973 | 06 zesde verdieping

# IfcSlab: Floor:NLRS_23.21_FL_breedplaat d=50/200_schil apart - gevlinderd en ingestrooid_gen, Floor:NLRS_23.21_FL_breedplaat d=50/200_schil apart - gevlinderd en ingestrooid_gen:5711680
In: 01b tweede tussenverdieping
PredefinedType: FLOOR; Classification: 23.21 vloeren - constructief, vrijdragende vloeren (Uniformat); Material: NLRS_f2_beton ihwg 200 mm
Pset_SlabCommon - LoadBearing: yes; IsExternal: no; Reference: NLRS_23.21_FL_breedplaat d=50/200_schil apart - gevlinderd en ingestrooid_gen; ThermalTransmittance: 5.23 kg/K/s3

# IfcSlab: Floor:NLRS_23.21_FL_breedplaat d=50/230_schil apart_gen (7)
In: 03 derde verdieping
PredefinedType: FLOOR; Classification: 23.21 vloeren - constructief, vrijdragende vloeren (Uniformat)
Pset_SlabCommon - LoadBearing: yes; IsExternal: no; Reference: NLRS_23.21_FL_breedplaat d=50/230_schil apart_gen; ThermalTransmittance: 4.54783 kg/K/s3
Name (Floor:NLRS_23.21_FL_breedplaat d=50/230_schil apart_gen:...)
4943966 | Material: NLRS_f2_beton ihwg 230 mm
4944942
4944966 | Material: NLRS_f2_beton ihwg 230 mm
4944989
4945013 | Material: NLRS_f2_beton ihwg 230 mm
6446422
6446444

# IfcSlab: Floor:NLRS_23.21_FL_breedplaat d=50/250_gen (2)
In: 02b tweede tussenverdieping
PredefinedType: FLOOR; Classification: 23.21 vloeren - constructief, vrijdragende vloeren (Uniformat); Material: NLRS_f2_beton ihwg 200 mm, NLRS_f2_beton prefab 50 mm
Pset_SlabCommon - LoadBearing: yes; IsExternal: no; PitchAngle: 0 deg; Reference: NLRS_23.21_FL_breedplaat d=50/250_gen; ThermalTransmittance: 4.184 kg/K/s3
Name (Floor:NLRS_23.21_FL_breedplaat d=50/250_gen:...)
6928892
6928909

# IfcSlab: Floor:NLRS_23.21_FL_breedplaat d=70/200_schil apart_gen (2)
In: 00a eerste tussenverdieping
PredefinedType: FLOOR; Classification: 23.21 vloeren - constructief, vrijdragende vloeren (Uniformat)
Pset_SlabCommon - LoadBearing: yes; IsExternal: no; Reference: NLRS_23.21_FL_breedplaat d=70/200_schil apart_gen; ThermalTransmittance: 5.23 kg/K/s3
Name (Floor:NLRS_23.21_FL_breedplaat d=70/200_schil apart_gen:...) | Material
5710067 | NLRS_f2_beton ihwg
5712835 | NLRS_f2_beton ihwg 200 mm | Pset_SlabCommon - PitchAngle: 0 deg

# IfcSlab: Floor:NLRS_23.21_FL_breedplaat d=70/250_opgeruwd_schil apart_gen (23)
PredefinedType: FLOOR; Classification: 23.21 vloeren - constructief, vrijdragende vloeren (Uniformat)
Pset_SlabCommon - LoadBearing: yes; IsExternal: no; Reference: NLRS_23.21_FL_breedplaat d=70/250_opgeruwd_schil apart_gen; ThermalTransmittance: 4.184 kg/K/s3
Name (Floor:NLRS_23.21_FL_breedplaat d=70/250_opgeruwd_schil apart_gen:...) | In | Material
5130914 | 00 begane grond | NLRS_f2_beton ihwg
5135531 | 00a eerste tussenverdieping | NLRS_f2_beton ihwg 250 mm
5135541 | 00 begane grond | NLRS_f2_beton ihwg 250 mm
5135550 | 00 begane grond | NLRS_f2_beton ihwg 250 mm | Pset_SlabCommon - PitchAngle: 0 deg
5135827 | 01b tweede tussenverdieping | NLRS_f2_beton ihwg 250 mm
5135837 | 01b tweede tussenverdieping | NLRS_f2_beton ihwg 250 mm
5135846 | 01b tweede tussenverdieping | NLRS_f2_beton ihwg 250 mm
5135967 | 00a eerste tussenverdieping | NLRS_f2_beton ihwg 250 mm
5143093 | 00 begane grond | NLRS_f2_beton ihwg 250 mm
5144308 | 01b tweede tussenverdieping | NLRS_f2_beton ihwg 250 mm
5144318 | 01b tweede tussenverdieping | NLRS_f2_beton ihwg 250 mm | Pset_SlabCommon - PitchAngle: 0 deg
5144327 | 01b tweede tussenverdieping | NLRS_f2_beton ihwg 250 mm
5144338 | 00a eerste tussenverdieping | NLRS_f2_beton ihwg 250 mm
7510806 | 02a eerste tussenverdieping | NLRS_f2_beton ihwg 250 mm
7510816 | 02a eerste tussenverdieping | NLRS_f2_beton ihwg 250 mm
7510825 | 02a eerste tussenverdieping | NLRS_f2_beton ihwg 250 mm
7511834 | 02a eerste tussenverdieping | NLRS_f2_beton ihwg 250 mm
7511844 | 02a eerste tussenverdieping | NLRS_f2_beton ihwg 250 mm | Pset_SlabCommon - PitchAngle: 0 deg
7511853 | 02a eerste tussenverdieping | NLRS_f2_beton ihwg 250 mm
7512461 | 01b tweede tussenverdieping | NLRS_f2_beton ihwg 250 mm
7512586 | 02a eerste tussenverdieping | NLRS_f2_beton ihwg 250 mm
7513144 | 01b tweede tussenverdieping | NLRS_f2_beton ihwg 250 mm
7513168 | 02a eerste tussenverdieping | NLRS_f2_beton ihwg 250 mm

# IfcSlab: Floor:NLRS_23.21_FL_breedplaat d=70/250_schil apart - gevlinderd_gen (15)
PredefinedType: FLOOR; Classification: 23.21 vloeren - constructief, vrijdragende vloeren (Uniformat)
Pset_SlabCommon - LoadBearing: yes; IsExternal: no; Reference: NLRS_23.21_FL_breedplaat d=70/250_schil apart - gevlinderd_gen; ThermalTransmittance: 4.184 kg/K/s3
Name (Floor:NLRS_23.21_FL_breedplaat d=70/250_schil apart - gevlinderd_gen:...) | In | Group
5438903 | 01c derde tussenverdieping | Model Group:NLRS_23.21_FL_breedplaat d=50/250 01--02:5438789 | Material: NLRS_f2_beton ihwg
5438916 | 01c derde tussenverdieping | Model Group:NLRS_23.21_FL_breedplaat d=50/250 01--02:5438789 | Material: NLRS_f2_beton ihwg
5438941 | 01c derde tussenverdieping | Model Group:NLRS_23.21_FL_breedplaat d=50/250 01--02:5438789 | Material: NLRS_f2_beton ihwg 250 mm
5438960 | 01c derde tussenverdieping | Model Group:NLRS_23.21_FL_breedplaat d=50/250 01--02:5438789
5439004 | 01c derde tussenverdieping | Model Group:NLRS_23.21_FL_breedplaat d=50/250 01--02:5438789
5439279 | 02b tweede tussenverdieping | Model Group:NLRS_23.21_FL_breedplaat d=50/250 01--02:5439165
5439292 | 02b tweede tussenverdieping | Model Group:NLRS_23.21_FL_breedplaat d=50/250 01--02:5439165
5439317 | 02b tweede tussenverdieping | Model Group:NLRS_23.21_FL_breedplaat d=50/250 01--02:5439165 | Material: NLRS_f2_beton ihwg 250 mm
5439336 | 02b tweede tussenverdieping | Model Group:NLRS_23.21_FL_breedplaat d=50/250 01--02:5439165
5439380 | 02b tweede tussenverdieping | Model Group:NLRS_23.21_FL_breedplaat d=50/250 01--02:5439165
5439659 | 01a eerste tussenverdieping | Model Group:NLRS_23.21_FL_breedplaat d=50/250 01--02:5439545
5439672 | 01a eerste tussenverdieping | Model Group:NLRS_23.21_FL_breedplaat d=50/250 01--02:5439545
5439697 | 01a eerste tussenverdieping | Model Group:NLRS_23.21_FL_breedplaat d=50/250 01--02:5439545 | Material: NLRS_f2_beton ihwg 250 mm
5439716 | 01a eerste tussenverdieping | Model Group:NLRS_23.21_FL_breedplaat d=50/250 01--02:5439545
5439760 | 01a eerste tussenverdieping | Model Group:NLRS_23.21_FL_breedplaat d=50/250 01--02:5439545

# IfcSlab: Floor:NLRS_23.21_FL_breedplaat d=70/250_schil apart_gen (54)
PredefinedType: FLOOR; Classification: 23.21 vloeren - constructief, vrijdragende vloeren (Uniformat)
Pset_SlabCommon - IsExternal: no; Reference: NLRS_23.21_FL_breedplaat d=70/250_schil apart_gen; ThermalTransmittance: 4.184 kg/K/s3
Name (Floor:NLRS_23.21_FL_breedplaat d=70/250_schil apart_gen:...) | In | Material | LoadBearing
4418822 | 01 eerste verdieping | NLRS_f2_beton ihwg 250 mm | yes
4419543 | 01 eerste verdieping |  | yes
4420422 | 02 tweede verdieping | NLRS_f2_beton ihwg 250 mm | yes
4420447 | 02 tweede verdieping |  | yes
4420710 | 03 derde verdieping | NLRS_f2_beton ihwg 250 mm | yes
4420735 | 03 derde verdieping |  | yes
4420996 | 04 vierde verdieping |  | yes
4421059 | 04 vierde verdieping |  | yes
4423589 | 01 eerste verdieping | NLRS_f2_beton ihwg 250 mm | yes
4424393 | 02 tweede verdieping | NLRS_f2_beton ihwg 250 mm | yes
4424580 | 03 derde verdieping | NLRS_f2_beton ihwg 250 mm | yes
4424766 | 04 vierde verdieping |  | yes
4425209 | 04 vierde verdieping |  | yes
4425371 | 04 vierde verdieping |  | yes
4425422 | 04 vierde verdieping |  | yes
4524177 | 04 vierde verdieping |  | yes
4656825 | 23 dakverdieping |  | no | Group: Model Group:NLRS_01.00_verdieping 21--23_gen (members excluded):4647240
4846929 | 23 dakverdieping |  | no | Group: Model Group:NLRS_01.00_verdieping 21--23_gen (members excluded):4846692
4967426 | 01 eerste verdieping | NLRS_f2_beton ihwg 250 mm | yes
4969095 | 02 tweede verdieping | NLRS_f2_beton ihwg 250 mm | yes | Pset_SlabCommon - PitchAngle: 0 deg
4969177 | 04 vierde verdieping | NLRS_f2_beton ihwg 250 mm | yes
5015186 | 01 eerste verdieping |  | yes
5015205 | 02 tweede verdieping |  | yes
5015219 | 03 derde verdieping |  | yes
5015517 | 01 eerste verdieping | NLRS_f2_beton ihwg 250 mm | yes
5015559 | 02 tweede verdieping | NLRS_f2_beton ihwg 250 mm | yes
5015629 | 04 vierde verdieping | NLRS_f2_beton ihwg 250 mm | yes
5438969 | 01c derde tussenverdieping |  | yes | Group: Model Group:NLRS_23.21_FL_breedplaat d=50/250 01--02:5438789
5438987 | 01c derde tussenverdieping |  | yes | Group: Model Group:NLRS_23.21_FL_breedplaat d=50/250 01--02:5438789
5439345 | 02b tweede tussenverdieping |  | yes | Group: Model Group:NLRS_23.21_FL_breedplaat d=50/250 01--02:5439165
5439363 | 02b tweede tussenverdieping |  | yes | Group: Model Group:NLRS_23.21_FL_breedplaat d=50/250 01--02:5439165
5439725 | 01a eerste tussenverdieping |  | yes | Group: Model Group:NLRS_23.21_FL_breedplaat d=50/250 01--02:5439545
5439743 | 01a eerste tussenverdieping |  | yes | Group: Model Group:NLRS_23.21_FL_breedplaat d=50/250 01--02:5439545
5707772 | 00 begane grond |  | yes
5771356 | 01a eerste tussenverdieping | NLRS_f2_beton ihwg 250 mm | yes | Group: Model Group:NLRS_23.21_FL_breedplaat d=50/250 01--02:5439545
5771699 | 01c derde tussenverdieping | NLRS_f2_beton ihwg 250 mm | yes | Group: Model Group:NLRS_23.21_FL_breedplaat d=50/250 01--02:5438789
5771709 | 02b tweede tussenverdieping | NLRS_f2_beton ihwg 250 mm | yes | Group: Model Group:NLRS_23.21_FL_breedplaat d=50/250 01--02:5439165
6446554 | 03 derde verdieping | NLRS_f2_beton ihwg 250 mm | yes
6446554:2 | 03 derde verdieping | NLRS_f2_beton ihwg 250 mm | yes
6446554:3 | 03 derde verdieping | NLRS_f2_beton ihwg 250 mm | yes
6446626 | 03 derde verdieping | NLRS_f2_beton ihwg 250 mm | yes
6446626:2 | 03 derde verdieping | NLRS_f2_beton ihwg 250 mm | yes
6446626:3 | 03 derde verdieping | NLRS_f2_beton ihwg 250 mm | yes
7397005 | 00 begane grond |  | yes
8396137 | 01c derde tussenverdieping | NLRS_f2_beton ihwg 250 mm | yes
8396204 | 02b tweede tussenverdieping | NLRS_f2_beton ihwg 250 mm | yes
8396248 | 01c derde tussenverdieping | NLRS_f2_beton ihwg 250 mm | yes
8396258 | 02b tweede tussenverdieping | NLRS_f2_beton ihwg 250 mm | yes
8400656 | 02b tweede tussenverdieping | NLRS_f2_beton ihwg 250 mm | yes
8403225 | 01c derde tussenverdieping | NLRS_f2_beton ihwg 250 mm | yes
8555357 | 04 vierde verdieping | NLRS_f2_beton ihwg 250 mm | yes
8585283 | 04 vierde verdieping | NLRS_f2_beton ihwg 250 mm | yes
9278362 | 01c derde tussenverdieping | NLRS_f2_beton ihwg 250 mm | yes
10122022 | 02b tweede tussenverdieping | NLRS_f2_beton ihwg 250 mm | yes | Pset_SlabCommon - PitchAngle: 0 deg

# IfcSlab: Floor:NLRS_23.21_FL_breedplaat d=70/270_schil apart_gen (2)
PredefinedType: FLOOR; Classification: 23.21 vloeren - constructief, vrijdragende vloeren (Uniformat); Material: NLRS_f2_beton ihwg 270 mm
Pset_SlabCommon - LoadBearing: yes; IsExternal: no; Reference: NLRS_23.21_FL_breedplaat d=70/270_schil apart_gen; ThermalTransmittance: 3.87407 kg/K/s3
Name (Floor:NLRS_23.21_FL_breedplaat d=70/270_schil apart_gen:...) | In
5709759 | 00a eerste tussenverdieping
5711375 | 01b tweede tussenverdieping

# IfcSlab: Floor:NLRS_23.21_FL_breedplaatschil d=70_gen (223)
PredefinedType: FLOOR; Classification: 23.21 vloeren - constructief, vrijdragende vloeren (Uniformat); Material: NLRS_f2_beton prefab 70 mm
Pset_SlabCommon - IsExternal: no; Reference: NLRS_23.21_FL_breedplaatschil d=70_gen; ThermalTransmittance: 14.9429 kg/K/s3
Name (Floor:NLRS_23.21_FL_breedplaatschil d=70_gen:...) | In | LoadBearing | PitchAngle (deg)
6999338 | 01 eerste verdieping | yes | 0
6999362 | 01 eerste verdieping | yes | 0 | Group: Model Group:Breedplaten woningen zuid:7328421
6999394 | 01 eerste verdieping | yes | 0 | Group: Model Group:Breedplaten woningen zuid:7328421
6999413 | 01 eerste verdieping | yes | 0 | Group: Model Group:Breedplaten woningen zuid:7328421
6999434 | 01 eerste verdieping | yes | 0 | Group: Model Group:Breedplaten woningen zuid:7328421
6999544 | 01 eerste verdieping | yes | 0 | Group: Model Group:Breedplaten woningen zuid:7328421
7327616 | 01 eerste verdieping | yes | 0 | Group: Model Group:Breedplaten woningen zuid:7328421
7327627 | 01 eerste verdieping | yes | 0 | Group: Model Group:Breedplaten woningen zuid:7328421
7327694 | 01 eerste verdieping | yes | 0 | Group: Model Group:Breedplaten woningen zuid:7328421
7327705 | 01 eerste verdieping | yes | 0 | Group: Model Group:Breedplaten woningen zuid:7328421
7327782 | 01 eerste verdieping | yes | 0 | Group: Model Group:Breedplaten woningen zuid:7328421
7327836 | 01 eerste verdieping | yes | 0 | Group: Model Group:Breedplaten woningen zuid:7328421
7327848 | 01 eerste verdieping | yes | 0 | Group: Model Group:Breedplaten woningen zuid:7328421
7327925 | 01 eerste verdieping | yes | 0 | Group: Model Group:Breedplaten woningen zuid:7328421
7327937 | 01 eerste verdieping | yes | 0 | Group: Model Group:Breedplaten woningen zuid:7328421
7328056 | 01 eerste verdieping | yes | 0
7328662 | 02 tweede verdieping | yes | 0 | Group: Model Group:Breedplaten woningen zuid:7328825
7328673 | 02 tweede verdieping | yes | 0 | Group: Model Group:Breedplaten woningen zuid:7328825
7328685 | 02 tweede verdieping | yes | 0 | Group: Model Group:Breedplaten woningen zuid:7328825
7328697 | 02 tweede verdieping | yes | 0 | Group: Model Group:Breedplaten woningen zuid:7328825
7328709 | 02 tweede verdieping | yes | 0 | Group: Model Group:Breedplaten woningen zuid:7328825
7328721 | 02 tweede verdieping | yes | 0 | Group: Model Group:Breedplaten woningen zuid:7328825
7328732 | 02 tweede verdieping | yes | 0 | Group: Model Group:Breedplaten woningen zuid:7328825
7328744 | 02 tweede verdieping | yes | 0 | Group: Model Group:Breedplaten woningen zuid:7328825
7328755 | 02 tweede verdieping | yes | 0 | Group: Model Group:Breedplaten woningen zuid:7328825
7328767 | 02 tweede verdieping | yes | 0 | Group: Model Group:Breedplaten woningen zuid:7328825
7328778 | 02 tweede verdieping | yes | 0 | Group: Model Group:Breedplaten woningen zuid:7328825
7328790 | 02 tweede verdieping | yes | 0 | Group: Model Group:Breedplaten woningen zuid:7328825
7328802 | 02 tweede verdieping | yes | 0 | Group: Model Group:Breedplaten woningen zuid:7328825
7328814 | 02 tweede verdieping | yes | 0 | Group: Model Group:Breedplaten woningen zuid:7328825
7329241 | 02 tweede verdieping | yes
7329241:2 | 02 tweede verdieping | yes
7329677 | 03 derde verdieping | yes | 0 | Group: Model Group:Breedplaten woningen zuid:7329840
7329688 | 03 derde verdieping | yes | 0 | Group: Model Group:Breedplaten woningen zuid:7329840
7329700 | 03 derde verdieping | yes | 0 | Group: Model Group:Breedplaten woningen zuid:7329840
7329712 | 03 derde verdieping | yes | 0 | Group: Model Group:Breedplaten woningen zuid:7329840
7329724 | 03 derde verdieping | yes | 0 | Group: Model Group:Breedplaten woningen zuid:7329840
7329736 | 03 derde verdieping | yes | 0 | Group: Model Group:Breedplaten woningen zuid:7329840
7329747 | 03 derde verdieping | yes | 0 | Group: Model Group:Breedplaten woningen zuid:7329840
7329759 | 03 derde verdieping | yes | 0 | Group: Model Group:Breedplaten woningen zuid:7329840
7329770 | 03 derde verdieping | yes | 0 | Group: Model Group:Breedplaten woningen zuid:7329840
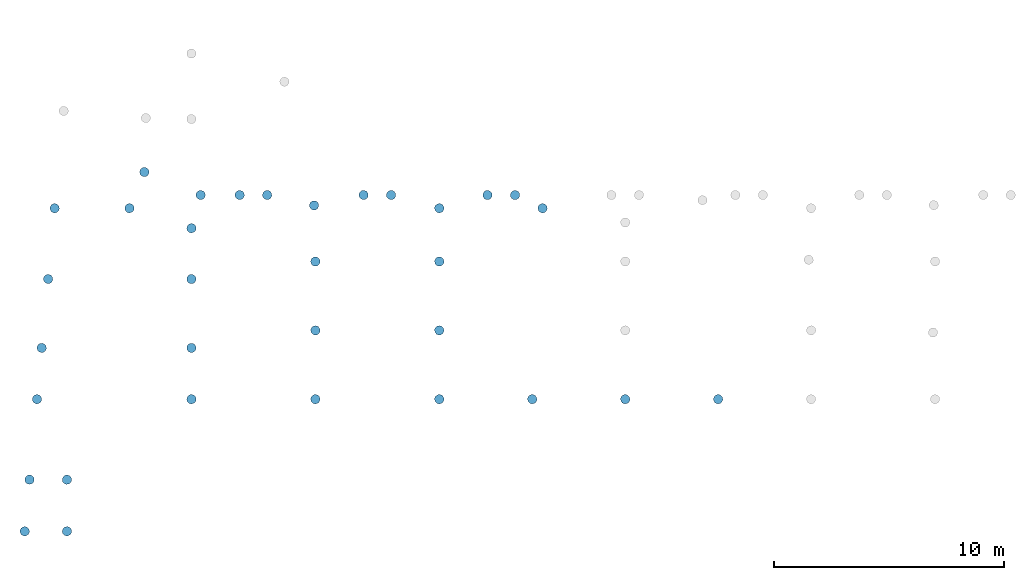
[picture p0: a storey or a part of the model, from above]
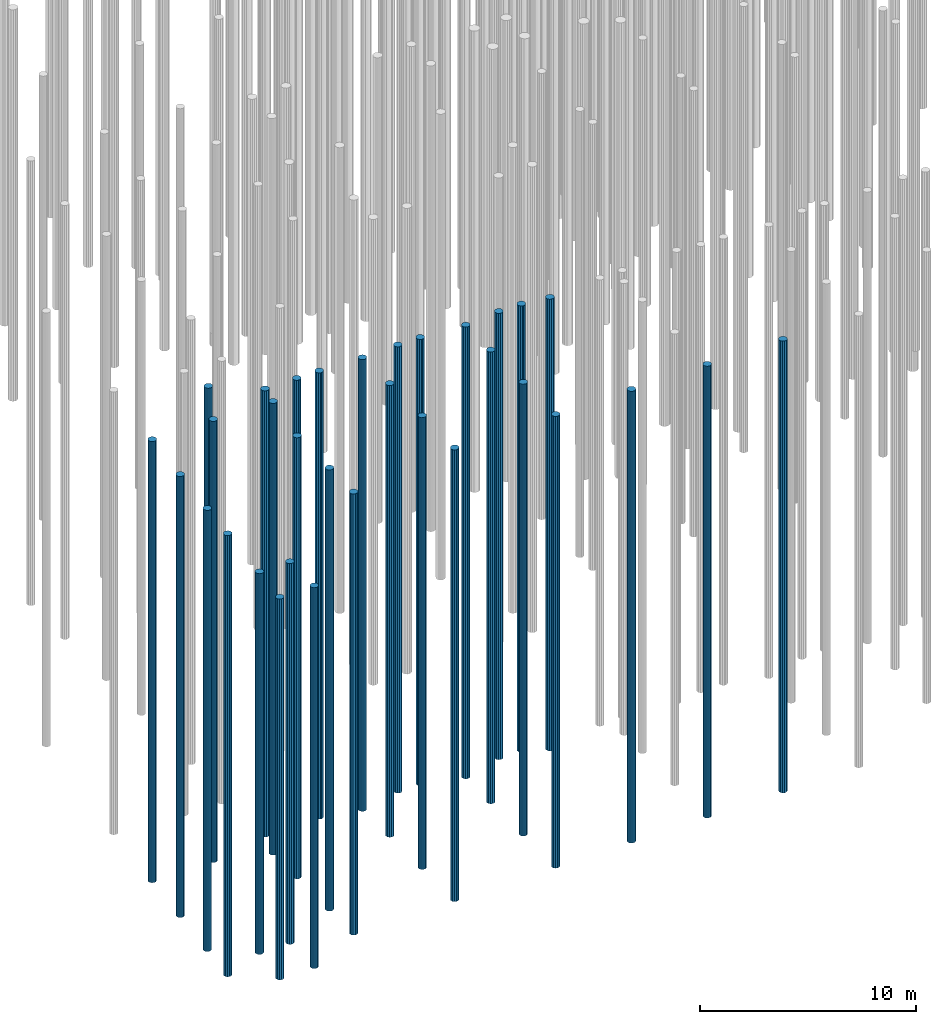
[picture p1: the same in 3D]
Properties of the parts of a building model (IFC2X3), part 9 of 11

# IfcSlab: Floor:NLRS_23.21_FL_breedplaatschil d=70_gen (223)
Name (Floor:NLRS_23.21_FL_breedplaatschil d=70_gen:...) | In | LoadBearing | PitchAngle (deg)
7329782 | 03 derde verdieping | yes | 0 | Group: Model Group:Breedplaten woningen zuid:7329840
7329793 | 03 derde verdieping | yes | 0 | Group: Model Group:Breedplaten woningen zuid:7329840
7329805 | 03 derde verdieping | yes | 0 | Group: Model Group:Breedplaten woningen zuid:7329840
7329817 | 03 derde verdieping | yes | 0 | Group: Model Group:Breedplaten woningen zuid:7329840
7329829 | 03 derde verdieping | yes | 0 | Group: Model Group:Breedplaten woningen zuid:7329840
7329842 | 03 derde verdieping | yes | 0
7330475 | 04 vierde verdieping | yes | 0
7330486 | 04 vierde verdieping | yes | 0
7330774 | 04 vierde verdieping | yes | 0
7330805 | 04 vierde verdieping | yes | 0
7330966 | 04 vierde verdieping | yes | 0
7330978 | 04 vierde verdieping | yes | 0
7331031 | 04 vierde verdieping | yes | 0
7331043 | 04 vierde verdieping | yes | 0
7331126 | 04 vierde verdieping | yes | 0
7331138 | 04 vierde verdieping | yes | 0
7331146 | 04 vierde verdieping | yes | 0
7331158 | 04 vierde verdieping | yes | 0
7331266 | 04 vierde verdieping | yes | 0
7331278 | 04 vierde verdieping | yes | 0
7331347 | 04 vierde verdieping | yes | 0
7344416 | 01 eerste verdieping | yes | 0
7344645 | 01 eerste verdieping | yes | 0
7344727 | 01 eerste verdieping | yes | 0 | Group: Model Group:Breedplaten woningen noord:7361993
7344808 | 01 eerste verdieping | yes | 0 | Group: Model Group:Breedplaten woningen noord:7361993
7346866 | 01a eerste tussenverdieping | yes | Group: Model Group:NLRS_23.21_FL_breedplaat d=50/250 01--02:5439545
7347455 | 01c derde tussenverdieping | yes | Group: Model Group:NLRS_23.21_FL_breedplaat d=50/250 01--02:5438789
7347488 | 02b tweede tussenverdieping | yes | Group: Model Group:NLRS_23.21_FL_breedplaat d=50/250 01--02:5439165
7348165 | 01a eerste tussenverdieping | yes
7348165:2 | 01a eerste tussenverdieping | yes
7349808 | 01c derde tussenverdieping | yes
7349808:2 | 01c derde tussenverdieping | yes
7349842 | 02b tweede tussenverdieping | yes
7349842:2 | 02b tweede tussenverdieping | yes
7351369 | 01a eerste tussenverdieping | yes | 0 | Group: Model Group:NLRS_23.21_FL_breedplaat d=50/250 01--02:5439545
7351742 | 01c derde tussenverdieping | yes | 0 | Group: Model Group:NLRS_23.21_FL_breedplaat d=50/250 01--02:5438789
7351752 | 02b tweede tussenverdieping | yes | 0 | Group: Model Group:NLRS_23.21_FL_breedplaat d=50/250 01--02:5439165
7353312 | 01a eerste tussenverdieping | yes
7353312:2 | 01a eerste tussenverdieping | yes
7353350 | 01a eerste tussenverdieping | yes | 0 | Group: Model Group:NLRS_23.21_FL_breedplaat d=50/250 01--02:5439545
7354867 | 01c derde tussenverdieping | yes
7354867:2 | 01c derde tussenverdieping | yes
7354905 | 01c derde tussenverdieping | yes | 0 | Group: Model Group:NLRS_23.21_FL_breedplaat d=50/250 01--02:5438789
7354914 | 02b tweede tussenverdieping | yes
7354914:2 | 02b tweede tussenverdieping | yes
7354952 | 02b tweede tussenverdieping | yes | 0 | Group: Model Group:NLRS_23.21_FL_breedplaat d=50/250 01--02:5439165
7355239 | 01a eerste tussenverdieping | yes | Group: Model Group:NLRS_23.21_FL_breedplaat d=50/250 01--02:5439545
7355256 | 01a eerste tussenverdieping | yes | Group: Model Group:NLRS_23.21_FL_breedplaat d=50/250 01--02:5439545
7356579 | 01c derde tussenverdieping | yes | Group: Model Group:NLRS_23.21_FL_breedplaat d=50/250 01--02:5438789
7356590 | 01c derde tussenverdieping | yes | Group: Model Group:NLRS_23.21_FL_breedplaat d=50/250 01--02:5438789
7356630 | 02b tweede tussenverdieping | yes | Group: Model Group:NLRS_23.21_FL_breedplaat d=50/250 01--02:5439165
7356641 | 02b tweede tussenverdieping | yes | Group: Model Group:NLRS_23.21_FL_breedplaat d=50/250 01--02:5439165
7357067 | 01a eerste tussenverdieping | yes | Group: Model Group:NLRS_23.21_FL_breedplaat d=50/250 01--02:5439545
7358726 | 01c derde tussenverdieping | yes | Group: Model Group:NLRS_23.21_FL_breedplaat d=50/250 01--02:5438789
7358768 | 02b tweede tussenverdieping | yes | Group: Model Group:NLRS_23.21_FL_breedplaat d=50/250 01--02:5439165
7359175 | 01 eerste verdieping | yes | 0
7359687 | 01 eerste verdieping | yes
7359687:2 | 01 eerste verdieping | yes
7360278 | 01 eerste verdieping | yes | 0 | Group: Model Group:Breedplaten woningen noord:7361993
7360291 | 01 eerste verdieping | yes | 0 | Group: Model Group:Breedplaten woningen noord:7361993
7360368 | 01 eerste verdieping | yes | Group: Model Group:Breedplaten woningen noord:7361993
7360656 | 01 eerste verdieping | yes | 0
7360681 | 01 eerste verdieping | yes
7360681:2 | 01 eerste verdieping | yes
7360710 | 01 eerste verdieping | yes | 0 | Group: Model Group:Breedplaten woningen noord:7361993
7360723 | 01 eerste verdieping | yes | 0 | Group: Model Group:Breedplaten woningen noord:7361993
7360734 | 01 eerste verdieping | yes | Group: Model Group:Breedplaten woningen noord:7361993
7361112 | 00a eerste tussenverdieping | yes | 0
7361392 | 00a eerste tussenverdieping | yes | 0
7361581 | 01b tweede tussenverdieping | yes | 0
7362284 | 02 tweede verdieping | yes | 0
7362294 | 02 tweede verdieping | yes | 0
7362303 | 02 tweede verdieping | yes | 0 | Group: Model Group:Breedplaten woningen noord:7362532
7362316 | 02 tweede verdieping | yes | 0 | Group: Model Group:Breedplaten woningen noord:7362532
7362381 | 02 tweede verdieping | yes | 0 | Group: Model Group:Breedplaten woningen noord:7362532
7362394 | 02 tweede verdieping | yes | 0 | Group: Model Group:Breedplaten woningen noord:7362532
7362405 | 02 tweede verdieping | yes | Group: Model Group:Breedplaten woningen noord:7362532
7362430 | 02 tweede verdieping | yes | 0
7362455 | 02 tweede verdieping | yes
7362484 | 02 tweede verdieping | yes | 0 | Group: Model Group:Breedplaten woningen noord:7362532
7362497 | 02 tweede verdieping | yes | 0 | Group: Model Group:Breedplaten woningen noord:7362532
7362508 | 02 tweede verdieping | yes | Group: Model Group:Breedplaten woningen noord:7362532
7364416 | 02 tweede verdieping | yes | 0
7365016 | 02 tweede verdieping | yes | 0
7365041 | 02 tweede verdieping | yes
7365068 | 02 tweede verdieping | yes | 0
7367631 | 03 derde verdieping | yes | 0 | Group: Model Group:Breedplaten woningen noord:7367752
7367644 | 03 derde verdieping | yes | 0 | Group: Model Group:Breedplaten woningen noord:7367752
7367655 | 03 derde verdieping | yes | 0 | Group: Model Group:Breedplaten woningen noord:7367752
7367668 | 03 derde verdieping | yes | 0 | Group: Model Group:Breedplaten woningen noord:7367752
7367679 | 03 derde verdieping | yes | Group: Model Group:Breedplaten woningen noord:7367752
7367704 | 03 derde verdieping | yes | 0 | Group: Model Group:Breedplaten woningen noord:7367752
7367717 | 03 derde verdieping | yes | 0 | Group: Model Group:Breedplaten woningen noord:7367752
7367728 | 03 derde verdieping | yes | Group: Model Group:Breedplaten woningen noord:7367752
7368093 | 03 derde verdieping | yes | 0
7368118 | 03 derde verdieping | yes
7368653 | 03 derde verdieping | yes | 0
7368671 | 03 derde verdieping | yes
7369389 | 03 derde verdieping | yes | 0
7369939 | 04 vierde verdieping | yes
7370313 | 04 vierde verdieping | yes | 0
7370462 | 04 vierde verdieping | yes | 0
7370523 | 04 vierde verdieping | yes | 0
7371066 | 04 vierde verdieping | yes
7371066:2 | 04 vierde verdieping | yes
7371104 | 04 vierde verdieping | yes | 0
7371218 | 04 vierde verdieping | yes
7371373 | 04 vierde verdieping | yes | 0
7371505 | 04 vierde verdieping | yes
7371712 | 04 vierde verdieping | yes
7371747 | 04 vierde verdieping | yes | 0
7371862 | 04 vierde verdieping | yes
7371887 | 04 vierde verdieping | yes | 0
7371905 | 04 vierde verdieping | yes
7372352 | 04 vierde verdieping | yes | 0
7372365 | 04 vierde verdieping | yes | 0
7372445 | 04 vierde verdieping | yes
7374545 | 04 vierde verdieping | yes
7374545:2 | 04 vierde verdieping | yes
7374583 | 04 vierde verdieping | yes | 0
7374592 | 04 vierde verdieping | yes
7374605 | 04 vierde verdieping | yes | 0
7374614 | 04 vierde verdieping | yes
7374635 | 04 vierde verdieping | yes
7374648 | 04 vierde verdieping | yes | 0
7374656 | 04 vierde verdieping | yes
7374676 | 04 vierde verdieping | yes | 0
7374693 | 04 vierde verdieping | yes
7374717 | 04 vierde verdieping | yes | 0
7374730 | 04 vierde verdieping | yes | 0
7374741 | 04 vierde verdieping | yes
7395939 | 00 begane grond | yes
7397036 | 00 begane grond | yes
7510317 | 01b tweede tussenverdieping | yes | 0
7510327 | 01b tweede tussenverdieping | yes | 0
7510336 | 01b tweede tussenverdieping | yes | 0
7510835 | 02a eerste tussenverdieping | yes | 0
7510845 | 02a eerste tussenverdieping | yes | 0
7510853 | 02a eerste tussenverdieping | yes | 0
7511800 | 01b tweede tussenverdieping | yes | 0
7511810 | 01b tweede tussenverdieping | yes | 0
7511819 | 01b tweede tussenverdieping | yes | 0
7511863 | 02a eerste tussenverdieping | yes | 0
7511873 | 02a eerste tussenverdieping | yes | 0
7511881 | 02a eerste tussenverdieping | yes | 0
7512189 | 01 eerste verdieping | yes | 0
7512474 | 01c derde tussenverdieping | yes | 0
7512599 | 02b tweede tussenverdieping | yes | 0
7513133 | 01 eerste verdieping | yes | 0
7513157 | 01c derde tussenverdieping | yes | 0
7513181 | 02b tweede tussenverdieping | yes | 0
7513437 | 01 eerste verdieping | yes | 0
7513446 | 00 begane grond | yes | 0
7513454 | 00 begane grond | yes | 0
7513824 | 00 begane grond | yes | 0
7514007 | 00 begane grond | yes | 0
8555375 | 04 vierde verdieping | yes | 0
8575961 | 02b tweede tussenverdieping | yes | 0 | Group: Model Group:NLRS_23.21_FL_breedplaat d=50/250 01--02:5439165
8576238 | 01c derde tussenverdieping | yes | 0 | Group: Model Group:NLRS_23.21_FL_breedplaat d=50/250 01--02:5438789
8576259 | 01a eerste tussenverdieping | yes | 0 | Group: Model Group:NLRS_23.21_FL_breedplaat d=50/250 01--02:5439545
8585291 | 04 vierde verdieping | yes | 0
11470252 | 02 tweede verdieping | yes | 0
11470271 | 02b tweede tussenverdieping | yes | 0
11470299 | 02 tweede verdieping | yes | 0
11470326 | 02b tweede tussenverdieping | yes | 0
11470359 | 02 tweede verdieping | yes
11919572 | 23 dakverdieping | no | Group: Model Group:NLRS_01.00_verdieping 21--23_gen (members excluded):4846692
11919572:2 | 23 dakverdieping | no | Group: Model Group:NLRS_01.00_verdieping 21--23_gen (members excluded):4846692
11919572:3 | 23 dakverdieping | no | Group: Model Group:NLRS_01.00_verdieping 21--23_gen (members excluded):4846692
11919572:4 | 23 dakverdieping | no | Group: Model Group:NLRS_01.00_verdieping 21--23_gen (members excluded):4846692
11919572:5 | 23 dakverdieping | no | Group: Model Group:NLRS_01.00_verdieping 21--23_gen (members excluded):4846692
11919572:6 | 23 dakverdieping | no | Group: Model Group:NLRS_01.00_verdieping 21--23_gen (members excluded):4846692
11919572:7 | 23 dakverdieping | no | Group: Model Group:NLRS_01.00_verdieping 21--23_gen (members excluded):4846692
11919963 | 23 dakverdieping | no | Group: Model Group:NLRS_01.00_verdieping 21--23_gen (members excluded):4647240
11919963:2 | 23 dakverdieping | no | Group: Model Group:NLRS_01.00_verdieping 21--23_gen (members excluded):4647240
11919963:3 | 23 dakverdieping | no | Group: Model Group:NLRS_01.00_verdieping 21--23_gen (members excluded):4647240
11919963:4 | 23 dakverdieping | no | Group: Model Group:NLRS_01.00_verdieping 21--23_gen (members excluded):4647240
11919963:5 | 23 dakverdieping | no | Group: Model Group:NLRS_01.00_verdieping 21--23_gen (members excluded):4647240
11919963:6 | 23 dakverdieping | no | Group: Model Group:NLRS_01.00_verdieping 21--23_gen (members excluded):4647240
11919963:7 | 23 dakverdieping | no | Group: Model Group:NLRS_01.00_verdieping 21--23_gen (members excluded):4647240
12376340 | 00a eerste tussenverdieping | yes | 0
12376402 | 01b tweede tussenverdieping | yes | 0

# IfcSlab: Floor:NLRS_23.21_FL_druklaag - opgeruwd d=70_gen, Floor:NLRS_23.21_FL_druklaag - opgeruwd d=70_gen:4444314
In: 00 begane grond
PredefinedType: FLOOR; Classification: 23.21 vloeren - constructief, vrijdragende vloeren (Uniformat); Material: NLRS_f2_beton ihwg 70 mm
Pset_SlabCommon - LoadBearing: yes; IsExternal: no; PitchAngle: 0 deg; Reference: NLRS_23.21_FL_druklaag - opgeruwd d=70_gen; ThermalTransmittance: 14.9429 kg/K/s3

# IfcSlab: Floor:NLRS_23.21_FL_druklaag d=100_gen (7)
In: 04 vierde verdieping
PredefinedType: FLOOR; Classification: 23.21 vloeren - constructief, vrijdragende vloeren (Uniformat); Material: NLRS_f2_beton ihwg 100 mm
Pset_SlabCommon - LoadBearing: yes; IsExternal: no; PitchAngle: 0 deg; Reference: NLRS_23.21_FL_druklaag d=100_gen; ThermalTransmittance: 10.46 kg/K/s3
Name (Floor:NLRS_23.21_FL_druklaag d=100_gen:...)
4446145
5257721
5257784
5258173
5259171
5388394
7688747

# IfcSlab: Floor:NLRS_23.21_FL_druklaag d=100_gen normaal (3)
In: 01b tweede tussenverdieping
PredefinedType: FLOOR; Classification: 23.21 vloeren - constructief, vrijdragende vloeren (Uniformat); Material: NLRS_f2_beton ihwg 100 mm
Pset_SlabCommon - LoadBearing: yes; IsExternal: no; Reference: NLRS_23.21_FL_druklaag d=100_gen normaal; ThermalTransmittance: 10.46 kg/K/s3
Name (Floor:NLRS_23.21_FL_druklaag d=100_gen normaal:...) | PitchAngle (deg)
5710144
9999921 | 0
13445479 | 0

# IfcSlab: Floor:NLRS_23.21_FL_druklaag d=110_gen, Floor:NLRS_23.21_FL_druklaag d=110_gen:8505476
In: 00 begane grond
PredefinedType: FLOOR; Classification: 23.21 vloeren - constructief, vrijdragende vloeren (Uniformat); Material: NLRS_f2_beton ihwg 110 mm
Pset_SlabCommon - LoadBearing: yes; IsExternal: no; Reference: NLRS_23.21_FL_druklaag d=110_gen; ThermalTransmittance: 9.50909 kg/K/s3

# IfcSlab: Floor:NLRS_23.21_FL_druklaag d=50_gen, Floor:NLRS_23.21_FL_druklaag d=50_gen:5515846
In: 02 tweede verdieping
PredefinedType: FLOOR; Classification: 23.21 vloeren - constructief, vrijdragende vloeren (Uniformat); Material: NLRS_f2_beton ihwg 50 mm
Pset_SlabCommon - LoadBearing: yes; IsExternal: no; PitchAngle: 0 deg; Reference: NLRS_23.21_FL_druklaag d=50_gen; ThermalTransmittance: 20.92 kg/K/s3

# IfcSlab: Floor:NLRS_23.21_FL_druklaag d=70 - gevlinderd en ingestrooid_gen (28)
PredefinedType: FLOOR; Classification: 23.21 vloeren - constructief, vrijdragende vloeren (Uniformat); Material: NLRS_f2_beton ihwg 70 mm
Pset_SlabCommon - LoadBearing: yes; IsExternal: no; Reference: NLRS_23.21_FL_druklaag d=70 - gevlinderd en ingestrooid_gen; ThermalTransmittance: 14.9429 kg/K/s3
Name (Floor:NLRS_23.21_FL_druklaag d=70 - gevlinderd en ingestrooid_gen:...) | In | PitchAngle (deg)
4440982 | 00a eerste tussenverdieping | 0
4443160 | 01b tweede tussenverdieping | 0
4443375 | 02a eerste tussenverdieping | 0
4459988 | 00a eerste tussenverdieping | 0
4460084 | 00a eerste tussenverdieping
4460484 | 01b tweede tussenverdieping | 0
4460573 | 01b tweede tussenverdieping | 0
4460913 | 02a eerste tussenverdieping | 0
4460984 | 02a eerste tussenverdieping | 0
4462169 | 01a eerste tussenverdieping | 0
4463176 | 01a eerste tussenverdieping
4464669 | 01a eerste tussenverdieping
4472069 | 02b tweede tussenverdieping
4472123 | 01c derde tussenverdieping
4472187 | 01c derde tussenverdieping | 0
4472277 | 02b tweede tussenverdieping | 0
4472351 | 01c derde tussenverdieping
4472631 | 02b tweede tussenverdieping
5256911 | 00a eerste tussenverdieping | 0
5257411 | 01b tweede tussenverdieping | 0
5257593 | 02a eerste tussenverdieping | 0
5258680 | 00a eerste tussenverdieping | 0
5258946 | 01b tweede tussenverdieping | 0
5259453 | 02a eerste tussenverdieping | 0
5711536 | 01b tweede tussenverdieping | 0
9994388 | 01a eerste tussenverdieping | 0
9994758 | 01c derde tussenverdieping | 0
9994883 | 02b tweede tussenverdieping | 0

# IfcSlab: Floor:NLRS_23.21_FL_druklaag d=70 - gevlinderd_gen (9)
PredefinedType: FLOOR; Classification: 23.21 vloeren - constructief, vrijdragende vloeren (Uniformat); Material: NLRS_f2_beton ihwg 70 mm
Pset_SlabCommon - LoadBearing: yes; IsExternal: no; Reference: NLRS_23.21_FL_druklaag d=70 - gevlinderd_gen; ThermalTransmittance: 14.9429 kg/K/s3
Name (Floor:NLRS_23.21_FL_druklaag d=70 - gevlinderd_gen:...) | In
4409162 | 00 begane grond
5154816 | 00 begane grond
5296175 | 00 begane grond | Pset_SlabCommon - PitchAngle: 0 deg
5296847 | 00 begane grond
5297085 | 00 begane grond
5297204 | 00 begane grond
5498566 | 01a eerste tussenverdieping
5498566:2 | 01a eerste tussenverdieping
6593532 | 00 begane grond | Pset_SlabCommon - PitchAngle: 0 deg

# IfcSlab: Floor:NLRS_23.21_FL_druklaag d=70_gen (49)
PredefinedType: FLOOR; Classification: 23.21 vloeren - constructief, vrijdragende vloeren (Uniformat); Material: NLRS_f2_beton ihwg 70 mm
Pset_SlabCommon - IsExternal: no; Reference: NLRS_23.21_FL_druklaag d=70_gen; ThermalTransmittance: 14.9429 kg/K/s3
Name (Floor:NLRS_23.21_FL_druklaag d=70_gen:...) | In | LoadBearing
4408707 | 00 begane grond | yes
4408707:2 | 00 begane grond | yes
4408707:3 | 00 begane grond | yes
4408707:4 | 00 begane grond | yes
4408707:5 | 00 begane grond | yes
4408707:6 | 00 begane grond | yes
4408707:7 | 00 begane grond | yes
4408707:8 | 00 begane grond | yes
4408707:9 | 00 begane grond | yes
4408707:10 | 00 begane grond | yes
4408707:11 | 00 begane grond | yes
4408707:12 | 00 begane grond | yes
4408707:13 | 00 begane grond | yes
4409261 | 00 begane grond | yes
4409261:2 | 00 begane grond | yes
4409261:3 | 00 begane grond | yes
4409261:4 | 00 begane grond | yes
4409261:5 | 00 begane grond | yes
4409261:6 | 00 begane grond | yes
4409261:7 | 00 begane grond | yes
4409261:8 | 00 begane grond | yes
4409261:9 | 00 begane grond | yes
4409261:10 | 00 begane grond | yes
4409261:11 | 00 begane grond | yes
4409261:12 | 00 begane grond | yes
4409261:13 | 00 begane grond | yes
4409261:14 | 00 begane grond | yes
4409261:15 | 00 begane grond | yes
4409261:16 | 00 begane grond | yes
4509711 | 00 begane grond | yes
5709988 | 00a eerste tussenverdieping | yes | Pset_SlabCommon - PitchAngle: 0 deg
5713917 | 05 vijfde verdieping | yes | Pset_SlabCommon - PitchAngle: 0 deg
5714123 | 04 vierde verdieping | yes | Pset_SlabCommon - PitchAngle: 0 deg
6593641 | 00 begane grond | yes
9339638 | 00a eerste tussenverdieping | no | Pset_SlabCommon - PitchAngle: 0 deg
9383107 | 01b tweede tussenverdieping | no | Pset_SlabCommon - PitchAngle: 0 deg
9383134 | 00a eerste tussenverdieping | no | Pset_SlabCommon - PitchAngle: 0 deg
9383152 | 01b tweede tussenverdieping | no | Pset_SlabCommon - PitchAngle: 0 deg
9383167 | 02a eerste tussenverdieping | no | Pset_SlabCommon - PitchAngle: 0 deg
9388743 | 00a eerste tussenverdieping | no | Pset_SlabCommon - PitchAngle: 0 deg
9388854 | 01b tweede tussenverdieping | no | Pset_SlabCommon - PitchAngle: 0 deg
9388880 | 02a eerste tussenverdieping | no | Pset_SlabCommon - PitchAngle: 0 deg
9389104 | 02a eerste tussenverdieping | no | Pset_SlabCommon - PitchAngle: 0 deg
10002782 | 04 vierde verdieping | yes | Pset_SlabCommon - PitchAngle: 0 deg
12593083 | 05 vijfde verdieping | yes | Pset_SlabCommon - PitchAngle: 0 deg
12928577 | 04 vierde verdieping | yes | Pset_SlabCommon - PitchAngle: 0 deg
12928593 | 04 vierde verdieping | yes | Pset_SlabCommon - PitchAngle: 0 deg
13446962 | 04 vierde verdieping | yes | Pset_SlabCommon - PitchAngle: 0 deg
13451327 | 05 vijfde verdieping | yes | Pset_SlabCommon - PitchAngle: 0 deg

# IfcSlab: Floor:NLRS_23.21_FL_druklaag d=80-var_gen, Floor:NLRS_23.21_FL_druklaag d=80-var_gen:4483913
In: 04 vierde verdieping
PredefinedType: FLOOR; Classification: 23.21 vloeren - constructief, vrijdragende vloeren (Uniformat); Material: NLRS_f2_beton ihwg 80 mm
Pset_SlabCommon - LoadBearing: yes; IsExternal: no; Reference: NLRS_23.21_FL_druklaag d=80-var_gen; ThermalTransmittance: 13.075 kg/K/s3

# IfcSlab: Floor:NLRS_23.21_FL_druklaag d=80_gen (7)
PredefinedType: FLOOR; Classification: 23.21 vloeren - constructief, vrijdragende vloeren (Uniformat); Material: NLRS_f2_beton ihwg 80 mm
Pset_SlabCommon - LoadBearing: yes; IsExternal: no; Reference: NLRS_23.21_FL_druklaag d=80_gen; ThermalTransmittance: 13.075 kg/K/s3
Name (Floor:NLRS_23.21_FL_druklaag d=80_gen:...) | In
4488263 | 04 vierde verdieping
4489549 | 04 vierde verdieping
8551452 | 04 vierde verdieping | Pset_SlabCommon - PitchAngle: 0 deg
8584224 | 04 vierde verdieping | Pset_SlabCommon - PitchAngle: 0 deg
9994948 | 04 vierde verdieping | Pset_SlabCommon - PitchAngle: 0 deg
12928604 | 05 vijfde verdieping
12928604:2 | 05 vijfde verdieping

# IfcSlab: Floor:NLRS_23.21_FL_geisoleerde kanaalplaat d=200 rc 3.5 iso132_gen (52)
In: 00 begane grond
PredefinedType: FLOOR; Classification: 23.21 vloeren - constructief, vrijdragende vloeren (Uniformat); Material: NLRS_f2_beton prefab 200 mm, NLRS_n7_isolatie EPS 132 mm
Pset_SlabCommon - LoadBearing: yes; IsExternal: no; Reference: NLRS_23.21_FL_geisoleerde kanaalplaat d=200 rc 3.5 iso132_gen; ThermalTransmittance: 0.252357 kg/K/s3
Name (Floor:NLRS_23.21_FL_geisoleerde kanaalplaat d=200 rc 3.5 iso132_gen:...)
4409562
4409618
4409642
4409711
4409735
4409759
4409783
4409934
4409956
4410046
4410068
4410092
4410124 | Pset_SlabCommon - PitchAngle: 0 deg
4410209
4410274
4410630
4410670
4410735 | Pset_SlabCommon - PitchAngle: 0 deg
4410813
4410835 | Pset_SlabCommon - PitchAngle: 0 deg
4410892 | Pset_SlabCommon - PitchAngle: 0 deg
4410970
4410970:2
4411166
4411175
4411207
4411216
4411248
4411257
4411311
4411349
4411358
4411390
4411399
4411443 | Pset_SlabCommon - PitchAngle: 0 deg
4411790
4411953
4412008
4412209
4412209:2
4412552
4962705
5015092
5015101
5015110
5015137
5015165
5015423
5155302
5155425 | Pset_SlabCommon - PitchAngle: 0 deg
5622993 | Pset_SlabCommon - PitchAngle: 0 deg
5708983

# IfcSlab: Floor:NLRS_23.21_FL_kanaalplaat d=200_gen (7)
PredefinedType: FLOOR; Classification: 23.21 vloeren - constructief, vrijdragende vloeren (Uniformat); Material: NLRS_f2_beton prefab 200 mm
Pset_SlabCommon - LoadBearing: yes; IsExternal: no; Reference: NLRS_23.21_FL_kanaalplaat d=200_gen; ThermalTransmittance: 5.23 kg/K/s3
Name (Floor:NLRS_23.21_FL_kanaalplaat d=200_gen:...) | In
4412124 | 00 begane grond | Pset_SlabCommon - PitchAngle: 0 deg
4444325 | 00a eerste tussenverdieping | Pset_SlabCommon - PitchAngle: 0 deg
4473771 | 01a eerste tussenverdieping
4473771:2 | 01a eerste tussenverdieping
4474941 | 02 tweede verdieping | Pset_SlabCommon - PitchAngle: 0 deg
8688232 | 02b tweede tussenverdieping
8699548 | 02b tweede tussenverdieping

# IfcSlab: Floor:NLRS_23.21_FL_kanaalplaat d=255_gen (73)
PredefinedType: FLOOR; Classification: 23.21 vloeren - constructief, vrijdragende vloeren (Uniformat); Material: NLRS_f2_beton prefab 255 mm
Pset_SlabCommon - LoadBearing: yes; IsExternal: no; Reference: NLRS_23.21_FL_kanaalplaat d=255_gen; ThermalTransmittance: 4.10196 kg/K/s3
Name (Floor:NLRS_23.21_FL_kanaalplaat d=255_gen:...) | In | PitchAngle (deg)
4434327 | 00a eerste tussenverdieping | 0
4435507 | 00a eerste tussenverdieping | 0
4436055 | 00a eerste tussenverdieping | 0
4437521 | 00a eerste tussenverdieping | 0
4437683 | 01b tweede tussenverdieping | 0
4438000 | 02a eerste tussenverdieping | 0
4438819 | 02a eerste tussenverdieping | 0
4439044 | 01b tweede tussenverdieping | 0
4439256 | 02a eerste tussenverdieping | 0
4439296 | 01b tweede tussenverdieping | 0
4439403 | 02a eerste tussenverdieping | 0
4458944 | 01a eerste tussenverdieping
4458944:2 | 01a eerste tussenverdieping
4459344 | 01a eerste tussenverdieping | 0
4459453 | 01a eerste tussenverdieping | 0
4459668 | 01a eerste tussenverdieping | 0
4459777 | 01a eerste tussenverdieping | 0
4460672 | 01b tweede tussenverdieping | 0
4460727 | 01b tweede tussenverdieping | 0
4460786 | 01b tweede tussenverdieping | 0
4460844 | 01b tweede tussenverdieping | 0
4461074 | 02a eerste tussenverdieping | 0
4461129 | 02a eerste tussenverdieping | 0
4461188 | 02a eerste tussenverdieping | 0
4461246 | 00a eerste tussenverdieping | 0
4461301 | 00a eerste tussenverdieping | 0
4461360 | 00a eerste tussenverdieping | 0
4466915 | 01a eerste tussenverdieping | 0
4467315 | 01a eerste tussenverdieping
4467315:2 | 01a eerste tussenverdieping
4469425 | 01a eerste tussenverdieping
4469425:2 | 01a eerste tussenverdieping
4471776 | 01c derde tussenverdieping | 0
4471812 | 02b tweede tussenverdieping | 0
4471863 | 01c derde tussenverdieping | 0
4471873 | 01c derde tussenverdieping
4471873:2 | 01c derde tussenverdieping
4471962 | 02b tweede tussenverdieping | 0
4471972 | 02b tweede tussenverdieping
4471972:2 | 02b tweede tussenverdieping
4472341 | 01c derde tussenverdieping | 0
4472388 | 01c derde tussenverdieping
4472388:2 | 01c derde tussenverdieping
4472621 | 02b tweede tussenverdieping | 0
4472668 | 02b tweede tussenverdieping
4472668:2 | 02b tweede tussenverdieping
4490574 | 01c derde tussenverdieping
4490574:2 | 01c derde tussenverdieping
4491529 | 02b tweede tussenverdieping
4491529:2 | 02b tweede tussenverdieping
4990295 | 01c derde tussenverdieping | 0
4990344 | 02b tweede tussenverdieping | 0
5091357 | 01c derde tussenverdieping | 0
5091402 | 02b tweede tussenverdieping | 0
5256924 | 00a eerste tussenverdieping | 0
5257280 | 01b tweede tussenverdieping | 0
5257647 | 02a eerste tussenverdieping | 0
5258738 | 00a eerste tussenverdieping | 0
5258994 | 01b tweede tussenverdieping | 0
5259410 | 02a eerste tussenverdieping | 0
5591209 | 01a eerste tussenverdieping | 0
5709979 | 00a eerste tussenverdieping | 0
5711524 | 01b tweede tussenverdieping | 0
5711606 | 01b tweede tussenverdieping | 0
5714115 | 04 vierde verdieping | 0
8551417 | 04 vierde verdieping | 0
8584353 | 04 vierde verdieping | 0
9994748 | 01c derde tussenverdieping | 0
9994873 | 02b tweede tussenverdieping | 0
10002764 | 04 vierde verdieping | 0
10439269 | 01a eerste tussenverdieping | 0
10449945 | 01a eerste tussenverdieping | 0
13446921 | 04 vierde verdieping | 0

# IfcSlab: Floor:NLRS_23.21_FL_kanaalplaat d=320_gen (3)
In: 01b tweede tussenverdieping
PredefinedType: FLOOR; Classification: 23.21 vloeren - constructief, vrijdragende vloeren (Uniformat); Material: NLRS_f2_beton prefab 320 mm
Pset_SlabCommon - LoadBearing: yes; IsExternal: no; Reference: NLRS_23.21_FL_kanaalplaat d=320_gen; ThermalTransmittance: 3.26875 kg/K/s3
Name (Floor:NLRS_23.21_FL_kanaalplaat d=320_gen:...)
5710136
9999821 | Pset_SlabCommon - PitchAngle: 0 deg
13445279

# IfcSlab: Floor:NLRS_23.21_FL_kanaalplaat d=400_gen (19)
In: 04 vierde verdieping
PredefinedType: FLOOR; Classification: 23.21 vloeren - constructief, vrijdragende vloeren (Uniformat); Material: NLRS_f2_beton prefab 400 mm
Pset_SlabCommon - LoadBearing: yes; IsExternal: no; Reference: NLRS_23.21_FL_kanaalplaat d=400_gen; ThermalTransmittance: 2.615 kg/K/s3
Name (Floor:NLRS_23.21_FL_kanaalplaat d=400_gen:...) | PitchAngle (deg)
4445736 | 0
4451244
4481380
4483202 | 0
4485819 | 0
4486448 | 0
4486785
4486785:2
4487132
4525344
5258242 | 0
5258298 | 0
5258354 | 0
5258525 | 0
5259228 | 0
5391716 | 0
5499462 | 0
7689055
9995016 | 0

# IfcSlab: Floor:NLRS_27.21_FL_beton ihwg d=50_gen (2)
In: 23 dakverdieping
PredefinedType: ROOF; Classification: 27.21 daken - constructief, vlakke daken (Uniformat); Material: NLRS_f2_beton ihwg 50 mm
Pset_SlabCommon - PitchAngle: 0 deg; IsExternal: yes; LoadBearing: no; Reference: NLRS_27.21_FL_beton ihwg d=50_gen; ThermalTransmittance: 20.92 kg/K/s3
Name (Floor:NLRS_27.21_FL_beton ihwg d=50_gen:...) | Group
11915168 | Model Group:NLRS_01.00_mid-rise_gen:4847172
11918933 | Model Group:NLRS_01.00_mid-rise_gen:4675261

# IfcSlab: Floor:NLRS_27.21_FL_beton prefab d=100_gen (2)
In: 23 dakverdieping
PredefinedType: ROOF; Classification: 27.21 daken - constructief, vlakke daken (Uniformat); Material: NLRS_f2_beton prefab 100 mm
Pset_SlabCommon - PitchAngle: 0 deg; IsExternal: yes; LoadBearing: no; Reference: NLRS_27.21_FL_beton prefab d=100_gen; ThermalTransmittance: 10.46 kg/K/s3
Name (Floor:NLRS_27.21_FL_beton prefab d=100_gen:...) | Group
11915063 | Model Group:NLRS_01.00_mid-rise_gen:4847172
11918926 | Model Group:NLRS_01.00_mid-rise_gen:4675261

# IfcSlab: Floor:NLRS_27.21_FL_beton prefab d=200_gen (16)
PredefinedType: ROOF; Classification: 27.21 daken - constructief, vlakke daken (Uniformat); Material: NLRS_f2_beton prefab 200 mm
Pset_SlabCommon - LoadBearing: yes; IsExternal: yes; Reference: NLRS_27.21_FL_beton prefab d=200_gen; ThermalTransmittance: 5.23 kg/K/s3
Name (Floor:NLRS_27.21_FL_beton prefab d=200_gen:...) | In | Group
4716934 | 05 vijfde verdieping | Model Group:NLRS_01.00_dakopbouw 01_gen:4907491
4716934:2 | 05 vijfde verdieping | Model Group:NLRS_01.00_dakopbouw 01_gen:4907491
4717285 | 05 vijfde verdieping | Model Group:NLRS_01.00_dakopbouw 02_gen:4909826 | Pset_SlabCommon - PitchAngle: 0 deg
4907965 | 05 vijfde verdieping | Model Group:NLRS_01.00_dakopbouw 01_gen:4907974
4907965:2 | 05 vijfde verdieping | Model Group:NLRS_01.00_dakopbouw 01_gen:4907974
4908065 | 05 vijfde verdieping | Model Group:NLRS_01.00_dakopbouw 01_gen:4908074
4908065:2 | 05 vijfde verdieping | Model Group:NLRS_01.00_dakopbouw 01_gen:4908074
4908135 | 05 vijfde verdieping | Model Group:NLRS_01.00_dakopbouw 01_gen:4908144
4908135:2 | 05 vijfde verdieping | Model Group:NLRS_01.00_dakopbouw 01_gen:4908144
4908209 | 05 vijfde verdieping
4908209:2 | 05 vijfde verdieping
4910173 | 05 vijfde verdieping | Model Group:NLRS_01.00_dakopbouw 02_gen:4910181 | Pset_SlabCommon - PitchAngle: 0 deg
4910331 | 05 vijfde verdieping | Model Group:NLRS_01.00_dakopbouw 02_gen:4910339 | Pset_SlabCommon - PitchAngle: 0 deg
4910431 | 05 vijfde verdieping | Model Group:NLRS_01.00_dakopbouw 02_gen:4910439 | Pset_SlabCommon - PitchAngle: 0 deg
4910524 | 05 vijfde verdieping | Model Group:NLRS_01.00_dakopbouw 02_gen:4910532 | Pset_SlabCommon - PitchAngle: 0 deg
5232966 | 04 vierde verdieping | Pset_SlabCommon - PitchAngle: 0 deg

# IfcSlab: Floor:NLRS_27.21_FL_kanaalplaat d=200_gen (3)
In: 05 vijfde verdieping
PredefinedType: ROOF; Classification: 27.21 daken - constructief, vlakke daken (Uniformat); Material: NLRS_f2_beton prefab 200 mm
Pset_SlabCommon - LoadBearing: yes; PitchAngle: 0 deg; IsExternal: yes; Reference: NLRS_27.21_FL_kanaalplaat d=200_gen; ThermalTransmittance: 5.23 kg/K/s3
Name (Floor:NLRS_27.21_FL_kanaalplaat d=200_gen:...)
5713909
12593159
13448787

# IfcSlab: NLRS_16.13_SFO_LB_fundatiepoer_gen:150x2700x1350, NLRS_16.13_SFO_LB_fundatiepoer_gen:150x2700x1350:9885626
In: 00 begane grond
PredefinedType: BASESLAB; Classification: 16.13 funderingsconstructies - voeten en balken, fundatie poeren (Uniformat); Material: NLRS_f2_beton ihwg
Pset_SlabCommon - IsExternal: no; PitchAngle: 0 deg; Reference: 150x2700x1350

# IfcSlab: NLRS_16.13_SFO_LB_fundatiepoer_gen:2470x2700x1350, NLRS_16.13_SFO_LB_fundatiepoer_gen:2470x2700x1350:4195481
In: 00 begane grond
PredefinedType: BASESLAB; Classification: 16.13 funderingsconstructies - voeten en balken, fundatie poeren (Uniformat); Material: NLRS_f2_beton ihwg
Pset_SlabCommon - IsExternal: no; PitchAngle: 0 deg; Reference: 2470x2700x1350

# IfcSlab: NLRS_16.13_SFO_LB_fundatiepoer_gen:2700x2700x1350 (2)
In: 00 begane grond
PredefinedType: BASESLAB; Classification: 16.13 funderingsconstructies - voeten en balken, fundatie poeren (Uniformat); Material: NLRS_f2_beton ihwg
Pset_SlabCommon - IsExternal: no; Reference: 2700x2700x1350; PitchAngle: 0 deg
Name (NLRS_16.13_SFO_LB_fundatiepoer_gen:2700x2700x1350:...)
4116818
4195483

# IfcSlab: NLRS_16.13_SFO_LB_fundatiepoer_gen:2700x3700x1650, NLRS_16.13_SFO_LB_fundatiepoer_gen:2700x3700x1650:4116828
In: 00 begane grond
PredefinedType: BASESLAB; Classification: 16.13 funderingsconstructies - voeten en balken, fundatie poeren (Uniformat); Material: NLRS_f2_beton ihwg
Pset_SlabCommon - IsExternal: no; PitchAngle: 0 deg; Reference: 2700x3700x1650

# IfcSlab: NLRS_16.13_SFO_LB_fundatiepoer_gen:2700x7380x1350, NLRS_16.13_SFO_LB_fundatiepoer_gen:2700x7380x1350:4116824
In: 00 begane grond
PredefinedType: BASESLAB; Classification: 16.13 funderingsconstructies - voeten en balken, fundatie poeren (Uniformat); Material: NLRS_f2_beton ihwg
Pset_SlabCommon - IsExternal: no; PitchAngle: 0 deg; Reference: 2700x7380x1350

# IfcSlab: NLRS_16.13_SFO_LB_fundatiepoer_gen:2930x1150x1350, NLRS_16.13_SFO_LB_fundatiepoer_gen:2930x1150x1350:9802785
In: 00 begane grond
PredefinedType: BASESLAB; Classification: 16.13 funderingsconstructies - voeten en balken, fundatie poeren (Uniformat); Material: NLRS_f2_beton ihwg
Pset_SlabCommon - IsExternal: no; PitchAngle: 0 deg; Reference: 2930x1150x1350

# IfcSlab: NLRS_16.13_SFO_LB_fundatiepoer_gen:3350x3750x1650, NLRS_16.13_SFO_LB_fundatiepoer_gen:3350x3750x1650:4116820
In: 00 begane grond
PredefinedType: BASESLAB; Classification: 16.13 funderingsconstructies - voeten en balken, fundatie poeren (Uniformat); Material: NLRS_f2_beton ihwg
Pset_SlabCommon - IsExternal: no; PitchAngle: 0 deg; Reference: 3350x3750x1650

# IfcSlab: NLRS_16.13_SFO_LB_fundatiepoer_gen:3600x3600x1650, NLRS_16.13_SFO_LB_fundatiepoer_gen:3600x3600x1650:5210958
In: 00 begane grond
PredefinedType: BASESLAB; Classification: 16.13 funderingsconstructies - voeten en balken, fundatie poeren (Uniformat); Material: NLRS_f2_beton ihwg
Pset_SlabCommon - IsExternal: no; PitchAngle: 0 deg; Reference: 3600x3600x1650

# IfcSlab: NLRS_16.13_SFO_LB_fundatiepoer_gen:3850x3350x1650, NLRS_16.13_SFO_LB_fundatiepoer_gen:3850x3350x1650:5210954
In: 00 begane grond
PredefinedType: BASESLAB; Classification: 16.13 funderingsconstructies - voeten en balken, fundatie poeren (Uniformat); Material: NLRS_f2_beton ihwg
Pset_SlabCommon - IsExternal: no; PitchAngle: 0 deg; Reference: 3850x3350x1650

# IfcSlab: NLRS_16.13_SFO_LB_fundatiepoer_gen:4000x2700x1650, NLRS_16.13_SFO_LB_fundatiepoer_gen:4000x2700x1650:5210952
In: 00 begane grond
PredefinedType: BASESLAB; Classification: 16.13 funderingsconstructies - voeten en balken, fundatie poeren (Uniformat); Material: NLRS_f2_beton ihwg
Pset_SlabCommon - IsExternal: no; PitchAngle: 0 deg; Reference: 4000x2700x1650

# IfcSlab: NLRS_16.13_SFO_LB_fundatiepoer_gen:600x2050x1200, NLRS_16.13_SFO_LB_fundatiepoer_gen:600x2050x1200:5708028
In: 00 begane grond
PredefinedType: BASESLAB; Classification: 16.13 funderingsconstructies - voeten en balken, fundatie poeren (Uniformat); Material: NLRS_f2_beton ihwg
Pset_SlabCommon - IsExternal: no; PitchAngle: 0 deg; Reference: 600x2050x1200

# IfcSlab: NLRS_16.13_SFO_LB_fundatiepoer_gen:600x2200x1200 (16)
In: 00 begane grond
PredefinedType: BASESLAB; Classification: 16.13 funderingsconstructies - voeten en balken, fundatie poeren (Uniformat); Material: NLRS_f2_beton ihwg
Pset_SlabCommon - IsExternal: no; Reference: 600x2200x1200
Name (NLRS_16.13_SFO_LB_fundatiepoer_gen:600x2200x1200:...) | PitchAngle (deg)
5221870 | 0
5222014 | 0
5222033 | 0
5222052 | 0
5222071 | 0
5222092 | 0
5222111 | 0
5222128 | 0
5222147 | 0
5222174 | 0
5222193 | 0
5222210 | 0
5222227 | 0
5222246
5222265 | 0
5263121 | 0

# IfcSlab: NLRS_16.13_SFO_LB_fundatiepoer_gen:600x6100x1200, NLRS_16.13_SFO_LB_fundatiepoer_gen:600x6100x1200:5948736
In: 00 begane grond
PredefinedType: BASESLAB; Classification: 16.13 funderingsconstructies - voeten en balken, fundatie poeren (Uniformat); Material: NLRS_f2_beton ihwg
Pset_SlabCommon - IsExternal: no; PitchAngle: 0 deg; Reference: 600x6100x1200

# IfcSlab: NLRS_16.13_SFO_LB_fundatiepoer_gen:625x1000x1350, NLRS_16.13_SFO_LB_fundatiepoer_gen:625x1000x1350:9922794
In: 00 begane grond
PredefinedType: BASESLAB; Classification: 16.13 funderingsconstructies - voeten en balken, fundatie poeren (Uniformat); Material: NLRS_f2_beton ihwg
Pset_SlabCommon - IsExternal: no; PitchAngle: 0 deg; Reference: 625x1000x1350

# IfcSlab: NLRS_16.13_SFO_LB_fundatiepoer_gen:6750x2900x1350, NLRS_16.13_SFO_LB_fundatiepoer_gen:6750x2900x1350:5014849
In: 00 begane grond
PredefinedType: BASESLAB; Classification: 16.13 funderingsconstructies - voeten en balken, fundatie poeren (Uniformat); Material: NLRS_f2_beton ihwg
Pset_SlabCommon - IsExternal: no; PitchAngle: 0 deg; Reference: 6750x2900x1350

# IfcSlab: NLRS_16.13_SFO_LB_fundatiepoer_gen:7050x2700x1350, NLRS_16.13_SFO_LB_fundatiepoer_gen:7050x2700x1350:5210956
In: 00 begane grond
PredefinedType: BASESLAB; Classification: 16.13 funderingsconstructies - voeten en balken, fundatie poeren (Uniformat); Material: NLRS_f2_beton ihwg
Pset_SlabCommon - IsExternal: no; PitchAngle: 0 deg; Reference: 7050x2700x1350

# IfcWall: Basic Wall:NLRS_16.21_WA_beton ihwg d=250_gen, Basic Wall:NLRS_16.21_WA_beton ihwg d=250_gen:5988041
In: 00 begane grond
Type - PredefinedType: STANDARD; Material: NLRS_f2_beton ihwg 250 mm
Classification: 16.21 funderingsconstructies - keerwanden, grondkerende wanden (Uniformat)
Pset_WallCommon - LoadBearing: yes; ExtendToStructure: no; IsExternal: yes; Reference: NLRS_16.21_WA_beton ihwg d=250_gen; ThermalTransmittance: 4.184 kg/K/s3

# IfcWall: Basic Wall:NLRS_16.22_WA_beton ihwg d=300_gen, Basic Wall:NLRS_16.22_WA_beton ihwg d=300_gen:5756958
In: 00 begane grond
Classification: 16.22 funderingsconstructies - keerwanden, waterkerende wanden (Uniformat); Material: NLRS_f2_beton ihwg
Pset_WallCommon - LoadBearing: yes; ExtendToStructure: no; IsExternal: yes; Reference: NLRS_16.22_WA_beton ihwg d=300_gen; ThermalTransmittance: 3.48667 kg/K/s3

# IfcWall: Basic Wall:NLRS_22.21_WA_beton ihwg d=250_gen (29)
Type - PredefinedType: STANDARD; Material: NLRS_f2_beton ihwg 250 mm
Classification: 22.21 binnenwanden - constructief, massieve wanden (Uniformat)
Pset_WallCommon - LoadBearing: yes; IsExternal: no; Reference: NLRS_22.21_WA_beton ihwg d=250_gen; ExtendToStructure: no; ThermalTransmittance: 4.184 kg/K/s3
Name (Basic Wall:NLRS_22.21_WA_beton ihwg d=250_gen:...) | In
4242424 | 00 begane grond
4243730 | 00 begane grond
4315560 | 01 eerste verdieping
4316144 | 01a eerste tussenverdieping
4319786 | 01 eerste verdieping
4320884 | 01 eerste verdieping
4339734 | 02 tweede verdieping
4341124 | 02 tweede verdieping
4341134 | 02 tweede verdieping
4341138 | 02 tweede verdieping
4343919 | 03 derde verdieping
4343925 | 03 derde verdieping
4343929 | 03 derde verdieping
4653471 | 22 tweeëntwintigste verdieping | Group: Model Group:NLRS_01.00_verdieping 21--23_gen (members excluded):4647240
4846823 | 22 tweeëntwintigste verdieping | Group: Model Group:NLRS_01.00_verdieping 21--23_gen (members excluded):4846692
5014898 | 00 begane grond
5014908 | 00 begane grond
5014952 | 01 eerste verdieping
5014964 | 01 eerste verdieping
5014968 | 01 eerste verdieping
5014982 | 02 tweede verdieping
5014992 | 02 tweede verdieping
5014998 | 03 derde verdieping
5015008 | 03 derde verdieping
11363118 | 04 vierde verdieping | Group: Model Group:NLRS_01.00_verdieping 04_gen (members excluded):4585793
11661663 | 22 tweeëntwintigste verdieping | Group: Model Group:NLRS_01.00_verdieping 21--23_gen (members excluded):4846692
11662010 | 22 tweeëntwintigste verdieping | Group: Model Group:NLRS_01.00_verdieping 21--23_gen (members excluded):4846692
11663185 | 22 tweeëntwintigste verdieping | Group: Model Group:NLRS_01.00_verdieping 21--23_gen (members excluded):4647240
11663189 | 22 tweeëntwintigste verdieping | Group: Model Group:NLRS_01.00_verdieping 21--23_gen (members excluded):4647240

# IfcWall: NLRS_16.12_SF_WPB_oplegnok ihwg beton_gen:200x200, NLRS_16.12_SF_WPB_oplegnok ihwg beton_gen:200x200:5954534
In: 00 begane grond
Type - Material: NLRS_f2_beton ihwg
Classification: 16.12 funderingsconstructies - voeten en balken, fundatie balken (Uniformat)
Pset_WallCommon - LoadBearing: yes; ExtendToStructure: no; IsExternal: yes; Reference: 200x200

# IfcWall: NLRS_21.21_SF_WPB_oplegnok ihwg beton_gen:200x250 (31)
Type - Material: NLRS_f2_beton ihwg
Classification: 21.21 buitenwanden - constructief, massieve wanden (Uniformat)
Pset_WallCommon - LoadBearing: yes; ExtendToStructure: no; IsExternal: yes; Reference: 200x250
Name (NLRS_21.21_SF_WPB_oplegnok ihwg beton_gen:200x250:...) | In
4392972 | 01 eerste verdieping
4393750 | 01c derde tussenverdieping
4393752 | 02b tweede tussenverdieping
4393754 | 04 vierde verdieping
4393756 | 01 eerste verdieping
4394438 | 01c derde tussenverdieping
4394440 | 02b tweede tussenverdieping
4394442 | 04 vierde verdieping
4394444 | 01 eerste verdieping
4394724 | 01c derde tussenverdieping
4394726 | 02b tweede tussenverdieping
4394728 | 01 eerste verdieping
4394824 | 01c derde tussenverdieping
4394826 | 02b tweede tussenverdieping
4394828 | 01 eerste verdieping
4394867 | 01c derde tussenverdieping
4394869 | 02b tweede tussenverdieping
4394871 | 01 eerste verdieping
4394952 | 04 vierde verdieping
4399643 | 01c derde tussenverdieping
4399761 | 02b tweede tussenverdieping
5015046 | 01 eerste verdieping
6265110 | 01c derde tussenverdieping
6265112 | 02b tweede tussenverdieping
6651517 | 02b tweede tussenverdieping
6651654 | 04 vierde verdieping
6651908 | 01c derde tussenverdieping
6652160 | 02b tweede tussenverdieping
6652175 | 04 vierde verdieping
8792734 | 04 vierde verdieping
8792741 | 04 vierde verdieping

# IfcWall: NLRS_21.21_SF_WPB_oplegnok ihwg beton_gen:250x250 (11)
Type - Material: NLRS_f2_beton ihwg
Classification: 21.21 buitenwanden - constructief, massieve wanden (Uniformat)
Pset_WallCommon - LoadBearing: yes; ExtendToStructure: no; IsExternal: yes; Reference: 250x250
Name (NLRS_21.21_SF_WPB_oplegnok ihwg beton_gen:250x250:...) | In
6574442 | 01 eerste verdieping
6574453 | 01 eerste verdieping
6574455 | 01 eerste verdieping
6574473 | 01b tweede tussenverdieping
6574479 | 02a eerste tussenverdieping
6574631 | 01b tweede tussenverdieping
6574633 | 02a eerste tussenverdieping
6574766 | 01b tweede tussenverdieping
6574783 | 02a eerste tussenverdieping
6574968 | 01b tweede tussenverdieping
6574970 | 02a eerste tussenverdieping

# IfcWall: NLRS_21.21_SF_WPB_oplegnok ihwg beton_gen:250x400, NLRS_21.21_SF_WPB_oplegnok ihwg beton_gen:250x400:6573056
In: 01 eerste verdieping
Type - Material: NLRS_f2_beton ihwg
Classification: 21.21 buitenwanden - constructief, massieve wanden (Uniformat)
Pset_WallCommon - LoadBearing: yes; ExtendToStructure: no; IsExternal: yes; Reference: 250x400

# IfcWall: NLRS_21.21_SF_WPB_oplegnok prefabbeton_gen:200x200 (12)
Type - Material: NLRS_f2_beton prefab
Classification: 21.21 buitenwanden - constructief, massieve wanden (Uniformat)
Pset_WallCommon - LoadBearing: yes; ExtendToStructure: no; IsExternal: yes; Reference: 200x200
Name (NLRS_21.21_SF_WPB_oplegnok prefabbeton_gen:200x200:...) | In
4284255 | 00a eerste tussenverdieping
4284787 | 00a eerste tussenverdieping
5392523 | 04 vierde verdieping
6556346 | 00a eerste tussenverdieping
7689066 | 04 vierde verdieping
7689068 | 04 vierde verdieping
12806310 | 04 vierde verdieping
12806314 | 04 vierde verdieping
12806397 | 04 vierde verdieping
12806401 | 04 vierde verdieping
12806508 | 04 vierde verdieping
12806516 | 04 vierde verdieping

# IfcWall: NLRS_21.21_SF_WPB_oplegnok prefabbeton_gen:200x250 (15)
Type - Material: NLRS_f2_beton prefab
Classification: 21.21 buitenwanden - constructief, massieve wanden (Uniformat)
Pset_WallCommon - LoadBearing: yes; ExtendToStructure: no; IsExternal: yes; Reference: 200x250
Name (NLRS_21.21_SF_WPB_oplegnok prefabbeton_gen:200x250:...) | In
4283808 | 00a eerste tussenverdieping
4283810 | 00a eerste tussenverdieping
4395246 | 01 eerste verdieping
4395554 | 01c derde tussenverdieping
4396779 | 01 eerste verdieping
4397124 | 01 eerste verdieping
4397478 | 01 eerste verdieping
4397705 | 01c derde tussenverdieping
5230104 | 01b tweede tussenverdieping
5392646 | 04 vierde verdieping
6491020 | 01a eerste tussenverdieping
6552786 | 01 eerste verdieping
6604337 | 01 eerste verdieping
6612303 | 01 eerste verdieping
6816431 | 01c derde tussenverdieping

# IfcWall: NLRS_21.21_SF_WPB_oplegnok prefabbeton_gen:200x250 afschuining (28)
Type - Material: NLRS_f2_beton prefab
Classification: 21.21 buitenwanden - constructief, massieve wanden (Uniformat)
Pset_WallCommon - LoadBearing: yes; ExtendToStructure: no; IsExternal: yes; Reference: 200x250 afschuining
Name (NLRS_21.21_SF_WPB_oplegnok prefabbeton_gen:200x250 afschuining:...) | In
6142879 | 00a eerste tussenverdieping
6143688 | 01b tweede tussenverdieping
6144261 | 02a eerste tussenverdieping
6188703 | 01a eerste tussenverdieping
6188705 | 00a eerste tussenverdieping
6188803 | 01c derde tussenverdieping
6188805 | 01b tweede tussenverdieping
6188860 | 02b tweede tussenverdieping
6188862 | 02a eerste tussenverdieping
6191637 | 01c derde tussenverdieping
6191644 | 01a eerste tussenverdieping
6191654 | 00a eerste tussenverdieping
6191731 | 01b tweede tussenverdieping
6192239 | 02b tweede tussenverdieping
6205718 | 01a eerste tussenverdieping
6205720 | 00a eerste tussenverdieping
6205832 | 01c derde tussenverdieping
6205834 | 01b tweede tussenverdieping
6205920 | 02b tweede tussenverdieping
6205922 | 02a eerste tussenverdieping
6206198 | 01b tweede tussenverdieping
6206237 | 02a eerste tussenverdieping
6209097 | 00a eerste tussenverdieping
6209194 | 00a eerste tussenverdieping
6209207 | 02a eerste tussenverdieping
6209258 | 02a eerste tussenverdieping
6209754 | 01b tweede tussenverdieping
10263241 | 01a eerste tussenverdieping

# IfcWall: NLRS_21.21_SF_WPB_oplegnok prefabbeton_gen:220x250 (4)
Type - Material: NLRS_f2_beton prefab
Classification: 21.21 buitenwanden - constructief, massieve wanden (Uniformat)
Pset_WallCommon - LoadBearing: yes; ExtendToStructure: no; IsExternal: yes; Reference: 220x250
Name (NLRS_21.21_SF_WPB_oplegnok prefabbeton_gen:220x250:...) | In
6597596 | 04 vierde verdieping
6597639 | 04 vierde verdieping
6598742 | 03 derde verdieping
6599451 | 03 derde verdieping

# IfcWall: NLRS_21.21_SF_WPB_oplegnok prefabbeton_gen:250x250, NLRS_21.21_SF_WPB_oplegnok prefabbeton_gen:250x250:7388595
In: 00a eerste tussenverdieping
Type - Material: NLRS_f2_beton prefab
Classification: 21.21 buitenwanden - constructief, massieve wanden (Uniformat)
Pset_WallCommon - LoadBearing: yes; ExtendToStructure: no; IsExternal: yes; Reference: 250x250

# IfcWall: NLRS_21.21_SF_WPB_oplegnok prefabbeton_gen:250x260, NLRS_21.21_SF_WPB_oplegnok prefabbeton_gen:250x260:11169153
In: 00a eerste tussenverdieping
Type - Material: NLRS_f2_beton prefab
Classification: 21.21 buitenwanden - constructief, massieve wanden (Uniformat)
Pset_WallCommon - LoadBearing: yes; ExtendToStructure: no; IsExternal: yes; Reference: 250x260

# IfcWall: NLRS_21.21_SF_WPB_oplegnok prefabbeton_gen:250x270, NLRS_21.21_SF_WPB_oplegnok prefabbeton_gen:250x270:5230201
In: 00a eerste tussenverdieping
Type - Material: NLRS_f2_beton prefab
Classification: 21.21 buitenwanden - constructief, massieve wanden (Uniformat)
Pset_WallCommon - LoadBearing: yes; ExtendToStructure: no; IsExternal: yes; Reference: 250x270

# IfcWall: NLRS_21.21_SF_WPB_oplegnok prefabbeton_gen:250x270 met afschuining -9gr (24)
Type - Material: NLRS_f2_beton prefab
Classification: 21.21 buitenwanden - constructief, massieve wanden (Uniformat)
Pset_WallCommon - LoadBearing: yes; ExtendToStructure: no; IsExternal: yes; Reference: 250x270 met afschuining -9gr
Name (NLRS_21.21_SF_WPB_oplegnok prefabbeton_gen:250x270 met afschuining -9gr:...) | In
6590529 | 00a eerste tussenverdieping
6590531 | 00a eerste tussenverdieping
6590533 | 00a eerste tussenverdieping
6590535 | 00a eerste tussenverdieping
6595619 | 01b tweede tussenverdieping
6595621 | 01b tweede tussenverdieping
6595623 | 01b tweede tussenverdieping
6595625 | 01b tweede tussenverdieping
6595633 | 02a eerste tussenverdieping
6595635 | 02a eerste tussenverdieping
6595637 | 02a eerste tussenverdieping
6595639 | 02a eerste tussenverdieping
6596099 | 01 eerste verdieping
6596101 | 01 eerste verdieping
6596103 | 01 eerste verdieping
6596105 | 01 eerste verdieping
6596329 | 01c derde tussenverdieping
6596331 | 01c derde tussenverdieping
6596333 | 01c derde tussenverdieping
6596335 | 01c derde tussenverdieping
6596337 | 02b tweede tussenverdieping
6596339 | 02b tweede tussenverdieping
6596341 | 02b tweede tussenverdieping
6596343 | 02b tweede tussenverdieping

# IfcWall: NLRS_21.21_SF_WPB_oplegnok prefabbeton_gen:250x270 met afschuining 9gr (24)
Type - Material: NLRS_f2_beton prefab
Classification: 21.21 buitenwanden - constructief, massieve wanden (Uniformat)
Pset_WallCommon - LoadBearing: yes; ExtendToStructure: no; IsExternal: yes; Reference: 250x270 met afschuining 9gr
Name (NLRS_21.21_SF_WPB_oplegnok prefabbeton_gen:250x270 met afschuining 9gr:...) | In
6588793 | 00a eerste tussenverdieping
6588801 | 00a eerste tussenverdieping
6588850 | 00a eerste tussenverdieping
6588922 | 00a eerste tussenverdieping
6595464 | 01b tweede tussenverdieping
6595466 | 01b tweede tussenverdieping
6595468 | 01b tweede tussenverdieping
6595470 | 01b tweede tussenverdieping
6595502 | 02a eerste tussenverdieping
6595504 | 02a eerste tussenverdieping
6595506 | 02a eerste tussenverdieping
6595508 | 02a eerste tussenverdieping
6595854 | 01a eerste tussenverdieping
6595911 | 01a eerste tussenverdieping
6596037 | 01a eerste tussenverdieping
6596039 | 01a eerste tussenverdieping
6596174 | 01c derde tussenverdieping
6596176 | 01c derde tussenverdieping
6596178 | 01c derde tussenverdieping
6596180 | 01c derde tussenverdieping
6596237 | 02b tweede tussenverdieping
6596239 | 02b tweede tussenverdieping
6596241 | 02b tweede tussenverdieping
6596243 | 02b tweede tussenverdieping

# IfcWall: NLRS_21.21_SF_WPB_oplegnok prefabbeton_gen:250x310 (38)
Type - Material: NLRS_f2_beton prefab
Classification: 21.21 buitenwanden - constructief, massieve wanden (Uniformat)
Pset_WallCommon - LoadBearing: yes; ExtendToStructure: no; IsExternal: yes; Reference: 250x310
Name (NLRS_21.21_SF_WPB_oplegnok prefabbeton_gen:250x310:...) | In
4529504 | 00a eerste tussenverdieping
4530669 | 01b tweede tussenverdieping
4530732 | 02a eerste tussenverdieping
4531702 | 00a eerste tussenverdieping
4531721 | 01b tweede tussenverdieping
4531738 | 02a eerste tussenverdieping
4531974 | 01a eerste tussenverdieping
4532041 | 01c derde tussenverdieping
4532058 | 02b tweede tussenverdieping
4532379 | 01b tweede tussenverdieping
4532398 | 01c derde tussenverdieping
4532419 | 02a eerste tussenverdieping
4532438 | 02b tweede tussenverdieping
4936170 | 01a eerste tussenverdieping
4936232 | 01c derde tussenverdieping
4936251 | 02b tweede tussenverdieping
5523766 | 01a eerste tussenverdieping
5523960 | 00a eerste tussenverdieping
5524063 | 00a eerste tussenverdieping
5591015 | 00a eerste tussenverdieping
6188955 | 01b tweede tussenverdieping
6188961 | 00a eerste tussenverdieping
6188967 | 02a eerste tussenverdieping
6234040 | 01b tweede tussenverdieping
6563084 | 00a eerste tussenverdieping
10263191 | 00a eerste tussenverdieping
10263193 | 01b tweede tussenverdieping
10263195 | 02a eerste tussenverdieping
10263216 | 00a eerste tussenverdieping
10263222 | 00a eerste tussenverdieping
10263224 | 01b tweede tussenverdieping
10263226 | 02a eerste tussenverdieping
10263283 | 01a eerste tussenverdieping
10263285 | 01c derde tussenverdieping
10263287 | 02b tweede tussenverdieping
10312200 | 00a eerste tussenverdieping
10312206 | 00a eerste tussenverdieping
10312213 | 01b tweede tussenverdieping

# IfcWall: NLRS_21.21_SF_WPB_oplegnok prefabbeton_gen:275x275 met afschuining 15gr (5)
In: 05 vijfde verdieping
Type - Material: NLRS_f2_beton prefab
Classification: 21.21 buitenwanden - constructief, massieve wanden (Uniformat)
Pset_WallCommon - LoadBearing: yes; ExtendToStructure: no; IsExternal: yes; Reference: 275x275 met afschuining 15gr
Name (NLRS_21.21_SF_WPB_oplegnok prefabbeton_gen:275x275 met afschuining 15gr:...)
5714201
5714203
5714205
5714207
5714209

# IfcWall: NLRS_21.21_SF_WPB_oplegnok prefabbeton_gen:300x350 (2)
Type - Material: NLRS_f2_beton prefab
Classification: 21.21 buitenwanden - constructief, massieve wanden (Uniformat)
Pset_WallCommon - LoadBearing: yes; ExtendToStructure: no; IsExternal: yes; Reference: 300x350
Name (NLRS_21.21_SF_WPB_oplegnok prefabbeton_gen:300x350:...) | In
6267552 | 04 vierde verdieping
6267558 | 03 derde verdieping

# IfcWall: NLRS_21.21_SF_WPB_oplegnok prefabbeton_gen:325x450 met afschuining 15gr (5)
In: 04 vierde verdieping
Type - Material: NLRS_f2_beton prefab
Classification: 21.21 buitenwanden - constructief, massieve wanden (Uniformat)
Pset_WallCommon - LoadBearing: yes; ExtendToStructure: no; IsExternal: yes; Reference: 325x450 met afschuining 15gr
Name (NLRS_21.21_SF_WPB_oplegnok prefabbeton_gen:325x450 met afschuining 15gr:...)
5714191
5714193
5714195
5714197
5714199

# IfcWallStandardCase: Basic Wall:NLRS_16.12_WA_beton ihwg d=250_gen (2)
In: 00 begane grond
Type - PredefinedType: STANDARD; Material: NLRS_f2_beton ihwg 250 mm
Classification: 16.12 funderingsconstructies - voeten en balken, fundatie balken (Uniformat)
Pset_WallCommon - LoadBearing: yes; IsExternal: no; ExtendToStructure: no; Reference: NLRS_16.12_WA_beton ihwg d=250_gen; ThermalTransmittance: 4.184 kg/K/s3
Name (Basic Wall:NLRS_16.12_WA_beton ihwg d=250_gen:...) | Group
8019412 | Model Group:Wand onder hellingbaan as L.35:8020095
8020230 | Model Group:Wand onder hellingbaan as L.35:8020249

# IfcWallStandardCase: Basic Wall:NLRS_16.21_WA_beton ihwg d=200_gen (2)
In: 00 begane grond
Type - PredefinedType: STANDARD; Material: NLRS_f2_beton ihwg 200 mm
Classification: 16.21 funderingsconstructies - keerwanden, grondkerende wanden (Uniformat)
Pset_WallCommon - LoadBearing: yes; ExtendToStructure: no; IsExternal: yes; Reference: NLRS_16.21_WA_beton ihwg d=200_gen; ThermalTransmittance: 5.23 kg/K/s3
Name (Basic Wall:NLRS_16.21_WA_beton ihwg d=200_gen:...)
10351883
10351974

# IfcWallStandardCase: Basic Wall:NLRS_16.21_WA_beton ihwg d=250_gen (15)
In: 00 begane grond
Type - PredefinedType: STANDARD; Material: NLRS_f2_beton ihwg 250 mm
Classification: 16.21 funderingsconstructies - keerwanden, grondkerende wanden (Uniformat)
Pset_WallCommon - ExtendToStructure: no; IsExternal: yes; Reference: NLRS_16.21_WA_beton ihwg d=250_gen; ThermalTransmittance: 4.184 kg/K/s3
Name (Basic Wall:NLRS_16.21_WA_beton ihwg d=250_gen:...) | LoadBearing
4238181 | yes
4545560 | yes
5707900 | yes
5708017 | yes
5709161 | yes
5709163 | yes
5709169 | yes
5709224 | yes
5709226 | yes
5709228 | yes
5709402 | yes
5709406 | yes
5709408 | yes
8448483 | no
8499921 | yes

# IfcWallStandardCase: Basic Wall:NLRS_16.21_WA_beton ihwg d=275_gen (2)
In: 00 begane grond
Type - PredefinedType: STANDARD; Material: NLRS_f2_beton ihwg 275 mm
Classification: 16.21 funderingsconstructies - keerwanden, grondkerende wanden (Uniformat)
Pset_WallCommon - LoadBearing: yes; ExtendToStructure: no; IsExternal: yes; Reference: NLRS_16.21_WA_beton ihwg d=275_gen; ThermalTransmittance: 3.80364 kg/K/s3
Name (Basic Wall:NLRS_16.21_WA_beton ihwg d=275_gen:...)
5709404
6045209

# IfcWallStandardCase: Basic Wall:NLRS_16.21_WA_beton ihwg d=400_gen (7)
In: 00 begane grond
Type - PredefinedType: STANDARD; Material: NLRS_f2_beton ihwg 400 mm
Classification: 16.21 funderingsconstructies - keerwanden, grondkerende wanden (Uniformat)
Pset_WallCommon - LoadBearing: yes; ExtendToStructure: no; IsExternal: yes; Reference: NLRS_16.21_WA_beton ihwg d=400_gen; ThermalTransmittance: 2.615 kg/K/s3
Name (Basic Wall:NLRS_16.21_WA_beton ihwg d=400_gen:...)
5709081
5709438
5709440
5889313
5985248
6017454
7321164

# IfcWallStandardCase: Basic Wall:NLRS_16.21_WA_beton ihwg d=500_gen (7)
In: 00 begane grond
Type - PredefinedType: STANDARD; Material: NLRS_f2_beton ihwg 500 mm
Classification: 16.21 funderingsconstructies - keerwanden, grondkerende wanden (Uniformat)
Pset_WallCommon - ExtendToStructure: no; IsExternal: yes; Reference: NLRS_16.21_WA_beton ihwg d=500_gen; ThermalTransmittance: 2.092 kg/K/s3
Name (Basic Wall:NLRS_16.21_WA_beton ihwg d=500_gen:...) | LoadBearing
5709165 | yes
5709167 | yes
5709347 | yes
5988288 | yes
5992928 | yes
5993174 | yes
8453925 | no

# IfcWallStandardCase: Basic Wall:NLRS_16.21_WA_beton prefab d=250_gen (33)
Type - PredefinedType: STANDARD; Material: NLRS_f2_beton prefab 250 mm
Classification: 16.21 funderingsconstructies - keerwanden, grondkerende wanden (Uniformat)
Pset_WallCommon - LoadBearing: yes; ExtendToStructure: no; IsExternal: yes; Reference: NLRS_16.21_WA_beton prefab d=250_gen; ThermalTransmittance: 4.184 kg/K/s3
Name (Basic Wall:NLRS_16.21_WA_beton prefab d=250_gen:...) | In
5754660 | 00a eerste tussenverdieping
5755363 | 01a eerste tussenverdieping
5755407 | 01b tweede tussenverdieping
5755509 | 02a eerste tussenverdieping
5755548 | 02b tweede tussenverdieping
5755710 | 01c derde tussenverdieping
5755859 | 00 begane grond
6129884 | 00 begane grond
6143668 | 00a eerste tussenverdieping
6144241 | 01b tweede tussenverdieping
6144538 | 02a eerste tussenverdieping
6188982 | 00a eerste tussenverdieping
6191690 | 01a eerste tussenverdieping
6191938 | 01b tweede tussenverdieping
6191957 | 01c derde tussenverdieping
6192143 | 02a eerste tussenverdieping
6205553 | 02b tweede tussenverdieping
6205561 | 00 begane grond
6205620 | 01a eerste tussenverdieping
6205730 | 00a eerste tussenverdieping
6205812 | 01c derde tussenverdieping
6205836 | 01b tweede tussenverdieping
6205932 | 02a eerste tussenverdieping
6205970 | 02b tweede tussenverdieping
6206002 | 00 begane grond
6206048 | 00 begane grond
6206108 | 00a eerste tussenverdieping
6206160 | 00a eerste tussenverdieping
6209047 | 01b tweede tussenverdieping
6209087 | 02a eerste tussenverdieping
6209134 | 00 begane grond
6209220 | 01b tweede tussenverdieping
6209265 | 02a eerste tussenverdieping

# IfcWallStandardCase: Basic Wall:NLRS_21.11_WA_kalkzandsteen vellingblok d=150_gen (4)
In: 00 begane grond
Type - PredefinedType: STANDARD; Material: NLRS_f1_kalkzandsteen wit 150 mm
Classification: 21.11 buitenwanden - niet constructief, massieve wanden (Uniformat)
Pset_WallCommon - LoadBearing: yes; ExtendToStructure: no; IsExternal: yes; Reference: NLRS_21.11_WA_kalkzandsteen vellingblok d=150_gen
Name (Basic Wall:NLRS_21.11_WA_kalkzandsteen vellingblok d=150_gen:...)
4272335
4272337
5014944
5014946

# IfcWallStandardCase: Basic Wall:NLRS_21.12_WA_isolatie EPS platen d=20_gen (20)
In: 00 begane grond
Type - PredefinedType: STANDARD; Material: NLRS_n7_isolatie EPS 20 mm
Classification: 21.12 buitenwanden - niet constructief, spouwwanden (Uniformat)
Pset_WallCommon - LoadBearing: yes; ExtendToStructure: no; IsExternal: yes; Reference: NLRS_21.12_WA_isolatie EPS platen d=20_gen; ThermalTransmittance: 1.75 kg/K/s3
Name (Basic Wall:NLRS_21.12_WA_isolatie EPS platen d=20_gen:...)
7240616
7240632
7240642
7240856
7241000
7242085
7312825
7312859
7313392
7313944
7313946
7313950
7314153
7314485
7315777
7319178
7319270
7319577
7319630
7320596

# IfcWallStandardCase: Basic Wall:NLRS_21.21_WA_beton ihwg d=150_gen (21)
Type - PredefinedType: STANDARD; Material: NLRS_f2_beton ihwg 150 mm
Classification: 21.21 buitenwanden - constructief, massieve wanden (Uniformat)
Pset_WallCommon - LoadBearing: yes; ExtendToStructure: no; IsExternal: yes; Reference: NLRS_21.21_WA_beton ihwg d=150_gen; ThermalTransmittance: 6.97333 kg/K/s3
Name (Basic Wall:NLRS_21.21_WA_beton ihwg d=150_gen:...) | In | Group
4561322 | 04 vierde verdieping | Model Group:NLRS_01.00_dakopbouw 01_gen:4907491
4561441 | 04 vierde verdieping | Model Group:NLRS_01.00_dakopbouw 01_gen:4907491
4566546 | 04 vierde verdieping | Model Group:NLRS_01.00_dakopbouw 02_gen:4909826
4566548 | 04 vierde verdieping | Model Group:NLRS_01.00_dakopbouw 02_gen:4909826
4907957 | 04 vierde verdieping | Model Group:NLRS_01.00_dakopbouw 01_gen:4907974
4907959 | 04 vierde verdieping | Model Group:NLRS_01.00_dakopbouw 01_gen:4907974
4908057 | 04 vierde verdieping | Model Group:NLRS_01.00_dakopbouw 01_gen:4908074
4908059 | 04 vierde verdieping | Model Group:NLRS_01.00_dakopbouw 01_gen:4908074
4908127 | 04 vierde verdieping | Model Group:NLRS_01.00_dakopbouw 01_gen:4908144
4908129 | 04 vierde verdieping | Model Group:NLRS_01.00_dakopbouw 01_gen:4908144
4908201 | 04 vierde verdieping
4908203 | 04 vierde verdieping
4910166 | 04 vierde verdieping | Model Group:NLRS_01.00_dakopbouw 02_gen:4910181
4910168 | 04 vierde verdieping | Model Group:NLRS_01.00_dakopbouw 02_gen:4910181
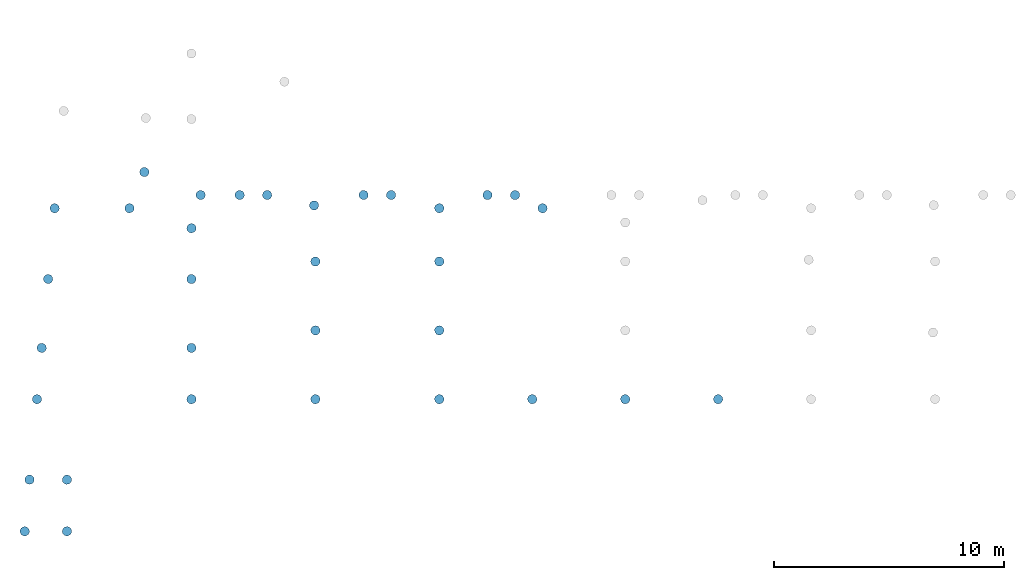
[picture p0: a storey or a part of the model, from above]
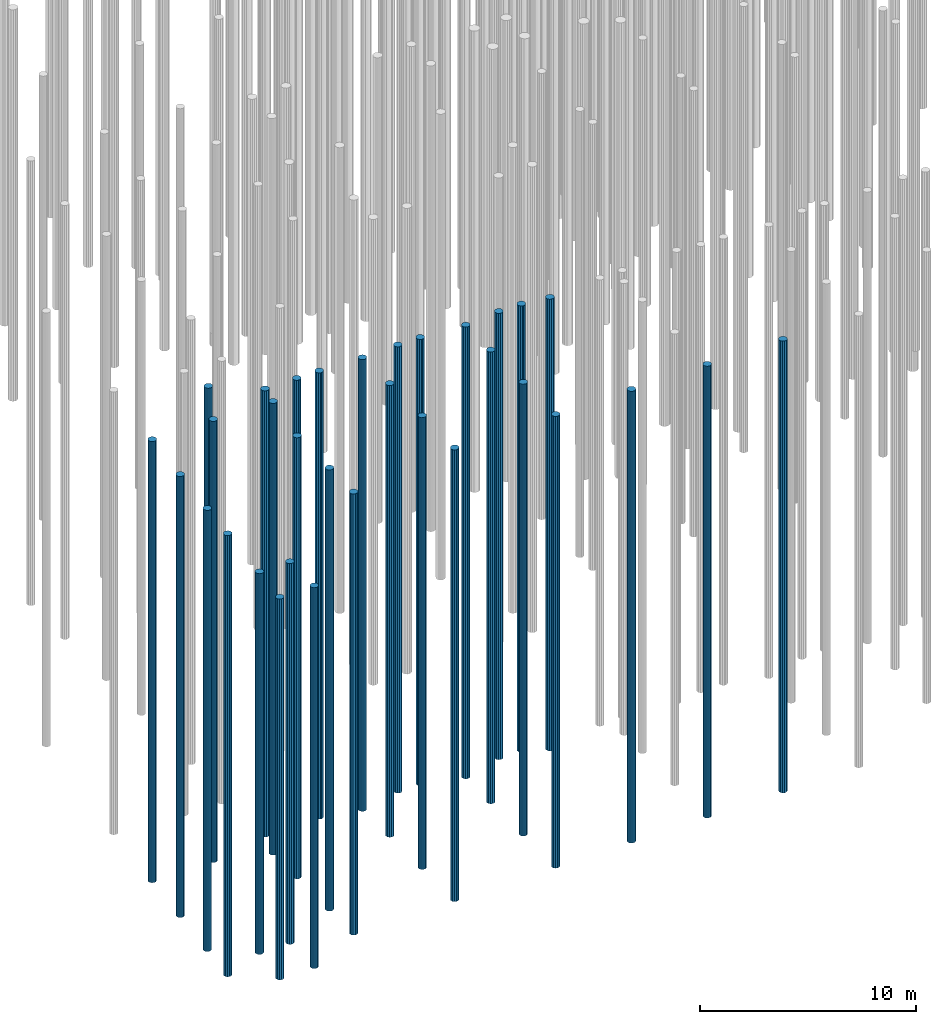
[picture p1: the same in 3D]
Properties of the parts of a building model (IFC2X3), part 10 of 11

# IfcWallStandardCase: Basic Wall:NLRS_21.21_WA_beton ihwg d=150_gen (21)
Name (Basic Wall:NLRS_21.21_WA_beton ihwg d=150_gen:...) | In | Group
4910324 | 04 vierde verdieping | Model Group:NLRS_01.00_dakopbouw 02_gen:4910339
4910326 | 04 vierde verdieping | Model Group:NLRS_01.00_dakopbouw 02_gen:4910339
4910424 | 04 vierde verdieping | Model Group:NLRS_01.00_dakopbouw 02_gen:4910439
4910426 | 04 vierde verdieping | Model Group:NLRS_01.00_dakopbouw 02_gen:4910439
4910517 | 04 vierde verdieping | Model Group:NLRS_01.00_dakopbouw 02_gen:4910532
4910519 | 04 vierde verdieping | Model Group:NLRS_01.00_dakopbouw 02_gen:4910532
10767428 | 00 begane grond

# IfcWallStandardCase: Basic Wall:NLRS_21.21_WA_beton ihwg d=200_gen (33)
Type - PredefinedType: STANDARD; Material: NLRS_f2_beton ihwg 200 mm
Classification: 21.21 buitenwanden - constructief, massieve wanden (Uniformat)
Pset_WallCommon - LoadBearing: yes; ExtendToStructure: no; IsExternal: yes; Reference: NLRS_21.21_WA_beton ihwg d=200_gen; ThermalTransmittance: 5.23 kg/K/s3
Name (Basic Wall:NLRS_21.21_WA_beton ihwg d=200_gen:...) | In | Group
4566550 | 04 vierde verdieping | Model Group:NLRS_01.00_dakopbouw 02_gen:4909826
4910170 | 04 vierde verdieping | Model Group:NLRS_01.00_dakopbouw 02_gen:4910181
4910328 | 04 vierde verdieping | Model Group:NLRS_01.00_dakopbouw 02_gen:4910339
4910428 | 04 vierde verdieping | Model Group:NLRS_01.00_dakopbouw 02_gen:4910439
4910521 | 04 vierde verdieping | Model Group:NLRS_01.00_dakopbouw 02_gen:4910532
11910071 | 23 dakverdieping | Model Group:NLRS_01.00_verdieping 21--23_gen (members excluded):4846692
11910676 | 23 dakverdieping | Model Group:NLRS_01.00_verdieping 21--23_gen (members excluded):4846692
11910873 | 23 dakverdieping | Model Group:NLRS_01.00_verdieping 21--23_gen (members excluded):4846692
11911235 | 23 dakverdieping | Model Group:NLRS_01.00_verdieping 21--23_gen (members excluded):4846692
11911363 | 23 dakverdieping | Model Group:NLRS_01.00_verdieping 21--23_gen (members excluded):4846692
11911468 | 23 dakverdieping | Model Group:NLRS_01.00_verdieping 21--23_gen (members excluded):4846692
11911724 | 23 dakverdieping | Model Group:NLRS_01.00_verdieping 21--23_gen (members excluded):4846692
11912062 | 23 dakverdieping | Model Group:NLRS_01.00_verdieping 21--23_gen (members excluded):4846692
11912180 | 23 dakverdieping | Model Group:NLRS_01.00_verdieping 21--23_gen (members excluded):4846692
11912355 | 23 dakverdieping | Model Group:NLRS_01.00_verdieping 21--23_gen (members excluded):4846692
11912633 | 23 dakverdieping | Model Group:NLRS_01.00_verdieping 21--23_gen (members excluded):4846692
11912635 | 23 dakverdieping | Model Group:NLRS_01.00_verdieping 21--23_gen (members excluded):4846692
11912799 | 23 dakverdieping | Model Group:NLRS_01.00_verdieping 21--23_gen (members excluded):4846692
11912916 | 23 dakverdieping | Model Group:NLRS_01.00_verdieping 21--23_gen (members excluded):4846692
11914850 | 23 dakverdieping | Model Group:NLRS_01.00_verdieping 21--23_gen (members excluded):4647240
11914852 | 23 dakverdieping | Model Group:NLRS_01.00_verdieping 21--23_gen (members excluded):4647240
11914854 | 23 dakverdieping | Model Group:NLRS_01.00_verdieping 21--23_gen (members excluded):4647240
11914856 | 23 dakverdieping | Model Group:NLRS_01.00_verdieping 21--23_gen (members excluded):4647240
11914858 | 23 dakverdieping | Model Group:NLRS_01.00_verdieping 21--23_gen (members excluded):4647240
11914860 | 23 dakverdieping | Model Group:NLRS_01.00_verdieping 21--23_gen (members excluded):4647240
11914862 | 23 dakverdieping | Model Group:NLRS_01.00_verdieping 21--23_gen (members excluded):4647240
11914864 | 23 dakverdieping | Model Group:NLRS_01.00_verdieping 21--23_gen (members excluded):4647240
11914866 | 23 dakverdieping | Model Group:NLRS_01.00_verdieping 21--23_gen (members excluded):4647240
11914868 | 23 dakverdieping | Model Group:NLRS_01.00_verdieping 21--23_gen (members excluded):4647240
11914870 | 23 dakverdieping | Model Group:NLRS_01.00_verdieping 21--23_gen (members excluded):4647240
11914872 | 23 dakverdieping | Model Group:NLRS_01.00_verdieping 21--23_gen (members excluded):4647240
11914874 | 23 dakverdieping | Model Group:NLRS_01.00_verdieping 21--23_gen (members excluded):4647240
11914876 | 23 dakverdieping | Model Group:NLRS_01.00_verdieping 21--23_gen (members excluded):4647240

# IfcWallStandardCase: Basic Wall:NLRS_21.21_WA_beton ihwg d=250_gen (150)
Type - PredefinedType: STANDARD; Material: NLRS_f2_beton ihwg 250 mm
Classification: 21.21 buitenwanden - constructief, massieve wanden (Uniformat)
Pset_WallCommon - LoadBearing: yes; ExtendToStructure: no; IsExternal: yes; Reference: NLRS_21.21_WA_beton ihwg d=250_gen; ThermalTransmittance: 4.184 kg/K/s3
Name (Basic Wall:NLRS_21.21_WA_beton ihwg d=250_gen:...) | In | Group
4343921 | 02b tweede tussenverdieping
4343923 | 03 derde verdieping
4561626 | 04 vierde verdieping | Model Group:NLRS_01.00_dakopbouw 01_gen:4907491
4744578 | 04 vierde verdieping | Model Group:NLRS_01.00_verdieping 04_gen (members excluded):4585793
4745194 | 04 vierde verdieping | Model Group:NLRS_01.00_verdieping 04_gen (members excluded):4585793
4745206 | 06 zesde verdieping | Model Group:NLRS_21.21_wand ihwg as L.P 06-20_gen:4599056
4745210 | 06 zesde verdieping | Model Group:NLRS_21.21_wand ihwg as L.P 06-20_gen:4599124
4745222 | 07 zevende verdieping | Model Group:NLRS_21.21_wand ihwg as L.P 06-20_gen:4600793
4745226 | 07 zevende verdieping | Model Group:NLRS_21.21_wand ihwg as L.P 06-20_gen:4600861
4745230 | 08 achtste verdieping | Model Group:NLRS_21.21_wand ihwg as L.P 06-20_gen:4601861
4745234 | 08 achtste verdieping | Model Group:NLRS_21.21_wand ihwg as L.P 06-20_gen:4601929
4745238 | 09 negende verdieping | Model Group:NLRS_21.21_wand ihwg as L.P 06-20_gen:4602970
4745242 | 09 negende verdieping | Model Group:NLRS_21.21_wand ihwg as L.P 06-20_gen:4603038
4745246 | 10 tiende verdieping | Model Group:NLRS_21.21_wand ihwg as L.P 06-20_gen:4604038
4745250 | 10 tiende verdieping | Model Group:NLRS_21.21_wand ihwg as L.P 06-20_gen:4604106
4745254 | 12 twaalfde verdieping | Model Group:NLRS_21.21_wand ihwg as L.P 06-20_gen:4608046
4745258 | 12 twaalfde verdieping | Model Group:NLRS_21.21_wand ihwg as L.P 06-20_gen:4608114
4745270 | 13 dertiende verdieping | Model Group:NLRS_21.21_wand ihwg as L.P 06-20_gen:4609416
4745274 | 13 dertiende verdieping | Model Group:NLRS_21.21_wand ihwg as L.P 06-20_gen:4609484
4745278 | 14 veertiende verdieping | Model Group:NLRS_21.21_wand ihwg as L.P 06-20_gen:4610442
4745282 | 14 veertiende verdieping | Model Group:NLRS_21.21_wand ihwg as L.P 06-20_gen:4610510
4745286 | 15 vijftiende verdieping | Model Group:NLRS_21.21_wand ihwg as L.P 06-20_gen:4611466
4745290 | 15 vijftiende verdieping | Model Group:NLRS_21.21_wand ihwg as L.P 06-20_gen:4611534
4745294 | 16 zestiende verdieping | Model Group:NLRS_21.21_wand ihwg as L.P 06-20_gen:4612492
4745298 | 16 zestiende verdieping | Model Group:NLRS_21.21_wand ihwg as L.P 06-20_gen:4612560
4745302 | 17 zeventiende verdieping | Model Group:NLRS_21.21_wand ihwg as L.P 06-20_gen:4613516
4745306 | 17 zeventiende verdieping | Model Group:NLRS_21.21_wand ihwg as L.P 06-20_gen:4613584
4745310 | 18 achttiende verdieping | Model Group:NLRS_21.21_wand ihwg as L.P 06-20_gen:4616006
4745314 | 18 achttiende verdieping | Model Group:NLRS_21.21_wand ihwg as L.P 06-20_gen:4616074
4745326 | 19 negentiende verdieping | Model Group:NLRS_21.21_wand ihwg as L.P 06-20_gen:4617493
4745330 | 19 negentiende verdieping | Model Group:NLRS_21.21_wand ihwg as L.P 06-20_gen:4617561
4745334 | 20 twintigste verdieping | Model Group:NLRS_21.21_wand ihwg as L.P 06-20_gen:4618590
4745338 | 20 twintigste verdieping | Model Group:NLRS_21.21_wand ihwg as L.P 06-20_gen:4618658
4745358 | 11 elfde verdieping | Model Group:NLRS_21.21_wand ihwg as L.P 06-20_gen:4625959
4745362 | 11 elfde verdieping | Model Group:NLRS_21.21_wand ihwg as L.P 06-20_gen:4626027
4847173 | 04 vierde verdieping | Model Group:NLRS_01.00_verdieping 04_gen (members excluded):4844403
4847175 | 04 vierde verdieping | Model Group:NLRS_01.00_verdieping 04_gen (members excluded):4844403
4847177 | 06 zesde verdieping | Model Group:NLRS_21.21_wand ihwg as L.P 06-20_gen:4844406
4847179 | 06 zesde verdieping | Model Group:NLRS_21.21_wand ihwg as L.P 06-20_gen:4844438
4847181 | 07 zevende verdieping | Model Group:NLRS_21.21_wand ihwg as L.P 06-20_gen:4844481
4847183 | 07 zevende verdieping | Model Group:NLRS_21.21_wand ihwg as L.P 06-20_gen:4844513
4847185 | 08 achtste verdieping | Model Group:NLRS_21.21_wand ihwg as L.P 06-20_gen:4844556
4847187 | 08 achtste verdieping | Model Group:NLRS_21.21_wand ihwg as L.P 06-20_gen:4844588
4847189 | 09 negende verdieping | Model Group:NLRS_21.21_wand ihwg as L.P 06-20_gen:4844631
4847191 | 09 negende verdieping | Model Group:NLRS_21.21_wand ihwg as L.P 06-20_gen:4844663
4847193 | 10 tiende verdieping | Model Group:NLRS_21.21_wand ihwg as L.P 06-20_gen:4844706
4847195 | 10 tiende verdieping | Model Group:NLRS_21.21_wand ihwg as L.P 06-20_gen:4844738
4847197 | 12 twaalfde verdieping | Model Group:NLRS_21.21_wand ihwg as L.P 06-20_gen:4844853
4847199 | 12 twaalfde verdieping | Model Group:NLRS_21.21_wand ihwg as L.P 06-20_gen:4844885
4847201 | 13 dertiende verdieping | Model Group:NLRS_21.21_wand ihwg as L.P 06-20_gen:4844922
4847203 | 13 dertiende verdieping | Model Group:NLRS_21.21_wand ihwg as L.P 06-20_gen:4844954
4847205 | 14 veertiende verdieping | Model Group:NLRS_21.21_wand ihwg as L.P 06-20_gen:4844991
4847207 | 14 veertiende verdieping | Model Group:NLRS_21.21_wand ihwg as L.P 06-20_gen:4845023
4847209 | 15 vijftiende verdieping | Model Group:NLRS_21.21_wand ihwg as L.P 06-20_gen:4845060
4847211 | 15 vijftiende verdieping | Model Group:NLRS_21.21_wand ihwg as L.P 06-20_gen:4845092
4847213 | 16 zestiende verdieping | Model Group:NLRS_21.21_wand ihwg as L.P 06-20_gen:4845129
4847215 | 16 zestiende verdieping | Model Group:NLRS_21.21_wand ihwg as L.P 06-20_gen:4845161
4847217 | 17 zeventiende verdieping | Model Group:NLRS_21.21_wand ihwg as L.P 06-20_gen:4845198
4847219 | 17 zeventiende verdieping | Model Group:NLRS_21.21_wand ihwg as L.P 06-20_gen:4845230
4847221 | 18 achttiende verdieping | Model Group:NLRS_21.21_wand ihwg as L.P 06-20_gen:4845339
4847223 | 18 achttiende verdieping | Model Group:NLRS_21.21_wand ihwg as L.P 06-20_gen:4845371
4847225 | 19 negentiende verdieping | Model Group:NLRS_21.21_wand ihwg as L.P 06-20_gen:4845408
4847227 | 19 negentiende verdieping | Model Group:NLRS_21.21_wand ihwg as L.P 06-20_gen:4845440
4847229 | 20 twintigste verdieping | Model Group:NLRS_21.21_wand ihwg as L.P 06-20_gen:4845549
4847231 | 20 twintigste verdieping | Model Group:NLRS_21.21_wand ihwg as L.P 06-20_gen:4845581
4847233 | 05 vijfde verdieping | Model Group:NLRS_21.21_wand ihwg as L.P 06-20_gen:4845680
4847235 | 05 vijfde verdieping | Model Group:NLRS_21.21_wand ihwg as L.P 06-20_gen:4845712
4847237 | 11 elfde verdieping | Model Group:NLRS_21.21_wand ihwg as L.P 06-20_gen:4845755
4847239 | 11 elfde verdieping | Model Group:NLRS_21.21_wand ihwg as L.P 06-20_gen:4845787
4907961 | 04 vierde verdieping | Model Group:NLRS_01.00_dakopbouw 01_gen:4907974
4908061 | 04 vierde verdieping | Model Group:NLRS_01.00_dakopbouw 01_gen:4908074
4908131 | 04 vierde verdieping | Model Group:NLRS_01.00_dakopbouw 01_gen:4908144
4908205 | 04 vierde verdieping
5015000 | 02b tweede tussenverdieping
5015002 | 03 derde verdieping
5096675 | 21 eenentwintigste verdieping | Model Group:NLRS_01.00_verdieping 21--23_gen (members excluded):4846692
5097815 | 21 eenentwintigste verdieping | Model Group:NLRS_01.00_verdieping 21--23_gen (members excluded):4647240
5104569 | 21 eenentwintigste verdieping | Model Group:NLRS_01.00_verdieping 21--23_gen (members excluded):4846692
5105304 | 21 eenentwintigste verdieping | Model Group:NLRS_01.00_verdieping 21--23_gen (members excluded):4647240
5111924 | 22 tweeëntwintigste verdieping | Model Group:NLRS_01.00_verdieping 21--23_gen (members excluded):4846692
5115240 | 22 tweeëntwintigste verdieping | Model Group:NLRS_01.00_verdieping 21--23_gen (members excluded):4846692
5118776 | 22 tweeëntwintigste verdieping | Model Group:NLRS_01.00_verdieping 21--23_gen (members excluded):4647240
5118785 | 22 tweeëntwintigste verdieping | Model Group:NLRS_01.00_verdieping 21--23_gen (members excluded):4647240
6698110 | 05 vijfde verdieping | Model Group:NLRS_21.21_wand ihwg as L.P 06-20_gen:6698038
6698112 | 05 vijfde verdieping | Model Group:NLRS_21.21_wand ihwg as L.P 06-20_gen:6698070
12256831 | 20 twintigste verdieping | Model Group:NLRS_01.00_verdieping 20_gen:4845671
12257136 | 18 achttiende verdieping | Model Group:NLRS_01.00_verdieping 18-19_gen:4845405
12257434 | 20 twintigste verdieping | Model Group:NLRS_01.00_verdieping 20_gen:4622361
12258122 | 18 achttiende verdieping | Model Group:NLRS_01.00_verdieping 18-19_gen:4617185
12258130 | 19 negentiende verdieping | Model Group:NLRS_01.00_verdieping 18-19_gen:4617669
12258142 | 19 negentiende verdieping | Model Group:NLRS_01.00_verdieping 18-19_gen:4845546
12258328 | 11 elfde verdieping | Model Group:NLRS_01.00_verdieping 11--17_gen:4845821
12258519 | 12 twaalfde verdieping | Model Group:NLRS_01.00_verdieping 11--17_gen:4609129
12258525 | 13 dertiende verdieping | Model Group:NLRS_01.00_verdieping 11--17_gen:4609592
12258528 | 14 veertiende verdieping | Model Group:NLRS_01.00_verdieping 11--17_gen:4610618
12258531 | 15 vijftiende verdieping | Model Group:NLRS_01.00_verdieping 11--17_gen:4611642
12258534 | 16 zestiende verdieping | Model Group:NLRS_01.00_verdieping 11--17_gen:4612668
12258537 | 17 zeventiende verdieping | Model Group:NLRS_01.00_verdieping 11--17_gen:4613692
12258540 | 11 elfde verdieping | Model Group:NLRS_01.00_verdieping 11--17_gen:4626135
12258564 | 12 twaalfde verdieping | Model Group:NLRS_01.00_verdieping 11--17_gen:4844919
12258567 | 13 dertiende verdieping | Model Group:NLRS_01.00_verdieping 11--17_gen:4844988
12258570 | 14 veertiende verdieping | Model Group:NLRS_01.00_verdieping 11--17_gen:4845057
12258573 | 15 vijftiende verdieping | Model Group:NLRS_01.00_verdieping 11--17_gen:4845126
12258576 | 16 zestiende verdieping | Model Group:NLRS_01.00_verdieping 11--17_gen:4845195
12258579 | 17 zeventiende verdieping | Model Group:NLRS_01.00_verdieping 11--17_gen:4845336
12259458 | 20 twintigste verdieping | Model Group:NLRS_01.00_verdieping 20_gen:4845671
12259537 | 20 twintigste verdieping | Model Group:NLRS_01.00_verdieping 20_gen:4622361
12259598 | 10 tiende verdieping | Model Group:NLRS_01.00_verdieping 06--10_gen:4844850
12260066 | 06 zesde verdieping | Model Group:NLRS_01.00_verdieping 06--10_gen:4600460
12260072 | 07 zevende verdieping | Model Group:NLRS_01.00_verdieping 06--10_gen:4600975
12260075 | 08 achtste verdieping | Model Group:NLRS_01.00_verdieping 06--10_gen:4602043
12260078 | 09 negende verdieping | Model Group:NLRS_01.00_verdieping 06--10_gen:4603152
12260081 | 10 tiende verdieping | Model Group:NLRS_01.00_verdieping 06--10_gen:4604220
12260099 | 06 zesde verdieping | Model Group:NLRS_01.00_verdieping 06--10_gen:4844478
12260102 | 07 zevende verdieping | Model Group:NLRS_01.00_verdieping 06--10_gen:4844553
12260105 | 08 achtste verdieping | Model Group:NLRS_01.00_verdieping 06--10_gen:4844628
12260108 | 09 negende verdieping | Model Group:NLRS_01.00_verdieping 06--10_gen:4844703
12269200 | 06 zesde verdieping | Model Group:NLRS_01.00_verdieping 06--10_gen:4844478
12269210 | 21 eenentwintigste verdieping | Model Group:NLRS_01.00_verdieping 21--23_gen (members excluded):4846692
12269220 | 06 zesde verdieping | Model Group:NLRS_01.00_verdieping 06--10_gen:4600460
12269224 | 07 zevende verdieping | Model Group:NLRS_01.00_verdieping 06--10_gen:4600975
12269226 | 08 achtste verdieping | Model Group:NLRS_01.00_verdieping 06--10_gen:4602043
12269228 | 09 negende verdieping | Model Group:NLRS_01.00_verdieping 06--10_gen:4603152
12269230 | 10 tiende verdieping | Model Group:NLRS_01.00_verdieping 06--10_gen:4604220
12269247 | 07 zevende verdieping | Model Group:NLRS_01.00_verdieping 06--10_gen:4844553
12269249 | 08 achtste verdieping | Model Group:NLRS_01.00_verdieping 06--10_gen:4844628
12269251 | 09 negende verdieping | Model Group:NLRS_01.00_verdieping 06--10_gen:4844703
12269253 | 10 tiende verdieping | Model Group:NLRS_01.00_verdieping 06--10_gen:4844850
12269291 | 11 elfde verdieping | Model Group:NLRS_01.00_verdieping 11--17_gen:4845821
12269377 | 12 twaalfde verdieping | Model Group:NLRS_01.00_verdieping 11--17_gen:4609129
12269383 | 13 dertiende verdieping | Model Group:NLRS_01.00_verdieping 11--17_gen:4609592
12269386 | 14 veertiende verdieping | Model Group:NLRS_01.00_verdieping 11--17_gen:4610618
12269389 | 15 vijftiende verdieping | Model Group:NLRS_01.00_verdieping 11--17_gen:4611642
12269392 | 16 zestiende verdieping | Model Group:NLRS_01.00_verdieping 11--17_gen:4612668
12269395 | 17 zeventiende verdieping | Model Group:NLRS_01.00_verdieping 11--17_gen:4613692
12269398 | 11 elfde verdieping | Model Group:NLRS_01.00_verdieping 11--17_gen:4626135
12269422 | 12 twaalfde verdieping | Model Group:NLRS_01.00_verdieping 11--17_gen:4844919
12269425 | 13 dertiende verdieping | Model Group:NLRS_01.00_verdieping 11--17_gen:4844988
12269428 | 14 veertiende verdieping | Model Group:NLRS_01.00_verdieping 11--17_gen:4845057
12269431 | 15 vijftiende verdieping | Model Group:NLRS_01.00_verdieping 11--17_gen:4845126
12269434 | 16 zestiende verdieping | Model Group:NLRS_01.00_verdieping 11--17_gen:4845195
12269437 | 17 zeventiende verdieping | Model Group:NLRS_01.00_verdieping 11--17_gen:4845336
12269532 | 18 achttiende verdieping | Model Group:NLRS_01.00_verdieping 18-19_gen:4845405
12269669 | 18 achttiende verdieping | Model Group:NLRS_01.00_verdieping 18-19_gen:4617185
12269675 | 19 negentiende verdieping | Model Group:NLRS_01.00_verdieping 18-19_gen:4617669
12269684 | 19 negentiende verdieping | Model Group:NLRS_01.00_verdieping 18-19_gen:4845546
12269843 | 20 twintigste verdieping | Model Group:NLRS_01.00_verdieping 20_gen:4845671
12269926 | 20 twintigste verdieping | Model Group:NLRS_01.00_verdieping 20_gen:4622361
12269974 | 21 eenentwintigste verdieping | Model Group:NLRS_01.00_verdieping 21--23_gen (members excluded):4647240
13428250 | 00 begane grond

# IfcWallStandardCase: Basic Wall:NLRS_21.21_WA_beton ihwg d=410_gen (4)
Type - PredefinedType: STANDARD; Material: NLRS_f2_beton ihwg 410 mm
Classification: 21.21 buitenwanden - constructief, massieve wanden (Uniformat)
Pset_WallCommon - LoadBearing: yes; ExtendToStructure: no; IsExternal: yes; Reference: NLRS_21.21_WA_beton ihwg d=410_gen; ThermalTransmittance: 2.55122 kg/K/s3
Name (Basic Wall:NLRS_21.21_WA_beton ihwg d=410_gen:...) | In | Group
4574306 | 04 vierde verdieping | Model Group:NLRS_01.00_verdieping 04_gen (members excluded):4585793
4574514 | 05 vijfde verdieping | Model Group:NLRS_01.00_verdieping 04_gen (members excluded):4585793
4844289 | 04 vierde verdieping | Model Group:NLRS_01.00_verdieping 04_gen (members excluded):4844403
4844291 | 05 vijfde verdieping | Model Group:NLRS_01.00_verdieping 04_gen (members excluded):4844403

# IfcWallStandardCase: Basic Wall:NLRS_21.21_WA_beton prefab d=200_gen (49)
Type - PredefinedType: STANDARD; Material: NLRS_f2_beton prefab 200 mm
Classification: 21.21 buitenwanden - constructief, massieve wanden (Uniformat)
Pset_WallCommon - LoadBearing: yes; ExtendToStructure: no; IsExternal: yes; Reference: NLRS_21.21_WA_beton prefab d=200_gen; ThermalTransmittance: 5.23 kg/K/s3
Name (Basic Wall:NLRS_21.21_WA_beton prefab d=200_gen:...) | In | Group
4222705 | 00 begane grond
4231471 | 00 begane grond
4291020 | 01 eerste verdieping
4293523 | 02 tweede verdieping
4294763 | 03 derde verdieping
4295345 | 03 derde verdieping
4296181 | 03 derde verdieping
4296283 | 03 derde verdieping
4407357 | 01 eerste verdieping
4407509 | 02 tweede verdieping
4407683 | 01 eerste verdieping
4407748 | 02 tweede verdieping
4549220 | 03 derde verdieping
4578992 | 04 vierde verdieping | Model Group:NLRS_01.00_verdieping 04_gen (members excluded):4585793
4599156 | 06 zesde verdieping | Model Group:NLRS_01.00_verdieping 06--10_gen:4600460
4600893 | 07 zevende verdieping | Model Group:NLRS_01.00_verdieping 06--10_gen:4600975
4601961 | 08 achtste verdieping | Model Group:NLRS_01.00_verdieping 06--10_gen:4602043
4603070 | 09 negende verdieping | Model Group:NLRS_01.00_verdieping 06--10_gen:4603152
4604138 | 10 tiende verdieping | Model Group:NLRS_01.00_verdieping 06--10_gen:4604220
4608140 | 12 twaalfde verdieping | Model Group:NLRS_01.00_verdieping 11--17_gen:4609129
4609510 | 13 dertiende verdieping | Model Group:NLRS_01.00_verdieping 11--17_gen:4609592
4610536 | 14 veertiende verdieping | Model Group:NLRS_01.00_verdieping 11--17_gen:4610618
4611560 | 15 vijftiende verdieping | Model Group:NLRS_01.00_verdieping 11--17_gen:4611642
4612586 | 16 zestiende verdieping | Model Group:NLRS_01.00_verdieping 11--17_gen:4612668
4613610 | 17 zeventiende verdieping | Model Group:NLRS_01.00_verdieping 11--17_gen:4613692
4616100 | 18 achttiende verdieping | Model Group:NLRS_01.00_verdieping 18-19_gen:4617185
4617587 | 19 negentiende verdieping | Model Group:NLRS_01.00_verdieping 18-19_gen:4617669
4618684 | 20 twintigste verdieping | Model Group:NLRS_01.00_verdieping 20_gen:4622361
4621135 | 21 eenentwintigste verdieping | Model Group:NLRS_01.00_verdieping 21--23_gen (members excluded):4647240
4626053 | 11 elfde verdieping | Model Group:NLRS_01.00_verdieping 11--17_gen:4626135
4844329 | 04 vierde verdieping | Model Group:NLRS_01.00_verdieping 04_gen (members excluded):4844403
4844470 | 06 zesde verdieping | Model Group:NLRS_01.00_verdieping 06--10_gen:4844478
4844545 | 07 zevende verdieping | Model Group:NLRS_01.00_verdieping 06--10_gen:4844553
4844620 | 08 achtste verdieping | Model Group:NLRS_01.00_verdieping 06--10_gen:4844628
4844695 | 09 negende verdieping | Model Group:NLRS_01.00_verdieping 06--10_gen:4844703
4844770 | 10 tiende verdieping | Model Group:NLRS_01.00_verdieping 06--10_gen:4844850
4844911 | 12 twaalfde verdieping | Model Group:NLRS_01.00_verdieping 11--17_gen:4844919
4844980 | 13 dertiende verdieping | Model Group:NLRS_01.00_verdieping 11--17_gen:4844988
4845049 | 14 veertiende verdieping | Model Group:NLRS_01.00_verdieping 11--17_gen:4845057
4845118 | 15 vijftiende verdieping | Model Group:NLRS_01.00_verdieping 11--17_gen:4845126
4845187 | 16 zestiende verdieping | Model Group:NLRS_01.00_verdieping 11--17_gen:4845195
4845256 | 17 zeventiende verdieping | Model Group:NLRS_01.00_verdieping 11--17_gen:4845336
4845397 | 18 achttiende verdieping | Model Group:NLRS_01.00_verdieping 18-19_gen:4845405
4845466 | 19 negentiende verdieping | Model Group:NLRS_01.00_verdieping 18-19_gen:4845546
4845604 | 20 twintigste verdieping | Model Group:NLRS_01.00_verdieping 20_gen:4845671
4845666 | 21 eenentwintigste verdieping | Model Group:NLRS_01.00_verdieping 21--23_gen (members excluded):4846692
4845744 | 05 vijfde verdieping | Model Group:NLRS_01.00_verdieping 05_gen:6691052
4845813 | 11 elfde verdieping | Model Group:NLRS_01.00_verdieping 11--17_gen:4845821
6698102 | 05 vijfde verdieping | Model Group:NLRS_01.00_verdieping 05_gen (members excluded):6698157

# IfcWallStandardCase: Basic Wall:NLRS_21.21_WA_beton prefab d=250_gen (217)
Type - PredefinedType: STANDARD; Material: NLRS_f2_beton prefab 250 mm
Classification: 21.21 buitenwanden - constructief, massieve wanden (Uniformat)
Pset_WallCommon - LoadBearing: yes; ExtendToStructure: no; Reference: NLRS_21.21_WA_beton prefab d=250_gen; IsExternal: yes; ThermalTransmittance: 4.184 kg/K/s3
Name (Basic Wall:NLRS_21.21_WA_beton prefab d=250_gen:...) | In | Group
4222507 | 00 begane grond
4223142 | 00 begane grond
4223238 | 00 begane grond
4223371 | 00 begane grond
4227569 | 00 begane grond
4227594 | 00 begane grond
4227598 | 00 begane grond
4227922 | 00 begane grond
4237175 | 00 begane grond
4296753 | 00 begane grond
4299056 | 01 eerste verdieping
4299065 | 01 eerste verdieping
4299069 | 01 eerste verdieping
4299799 | 02 tweede verdieping
4299801 | 02 tweede verdieping
4299885 | 03 derde verdieping
4299887 | 03 derde verdieping
4323393 | 01 eerste verdieping
4323395 | 01 eerste verdieping
4323397 | 01 eerste verdieping
4339338 | 02 tweede verdieping
4339340 | 02 tweede verdieping
4339344 | 02 tweede verdieping
4342962 | 03 derde verdieping
4342964 | 03 derde verdieping
4342968 | 03 derde verdieping
4406463 | 01 eerste verdieping
4406601 | 01 eerste verdieping
4406766 | 01 eerste verdieping
4406793 | 02 tweede verdieping
4406820 | 03 derde verdieping
4406864 | 01 eerste verdieping
4406903 | 02 tweede verdieping
4406943 | 03 derde verdieping
4406984 | 01 eerste verdieping
4407109 | 02 tweede verdieping
4407185 | 03 derde verdieping
4538003 | 00 begane grond
4539723 | 03 derde verdieping
4541086 | 02 tweede verdieping
4560305 | 04 vierde verdieping
4560506 | 04 vierde verdieping
4560774 | 04 vierde verdieping
4560873 | 04 vierde verdieping
4572448 | 04 vierde verdieping | Model Group:NLRS_01.00_verdieping 04_gen (members excluded):4585793
4573377 | 04 vierde verdieping | Model Group:NLRS_01.00_verdieping 04_gen (members excluded):4585793
4573563 | 04 vierde verdieping | Model Group:NLRS_01.00_verdieping 04_gen (members excluded):4585793
4599064 | 06 zesde verdieping | Model Group:NLRS_01.00_verdieping 06--10_gen:4600460
4599069 | 06 zesde verdieping | Model Group:NLRS_01.00_verdieping 06--10_gen:4600460
4599074 | 06 zesde verdieping | Model Group:NLRS_01.00_verdieping 06--10_gen:4600460
4599084 | 07 zevende verdieping | Model Group:NLRS_01.00_verdieping 06--10_gen:4600460
4600801 | 07 zevende verdieping | Model Group:NLRS_01.00_verdieping 06--10_gen:4600975
4600806 | 07 zevende verdieping | Model Group:NLRS_01.00_verdieping 06--10_gen:4600975
4600811 | 07 zevende verdieping | Model Group:NLRS_01.00_verdieping 06--10_gen:4600975
4600821 | 08 achtste verdieping | Model Group:NLRS_01.00_verdieping 06--10_gen:4600975
4601869 | 08 achtste verdieping | Model Group:NLRS_01.00_verdieping 06--10_gen:4602043
4601874 | 08 achtste verdieping | Model Group:NLRS_01.00_verdieping 06--10_gen:4602043
4601879 | 08 achtste verdieping | Model Group:NLRS_01.00_verdieping 06--10_gen:4602043
4601889 | 09 negende verdieping | Model Group:NLRS_01.00_verdieping 06--10_gen:4602043
4602978 | 09 negende verdieping | Model Group:NLRS_01.00_verdieping 06--10_gen:4603152
4602983 | 09 negende verdieping | Model Group:NLRS_01.00_verdieping 06--10_gen:4603152
4602988 | 09 negende verdieping | Model Group:NLRS_01.00_verdieping 06--10_gen:4603152
4602998 | 10 tiende verdieping | Model Group:NLRS_01.00_verdieping 06--10_gen:4603152
4604046 | 10 tiende verdieping | Model Group:NLRS_01.00_verdieping 06--10_gen:4604220
4604051 | 10 tiende verdieping | Model Group:NLRS_01.00_verdieping 06--10_gen:4604220
4604056 | 10 tiende verdieping | Model Group:NLRS_01.00_verdieping 06--10_gen:4604220
4604066 | 11 elfde verdieping | Model Group:NLRS_01.00_verdieping 06--10_gen:4604220
4608054 | 12 twaalfde verdieping | Model Group:NLRS_01.00_verdieping 11--17_gen:4609129
4608059 | 12 twaalfde verdieping | Model Group:NLRS_01.00_verdieping 11--17_gen:4609129
4608064 | 12 twaalfde verdieping | Model Group:NLRS_01.00_verdieping 11--17_gen:4609129
4608074 | 12 twaalfde verdieping | Model Group:NLRS_01.00_verdieping 11--17_gen:4609129
4609424 | 13 dertiende verdieping | Model Group:NLRS_01.00_verdieping 11--17_gen:4609592
4609429 | 13 dertiende verdieping | Model Group:NLRS_01.00_verdieping 11--17_gen:4609592
4609434 | 13 dertiende verdieping | Model Group:NLRS_01.00_verdieping 11--17_gen:4609592
4609444 | 13 dertiende verdieping | Model Group:NLRS_01.00_verdieping 11--17_gen:4609592
4610450 | 14 veertiende verdieping | Model Group:NLRS_01.00_verdieping 11--17_gen:4610618
4610455 | 14 veertiende verdieping | Model Group:NLRS_01.00_verdieping 11--17_gen:4610618
4610460 | 14 veertiende verdieping | Model Group:NLRS_01.00_verdieping 11--17_gen:4610618
4610470 | 14 veertiende verdieping | Model Group:NLRS_01.00_verdieping 11--17_gen:4610618
4611474 | 15 vijftiende verdieping | Model Group:NLRS_01.00_verdieping 11--17_gen:4611642
4611479 | 15 vijftiende verdieping | Model Group:NLRS_01.00_verdieping 11--17_gen:4611642
4611484 | 15 vijftiende verdieping | Model Group:NLRS_01.00_verdieping 11--17_gen:4611642
4611494 | 15 vijftiende verdieping | Model Group:NLRS_01.00_verdieping 11--17_gen:4611642
4612500 | 16 zestiende verdieping | Model Group:NLRS_01.00_verdieping 11--17_gen:4612668
4612505 | 16 zestiende verdieping | Model Group:NLRS_01.00_verdieping 11--17_gen:4612668
4612510 | 16 zestiende verdieping | Model Group:NLRS_01.00_verdieping 11--17_gen:4612668
4612520 | 16 zestiende verdieping | Model Group:NLRS_01.00_verdieping 11--17_gen:4612668
4613524 | 17 zeventiende verdieping | Model Group:NLRS_01.00_verdieping 11--17_gen:4613692
4613529 | 17 zeventiende verdieping | Model Group:NLRS_01.00_verdieping 11--17_gen:4613692
4613534 | 17 zeventiende verdieping | Model Group:NLRS_01.00_verdieping 11--17_gen:4613692
4613544 | 17 zeventiende verdieping | Model Group:NLRS_01.00_verdieping 11--17_gen:4613692
4616014 | 18 achttiende verdieping | Model Group:NLRS_01.00_verdieping 18-19_gen:4617185
4616019 | 18 achttiende verdieping | Model Group:NLRS_01.00_verdieping 18-19_gen:4617185
4616024 | 18 achttiende verdieping | Model Group:NLRS_01.00_verdieping 18-19_gen:4617185
4616034 | 18 achttiende verdieping | Model Group:NLRS_01.00_verdieping 18-19_gen:4617185
4617501 | 19 negentiende verdieping | Model Group:NLRS_01.00_verdieping 18-19_gen:4617669
4617506 | 19 negentiende verdieping | Model Group:NLRS_01.00_verdieping 18-19_gen:4617669
4617511 | 19 negentiende verdieping | Model Group:NLRS_01.00_verdieping 18-19_gen:4617669
4617521 | 19 negentiende verdieping | Model Group:NLRS_01.00_verdieping 18-19_gen:4617669
4618598 | 20 twintigste verdieping | Model Group:NLRS_01.00_verdieping 20_gen:4622361
4618603 | 20 twintigste verdieping | Model Group:NLRS_01.00_verdieping 20_gen:4622361
4618608 | 20 twintigste verdieping | Model Group:NLRS_01.00_verdieping 20_gen:4622361
4618618 | 20 twintigste verdieping | Model Group:NLRS_01.00_verdieping 20_gen:4622361
4625967 | 11 elfde verdieping | Model Group:NLRS_01.00_verdieping 11--17_gen:4626135
4625972 | 11 elfde verdieping | Model Group:NLRS_01.00_verdieping 11--17_gen:4626135
4625977 | 11 elfde verdieping | Model Group:NLRS_01.00_verdieping 11--17_gen:4626135
4625987 | 11 elfde verdieping | Model Group:NLRS_01.00_verdieping 11--17_gen:4626135
4722320 | 00 begane grond
4722639 | 01 eerste verdieping
4723040 | 00 begane grond
4723195 | 01 eerste verdieping
4723596 | 02 tweede verdieping
4844269 | 04 vierde verdieping | Model Group:NLRS_01.00_verdieping 04_gen (members excluded):4844403
4844274 | 04 vierde verdieping | Model Group:NLRS_01.00_verdieping 04_gen (members excluded):4844403
4844279 | 04 vierde verdieping | Model Group:NLRS_01.00_verdieping 04_gen (members excluded):4844403
4844414 | 06 zesde verdieping | Model Group:NLRS_01.00_verdieping 06--10_gen:4844478
4844419 | 06 zesde verdieping | Model Group:NLRS_01.00_verdieping 06--10_gen:4844478
4844424 | 06 zesde verdieping | Model Group:NLRS_01.00_verdieping 06--10_gen:4844478
4844434 | 07 zevende verdieping | Model Group:NLRS_01.00_verdieping 06--10_gen:4844478
4844489 | 07 zevende verdieping | Model Group:NLRS_01.00_verdieping 06--10_gen:4844553
4844494 | 07 zevende verdieping | Model Group:NLRS_01.00_verdieping 06--10_gen:4844553
4844499 | 07 zevende verdieping | Model Group:NLRS_01.00_verdieping 06--10_gen:4844553
4844509 | 08 achtste verdieping | Model Group:NLRS_01.00_verdieping 06--10_gen:4844553
4844564 | 08 achtste verdieping | Model Group:NLRS_01.00_verdieping 06--10_gen:4844628
4844569 | 08 achtste verdieping | Model Group:NLRS_01.00_verdieping 06--10_gen:4844628
4844574 | 08 achtste verdieping | Model Group:NLRS_01.00_verdieping 06--10_gen:4844628
4844584 | 09 negende verdieping | Model Group:NLRS_01.00_verdieping 06--10_gen:4844628
4844639 | 09 negende verdieping | Model Group:NLRS_01.00_verdieping 06--10_gen:4844703
4844644 | 09 negende verdieping | Model Group:NLRS_01.00_verdieping 06--10_gen:4844703
4844649 | 09 negende verdieping | Model Group:NLRS_01.00_verdieping 06--10_gen:4844703
4844659 | 10 tiende verdieping | Model Group:NLRS_01.00_verdieping 06--10_gen:4844703
4844714 | 10 tiende verdieping | Model Group:NLRS_01.00_verdieping 06--10_gen:4844850
4844719 | 10 tiende verdieping | Model Group:NLRS_01.00_verdieping 06--10_gen:4844850
4844724 | 10 tiende verdieping | Model Group:NLRS_01.00_verdieping 06--10_gen:4844850
4844734 | 11 elfde verdieping | Model Group:NLRS_01.00_verdieping 06--10_gen:4844850
4844861 | 12 twaalfde verdieping | Model Group:NLRS_01.00_verdieping 11--17_gen:4844919
4844866 | 12 twaalfde verdieping | Model Group:NLRS_01.00_verdieping 11--17_gen:4844919
4844871 | 12 twaalfde verdieping | Model Group:NLRS_01.00_verdieping 11--17_gen:4844919
4844881 | 12 twaalfde verdieping | Model Group:NLRS_01.00_verdieping 11--17_gen:4844919
4844930 | 13 dertiende verdieping | Model Group:NLRS_01.00_verdieping 11--17_gen:4844988
4844935 | 13 dertiende verdieping | Model Group:NLRS_01.00_verdieping 11--17_gen:4844988
4844940 | 13 dertiende verdieping | Model Group:NLRS_01.00_verdieping 11--17_gen:4844988
4844950 | 13 dertiende verdieping | Model Group:NLRS_01.00_verdieping 11--17_gen:4844988
4844999 | 14 veertiende verdieping | Model Group:NLRS_01.00_verdieping 11--17_gen:4845057
4845004 | 14 veertiende verdieping | Model Group:NLRS_01.00_verdieping 11--17_gen:4845057
4845009 | 14 veertiende verdieping | Model Group:NLRS_01.00_verdieping 11--17_gen:4845057
4845019 | 14 veertiende verdieping | Model Group:NLRS_01.00_verdieping 11--17_gen:4845057
4845068 | 15 vijftiende verdieping | Model Group:NLRS_01.00_verdieping 11--17_gen:4845126
4845073 | 15 vijftiende verdieping | Model Group:NLRS_01.00_verdieping 11--17_gen:4845126
4845078 | 15 vijftiende verdieping | Model Group:NLRS_01.00_verdieping 11--17_gen:4845126
4845088 | 15 vijftiende verdieping | Model Group:NLRS_01.00_verdieping 11--17_gen:4845126
4845137 | 16 zestiende verdieping | Model Group:NLRS_01.00_verdieping 11--17_gen:4845195
4845142 | 16 zestiende verdieping | Model Group:NLRS_01.00_verdieping 11--17_gen:4845195
4845147 | 16 zestiende verdieping | Model Group:NLRS_01.00_verdieping 11--17_gen:4845195
4845157 | 16 zestiende verdieping | Model Group:NLRS_01.00_verdieping 11--17_gen:4845195
4845206 | 17 zeventiende verdieping | Model Group:NLRS_01.00_verdieping 11--17_gen:4845336
4845211 | 17 zeventiende verdieping | Model Group:NLRS_01.00_verdieping 11--17_gen:4845336
4845216 | 17 zeventiende verdieping | Model Group:NLRS_01.00_verdieping 11--17_gen:4845336
4845226 | 17 zeventiende verdieping | Model Group:NLRS_01.00_verdieping 11--17_gen:4845336
4845347 | 18 achttiende verdieping | Model Group:NLRS_01.00_verdieping 18-19_gen:4845405
4845352 | 18 achttiende verdieping | Model Group:NLRS_01.00_verdieping 18-19_gen:4845405
4845357 | 18 achttiende verdieping | Model Group:NLRS_01.00_verdieping 18-19_gen:4845405
4845367 | 18 achttiende verdieping | Model Group:NLRS_01.00_verdieping 18-19_gen:4845405
4845416 | 19 negentiende verdieping | Model Group:NLRS_01.00_verdieping 18-19_gen:4845546
4845421 | 19 negentiende verdieping | Model Group:NLRS_01.00_verdieping 18-19_gen:4845546
4845426 | 19 negentiende verdieping | Model Group:NLRS_01.00_verdieping 18-19_gen:4845546
4845436 | 19 negentiende verdieping | Model Group:NLRS_01.00_verdieping 18-19_gen:4845546
4845557 | 20 twintigste verdieping | Model Group:NLRS_01.00_verdieping 20_gen:4845671
4845562 | 20 twintigste verdieping | Model Group:NLRS_01.00_verdieping 20_gen:4845671
4845567 | 20 twintigste verdieping | Model Group:NLRS_01.00_verdieping 20_gen:4845671
4845577 | 20 twintigste verdieping | Model Group:NLRS_01.00_verdieping 20_gen:4845671
4845688 | 05 vijfde verdieping | Model Group:NLRS_01.00_verdieping 05_gen:6691052
4845693 | 05 vijfde verdieping | Model Group:NLRS_01.00_verdieping 05_gen:6691052
4845698 | 05 vijfde verdieping | Model Group:NLRS_01.00_verdieping 05_gen:6691052
4845708 | 06 zesde verdieping | Model Group:NLRS_01.00_verdieping 05_gen:6691052
4845763 | 11 elfde verdieping | Model Group:NLRS_01.00_verdieping 11--17_gen:4845821
4845768 | 11 elfde verdieping | Model Group:NLRS_01.00_verdieping 11--17_gen:4845821
4845773 | 11 elfde verdieping | Model Group:NLRS_01.00_verdieping 11--17_gen:4845821
4845783 | 11 elfde verdieping | Model Group:NLRS_01.00_verdieping 11--17_gen:4845821
5102033 | 21 eenentwintigste verdieping | Model Group:NLRS_01.00_verdieping 21--23_gen (members excluded):4846692
5103390 | 21 eenentwintigste verdieping | Model Group:NLRS_01.00_verdieping 21--23_gen (members excluded):4647240
5108967 | 21 eenentwintigste verdieping | Model Group:NLRS_01.00_verdieping 21--23_gen (members excluded):4846692
5109469 | 21 eenentwintigste verdieping | Model Group:NLRS_01.00_verdieping 21--23_gen (members excluded):4647240
5119108 | 22 tweeëntwintigste verdieping | Model Group:NLRS_01.00_verdieping 21--23_gen (members excluded):4846692
5119213 | 22 tweeëntwintigste verdieping | Model Group:NLRS_01.00_verdieping 21--23_gen (members excluded):4846692
5119791 | 22 tweeëntwintigste verdieping | Model Group:NLRS_01.00_verdieping 21--23_gen (members excluded):4647240
5119796 | 22 tweeëntwintigste verdieping | Model Group:NLRS_01.00_verdieping 21--23_gen (members excluded):4647240
5153926 | 00 begane grond
5707812 | 00 begane grond
5707814 | 00 begane grond
5707816 | 00a eerste tussenverdieping
5708810 | 00 begane grond
5708812 | 00 begane grond
5708814 | 00 begane grond
5708816 | 00 begane grond
5708818 | 00 begane grond
5709625 | 00a eerste tussenverdieping
5709627 | 00a eerste tussenverdieping
5709629 | 00a eerste tussenverdieping
5709631 | 00a eerste tussenverdieping
5709807 | 00a eerste tussenverdieping
5709809 | 00a eerste tussenverdieping
5711382 | 01b tweede tussenverdieping
5711432 | 01b tweede tussenverdieping
5711727 | 00a eerste tussenverdieping
5713345 | 01b tweede tussenverdieping
5713347 | 01b tweede tussenverdieping
5713349 | 01b tweede tussenverdieping
5713658 | 00a eerste tussenverdieping
5713804 | 04 vierde verdieping
5713806 | 04 vierde verdieping
6397895 | 00a eerste tussenverdieping
6398131 | 00a eerste tussenverdieping
6698046 | 05 vijfde verdieping | Model Group:NLRS_01.00_verdieping 05_gen (members excluded):6698157
6698051 | 05 vijfde verdieping | Model Group:NLRS_01.00_verdieping 05_gen (members excluded):6698157
6698056 | 05 vijfde verdieping | Model Group:NLRS_01.00_verdieping 05_gen (members excluded):6698157
6698066 | 06 zesde verdieping | Model Group:NLRS_01.00_verdieping 05_gen (members excluded):6698157

# IfcWallStandardCase: Basic Wall:NLRS_21.21_WA_beton prefab d=270_gen (68)
Type - PredefinedType: STANDARD; Material: NLRS_f2_beton prefab 270 mm
Classification: 21.21 buitenwanden - constructief, massieve wanden (Uniformat)
Pset_WallCommon - LoadBearing: yes; ExtendToStructure: no; IsExternal: yes; Reference: NLRS_21.21_WA_beton prefab d=270_gen; ThermalTransmittance: 3.87407 kg/K/s3
Name (Basic Wall:NLRS_21.21_WA_beton prefab d=270_gen:...) | In | Group
4571514 | 04 vierde verdieping | Model Group:NLRS_01.00_verdieping 04_gen (members excluded):4585793
4573694 | 04 vierde verdieping | Model Group:NLRS_01.00_verdieping 04_gen (members excluded):4585793
4599059 | 06 zesde verdieping | Model Group:NLRS_01.00_verdieping 06--10_gen:4600460
4599079 | 06 zesde verdieping | Model Group:NLRS_01.00_verdieping 06--10_gen:4600460
4600796 | 07 zevende verdieping | Model Group:NLRS_01.00_verdieping 06--10_gen:4600975
4600816 | 07 zevende verdieping | Model Group:NLRS_01.00_verdieping 06--10_gen:4600975
4601864 | 08 achtste verdieping | Model Group:NLRS_01.00_verdieping 06--10_gen:4602043
4601884 | 08 achtste verdieping | Model Group:NLRS_01.00_verdieping 06--10_gen:4602043
4602973 | 09 negende verdieping | Model Group:NLRS_01.00_verdieping 06--10_gen:4603152
4602993 | 09 negende verdieping | Model Group:NLRS_01.00_verdieping 06--10_gen:4603152
4604041 | 10 tiende verdieping | Model Group:NLRS_01.00_verdieping 06--10_gen:4604220
4604061 | 10 tiende verdieping | Model Group:NLRS_01.00_verdieping 06--10_gen:4604220
4608049 | 12 twaalfde verdieping | Model Group:NLRS_01.00_verdieping 11--17_gen:4609129
4608069 | 12 twaalfde verdieping | Model Group:NLRS_01.00_verdieping 11--17_gen:4609129
4609419 | 13 dertiende verdieping | Model Group:NLRS_01.00_verdieping 11--17_gen:4609592
4609439 | 13 dertiende verdieping | Model Group:NLRS_01.00_verdieping 11--17_gen:4609592
4610445 | 14 veertiende verdieping | Model Group:NLRS_01.00_verdieping 11--17_gen:4610618
4610465 | 14 veertiende verdieping | Model Group:NLRS_01.00_verdieping 11--17_gen:4610618
4611469 | 15 vijftiende verdieping | Model Group:NLRS_01.00_verdieping 11--17_gen:4611642
4611489 | 15 vijftiende verdieping | Model Group:NLRS_01.00_verdieping 11--17_gen:4611642
4612495 | 16 zestiende verdieping | Model Group:NLRS_01.00_verdieping 11--17_gen:4612668
4612515 | 16 zestiende verdieping | Model Group:NLRS_01.00_verdieping 11--17_gen:4612668
4613519 | 17 zeventiende verdieping | Model Group:NLRS_01.00_verdieping 11--17_gen:4613692
4613539 | 17 zeventiende verdieping | Model Group:NLRS_01.00_verdieping 11--17_gen:4613692
4616009 | 18 achttiende verdieping | Model Group:NLRS_01.00_verdieping 18-19_gen:4617185
4616029 | 18 achttiende verdieping | Model Group:NLRS_01.00_verdieping 18-19_gen:4617185
4617496 | 19 negentiende verdieping | Model Group:NLRS_01.00_verdieping 18-19_gen:4617669
4617516 | 19 negentiende verdieping | Model Group:NLRS_01.00_verdieping 18-19_gen:4617669
4618593 | 20 twintigste verdieping | Model Group:NLRS_01.00_verdieping 20_gen:4622361
4618613 | 20 twintigste verdieping | Model Group:NLRS_01.00_verdieping 20_gen:4622361
4625962 | 11 elfde verdieping | Model Group:NLRS_01.00_verdieping 11--17_gen:4626135
4625982 | 11 elfde verdieping | Model Group:NLRS_01.00_verdieping 11--17_gen:4626135
4844264 | 04 vierde verdieping | Model Group:NLRS_01.00_verdieping 04_gen (members excluded):4844403
4844284 | 04 vierde verdieping | Model Group:NLRS_01.00_verdieping 04_gen (members excluded):4844403
4844409 | 06 zesde verdieping | Model Group:NLRS_01.00_verdieping 06--10_gen:4844478
4844429 | 06 zesde verdieping | Model Group:NLRS_01.00_verdieping 06--10_gen:4844478
4844484 | 07 zevende verdieping | Model Group:NLRS_01.00_verdieping 06--10_gen:4844553
4844504 | 07 zevende verdieping | Model Group:NLRS_01.00_verdieping 06--10_gen:4844553
4844559 | 08 achtste verdieping | Model Group:NLRS_01.00_verdieping 06--10_gen:4844628
4844579 | 08 achtste verdieping | Model Group:NLRS_01.00_verdieping 06--10_gen:4844628
4844634 | 09 negende verdieping | Model Group:NLRS_01.00_verdieping 06--10_gen:4844703
4844654 | 09 negende verdieping | Model Group:NLRS_01.00_verdieping 06--10_gen:4844703
4844709 | 10 tiende verdieping | Model Group:NLRS_01.00_verdieping 06--10_gen:4844850
4844729 | 10 tiende verdieping | Model Group:NLRS_01.00_verdieping 06--10_gen:4844850
4844856 | 12 twaalfde verdieping | Model Group:NLRS_01.00_verdieping 11--17_gen:4844919
4844876 | 12 twaalfde verdieping | Model Group:NLRS_01.00_verdieping 11--17_gen:4844919
4844925 | 13 dertiende verdieping | Model Group:NLRS_01.00_verdieping 11--17_gen:4844988
4844945 | 13 dertiende verdieping | Model Group:NLRS_01.00_verdieping 11--17_gen:4844988
4844994 | 14 veertiende verdieping | Model Group:NLRS_01.00_verdieping 11--17_gen:4845057
4845014 | 14 veertiende verdieping | Model Group:NLRS_01.00_verdieping 11--17_gen:4845057
4845063 | 15 vijftiende verdieping | Model Group:NLRS_01.00_verdieping 11--17_gen:4845126
4845083 | 15 vijftiende verdieping | Model Group:NLRS_01.00_verdieping 11--17_gen:4845126
4845132 | 16 zestiende verdieping | Model Group:NLRS_01.00_verdieping 11--17_gen:4845195
4845152 | 16 zestiende verdieping | Model Group:NLRS_01.00_verdieping 11--17_gen:4845195
4845201 | 17 zeventiende verdieping | Model Group:NLRS_01.00_verdieping 11--17_gen:4845336
4845221 | 17 zeventiende verdieping | Model Group:NLRS_01.00_verdieping 11--17_gen:4845336
4845342 | 18 achttiende verdieping | Model Group:NLRS_01.00_verdieping 18-19_gen:4845405
4845362 | 18 achttiende verdieping | Model Group:NLRS_01.00_verdieping 18-19_gen:4845405
4845411 | 19 negentiende verdieping | Model Group:NLRS_01.00_verdieping 18-19_gen:4845546
4845431 | 19 negentiende verdieping | Model Group:NLRS_01.00_verdieping 18-19_gen:4845546
4845552 | 20 twintigste verdieping | Model Group:NLRS_01.00_verdieping 20_gen:4845671
4845572 | 20 twintigste verdieping | Model Group:NLRS_01.00_verdieping 20_gen:4845671
4845683 | 05 vijfde verdieping | Model Group:NLRS_01.00_verdieping 05_gen:6691052
4845703 | 05 vijfde verdieping | Model Group:NLRS_01.00_verdieping 05_gen:6691052
4845758 | 11 elfde verdieping | Model Group:NLRS_01.00_verdieping 11--17_gen:4845821
4845778 | 11 elfde verdieping | Model Group:NLRS_01.00_verdieping 11--17_gen:4845821
6698041 | 05 vijfde verdieping | Model Group:NLRS_01.00_verdieping 05_gen (members excluded):6698157
6698061 | 05 vijfde verdieping | Model Group:NLRS_01.00_verdieping 05_gen (members excluded):6698157

# IfcWallStandardCase: Basic Wall:NLRS_22.21_WA_beton ihwg d=105_gen (8)
Type - PredefinedType: STANDARD; Material: NLRS_f2_beton ihwg 105 mm
Classification: 22.21 binnenwanden - constructief, massieve wanden (Uniformat)
Pset_WallCommon - LoadBearing: yes; IsExternal: no; ExtendToStructure: no; Reference: NLRS_22.21_WA_beton ihwg d=105_gen; ThermalTransmittance: 9.9619 kg/K/s3
Name (Basic Wall:NLRS_22.21_WA_beton ihwg d=105_gen:...) | In
8706166 | 01 eerste verdieping
8787398 | 00 begane grond
8787739 | 00 begane grond
8844289 | 01 eerste verdieping
8844394 | 02 tweede verdieping
8844636 | 02 tweede verdieping
8844752 | 03 derde verdieping
8844935 | 03 derde verdieping

# IfcWallStandardCase: Basic Wall:NLRS_22.21_WA_beton ihwg d=140_gen (6)
Type - PredefinedType: STANDARD; Material: NLRS_f2_beton ihwg 140 mm
Classification: 22.21 binnenwanden - constructief, massieve wanden (Uniformat)
Pset_WallCommon - LoadBearing: yes; IsExternal: no; ExtendToStructure: no; Reference: NLRS_22.21_WA_beton ihwg d=140_gen; ThermalTransmittance: 7.47143 kg/K/s3
Name (Basic Wall:NLRS_22.21_WA_beton ihwg d=140_gen:...) | In | Group
9931656 | 04 vierde verdieping | Model Group:NLRS_01.00_mid-rise_gen:4847172
9934051 | 04 vierde verdieping | Model Group:NLRS_01.00_mid-rise_gen:4675261
11038239 | 20 twintigste verdieping | Model Group:NLRS_01.00_verdieping 20_gen:4845671
11038249 | 20 twintigste verdieping | Model Group:NLRS_01.00_verdieping 20_gen:4622361
11038276 | 20 twintigste verdieping | Model Group:NLRS_01.00_verdieping 20_gen:4845671
11038330 | 20 twintigste verdieping | Model Group:NLRS_01.00_verdieping 20_gen:4622361

# IfcWallStandardCase: Basic Wall:NLRS_22.21_WA_beton ihwg d=160_gen (16)
Type - PredefinedType: STANDARD; Material: NLRS_f2_beton ihwg 160 mm
Classification: 22.21 binnenwanden - constructief, massieve wanden (Uniformat)
Pset_WallCommon - LoadBearing: yes; IsExternal: no; ExtendToStructure: no; Reference: NLRS_22.21_WA_beton ihwg d=160_gen; ThermalTransmittance: 6.5375 kg/K/s3
Name (Basic Wall:NLRS_22.21_WA_beton ihwg d=160_gen:...) | In | Group
11039756 | 05 vijfde verdieping | Model Group:NLRS_01.00_verdieping 05_gen:6691052
11040199 | 05 vijfde verdieping | Model Group:NLRS_01.00_verdieping 05_gen (members excluded):6698157
11040548 | 06 zesde verdieping | Model Group:NLRS_01.00_verdieping 06--10_gen:4844478
11041962 | 06 zesde verdieping | Model Group:NLRS_01.00_verdieping 06--10_gen:4600460
11041970 | 07 zevende verdieping | Model Group:NLRS_01.00_verdieping 06--10_gen:4600975
11041974 | 08 achtste verdieping | Model Group:NLRS_01.00_verdieping 06--10_gen:4602043
11041978 | 09 negende verdieping | Model Group:NLRS_01.00_verdieping 06--10_gen:4603152
11041982 | 10 tiende verdieping | Model Group:NLRS_01.00_verdieping 06--10_gen:4604220
11042006 | 07 zevende verdieping | Model Group:NLRS_01.00_verdieping 06--10_gen:4844553
11042010 | 08 achtste verdieping | Model Group:NLRS_01.00_verdieping 06--10_gen:4844628
11042014 | 09 negende verdieping | Model Group:NLRS_01.00_verdieping 06--10_gen:4844703
11042018 | 10 tiende verdieping | Model Group:NLRS_01.00_verdieping 06--10_gen:4844850
11045258 | 18 achttiende verdieping | Model Group:NLRS_01.00_verdieping 18-19_gen:4845405
11045930 | 18 achttiende verdieping | Model Group:NLRS_01.00_verdieping 18-19_gen:4617185
11045938 | 19 negentiende verdieping | Model Group:NLRS_01.00_verdieping 18-19_gen:4617669
11045950 | 19 negentiende verdieping | Model Group:NLRS_01.00_verdieping 18-19_gen:4845546

# IfcWallStandardCase: Basic Wall:NLRS_22.21_WA_beton ihwg d=200_gen (4)
In: 21 eenentwintigste verdieping
Type - PredefinedType: STANDARD; Material: NLRS_f2_beton ihwg 200 mm
Classification: 22.21 binnenwanden - constructief, massieve wanden (Uniformat)
Pset_WallCommon - LoadBearing: yes; IsExternal: no; ExtendToStructure: no; Reference: NLRS_22.21_WA_beton ihwg d=200_gen; ThermalTransmittance: 5.23 kg/K/s3
Name (Basic Wall:NLRS_22.21_WA_beton ihwg d=200_gen:...) | Group
13465000 | Model Group:NLRS_01.00_verdieping 21--23_gen (members excluded):4846692
13465730 | Model Group:NLRS_01.00_verdieping 21--23_gen (members excluded):4846692
13466347 | Model Group:NLRS_01.00_verdieping 21--23_gen (members excluded):4647240
13466533 | Model Group:NLRS_01.00_verdieping 21--23_gen (members excluded):4647240

# IfcWallStandardCase: Basic Wall:NLRS_22.21_WA_beton ihwg d=250_gen (480)
Type - PredefinedType: STANDARD; Material: NLRS_f2_beton ihwg 250 mm
Classification: 22.21 binnenwanden - constructief, massieve wanden (Uniformat)
Pset_WallCommon - LoadBearing: yes; IsExternal: no; Reference: NLRS_22.21_WA_beton ihwg d=250_gen; ExtendToStructure: no; ThermalTransmittance: 4.184 kg/K/s3
Name (Basic Wall:NLRS_22.21_WA_beton ihwg d=250_gen:...) | In | Group
4221399 | 00 begane grond
4222103 | 00 begane grond
4222248 | 00 begane grond
4222310 | 00 begane grond
4223047 | 00 begane grond
4239756 | 00 begane grond
4239840 | 00 begane grond
4240043 | 00 begane grond
4240099 | 00 begane grond
4240202 | 00 begane grond
4240908 | 00 begane grond
4240983 | 00 begane grond
4241086 | 00 begane grond
4241678 | 00 begane grond
4242182 | 00 begane grond
4242755 | 00 begane grond
4243680 | 00 begane grond
4243690 | 00 begane grond
4243948 | 00 begane grond
4244499 | 00 begane grond
4244517 | 00 begane grond
4246637 | 00 begane grond
4246909 | 00 begane grond
4251977 | 00 begane grond
4255940 | 00 begane grond
4256084 | 00 begane grond
4256256 | 00 begane grond
4314950 | 01 eerste verdieping
4315295 | 01 eerste verdieping
4315339 | 01 eerste verdieping
4315632 | 01 eerste verdieping
4315671 | 01 eerste verdieping
4316318 | 01 eerste verdieping
4318057 | 00 begane grond
4318079 | 00 begane grond
4318194 | 00 begane grond
4318214 | 00 begane grond
4318234 | 00 begane grond
4318254 | 00 begane grond
4318270 | 00 begane grond
4318288 | 00 begane grond
4318306 | 00 begane grond
4318324 | 00 begane grond
4318344 | 00 begane grond
4318362 | 00 begane grond
4318382 | 00 begane grond
4319105 | 00 begane grond
4319756 | 01 eerste verdieping
4319766 | 01 eerste verdieping
4319776 | 01 eerste verdieping
4320068 | 01 eerste verdieping
4322976 | 01 eerste verdieping
4323074 | 01 eerste verdieping
4323143 | 01 eerste verdieping
4324208 | 01 eerste verdieping
4324215 | 01 eerste verdieping
4324217 | 01 eerste verdieping
4324219 | 01 eerste verdieping
4324221 | 01 eerste verdieping
4324223 | 01 eerste verdieping
4324225 | 01 eerste verdieping
4324227 | 01 eerste verdieping
4324229 | 01 eerste verdieping
4324231 | 01 eerste verdieping
4324233 | 01 eerste verdieping
4324235 | 01 eerste verdieping
4324237 | 01 eerste verdieping
4324239 | 01 eerste verdieping
4324241 | 01 eerste verdieping
4335982 | 01 eerste verdieping
4336036 | 01 eerste verdieping
4336141 | 01 eerste verdieping
4338545 | 02 tweede verdieping
4338547 | 02 tweede verdieping
4338549 | 02 tweede verdieping
4338551 | 02 tweede verdieping
4338553 | 02 tweede verdieping
4338555 | 02 tweede verdieping
4338557 | 02 tweede verdieping
4338559 | 02 tweede verdieping
4338561 | 02 tweede verdieping
4338563 | 02 tweede verdieping
4338565 | 02 tweede verdieping
4338567 | 02 tweede verdieping
4338569 | 02 tweede verdieping
4338571 | 02 tweede verdieping
4338573 | 02 tweede verdieping
4338876 | 03 derde verdieping
4338878 | 03 derde verdieping
4338880 | 03 derde verdieping
4338882 | 03 derde verdieping
4338884 | 03 derde verdieping
4338886 | 03 derde verdieping
4338888 | 03 derde verdieping
4338890 | 03 derde verdieping
4338892 | 03 derde verdieping
4338894 | 03 derde verdieping
4338896 | 03 derde verdieping
4338898 | 03 derde verdieping
4339057 | 02 tweede verdieping
4339117 | 03 derde verdieping
4339326 | 02 tweede verdieping
4339328 | 02 tweede verdieping
4339330 | 02 tweede verdieping
4339332 | 02 tweede verdieping
4339334 | 01c derde tussenverdieping
4339336 | 01c derde tussenverdieping
4339352 | 02 tweede verdieping
4339354 | 01c derde tussenverdieping
4339516 | 02 tweede verdieping
4339518 | 02 tweede verdieping
4341122 | 02 tweede verdieping
4341126 | 01c derde tussenverdieping
4341128 | 02 tweede verdieping
4341136 | 02 tweede verdieping
4342950 | 03 derde verdieping
4342952 | 03 derde verdieping
4342954 | 03 derde verdieping
4342956 | 03 derde verdieping
4342958 | 02b tweede tussenverdieping
4342960 | 02b tweede tussenverdieping
4342976 | 03 derde verdieping
4342978 | 02b tweede tussenverdieping
4342980 | 03 derde verdieping
4342982 | 03 derde verdieping
4342984 | 03 derde verdieping
4343917 | 03 derde verdieping
4343927 | 03 derde verdieping
4344512 | 02b tweede tussenverdieping
4344708 | 02b tweede tussenverdieping
4344791 | 01c derde tussenverdieping
4344988 | 01c derde tussenverdieping
4345109 | 01a eerste tussenverdieping
4345254 | 01 eerste verdieping
4545765 | 01 eerste verdieping
4545976 | 02 tweede verdieping
4546118 | 01 eerste verdieping
4546245 | 02 tweede verdieping
4546382 | 03 derde verdieping
4552016 | 03 derde verdieping
4562322 | 03 derde verdieping
4562435 | 03 derde verdieping
4562654 | 03 derde verdieping
4562671 | 03 derde verdieping
4562828 | 03 derde verdieping
4562887 | 03 derde verdieping
4575549 | 04 vierde verdieping | Model Group:NLRS_01.00_verdieping 04_gen (members excluded):4585793
4575757 | 04 vierde verdieping | Model Group:NLRS_01.00_verdieping 04_gen (members excluded):4585793
4577208 | 04 vierde verdieping | Model Group:NLRS_01.00_verdieping 04_gen (members excluded):4585793
4577402 | 04 vierde verdieping | Model Group:NLRS_01.00_verdieping 04_gen (members excluded):4585793
4577539 | 04 vierde verdieping | Model Group:NLRS_01.00_verdieping 04_gen (members excluded):4585793
4599125 | 06 zesde verdieping | Model Group:NLRS_01.00_verdieping 06--10_gen:4600460
4599127 | 06 zesde verdieping | Model Group:NLRS_01.00_verdieping 06--10_gen:4600460
4599135 | 06 zesde verdieping | Model Group:NLRS_01.00_verdieping 06--10_gen:4600460
4599139 | 06 zesde verdieping | Model Group:NLRS_01.00_verdieping 06--10_gen:4600460
4599141 | 06 zesde verdieping | Model Group:NLRS_01.00_verdieping 06--10_gen:4600460
4600862 | 07 zevende verdieping | Model Group:NLRS_01.00_verdieping 06--10_gen:4600975
4600864 | 07 zevende verdieping | Model Group:NLRS_01.00_verdieping 06--10_gen:4600975
4600872 | 07 zevende verdieping | Model Group:NLRS_01.00_verdieping 06--10_gen:4600975
4600876 | 07 zevende verdieping | Model Group:NLRS_01.00_verdieping 06--10_gen:4600975
4600878 | 07 zevende verdieping | Model Group:NLRS_01.00_verdieping 06--10_gen:4600975
4601930 | 08 achtste verdieping | Model Group:NLRS_01.00_verdieping 06--10_gen:4602043
4601932 | 08 achtste verdieping | Model Group:NLRS_01.00_verdieping 06--10_gen:4602043
4601940 | 08 achtste verdieping | Model Group:NLRS_01.00_verdieping 06--10_gen:4602043
4601944 | 08 achtste verdieping | Model Group:NLRS_01.00_verdieping 06--10_gen:4602043
4601946 | 08 achtste verdieping | Model Group:NLRS_01.00_verdieping 06--10_gen:4602043
4603039 | 09 negende verdieping | Model Group:NLRS_01.00_verdieping 06--10_gen:4603152
4603041 | 09 negende verdieping | Model Group:NLRS_01.00_verdieping 06--10_gen:4603152
4603049 | 09 negende verdieping | Model Group:NLRS_01.00_verdieping 06--10_gen:4603152
4603053 | 09 negende verdieping | Model Group:NLRS_01.00_verdieping 06--10_gen:4603152
4603055 | 09 negende verdieping | Model Group:NLRS_01.00_verdieping 06--10_gen:4603152
4604107 | 10 tiende verdieping | Model Group:NLRS_01.00_verdieping 06--10_gen:4604220
4604109 | 10 tiende verdieping | Model Group:NLRS_01.00_verdieping 06--10_gen:4604220
4604117 | 10 tiende verdieping | Model Group:NLRS_01.00_verdieping 06--10_gen:4604220
4604121 | 10 tiende verdieping | Model Group:NLRS_01.00_verdieping 06--10_gen:4604220
4604123 | 10 tiende verdieping | Model Group:NLRS_01.00_verdieping 06--10_gen:4604220
4608115 | 12 twaalfde verdieping | Model Group:NLRS_01.00_verdieping 11--17_gen:4609129
4608117 | 12 twaalfde verdieping | Model Group:NLRS_01.00_verdieping 11--17_gen:4609129
4608125 | 12 twaalfde verdieping | Model Group:NLRS_01.00_verdieping 11--17_gen:4609129
4608127 | 12 twaalfde verdieping | Model Group:NLRS_01.00_verdieping 11--17_gen:4609129
4609485 | 13 dertiende verdieping | Model Group:NLRS_01.00_verdieping 11--17_gen:4609592
4609487 | 13 dertiende verdieping | Model Group:NLRS_01.00_verdieping 11--17_gen:4609592
4609495 | 13 dertiende verdieping | Model Group:NLRS_01.00_verdieping 11--17_gen:4609592
4609497 | 13 dertiende verdieping | Model Group:NLRS_01.00_verdieping 11--17_gen:4609592
4610511 | 14 veertiende verdieping | Model Group:NLRS_01.00_verdieping 11--17_gen:4610618
4610513 | 14 veertiende verdieping | Model Group:NLRS_01.00_verdieping 11--17_gen:4610618
4610521 | 14 veertiende verdieping | Model Group:NLRS_01.00_verdieping 11--17_gen:4610618
4610523 | 14 veertiende verdieping | Model Group:NLRS_01.00_verdieping 11--17_gen:4610618
4611535 | 15 vijftiende verdieping | Model Group:NLRS_01.00_verdieping 11--17_gen:4611642
4611537 | 15 vijftiende verdieping | Model Group:NLRS_01.00_verdieping 11--17_gen:4611642
4611545 | 15 vijftiende verdieping | Model Group:NLRS_01.00_verdieping 11--17_gen:4611642
4611547 | 15 vijftiende verdieping | Model Group:NLRS_01.00_verdieping 11--17_gen:4611642
4612561 | 16 zestiende verdieping | Model Group:NLRS_01.00_verdieping 11--17_gen:4612668
4612563 | 16 zestiende verdieping | Model Group:NLRS_01.00_verdieping 11--17_gen:4612668
4612571 | 16 zestiende verdieping | Model Group:NLRS_01.00_verdieping 11--17_gen:4612668
4612573 | 16 zestiende verdieping | Model Group:NLRS_01.00_verdieping 11--17_gen:4612668
4613585 | 17 zeventiende verdieping | Model Group:NLRS_01.00_verdieping 11--17_gen:4613692
4613587 | 17 zeventiende verdieping | Model Group:NLRS_01.00_verdieping 11--17_gen:4613692
4613595 | 17 zeventiende verdieping | Model Group:NLRS_01.00_verdieping 11--17_gen:4613692
4613597 | 17 zeventiende verdieping | Model Group:NLRS_01.00_verdieping 11--17_gen:4613692
4616075 | 18 achttiende verdieping | Model Group:NLRS_01.00_verdieping 18-19_gen:4617185
4616077 | 18 achttiende verdieping | Model Group:NLRS_01.00_verdieping 18-19_gen:4617185
4616085 | 18 achttiende verdieping | Model Group:NLRS_01.00_verdieping 18-19_gen:4617185
4616087 | 18 achttiende verdieping | Model Group:NLRS_01.00_verdieping 18-19_gen:4617185
4617562 | 19 negentiende verdieping | Model Group:NLRS_01.00_verdieping 18-19_gen:4617669
4617564 | 19 negentiende verdieping | Model Group:NLRS_01.00_verdieping 18-19_gen:4617669
4617572 | 19 negentiende verdieping | Model Group:NLRS_01.00_verdieping 18-19_gen:4617669
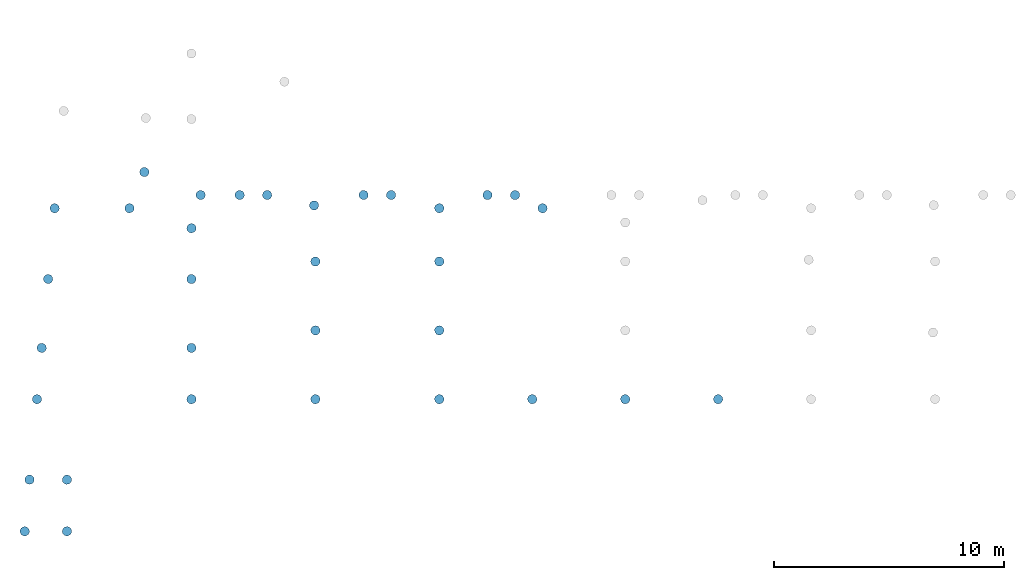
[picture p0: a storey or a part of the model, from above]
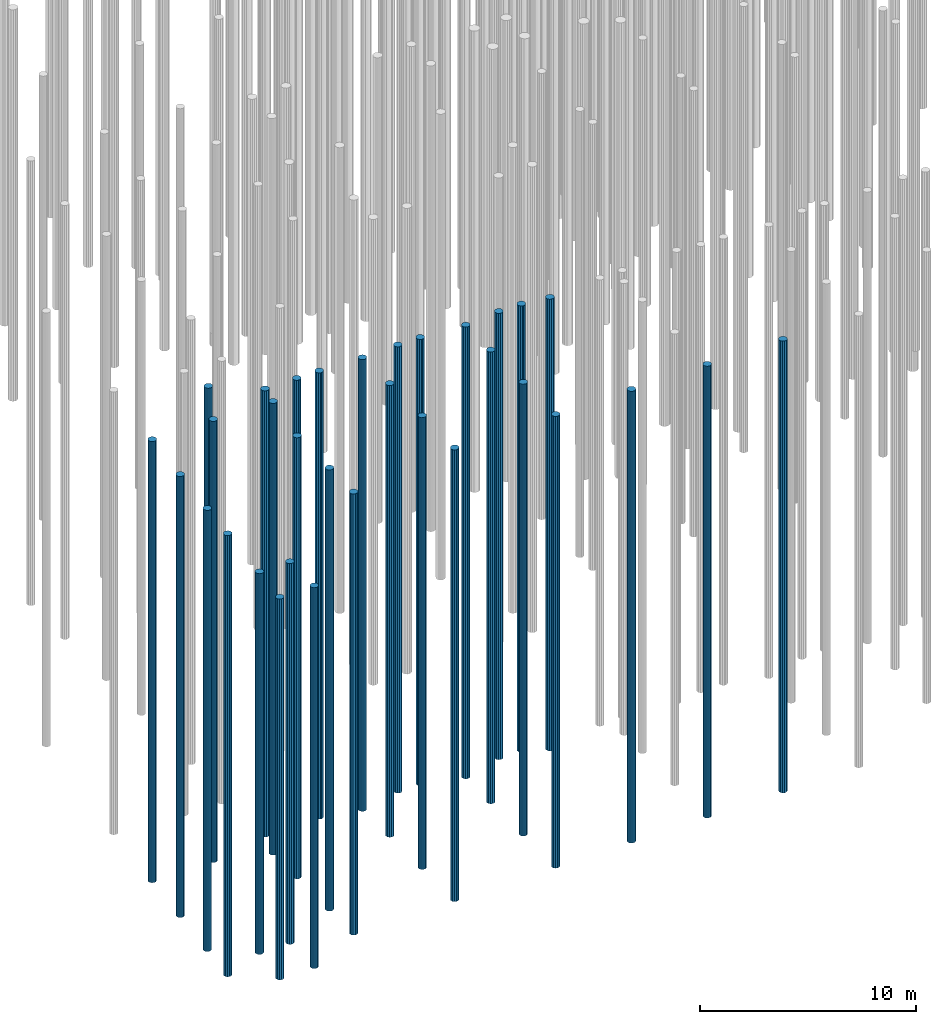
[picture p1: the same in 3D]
Properties of the parts of a building model (IFC2X3), part 11 of 11

# IfcWallStandardCase: Basic Wall:NLRS_22.21_WA_beton ihwg d=250_gen (480)
Name (Basic Wall:NLRS_22.21_WA_beton ihwg d=250_gen:...) | In | Group
4617574 | 19 negentiende verdieping | Model Group:NLRS_01.00_verdieping 18-19_gen:4617669
4618661 | 20 twintigste verdieping | Model Group:NLRS_01.00_verdieping 20_gen:4622361
4618669 | 20 twintigste verdieping | Model Group:NLRS_01.00_verdieping 20_gen:4622361
4618671 | 20 twintigste verdieping | Model Group:NLRS_01.00_verdieping 20_gen:4622361
4620181 | 20 twintigste verdieping | Model Group:NLRS_01.00_verdieping 20_gen:4622361
4621115 | 21 eenentwintigste verdieping | Model Group:NLRS_01.00_verdieping 21--23_gen (members excluded):4647240
4621120 | 21 eenentwintigste verdieping | Model Group:NLRS_01.00_verdieping 21--23_gen (members excluded):4647240
4621122 | 21 eenentwintigste verdieping | Model Group:NLRS_01.00_verdieping 21--23_gen (members excluded):4647240
4621218 | 21 eenentwintigste verdieping | Model Group:NLRS_01.00_verdieping 21--23_gen (members excluded):4647240
4626028 | 11 elfde verdieping | Model Group:NLRS_01.00_verdieping 11--17_gen:4626135
4626030 | 11 elfde verdieping | Model Group:NLRS_01.00_verdieping 11--17_gen:4626135
4626038 | 11 elfde verdieping | Model Group:NLRS_01.00_verdieping 11--17_gen:4626135
4626040 | 11 elfde verdieping | Model Group:NLRS_01.00_verdieping 11--17_gen:4626135
4652445 | 22 tweeëntwintigste verdieping | Model Group:NLRS_01.00_verdieping 21--23_gen (members excluded):4647240
4652447 | 22 tweeëntwintigste verdieping | Model Group:NLRS_01.00_verdieping 21--23_gen (members excluded):4647240
4652449 | 22 tweeëntwintigste verdieping | Model Group:NLRS_01.00_verdieping 21--23_gen (members excluded):4647240
4652453 | 22 tweeëntwintigste verdieping | Model Group:NLRS_01.00_verdieping 21--23_gen (members excluded):4647240
4652945 | 22 tweeëntwintigste verdieping | Model Group:NLRS_01.00_verdieping 21--23_gen (members excluded):4647240
4653282 | 22 tweeëntwintigste verdieping | Model Group:NLRS_01.00_verdieping 21--23_gen (members excluded):4647240
4653359 | 22 tweeëntwintigste verdieping | Model Group:NLRS_01.00_verdieping 21--23_gen (members excluded):4647240
4844295 | 04 vierde verdieping | Model Group:NLRS_01.00_verdieping 04_gen (members excluded):4844403
4844297 | 04 vierde verdieping | Model Group:NLRS_01.00_verdieping 04_gen (members excluded):4844403
4844308 | 04 vierde verdieping | Model Group:NLRS_01.00_verdieping 04_gen (members excluded):4844403
4844312 | 04 vierde verdieping | Model Group:NLRS_01.00_verdieping 04_gen (members excluded):4844403
4844314 | 04 vierde verdieping | Model Group:NLRS_01.00_verdieping 04_gen (members excluded):4844403
4844439 | 06 zesde verdieping | Model Group:NLRS_01.00_verdieping 06--10_gen:4844478
4844441 | 06 zesde verdieping | Model Group:NLRS_01.00_verdieping 06--10_gen:4844478
4844449 | 06 zesde verdieping | Model Group:NLRS_01.00_verdieping 06--10_gen:4844478
4844453 | 06 zesde verdieping | Model Group:NLRS_01.00_verdieping 06--10_gen:4844478
4844455 | 06 zesde verdieping | Model Group:NLRS_01.00_verdieping 06--10_gen:4844478
4844514 | 07 zevende verdieping | Model Group:NLRS_01.00_verdieping 06--10_gen:4844553
4844516 | 07 zevende verdieping | Model Group:NLRS_01.00_verdieping 06--10_gen:4844553
4844524 | 07 zevende verdieping | Model Group:NLRS_01.00_verdieping 06--10_gen:4844553
4844528 | 07 zevende verdieping | Model Group:NLRS_01.00_verdieping 06--10_gen:4844553
4844530 | 07 zevende verdieping | Model Group:NLRS_01.00_verdieping 06--10_gen:4844553
4844589 | 08 achtste verdieping | Model Group:NLRS_01.00_verdieping 06--10_gen:4844628
4844591 | 08 achtste verdieping | Model Group:NLRS_01.00_verdieping 06--10_gen:4844628
4844599 | 08 achtste verdieping | Model Group:NLRS_01.00_verdieping 06--10_gen:4844628
4844603 | 08 achtste verdieping | Model Group:NLRS_01.00_verdieping 06--10_gen:4844628
4844605 | 08 achtste verdieping | Model Group:NLRS_01.00_verdieping 06--10_gen:4844628
4844664 | 09 negende verdieping | Model Group:NLRS_01.00_verdieping 06--10_gen:4844703
4844666 | 09 negende verdieping | Model Group:NLRS_01.00_verdieping 06--10_gen:4844703
4844674 | 09 negende verdieping | Model Group:NLRS_01.00_verdieping 06--10_gen:4844703
4844678 | 09 negende verdieping | Model Group:NLRS_01.00_verdieping 06--10_gen:4844703
4844680 | 09 negende verdieping | Model Group:NLRS_01.00_verdieping 06--10_gen:4844703
4844739 | 10 tiende verdieping | Model Group:NLRS_01.00_verdieping 06--10_gen:4844850
4844741 | 10 tiende verdieping | Model Group:NLRS_01.00_verdieping 06--10_gen:4844850
4844749 | 10 tiende verdieping | Model Group:NLRS_01.00_verdieping 06--10_gen:4844850
4844753 | 10 tiende verdieping | Model Group:NLRS_01.00_verdieping 06--10_gen:4844850
4844755 | 10 tiende verdieping | Model Group:NLRS_01.00_verdieping 06--10_gen:4844850
4844886 | 12 twaalfde verdieping | Model Group:NLRS_01.00_verdieping 11--17_gen:4844919
4844888 | 12 twaalfde verdieping | Model Group:NLRS_01.00_verdieping 11--17_gen:4844919
4844896 | 12 twaalfde verdieping | Model Group:NLRS_01.00_verdieping 11--17_gen:4844919
4844898 | 12 twaalfde verdieping | Model Group:NLRS_01.00_verdieping 11--17_gen:4844919
4844955 | 13 dertiende verdieping | Model Group:NLRS_01.00_verdieping 11--17_gen:4844988
4844957 | 13 dertiende verdieping | Model Group:NLRS_01.00_verdieping 11--17_gen:4844988
4844965 | 13 dertiende verdieping | Model Group:NLRS_01.00_verdieping 11--17_gen:4844988
4844967 | 13 dertiende verdieping | Model Group:NLRS_01.00_verdieping 11--17_gen:4844988
4845024 | 14 veertiende verdieping | Model Group:NLRS_01.00_verdieping 11--17_gen:4845057
4845026 | 14 veertiende verdieping | Model Group:NLRS_01.00_verdieping 11--17_gen:4845057
4845034 | 14 veertiende verdieping | Model Group:NLRS_01.00_verdieping 11--17_gen:4845057
4845036 | 14 veertiende verdieping | Model Group:NLRS_01.00_verdieping 11--17_gen:4845057
4845093 | 15 vijftiende verdieping | Model Group:NLRS_01.00_verdieping 11--17_gen:4845126
4845095 | 15 vijftiende verdieping | Model Group:NLRS_01.00_verdieping 11--17_gen:4845126
4845103 | 15 vijftiende verdieping | Model Group:NLRS_01.00_verdieping 11--17_gen:4845126
4845105 | 15 vijftiende verdieping | Model Group:NLRS_01.00_verdieping 11--17_gen:4845126
4845162 | 16 zestiende verdieping | Model Group:NLRS_01.00_verdieping 11--17_gen:4845195
4845164 | 16 zestiende verdieping | Model Group:NLRS_01.00_verdieping 11--17_gen:4845195
4845172 | 16 zestiende verdieping | Model Group:NLRS_01.00_verdieping 11--17_gen:4845195
4845174 | 16 zestiende verdieping | Model Group:NLRS_01.00_verdieping 11--17_gen:4845195
4845231 | 17 zeventiende verdieping | Model Group:NLRS_01.00_verdieping 11--17_gen:4845336
4845233 | 17 zeventiende verdieping | Model Group:NLRS_01.00_verdieping 11--17_gen:4845336
4845241 | 17 zeventiende verdieping | Model Group:NLRS_01.00_verdieping 11--17_gen:4845336
4845243 | 17 zeventiende verdieping | Model Group:NLRS_01.00_verdieping 11--17_gen:4845336
4845372 | 18 achttiende verdieping | Model Group:NLRS_01.00_verdieping 18-19_gen:4845405
4845374 | 18 achttiende verdieping | Model Group:NLRS_01.00_verdieping 18-19_gen:4845405
4845382 | 18 achttiende verdieping | Model Group:NLRS_01.00_verdieping 18-19_gen:4845405
4845384 | 18 achttiende verdieping | Model Group:NLRS_01.00_verdieping 18-19_gen:4845405
4845441 | 19 negentiende verdieping | Model Group:NLRS_01.00_verdieping 18-19_gen:4845546
4845443 | 19 negentiende verdieping | Model Group:NLRS_01.00_verdieping 18-19_gen:4845546
4845451 | 19 negentiende verdieping | Model Group:NLRS_01.00_verdieping 18-19_gen:4845546
4845453 | 19 negentiende verdieping | Model Group:NLRS_01.00_verdieping 18-19_gen:4845546
4845584 | 20 twintigste verdieping | Model Group:NLRS_01.00_verdieping 20_gen:4845671
4845589 | 20 twintigste verdieping | Model Group:NLRS_01.00_verdieping 20_gen:4845671
4845591 | 20 twintigste verdieping | Model Group:NLRS_01.00_verdieping 20_gen:4845671
4845643 | 20 twintigste verdieping | Model Group:NLRS_01.00_verdieping 20_gen:4845671
4845649 | 21 eenentwintigste verdieping | Model Group:NLRS_01.00_verdieping 21--23_gen (members excluded):4846692
4845651 | 21 eenentwintigste verdieping | Model Group:NLRS_01.00_verdieping 21--23_gen (members excluded):4846692
4845653 | 21 eenentwintigste verdieping | Model Group:NLRS_01.00_verdieping 21--23_gen (members excluded):4846692
4845669 | 21 eenentwintigste verdieping | Model Group:NLRS_01.00_verdieping 21--23_gen (members excluded):4846692
4845713 | 05 vijfde verdieping | Model Group:NLRS_01.00_verdieping 05_gen:6691052
4845715 | 05 vijfde verdieping | Model Group:NLRS_01.00_verdieping 05_gen:6691052
4845723 | 05 vijfde verdieping | Model Group:NLRS_01.00_verdieping 05_gen:6691052
4845727 | 05 vijfde verdieping | Model Group:NLRS_01.00_verdieping 05_gen:6691052
4845729 | 05 vijfde verdieping | Model Group:NLRS_01.00_verdieping 05_gen:6691052
4845788 | 11 elfde verdieping | Model Group:NLRS_01.00_verdieping 11--17_gen:4845821
4845790 | 11 elfde verdieping | Model Group:NLRS_01.00_verdieping 11--17_gen:4845821
4845798 | 11 elfde verdieping | Model Group:NLRS_01.00_verdieping 11--17_gen:4845821
4845800 | 11 elfde verdieping | Model Group:NLRS_01.00_verdieping 11--17_gen:4845821
4846819 | 22 tweeëntwintigste verdieping | Model Group:NLRS_01.00_verdieping 21--23_gen (members excluded):4846692
4846821 | 22 tweeëntwintigste verdieping | Model Group:NLRS_01.00_verdieping 21--23_gen (members excluded):4846692
4846825 | 22 tweeëntwintigste verdieping | Model Group:NLRS_01.00_verdieping 21--23_gen (members excluded):4846692
4846829 | 22 tweeëntwintigste verdieping | Model Group:NLRS_01.00_verdieping 21--23_gen (members excluded):4846692
4846833 | 22 tweeëntwintigste verdieping | Model Group:NLRS_01.00_verdieping 21--23_gen (members excluded):4846692
4846835 | 22 tweeëntwintigste verdieping | Model Group:NLRS_01.00_verdieping 21--23_gen (members excluded):4846692
4846837 | 22 tweeëntwintigste verdieping | Model Group:NLRS_01.00_verdieping 21--23_gen (members excluded):4846692
4886314 | 00 begane grond
4887180 | 01 eerste verdieping
4888376 | 03 derde verdieping
4888636 | 02 tweede verdieping
4888859 | 01 eerste verdieping
4889039 | 01 eerste verdieping
4889209 | 02 tweede verdieping
4889302 | 03 derde verdieping
4945426 | 03 derde verdieping
5014890 | 00 begane grond
5014892 | 00 begane grond
5014894 | 00 begane grond
5014896 | 00 begane grond
5014900 | 00 begane grond
5014902 | 00 begane grond
5014904 | 00 begane grond
5014910 | 00 begane grond
5014912 | 00 begane grond
5014950 | 01 eerste verdieping
5014954 | 01 eerste verdieping
5014956 | 01 eerste verdieping
5014958 | 01 eerste verdieping
5014960 | 01 eerste verdieping
5014962 | 01 eerste verdieping
5014966 | 01 eerste verdieping
5014978 | 02 tweede verdieping
5014980 | 02 tweede verdieping
5014984 | 01c derde tussenverdieping
5014986 | 02 tweede verdieping
5014988 | 02 tweede verdieping
5014990 | 02 tweede verdieping
5014994 | 03 derde verdieping
5014996 | 03 derde verdieping
5015004 | 03 derde verdieping
5015006 | 03 derde verdieping
5015396 | 03 derde verdieping
5015398 | 02 tweede verdieping
5015400 | 01 eerste verdieping
5015402 | 01 eerste verdieping
5015404 | 02 tweede verdieping
5015406 | 03 derde verdieping
5095103 | 01 eerste verdieping
5966790 | 00 begane grond
5966850 | 00 begane grond
5983964 | 22 tweeëntwintigste verdieping | Model Group:NLRS_01.00_verdieping 21--23_gen (members excluded):4647240
5984466 | 22 tweeëntwintigste verdieping | Model Group:NLRS_01.00_verdieping 21--23_gen (members excluded):4846692
6698071 | 05 vijfde verdieping | Model Group:NLRS_01.00_verdieping 05_gen (members excluded):6698157
6698073 | 05 vijfde verdieping | Model Group:NLRS_01.00_verdieping 05_gen (members excluded):6698157
6698081 | 05 vijfde verdieping | Model Group:NLRS_01.00_verdieping 05_gen (members excluded):6698157
6698085 | 05 vijfde verdieping | Model Group:NLRS_01.00_verdieping 05_gen (members excluded):6698157
6698087 | 05 vijfde verdieping | Model Group:NLRS_01.00_verdieping 05_gen (members excluded):6698157
8499910 | 00 begane grond
11363083 | 04 vierde verdieping | Model Group:NLRS_01.00_verdieping 04_gen (members excluded):4844403
11363210 | 04 vierde verdieping | Model Group:NLRS_01.00_verdieping 04_gen (members excluded):4844403
11363226 | 04 vierde verdieping | Model Group:NLRS_01.00_verdieping 04_gen (members excluded):4844403
11363240 | 04 vierde verdieping | Model Group:NLRS_01.00_verdieping 04_gen (members excluded):4844403
11363270 | 04 vierde verdieping | Model Group:NLRS_01.00_verdieping 04_gen (members excluded):4585793
11363272 | 04 vierde verdieping | Model Group:NLRS_01.00_verdieping 04_gen (members excluded):4585793
11363274 | 04 vierde verdieping | Model Group:NLRS_01.00_verdieping 04_gen (members excluded):4585793
11363371 | 04 vierde verdieping | Model Group:NLRS_01.00_verdieping 04_gen (members excluded):4844403
11363377 | 04 vierde verdieping | Model Group:NLRS_01.00_verdieping 04_gen (members excluded):4585793
11363405 | 04 vierde verdieping | Model Group:NLRS_01.00_verdieping 04_gen (members excluded):4844403
11363413 | 04 vierde verdieping | Model Group:NLRS_01.00_verdieping 04_gen (members excluded):4585793
11363629 | 05 vijfde verdieping | Model Group:NLRS_01.00_verdieping 05_gen:6691052
11363657 | 05 vijfde verdieping | Model Group:NLRS_01.00_verdieping 05_gen:6691052
11363683 | 05 vijfde verdieping | Model Group:NLRS_01.00_verdieping 05_gen:6691052
11363695 | 05 vijfde verdieping | Model Group:NLRS_01.00_verdieping 05_gen (members excluded):6698157
11363697 | 05 vijfde verdieping | Model Group:NLRS_01.00_verdieping 05_gen (members excluded):6698157
11363699 | 05 vijfde verdieping | Model Group:NLRS_01.00_verdieping 05_gen (members excluded):6698157
11363800 | 06 zesde verdieping | Model Group:NLRS_01.00_verdieping 06--10_gen:4844478
11363904 | 06 zesde verdieping | Model Group:NLRS_01.00_verdieping 06--10_gen:4844478
11363930 | 06 zesde verdieping | Model Group:NLRS_01.00_verdieping 06--10_gen:4844478
11363936 | 06 zesde verdieping | Model Group:NLRS_01.00_verdieping 06--10_gen:4600460
11363938 | 06 zesde verdieping | Model Group:NLRS_01.00_verdieping 06--10_gen:4600460
11363940 | 06 zesde verdieping | Model Group:NLRS_01.00_verdieping 06--10_gen:4600460
11363948 | 07 zevende verdieping | Model Group:NLRS_01.00_verdieping 06--10_gen:4600975
11363950 | 07 zevende verdieping | Model Group:NLRS_01.00_verdieping 06--10_gen:4600975
11363952 | 07 zevende verdieping | Model Group:NLRS_01.00_verdieping 06--10_gen:4600975
11363954 | 08 achtste verdieping | Model Group:NLRS_01.00_verdieping 06--10_gen:4602043
11363956 | 08 achtste verdieping | Model Group:NLRS_01.00_verdieping 06--10_gen:4602043
11363958 | 08 achtste verdieping | Model Group:NLRS_01.00_verdieping 06--10_gen:4602043
11363960 | 09 negende verdieping | Model Group:NLRS_01.00_verdieping 06--10_gen:4603152
11363962 | 09 negende verdieping | Model Group:NLRS_01.00_verdieping 06--10_gen:4603152
11363964 | 09 negende verdieping | Model Group:NLRS_01.00_verdieping 06--10_gen:4603152
11363966 | 10 tiende verdieping | Model Group:NLRS_01.00_verdieping 06--10_gen:4604220
11363968 | 10 tiende verdieping | Model Group:NLRS_01.00_verdieping 06--10_gen:4604220
11363970 | 10 tiende verdieping | Model Group:NLRS_01.00_verdieping 06--10_gen:4604220
11364017 | 07 zevende verdieping | Model Group:NLRS_01.00_verdieping 06--10_gen:4844553
11364019 | 07 zevende verdieping | Model Group:NLRS_01.00_verdieping 06--10_gen:4844553
11364021 | 07 zevende verdieping | Model Group:NLRS_01.00_verdieping 06--10_gen:4844553
11364023 | 08 achtste verdieping | Model Group:NLRS_01.00_verdieping 06--10_gen:4844628
11364025 | 08 achtste verdieping | Model Group:NLRS_01.00_verdieping 06--10_gen:4844628
11364027 | 08 achtste verdieping | Model Group:NLRS_01.00_verdieping 06--10_gen:4844628
11364029 | 09 negende verdieping | Model Group:NLRS_01.00_verdieping 06--10_gen:4844703
11364031 | 09 negende verdieping | Model Group:NLRS_01.00_verdieping 06--10_gen:4844703
11364033 | 09 negende verdieping | Model Group:NLRS_01.00_verdieping 06--10_gen:4844703
11364035 | 10 tiende verdieping | Model Group:NLRS_01.00_verdieping 06--10_gen:4844850
11364037 | 10 tiende verdieping | Model Group:NLRS_01.00_verdieping 06--10_gen:4844850
11364039 | 10 tiende verdieping | Model Group:NLRS_01.00_verdieping 06--10_gen:4844850
11365139 | 11 elfde verdieping | Model Group:NLRS_01.00_verdieping 11--17_gen:4845821
11365169 | 11 elfde verdieping | Model Group:NLRS_01.00_verdieping 11--17_gen:4845821
11366752 | 12 twaalfde verdieping | Model Group:NLRS_01.00_verdieping 11--17_gen:4609129
11366754 | 12 twaalfde verdieping | Model Group:NLRS_01.00_verdieping 11--17_gen:4609129
11366766 | 13 dertiende verdieping | Model Group:NLRS_01.00_verdieping 11--17_gen:4609592
11366768 | 13 dertiende verdieping | Model Group:NLRS_01.00_verdieping 11--17_gen:4609592
11366773 | 14 veertiende verdieping | Model Group:NLRS_01.00_verdieping 11--17_gen:4610618
11366775 | 14 veertiende verdieping | Model Group:NLRS_01.00_verdieping 11--17_gen:4610618
11366780 | 15 vijftiende verdieping | Model Group:NLRS_01.00_verdieping 11--17_gen:4611642
11366782 | 15 vijftiende verdieping | Model Group:NLRS_01.00_verdieping 11--17_gen:4611642
11366787 | 16 zestiende verdieping | Model Group:NLRS_01.00_verdieping 11--17_gen:4612668
11366789 | 16 zestiende verdieping | Model Group:NLRS_01.00_verdieping 11--17_gen:4612668
11366794 | 17 zeventiende verdieping | Model Group:NLRS_01.00_verdieping 11--17_gen:4613692
11366796 | 17 zeventiende verdieping | Model Group:NLRS_01.00_verdieping 11--17_gen:4613692
11366801 | 11 elfde verdieping | Model Group:NLRS_01.00_verdieping 11--17_gen:4626135
11366803 | 11 elfde verdieping | Model Group:NLRS_01.00_verdieping 11--17_gen:4626135
11366857 | 12 twaalfde verdieping | Model Group:NLRS_01.00_verdieping 11--17_gen:4844919
11366859 | 12 twaalfde verdieping | Model Group:NLRS_01.00_verdieping 11--17_gen:4844919
11366864 | 13 dertiende verdieping | Model Group:NLRS_01.00_verdieping 11--17_gen:4844988
11366866 | 13 dertiende verdieping | Model Group:NLRS_01.00_verdieping 11--17_gen:4844988
11366871 | 14 veertiende verdieping | Model Group:NLRS_01.00_verdieping 11--17_gen:4845057
11366873 | 14 veertiende verdieping | Model Group:NLRS_01.00_verdieping 11--17_gen:4845057
11366878 | 15 vijftiende verdieping | Model Group:NLRS_01.00_verdieping 11--17_gen:4845126
11366880 | 15 vijftiende verdieping | Model Group:NLRS_01.00_verdieping 11--17_gen:4845126
11366885 | 16 zestiende verdieping | Model Group:NLRS_01.00_verdieping 11--17_gen:4845195
11366887 | 16 zestiende verdieping | Model Group:NLRS_01.00_verdieping 11--17_gen:4845195
11366892 | 17 zeventiende verdieping | Model Group:NLRS_01.00_verdieping 11--17_gen:4845336
11366894 | 17 zeventiende verdieping | Model Group:NLRS_01.00_verdieping 11--17_gen:4845336
11368166 | 18 achttiende verdieping | Model Group:NLRS_01.00_verdieping 18-19_gen:4845405
11368426 | 18 achttiende verdieping | Model Group:NLRS_01.00_verdieping 18-19_gen:4845405
11369110 | 18 achttiende verdieping | Model Group:NLRS_01.00_verdieping 18-19_gen:4617185
11369112 | 18 achttiende verdieping | Model Group:NLRS_01.00_verdieping 18-19_gen:4617185
11369124 | 19 negentiende verdieping | Model Group:NLRS_01.00_verdieping 18-19_gen:4617669
11369126 | 19 negentiende verdieping | Model Group:NLRS_01.00_verdieping 18-19_gen:4617669
11369145 | 19 negentiende verdieping | Model Group:NLRS_01.00_verdieping 18-19_gen:4845546
11369147 | 19 negentiende verdieping | Model Group:NLRS_01.00_verdieping 18-19_gen:4845546
11369548 | 20 twintigste verdieping | Model Group:NLRS_01.00_verdieping 20_gen:4845671
11369750 | 20 twintigste verdieping | Model Group:NLRS_01.00_verdieping 20_gen:4845671
11370064 | 20 twintigste verdieping | Model Group:NLRS_01.00_verdieping 20_gen:4622361
11370066 | 20 twintigste verdieping | Model Group:NLRS_01.00_verdieping 20_gen:4622361
11514347 | 18 achttiende verdieping | Model Group:NLRS_01.00_verdieping 18-19_gen:4845405
11514365 | 18 achttiende verdieping | Model Group:NLRS_01.00_verdieping 18-19_gen:4617185
11514369 | 19 negentiende verdieping | Model Group:NLRS_01.00_verdieping 18-19_gen:4617669
11514381 | 19 negentiende verdieping | Model Group:NLRS_01.00_verdieping 18-19_gen:4845546
11514471 | 20 twintigste verdieping | Model Group:NLRS_01.00_verdieping 20_gen:4845671
11514497 | 20 twintigste verdieping | Model Group:NLRS_01.00_verdieping 20_gen:4845671
11514521 | 20 twintigste verdieping | Model Group:NLRS_01.00_verdieping 20_gen:4845671
11514541 | 20 twintigste verdieping | Model Group:NLRS_01.00_verdieping 20_gen:4845671
11514557 | 20 twintigste verdieping | Model Group:NLRS_01.00_verdieping 20_gen:4845671
11514563 | 20 twintigste verdieping | Model Group:NLRS_01.00_verdieping 20_gen:4622361
11514565 | 20 twintigste verdieping | Model Group:NLRS_01.00_verdieping 20_gen:4622361
11514567 | 20 twintigste verdieping | Model Group:NLRS_01.00_verdieping 20_gen:4622361
11514569 | 20 twintigste verdieping | Model Group:NLRS_01.00_verdieping 20_gen:4622361
11514571 | 20 twintigste verdieping | Model Group:NLRS_01.00_verdieping 20_gen:4622361
11656887 | 21 eenentwintigste verdieping | Model Group:NLRS_01.00_verdieping 21--23_gen (members excluded):4846692
11656917 | 21 eenentwintigste verdieping | Model Group:NLRS_01.00_verdieping 21--23_gen (members excluded):4647240
11656997 | 21 eenentwintigste verdieping | Model Group:NLRS_01.00_verdieping 21--23_gen (members excluded):4846692
11657047 | 21 eenentwintigste verdieping | Model Group:NLRS_01.00_verdieping 21--23_gen (members excluded):4846692
11657360 | 21 eenentwintigste verdieping | Model Group:NLRS_01.00_verdieping 21--23_gen (members excluded):4647240
11657376 | 21 eenentwintigste verdieping | Model Group:NLRS_01.00_verdieping 21--23_gen (members excluded):4647240
11657770 | 21 eenentwintigste verdieping | Model Group:NLRS_01.00_verdieping 21--23_gen (members excluded):4846692
11658094 | 21 eenentwintigste verdieping | Model Group:NLRS_01.00_verdieping 21--23_gen (members excluded):4647240
11661834 | 22 tweeëntwintigste verdieping | Model Group:NLRS_01.00_verdieping 21--23_gen (members excluded):4846692
11662193 | 22 tweeëntwintigste verdieping | Model Group:NLRS_01.00_verdieping 21--23_gen (members excluded):4846692
11663187 | 22 tweeëntwintigste verdieping | Model Group:NLRS_01.00_verdieping 21--23_gen (members excluded):4647240
11663191 | 22 tweeëntwintigste verdieping | Model Group:NLRS_01.00_verdieping 21--23_gen (members excluded):4647240
13463004 | 22 tweeëntwintigste verdieping | Model Group:NLRS_01.00_verdieping 21--23_gen (members excluded):4846692
13464049 | 22 tweeëntwintigste verdieping | Model Group:NLRS_01.00_verdieping 21--23_gen (members excluded):4647240

# IfcWallStandardCase: Basic Wall:NLRS_22.21_WA_beton prefab d=100_gen (8)
In: 22 tweeëntwintigste verdieping
Type - PredefinedType: STANDARD; Material: NLRS_f2_beton prefab 100 mm
Classification: 22.21 binnenwanden - constructief, massieve wanden (Uniformat)
Pset_WallCommon - LoadBearing: yes; IsExternal: no; ExtendToStructure: no; Reference: NLRS_22.21_WA_beton prefab d=100_gen; ThermalTransmittance: 10.46 kg/K/s3
Name (Basic Wall:NLRS_22.21_WA_beton prefab d=100_gen:...) | Group
11924729 | Model Group:NLRS_01.00_verdieping 21--23_gen (members excluded):4846692
11924998 | Model Group:NLRS_01.00_verdieping 21--23_gen (members excluded):4846692
11925058 | Model Group:NLRS_01.00_verdieping 21--23_gen (members excluded):4846692
11925162 | Model Group:NLRS_01.00_verdieping 21--23_gen (members excluded):4846692
11925539 | Model Group:NLRS_01.00_verdieping 21--23_gen (members excluded):4647240
11925541 | Model Group:NLRS_01.00_verdieping 21--23_gen (members excluded):4647240
11925543 | Model Group:NLRS_01.00_verdieping 21--23_gen (members excluded):4647240
11925545 | Model Group:NLRS_01.00_verdieping 21--23_gen (members excluded):4647240

# IfcWallStandardCase: Basic Wall:NLRS_22.21_WA_beton prefab d=180_gen (23)
Type - PredefinedType: STANDARD; Material: NLRS_f2_beton prefab 180 mm
Classification: 22.21 binnenwanden - constructief, massieve wanden (Uniformat)
Pset_WallCommon - LoadBearing: yes; IsExternal: no; ExtendToStructure: no; Reference: NLRS_22.21_WA_beton prefab d=180_gen; ThermalTransmittance: 5.81111 kg/K/s3
Name (Basic Wall:NLRS_22.21_WA_beton prefab d=180_gen:...) | In
4264388 | 00 begane grond
4264517 | 00 begane grond
4336222 | 01a eerste tussenverdieping
4336379 | 01a eerste tussenverdieping
4336613 | 01a eerste tussenverdieping
4337490 | 00 begane grond
4337654 | 00 begane grond
4337785 | 00 begane grond
4338044 | 01c derde tussenverdieping
4338046 | 01c derde tussenverdieping
4338246 | 01c derde tussenverdieping
4339812 | 01a eerste tussenverdieping
4339907 | 01 eerste verdieping
4340078 | 01a eerste tussenverdieping
4340548 | 01c derde tussenverdieping
4340550 | 01c derde tussenverdieping
4340552 | 01c derde tussenverdieping
5968189 | 02b tweede tussenverdieping
6503753 | 02b tweede tussenverdieping
6510032 | 02b tweede tussenverdieping
6604935 | 02b tweede tussenverdieping
6611465 | 02b tweede tussenverdieping
7200927 | 02b tweede tussenverdieping

# IfcWallStandardCase: Basic Wall:NLRS_22.21_WA_beton prefab d=200_gen (204)
Type - PredefinedType: STANDARD; Material: NLRS_f2_beton prefab 200 mm
Classification: 22.21 binnenwanden - constructief, massieve wanden (Uniformat)
Pset_WallCommon - LoadBearing: yes; IsExternal: no; ExtendToStructure: no; Reference: NLRS_22.21_WA_beton prefab d=200_gen; ThermalTransmittance: 5.23 kg/K/s3
Name (Basic Wall:NLRS_22.21_WA_beton prefab d=200_gen:...) | In | Group
4321449 | 01 eerste verdieping
4321688 | 00 begane grond
4322541 | 02 tweede verdieping
4322647 | 03 derde verdieping
4564469 | 00 begane grond
4564471 | 00 begane grond
4564473 | 00 begane grond
4564477 | 01a eerste tussenverdieping
4564479 | 01 eerste verdieping
4564481 | 01a eerste tussenverdieping
4564485 | 01c derde tussenverdieping
4564487 | 01c derde tussenverdieping
4564489 | 01c derde tussenverdieping
4564491 | 02b tweede tussenverdieping
4564493 | 02b tweede tussenverdieping
4564495 | 02b tweede tussenverdieping
4565078 | 00 begane grond
4565080 | 01a eerste tussenverdieping
4565082 | 01c derde tussenverdieping
4565084 | 02b tweede tussenverdieping
4578065 | 04 vierde verdieping | Model Group:NLRS_01.00_verdieping 04_gen (members excluded):4585793
4578213 | 04 vierde verdieping | Model Group:NLRS_01.00_verdieping 04_gen (members excluded):4585793
4578344 | 04 vierde verdieping | Model Group:NLRS_01.00_verdieping 04_gen (members excluded):4585793
4578539 | 04 vierde verdieping | Model Group:NLRS_01.00_verdieping 04_gen (members excluded):4585793
4599146 | 06 zesde verdieping | Model Group:NLRS_01.00_verdieping 06--10_gen:4600460
4599148 | 06 zesde verdieping | Model Group:NLRS_01.00_verdieping 06--10_gen:4600460
4599150 | 06 zesde verdieping | Model Group:NLRS_01.00_verdieping 06--10_gen:4600460
4599152 | 06 zesde verdieping | Model Group:NLRS_01.00_verdieping 06--10_gen:4600460
4600883 | 07 zevende verdieping | Model Group:NLRS_01.00_verdieping 06--10_gen:4600975
4600885 | 07 zevende verdieping | Model Group:NLRS_01.00_verdieping 06--10_gen:4600975
4600887 | 07 zevende verdieping | Model Group:NLRS_01.00_verdieping 06--10_gen:4600975
4600889 | 07 zevende verdieping | Model Group:NLRS_01.00_verdieping 06--10_gen:4600975
4601951 | 08 achtste verdieping | Model Group:NLRS_01.00_verdieping 06--10_gen:4602043
4601953 | 08 achtste verdieping | Model Group:NLRS_01.00_verdieping 06--10_gen:4602043
4601955 | 08 achtste verdieping | Model Group:NLRS_01.00_verdieping 06--10_gen:4602043
4601957 | 08 achtste verdieping | Model Group:NLRS_01.00_verdieping 06--10_gen:4602043
4603060 | 09 negende verdieping | Model Group:NLRS_01.00_verdieping 06--10_gen:4603152
4603062 | 09 negende verdieping | Model Group:NLRS_01.00_verdieping 06--10_gen:4603152
4603064 | 09 negende verdieping | Model Group:NLRS_01.00_verdieping 06--10_gen:4603152
4603066 | 09 negende verdieping | Model Group:NLRS_01.00_verdieping 06--10_gen:4603152
4604128 | 10 tiende verdieping | Model Group:NLRS_01.00_verdieping 06--10_gen:4604220
4604130 | 10 tiende verdieping | Model Group:NLRS_01.00_verdieping 06--10_gen:4604220
4604132 | 10 tiende verdieping | Model Group:NLRS_01.00_verdieping 06--10_gen:4604220
4604134 | 10 tiende verdieping | Model Group:NLRS_01.00_verdieping 06--10_gen:4604220
4608130 | 12 twaalfde verdieping | Model Group:NLRS_01.00_verdieping 11--17_gen:4609129
4608132 | 12 twaalfde verdieping | Model Group:NLRS_01.00_verdieping 11--17_gen:4609129
4608134 | 12 twaalfde verdieping | Model Group:NLRS_01.00_verdieping 11--17_gen:4609129
4608136 | 12 twaalfde verdieping | Model Group:NLRS_01.00_verdieping 11--17_gen:4609129
4609500 | 13 dertiende verdieping | Model Group:NLRS_01.00_verdieping 11--17_gen:4609592
4609502 | 13 dertiende verdieping | Model Group:NLRS_01.00_verdieping 11--17_gen:4609592
4609504 | 13 dertiende verdieping | Model Group:NLRS_01.00_verdieping 11--17_gen:4609592
4609506 | 13 dertiende verdieping | Model Group:NLRS_01.00_verdieping 11--17_gen:4609592
4610526 | 14 veertiende verdieping | Model Group:NLRS_01.00_verdieping 11--17_gen:4610618
4610528 | 14 veertiende verdieping | Model Group:NLRS_01.00_verdieping 11--17_gen:4610618
4610530 | 14 veertiende verdieping | Model Group:NLRS_01.00_verdieping 11--17_gen:4610618
4610532 | 14 veertiende verdieping | Model Group:NLRS_01.00_verdieping 11--17_gen:4610618
4611550 | 15 vijftiende verdieping | Model Group:NLRS_01.00_verdieping 11--17_gen:4611642
4611552 | 15 vijftiende verdieping | Model Group:NLRS_01.00_verdieping 11--17_gen:4611642
4611554 | 15 vijftiende verdieping | Model Group:NLRS_01.00_verdieping 11--17_gen:4611642
4611556 | 15 vijftiende verdieping | Model Group:NLRS_01.00_verdieping 11--17_gen:4611642
4612576 | 16 zestiende verdieping | Model Group:NLRS_01.00_verdieping 11--17_gen:4612668
4612578 | 16 zestiende verdieping | Model Group:NLRS_01.00_verdieping 11--17_gen:4612668
4612580 | 16 zestiende verdieping | Model Group:NLRS_01.00_verdieping 11--17_gen:4612668
4612582 | 16 zestiende verdieping | Model Group:NLRS_01.00_verdieping 11--17_gen:4612668
4613600 | 17 zeventiende verdieping | Model Group:NLRS_01.00_verdieping 11--17_gen:4613692
4613602 | 17 zeventiende verdieping | Model Group:NLRS_01.00_verdieping 11--17_gen:4613692
4613604 | 17 zeventiende verdieping | Model Group:NLRS_01.00_verdieping 11--17_gen:4613692
4613606 | 17 zeventiende verdieping | Model Group:NLRS_01.00_verdieping 11--17_gen:4613692
4616090 | 18 achttiende verdieping | Model Group:NLRS_01.00_verdieping 18-19_gen:4617185
4616092 | 18 achttiende verdieping | Model Group:NLRS_01.00_verdieping 18-19_gen:4617185
4616094 | 18 achttiende verdieping | Model Group:NLRS_01.00_verdieping 18-19_gen:4617185
4616096 | 18 achttiende verdieping | Model Group:NLRS_01.00_verdieping 18-19_gen:4617185
4617577 | 19 negentiende verdieping | Model Group:NLRS_01.00_verdieping 18-19_gen:4617669
4617579 | 19 negentiende verdieping | Model Group:NLRS_01.00_verdieping 18-19_gen:4617669
4617581 | 19 negentiende verdieping | Model Group:NLRS_01.00_verdieping 18-19_gen:4617669
4617583 | 19 negentiende verdieping | Model Group:NLRS_01.00_verdieping 18-19_gen:4617669
4618674 | 20 twintigste verdieping | Model Group:NLRS_01.00_verdieping 20_gen:4622361
4618676 | 20 twintigste verdieping | Model Group:NLRS_01.00_verdieping 20_gen:4622361
4618678 | 20 twintigste verdieping | Model Group:NLRS_01.00_verdieping 20_gen:4622361
4618680 | 20 twintigste verdieping | Model Group:NLRS_01.00_verdieping 20_gen:4622361
4621125 | 21 eenentwintigste verdieping | Model Group:NLRS_01.00_verdieping 21--23_gen (members excluded):4647240
4621127 | 21 eenentwintigste verdieping | Model Group:NLRS_01.00_verdieping 21--23_gen (members excluded):4647240
4621129 | 21 eenentwintigste verdieping | Model Group:NLRS_01.00_verdieping 21--23_gen (members excluded):4647240
4621131 | 21 eenentwintigste verdieping | Model Group:NLRS_01.00_verdieping 21--23_gen (members excluded):4647240
4626043 | 11 elfde verdieping | Model Group:NLRS_01.00_verdieping 11--17_gen:4626135
4626045 | 11 elfde verdieping | Model Group:NLRS_01.00_verdieping 11--17_gen:4626135
4626047 | 11 elfde verdieping | Model Group:NLRS_01.00_verdieping 11--17_gen:4626135
4626049 | 11 elfde verdieping | Model Group:NLRS_01.00_verdieping 11--17_gen:4626135
4844319 | 04 vierde verdieping | Model Group:NLRS_01.00_verdieping 04_gen (members excluded):4844403
4844321 | 04 vierde verdieping | Model Group:NLRS_01.00_verdieping 04_gen (members excluded):4844403
4844323 | 04 vierde verdieping | Model Group:NLRS_01.00_verdieping 04_gen (members excluded):4844403
4844325 | 04 vierde verdieping | Model Group:NLRS_01.00_verdieping 04_gen (members excluded):4844403
4844460 | 06 zesde verdieping | Model Group:NLRS_01.00_verdieping 06--10_gen:4844478
4844462 | 06 zesde verdieping | Model Group:NLRS_01.00_verdieping 06--10_gen:4844478
4844464 | 06 zesde verdieping | Model Group:NLRS_01.00_verdieping 06--10_gen:4844478
4844466 | 06 zesde verdieping | Model Group:NLRS_01.00_verdieping 06--10_gen:4844478
4844535 | 07 zevende verdieping | Model Group:NLRS_01.00_verdieping 06--10_gen:4844553
4844537 | 07 zevende verdieping | Model Group:NLRS_01.00_verdieping 06--10_gen:4844553
4844539 | 07 zevende verdieping | Model Group:NLRS_01.00_verdieping 06--10_gen:4844553
4844541 | 07 zevende verdieping | Model Group:NLRS_01.00_verdieping 06--10_gen:4844553
4844610 | 08 achtste verdieping | Model Group:NLRS_01.00_verdieping 06--10_gen:4844628
4844612 | 08 achtste verdieping | Model Group:NLRS_01.00_verdieping 06--10_gen:4844628
4844614 | 08 achtste verdieping | Model Group:NLRS_01.00_verdieping 06--10_gen:4844628
4844616 | 08 achtste verdieping | Model Group:NLRS_01.00_verdieping 06--10_gen:4844628
4844685 | 09 negende verdieping | Model Group:NLRS_01.00_verdieping 06--10_gen:4844703
4844687 | 09 negende verdieping | Model Group:NLRS_01.00_verdieping 06--10_gen:4844703
4844689 | 09 negende verdieping | Model Group:NLRS_01.00_verdieping 06--10_gen:4844703
4844691 | 09 negende verdieping | Model Group:NLRS_01.00_verdieping 06--10_gen:4844703
4844760 | 10 tiende verdieping | Model Group:NLRS_01.00_verdieping 06--10_gen:4844850
4844762 | 10 tiende verdieping | Model Group:NLRS_01.00_verdieping 06--10_gen:4844850
4844764 | 10 tiende verdieping | Model Group:NLRS_01.00_verdieping 06--10_gen:4844850
4844766 | 10 tiende verdieping | Model Group:NLRS_01.00_verdieping 06--10_gen:4844850
4844901 | 12 twaalfde verdieping | Model Group:NLRS_01.00_verdieping 11--17_gen:4844919
4844903 | 12 twaalfde verdieping | Model Group:NLRS_01.00_verdieping 11--17_gen:4844919
4844905 | 12 twaalfde verdieping | Model Group:NLRS_01.00_verdieping 11--17_gen:4844919
4844907 | 12 twaalfde verdieping | Model Group:NLRS_01.00_verdieping 11--17_gen:4844919
4844970 | 13 dertiende verdieping | Model Group:NLRS_01.00_verdieping 11--17_gen:4844988
4844972 | 13 dertiende verdieping | Model Group:NLRS_01.00_verdieping 11--17_gen:4844988
4844974 | 13 dertiende verdieping | Model Group:NLRS_01.00_verdieping 11--17_gen:4844988
4844976 | 13 dertiende verdieping | Model Group:NLRS_01.00_verdieping 11--17_gen:4844988
4845039 | 14 veertiende verdieping | Model Group:NLRS_01.00_verdieping 11--17_gen:4845057
4845041 | 14 veertiende verdieping | Model Group:NLRS_01.00_verdieping 11--17_gen:4845057
4845043 | 14 veertiende verdieping | Model Group:NLRS_01.00_verdieping 11--17_gen:4845057
4845045 | 14 veertiende verdieping | Model Group:NLRS_01.00_verdieping 11--17_gen:4845057
4845108 | 15 vijftiende verdieping | Model Group:NLRS_01.00_verdieping 11--17_gen:4845126
4845110 | 15 vijftiende verdieping | Model Group:NLRS_01.00_verdieping 11--17_gen:4845126
4845112 | 15 vijftiende verdieping | Model Group:NLRS_01.00_verdieping 11--17_gen:4845126
4845114 | 15 vijftiende verdieping | Model Group:NLRS_01.00_verdieping 11--17_gen:4845126
4845177 | 16 zestiende verdieping | Model Group:NLRS_01.00_verdieping 11--17_gen:4845195
4845179 | 16 zestiende verdieping | Model Group:NLRS_01.00_verdieping 11--17_gen:4845195
4845181 | 16 zestiende verdieping | Model Group:NLRS_01.00_verdieping 11--17_gen:4845195
4845183 | 16 zestiende verdieping | Model Group:NLRS_01.00_verdieping 11--17_gen:4845195
4845246 | 17 zeventiende verdieping | Model Group:NLRS_01.00_verdieping 11--17_gen:4845336
4845248 | 17 zeventiende verdieping | Model Group:NLRS_01.00_verdieping 11--17_gen:4845336
4845250 | 17 zeventiende verdieping | Model Group:NLRS_01.00_verdieping 11--17_gen:4845336
4845252 | 17 zeventiende verdieping | Model Group:NLRS_01.00_verdieping 11--17_gen:4845336
4845387 | 18 achttiende verdieping | Model Group:NLRS_01.00_verdieping 18-19_gen:4845405
4845389 | 18 achttiende verdieping | Model Group:NLRS_01.00_verdieping 18-19_gen:4845405
4845391 | 18 achttiende verdieping | Model Group:NLRS_01.00_verdieping 18-19_gen:4845405
4845393 | 18 achttiende verdieping | Model Group:NLRS_01.00_verdieping 18-19_gen:4845405
4845456 | 19 negentiende verdieping | Model Group:NLRS_01.00_verdieping 18-19_gen:4845546
4845458 | 19 negentiende verdieping | Model Group:NLRS_01.00_verdieping 18-19_gen:4845546
4845460 | 19 negentiende verdieping | Model Group:NLRS_01.00_verdieping 18-19_gen:4845546
4845462 | 19 negentiende verdieping | Model Group:NLRS_01.00_verdieping 18-19_gen:4845546
4845594 | 20 twintigste verdieping | Model Group:NLRS_01.00_verdieping 20_gen:4845671
4845596 | 20 twintigste verdieping | Model Group:NLRS_01.00_verdieping 20_gen:4845671
4845598 | 20 twintigste verdieping | Model Group:NLRS_01.00_verdieping 20_gen:4845671
4845600 | 20 twintigste verdieping | Model Group:NLRS_01.00_verdieping 20_gen:4845671
4845656 | 21 eenentwintigste verdieping | Model Group:NLRS_01.00_verdieping 21--23_gen (members excluded):4846692
4845658 | 21 eenentwintigste verdieping | Model Group:NLRS_01.00_verdieping 21--23_gen (members excluded):4846692
4845660 | 21 eenentwintigste verdieping | Model Group:NLRS_01.00_verdieping 21--23_gen (members excluded):4846692
4845662 | 21 eenentwintigste verdieping | Model Group:NLRS_01.00_verdieping 21--23_gen (members excluded):4846692
4845734 | 05 vijfde verdieping | Model Group:NLRS_01.00_verdieping 05_gen:6691052
4845736 | 05 vijfde verdieping | Model Group:NLRS_01.00_verdieping 05_gen:6691052
4845738 | 05 vijfde verdieping | Model Group:NLRS_01.00_verdieping 05_gen:6691052
4845740 | 05 vijfde verdieping | Model Group:NLRS_01.00_verdieping 05_gen:6691052
4845803 | 11 elfde verdieping | Model Group:NLRS_01.00_verdieping 11--17_gen:4845821
4845805 | 11 elfde verdieping | Model Group:NLRS_01.00_verdieping 11--17_gen:4845821
4845807 | 11 elfde verdieping | Model Group:NLRS_01.00_verdieping 11--17_gen:4845821
4845809 | 11 elfde verdieping | Model Group:NLRS_01.00_verdieping 11--17_gen:4845821
5014970 | 01 eerste verdieping
5014972 | 00 begane grond
5014974 | 02 tweede verdieping
5014976 | 03 derde verdieping
5030617 | 00 begane grond
5030619 | 00 begane grond
5030621 | 00 begane grond
5030625 | 01a eerste tussenverdieping
5030627 | 01 eerste verdieping
5030629 | 01a eerste tussenverdieping
5030633 | 01c derde tussenverdieping
5030635 | 01c derde tussenverdieping
5030637 | 01c derde tussenverdieping
5030639 | 02b tweede tussenverdieping
5030641 | 02b tweede tussenverdieping
5030643 | 02b tweede tussenverdieping
5030649 | 00 begane grond
5030651 | 01a eerste tussenverdieping
5030653 | 01c derde tussenverdieping
5030655 | 02b tweede tussenverdieping
5230614 | 00 begane grond
5230983 | 00 begane grond
5231050 | 00 begane grond
5231142 | 00 begane grond
5232296 | 01a eerste tussenverdieping
5232298 | 01a eerste tussenverdieping
5232452 | 01c derde tussenverdieping
5232454 | 01c derde tussenverdieping
5232582 | 02b tweede tussenverdieping
5232584 | 02b tweede tussenverdieping
5232743 | 04 vierde verdieping
5232745 | 04 vierde verdieping
5233234 | 01a eerste tussenverdieping
5233236 | 01a eerste tussenverdieping
5233375 | 01c derde tussenverdieping
5233377 | 01c derde tussenverdieping
5233457 | 02b tweede tussenverdieping
5233459 | 02b tweede tussenverdieping
5233568 | 04 vierde verdieping
5233570 | 04 vierde verdieping
6698092 | 05 vijfde verdieping | Model Group:NLRS_01.00_verdieping 05_gen (members excluded):6698157
6698094 | 05 vijfde verdieping | Model Group:NLRS_01.00_verdieping 05_gen (members excluded):6698157
6698096 | 05 vijfde verdieping | Model Group:NLRS_01.00_verdieping 05_gen (members excluded):6698157
6698098 | 05 vijfde verdieping | Model Group:NLRS_01.00_verdieping 05_gen (members excluded):6698157

# IfcWallStandardCase: Basic Wall:NLRS_22.21_WA_beton prefab d=250_gen (68)
Type - PredefinedType: STANDARD; Material: NLRS_f2_beton prefab 250 mm
Classification: 22.21 binnenwanden - constructief, massieve wanden (Uniformat)
Pset_WallCommon - LoadBearing: yes; IsExternal: no; ExtendToStructure: no; Reference: NLRS_22.21_WA_beton prefab d=250_gen; ThermalTransmittance: 4.184 kg/K/s3
Name (Basic Wall:NLRS_22.21_WA_beton prefab d=250_gen:...) | In
4227596 | 00 begane grond
4227600 | 00 begane grond
4238424 | 00 begane grond
4239312 | 00 begane grond
4239349 | 00 begane grond
4239422 | 00 begane grond
4240422 | 00 begane grond
4252503 | 00 begane grond
4252725 | 00 begane grond
4252773 | 00 begane grond
4254047 | 00 begane grond
4254243 | 00 begane grond
4254381 | 00 begane grond
4318848 | 00 begane grond
4323235 | 01 eerste verdieping
4323399 | 00a eerste tussenverdieping
4323753 | 01a eerste tussenverdieping
4339342 | 02 tweede verdieping
4339346 | 01b tweede tussenverdieping
4339348 | 01c derde tussenverdieping
4342966 | 03 derde verdieping
4342970 | 02a eerste tussenverdieping
4342972 | 02b tweede tussenverdieping
4360784 | 01a eerste tussenverdieping
4362177 | 02 tweede verdieping
4363912 | 02b tweede tussenverdieping
4367325 | 01a eerste tussenverdieping
4367347 | 02 tweede verdieping
4367377 | 02b tweede tussenverdieping
4367477 | 01a eerste tussenverdieping
4367499 | 02 tweede verdieping
4367529 | 02b tweede tussenverdieping
4367553 | 01a eerste tussenverdieping
4367575 | 02 tweede verdieping
4367605 | 02b tweede tussenverdieping
4732843 | 00 begane grond
4732873 | 01a eerste tussenverdieping
4732896 | 02 tweede verdieping
4732926 | 02b tweede tussenverdieping
5132642 | 00 begane grond
5133833 | 02b tweede tussenverdieping
5143272 | 00 begane grond
5501026 | 02b tweede tussenverdieping
5502558 | 00a eerste tussenverdieping
5591892 | 00a eerste tussenverdieping
5840974 | 00 begane grond
5960007 | 00 begane grond
12815316 | 00 begane grond
12815467 | 01a eerste tussenverdieping
12816073 | 02b tweede tussenverdieping
12816645 | 02 tweede verdieping
12908715 | 00 begane grond
12908733 | 01a eerste tussenverdieping
12908790 | 02b tweede tussenverdieping
12908828 | 02 tweede verdieping
12909192 | 02b tweede tussenverdieping
12909254 | 02 tweede verdieping
12909319 | 01a eerste tussenverdieping
12909392 | 00 begane grond
12916095 | 01a eerste tussenverdieping
12916153 | 00 begane grond
12916198 | 02 tweede verdieping
12916256 | 02b tweede tussenverdieping
12917585 | 02b tweede tussenverdieping
12917902 | 02 tweede verdieping
12918050 | 01a eerste tussenverdieping
12918180 | 00 begane grond
12939478 | 00 begane grond

# IfcWallStandardCase: Basic Wall:NLRS_22.21_WA_beton prefab d=60_gen (136)
Type - PredefinedType: STANDARD; Material: NLRS_f2_beton prefab 60 mm
Classification: 22.21 binnenwanden - constructief, massieve wanden (Uniformat)
Pset_WallCommon - LoadBearing: yes; IsExternal: no; ExtendToStructure: no; Reference: NLRS_22.21_WA_beton prefab d=60_gen; ThermalTransmittance: 17.4333 kg/K/s3
Name (Basic Wall:NLRS_22.21_WA_beton prefab d=60_gen:...) | In | Group
10579184 | 05 vijfde verdieping | Model Group:NLRS_01.00_verdieping 05_gen:6691052
10579196 | 05 vijfde verdieping | Model Group:NLRS_01.00_verdieping 05_gen:6691052
10579617 | 05 vijfde verdieping | Model Group:NLRS_01.00_verdieping 05_gen (members excluded):6698157
10579619 | 05 vijfde verdieping | Model Group:NLRS_01.00_verdieping 05_gen (members excluded):6698157
10580692 | 04 vierde verdieping | Model Group:NLRS_01.00_verdieping 04_gen (members excluded):4844403
10580694 | 04 vierde verdieping | Model Group:NLRS_01.00_verdieping 04_gen (members excluded):4844403
10580774 | 04 vierde verdieping | Model Group:NLRS_01.00_verdieping 04_gen (members excluded):4585793
10580776 | 04 vierde verdieping | Model Group:NLRS_01.00_verdieping 04_gen (members excluded):4585793
10580884 | 06 zesde verdieping | Model Group:NLRS_01.00_verdieping 06--10_gen:4844478
10580886 | 06 zesde verdieping | Model Group:NLRS_01.00_verdieping 06--10_gen:4844478
10581677 | 06 zesde verdieping | Model Group:NLRS_01.00_verdieping 06--10_gen:4600460
10581679 | 06 zesde verdieping | Model Group:NLRS_01.00_verdieping 06--10_gen:4600460
10581689 | 07 zevende verdieping | Model Group:NLRS_01.00_verdieping 06--10_gen:4600975
10581691 | 07 zevende verdieping | Model Group:NLRS_01.00_verdieping 06--10_gen:4600975
10581695 | 08 achtste verdieping | Model Group:NLRS_01.00_verdieping 06--10_gen:4602043
10581697 | 08 achtste verdieping | Model Group:NLRS_01.00_verdieping 06--10_gen:4602043
10581701 | 09 negende verdieping | Model Group:NLRS_01.00_verdieping 06--10_gen:4603152
10581703 | 09 negende verdieping | Model Group:NLRS_01.00_verdieping 06--10_gen:4603152
10581707 | 10 tiende verdieping | Model Group:NLRS_01.00_verdieping 06--10_gen:4604220
10581709 | 10 tiende verdieping | Model Group:NLRS_01.00_verdieping 06--10_gen:4604220
10581743 | 07 zevende verdieping | Model Group:NLRS_01.00_verdieping 06--10_gen:4844553
10581745 | 07 zevende verdieping | Model Group:NLRS_01.00_verdieping 06--10_gen:4844553
10581749 | 08 achtste verdieping | Model Group:NLRS_01.00_verdieping 06--10_gen:4844628
10581751 | 08 achtste verdieping | Model Group:NLRS_01.00_verdieping 06--10_gen:4844628
10581755 | 09 negende verdieping | Model Group:NLRS_01.00_verdieping 06--10_gen:4844703
10581757 | 09 negende verdieping | Model Group:NLRS_01.00_verdieping 06--10_gen:4844703
10581761 | 10 tiende verdieping | Model Group:NLRS_01.00_verdieping 06--10_gen:4844850
10581763 | 10 tiende verdieping | Model Group:NLRS_01.00_verdieping 06--10_gen:4844850
10586173 | 04 vierde verdieping | Model Group:NLRS_01.00_verdieping 04_gen (members excluded):4844403
10586387 | 04 vierde verdieping | Model Group:NLRS_01.00_verdieping 04_gen (members excluded):4844403
10586527 | 04 vierde verdieping | Model Group:NLRS_01.00_verdieping 04_gen (members excluded):4585793
10586529 | 04 vierde verdieping | Model Group:NLRS_01.00_verdieping 04_gen (members excluded):4585793
10628018 | 11 elfde verdieping | Model Group:NLRS_01.00_verdieping 11--17_gen:4845821
10628020 | 11 elfde verdieping | Model Group:NLRS_01.00_verdieping 11--17_gen:4845821
10629028 | 12 twaalfde verdieping | Model Group:NLRS_01.00_verdieping 11--17_gen:4609129
10629030 | 12 twaalfde verdieping | Model Group:NLRS_01.00_verdieping 11--17_gen:4609129
10629040 | 13 dertiende verdieping | Model Group:NLRS_01.00_verdieping 11--17_gen:4609592
10629042 | 13 dertiende verdieping | Model Group:NLRS_01.00_verdieping 11--17_gen:4609592
10629046 | 14 veertiende verdieping | Model Group:NLRS_01.00_verdieping 11--17_gen:4610618
10629048 | 14 veertiende verdieping | Model Group:NLRS_01.00_verdieping 11--17_gen:4610618
10629052 | 15 vijftiende verdieping | Model Group:NLRS_01.00_verdieping 11--17_gen:4611642
10629054 | 15 vijftiende verdieping | Model Group:NLRS_01.00_verdieping 11--17_gen:4611642
10629058 | 16 zestiende verdieping | Model Group:NLRS_01.00_verdieping 11--17_gen:4612668
10629060 | 16 zestiende verdieping | Model Group:NLRS_01.00_verdieping 11--17_gen:4612668
10629064 | 17 zeventiende verdieping | Model Group:NLRS_01.00_verdieping 11--17_gen:4613692
10629066 | 17 zeventiende verdieping | Model Group:NLRS_01.00_verdieping 11--17_gen:4613692
10629070 | 11 elfde verdieping | Model Group:NLRS_01.00_verdieping 11--17_gen:4626135
10629072 | 11 elfde verdieping | Model Group:NLRS_01.00_verdieping 11--17_gen:4626135
10629118 | 12 twaalfde verdieping | Model Group:NLRS_01.00_verdieping 11--17_gen:4844919
10629120 | 12 twaalfde verdieping | Model Group:NLRS_01.00_verdieping 11--17_gen:4844919
10629124 | 13 dertiende verdieping | Model Group:NLRS_01.00_verdieping 11--17_gen:4844988
10629126 | 13 dertiende verdieping | Model Group:NLRS_01.00_verdieping 11--17_gen:4844988
10629130 | 14 veertiende verdieping | Model Group:NLRS_01.00_verdieping 11--17_gen:4845057
10629132 | 14 veertiende verdieping | Model Group:NLRS_01.00_verdieping 11--17_gen:4845057
10629136 | 15 vijftiende verdieping | Model Group:NLRS_01.00_verdieping 11--17_gen:4845126
10629138 | 15 vijftiende verdieping | Model Group:NLRS_01.00_verdieping 11--17_gen:4845126
10629142 | 16 zestiende verdieping | Model Group:NLRS_01.00_verdieping 11--17_gen:4845195
10629144 | 16 zestiende verdieping | Model Group:NLRS_01.00_verdieping 11--17_gen:4845195
10629148 | 17 zeventiende verdieping | Model Group:NLRS_01.00_verdieping 11--17_gen:4845336
10629150 | 17 zeventiende verdieping | Model Group:NLRS_01.00_verdieping 11--17_gen:4845336
10629991 | 11 elfde verdieping | Model Group:NLRS_01.00_verdieping 11--17_gen:4845821
10630161 | 11 elfde verdieping | Model Group:NLRS_01.00_verdieping 11--17_gen:4845821
10631241 | 12 twaalfde verdieping | Model Group:NLRS_01.00_verdieping 11--17_gen:4609129
10631243 | 12 twaalfde verdieping | Model Group:NLRS_01.00_verdieping 11--17_gen:4609129
10631253 | 13 dertiende verdieping | Model Group:NLRS_01.00_verdieping 11--17_gen:4609592
10631255 | 13 dertiende verdieping | Model Group:NLRS_01.00_verdieping 11--17_gen:4609592
10631259 | 14 veertiende verdieping | Model Group:NLRS_01.00_verdieping 11--17_gen:4610618
10631261 | 14 veertiende verdieping | Model Group:NLRS_01.00_verdieping 11--17_gen:4610618
10631265 | 15 vijftiende verdieping | Model Group:NLRS_01.00_verdieping 11--17_gen:4611642
10631267 | 15 vijftiende verdieping | Model Group:NLRS_01.00_verdieping 11--17_gen:4611642
10631271 | 16 zestiende verdieping | Model Group:NLRS_01.00_verdieping 11--17_gen:4612668
10631273 | 16 zestiende verdieping | Model Group:NLRS_01.00_verdieping 11--17_gen:4612668
10631277 | 17 zeventiende verdieping | Model Group:NLRS_01.00_verdieping 11--17_gen:4613692
10631279 | 17 zeventiende verdieping | Model Group:NLRS_01.00_verdieping 11--17_gen:4613692
10631283 | 11 elfde verdieping | Model Group:NLRS_01.00_verdieping 11--17_gen:4626135
10631285 | 11 elfde verdieping | Model Group:NLRS_01.00_verdieping 11--17_gen:4626135
10631331 | 12 twaalfde verdieping | Model Group:NLRS_01.00_verdieping 11--17_gen:4844919
10631333 | 12 twaalfde verdieping | Model Group:NLRS_01.00_verdieping 11--17_gen:4844919
10631337 | 13 dertiende verdieping | Model Group:NLRS_01.00_verdieping 11--17_gen:4844988
10631339 | 13 dertiende verdieping | Model Group:NLRS_01.00_verdieping 11--17_gen:4844988
10631343 | 14 veertiende verdieping | Model Group:NLRS_01.00_verdieping 11--17_gen:4845057
10631345 | 14 veertiende verdieping | Model Group:NLRS_01.00_verdieping 11--17_gen:4845057
10631349 | 15 vijftiende verdieping | Model Group:NLRS_01.00_verdieping 11--17_gen:4845126
10631351 | 15 vijftiende verdieping | Model Group:NLRS_01.00_verdieping 11--17_gen:4845126
10631355 | 16 zestiende verdieping | Model Group:NLRS_01.00_verdieping 11--17_gen:4845195
10631357 | 16 zestiende verdieping | Model Group:NLRS_01.00_verdieping 11--17_gen:4845195
10631361 | 17 zeventiende verdieping | Model Group:NLRS_01.00_verdieping 11--17_gen:4845336
10631363 | 17 zeventiende verdieping | Model Group:NLRS_01.00_verdieping 11--17_gen:4845336
10634087 | 18 achttiende verdieping | Model Group:NLRS_01.00_verdieping 18-19_gen:4845405
10634089 | 18 achttiende verdieping | Model Group:NLRS_01.00_verdieping 18-19_gen:4845405
10635327 | 18 achttiende verdieping | Model Group:NLRS_01.00_verdieping 18-19_gen:4845405
10635329 | 18 achttiende verdieping | Model Group:NLRS_01.00_verdieping 18-19_gen:4845405
10635735 | 18 achttiende verdieping | Model Group:NLRS_01.00_verdieping 18-19_gen:4617185
10635737 | 18 achttiende verdieping | Model Group:NLRS_01.00_verdieping 18-19_gen:4617185
10635747 | 19 negentiende verdieping | Model Group:NLRS_01.00_verdieping 18-19_gen:4617669
10635749 | 19 negentiende verdieping | Model Group:NLRS_01.00_verdieping 18-19_gen:4617669
10635765 | 19 negentiende verdieping | Model Group:NLRS_01.00_verdieping 18-19_gen:4845546
10635767 | 19 negentiende verdieping | Model Group:NLRS_01.00_verdieping 18-19_gen:4845546
10636189 | 20 twintigste verdieping | Model Group:NLRS_01.00_verdieping 20_gen:4845671
10636191 | 20 twintigste verdieping | Model Group:NLRS_01.00_verdieping 20_gen:4845671
10636434 | 20 twintigste verdieping | Model Group:NLRS_01.00_verdieping 20_gen:4622361
10636436 | 20 twintigste verdieping | Model Group:NLRS_01.00_verdieping 20_gen:4622361
10636702 | 18 achttiende verdieping | Model Group:NLRS_01.00_verdieping 18-19_gen:4617185
10636704 | 18 achttiende verdieping | Model Group:NLRS_01.00_verdieping 18-19_gen:4617185
10636714 | 19 negentiende verdieping | Model Group:NLRS_01.00_verdieping 18-19_gen:4617669
10636716 | 19 negentiende verdieping | Model Group:NLRS_01.00_verdieping 18-19_gen:4617669
10636732 | 19 negentiende verdieping | Model Group:NLRS_01.00_verdieping 18-19_gen:4845546
10636734 | 19 negentiende verdieping | Model Group:NLRS_01.00_verdieping 18-19_gen:4845546
10636848 | 20 twintigste verdieping | Model Group:NLRS_01.00_verdieping 20_gen:4845671
10636850 | 20 twintigste verdieping | Model Group:NLRS_01.00_verdieping 20_gen:4845671
10636930 | 20 twintigste verdieping | Model Group:NLRS_01.00_verdieping 20_gen:4622361
10636932 | 20 twintigste verdieping | Model Group:NLRS_01.00_verdieping 20_gen:4622361
10645803 | 05 vijfde verdieping | Model Group:NLRS_01.00_verdieping 05_gen:6691052
10645805 | 05 vijfde verdieping | Model Group:NLRS_01.00_verdieping 05_gen:6691052
10645863 | 05 vijfde verdieping | Model Group:NLRS_01.00_verdieping 05_gen (members excluded):6698157
10645865 | 05 vijfde verdieping | Model Group:NLRS_01.00_verdieping 05_gen (members excluded):6698157
10645946 | 06 zesde verdieping | Model Group:NLRS_01.00_verdieping 06--10_gen:4844478
10645948 | 06 zesde verdieping | Model Group:NLRS_01.00_verdieping 06--10_gen:4844478
10646071 | 06 zesde verdieping | Model Group:NLRS_01.00_verdieping 06--10_gen:4600460
10646073 | 06 zesde verdieping | Model Group:NLRS_01.00_verdieping 06--10_gen:4600460
10646083 | 07 zevende verdieping | Model Group:NLRS_01.00_verdieping 06--10_gen:4600975
10646085 | 07 zevende verdieping | Model Group:NLRS_01.00_verdieping 06--10_gen:4600975
10646089 | 08 achtste verdieping | Model Group:NLRS_01.00_verdieping 06--10_gen:4602043
10646091 | 08 achtste verdieping | Model Group:NLRS_01.00_verdieping 06--10_gen:4602043
10646095 | 09 negende verdieping | Model Group:NLRS_01.00_verdieping 06--10_gen:4603152
10646097 | 09 negende verdieping | Model Group:NLRS_01.00_verdieping 06--10_gen:4603152
10646101 | 10 tiende verdieping | Model Group:NLRS_01.00_verdieping 06--10_gen:4604220
10646103 | 10 tiende verdieping | Model Group:NLRS_01.00_verdieping 06--10_gen:4604220
10646137 | 07 zevende verdieping | Model Group:NLRS_01.00_verdieping 06--10_gen:4844553
10646139 | 07 zevende verdieping | Model Group:NLRS_01.00_verdieping 06--10_gen:4844553
10646143 | 08 achtste verdieping | Model Group:NLRS_01.00_verdieping 06--10_gen:4844628
10646145 | 08 achtste verdieping | Model Group:NLRS_01.00_verdieping 06--10_gen:4844628
10646149 | 09 negende verdieping | Model Group:NLRS_01.00_verdieping 06--10_gen:4844703
10646151 | 09 negende verdieping | Model Group:NLRS_01.00_verdieping 06--10_gen:4844703
10646155 | 10 tiende verdieping | Model Group:NLRS_01.00_verdieping 06--10_gen:4844850
10646157 | 10 tiende verdieping | Model Group:NLRS_01.00_verdieping 06--10_gen:4844850
